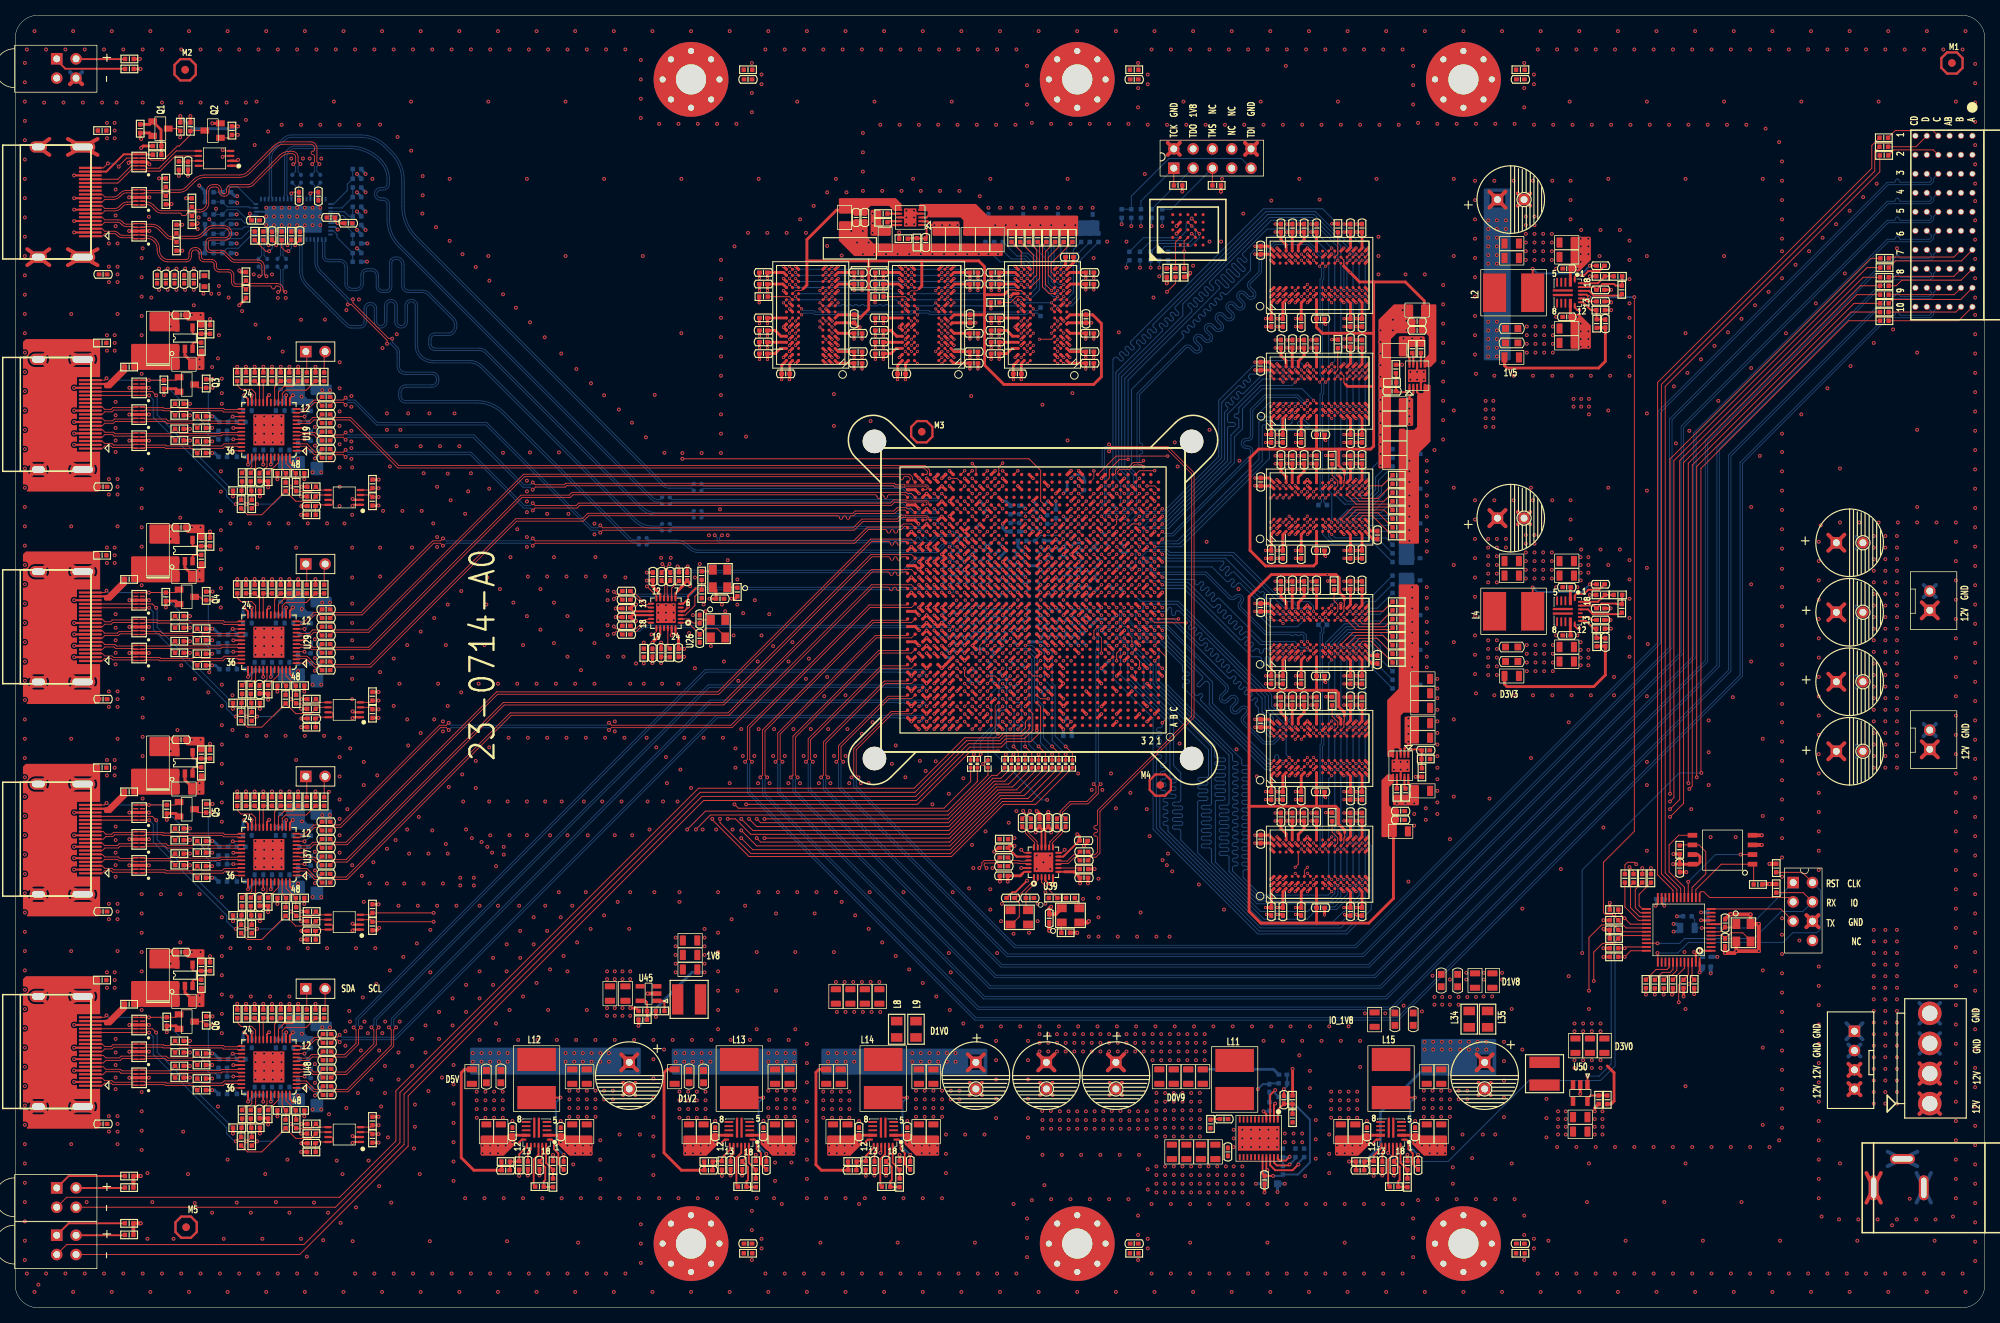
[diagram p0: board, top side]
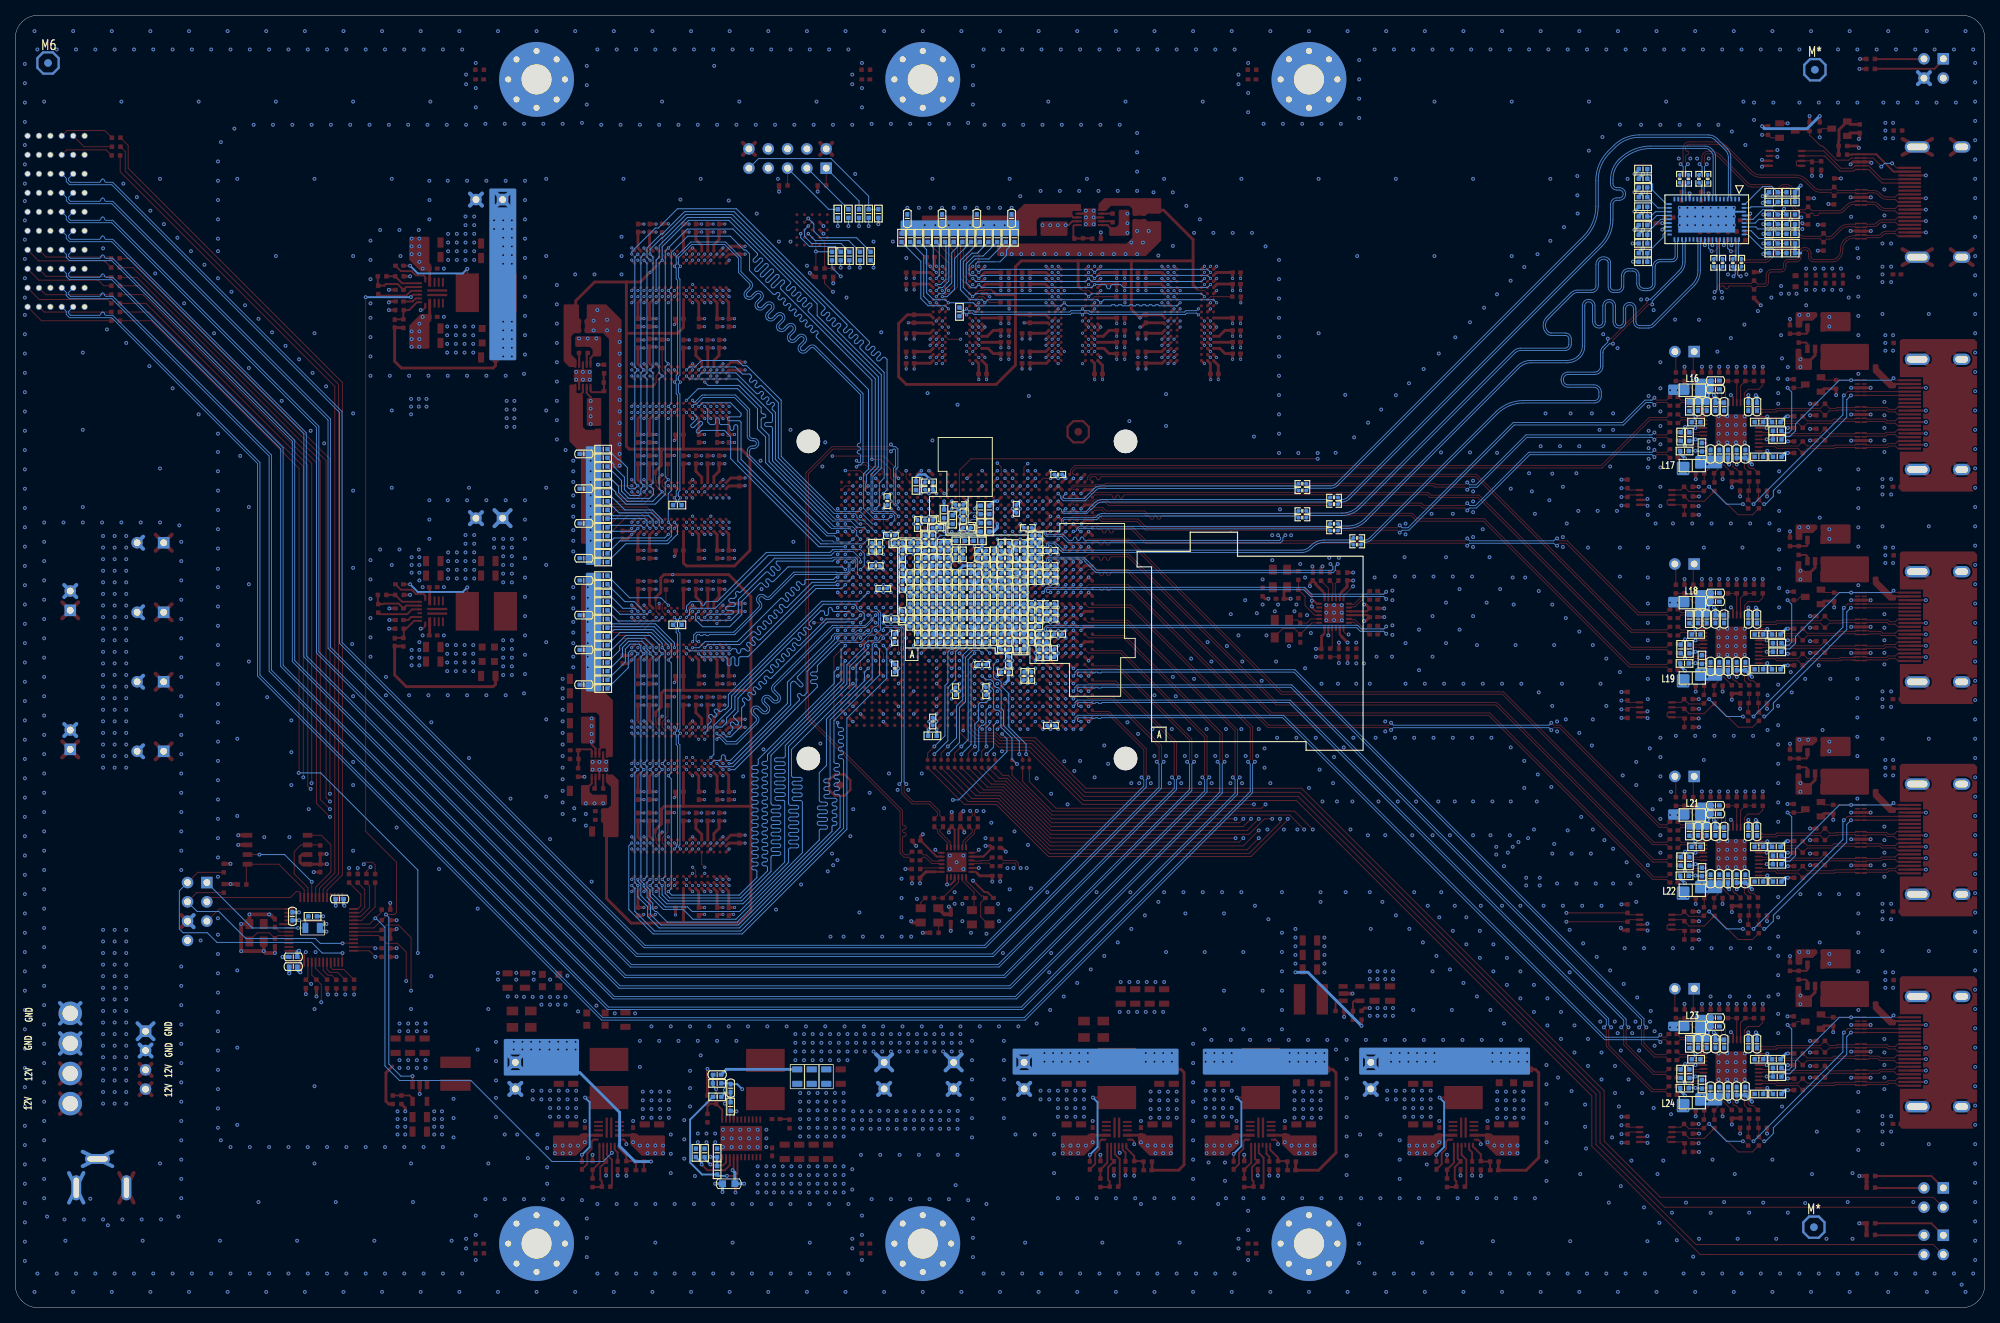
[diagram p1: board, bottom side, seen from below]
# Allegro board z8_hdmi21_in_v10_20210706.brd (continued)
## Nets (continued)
HDMI_RX1N: C400.1 HDMI1.6(DAT1-) R21.2 U7.5(IO4) U7.6(NC4)
HDMI_RX1P: C401.1 HDMI1.4(DAT1+) R24.2 U7.4(IO3) U7.7(NC3)
HDMI_RX2N: C392.1 HDMI1.9(DAT0-) R18.2 U4.2(IO2) U4.9(NC2)
HDMI_RX2P: C393.1 HDMI1.7(DAT0+) R20.2 U4.1(IO1) U4.10(NC1)
HDMI_RX3N: C390.1 HDMI1.12(CLK-) R16.2 U4.5(IO4) U4.6(NC4)
HDMI_RX3P: C391.1 HDMI1.10(CLK+) R17.2 U4.4(IO3) U4.7(NC3)
HDMI_RXC0N: C398.2 U59.39(S_INA1N)
HDMI_RXC0P: C399.2 U59.40(S_INA1P)
HDMI_RXC1N: C400.2 U59.44(S_INA0N)
HDMI_RXC1P: C401.2 U59.45(S_INA0P)
HDMI_RXC2N: C392.2 U59.11(D_IN0N)
HDMI_RXC2P: C393.2 U59.10(D_IN0P)
HDMI_RXC3N: C390.2 U59.16(D_IN1N)
HDMI_RXC3P: C391.2 U59.15(D_IN1P)
HDMI_SCL_1: J6.15(SCL) R93.1 R101.1 R107.1 U15.1(IO1) U15.10(NC1)
HDMI_SCL_2: J8.15(SCL) R161.1 R169.1 R173.1 U24.1(IO1) U24.10(NC1)
HDMI_SCL_3: J10.15(SCL) R230.1 R239.1 R243.1 U35.1(IO1) U35.10(NC1)
HDMI_SCL_4: J14.15(SCL) R288.1 R297.1 R301.1 U46.1(IO1) U46.10(NC1)
HDMI_SCL_21: HDMI1.15(SCL) U2.6(SCL2) U3.1(IO1) U3.10(NC1)
HDMI_SDA_1: J6.16(SDA) R94.1 R102.1 R108.1 U15.2(IO2) U15.9(NC2)
HDMI_SDA_2: J8.16(SDA) R162.1 R170.1 R174.1 U24.2(IO2) U24.9(NC2)
HDMI_SDA_3: J10.16(SDA) R231.1 R240.1 R244.1 U35.2(IO2) U35.9(NC2)
HDMI_SDA_4: J14.16(SDA) R289.1 R298.1 R302.1 U46.2(IO2) U46.9(NC2)
HDMI_SDA_21: HDMI1.16(SDA) U2.5(SDA2) U3.2(IO2) U3.9(NC2)
HM20_RX_RCK+: C428.2 P1.AD28(REFCLK_GXBL1C_CHTP_1C_AD28)
HM20_RX_RCK-: C426.2 P1.AD27(REFCLK_GXBL1C_CHTN_1C_AD27)
HM20_TX+: C160.1 U26.10(CLK3A)
HM20_TX-: C161.1 U26.9(CLK3B)
HM20_TX_RCX+: C160.2 P1.AB28(REFCLK_GXBL1D_CHBP_1D_AB28)
HM20_TX_RCX-: C161.2 P1.AB27(REFCLK_GXBL1D_CHBN_1D_AB27)
HM21_RX0+: C664.1 U59.29(S_OUTB1P)
HM21_RX0-: C663.1 U59.28(S_OUTB1N)
HM21_RX1+: C662.1 U59.35(S_OUTA0P)
HM21_RX1-: C661.1 U59.34(S_OUTA0N)
HM21_RX2+: C666.1 U59.7(D_OUT1P)
HM21_RX2-: C665.1 U59.8(D_OUT1N)
HM21_RX3+: C668.1 U59.3(D_OUT0P)
HM21_RX3-: C667.1 U59.4(D_OUT0N)
HM21_SCL: R187.2 R344.1 R345.1 U59.50(DEM_S1)
HM21_SDA: R186.2 R347.1 R348.1 U59.49(DEM_S0)
HM21RX0+: C664.2 P1.AG30(GXBL1C_RX_CH2P,GXBL1C_REFCLK2P_)
HM21RX0-: C663.2 P1.AG29(GXBL1C_RX_CH2N,GXBL1C_REFCLK2N_)
HM21RX1+: C662.2 P1.AF32(GXBL1C_RX_CH3P,GXBL1C_REFCLK3P_)
HM21RX1-: C661.2 P1.AF31(GXBL1C_RX_CH3N,GXBL1C_REFCLK3N_)
HM21RX2+: C666.2 P1.AJ30(GXBL1C_RX_CH1P,GXBL1C_REFCLK1P_)
HM21RX2-: C665.2 P1.AJ29(GXBL1C_RX_CH1N,GXBL1C_REFCLK1N_)
HM21RX3+: C668.2 P1.AL30(GXBL1C_RX_CH0P,GXBL1C_REFCLK0P_)
HM21RX3-: C667.2 P1.AL29(GXBL1C_RX_CH0N,GXBL1C_REFCLK0N_)
HM_1_TCX+: C115.1 P1.AH32(GXBL1C_TX_CH3P_1C_AH32)
HM_1_TCX-: C113.1 P1.AH31(GXBL1C_TX_CH3N_1C_AH31)
HM_1_TX0+: C120.1 P1.AP32(GXBL1C_TX_CH0P_1C_AP32)
HM_1_TX0-: C117.1 P1.AP31(GXBL1C_TX_CH0N_1C_AP31)
HM_1_TX1+: C130.1 P1.AM32(GXBL1C_TX_CH1P_1C_AM32)
HM_1_TX1-: C122.1 P1.AM31(GXBL1C_TX_CH1N_1C_AM31)
HM_1_TX2+: C133.1 P1.AK32(GXBL1C_TX_CH2P_1C_AK32)
HM_1_TX2-: C132.1 P1.AK31(GXBL1C_TX_CH2N_1C_AK31)
HM_2_TCX+: C181.1 P1.AG34(GXBL1D_TX_CH1P_1D_AG34)
HM_2_TCX-: C178.1 P1.AG33(GXBL1D_TX_CH1N_1D_AG33)
HM_2_TX0+: C187.1 P1.AN34(GXBL1C_TX_CH4P_1C_AN34)
HM_2_TX0-: C185.1 P1.AN33(GXBL1C_TX_CH4N_1C_AN33)
HM_2_TX1+: C194.1 P1.AL34(GXBL1C_TX_CH5P_1C_AL34)
HM_2_TX1-: C191.1 P1.AL33(GXBL1C_TX_CH5N_1C_AL33)
HM_2_TX2+: C202.1 P1.AJ34(GXBL1D_TX_CH0P_1D_AJ34)
HM_2_TX2-: C199.1 P1.AJ33(GXBL1D_TX_CH0N_1D_AJ33)
HM_3_TCX+: C252.1 P1.W34(GXBL1D_TX_CH5P_1D_W34)
HM_3_TCX-: C245.1 P1.W33(GXBL1D_TX_CH5N_1D_W33)
HM_3_TX0+: C257.1 P1.AE34(GXBL1D_TX_CH2P_1D_AE34)
HM_3_TX0-: C254.1 P1.AE33(GXBL1D_TX_CH2N_1D_AE33)
HM_3_TX1+: C263.1 P1.AC34(GXBL1D_TX_CH3P_1D_AC34)
HM_3_TX1-: C260.1 P1.AC33(GXBL1D_TX_CH3N_1D_AC33)
HM_3_TX2+: C269.1 P1.AA34(GXBL1D_TX_CH4P_1D_AA34)
HM_3_TX2-: C266.1 P1.AA33(GXBL1D_TX_CH4N_1D_AA33)
HM_4_TCX+: C296.1 P1.B32(GXBL1F_TX_CH5P_1F_B32)
HM_4_TCX-: C295.1 P1.B31(GXBL1F_TX_CH5N_1F_B31)
HM_4_TX0+: C301.1 P1.H32(GXBL1F_TX_CH2P_1F_H32)
HM_4_TX0-: C300.1 P1.H31(GXBL1F_TX_CH2N_1F_H31)
HM_4_TX1+: C331.1 P1.F32(GXBL1F_TX_CH3P_1F_F32)
HM_4_TX1-: C302.1 P1.F31(GXBL1F_TX_CH3N_1F_F31)
HM_4_TX2+: C333.1 P1.D32(GXBL1F_TX_CH4P_1F_D32)
HM_4_TX2-: C332.1 P1.D31(GXBL1F_TX_CH4N_1F_D31)
HM_SCL_1: J5.2 P1.C19(IO_2L_46_C19/DQ0) R75.2
HM_SCL_2: J7.2 P1.A20(IO_2L_41_A20/DQSN1) R132.2
HM_SCL_3: J9.2 P1.D21(IO_2L_29_D21/PLL_2L_CLKOUT1N/DQ) R209.2
HM_SCL_4: J12.2 P1.J20(IO_2L_12_J20/DQ5) R271.2
HM_SDA_1: J5.1 P1.B20(IO_2L_45_B20/DQSN0) R73.2
HM_SDA_2: J7.1 P1.A19(IO_2L_40_A19/DQS1) R130.2
HM_SDA_3: J9.1 P1.E21(IO_2L_28_E21/PLL_2L_CLKOUT1P,PL) R207.2
HM_SDA_4: J12.1 P1.M20(IO_2L_11_M20/DQ6) R269.2
HM_TX_HPD1: P1.B22(IO_2L_42_B22/DQ0) R386.1 R387.1
HM_TX_HPD2: P1.C22(IO_2L_33_C22/DQSN2) R446.1 R447.1
HM_TX_HPD3: P1.H20(IO_2L_13_H20/DQ5) R467.1 R468.1
HM_TX_HPD4: P1.K19(IO_2L_8_K19/DQS6) R480.1 R481.1
HM_TX_SCL1: R105.2 R183.2 U21.3(SCL1)
HM_TX_SCL2: R172.2 R185.2 U31.3(SCL1)
HM_TX_SCL3: R180.2 R242.2 U42.3(SCL1)
HM_TX_SCL4: R189.2 R300.2 U55.3(SCL1)
HM_TX_SCL21: R190.2 U2.3(SCL1)
HM_TX_SDA1: R96.2 R182.2 U21.4(SDA1)
HM_TX_SDA2: R164.2 R184.2 U31.4(SDA1)
HM_TX_SDA3: R179.2 R233.2 U42.4(SDA1)
HM_TX_SDA4: R188.2 R292.2 U55.4(SDA1)
HM_TX_SDA21: R191.2 U2.4(SDA1)
HPD_IN1: J6.19(HPLG) Q3.1(G) R78.2 R388.2 U15.5(IO4) U15.6(NC4)
HPD_IN2: J8.19(HPLG) Q4.1(G) R138.2 R448.2 U24.5(IO4) U24.6(NC4)
HPD_IN3: J10.19(HPLG) Q5.1(G) R211.2 R469.2 U35.5(IO4) U35.6(NC4)
HPD_IN4: J14.19(HPLG) Q6.1(G) R274.2 R482.2 U46.5(IO4) U46.6(NC4)
HPD_SNK_1: R385.1 R388.1 U19.33(HPD_SNK)
HPD_SNK_2: R444.1 R448.1 U29.33(HPD_SNK)
HPD_SNK_3: R466.1 R469.1 U37.33(HPD_SNK)
HPD_SNK_4: R479.1 R482.1 U48.33(HPD_SNK)
HPD_SRC_1: R387.2 U19.4(HPD_SRC)
HPD_SRC_2: R447.2 U29.4(HPD_SRC)
HPD_SRC_3: R468.2 U37.4(HPD_SRC)
HPD_SRC_4: R481.2 U48.4(HPD_SRC)
I2C_EN/PIN_1: R381.2 R382.1 U19.10(I2C_EN/PIN)
I2C_EN/PIN_2: R436.2 R439.1 U29.10(I2C_EN/PIN)
I2C_EN/PIN_3: R462.2 R463.1 U37.10(I2C_EN/PIN)
I2C_EN/PIN_4: R475.2 R476.1 U48.10(I2C_EN/PIN)
LED1: P1.A18(IO_2L_38_A18/DQ1) U57.4(T-)
LED2: P1.B18(IO_2L_39_B18/DQ1) U57.2(B-)
LED3: P1.D17(IO_2L_37_D17/DQ1) U58.4(T-)
LED4: P1.C18(IO_2L_36_C18/DQ1) U58.2(B-)
LED_HDMI21: P1.F21(IO_2L_17_F21/DQSN5) U1.2(B-)
M_AS_DATA0: R703.1 U6.D3(DQ0)
M_AS_DATA1: R704.1 U6.D2(DQ1)
M_AS_DATA2: R705.1 U6.C4(W#/DQ2)
M_AS_DATA3: R706.1 U6.D4(HOLD#/DQ3)
MODE: R343.1 R346.1 U59.21(MODE)
MSEL0: P1.AG15(MSEL0) R410.1 R412.1
MSEL1: P1.AG13(MSEL1) R413.1
MSEL2: P1.AG12(MSEL2) R414.1
NCE: P1.AF14(NCE) R418.1
NCONFIG: P1.AF13(NCONFIG) R420.1
NCS0: R43.2 R707.2 U6.C2(S#)
NIO_PULLUP: P1.AE14(NIO_PULLUP) R421.1 R422.1
NSTATUS: P1.AM11(NSTATUS) R398.1
PRE_SEL_1: R68.1 R69.2 U19.20(PRE_SEL)
PRE_SEL_2: R125.1 R126.2 U29.20(PRE_SEL)
PRE_SEL_3: R202.1 R203.2 U37.20(PRE_SEL)
PRE_SEL_4: R264.1 R265.2 U48.20(PRE_SEL)
R0PWR5V: HDMI1.18(+5V) R12.1 U3.5(IO4) U3.6(NC4)
RC_F_N: C184.1 U26.17(CLK1B)
RC_F_P: C186.1 U26.18(CLK1A)
REFCLK_F_N: C184.2 P1.P27(REFCLK_GXBL1F_CHBN_1F_P27)
REFCLK_F_P: C186.2 P1.P28(REFCLK_GXBL1F_CHBP_1F_P28)
RX_5V_N: Q1.3(D) R7.2 R192.2
RX_HPD_N: Q2.1(G) R11.2 R181.2
SCL_CTL_1: R74.2 R75.1 U19.15(SCL_CTL)
SCL_CTL_2: R131.2 R132.1 U29.15(SCL_CTL)
SCL_CTL_3: R208.2 R209.1 U37.15(SCL_CTL)
SCL_CTL_4: R270.2 R271.1 U48.15(SCL_CTL)
SCL_SNK_1: R93.2 U19.38(SCL_SNK)
SCL_SNK_2: R161.2 U29.38(SCL_SNK)
SCL_SNK_3: R230.2 U37.38(SCL_SNK)
SCL_SNK_4: R288.2 U48.38(SCL_SNK)
SCL_SRC_1: R90.1 R98.1 U19.46(SCL_SRC)
SCL_SRC_2: R159.1 R165.1 U29.46(SCL_SRC)
SCL_SRC_3: R226.1 R234.1 U37.46(SCL_SRC)
SCL_SRC_4: R286.1 R294.1 U48.46(SCL_SRC)
SDA_CTL_1: R72.2 R73.1 U19.16(SDA_CTL)
SDA_CTL_2: R129.2 R130.1 U29.16(SDA_CTL)
SDA_CTL_3: R206.2 R207.1 U37.16(SDA_CTL)
SDA_CTL_4: R268.2 R269.1 U48.16(SDA_CTL)
SDA_SNK_1: R94.2 U19.39(SDA_SNK)
SDA_SNK_2: R162.2 U29.39(SDA_SNK)
SDA_SNK_3: R231.2 U37.39(SDA_SNK)
SDA_SNK_4: R289.2 U48.39(SDA_SNK)
SDA_SRC_1: R91.1 R99.1 U19.47(SDA_SRC)
SDA_SRC_2: R160.1 R166.1 U29.47(SDA_SRC)
SDA_SRC_3: R227.1 R235.1 U37.47(SDA_SRC)
SDA_SRC_4: R287.1 R295.1 U48.47(SDA_SRC)
SEL0: R352.1 R367.1 U59.23(SEL0)
SEL1: R370.1 R373.1 U59.26(SEL1)
SI_DDR3A_N: C247.1 U39.17(CLK1B)
SI_DDR3A_P: C246.1 U39.18(CLK1A)
SI_DDR3B_N: C262.1 U39.9(CLK3B)
SI_DDR3B_P: C259.1 U39.10(CLK3A)
SI_DDR3C_N: C251.1 U39.13(CLK2B)
SI_DDR3C_P: C250.1 U39.14(CLK2A)
SIG_EN_1: R70.1 R71.2 U19.17(SIG_EN)
SIG_EN_2: R127.1 R128.2 U29.17(SIG_EN)
SIG_EN_3: R204.1 R205.2 U37.17(SIG_EN)
SIG_EN_4: R266.1 R267.2 U48.17(SIG_EN)
SWAP/POL_1: R389.1 R391.2 U19.1(SWAP/POL)
SWAP/POL_2: R450.1 R452.2 U29.1(SWAP/POL)
SWAP/POL_3: R470.1 R471.2 U37.1(SWAP/POL)
SWAP/POL_4: R484.1 R485.2 U48.1(SWAP/POL)
SWCLK: J11.2 R221.2 U43.37(PA14)
SWDIO: J11.4 R225.2 U43.34(PA13)
TCK: P1.AH12(TCK) R699.1
TDI: P1.AH13(TDI) R702.1
TDO: P1.AJ12(TDO) R700.1
TMS: P1.AL10(TMS) R701.1
TRST: P1.AL11(TRST) R400.1
TX_TERM_1: R392.1 R393.2 U19.36(TX_TERM_CTL)
TX_TERM_2: R454.1 R455.2 U29.36(TX_TERM_CTL)
TX_TERM_3: R472.1 R473.2 U37.36(TX_TERM_CTL)
TX_TERM_4: R486.1 R487.2 U48.36(TX_TERM_CTL)
UART_RXD: J11.3 U43.13(PA3)
UART_TXD: J11.5 U43.12(PA2)
VREF_DDR3_A: C9.1 C10.1 C11.1 C64.1 C65.1 C66.1 C445.1 C579.1 P1.AC23(VREFB2JN0_2J_AC23) P1.M22(VREFB2KN0_2K_M22) U5.6(REFOUT) U10.H1(VREFDQ) U10.M8(VREFCA) U11.H1(VREFDQ) U11.M8(VREFCA) U12.H1(VREFDQ) U12.M8(VREFCA)
VREF_DDR3_B: C58.1 C67.1 C68.1 C80.1 C124.1 C149.1 C448.1 C464.1 P1.AC12(VREFB3BN0_3B_AC12) P1.AD12(VREFB3AN0_3A_AD12) U8.H1(VREFDQ) U8.M8(VREFCA) U14.6(REFOUT) U16.H1(VREFDQ) U16.M8(VREFCA) U22.H1(VREFDQ) U22.M8(VREFCA)
VREF_DDR3_C: C203.1 C231.1 C237.1 C244.1 C253.1 C273.1 C472.1 C492.1 P1.AA10(VREFB3CN0_3C_AA10) P1.V10(VREFB3DN0_3D_V10) U28.H1(VREFDQ) U28.M8(VREFCA) U32.H1(VREFDQ) U32.M8(VREFCA) U34.6(REFOUT) U40.H1(VREFDQ) U40.M8(VREFCA)
VTT_DDR3_A: C25.1 C26.1 C27.1 C394.1 C395.1 C396.1 C397.1 R30.1 R31.1 R32.1 R33.1 R34.1 R35.1 R36.1 R37.1 R353.1 R354.1 R355.1 R356.1 R357.1 R358.1 R359.1 R360.1 R361.1 R362.1 R363.1 R364.1 R365.1 R366.1 U5.3(VO) U5.5(VOSNS)
VTT_DDR3_B: C123.1 C131.1 C140.1 C410.1 C417.1 C427.1 C459.1 R92.1 R97.1 R103.1 R106.1 R109.1 R111.1 R112.1 R113.1 R390.1 R394.1 R395.1 R397.1 R399.1 R402.1 R404.1 R407.1 R411.1 R415.1 R419.1 R423.1 R424.1 R426.1 U14.3(VO) U14.5(VOSNS)
VTT_DDR3_C: C205.1 C213.1 C221.1 C487.1 C531.1 C580.1 C593.1 R139.1 R141.1 R143.1 R145.1 R148.1 R152.1 R156.1 R157.1 R428.1 R430.1 R431.1 R432.1 R433.1 R435.1 R438.1 R442.1 R445.1 R449.1 R451.1 R456.1 R458.1 R459.1 U34.3(VO) U34.5(VOSNS)
XTL25N: C281.2 U43.6(PF1/OSC_OUT) Y5.1(XTALI)
XTL25N1: C271.2 U39.2(CLKIN_N) Y4.1(XTALI)
XTL25N2: C182.2 U26.2(CLKIN_N) Y2.1(XTALI)
XTL25P: C284.2 U43.5(PF0/OSC_IN) Y5.3(XTALO)
XTL25P1: C270.2 U39.1(CLKIN_P) Y4.3(XTALO)
XTL25P2: C189.2 U26.1(CLKIN_P) Y2.3(XTALO)
N22024981: R22.1 U5.9(PGOOD)
N22025053: C111.2 R64.2 R76.1 U14.1(REFIN)
N22025271: R61.1 U14.9(PGOOD)
N22025327: C228.2 R178.1 R195.2 U34.1(REFIN)
N22025525: R198.1 U34.9(PGOOD)
N22025799: R19.1 U5.7(EN)
N22025867: R62.1 U14.7(EN)
N22025914: R197.1 U34.7(EN)
N22026405: R259.1 R272.1 U45.5(FB)
N22026409: L7.1 U45.3(SW)
N22026570: C28.2 R38.2 R40.1 U5.1(REFIN)
N22030137: C1.1 C2.1 C3.1 J1.1 J1.2 J1.3 J1.4 J1.5 J1.6 J1.7 J1.8 J1.9 J2.1 J2.2 J2.3 J2.4 J2.5 J2.6 J2.7 J2.8 J2.9 J3.1 J3.2 J3.3 J3.4 J3.5 J3.6 J3.7 J3.8 J3.9 R3.2 R4.2 R5.2
N22030618: C384.2 R306.1 R312.2 U53.13(FB)
N22030676: R323.2 U53.16(PGOOD)
N22030684: R313.2 R319.1 U53.18(MODE)
N22030720: C378.1 U53.1(BOOT)
N22030722: C378.2 L14.1 U53.6(SW1) U53.7(SW2)
N22030830: C376.1 U53.14(SS)
N22030983: R492.1 R493.1 U56.22(RF)
N22031161: C334.2 C622.2 R483.1
N22031163: C336.2 C626.2 L11.2 R483.2 U56.6(LL#6) U56.7(LL#7) U56.8(LL#8) U56.9(LL#9) U56.10(LL#10) U56.11(LL#11)
N22031238: R325.2 U57.3(T+)
N22031240: R316.2 U57.1(B+)
N22031335: R488.2 U56.3(PGOOD)
N22031337: R489.2 U56.4(VBST)
N22031349: C336.1 R293.2
N22031384: R491.1 U56.21(TRIP)
N22031400: R490.1 U56.20(MODE)
N22031488: C626.1 R489.1
N22031700: C387.1 C388.1 C389.1 J16.1 J16.2 J16.3 J16.4 J16.5 J16.6 J16.7 J16.8 J16.9 J17.1 J17.2 J17.3 J17.4 J17.5 J17.6 J17.7 J17.8 J17.9 J18.1 J18.2 J18.3 J18.4 J18.5 J18.6 J18.7 J18.8 J18.9 R328.2 R329.2 R330.2
N22047900: P1.M27(REFCLK_GXBL1F_CHTN_1F_M27) P1.M28(REFCLK_GXBL1F_CHTP_1F_M28) R443.2
N22048190: P1.AP29(RREF_BL_AP29) R396.2
N22048192: P1.A29(RREF_TL_A29) R461.2
N22048413: L20.1 P1.A14(ADCGND_A14)
N22049180: R228.2 R229.2 U39.3(CLKIN)
N22049282: R222.1 U39.8(INTR)
N22049606: R246.2 Y3.1(EN)
N22053758: R50.2 U12.L8(ZQ)
N22054851: P1.F25(IO_2K_26_F25/RZQ_2K/LVDS2K_11P/) R457.1
N22055520: R48.2 U10.L8(ZQ)
N22056050: R49.2 U11.L8(ZQ)
N22061318: R23.2 U8.L8(ZQ)
N22061537: P1.AJ7(IO_3A_26_AJ7/RZQ_3A/LVDS3A_11P/) R403.1
N22061744: R59.2 U16.L8(ZQ)
N22062524: R89.2 U22.L8(ZQ)
N22067825: P1.K7(IO_3D_26_K7/RZQ_3D/LVDS3D_11P/D) R453.1
N22068466: R212.2 U40.L8(ZQ)
N22069069: R121.2 U28.L8(ZQ)
N22069811: R168.2 U32.L8(ZQ)
N22071827: J4.9(5) R406.2 R702.2
N22071832: J4.5(3) R15.2 R701.2
N22072215: J4.1 R14.2 R699.2
N22072232: J4.3(2) R700.2
N22082350: P1.Y18(GNDSENSE_Y18) R429.2
N22082686: P1.Y17(VCCLSENSE_Y17) R425.2
N22086073: JT1.A10(D-C10) R54.2
N22086076: JT1.B9(D-D9) R47.2
N22086079: JT1.A9(D-C9) R51.2
N22086210: JT1.B10(D-D10) R53.2
N22090777: R327.2 U58.3(T+)
N22090779: R326.2 U58.1(B+)
N22318019: C130.2 U19.5(IN_D1P)
N22318021: C122.2 U19.6(IN_D1N)
N22318023: C133.2 U19.2(IN_D2P)
N22318025: C132.2 U19.3(IN_D2N)
N22318199: C143.1 J6.MTG1 J6.MTG2 J6.MTG3 J6.MTG4 R58.2
N22318292: C144.2 R110.1 U21.7(VREF2) U21.8(EN)
N22318294: C120.2 U19.8(IN_D0P)
N22318980: C117.2 U19.9(IN_D0N)
N22318988: C115.2 U19.11(IN_CLKP)
N22318990: C113.2 U19.12(IN_CLKN)
N22319096: R65.2 U19.22(VSADJ)
N22319158: R95.1 U19.45(SPDIF_IN)
N22319174: C141.1 U19.42(OE)
N22319555: J6.18(+5V) R63.1
N22319599: R60.2 U13.3(OCB)
N22319611: R56.1 R57.1 U13.4(EN)
N22336290: C194.2 U29.5(IN_D1P)
N22336292: C191.2 U29.6(IN_D1N)
N22336294: C202.2 U29.2(IN_D2P)
N22336296: C199.2 U29.3(IN_D2N)
N22336470: C214.1 J8.MTG1 J8.MTG2 J8.MTG3 J8.MTG4 R116.2
N22336560: C222.2 R175.1 U31.7(VREF2) U31.8(EN)
N22336562: C187.2 U29.8(IN_D0P)
N22337251: C185.2 U29.9(IN_D0N)
N22337253: C181.2 U29.11(IN_CLKP)
N22337255: C178.2 U29.12(IN_CLKN)
N22337367: R122.2 U29.22(VSADJ)
N22337429: R163.1 U29.45(SPDIF_IN)
N22337445: C212.1 U29.42(OE)
N22337826: J8.18(+5V) R120.1
N22337863: R117.2 U23.3(OCB)
N22337874: R114.1 R115.1 U23.4(EN)
N22341695: C263.2 U37.5(IN_D1P)
N22341697: C260.2 U37.6(IN_D1N)
N22341699: C269.2 U37.2(IN_D2P)
N22341701: C266.2 U37.3(IN_D2N)
N22341875: C274.1 J10.MTG1 J10.MTG2 J10.MTG3 J10.MTG4 R193.2
N22341965: C282.2 R248.1 U42.7(VREF2) U42.8(EN)
N22341967: C257.2 U37.8(IN_D0P)
N22342656: C254.2 U37.9(IN_D0N)
N22342658: C252.2 U37.11(IN_CLKP)
N22342660: C245.2 U37.12(IN_CLKN)
N22342772: R199.2 U37.22(VSADJ)
N22342834: R232.1 U37.45(SPDIF_IN)
N22342850: C272.1 U37.42(OE)
N22343231: J10.18(+5V) R196.1
N22343268: R194.2 U33.3(OCB)
N22343279: R176.1 R177.1 U33.4(EN)
N22346984: C331.2 U48.5(IN_D1P)
N22347001: C302.2 U48.6(IN_D1N)
N22347003: C333.2 U48.2(IN_D2P)
N22347005: C332.2 U48.3(IN_D2N)
N22347179: C338.1 J14.MTG1 J14.MTG2 J14.MTG3 J14.MTG4 R253.2
N22347257: C364.2 R303.1 U55.7(VREF2) U55.8(EN)
N22347259: C301.2 U48.8(IN_D0P)
N22347960: C300.2 U48.9(IN_D0N)
N22347962: C296.2 U48.11(IN_CLKP)
N22347964: C295.2 U48.12(IN_CLKN)
N22348076: R261.2 U48.22(VSADJ)
N22348138: R290.1 U48.45(SPDIF_IN)
N22348154: C335.1 U48.42(OE)
N22348531: J14.18(+5V) R258.1
N22348572: R257.2 U44.3(OCB)
N22348576: R251.1 R252.1 U44.4(EN)
N22353387: R118.2 R134.2 U26.3(CLKIN)
N22353420: R119.1 U26.8(INTR)
N22353722: R133.2 Y1.1(EN)
N22359824: P1.T27(REFCLK_GXBL1E_CHTN_1E_T27) P1.T28(REFCLK_GXBL1E_CHTP_1E_T28) R434.2
N22360101: P1.Y27(REFCLK_GXBL1D_CHTN_1D_Y27) P1.Y28(REFCLK_GXBL1D_CHTP_1D_Y28) R427.2
N22376675: C43.1 HDMI1.MTG1 HDMI1.MTG2 HDMI1.MTG3 HDMI1.MTG4 R10.2
N22380384: C4.2 R13.1 U2.7(VREF2) U2.8(EN)
N22381237: R349.1 U59.22(INPUT_EN)
N22381770: R27.2 U59.43(S_INB0P)
N22381784: R26.2 U59.42(S_INB0N)
N22381826: R29.2 U59.38(S_INB1P)
N22381836: R28.2 U59.37(S_INB1N)
N22382472: C20.1 U59.41(VDD#41)
N22382559: C21.1 U59.36(VDD#36)
N22383207: C5.1 U59.9(VDD#9)
N22383495: C6.1 U59.14(VDD#14)
N22383981: C12.1 U59.51(VDD#51)
N22398516: Q1.1(G) R6.2 R9.1 R12.2
N22432680: P1.A13(VREFP_ADC_A13) P1.B13(VREFN_ADC_B13) R460.1
N22449821: R315.2 R320.1 U54.18(MODE)
N22449835: C381.1 U54.1(BOOT)
N22449837: C381.2 L15.1 U54.6(SW1) U54.7(SW2)
N22449845: C385.2 R307.1 R314.2 U54.13(FB)
N22449937: C379.1 U54.14(SS)
N22450190: R324.2 U54.16(PGOOD)
N22451830: R135.2 R136.1 U25.18(MODE)
N22451844: C164.1 U25.1(BOOT)
N22451846: C164.2 L4.1 U25.6(SW1) U25.7(SW2)
N22451862: C190.2 R147.2 R151.1 U25.13(FB)
N22451950: C183.1 U25.14(SS)
N22452196: R140.2 U25.16(PGOOD)
N22462383: R260.2 U45.1(EN/PG)
N22647853: R309.2 R317.1 U51.18(MODE)
N22647875: C372.1 U51.1(BOOT)
N22647877: C372.2 L12.1 U51.6(SW1) U51.7(SW2)
N22647893: C382.2 R304.1 R308.2 U51.13(FB)
N22647973: C370.1 U51.14(SS)
N22648227: R321.2 U51.16(PGOOD)
N22660428: R254.1 U43.44(BOOT0)
N22766072: R311.2 R318.1 U52.18(MODE)
N22766094: C375.1 U52.1(BOOT)
N22766096: C375.2 L13.1 U52.6(SW1) U52.7(SW2)
N22766112: C383.2 R305.1 R310.2 U52.13(FB)
N22766192: C373.1 U52.14(SS)
N22766425: R322.2 U52.16(PGOOD)
N22768217: R44.2 R45.1 U9.18(MODE)
N22768239: C35.1 U9.1(BOOT)
N22768241: C35.2 L2.1 U9.6(SW1) U9.7(SW2)
N22768257: C74.2 R52.2 R55.1 U9.13(FB)
N22768337: C57.1 U9.14(SS)
N22768591: R46.2 U9.16(PGOOD)
N22769636: R284.1 R285.1 U50.5(FB)
N22769670: L10.1 U50.3(SW)
N22862307: JT1.D1(D-D1) R709.2
N22862309: JT1.C1(D-C1) R708.2
N22862311: JT1.C2(D-C2) R710.2
N22881224: JT1.A8(D-C8) R713.2
N22881226: JT1.B7(D-D7) R712.2
N22881228: JT1.A7(D-C7) R711.2
N22881230: JT1.B8(D-D8) R714.2
N22958186: R1.2 U1.3(T+)
N22958370: R2.2 U1.1(B+)

Pads without a net: HDMI1 13 14; J4 6 7 8; J6 13 14; J8 13 14; J10 13 14; J11 7; J14 13 14; JT1 A4 A5 A6 B4 B5 B6 D2; M1 1; M2 1; M3 1; M4 1; M5 1; M6 1; M* 1; M*#2 1; P1 A2 A3 A4 A5 A6 A8 A9 A10 A11 A15 A16 A23 AA5 AB1 AC4 AC13 AC14 AC15 AC20 AC22 AC24 AD10 AD17 AD19 AD20 AD22 AE12 AE16 AE17 AE18 AE19 AE20 AE21 AE22 AF16 AF19 AF20 AF21 AF22 AG16 AG18 AG20 AG21 AG22 AH3 AH5 AH14 AH15 AH18 AH19 AH20 AH22 AJ5 AJ14 AJ15 AJ17 AJ19 AJ20 AJ21 AJ22 AK7 AK13 AK14 AK17 AK18 AK19 AK20 AK21 AL1 AL8 AL13 AL14 AL15 AL16 AL18 AL19 AL20 AL21 AL27 AM8 AM10 AM13 AM15 AM16 AM17 AM18 AM20 AM21 AN1 AN2 AN3 AN5 AN9 AN12 AN13 AN14 AN15 AN17 AN18 AN19 AN20 AN28 AN29 AP2 AP3 AP5 AP10 AP12 AP14 AP15 AP16 AP17 AP19 B1 B3 B5 B6 B7 B8 B10 B11 B12 B15 B16 B17 C2 C3 C4 C5 C7 C8 C9 C10 C12 C13 C15 C17 D1 D2 D4 D5 D6 D7 D9 D10 D11 D12 D15 D16 D27 E1 E2 E3 E4 E6 E7 E8 E9 E11 E12 E13 E16 E22 E27 F1 F3 F4 F5 F6 F8 F9 F10 F11 F12 F13 F15 F16 G1 G2 G3 G5 G6 G7 G8 G10 G11 G12 G13 G15 G16 H2 H3 H4 H5 H7 H8 H9 H10 H11 H12 H13 H15 J2 J6 J7 J9 J10 J11 J12 J13 J19 J21 J24 J25 J26 K2 K3 K8 K9 K10 K11 K12 K13 K14 K22 K23 L9 L10 L11 L13 L14 M2 M3 M8 M9 M10 M11 M12 M13 N8 N10 N11 P10 R8 T14 T15 V5 W1 W10; U6 A2 A3 A4 A5 B1 B5 C1 C3 C5 D1 D5 E1 E2 E3 E4 E5; U8 B7 C7 D3 J1 J9 L1 L9 M7; U10 B7 C7 D3 J1 J9 L1 L9 M7; U11 J1 J9 L1 L9 M7; U12 J1 J9 L1 L9 M7; U15 4 7; U16 J1 J9 L1 L9 M7; U19 18 40 44; U22 J1 J9 L1 L9 M7; U24 4 7; U25 15; U26 5 21; U28 J1 J9 L1 L9 M7; U29 18 40 44; U32 J1 J9 L1 L9 M7; U35 4 7; U37 18 40 44; U39 5; U40 B7 C7 D3 J1 J9 L1 L9 M7; U43 2 3 4 10 11 21 22 33 38 39 43; U46 4 7; U48 18 40 44; U51 15; U52 15; U56 5; U59 1 2 5 6 12 13 17 18 27 32 33

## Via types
v1: diameter 0.508, hole 0.254, TOP to BOTTOM, 3709 vias
v2: diameter 0.457, hole 0.203, TOP to BOTTOM, 828 vias
v3: diameter 0.406, hole 0.203, TOP to BOTTOM, 891 vias

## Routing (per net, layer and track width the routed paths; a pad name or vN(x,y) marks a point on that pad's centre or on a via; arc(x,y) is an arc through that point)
D0V9_EN: length 65.2
  TOP w0.127: U43.31 211.12,49.47 R245.2 210.24,50.36 208.66,50.36 207.01,48.7 v1(207.01,41.72)
  TOP w0.254: v1(165.74,26.86) 165.58,26.7 U56.2
  06_SIG2 w0.127: v1(207.01,41.72) 202.69,37.4 177.42,37.4 166.88,26.86 v1(165.74,26.86)
D0V9_VFB: length 4.9
  TOP w0.254: R291.2 R283.1 167.98,26.84 C334.1 166.08,26.04 U56.1
D0V9_VREG: length 19.1
  TOP w0.254: U56.18 164.08,17.61 C386.1 v1(165.46,17.35)
  BOTTOM w0.254: v1(165.46,17.35) 166.57,17.35 R493.2 168.73,17.54 170.31,19.11 170.31,24.76 R488.1
D1V0_EN: length 118.4
  TOP w0.127: v1(207.65,42.99) 207.65,46.8 208.79,47.94 210.24,47.94 R247.2 211.27,48.97 U43.32
  TOP w0.254: U53.15 113.92,20.51 v1(113.79,20.38)
  06_SIG2 w0.127: v1(207.65,42.99) 207.52,42.99 202.56,38.04 134.62,38.04 130.43,33.85 130.43,29.65 124.33,23.56 116.97,23.56 v1(113.79,20.38)
D1V0_VREG: length 7.3
  TOP w0.254: U53.17 114.92,19.63 C377.1 115.32,18.5 115.32,16.83 115.12,16.63 R323.1 115.17,15.88 R319.2
D1V2: length 19.5
  TOP w0.381: R305.2 90.66,19.2 C383.1 87.63,18.1 85.34,20.38 85.34,30.92 85.79,31.37 C317.1
  vias: v1(39.12,109.92) v1(39.12,81.98) v1(39.12,54.04) v1(39.12,26.1) v1(40.26,109.92) v1(40.26,81.98) v1(40.26,54.04) v1(40.26,26.1) v1(86.87,33.52) v1(86.87,32.37) v1(88.01,33.52) v1(88.01,32.37) v1(89.15,33.52) v1(89.15,32.37) v1(90.3,33.52) v1(90.3,32.37) v1(91.44,33.52) v1(91.44,32.37) v1(99.06,33.52) v1(99.06,32.37) v1(100.2,33.52) v1(100.2,32.37) v1(101.35,33.52) v1(101.35,32.37) v1(102.49,33.52) v1(102.49,32.37)
D1V2_OUT1: length 14
  TOP w0.229: v1(36.5,110.94) 36.12,111.33 U19.48 ; v1(30.12,120.06) 30.62,119.55 U19.24 ; v1(35.65,120.06) 35.62,120.03 U19.14 ; U19.23 31.12,120.03 v1(31.1,120.06) ; U19.37 v1(30.62,110.94)
  BOTTOM w0.381: C414.2 C415.2 30.63,110.94 v1(30.62,110.94) ; v1(36.5,110.94) 36.5,111.37 C411.2 C412.2 ; v1(30.12,120.06) 29.97,119.91 C409.2 ; v1(35.65,120.06) 35.43,119.84 C406.2 C407.2 ; v1(31.1,120.06) 31.12,120.04 C408.2
  vias: v1(37.21,111.7)
D1V2_OUT2: length 14
  TOP w0.229: U29.37 v1(30.62,83) ; v1(35.65,92.12) 35.62,92.09 U29.14 ; U29.24 30.62,91.61 v1(30.12,92.12) ; v1(31.1,92.12) 31.12,92.09 U29.23 ; v1(36.5,83) 36.12,83.39 U29.48
  BOTTOM w0.381: C541.2 29.97,91.97 v1(30.12,92.12) ; C587.2 C586.2 36.5,83.43 v1(36.5,83) ; v1(30.62,83) 30.63,83 C590.2 C589.2 ; v1(35.65,92.12) 35.43,91.9 C538.2 C539.2 ; C540.2 31.12,92.1 v1(31.1,92.12)
  vias: v1(37.21,83.76)
D1V2_OUT3: length 14
  TOP w0.229: U37.48 36.12,55.45 v1(36.5,55.06) ; v1(31.1,64.18) 31.12,64.15 U37.23 ; v1(35.65,64.18) 35.62,64.15 U37.14 ; U37.37 v1(30.62,55.06) ; v1(30.12,64.18) 30.62,63.67 U37.24
  BOTTOM w0.381: v1(30.12,64.18) 29.97,64.03 C603.2 ; C601.2 C600.2 35.43,63.96 v1(35.65,64.18) ; v1(30.62,55.06) 30.63,55.06 C608.2 C607.2 ; C605.2 C604.2 36.5,55.49 v1(36.5,55.06) ; v1(31.1,64.18) 31.12,64.16 C602.2
  vias: v1(37.21,55.82)
D1V2_OUT4: length 14
  TOP w0.229: U48.37 v1(30.62,27.12) ; v1(31.1,36.24) 31.12,36.21 U48.23 ; v1(30.12,36.24) 30.62,35.73 U48.24 ; v1(35.65,36.24) 35.62,36.21 U48.14 ; v1(36.5,27.12) 36.12,27.51 U48.48
  BOTTOM w0.381: v1(30.12,36.24) 29.97,36.09 C621.2 ; v1(31.1,36.24) 31.12,36.22 C620.2 ; v1(30.62,27.12) 30.63,27.12 C631.2 C630.2 ; C619.2 C618.2 35.43,36.02 v1(35.65,36.24) ; v1(36.5,27.12) 36.5,27.55 C627.2 C628.2
  vias: v1(37.21,27.88)
D1V2_VREG: length 7.3
  TOP w0.254: U52.17 96,19.63 C374.1 96.39,18.5 96.39,16.83 96.19,16.63 R322.1 96.25,15.88 R318.2
D1V5_VREG: length 7.3
  TOP w0.254: U9.17 207.64,134.29 C56.1 208.77,134.68 210.31,134.68 210.51,134.48 R46.1 211.38,134.54 R45.2
D1V8: length 12.4
  TOP w0.381: R272.2 v1(81.99,37.09)
  BOTTOM w0.381: v1(81.99,37.09) 89.03,44.13 v1(90.68,44.13)
  vias: v1(81.66,84.77) v1(82.68,84.77) v1(90.68,49.85) v1(90.68,48.7) v1(90.68,47.56) v1(90.68,46.42) v1(90.68,45.28)
D1V8_EN: length 61.3
  TOP w0.127: R238.2 210.87,52.08 v1(211.71,51.24) 212.48,50.47 U43.29
  TOP w0.254: v1(180.59,20.38) 180.73,20.51 180.73,21.4
  BOTTOM w0.127: v1(211.71,51.24) 211.63,51.24 210.44,50.05 210.44,31.81 208.53,29.91 199.14,29.91 188.47,19.24 181.74,19.24 v1(180.59,20.38)
D1V8_VREG: length 7.3
  TOP w0.254: R320.2 181.97,15.88 R324.1 181.92,16.63 182.12,16.83 182.12,18.5 C380.1 181.73,19.63 U54.17
D3V3: length 90
  TOP w0.254: U43.48 v1(221.57,44.13) ; 138.05,57.36 U39.7 ; v1(215.77,52.9) 216.07,53.19 U43.24 ; 87.06,88.52 86.85,88.73 U26.24 ; U43.1 v1(221.74,46.97) ; U39.24 132.74,57.36 132.52,57.15 ; U26.7 86.85,94.02 87.12,94.3 ; v1(221.74,50.99) 221.76,50.97 U43.9
  TOP w0.279: C22.1 115.4,142.45 U5.10 ; U14.10 183.4,124.95 C95.1 ; C230.1 183.25,68.98 U34.10
  TOP w0.381: C265.1 R216.2 v1(218.11,59.7) ; C265.1 v1(218.08,58.37) ; C265.1 218.97,58.36 U38.8 221.35,58.36 221.62,58.63 221.62,59.36 221.35,59.63 U38.7 ; v1(87.99,86.69) C197.1 87.25,88.33 87.06,88.52 ; v1(94.23,93.28) 94.67,93.28 R133.1 ; v1(88.77,94.93) 88.77,95.3 C162.1 88.01,95.3 88.01,95.19 87.12,94.3 ; v1(91.31,93.28) C173.1 92.18,94.38 Y1.4 ; C204.1 195.9,82.04 196.22,81.72 207.64,81.72 209.17,83.25 C190.1 208.06,87.04 R151.2 ; v1(130.56,56.07) 130.56,56.82 C267.1 132.21,56.83 132.52,57.15 ; R255.2 v1(219.46,40.96) ; R249.2 v1(208.91,47.31) ; 138.05,57.36 139.28,57.36 C268.1 v1(140.06,55.83) ; R250.2 v1(208.91,46.16) ; R256.2 v1(220.85,41.26)
  TOP w0.508: 193.91,104.95 C145.1 ; C145.1 193.91,102.82 ; C145.1 196.04,102.82 ; C145.1 196.04,104.95 ; R225.1 v1(230.76,55.74) 229.85,55.74 R224.2 ; v1(136.27,52.77) 136.02,52.51 C280.1 136.86,51.77 Y3.4 ; R246.1 v1(139.7,49.34) ; U38.3 v1(229.74,60.9)
  03_SIG1 w0.508: 194.17,104.69 C145.1 ; C145.1 195.78,103.08 ; C145.1 194.17,103.08 ; C145.1 195.78,104.69
  BOTTOM w0.381: R474.1 v1(218.57,51.5) ; v1(221.74,50.99) 221.76,50.97 C610.1 ; v1(215.77,52.9) 215.88,53.01 C609.1
  BOTTOM w0.508: v1(221.74,46.97) 221.98,46.73 C612.1 ; C145.1 196.04,104.95 ; C145.1 196.04,102.82 ; C145.1 193.91,102.82 ; C145.1 193.91,104.95 ; v1(221.57,44.13) 221.98,44.54 C613.1
  vias: v1(24.77,133.41) v1(25.78,133.41) v1(26.8,134.43) v1(26.8,133.41) v1(40.39,120.71) v1(40.39,92.77) v1(40.39,64.83) v1(40.39,36.89) v1(41.4,120.71) v1(41.4,92.77) v1(41.4,64.83) v1(41.4,36.89) v1(112.78,143.95) v1(112.78,142.68) v1(112.78,141.41) v1(181.74,66.36) v1(182.63,127.52) v1(182.88,66.36) v1(183.77,127.52) v1(184.02,66.36) v1(184.91,127.52) v1(193.75,101.16) v1(193.75,100.01) v1(193.75,98.87) v1(193.75,97.73) v1(193.75,96.58) v1(193.75,95.44) v1(193.75,87.82) v1(193.75,86.68) v1(193.75,85.53) v1(193.75,84.39) v1(193.75,83.25) v1(194.89,101.16) v1(194.89,100.01) v1(194.89,98.87) v1(194.89,97.73) v1(194.89,96.58) v1(194.89,95.44) v1(194.89,87.82) v1(194.89,86.68) v1(194.89,85.53) v1(194.89,84.39) v1(194.89,83.25) v1(196.09,101.16) v1(196.09,100.01) v1(202.95,25.84) v1(202.95,24.83) v1(202.95,23.81) v1(202.95,22.8) v1(203.96,25.84) v1(203.96,24.83) v1(203.96,23.81) v1(203.96,22.8)
D3V3_HM21: length 20.6
  TOP w0.381: C13.2 42.43,142.68 v1(42.42,142.69) 42.05,143.06 C8.2 ; v1(29.46,131.89) 30.35,132.78 R39.1 ; R20.1 23.85,142.53 v1(24,142.68) ; v1(20.57,145.22) 20.52,145.17 R17.1 ; R16.1 v1(18.92,148.58) ; R24.1 v1(21.97,139.07) ; R21.1 v1(21.97,142.48) ; v1(29.46,136.46) 29.66,136.26 R25.1 ; R18.1 v1(22.48,145.96)
  BOTTOM w0.254: U59.24 42.41,142.7 v1(42.42,142.69)
  BOTTOM w0.381: v1(29.21,145.35) 29.08,145.49 R341.2 ; v1(46.28,137.63) 46.26,137.61 R373.2 ; R343.2 45.52,144.78 v1(46.08,144.22) ; R350.2 v1(29.13,141.3) ; R349.2 45.52,142.37 v1(46.08,141.8) ; R344.2 v1(29.13,143.84) ; R371.2 29.01,138.76 v1(29.13,138.63) ; R337.2 45.52,147.32 v1(46.08,146.76) ; v1(46.08,149.17) 45.52,149.73 R335.2 ; R338.2 28.89,146.24 v1(29.21,146.24) ; R368.2 v1(29.13,140.03) ; R367.2 v1(46.33,140.03) ; R347.2 v1(29.13,142.57)
  vias: v1(18.92,136.72) v1(20.07,136.72) v1(21.21,136.72) v1(22.35,136.72) v1(23.49,136.72)
D3V3_OUT1: length 18.8
  TOP w0.229: U19.13 36.12,119.65 v1(36.53,120.06) ; U19.43 v1(33.62,110.94)
  TOP w0.381: R82.1 v1(22.99,117.41) ; R71.1 v1(36.07,123.81) ; R69.1 v1(33.78,123.81) ; R86.1 v1(22.99,114.11) ; R85.1 v1(22.99,115.63) ; R83.1 v1(25.91,117.28) ; R87.1 v1(25.91,113.98) ; R72.1 v1(37.21,123.81) ; R80.1 v1(22.99,118.94) ; R88.1 v1(25.91,112.46) ; R74.1 v1(39.5,123.81) ; R57.2 v1(25.63,130.08) ; R84.1 v1(25.91,115.76) ; R66.1 v1(30.35,123.81)
  BOTTOM w0.381: v1(39.43,111.75) 40.06,112.37 R391.1 ; v1(25.91,117.28) 26.11,117.28 R384.1 ; C413.2 33.78,111.1 v1(33.62,110.94) ; v1(36.53,120.06) 36.58,120.01 C405.2 ; v1(25.91,112.46) 26.23,112.46 R393.1
  vias: v1(37.67,119.88)
D3V3_OUT2: length 19
  TOP w0.229: U29.13 36.12,91.71 v1(36.53,92.12) ; U29.43 v1(33.62,83)
  TOP w0.381: R144.1 v1(22.99,89.47) ; R128.1 v1(36.07,95.87) ; R129.1 v1(37.21,95.87) ; R146.1 v1(25.91,89.34) ; R149.1 v1(25.91,87.82) ; R158.1 v1(25.91,84.52) ; R123.1 v1(30.35,95.87) ; R150.1 v1(22.99,87.69) ; R126.1 v1(33.78,95.87) ; R155.1 v1(25.91,86.04) ; R142.1 v1(22.99,91) ; R153.1 v1(22.99,86.17) ; R131.1 v1(39.5,95.87) ; R115.2 v1(25.63,102.14)
  BOTTOM w0.381: C537.2 36.58,92.07 v1(36.53,92.12) ; R441.1 26.11,89.34 v1(25.91,89.34) ; v1(39.43,83.81) 40.06,84.43 R452.1 ; v1(25.91,84.52) 26.36,84.52 R455.1 ; v1(33.62,83) 33.78,83.16 C588.2
  vias: v1(37.72,91.94)
D3V3_OUT3: length 18.8
  TOP w0.229: v1(36.53,64.18) 36.12,63.77 U37.13 ; U37.43 v1(33.62,55.06)
  TOP w0.381: R217.1 v1(25.91,59.88) ; R218.1 v1(22.99,59.75) ; R203.1 v1(33.78,67.93) ; R206.1 v1(37.21,67.93) ; R215.1 v1(25.91,61.4) ; R177.2 v1(25.63,74.2) ; R205.1 v1(36.07,67.93) ; R200.1 v1(30.35,67.93) ; R223.1 v1(25.91,56.58) ; R208.1 v1(39.5,67.93) ; R220.1 v1(25.91,58.1) ; R219.1 v1(22.99,58.23) ; R214.1 v1(22.99,61.53) ; v1(22.99,63.06) R213.1
  BOTTOM w0.381: v1(25.91,56.58) 26.23,56.58 R473.1 ; R465.1 26.11,61.4 v1(25.91,61.4) ; v1(39.43,55.87) 40.06,56.49 R471.1 ; C599.2 36.58,64.13 v1(36.53,64.18) ; C606.2 33.78,55.22 v1(33.62,55.06)
  vias: v1(37.72,64)
D3V3_OUT4: length 18.8
  TOP w0.229: U48.43 v1(33.62,27.12) ; v1(36.53,36.24) 36.12,35.83 U48.13
  TOP w0.381: R262.1 v1(30.35,39.99) ; R280.1 v1(22.99,30.29) ; R279.1 v1(22.99,31.81) ; R276.1 v1(22.99,33.59) ; R268.1 v1(37.21,39.99) ; R270.1 v1(39.5,39.99) ; R275.1 v1(22.99,35.12) ; R278.1 v1(25.91,31.94) ; R267.1 v1(36.07,39.99) ; R265.1 v1(33.78,39.99) ; R277.1 v1(25.91,33.46) ; R282.1 v1(25.91,28.64) ; R252.2 v1(25.63,46.26) ; R281.1 v1(25.91,30.16)
  BOTTOM w0.381: R485.1 40.06,28.55 v1(39.43,27.93) ; R487.1 26.23,28.64 v1(25.91,28.64) ; R478.1 26.11,33.46 v1(25.91,33.46) ; C629.2 33.78,27.28 v1(33.62,27.12) ; C617.2 36.58,36.19 v1(36.53,36.24)
  vias: v1(37.72,36.06)
D3V3_VREG: length 7.1
  TOP w0.254: U25.17 207.64,92.38 C177.1 208.64,92.65 210.57,92.65 210.64,92.57 R140.1 211.38,92.63 R136.2
D5V: length 56.3
  TOP w0.381: C312.1 59.12,31.37 58.67,30.92 58.67,19.75 60.33,18.1 C382.1 63.99,19.2 R304.2 ; R167.2 v1(37.62,80.07) ; R175.2 v1(37.6,76.39) ; R6.1 16.81,152.84 v1(16.56,152.59) ; R104.2 v1(37.6,106.74) ; R171.2 v1(37.6,78.8) ; R8.1 v1(23.05,156.78) ; R303.2 v1(37.6,20.51) ; R101.2 v1(28.65,106.75) ; R169.2 v1(28.65,78.81) ; R299.2 v1(37.6,22.92) ; R102.2 v1(32.19,106.75) ; R170.2 v1(32.19,78.81) ; R298.2 v1(32.19,22.93) ; R239.2 v1(28.65,50.87) ; R248.2 v1(37.6,48.45) ; R100.2 v1(37.62,108.01) ; R297.2 v1(28.65,22.93) ; R296.2 v1(37.62,24.19) ; R236.2 v1(37.62,52.13) ; R241.2 v1(37.6,50.86) ; R240.2 v1(32.19,50.87) ; R13.2 v1(21.53,148.91) ; R260.1 v1(84.27,38.27) ; R110.2 v1(37.6,104.33)
  TOP w0.508: C303.1 81.84,31.23 ; C303.1 79.71,33.36 ; C303.1 79.71,31.23 ; C303.1 81.84,33.36
  05_PWR2 w0.508: 79.97,33.1 C303.1 ; C303.1 79.97,31.49 ; C303.1 81.58,31.49 ; C303.1 81.58,33.1
  BOTTOM w0.508: C303.1 81.84,33.36 ; C303.1 79.71,31.23 ; C303.1 79.71,33.36 ; C303.1 81.84,31.23
  vias: v1(20.45,130.37) v1(20.45,129.1) v1(20.45,102.43) v1(20.45,101.16) v1(20.45,74.49) v1(20.45,73.22) v1(20.45,46.55) v1(20.45,45.28) v1(60.2,33.52) v1(60.2,32.37) v1(61.34,33.52) v1(61.34,32.37) v1(62.48,33.52) v1(62.48,32.37) v1(63.63,33.52) v1(63.63,32.37) v1(64.77,33.52) v1(64.77,32.37) v1(72.39,33.52) v1(72.39,32.37) v1(73.53,33.52) v1(73.53,32.37) v1(74.68,33.52) v1(74.68,32.37) v1(75.82,33.52) v1(75.82,32.37) v1(76.96,33.52) v1(76.96,32.37) v1(77.85,44.26) v1(77.85,43.24) v1(78.11,33.52) v1(78.11,32.37) v1(78.87,44.26) v1(78.87,43.24) v1(79.88,44.26) v1(79.88,43.24) v1(80.9,44.26) v1(80.9,43.24)
D5V_VREG: length 7.3
  TOP w0.254: R317.2 69.58,15.88 R321.1 69.52,16.63 69.72,16.83 69.72,18.5 C371.1 69.33,19.63 U51.17
D12V: length 349.8
  TOP w0.254: U56.19 164.58,18.24 v1(164.72,18.1)
  TOP w0.381: C60.1 204.57,130.41 U9.11 ; U25.2 204.57,94.76 C171.1 ; C359.1 177.85,22.7 U54.11 ; C353.1 111.05,22.7 U53.11 ; C342.1 71.71,22.7 U51.2 ; U51.11 65.45,22.7 C341.1 ; U25.11 204.57,88.5 C188.1 ; C36.1 204.57,136.67 U9.2 ; C348.1 98.38,22.7 U52.2 ; U54.2 184.1,22.7 C360.1 ; C347.1 92.12,22.7 U52.11 ; C354.1 117.3,22.7 U53.2 ; R1.1 v1(16.4,164.3)
  TOP w0.508: 250.48,28.23 JA1.1 ; JA1.1 250.48,25.5 ; JA1.1 253.21,28.23 ; JA1.1 253.21,25.5 ; J13.4 242.74,29.57 ; J13.4 241.13,29.57 ; J13.4 241.13,27.96 ; J13.4 242.74,27.96 ; 238.48,101.71 C148.1 ; C148.1 240.62,101.71 ; C148.1 240.62,99.58 ; C148.1 238.48,99.58 ; JA1.2 253.21,29.46 ; JA1.2 250.48,29.46 ; JA1.2 250.48,32.19 ; JA1.2 253.21,32.19 ; FAN1.1 252.91,90.69 ; FAN1.1 252.91,92.82 ; FAN1.1 250.77,90.69 ; FAN1.1 250.77,92.82 ; 243.5,17.74 J15.1 ; J15.1 245.41,17.74 ; J15.1 243.5,13.83 ; J15.1 245.41,13.83 ; C227.1 240.62,74.28 ; C227.1 238.48,74.28 ; C227.1 240.62,72.15 ; C227.1 238.48,72.15 ; 250.77,74.54 FAN2.1 ; FAN2.1 252.91,72.4 ; FAN2.1 250.77,72.4 ; FAN2.1 252.91,74.54 ; 238.48,92.57 C179.1 ; C179.1 240.62,90.44 ; C179.1 240.62,92.57 ; C179.1 238.48,90.44 ; 238.48,83.43 C211.1 ; C211.1 238.48,81.29 ; C211.1 240.62,83.43 ; C211.1 240.62,81.29 ; J13.3 242.74,30.5 ; J13.3 241.13,32.11 ; J13.3 242.74,32.11 ; J13.3 241.13,30.5
  04_PWR1 w0.508: C148.1 240.36,101.45 ; C148.1 238.74,101.45 ; C148.1 238.74,99.84 ; C148.1 240.36,99.84 ; 238.74,92.31 C179.1 ; C179.1 240.36,90.7 ; C179.1 240.36,92.31 ; C179.1 238.74,90.7 ; JA1.2 253.21,29.46 ; JA1.2 253.21,32.19 ; JA1.2 250.48,32.19 ; JA1.2 250.48,29.46 ; FAN2.1 252.65,74.27 ; FAN2.1 251.04,74.27 ; FAN2.1 251.04,72.66 ; FAN2.1 252.65,72.66 ; J13.4 242.74,29.57 ; J13.4 241.13,29.57 ; J13.4 242.74,27.96 ; J13.4 241.13,27.96 ; J15.1 245.41,17.74 ; J15.1 243.5,17.74 ; J15.1 245.41,13.83 ; J15.1 243.5,13.83 ; 238.74,72.41 C227.1 ; C227.1 240.36,74.02 ; C227.1 240.36,72.41 ; C227.1 238.74,74.02 ; 250.48,28.23 JA1.1 ; JA1.1 253.21,28.23 ; JA1.1 250.48,25.5 ; JA1.1 253.21,25.5 ; 251.04,90.95 FAN1.1 ; FAN1.1 251.04,92.56 ; FAN1.1 252.65,92.56 ; FAN1.1 252.65,90.95 ; 241.13,30.5 J13.3 ; J13.3 242.74,32.11 ; J13.3 242.74,30.5 ; J13.3 241.13,32.11 ; C211.1 240.36,81.55 ; C211.1 238.74,83.16 ; C211.1 240.36,83.16 ; C211.1 238.74,81.55
  06_SIG2 w0.381: v1(16.4,164.3) 17.14,163.56 17.14,162.5 15.82,161.18 15.82,19.8 17.02,18.61 59.74,18.61 v1(61.47,20.33)
  BOTTOM w0.381: v1(164.72,18.1) 164.41,17.79 C632.1 v1(163.19,16.32)
  vias: v1(61.47,21.35) v1(62.48,21.35) v1(62.48,20.33) v1(63.5,21.35) v1(63.5,20.33) v1(64.52,21.35) v1(65.41,21.78) v1(71.75,21.78) v1(72.64,21.35) v1(73.66,21.35) v1(73.66,20.33) v1(74.68,21.35) v1(74.68,20.33) v1(75.69,21.35) v1(75.69,20.33) v1(88.14,21.35) v1(88.14,20.33) v1(89.15,21.35) v1(89.15,20.33) v1(90.17,21.35) v1(90.17,20.33) v1(91.19,21.35) v1(92.08,21.78) v1(98.42,21.78) v1(99.31,21.35) v1(100.33,21.35) v1(100.33,20.33) v1(101.35,21.35) v1(101.35,20.33) v1(102.36,21.35) v1(102.36,20.33) v1(107.06,21.35) v1(107.06,20.33) v1(108.08,21.35) v1(108.08,20.33) v1(109.09,21.35) v1(109.09,20.33) v1(110.11,21.35) v1(111,21.78) v1(117.35,21.78) v1(118.24,21.35) v1(119.25,21.35) v1(119.25,20.33) v1(120.27,21.35) v1(120.27,20.33) v1(121.28,21.35) v1(121.28,20.33) v1(150.11,18.61) v1(150.11,17.46) v1(150.11,16.32) v1(150.11,15.18) v1(151.26,18.61) v1(151.26,17.46) v1(151.26,16.32) v1(151.26,15.18) v1(152.4,18.61) v1(152.4,17.46) v1(152.4,16.32) v1(152.4,15.18) v1(153.54,18.61) v1(153.54,17.46) v1(153.54,16.32) v1(153.54,15.18) v1(154.69,18.61) v1(154.69,17.46) v1(154.69,16.32) v1(154.69,15.18) v1(155.83,18.61) v1(155.83,17.46) v1(155.83,16.32) v1(155.83,15.18) v1(156.97,18.61) v1(156.97,17.46) v1(156.97,16.32) v1(156.97,15.18) v1(158.12,18.61) v1(158.12,17.46) v1(158.12,16.32) v1(158.12,15.18) v1(159.26,18.61) v1(159.26,17.46) v1(159.26,16.32) v1(159.26,15.18) v1(160.27,18.61) v1(160.27,17.46) v1(160.27,16.32) v1(160.27,15.18) v1(161.42,18.61) v1(161.42,17.46) v1(161.42,16.32) v1(161.42,15.18) v1(173.86,21.35) v1(173.86,20.33) v1(174.88,21.35) v1(174.88,20.33) v1(175.9,21.35) v1(175.9,20.33) v1(176.91,21.35) v1(177.8,21.78) v1(184.15,21.78) v1(185.04,21.35) v1(186.06,21.35) v1(186.06,20.33) v1(187.07,21.35) v1(187.07,20.33) v1(188.09,21.35) v1(188.09,20.33) v1(205.49,136.72) v1(205.49,130.37) v1(205.49,94.81) v1(205.49,88.46) v1(205.92,140.65) v1(205.92,139.64) v1(205.92,138.62) v1(205.92,137.6) v1(205.92,129.48) v1(205.92,128.46) v1(205.92,127.44) v1(205.92,126.43) v1(205.92,98.74) v1(205.92,97.73) v1(205.92,96.71) v1(205.92,95.69) v1(205.92,87.57) v1(205.92,86.55) v1(205.92,85.53) v1(205.92,84.52) v1(206.93,140.65) v1(206.93,139.64) v1(206.93,138.62) v1(206.93,128.46) v1(206.93,127.44) v1(206.93,126.43) v1(206.93,98.74) v1(206.93,97.73) v1(206.93,96.71) v1(206.93,86.55) v1(206.93,85.53) v1(206.93,84.52) v1(244.47,101.54) v1(244.47,100.01) v1(244.47,98.49) v1(244.47,96.96) v1(244.47,95.44) v1(244.47,93.92) v1(244.47,92.39) v1(244.47,90.87) v1(244.47,89.34) v1(244.47,87.82) v1(244.47,86.3) v1(244.47,84.77) v1(244.47,83.25) v1(244.47,81.72) v1(244.47,80.2) v1(244.47,78.68) v1(244.47,77.15) v1(244.47,75.63) v1(244.47,74.1) v1(244.47,72.58) v1(244.47,71.06) v1(244.47,49.72) v1(244.47,48.2) v1(244.47,46.67) v1(244.47,45.15) v1(244.47,43.62) v1(244.47,42.1) v1(244.47,40.58) v1(244.47,39.05) v1(244.47,37.53) v1(244.47,36) v1(244.47,34.48) v1(244.47,32.96) v1(244.47,31.43) v1(244.47,29.91) v1(244.47,28.38) v1(244.47,26.86) v1(246,101.54) v1(246,100.01) v1(246,98.49) v1(246,96.96) v1(246,95.44) v1(246,93.92) v1(246,92.39) v1(246,90.87) v1(246,89.34) v1(246,87.82) v1(246,86.3) v1(246,84.77) v1(246,83.25) v1(246,81.72) v1(246,80.2) v1(246,78.68) v1(246,77.15) v1(246,75.63) v1(246,74.1) v1(246,72.58) v1(246,71.06) v1(246,49.72) v1(246,48.2) v1(246,46.67) v1(246,45.15) v1(246,43.62) v1(246,42.1) v1(246,40.58) v1(246,39.05) v1(246,37.53) v1(246,36) v1(246,32.96) v1(246,28.38) v1(246,26.86) v1(247.52,101.54) v1(247.52,100.01) v1(247.52,98.49) v1(247.52,96.96) v1(247.52,95.44) v1(247.52,93.92) v1(247.52,92.39) v1(247.52,90.87) v1(247.52,89.34) v1(247.52,87.82) v1(247.52,86.3) v1(247.52,84.77) v1(247.52,83.25) v1(247.52,81.72) v1(247.52,80.2) v1(247.52,78.68) v1(247.52,77.15) v1(247.52,75.63) v1(247.52,74.1) v1(247.52,72.58) v1(247.52,71.06) v1(247.52,49.72) v1(247.52,48.2) v1(247.52,46.67) v1(247.52,45.15) v1(247.52,43.62) v1(247.52,42.1) v1(247.52,40.58) v1(247.52,39.05) v1(247.52,37.53) v1(247.52,36) v1(247.52,34.48) v1(247.52,32.96) v1(247.52,31.43) v1(247.52,29.91) v1(247.52,28.38) v1(247.52,26.86)
GND: length 1574.2
  TOP w0.229: U19.41 v1(32.62,110.94) ; v1(33.4,36.26) 33.12,35.98 U48.19 ; U37.19 33.12,63.92 v1(33.4,64.2) ; U29.41 v1(32.62,83) ; U48.41 v1(32.62,27.12) ; U29.30 v1(28.69,87.81) ; U29.7 v1(38.06,87.81) ; U37.30 v1(28.69,59.87) ; v1(33.4,92.14) 33.12,91.86 U29.19 ; U37.7 v1(38.06,59.87) ; U37.41 v1(32.62,55.06) ; U19.19 33.12,119.8 v1(33.4,120.08) ; U19.30 v1(28.69,115.75) ; U48.30 v1(28.69,31.93) ; U48.7 v1(38.06,31.93) ; U19.7 v1(38.06,115.75)
  TOP w0.254: v1(88.52,93.03) 88.27,93.03 87.86,92.63 U26.6 ; v1(88.52,93.03) v1(88.52,92.27) 88.52,92.14 88.01,91.63 U26.4 ; v1(88.52,93.03) 88.52,93.66 89.53,94.68 ; U39.4 135.5,56.2 136.02,55.69 v1(136.5,55.69) U39.6 ; v1(205.74,131.25) 205.49,131.25 205.14,131.6 U9.12 ; v1(66.29,21.53) 66.29,21.78 66.64,22.13 U51.12 ; v1(205.74,89.34) 205.49,89.34 205.14,89.69 U25.12 ; U39.23 v1(132.33,57.86) ; v1(92.96,21.53) 92.96,21.78 93.31,22.13 U52.12 ; 216.57,53.97 216.57,53.24 v1(216.92,52.9) ; 224.27,50.47 U43.8 ; v1(178.69,21.53) 178.69,21.78 179.03,22.13 U54.12 ; U43.47 221.07,46.58 v1(220.85,46.8) ; v1(133.1,56.2) 131.57,54.67 131.17,54.67 C270.1 ; v1(111.89,21.53) 111.89,21.87 112.14,22.13 U53.12
  TOP w0.279: v1(44.36,49.63) 44.49,49.76 U42.1 ; v1(181.36,71.82) 181.75,72.21 U34.4 ; J10.8 v1(7.75,60.65) ; v1(184.4,123.13) U14.8 ; U14.4 184.9,121.72 v1(185.29,122.11) ; HDMI1.8 v1(7.75,144.47) ; HDMI1.17 v1(7.75,148.97) ; HDMI1.2 v1(7.75,141.47) ; U55.1 44.49,21.82 v1(44.36,21.69) ; J8.8 v1(7.75,88.59) ; v1(117.22,143.45) U5.8 ; J14.17 v1(7.75,37.21) ; J10.17 v1(7.75,65.15) ; J10.5 v1(7.75,59.15) ; J8.11 v1(7.75,90.09) ; J10.11 v1(7.75,62.15) ; U21.1 44.49,105.64 v1(44.36,105.51) ; J14.5 v1(7.75,31.21) ; J14.8 v1(7.75,32.71) ; J8.2 v1(7.75,85.59) ; U31.1 44.49,77.7 v1(44.36,77.57) ; J6.5 v1(7.75,115.03) ; J8.17 v1(7.75,93.09) ; v1(182.25,70.8) U34.8 ; J8.5 v1(7.75,87.09) ; HDMI1.11 v1(7.75,145.97) ; J14.11 v1(7.75,34.21) ; J14.2 v1(7.75,29.71) ; J6.17 v1(7.75,121.03) ; J6.8 v1(7.75,116.53) ; U5.4 118.63,143.95 v1(118.24,144.34) ; J6.11 v1(7.75,118.03) ; J10.2 v1(7.75,57.65) ; U26.23 v1(86.35,88.47) ; J6.2 v1(7.75,113.53) ; HDMI1.5 v1(7.75,142.97)
  TOP w0.33: U2.1 29.19,150.24 v1(29.31,150.12)
  TOP w0.356: P1.E25 v2(125.89,81.12) ; P1.D23 v2(128.89,80.12) ; P1.AC17 v2(134.89,99.12) ; P1.A28 v2(122.89,76.12) ; P1.K16 v2(135.89,85.12) P1.K15 ; P1.H14 v2(137.89,83.12) ; P1.E28 v2(122.89,80.12) ; P1.F14 v2(137.89,82.12) P1.G14 ; P1.AB19 v2(131.89,98.12) ; P1.D13 v2(137.89,79.12) P1.D14 ; P1.U19 v2(131.89,92.12) ; P1.P13 v2(138.89,89.12) ; P1.J8 v2(142.89,84.12) ; P1.J16 v2(135.89,84.12) P1.J15 ; P1.AA26 v2(124.89,97.12) ; P1.Y25 v2(125.89,96.12) ; P1.C28 v2(122.89,78.12) ; P1.B28 v2(122.89,77.12) ; P1.V25 v2(125.89,94.12) ; P1.AC16 v2(135.89,99.12) ; P1.N26 v2(124.89,88.12) ; P1.R20 v2(130.89,90.12) ; P1.AA22 v2(128.89,97.12) ; P1.C14 v2(137.89,78.12) ; P1.N21 v2(129.89,88.12) ; P1.Y26 v2(124.89,96.12) ; P1.AL12 v2(138.89,106.12) ; P1.AD23 v2(127.89,100.12) ; P1.R15 v2(136.89,90.12) ; P1.W13 v2(138.89,95.12) ; P1.T12 v2(138.89,91.12) ; P1.V21 v2(129.89,94.12) ; P1.L12 v2(139.89,86.12) ; P1.U26 v2(124.89,92.12) ; v2(121.89,92.12) P1.T29 ; P1.R25 v2(125.89,90.12) ; P1.M14 v2(137.89,87.12) ; P1.B14 v2(137.89,77.12) ; P1.E14 v2(137.89,80.12) ; P1.A27 v2(123.89,76.12) ; P1.AD18 v2(132.89,100.12) ; P1.T22 v2(128.89,91.12) ; P1.L15 v2(136.89,86.12) ; P1.V16 v2(135.89,94.12) ; P1.AA25 v2(125.89,97.12) ; P1.AC25 v2(125.89,99.12) ; P1.Y20 v2(130.89,96.12) ; P1.AE13 v2(138.89,100.12) ; P1.E15 v2(135.89,81.12) ; P1.AD13 v2(137.89,99.12) ; P1.T26 v2(124.89,91.12) ; P1.T17 v2(134.89,91.12) ; P1.L25 v2(125.89,87.12) P1.M25 ; P1.P26 v2(124.89,89.12) ; P1.U14 v2(137.89,92.12) ; P1.AC19 v2(131.89,99.12) ; P1.U24 v2(126.89,92.12) ; P1.W25 v2(125.89,95.12) ; P1.W23 v2(127.89,95.12) ; P1.F28 v2(122.89,81.12) ; P1.C26 v2(125.89,78.12) ; P1.J14 v2(137.89,84.12) ; P1.B24 v2(127.89,78.12) ; P1.A12 v2(138.89,76.12) ; P1.M19 v2(131.89,87.12) ; P1.AA12 v2(139.89,97.12) ; P1.M16 v2(135.89,87.12) ; P1.W18 v2(132.89,95.12) ; P1.AJ13 v2(138.89,105.12) ; P1.AA17 v2(134.89,97.12) ; P1.L16 v2(135.89,86.12) ; P1.F27 v2(123.89,81.12) ; P1.P23 v2(127.89,89.12) ; P1.V26 v2(124.89,94.12) ; P1.P18 v2(132.89,89.12) ; P1.M15 v2(136.89,87.12) ; P1.L17 v2(134.89,86.12)
  TOP w0.381: P1.D28 v2(122.89,79.12) ; P1.M34 P1.M33 v2(118.89,87.12) ; U40.A2 v3(165.18,55.56) ; U28.M9 v3(174.38,92.67) ; v1(19.56,120.08) R78.1 21.15,120.91 Q3.2 ; U50.2 v1(205.87,28.13) ; U32.F9 v3(169.98,77.2) U32.G9 ; v2(141.89,96.12) P1.Y10 ; U8.C8 v3(166.78,138.63) ; P1.C31 v2(119.89,78.12) P1.C32 ; P1.C29 v2(121.89,78.12) ; v2(144.89,83.12) P1.H6 ; U11.G1 123.25,129.59 C65.2 v3(126.36,129.59) ; v2(145.89,85.12) P1.K5 ; P1.Y30 v2(120.89,96.12) ; P1.H34 v2(117.89,83.12) P1.H33 ; C169.2 v3(174.78,95.58) ; v2(134.39,75.95) P1.A17 ; P1.F34 v2(117.89,81.12) P1.F33 ; v1(15.02,89.58) U27.8 U27.3 v1(17.58,89.58) ; P1.AM34 P1.AM33 v2(118.89,107.12) ; U40.A3 v3(165.18,56.36) ; U16.T7 v3(177.98,122.59) ; v3(130.89,133.02) 131.29,133.42 U12.M9 ; P1.A22 v2(129.89,76.12) ; P1.D33 v2(117.89,79.12) P1.D34 ; C159.2 v1(83.08,96.73) ; v2(144.89,77.12) P1.A7 ; U32.E2 v3(168.38,70.8) ; U6.B3 v1(152.76,141.31) ; C240.2 v3(168.78,65.1) ; P1.L30 v2(120.89,87.12) ; R201.2 v1(31.5,67.93) ; C134.2 v3(165.74,112.09) ; U40.T7 v3(177.98,60.36) ; U10.A2 v3(107.45,124.22) ; P1.AN31 v2(119.89,109.12) ; C374.2 v1(95.63,17.4) ; R70.2 v1(34.92,123.81) ; P1.M31 v2(119.89,88.12) P1.M32 ; C52.2 v3(113.14,133.82) ; U22.T3 v3(177.98,103.35) ; C105.2 v3(141.88,123.51) ; C180.2 v1(78.99,90.87) ; P1.AF2 v2(149.89,102.12) ; U10.T3 v3(106.65,137.02) ; P1.A33 v2(118.89,76.12) ; U32.E8 v3(168.38,76.4) ; U40.F9 v3(169.98,61.96) U40.G9 ; v1(15.02,30.27) U49.8 U49.3 v1(17.58,30.27) ; C77.2 v3(97.9,127.83) ; R238.1 v1(209.75,53.28) ; v3(172.38,98.87) 172.23,99.02 C149.2 ; C61.2 v3(97.9,129.48) ; v2(124.89,102.12) P1.AG27 ; v2(124.89,102.12) P1.AF26 ; v2(124.89,102.12) P1.AG26 ; C229.2 23.15,68.61 22.32,69.43 U33.2 ; P1.D29 v2(121.89,79.12) ; P1.AE29 v2(121.89,101.12) ; C206.2 v3(164.47,82.09) ; U10.E2 v3(107.45,127.42) ; C90.2 v3(165.74,127.33) ; C126.2 v3(165.99,113.84) ; C104.2 v3(126.64,123.51) ; C42.2 v3(141.88,135.45) ; U12.B3 v3(137.13,125.02) ; v2(148.89,84.12) P1.J3 ; U11.J2 v3(121.89,131.42) ; C386.2 v1(164.34,15.18) ; U32.G1 v3(169.98,70) ; U12.D8 v3(132.33,126.62) ; U16.B1 v3(165.98,116.99) ; U40.C2 v3(166.78,55.56) ; U12.G8 v3(132.33,129.02) ; P1.AA31 v2(119.89,97.12) ; P1.A32 v2(119.89,76.12) P1.A31 ; v1(15.02,37.21) U46.8 U46.3 v1(17.58,37.21) ; P1.AL32 v2(119.89,107.12) P1.AL31 ; C294.2 23.15,40.67 22.32,41.49 U44.2 ; U8.T3 v3(177.98,133.83) ; Q4.2 21.15,92.97 R138.1 v1(19.81,92.14) ; P1.H21 v2(129.89,83.12) ; C197.2 v1(87.99,85.64) ; U10.A7 v3(102.65,124.22) ; P1.J28 v2(122.89,84.12) ; U28.T1 v3(177.98,85.24) 178.46,84.76 C198.2 ; C81.2 v3(111.4,127.44) ; U10.G9 v3(101.05,129.02) U10.F9 ; P1.AA29 v2(121.89,97.12) ; P1.K17 v2(134.89,86.12) ; C207.2 v3(165.99,82.09) ; R266.2 v1(34.92,39.99) ; P1.AF30 v2(120.89,102.12) ; C14.2 v3(165.74,142.57) ; P1.AD21 v2(129.89,100.12) ; C219.2 v3(174.78,80.34) ; C99.2 v3(97.9,124.78) ; U8.C2 v3(166.78,133.03) ; U28.B1 v3(165.98,85.24) ; v3(100.82,122.11) C108.2 100.82,123.99 U10.A9 ; P1.Y29 v2(121.89,96.12) ; U10.D8 v3(101.85,126.62) ; U32.T7 v3(177.98,75.6) ; v1(17.65,141.67) 16.76,141.67 U7.3 U7.8 15.01,141.65 v1(14.99,141.67) ; P1.AF29 v2(121.89,102.12) ; U32.M1 v3(174.78,70) ; U22.E1 v3(168.38,101.75) ; v2(148.89,82.12) P1.F2 ; C92.2 v3(168.78,127.33) ; U28.A9 164.95,92.66 C175.2 v3(163.07,92.66) ; U28.J2 v3(172.38,86.04) ; C53.2 v3(126.64,133.82) ; C153.2 v3(174.78,98.6) ; P1.U29 v2(121.89,92.12) ; U11.E2 v3(122.69,127.42) ; C167.2 v3(168.78,95.58) ; C242.2 v3(174.78,65.1) ; U10.C2 v3(107.45,125.82) ; P1.H29 v2(121.89,83.12) ; R89.1 v3(172.38,112.13) ; U8.J2 v3(172.38,133.03) ; R48.1 v3(97.86,132.22) ; C212.2 33.24,80.82 R163.2 v1(33.27,80) ; U8.T1 v3(177.98,132.23) ; v2(145.89,94.12) P1.V6 ; U10.D1 v3(108.25,126.62) ; v3(131.3,122.11) C110.2 131.3,123.99 U12.A9 ; P1.AN11 v2(139.89,109.12) ; R90.2 v1(34.49,109.01) ; v3(170.43,127.33) C93.2 ; U10.J2 v3(106.65,131.42) ; P1.K29 v2(121.89,86.12) ; U10.M9 v3(101.05,133.82) ; v3(170.43,112.09) C137.2 ; R68.2 v1(32.64,123.81) ; U16.E1 v3(168.38,116.99) ; P1.AC32 v2(118.89,98.12) P1.AB32 v2(118.89,97.12) ; R91.2 v1(38.03,109.01) ; P1.E29 v2(121.89,80.12) ; C18.2 v3(174.78,142.57) ; U11.E8 v3(117.09,127.42) ; U28.T7 v3(177.98,90.84) ; P1.Y33 v2(117.89,96.12) P1.Y34 ; U8.B1 v3(165.98,132.23) ; C231.2 172.23,67.27 v3(172.38,67.12) ; P1.K20 v2(130.89,85.12) ; v1(14.99,146.09) U4.8 U4.3 v1(17.65,146.09) ; P1.AK30 v2(121.89,106.12) P1.AK29 ; U12.T1 v3(138.73,137.02) 139.21,137.5 C32.2 ; U22.M1 v3(174.78,101.75) ; P1.AD33 v2(117.89,100.12) P1.AD34 ; U11.G9 v3(116.29,129.02) U11.F9 ; U32.P1 v3(176.38,70) ; P1.N30 v2(120.89,89.12) ; U28.E1 v3(168.38,85.24) ; C71.2 v3(168.4,129.08) ; U40.M9 174.38,62.19 v3(173.98,62.59) ; C195.2 v1(83.82,84.82) ; C41.2 v3(128.38,135.42) ; v2(149.89,106.12) P1.AL2 ; P1.AM30 v2(121.89,108.12) P1.AM29 ; U22.J8 v3(172.38,108.15) ; P1.AE26 v2(124.89,101.12) ; P1.AD30 v2(120.89,100.12) P1.AE30 ; v1(14.92,150.62) 15.05,150.75 U3.8 U3.3 17.33,150.75 v1(17.65,150.43) ; v3(170.43,142.57) C17.2 ; v2(124.89,109.12) P1.AN26 ; U32.T1 v3(177.98,70) ; v2(150.89,88.12) P1.N1 ; v1(19.94,64.2) R211.1 21.15,65.03 Q5.2 ; P1.L31 v2(119.89,87.12) P1.L32 ; U40.P9 v3(176.38,61.96) ; v2(147.89,105.12) P1.AJ3 ; U10.E1 v3(108.25,127.42) ; U40.T1 v3(177.98,54.76) ; C236.2 v3(176.38,66.85) ; Q2.2 v1(25.93,155.83) ; U40.G8 v3(169.98,61.16) ; U10.B9 v3(101.05,125.02) ; U10.P9 v3(101.05,135.42) ; U32.E1 v3(168.38,70) ; P1.T32 v2(118.89,92.12) P1.U32 ; U12.E8 v3(132.33,127.42) ; P1.AP23 v2(128.89,110.12) ; C183.2 v1(209.87,90.49) ; U22.E8 v3(168.38,108.15) ; U22.G9 v3(169.98,108.95) U22.F9 ; U22.E2 v3(168.38,102.55) ; U11.B3 v3(121.89,125.82) ; U16.G1 v3(169.98,116.99) ; U16.M1 v3(174.78,116.99) ; U12.P1 v3(138.73,135.42) ; v2(145.89,100.12) P1.AE5 ; P1.E32 v2(119.89,80.12) P1.E31 ; C91.2 v3(167.26,127.33) ; P1.AF18 v2(133.89,102.12) ; U40.A7 v3(165.18,60.36) ; U12.T3 v3(137.13,137.02) ; C87.2 v3(174.78,127.46) ; v2(149.89,86.12) P1.L2 ; v3(173.98,77.83) 174.38,77.43 U32.M9 ; P1.L29 v2(121.89,87.12) ; v2(118.89,97.12) P1.AA32 ; v2(118.89,97.12) P1.AB33 P1.AB34 ; v1(33.27,24.12) R290.2 33.24,24.94 C335.2 ; U32.J2 v3(172.38,70.8) ; U16.J8 v3(172.38,123.39) ; P1.AK34 P1.AK33 v2(118.89,105.12) ; U40.A9 164.95,62.18 C255.2 v3(163.07,62.18) ; P1.V29 v2(121.89,94.12) ; C364.1 v1(37.63,21.65) ; U12.J2 v3(137.13,131.42) ; U16.J2 v3(172.38,117.79) ; C209.2 v3(174.78,82.09) ; U23.2 22.32,97.37 23.15,96.55 C163.2 ; v1(33.27,52.06) R232.2 33.24,52.88 C272.2 ; U16.E2 v3(168.38,117.79) ; U40.J2 v3(172.38,55.56) ; v3(163.07,139.65) C31.2 164.95,139.65 U8.A9 ; U40.G1 v3(169.98,54.76) ; C234.2 v3(168.4,66.85) ; P1.AM14 v2(136.89,107.12) ; P1.AM24 v2(126.89,108.12) ; P1.AJ32 v2(119.89,105.12) P1.AJ31 ; P1.A30 v2(120.89,76.12) ; U40.E1 v3(168.38,54.76) ; v2(137.89,103.12) P1.AG14 ; P1.N6 145.89,89.12 v2(145.89,89.12) ; U22.B1 v3(165.98,101.75) ; v2(144.89,78.12) P1.C6 ; U22.B9 v3(165.98,108.95) ; v2(122.89,82.12) P1.G28 ; P1.F29 v2(121.89,81.12) ; v3(163.07,77.42) C223.2 164.95,77.42 U32.A9 ; v2(131.89,77.12) P1.B19 ; U12.T9 v3(131.53,137.02) ; C16.2 v3(168.78,142.57) ; U10.T7 v3(102.65,137.02) ; U10.P1 v3(108.25,135.42) ; C98.2 v3(141.88,125.03) ; v2(147.89,87.12) P1.M4 ; P1.AB29 v2(121.89,98.12) P1.AC29 v2(121.89,99.12) P1.AD29 ; C141.2 33.24,108.76 R95.2 v1(33.27,107.94) ; U11.P9 v3(116.29,135.42) ; U10.B3 v3(106.65,125.02) ; R311.1 v1(97.41,20.13) ; C135.2 v3(167.26,112.09) ; v3(168.4,51.75) 169.02,51.75 C277.2 ; C129.2 v3(176.38,113.84) ; U28.B9 v3(165.98,92.44) ; U22.P9 v3(176.38,108.95) ; U10.A3 v3(106.65,124.22) ; v1(17.58,86.15) U30.3 U30.8 v1(15.02,86.15) ; P1.T34 P1.T33 v2(118.89,91.12) ; U32.B9 v3(165.98,77.2) ; P1.AP18 v2(133.89,109.12) ; v2(146.89,108.12) P1.AM4 ; U16.T1 v3(177.98,116.99) ; v2(140.89,81.12) P1.E10 ; v3(116.06,122.11) C109.2 116.06,123.99 U11.A9 ; U12.B1 v3(138.73,125.02) ; P1.AF34 v2(117.89,102.12) P1.AF33 ; C37.2 v3(97.9,135.42) ; v2(144.89,102.12) P1.AF7 ; U28.T3 v3(177.98,86.84) ; C232.2 v3(164.47,66.85) ; P1.AN21 v2(129.89,109.12) ; U16.T9 v3(177.98,124.19) ; P1.AP11 v2(139.89,110.12) ; v1(15.02,65.15) U35.8 U35.3 v1(17.58,65.15) ; U32.T3 v3(177.98,71.6) ; U40.D1 v3(167.58,54.76) ; P1.R30 v2(120.89,91.12) ; v2(147.89,78.12) P1.B4 ; v2(142.89,108.12) P1.AM9 ; C256.2 141.06,61.27 v1(140.56,60.77) ; P1.M30 v2(120.89,88.12) ; R122.1 v1(29.21,95.87) ; U8.E2 v3(168.38,133.03) ; P1.AP33 v2(118.89,109.12) P1.AN32 ; v1(17.58,117.52) U17.3 U17.8 v1(15.02,117.52) ; v2(122.89,83.12) P1.H28 ; U32.T9 v3(177.98,77.2) ; P1.H16 v2(135.89,83.12) ; U10.T1 v3(108.25,137.02) ; U28.G8 v3(169.98,91.64) ; U28.T9 v3(177.98,92.44) ; v3(173.98,109.58) 174.38,109.18 U22.M9 ; P1.G29 v2(121.89,82.12) ; P1.K27 v2(124.89,85.12) P1.K26 ; U16.T3 v3(177.98,118.59) ; v1(66.29,17.36) R308.1 ; U8.M1 v3(174.78,132.23) ; P1.D30 v2(120.89,79.12) ; C282.1 v1(37.63,49.59) ; U12.B9 v3(131.53,125.02) ; P1.K30 v2(120.89,86.12) ; v2(148.89,77.12) P1.B2 ; U8.T9 v3(177.98,139.43) ; v2(142.89,79.12) P1.D8 ; R237.2 v1(208.91,50.99) ; v1(80.9,39.43) 81.61,39.43 R259.2 ; U40.C8 v3(166.78,61.16) ; U16.P1 v3(176.38,116.99) ; v3(128.38,126.3) C86.2 ; R287.2 v1(38.03,25.19) ; U8.P1 v3(176.38,132.23) ; U16.B3 v3(165.98,118.59) ; U8.G8 v3(169.98,138.63) ; C203.2 172.23,82.41 v3(172.38,82.26) ; R49.1 v3(113.1,132.22) ; C83.2 v3(141.88,127.44) ; C177.2 v1(209.87,92.01) ; v2(141.89,106.12) P1.AK10 ; U12.M1 v3(138.73,133.82) ; v2(118.82,103.14) 118.39,103.57 P1.AH33 P1.AH34 ; P1.AJ16 v2(134.89,105.12) ; U13.2 22.32,125.31 23.15,124.49 C106.2 ; C94.2 v3(176.38,127.33) ; v1(179.83,17.4) C379.2 ; C125.2 v3(164.47,113.84) ; v2(145.89,104.12) P1.AH6 ; C4.1 v1(22.73,148.92) ; R59.1 v3(173.18,127.37) ; U28.B3 v3(165.98,86.84) ; P1.G30 v2(120.89,82.12) ; U12.P9 v3(131.53,135.42) ; v2(142.89,109.12) P1.AP8 ; C170.2 v3(176.38,95.58) ; P1.V34 v2(117.89,94.12) P1.V33 ; U10.M1 v3(108.25,133.82) ; R227.2 v1(38.03,53.13) ; U8.J8 v3(172.38,138.63) ; U11.B1 v3(123.49,125.02) ; R67.2 v1(31.5,123.81) ; P1.AH30 v2(121.89,104.12) P1.AH29 ; v1(217.93,41.21) 218.06,41.34 R254.2 ; P1.U30 v2(120.89,92.12) P1.T30 ; v1(15.02,93.09) U24.8 U24.3 v1(17.58,93.09) ; C152.2 v3(168.4,98.6) ; R212.1 v3(172.38,65.14) ; U11.G8 v3(117.09,129.02) ; C220.2 v3(176.38,80.34) ; P1.P31 v2(119.89,90.12) P1.P32 ; U28.D8 v3(167.58,91.64) ; v2(144.89,81.12) P1.F7 ; P1.H30 v2(120.89,83.12) ; U10.C8 v3(101.85,125.82) ; R263.2 v1(31.5,39.99) ; U10.T9 v3(101.05,137.02) ; P1.AG28 v2(122.89,103.12) ; v2(143.89,87.12) P1.L7 ; R310.1 v1(92.96,17.36) ; v2(131.89,108.12) P1.AM19 ; U40.D7 v3(167.58,60.36) ; U16.P9 v3(176.38,124.19) ; C217.2 v3(168.78,80.34) ; P1.Y32 v2(118.89,96.12) ; C278.2 175.02,51.61 v3(174.88,51.75) ; C218.2 v3(170.43,80.34) ; C165.2 v3(165.74,95.58) ; U10.D7 v3(102.65,126.62) ; U10.J8 v3(101.85,131.42) ; P1.AM28 v2(122.89,108.12) ; v2(149.89,91.12) P1.T2 ; C210.2 v3(176.38,82.09) ; P1.U31 v2(119.89,92.12) P1.T31 ; P1.R32 v2(119.89,91.12) P1.R31 v2(120.89,90.12) P1.P30 v2(121.89,90.12) P1.P29 ; U28.G1 v3(169.98,85.24) ; C268.2 v1(141.11,55.83) ; U28.P9 v3(176.38,92.44) ; v2(146.89,97.12) P1.AB4 ; v3(172.38,129.35) 172.23,129.5 C67.2 ; R284.2 207.77,26.3 v1(207.77,25.84) ; R124.2 v1(31.5,95.87) ; U22.T7 v3(177.98,107.35) ; U12.E1 v3(138.73,127.42) ; U28.D1 v3(167.58,85.24) ; C380.2 v1(181.36,17.4) ; U8.D1 v3(167.58,132.23) ; U22.G1 v3(169.98,101.75) ; R50.1 v3(128.34,131.42) ; U32.J8 v3(172.38,76.4) ; v1(15.02,33.7) U47.8 U47.3 v1(17.58,33.7) ; C150.2 v3(164.47,98.6) ; R312.1 v1(111.89,17.36) ; U40.T9 v3(177.98,61.96) ; v2(149.89,96.12) P1.AA2 ; v2(150.89,98.12) P1.AC1 ; C136.2 v3(168.78,112.09) ; P1.W30 v2(120.89,95.12) ; U11.M1 v3(123.49,133.82) ; C196.1 v1(84.96,87.52) ; U12.T7 v3(133.13,137.02) ; U40.T3 v3(177.98,56.36) ; P1.AD31 v2(119.89,100.12) P1.AE31 ; v2(122.89,110.12) P1.AP28 ; R202.2 v1(32.64,67.93) ; P1.W3 v2(148.89,95.12) ; P1.K33 v2(117.89,85.12) P1.K34 ; C176.2 v1(78.99,92.01) ; v2(145.89,90.12) P1.R5 ; U40.E8 v3(168.38,61.16) ; U8.P9 v3(176.38,139.43) ; U32.D8 v3(167.58,76.4) ; U16.E8 v3(168.38,123.39) ; R264.2 v1(32.64,39.99) ; U40.J8 v3(172.38,61.16) ; C239.2 v3(167.26,65.1) ; C139.2 v3(176.38,112.09) ; v3(113.14,126.3) C85.2 ; P1.AL28 v2(122.89,106.12) P1.AK28 ; C154.2 v3(176.38,98.6) ; v2(132.89,79.12) P1.D18 ; U40.D8 v3(167.58,61.16) ; P1.W32 v2(118.89,95.12) ; P1.B33 v2(117.89,77.12) P1.B34 ; P1.G32 v2(119.89,82.12) P1.G31 ; C238.2 v3(165.74,65.1) ; P1.AG4 v2(147.89,102.12) ; v2(147.89,92.12) P1.U4 ; v2(124.89,87.12) P1.M26 ; C73.2 v3(176.38,129.08) ; U32.B3 v3(165.98,71.6) ; P1.AH11 v2(140.89,104.12) ; U11.T7 v3(117.89,137.02) ; C279.2 176.55,51.61 v3(176.4,51.75) ; C373.2 v1(94.11,17.4) ; U28.G9 v3(169.98,92.44) U28.F9 ; P1.W29 v2(121.89,95.12) ; C124.2 172.23,114.26 v3(172.38,114.11) ; v2(146.89,106.12) P1.AK5 ; v1(15.02,114.09) U20.8 U20.3 v1(17.58,114.09) ; v2(140.89,91.12) P1.R10 ; v3(111.12,129.02) 110.93,129.02 C64.2 108.01,129.59 U10.G1 ; U8.B8 v3(165.98,138.63) ; R52.1 v1(209.93,131.25) ; P1.C21 v2(130.89,78.12) ; U10.E8 v3(101.85,127.42) ; U12.G9 v3(131.53,129.02) U12.F9 ; P1.C11 v2(140.89,78.12) ; v1(15.02,61.64) U36.8 U36.3 v1(17.58,61.64) ; P1.AB31 v2(119.89,98.12) P1.AC31 ; v3(141.6,129.59) C66.2 138.49,129.59 U12.G1 ; P1.E30 v2(120.89,80.12) ; C215.2 v3(165.74,80.34) ; U11.E1 v3(123.49,127.42) ; R159.2 v1(34.49,81.07) ; R121.1 v3(172.62,95.62) ; U28.P1 v3(176.38,85.24) ; U12.E2 v3(137.93,127.42) ; P1.AG19 v2(132.89,103.12) ; R313.1 v1(116.33,20.13) ; v1(19.94,36.26) R274.1 21.15,37.09 Q6.2 ; P1.M29 v2(121.89,88.12) ; U40.B8 v3(165.98,61.16) ; v1(88.46,97.54) 88.39,97.47 C162.2 ; C377.2 v1(114.55,17.4) ; Q1.2 17.69,154.57 R9.2 16.44,153.9 v1(16.57,153.77) ; U11.B9 v3(116.29,125.02) ; R247.1 R245.1 209.04,49.72 v1(208.91,49.85) ; C100.2 v3(113.14,124.78) ; v2(142.89,82.12) P1.G9 ; U28.E8 v3(168.38,91.64) ; R226.2 v1(34.49,53.13) ; U16.B9 v3(165.98,124.19) ; v3(170.43,65.1) C241.2 ; C39.2 v3(113.14,135.42) ; C72.2 v3(174.78,129.08) ; v2(148.89,100.12) P1.AD3 ; v2(128.89,86.12) P1.L22 ; C144.1 v1(37.63,105.47) ; P1.V30 v2(120.89,94.12) ; U32.B1 v3(165.98,70) ; P1.AJ28 v2(122.89,104.12) P1.AH28 ; C54.2 v3(128.38,133.82) ; U28.M1 v3(174.78,85.24) ; C97.2 v3(126.64,125.03) ; C216.2 v3(167.26,80.34) ; U8.F9 v3(169.98,139.43) U8.G9 ; U40.C3 v3(166.78,56.36) ; v2(124.89,99.12) P1.AD26 ; U22.B3 v3(165.98,103.35) ; U40.E2 v3(168.38,55.56) ; C79.2 v3(128.38,127.83) ; v1(128.78,60.01) 129.29,60.52 C258.2 ; v2(145.89,109.12) P1.AN6 ; U8.G1 v3(169.98,132.23) ; v3(163.07,124.41) C107.2 164.95,124.41 U16.A9 ; P1.Y31 v2(119.89,96.12) ; U11.M9 v3(116.29,133.82) ; P1.C30 v2(120.89,78.12) ; U40.B9 v3(165.98,61.96) ; P1.J32 v2(119.89,84.12) P1.J31 ; P1.AL17 v2(133.89,106.12) ; U22.P1 v3(176.38,101.75) ; U12.J8 v3(132.33,131.42) ; v1(70.74,20.13) R309.1 ; U22.T9 v3(177.98,108.95) ; C235.2 v3(174.78,66.85) ; v2(146.89,81.12) P1.E5 ; v2(150.89,104.12) P1.AH1 ; C243.2 v3(176.38,65.1) ; v3(164.59,51.75) 165.08,51.75 C275.2 ; P1.N31 v2(119.89,89.12) P1.N32 ; v2(143.89,105.12) P1.AJ8 ; v2(146.89,83.12) P1.G4 ; v1(67.44,17.4) C370.2 ; C208.2 v3(168.4,82.09) ; U11.T3 v3(121.89,137.02) ; U40.M1 v3(174.78,54.76) ; C222.1 v1(37.63,77.53) ; P1.N29 v2(121.89,89.12) ; U8.D7 v3(167.58,137.83) ; U8.A2 v3(165.18,133.03) ; C371.2 v1(68.96,17.4) ; v2(129.89,103.12) P1.AH21 ; P1.AC11 v2(139.89,99.12) ; C273.2 v3(172.23,51.69) ; P1.R29 v2(121.89,91.12) ; R135.1 v1(207.14,93.79) ; C15.2 v3(167.26,142.57) ; v2(126.89,106.12) P1.AK25 ; P1.AG32 v2(119.89,103.12) P1.AG31 ; v2(118.89,89.12) P1.P33 P1.P34 ; v3(165.99,51.75) 166.61,51.75 C276.2 ; U11.T1 v3(123.49,137.02) ; C233.2 v3(165.99,66.85) ; U11.J8 v3(117.09,131.42) ; v1(15.02,58.21) U41.8 U41.3 v1(17.58,58.21) ; U11.P1 v3(123.49,135.42) ; v2(142.89,78.12) P1.B9 ; C166.2 v3(167.26,95.58) ; U40.B1 v3(165.98,54.76) ; C62.2 v3(113.14,129.48) ; C376.2 v1(113.03,17.4) ; v3(163.07,109.17) C142.2 164.95,109.17 U22.A9 ; P1.F30 v2(120.89,81.12) ; U22.D8 v3(167.58,108.15) ; U8.A7 v3(165.18,137.83) ; U10.G8 v3(101.85,129.02) ; U12.D1 v3(138.73,126.62) ; P1.AC30 v2(120.89,98.12) P1.AB30 ; P1.W31 v2(119.89,95.12) ; U16.D8 v3(167.58,123.39) ; U8.B3 v3(165.98,133.83) ; U11.T9 v3(116.29,137.02) ; P1.AD32 v2(118.89,100.12) P1.AE32 ; v3(170.43,95.58) C168.2 ; U8.E1 v3(168.38,132.23) ; U22.D1 v3(167.58,101.75) ; C19.2 v3(176.38,142.57) ; U8.M9 v3(174.78,139.43) ; R23.1 v3(173.18,142.61) ; P1.H26 v2(125.89,84.12) ; C51.2 v3(111.4,133.82) ; C78.2 v3(113.14,127.83) ; U8.E8 v3(168.38,138.63) ; R261.1 v1(29.21,39.99) ; v1(209.93,132.27) 209.8,132.4 C57.2 ; v1(183.13,20.13) R315.1 ; C103.2 v3(111.4,123.51) ; R44.1 v1(207.14,135.7) ; P1.AL22 v2(129.89,106.12) ; P1.AP30 v2(120.89,109.12) P1.AN30 ; C127.2 v3(168.4,113.84) ; C147.2 178.59,101.14 v3(177.98,101.75) U22.T1 ; C40.2 v3(126.64,135.42) ; U32.P9 v3(176.38,77.2) ; R199.1 v1(29.21,67.93) ; U8.C3 v3(166.78,133.83) ; P1.B30 v2(120.89,77.12) ; U40.P1 v3(176.38,54.76) ; C151.2 v3(165.99,98.6) ; U10.C3 v3(106.65,125.82) ; R168.1 v3(172.38,80.38) ; P1.AA30 v2(120.89,97.12) ; U8.D8 v3(167.58,138.63) ; C265.2 v1(219.82,57.32) ; R65.1 v1(29.21,123.81) ; P1.J30 v2(121.89,84.12) P1.J29 P1.K28 ; C55.2 v3(141.88,133.92) ; U16.G8 v3(169.98,123.39) ; R204.2 v1(34.92,67.93) ; C96.2 v3(111.4,125.03) ; C138.2 v3(174.78,112.09) ; R127.2 v1(34.92,95.87) ; U28.J8 v3(172.38,91.64) ; C128.2 v3(174.78,113.84) ; U8.T7 v3(177.98,137.83) ; U11.D1 v3(123.49,126.62) ; P1.AN16 v2(135.89,108.12) ; C50.2 v3(97.9,133.82) ; v1(178.69,17.36) R314.1 ; v3(128.38,124.78) C101.2 ; U16.F9 v3(169.98,124.19) U16.G9 ; U22.G8 v3(169.98,108.15) ; U32.G8 v3(169.98,76.4) ; C56.2 v1(209.93,133.92) ; P1.V32 v2(118.89,94.12) ; U8.B9 v3(165.98,139.43) ; U16.D1 v3(167.58,116.99) ; R286.2 v1(34.49,25.19) ; C38.2 v3(111.4,135.42) ; U8.A3 v3(165.18,133.83) ; C267.2 v1(129.52,56.09) ; U11.D8 v3(117.09,126.62) ; U40.B3 v3(165.98,56.36) ; U28.E2 v3(168.38,86.04) ; U16.M9 v3(174.78,124.19) ; v2(149.89,78.12) P1.C1 ; v2(135.89,78.12) P1.C16 ; v1(15.02,121.03) U15.8 U15.3 v1(17.58,121.03) ; v2(143.89,107.12) P1.AL7 ; P1.K31 v2(119.89,86.12) ; C82.2 v3(126.64,127.44) ; P1.E20 v2(130.89,81.12) ; P1.AJ18 v2(133.89,105.12) ; U32.D1 v3(167.58,70) ; P1.B29 v2(121.89,77.12) ; R147.1 v1(209.9,89.34) ; v2(148.89,89.12) P1.P3 ; P1.V31 v2(119.89,94.12) ; v2(150.89,83.12) P1.H1 ; U10.B1 v3(108.25,125.02) ; C70.2 v3(165.99,129.08) ; U22.J2 v3(172.38,102.55) ; C69.2 v3(164.47,129.08) ; P1.AB26 v2(124.89,97.12) ; R14.1 v1(153.52,146.84) ; R125.2 v1(32.64,95.87) ; v3(128.38,129.48) C63.2 ; C84.2 v3(97.9,126.3) ; v2(148.89,79.12) P1.D3 ; P1.K32 v2(118.89,86.12) ; R160.2 v1(38.03,81.07) ; v2(136.89,101.12) P1.AE15 ; U10.B8 v3(101.85,125.02)
  TOP w0.457: v2(136.89,96.12) P1.Y15 ; v2(150.89,94.12) P1.V1 ; v2(138.89,110.12) P1.AP13 ; P1.V11 v2(140.89,94.12)
  TOP w0.508: v1(141.22,50.86) 141.05,50.69 Y3.2 ; 235.61,51.67 J11.6 ; J11.6 235.61,50.06 ; J11.6 237.22,50.06 ; J11.6 237.22,51.67 ; J4.2 153.21,153.28 ; J4.2 151.6,153.28 ; J4.2 153.21,151.66 ; J4.2 151.6,151.66 ; U38.4 v1(229.74,62.17) ; C307.2 194.1,27.99 ; C307.2 192.49,29.6 ; C307.2 194.1,29.6 ; C307.2 192.49,27.99 ; C7.2 199.28,146.6 ; C7.2 197.67,146.6 ; C7.2 197.67,144.99 ; C7.2 199.28,144.99 ; C248.2 134.75,64.96 v1(134.37,65.34) ; C145.2 199.28,103.08 ; C145.2 199.28,104.69 ; C145.2 197.67,104.69 ; C145.2 197.67,103.08 ; C304.2 127.17,27.99 ; C304.2 125.56,29.6 ; C304.2 127.17,29.6 ; C304.2 125.56,27.99 ; v1(226.39,46.93) 226.14,46.67 v1(224.92,46.67) C284.1 ; v1(226.39,46.93) v1(229.36,46.93) v1(229.36,50.5) Y5.4 v1(228.27,51.75) v1(225.68,51.75) 225.53,51.75 C281.1 ; v1(226.39,46.93) Y5.2 ; U45.2 v1(83.19,41.34) ; 7.2,160.97 U1.4 8.81,160.97 ; C305.2 136.44,27.99 ; C305.2 136.44,29.6 ; C305.2 134.83,27.99 ; C305.2 134.83,29.6 ; J4.10 163.37,153.28 ; J4.10 161.76,153.28 ; J4.10 161.76,151.66 ; J4.10 163.37,151.66 ; C303.2 81.58,29.6 ; C303.2 81.58,27.99 ; C303.2 79.97,29.6 ; C303.2 79.97,27.99 ; C280.2 v1(136.02,49.59) ; C306.2 145.59,27.99 ; C306.2 145.59,29.6 ; C306.2 143.97,27.99 ; C306.2 143.97,29.6 ; C249.2 v1(135.89,65.21) ; R221.1 v1(230.76,58.41)
  02_GND1 w0.508: J13.1 242.74,37.19 ; J13.1 241.13,37.19 ; J13.1 241.13,35.58 ; J13.1 242.74,35.58 ; 242.24,74.02 C227.2 242.24,72.41 ; C304.2 127.17,27.99 ; C304.2 125.56,27.99 ; C304.2 127.17,29.6 ; C304.2 125.56,29.6 ; 197.67,103.08 C145.2 ; C145.2 199.28,103.08 ; C145.2 199.28,104.69 ; C145.2 197.67,104.69 ; J11.6 237.22,51.67 ; J11.6 235.61,51.67 ; J11.6 235.61,50.06 ; J11.6 237.22,50.06 ; 246.3,20.54 J15.2 ; J15.2 250.21,18.63 ; J15.2 250.21,20.54 ; J15.2 246.3,18.63 ; 251.04,75.2 FAN2.2 ; FAN2.2 251.04,76.81 ; FAN2.2 252.65,76.81 ; FAN2.2 252.65,75.2 ; 242.24,90.7 C179.2 242.24,92.31 ; C7.2 199.28,144.99 ; C7.2 199.28,146.6 ; C7.2 197.67,144.99 ; C7.2 197.67,146.6 ; J15.3 252.01,17.74 ; J15.3 250.1,13.83 ; J15.3 250.1,17.74 ; J15.3 252.01,13.83 ; C307.2 194.1,29.6 ; C307.2 192.49,27.99 ; C307.2 194.1,27.99 ; C307.2 192.49,29.6 ; 79.97,27.99 C303.2 ; C303.2 81.58,29.6 ; C303.2 79.97,29.6 ; C303.2 81.58,27.99 ; J4.2 153.21,151.66 ; J4.2 151.6,153.28 ; J4.2 151.6,151.66 ; J4.2 153.21,153.28 ; 7.2,162.58 U1.4 ; U1.4 8.81,162.58 ; U1.4 7.2,160.97 ; U1.4 8.81,160.97 ; 251.04,93.49 FAN1.2 ; FAN1.2 251.04,95.1 ; FAN1.2 252.65,95.1 ; FAN1.2 252.65,93.49 ; 250.48,40.11 JA1.4 ; JA1.4 250.48,37.38 ; JA1.4 253.21,40.11 ; JA1.4 253.21,37.38 ; 250.48,36.15 JA1.3 ; JA1.3 250.48,33.42 ; JA1.3 253.21,36.15 ; JA1.3 253.21,33.42 ; 134.83,29.6 C305.2 ; C305.2 136.44,29.6 ; C305.2 134.83,27.99 ; C305.2 136.44,27.99 ; 242.24,101.45 C148.2 242.24,99.84 ; 161.76,153.28 J4.10 ; J4.10 163.37,151.66 ; J4.10 161.76,151.66 ; J4.10 163.37,153.28 ; J13.2 242.74,34.65 ; J13.2 241.13,33.04 ; J13.2 242.74,33.04 ; J13.2 241.13,34.65 ; 242.24,83.16 C211.2 242.24,81.55 ; C306.2 145.59,27.99 ; C306.2 143.97,27.99 ; C306.2 143.97,29.6 ; C306.2 145.59,29.6
  03_SIG1 w0.508: 246.3,18.63 J15.2 ; J15.2 250.21,20.54 ; J15.2 250.21,18.63 ; J15.2 246.3,20.54 ; JA1.3 253.21,33.42 ; JA1.3 250.48,36.15 ; JA1.3 253.21,36.15 ; JA1.3 250.48,33.42 ; C306.2 145.59,29.6 ; C306.2 145.59,27.99 ; C306.2 143.97,29.6 ; C306.2 143.97,27.99 ; 235.61,51.67 J11.6 ; J11.6 237.22,51.67 ; J11.6 237.22,50.06 ; J11.6 235.61,50.06 ; FAN1.2 252.65,93.49 ; FAN1.2 251.04,95.1 ; FAN1.2 252.65,95.1 ; FAN1.2 251.04,93.49 ; J13.2 242.74,34.65 ; J13.2 241.13,33.04 ; J13.2 242.74,33.04 ; J13.2 241.13,34.65 ; C303.2 81.58,27.99 ; C303.2 79.97,29.6 ; C303.2 79.97,27.99 ; C303.2 81.58,29.6 ; 251.04,75.2 FAN2.2 ; FAN2.2 252.65,75.2 ; FAN2.2 252.65,76.81 ; FAN2.2 251.04,76.81 ; 242.24,72.41 C227.2 242.24,74.02 ; 134.83,27.99 C305.2 ; C305.2 136.44,27.99 ; C305.2 134.83,29.6 ; C305.2 136.44,29.6 ; 250.1,13.83 J15.3 ; J15.3 252.01,13.83 ; J15.3 252.01,17.74 ; J15.3 250.1,17.74 ; 125.56,27.99 C304.2 ; C304.2 127.17,29.6 ; C304.2 127.17,27.99 ; C304.2 125.56,29.6 ; JA1.4 253.21,40.11 ; JA1.4 250.48,37.38 ; JA1.4 250.48,40.11 ; JA1.4 253.21,37.38 ; 242.24,99.84 C148.2 242.24,101.45 ; 242.24,90.7 C179.2 242.24,92.31 ; U1.4 8.81,162.58 ; U1.4 8.81,160.97 ; U1.4 7.2,162.58 ; U1.4 7.2,160.97 ; J13.1 242.74,37.19 ; J13.1 241.13,35.58 ; J13.1 242.74,35.58 ; J13.1 241.13,37.19 ; 192.49,27.99 C307.2 ; C307.2 194.1,27.99 ; C307.2 192.49,29.6 ; C307.2 194.1,29.6 ; 242.24,81.55 C211.2 242.24,83.16
  04_PWR1 w0.127: 45.97,128.21 44.96,128.21
  04_PWR1 w0.508: 7.2,162.58 U1.4 ; U1.4 8.81,162.58 ; U1.4 7.2,160.97 ; U1.4 8.81,160.97
  05_PWR2 w0.508: 250.48,33.42 JA1.3 ; JA1.3 250.48,36.15 ; JA1.3 253.21,33.42 ; JA1.3 253.21,36.15 ; 241.13,34.65 J13.2 ; J13.2 242.74,34.65 ; J13.2 242.74,33.04 ; J13.2 241.13,33.04 ; C307.2 194.1,29.6 ; C307.2 194.1,27.99 ; C307.2 192.49,27.99 ; C307.2 192.49,29.6 ; 242.24,90.7 C179.2 242.24,92.31 ; 79.97,29.6 C303.2 ; C303.2 81.58,29.6 ; C303.2 79.97,27.99 ; C303.2 81.58,27.99 ; 125.56,29.6 C304.2 ; C304.2 127.17,27.99 ; C304.2 125.56,27.99 ; C304.2 127.17,29.6 ; 235.61,51.67 J11.6 ; J11.6 235.61,50.06 ; J11.6 237.22,51.67 ; J11.6 237.22,50.06 ; J15.3 252.01,13.83 ; J15.3 252.01,17.74 ; J15.3 250.1,13.83 ; J15.3 250.1,17.74 ; J15.2 250.21,18.63 ; J15.2 246.3,18.63 ; J15.2 246.3,20.54 ; J15.2 250.21,20.54 ; JA1.4 253.21,37.38 ; JA1.4 250.48,40.11 ; JA1.4 250.48,37.38 ; JA1.4 253.21,40.11 ; 134.83,27.99 C305.2 ; C305.2 134.83,29.6 ; C305.2 136.44,27.99 ; C305.2 136.44,29.6 ; C7.2 199.28,146.6 ; C7.2 197.67,144.99 ; C7.2 197.67,146.6 ; C7.2 199.28,144.99 ; FAN2.2 252.65,76.81 ; FAN2.2 251.04,75.2 ; FAN2.2 251.04,76.81 ; FAN2.2 252.65,75.2 ; 197.67,103.08 C145.2 ; C145.2 199.28,103.08 ; C145.2 197.67,104.69 ; C145.2 199.28,104.69 ; J13.1 242.74,37.19 ; J13.1 241.13,37.19 ; J13.1 241.13,35.58 ; J13.1 242.74,35.58 ; 251.04,93.49 FAN1.2 ; FAN1.2 252.65,95.1 ; FAN1.2 251.04,95.1 ; FAN1.2 252.65,93.49 ; 242.24,99.84 C148.2 242.24,101.45 ; J4.2 153.21,151.66 ; J4.2 153.21,153.28 ; J4.2 151.6,151.66 ; J4.2 151.6,153.28 ; 242.24,81.55 C211.2 242.24,83.16 ; 242.24,72.41 C227.2 242.24,74.02 ; 161.76,153.28 J4.10 ; J4.10 163.37,153.28 ; J4.10 163.37,151.66 ; J4.10 161.76,151.66 ; U1.4 8.81,162.58 ; U1.4 7.2,162.58 ; U1.4 7.2,160.97 ; U1.4 8.81,160.97 ; C306.2 145.59,27.99 ; C306.2 143.97,29.6 ; C306.2 143.97,27.99 ; C306.2 145.59,29.6
  06_SIG2 w0.508: JA1.3 253.21,33.42 ; JA1.3 250.48,33.42 ; JA1.3 250.48,36.15 ; JA1.3 253.21,36.15 ; 250.1,13.83 J15.3 ; J15.3 252.01,17.74 ; J15.3 252.01,13.83 ; J15.3 250.1,17.74 ; J11.6 237.22,50.06 ; J11.6 235.61,50.06 ; J11.6 235.61,51.67 ; J11.6 237.22,51.67 ; C304.2 127.17,29.6 ; C304.2 127.17,27.99 ; C304.2 125.56,27.99 ; C304.2 125.56,29.6 ; 242.24,92.31 C179.2 242.24,90.7 ; 197.67,144.99 C7.2 ; C7.2 199.28,146.6 ; C7.2 199.28,144.99 ; C7.2 197.67,146.6 ; J13.2 242.74,34.65 ; J13.2 241.13,33.04 ; J13.2 241.13,34.65 ; J13.2 242.74,33.04 ; C305.2 136.44,27.99 ; C305.2 134.83,27.99 ; C305.2 134.83,29.6 ; C305.2 136.44,29.6 ; 79.97,27.99 C303.2 ; C303.2 81.58,29.6 ; C303.2 81.58,27.99 ; C303.2 79.97,29.6 ; 143.97,27.99 C306.2 ; C306.2 145.59,27.99 ; C306.2 143.97,29.6 ; C306.2 145.59,29.6 ; FAN2.2 252.65,75.2 ; FAN2.2 251.04,75.2 ; FAN2.2 252.65,76.81 ; FAN2.2 251.04,76.81 ; 242.24,72.41 C227.2 242.24,74.02 ; 251.04,93.49 FAN1.2 ; FAN1.2 252.65,95.1 ; FAN1.2 251.04,95.1 ; FAN1.2 252.65,93.49 ; 7.2,160.97 U1.4 ; U1.4 7.2,162.58 ; U1.4 8.81,162.58 ; U1.4 8.81,160.97 ; C307.2 194.1,27.99 ; C307.2 192.49,29.6 ; C307.2 192.49,27.99 ; C307.2 194.1,29.6 ; JA1.4 253.21,37.38 ; JA1.4 253.21,40.11 ; JA1.4 250.48,37.38 ; JA1.4 250.48,40.11 ; 242.24,83.16 C211.2 242.24,81.55 ; J13.1 242.74,37.19 ; J13.1 242.74,35.58 ; J13.1 241.13,37.19 ; J13.1 241.13,35.58 ; 242.24,99.84 C148.2 242.24,101.45 ; 197.67,104.69 C145.2 ; C145.2 197.67,103.08 ; C145.2 199.28,104.69 ; C145.2 199.28,103.08 ; 246.3,18.63 J15.2 ; J15.2 250.21,20.54 ; J15.2 250.21,18.63 ; J15.2 246.3,20.54
  07_GND2 w0.508: J11.6 237.22,50.06 ; J11.6 235.61,51.67 ; J11.6 237.22,51.67 ; J11.6 235.61,50.06 ; 241.13,35.58 J13.1 ; J13.1 242.74,35.58 ; J13.1 241.13,37.19 ; J13.1 242.74,37.19 ; J13.2 242.74,33.04 ; J13.2 241.13,34.65 ; J13.2 242.74,34.65 ; J13.2 241.13,33.04 ; C145.2 199.28,104.69 ; C145.2 197.67,103.08 ; C145.2 199.28,103.08 ; C145.2 197.67,104.69 ; C304.2 127.17,27.99 ; C304.2 125.56,29.6 ; C304.2 127.17,29.6 ; C304.2 125.56,27.99 ; 192.49,29.6 C307.2 ; C307.2 194.1,29.6 ; C307.2 194.1,27.99 ; C307.2 192.49,27.99 ; 134.83,27.99 C305.2 ; C305.2 134.83,29.6 ; C305.2 136.44,29.6 ; C305.2 136.44,27.99 ; U1.4 8.81,162.58 ; U1.4 8.81,160.97 ; U1.4 7.2,162.58 ; U1.4 7.2,160.97 ; C306.2 145.59,27.99 ; C306.2 145.59,29.6 ; C306.2 143.97,27.99 ; C306.2 143.97,29.6 ; JA1.4 253.21,37.38 ; JA1.4 253.21,40.11 ; JA1.4 250.48,37.38 ; JA1.4 250.48,40.11 ; C303.2 81.58,29.6 ; C303.2 81.58,27.99 ; C303.2 79.97,27.99 ; C303.2 79.97,29.6 ; J4.2 153.21,153.28 ; J4.2 151.6,153.28 ; J4.2 151.6,151.66 ; J4.2 153.21,151.66 ; 197.67,146.6 C7.2 ; C7.2 199.28,146.6 ; C7.2 199.28,144.99 ; C7.2 197.67,144.99 ; J15.3 252.01,13.83 ; J15.3 250.1,13.83 ; J15.3 252.01,17.74 ; J15.3 250.1,17.74 ; 251.04,75.2 FAN2.2 ; FAN2.2 252.65,76.81 ; FAN2.2 251.04,76.81 ; FAN2.2 252.65,75.2 ; J4.10 163.37,153.28 ; J4.10 163.37,151.66 ; J4.10 161.76,153.28 ; J4.10 161.76,151.66 ; 242.24,81.55 C211.2 242.24,83.16 ; J15.2 250.21,18.63 ; J15.2 250.21,20.54 ; J15.2 246.3,18.63 ; J15.2 246.3,20.54 ; JA1.3 253.21,33.42 ; JA1.3 253.21,36.15 ; JA1.3 250.48,33.42 ; JA1.3 250.48,36.15 ; 242.24,72.41 C227.2 242.24,74.02 ; 242.24,99.84 C148.2 242.24,101.45 ; 251.04,93.49 FAN1.2 ; FAN1.2 252.65,95.1 ; FAN1.2 251.04,95.1 ; FAN1.2 252.65,93.49 ; 242.24,90.7 C179.2 242.24,92.31
  BOTTOM w0.102: C513.2 P1.U26
  BOTTOM w0.254: U59.52 35.58,144.2 U59.55 ; U59.25 42.06,142.2 v1(42.42,141.85)
  BOTTOM w0.305: C568.2 C569.2
  BOTTOM w0.33: C438.2 139.39,100.62 C436.2 ; C532.2 142.39,90.62 C534.2
  BOTTOM w0.381: v2(127.89,89.12) 127.39,88.63 C560.2 ; v2(127.89,89.12) 128.38,88.63 C562.2 ; v2(127.89,89.12) 127.4,89.61 C557.2 ; v1(167,16.32) C632.2 v1(166.04,15.23) ; R412.2 135.75,104.26 v2(134.89,105.12) ; v2(141.89,96.12) 142.38,96.61 C472.2 ; v2(141.89,96.12) P1.Y10 C481.2 ; v2(141.89,96.12) 142.38,95.63 C492.2 ; C480.2 134.39,96.63 v2(134.89,97.12) ; C558.2 P1.P26 v2(124.89,89.12) ; P1.R20 v2(130.89,90.12) C544.2 ; v2(125.89,87.12) P1.L25 C577.2 126.45,86.68 127.32,86.68 C578.2 ; R396.1 121.37,109.61 v2(120.89,109.12) ; C569.2 C570.2 ; P1.AG26 v2(124.89,102.12) ; R342.2 R339.2 24.96,146.89 v1(24.21,147.65) ; C552.2 138.39,89.61 v2(138.89,89.12) ; C550.2 134.39,90.63 v2(134.89,91.12) 135.38,90.63 C549.2 ; C592.2 126.37,83.64 v2(125.89,84.12) 125.4,83.64 R457.2 ; v1(44.96,146.76) 45.52,146.19 R340.2 ; C529.2 126.39,92.62 v2(126.89,92.12) P1.U24 C528.2 ; v2(133.89,106.12) 134.37,105.64 C421.2 ; C579.2 128.39,86.62 v2(128.89,86.12) 128.4,85.64 C584.2 ; v2(121.89,97.12) 122.38,97.62 C467.2 ; C506.2 129.39,93.62 v2(129.89,94.12) P1.V21 C505.2 ; R460.2 138.39,77.62 v2(137.89,77.12) ; v2(133.89,102.12) 133.39,102.62 C429.2 ; C423.2 v2(126.89,106.12) ; C532.2 142.38,90.61 v2(141.89,90.12) 141.39,89.62 C551.2 ; C466.2 126.38,97.62 v2(125.89,97.12) ; C490.2 122.38,95.62 v2(121.89,95.12) ; C479.2 135.38,96.63 v2(134.89,97.12) ; C433.2 144.39,101.63 v2(144.89,102.12) ; v2(139.89,97.12) 139.39,97.61 C464.2 ; v2(139.89,97.12) 140.38,97.61 C463.2 ; v2(139.89,97.12) 140.38,96.63 C478.2 ; R461.1 123.35,76.58 v2(122.89,76.12) ; C451.2 142.36,99.63 v2(141.89,100.11) ; R429.1 132.39,95.61 v2(132.89,95.12) 133.38,95.61 C486.2 ; C461.2 137.39,98.63 v2(137.89,99.12) 138.38,98.63 C460.2 ; C546.2 139.38,90.63 v2(138.89,91.12) ; v2(124.89,99.12) P1.AD26 C449.2 ; v2(137.89,87.12) 137.39,87.61 C566.2 ; C576.2 143.4,87.61 v2(143.89,87.12) ; C454.2 127.39,99.63 v2(127.89,100.12) ; v2(121.89,99.12) 122.38,99.62 C447.2 ; C582.2 123.31,85.53 122.47,85.53 C583.2 P1.K29 v2(121.89,86.12) ; v2(124.89,91.12) 125.39,90.62 C533.2 ; C567.2 136.39,87.61 v2(136.89,87.12) ; v1(218.14,50.51) 218.48,50.51 C611.2 218.53,49.49 v1(218.14,49.49) ; C530.2 124.4,91.64 v2(124.89,92.12) P1.U26 ; C465.2 128.39,97.62 v2(128.89,97.12) P1.AA22 C475.2 ; C477.2 124.4,96.64 v2(124.89,97.12) P1.AB26 C470.2 ; C441.2 P1.AE5 v2(145.89,100.12) 145.39,100.62 C442.2 ; C456.2 131.4,98.62 v2(131.89,99.12) 131.39,99.62 C446.2 ; C609.2 216.93,52.91 v1(216.92,52.9) ; v2(142.89,84.12) 143.39,83.62 R453.2 ; C474.2 126.38,96.62 v2(125.89,96.12) ; C542.2 129.37,90.64 v2(128.89,91.12) 128.4,90.64 C543.2 ; C468.2 146.39,97.62 v2(146.89,97.12) ; C535.2 122.38,90.61 v2(121.89,90.12) ; C485.2 P1.Y15 v2(136.89,96.12) 137.39,95.62 C484.2 ; v2(140.89,87.12) 140.39,87.61 C563.2 ; v2(141.89,100.11) 141.4,99.62 C448.2 ; v2(141.89,100.11) 142.38,100.6 C437.2 ; C457.2 129.39,98.64 C453.2 130.38,99.63 v2(129.89,100.12) 129.39,100.62 C444.2 ; v2(127.89,100.12) 128.39,100.62 C445.2 ; v2(127.89,100.12) 127.39,100.61 C439.2 ; v2(124.89,96.12) P1.AA26 C476.2 ; C585.2 131.37,84.64 v2(130.89,85.12) ; C469.2 134.39,97.62 v2(134.89,97.12) ; C595.2 131.39,80.62 v2(130.89,81.12) ; C494.2 141.39,93.62 v2(140.89,94.12) P1.V11 C495.2 ; C610.2 v1(221.76,52.02) ; C545.2 140.39,90.63 v2(140.89,91.12) ; R434.1 121.89,91.13 v2(121.89,91.12) ; C488.2 128.38,95.62 v2(127.89,95.12) ; C572.2 131.39,87.61 v2(131.89,87.12) 132.38,87.61 C571.2 ; v2(124.89,87.12) 124.39,87.61 R443.1 ; C493.2 145.39,94.61 v2(145.89,94.12) ; C561.2 124.39,88.61 v2(124.89,88.12) P1.M26 C575.2 ; P1.AG14 v2(137.89,103.12) ; C473.2 130.39,96.61 v2(130.89,96.12) P1.Y20 C491.2 ; v2(129.89,103.12) 129.89,102.59 130.36,102.12 R417.1 ; v2(129.89,106.12) 130.34,106.12 R409.1 ; C512.2 122.38,92.62 v2(121.89,92.12) ; R346.2 45.52,143.65 v1(44.96,144.22) ; 24.21,138.76 R372.2 R369.2 ; v2(121.89,96.12) 122.38,96.62 R427.1 ; C556.2 132.4,89.61 v2(132.89,89.12) 133.38,89.61 C553.2 ; v2(138.89,87.12) 138.39,87.61 C565.2 ; R403.2 144.38,106.63 v2(143.89,107.12) ; v2(138.89,76.12) 138.99,76.02 L20.2 ; v2(124.89,85.12) 124.39,85.61 C581.2 ; v2(139.89,87.12) 139.39,87.61 C564.2 ; v2(121.89,88.12) P1.N30 C559.2 ; v2(125.89,90.12) 126.39,89.62 C554.2 ; C471.2 131.39,97.63 v2(131.89,98.12) ; v2(125.89,95.12) 126.38,95.62 C489.2 ; C450.2 v2(139.89,99.12) ; R370.2 45.52,138.83 v1(44.96,139.39) ; C500.2 P1.V16 v2(135.89,94.12) 136.39,93.62 C499.2 ; C458.2 125.39,98.63 v2(125.89,99.12) 126.39,99.62 C455.2 ; C462.2 136.38,98.63 v2(135.89,99.12) ; R352.2 45.52,141.24 v1(44.96,141.8) ; C425.2 v2(133.89,105.12) ; C432.2 P1.AF26 v2(124.89,101.12) 124.89,101.12 C434.2 ; C440.2 137.37,100.64 v2(136.89,101.12) 136.39,100.63 C443.2 136.12,100.9 R421.2 ; v2(135.89,87.12) 135.39,87.61 C568.2 ; C452.2 134.39,99.62 v2(134.89,99.12) ; C482.2 139.38,95.61 v2(138.89,95.12) 138.39,95.61 C483.2 ; C509.2 P1.V25 v2(125.89,94.12) ; C574.2 129.39,87.62 v2(129.89,88.12) 130.39,87.62 C573.2 ; C547.2 137.39,90.62 v2(136.89,90.12) P1.R15 C548.2 ; R348.2 R351.2 ; C436.2 139.38,100.61 v2(138.89,100.12) ; P1.AH11 v2(140.89,104.12) ; C594.2 v2(135.89,81.12) ; R336.2 45.52,148.61 v1(44.96,149.17) ; C591.2 v2(129.89,83.12)
  BOTTOM w0.508: C307.2 194.1,27.99 ; C307.2 194.1,29.6 ; C307.2 192.49,29.6 ; C307.2 192.49,27.99 ; C303.2 81.58,27.99 ; C303.2 79.97,29.6 ; C303.2 79.97,27.99 ; C303.2 81.58,29.6 ; J15.3 252.01,13.83 ; J15.3 250.1,13.83 ; J15.3 252.01,17.74 ; J15.3 250.1,17.74 ; JA1.3 253.21,33.42 ; JA1.3 250.48,33.42 ; JA1.3 250.48,36.15 ; JA1.3 253.21,36.15 ; C304.2 127.17,29.6 ; C304.2 125.56,29.6 ; C304.2 125.56,27.99 ; C304.2 127.17,27.99 ; C305.2 136.44,27.99 ; C305.2 136.44,29.6 ; C305.2 134.83,27.99 ; C305.2 134.83,29.6 ; 242.24,99.84 C148.2 242.24,101.45 ; C7.2 199.28,144.99 ; C7.2 197.67,144.99 ; C7.2 197.67,146.6 ; C7.2 199.28,146.6 ; U1.4 8.81,162.58 ; U1.4 7.2,160.97 ; U1.4 7.2,162.58 ; U1.4 8.81,160.97 ; 251.04,93.49 FAN1.2 ; FAN1.2 251.04,95.1 ; FAN1.2 252.65,95.1 ; FAN1.2 252.65,93.49 ; JA1.4 253.21,37.38 ; JA1.4 250.48,37.38 ; JA1.4 253.21,40.11 ; JA1.4 250.48,40.11 ; FAN2.2 252.65,76.81 ; FAN2.2 251.04,75.2 ; FAN2.2 251.04,76.81 ; FAN2.2 252.65,75.2 ; 235.61,51.67 J11.6 235.61,50.06 ; C306.2 145.59,29.6 ; C306.2 145.59,27.99 ; C306.2 143.97,27.99 ; C306.2 143.97,29.6 ; J13.1 243,37.45 ; J13.1 240.87,37.45 ; J13.1 240.87,35.32 ; J13.1 243,35.32 ; 242.24,81.55 C211.2 242.24,83.16 ; C145.2 199.28,103.08 ; C145.2 199.28,104.69 ; C145.2 197.67,103.08 ; C145.2 197.67,104.69 ; 242.24,90.7 C179.2 242.24,92.31 ; 241.13,34.65 J13.2 ; J13.2 242.74,34.65 ; J13.2 241.13,33.04 ; J13.2 242.74,33.04 ; C613.2 v1(223.03,44.01) ; C612.2 v1(223.9,46.16) ; J15.2 250.21,18.63 ; J15.2 246.3,18.63 ; J15.2 250.21,20.54 ; J15.2 246.3,20.54 ; 242.24,72.41 C227.2 242.24,74.02
  vias: v1(1.27,163.77) v1(1.27,161.23) v1(1.27,158.69) v1(1.27,156.15) v1(1.27,153.61) v1(1.27,151.07) v1(1.27,148.53) v1(1.27,145.99) v1(1.27,143.45) v1(1.27,140.91) v1(1.27,138.37) v1(1.27,135.83) v1(1.27,133.29) v1(1.27,130.75) v1(1.27,128.21) v1(1.27,125.67) v1(1.27,123.13) v1(1.27,120.59) v1(1.27,118.05) v1(1.27,115.51) v1(1.27,112.97) v1(1.27,110.43) v1(1.27,107.89) v1(1.27,105.35) v1(1.27,102.81) v1(1.27,100.27) v1(1.27,97.73) v1(1.27,95.19) v1(1.27,92.65) v1(1.27,90.11) v1(1.27,87.57) v1(1.27,85.03) v1(1.27,82.49) v1(1.27,79.95) v1(1.27,77.41) v1(1.27,74.87) v1(1.27,72.33) v1(1.27,69.79) v1(1.27,67.25) v1(1.27,64.71) v1(1.27,62.17) v1(1.27,59.63) v1(1.27,57.09) v1(1.27,54.55) v1(1.27,52.01) v1(1.27,49.47) v1(1.27,46.93) v1(1.27,44.39) v1(1.27,41.85) v1(1.27,39.31) v1(1.27,36.77) v1(1.27,34.23) v1(1.27,31.69) v1(1.27,29.15) v1(1.27,26.61) v1(1.27,24.07) v1(1.27,21.53) v1(1.27,18.99) v1(1.27,16.45) v1(1.27,13.91) v1(1.27,11.37) v1(1.27,8.83) v1(1.27,6.29) v1(1.52,165.54) v1(1.52,4.51) v1(3.05,3.05) v1(3.81,158.56) v1(4.06,165.54) v1(4.06,4.51) v1(6.35,158.56) v1(6.6,165.54) v1(6.6,4.51) v1(7.37,130.75) v1(7.37,102.81) v1(7.37,74.87) v1(7.37,46.93) v1(7.37,21.53) v1(8.89,158.56) v1(9.14,165.54) v1(9.14,4.51) v1(9.4,13.91) v1(11.43,158.56) v1(11.68,165.54) v1(11.68,4.51) v1(12.06,155.89) v1(12.06,153.86) v1(12.06,127.95) v1(12.06,125.92) v1(12.06,100.01) v1(12.06,97.98) v1(12.06,72.07) v1(12.06,70.04) v1(12.06,44.13) v1(12.06,42.1) v1(12.32,140.02) v1(12.32,136.97) v1(12.32,134.94) v1(12.32,109.03) v1(12.32,107) v1(12.32,81.09) v1(12.32,79.06) v1(12.32,53.15) v1(12.32,51.12) v1(12.32,25.21) v1(12.32,23.18) v1(13.08,155.89) v1(13.08,154.88) v1(13.08,153.86) v1(13.08,127.95) v1(13.08,126.94) v1(13.08,125.92) v1(13.08,100.01) v1(13.08,99) v1(13.08,97.98) v1(13.08,72.07) v1(13.08,71.06) v1(13.08,70.04) v1(13.08,44.13) v1(13.08,43.12) v1(13.08,42.1) v1(13.21,147.13) v1(13.21,143.7) v1(13.21,142.3) v1(13.21,119.19) v1(13.21,117.41) v1(13.21,115.76) v1(13.21,114.11) v1(13.21,112.59) v1(13.21,91.25) v1(13.21,89.47) v1(13.21,87.82) v1(13.21,86.17) v1(13.21,84.65) v1(13.21,63.31) v1(13.21,61.53) v1(13.21,59.88) v1(13.21,58.23) v1(13.21,56.71) v1(13.21,35.37) v1(13.21,33.59) v1(13.21,31.94) v1(13.21,30.29) v1(13.21,28.77) v1(13.34,158.56) v1(13.46,140.02) v1(13.46,136.97) v1(13.46,135.95) v1(13.46,134.94) v1(13.46,130.75) v1(13.46,109.03) v1(13.46,108.01) v1(13.46,107) v1(13.46,102.81) v1(13.46,81.09) v1(13.46,80.07) v1(13.46,79.06) v1(13.46,74.87) v1(13.46,53.15) v1(13.46,52.13) v1(13.46,51.12) v1(13.46,46.93) v1(13.46,25.21) v1(13.46,24.19) v1(13.46,23.18) v1(13.46,21.53) v1(14.22,165.54) v1(14.22,4.51) v1(16.64,138.11) v1(16.64,135.57) v1(16.64,133.03) v1(16.64,130.49) v1(16.64,127.95) v1(16.64,122.87) v1(16.64,110.3) v1(16.64,107.76) v1(16.64,105.22) v1(16.64,102.68) v1(16.64,100.14) v1(16.64,95.06) v1(16.64,54.42) v1(16.64,51.88) v1(16.64,49.34) v1(16.64,46.8) v1(16.64,44.26) v1(16.64,39.18) v1(16.64,28.38) v1(16.64,25.84) v1(16.64,23.3) v1(16.64,20.76) v1(16.76,165.54) v1(16.76,158.56) v1(16.76,139.38) v1(16.76,82.74) v1(16.76,80.2) v1(16.76,77.66) v1(16.76,75.12) v1(16.76,72.58) v1(16.76,66.99) v1(16.76,4.51) v1(17.4,17.72) v1(17.4,9.08) v1(17.58,143.53) v1(17.91,132.91) v1(18.03,13.91) v1(18.92,133.92) v1(19.18,54.42) v1(19.3,165.54) v1(19.3,158.56) v1(19.3,4.51) v1(20.07,133.92) v1(20.32,82.74) v1(20.83,9.08) v1(21.21,133.92) v1(21.34,76.01) v1(21.72,110.3) v1(21.72,103.95) v1(21.72,54.42) v1(21.72,48.07) v1(21.84,165.54) v1(21.84,158.56) v1(21.84,84.52) v1(21.84,4.51) v1(22.1,23.18) v1(22.35,133.92) v1(22.73,17.59) v1(23.24,130.62) v1(23.24,102.68) v1(23.24,74.74) v1(23.24,46.8) v1(23.49,133.92) v1(23.49,131.89) v1(23.62,82.74) v1(23.62,13.78) v1(24,141.92) v1(24.13,143.45) v1(24.26,124.78) v1(24.26,123.76) v1(24.26,96.96) v1(24.26,95.82) v1(24.26,69.02) v1(24.26,67.88) v1(24.26,54.42) v1(24.26,41.08) v1(24.26,39.94) v1(24.38,165.54) v1(24.38,158.56) v1(24.38,130.62) v1(24.38,102.68) v1(24.38,74.74) v1(24.38,46.8) v1(24.38,4.51) v1(25.4,80.96) v1(25.53,83.63) v1(25.91,123.76) v1(25.91,12.51) v1(26.67,124.9) v1(26.67,26.48) v1(26.8,127.95) v1(26.92,165.54) v1(26.92,4.51) v1(27.05,110.05) v1(27.05,107.38) v1(27.05,104.84) v1(27.05,102.3) v1(27.05,99.76) v1(27.05,97.22) v1(27.05,94.68) v1(27.05,92.14) v1(27.18,122.24) v1(27.18,120.33) v1(27.18,118.94) v1(27.18,81.98) v1(27.18,79.18) v1(27.18,76.64) v1(27.18,74.1) v1(27.18,71.56) v1(27.18,69.02) v1(27.18,66.48) v1(27.18,63.94) v1(27.18,54.04) v1(27.18,51.37) v1(27.18,48.83) v1(27.18,46.29) v1(27.18,43.75) v1(27.18,41.21) v1(27.18,38.67) v1(27.18,36.13) v1(27.43,9.08) v1(27.81,158.56) v1(27.94,19.49) v1(28.07,132.91) v1(28.32,103.19) v1(28.32,47.31) v1(28.45,40.96) v1(28.58,80.58) v1(28.58,76.01) v1(29.14,13.84) v1(29.46,165.54) v1(29.46,4.51) v1(29.84,131.13) v1(30.35,158.56) v1(30.35,156.27) v1(30.48,75.25) v1(30.86,103.19) v1(30.86,47.31) v1(30.99,40.96) v1(30.99,12.51) v1(31.37,135.95) v1(31.5,152.97) v1(31.6,117.28) v1(31.6,116.14) v1(31.6,114.99) v1(31.6,113.85) v1(31.6,89.34) v1(31.6,88.2) v1(31.6,87.05) v1(31.6,85.91) v1(31.6,61.4) v1(31.6,60.26) v1(31.6,59.11) v1(31.6,57.97) v1(31.6,33.46) v1(31.6,32.32) v1(31.6,31.17) v1(31.6,30.03) v1(31.62,129.35) v1(31.75,158.69) v1(31.88,100.01) v1(32,165.54) v1(32,4.51) v1(32.51,9.08) v1(32.74,117.28) v1(32.74,116.14) v1(32.74,114.99) v1(32.74,113.85) v1(32.74,89.34) v1(32.74,88.2) v1(32.74,87.05) v1(32.74,85.91) v1(32.74,61.4) v1(32.74,60.26) v1(32.74,59.11) v1(32.74,57.97) v1(32.74,33.46) v1(32.74,32.32) v1(32.74,31.17) v1(32.74,30.03) v1(32.89,17.59) v1(33.02,144.72) v1(33.02,143.57) v1(33.02,142.43) v1(33.02,75.25) v1(33.27,154.75) v1(33.4,127.57) v1(33.4,103.19) v1(33.4,47.31) v1(33.53,40.96) v1(33.78,135.95) v1(33.88,117.28) v1(33.88,116.14) v1(33.88,114.99) v1(33.88,113.85) v1(33.88,89.34) v1(33.88,88.2) v1(33.88,87.05) v1(33.88,85.91) v1(33.88,61.4) v1(33.88,60.26) v1(33.88,59.11) v1(33.88,57.97) v1(33.88,33.46) v1(33.88,32.32) v1(33.88,31.17) v1(33.88,30.03) v1(34.04,144.72) v1(34.04,143.57) v1(34.04,142.43) v1(34.29,13.91) v1(34.54,165.54) v1(34.54,132.85) v1(34.54,4.51) v1(35.05,155.64) v1(35.05,144.72) v1(35.05,143.57) v1(35.05,142.43) v1(35.02,117.28) v1(35.02,116.14) v1(35.02,114.99) v1(35.02,113.85) v1(35.02,89.34) v1(35.02,88.2) v1(35.02,87.05) v1(35.02,85.91) v1(35.02,61.4) v1(35.02,60.26) v1(35.02,59.11) v1(35.02,57.97) v1(35.02,33.46) v1(35.02,32.32) v1(35.02,31.17) v1(35.02,30.03) v1(35.18,125.79) v1(35.59,132.85) v1(35.56,75.25) v1(35.81,19.49) v1(35.94,103.19) v1(35.94,47.31) v1(36.07,144.72) v1(36.07,143.57) v1(36.07,142.43) v1(36.07,40.96) v1(36.07,12.51) v1(36.32,151.19) v1(36.96,100.01) v1(36.96,72.07) v1(37.08,165.54) v1(37.08,144.72) v1(37.08,143.57) v1(37.08,142.43) v1(37.08,4.51) v1(37.59,155.64) v1(37.59,129.98) v1(37.59,9.08) v1(37.85,151.19) v1(38.1,144.72) v1(38.1,143.57) v1(38.1,142.43) v1(38.1,75.25) v1(38.35,6.73) v1(38.48,103.19) v1(38.48,47.31) v1(38.73,151.19) v1(39.12,144.72) v1(39.12,143.57) v1(39.12,142.43) v1(39.3,13.84) v1(39.62,165.54) v1(39.62,4.51) v1(40.13,155.64) v1(40.13,144.72) v1(40.13,143.57) v1(40.13,142.43) v1(40.26,151.19) v1(40.51,8.89) v1(40.64,75.25) v1(40.74,130.01) v1(41.02,103.19) v1(41.02,47.31) v1(41.15,12.51) v1(41.27,67.88) v1(41.27,25.46) v1(41.91,158.69) v1(42.16,165.54) v1(42.29,19.37) v1(42.67,155.64) v1(42.67,124.4) v1(42.67,120.97) v1(42.67,117.92) v1(42.67,116.01) v1(42.67,113.6) v1(42.67,110.55) v1(42.67,108.01) v1(42.67,105.47) v1(42.67,74.99) v1(42.67,72.45) v1(42.67,69.91) v1(42.67,66.87) v1(42.67,64.33) v1(42.67,62.17) v1(42.67,59.88) v1(42.8,11.18) v1(43.05,17.59) v1(43.31,103.19) v1(43.43,36.39) v1(43.43,34.48) v1(43.56,131.25) v1(43.56,26.29) v1(43.69,65.6) v1(43.94,39.05) v1(44.07,73.6) v1(44.04,37.65) v1(44.22,119.96) v1(44.22,118.55) v1(44.22,115.39) v1(44.22,113.98) v1(44.22,113.1) v1(44.22,111.69) v1(44.32,110.55) v1(44.32,104.33) v1(44.32,100.01) v1(44.32,96.08) v1(44.32,92.65) v1(44.32,90.11) v1(44.32,87.82) v1(44.32,85.53) v1(44.32,82.74) v1(44.32,80.07) v1(44.32,58.23) v1(44.38,8.76) v1(44.7,165.54) v1(44.7,4.51) v1(44.83,47.31) v1(44.83,13.21) v1(45.09,28.26) v1(45.21,155.64) v1(45.21,132.65) v1(45.47,33.85) v1(45.59,56.83) v1(45.72,40.83) v1(45.85,71.82) v1(45.85,68.77) v1(45.85,53.4) v1(45.94,37.65) v1(46.39,36.13) v1(46.48,19.37) v1(46.61,55.82) v1(46.86,30.04) v1(46.99,148.53) v1(47.12,58.61) v1(47.24,165.54) v1(47.24,4.51) v1(47.37,47.31) v1(47.5,42.61) v1(47.62,70.04) v1(47.88,33.85) v1(47.88,16) v1(48.01,155.66) v1(48.01,100.01) v1(48.01,96.2) v1(48.01,83.63) v1(48.13,26.48) v1(48.29,36.13) v1(48.31,126.25) v1(48.39,104.84) v1(48.67,37.65) v1(48.64,31.81) v1(48.64,28.26) v1(48.9,117.67) v1(48.9,115.51) v1(48.9,60.39) v1(48.9,55.82) v1(49.02,22.42) v1(49.28,110.68) v1(49.28,44.39) v1(49.46,13.84) v1(49.78,165.54) v1(49.78,85.41) v1(49.78,79.18) v1(49.78,4.51) v1(50.04,61.53) v1(50.19,128.08) v1(50.16,113.35) v1(50.3,154.03) v1(50.42,52.9) v1(50.42,33.59) v1(50.42,30.04) v1(50.55,82.11) v1(50.58,37.65) v1(50.67,115.51) v1(50.93,104.84) v1(51.05,46.16) v1(51.18,55.82) v1(51.56,87.19) v1(51.56,77.41) v1(51.56,62.93) v1(51.69,117.67) v1(51.69,73.98) v1(51.82,59.75) v1(52.07,158.69) v1(52.09,152.23) v1(52.2,100.01) v1(52.2,35.37) v1(52.2,31.81) v1(52.32,165.54) v1(52.32,4.51) v1(52.45,20.95) v1(52.58,26.73) v1(52.58,23.81) v1(52.83,47.94) v1(52.96,52.9) v1(53.09,64.58) v1(53.21,17.59) v1(53.34,113.35) v1(53.34,88.96) v1(53.34,75.63) v1(53.47,104.84) v1(53.6,148.89) v1(53.6,146.35) v1(53.56,143.96) v1(53.72,109.79) v1(53.72,55.82) v1(53.98,37.15) v1(53.98,33.59) v1(54.36,59.75) v1(54.36,28.51) v1(54.48,117.67) v1(54.54,8.76) v1(54.61,49.72) v1(54.61,44.13) v1(54.86,165.54) v1(54.86,62.8) v1(54.86,4.51) v1(54.99,103.19) v1(55.12,90.74) v1(55.12,77.41) v1(55.35,142.16) v1(55.5,108.01) v1(55.5,101.4) v1(55.5,100.09) v1(55.5,52.9) v1(55.63,82.11) v1(55.75,38.93) v1(55.75,35.37) v1(55.88,113.35) v1(56.13,30.29) v1(56.26,77.14) v1(56.26,75.83) v1(56.26,55.82) v1(56.64,87.19) v1(56.64,61.02) v1(56.9,109.74) v1(56.9,92.52) v1(56.9,79.18) v1(56.9,59.75) v1(57.02,68.52) v1(57.15,148.53) v1(57.15,140.37) v1(57.28,106.24) v1(57.4,165.54) v1(57.4,4.51) v1(57.53,40.7) v1(57.53,37.15) v1(57.66,31.94) v1(57.66,29.4) v1(57.66,26.86) v1(57.66,24.32) v1(57.66,21.78) v1(57.66,19.24) v1(57.66,16.7) v1(57.79,117.67) v1(58.04,52.9) v1(58.42,113.35) v1(58.67,94.3) v1(58.67,80.96) v1(58.84,138.61) v1(58.8,70.17) v1(58.93,66.61) v1(59.18,104.46) v1(59.18,14.41) v1(59.31,42.48) v1(59.31,38.93) v1(59.59,107.4) v1(59.94,165.54) v1(59.94,109.79) v1(59.94,4.51) v1(60.45,96.08) v1(60.58,136.92) v1(60.58,71.95) v1(60.58,68.39) v1(60.71,28.44) v1(60.71,27.29) v1(60.71,26.15) v1(60.71,25.01) v1(60.96,82.11) v1(61.09,52.9) v1(61.09,44.26) v1(61.09,40.7) v1(61.09,35.24) v1(61.72,87.19) v1(61.72,14.41) v1(61.85,28.44) v1(61.85,27.29) v1(61.85,26.15) v1(61.85,25.01) v1(61.98,92.52) v1(62.1,96.08) v1(62.23,158.69) v1(62.23,138.37) v1(62.37,135.13) v1(62.36,107.76) v1(62.36,73.72) v1(62.36,66.61) v1(62.48,165.54) v1(62.48,62.17) v1(62.48,4.51) v1(62.87,46.04) v1(62.87,42.48) v1(62.99,28.44) v1(62.99,27.29) v1(62.99,26.15) v1(62.99,25.01) v1(63.25,37.4) v1(63.5,82.11) v1(63.5,52.9) v1(63.63,35.24) v1(63.75,94.55) v1(64.17,133.33) v1(64.16,112.48) v1(64.14,28.44) v1(64.14,27.29) v1(64.14,26.15) v1(64.14,25.01) v1(64.26,14.41) v1(64.64,47.82) v1(64.64,44.26) v1(64.77,66.61) v1(64.7,8.76) v1(64.9,74.99) v1(65.02,165.54) v1(65.02,62.17) v1(65.02,39.18) v1(65.02,4.51) v1(65.15,98.74) v1(65.41,24.57) v1(65.53,92.77) v1(65.86,131.57) v1(66.04,102.43) v1(66.04,82.11) v1(66.17,35.24) v1(66.29,52.9) v1(66.42,49.59) v1(66.42,46.04) v1(66.8,87.19) v1(66.8,40.96) v1(66.8,14.41) v1(67.31,148.53) v1(67.31,108.81) v1(67.31,107.4) v1(67.31,106.08) v1(67.31,104.67) v1(67.31,101.4) v1(67.31,100.09) v1(67.31,91) v1(67.31,66.61) v1(67.31,62.17) v1(67.44,96.2) v1(67.44,74.99) v1(67.56,165.54) v1(67.56,4.51) v1(67.72,129.65) v1(67.72,112.53) v1(68.2,51.37) v1(68.2,47.82) v1(68.58,82.11) v1(68.58,42.74) v1(68.71,35.24) v1(69.09,94.55) v1(69.09,89.22) v1(69.34,14.41) v1(69.65,127.67) v1(69.72,66.61) v1(69.72,52.9) v1(69.98,104.46) v1(69.98,96.2) v1(69.98,74.99) v1(69.98,49.59) v1(70.1,165.54) v1(70.1,39.18) v1(70.1,4.51) v1(70.36,62.17) v1(70.36,44.51) v1(70.87,98.74) v1(70.87,92.77) v1(70.87,87.44) v1(71.12,82.11) v1(71.25,35.24) v1(71.53,112.53) v1(71.5,54.67) v1(71.75,51.37) v1(71.75,24.57) v1(71.83,125.54) v1(71.88,66.61) v1(71.88,14.41) v1(72.14,46.29) v1(72.39,158.69) v1(72.39,138.37) v1(72.52,96.2) v1(72.52,74.99) v1(72.64,165.54) v1(72.64,91) v1(72.64,85.66) v1(72.64,62.17) v1(72.64,44.26) v1(72.64,4.51) v1(72.77,104.46) v1(72.9,28.56) v1(72.9,27.42) v1(72.9,26.28) v1(72.9,25.13) v1(73.28,52.9) v1(73.41,18.86) v1(73.66,82.11) v1(73.79,35.24) v1(73.81,123.51) v1(73.91,48.07) v1(74.04,28.56) v1(74.04,27.42) v1(74.04,26.28) v1(74.04,25.13) v1(74.04,8.57) v1(74.42,89.22) v1(74.42,83.88) v1(74.42,14.41) v1(74.8,66.61) v1(75.06,96.2) v1(75.06,74.99) v1(75.06,54.67) v1(75.18,165.54) v1(75.18,39.18) v1(75.18,28.56) v1(75.18,27.42) v1(75.18,26.28) v1(75.18,25.13) v1(75.18,4.51) v1(75.31,62.17) v1(75.69,49.85) v1(75.74,121.63) v1(76.2,103.16) v1(76.2,101.75) v1(76.2,87.44) v1(76.2,82.11) v1(76.33,98.74) v1(76.33,35.24) v1(76.33,28.56) v1(76.33,27.42) v1(76.33,26.28) v1(76.33,25.13) v1(76.96,22.03) v1(76.96,19.49) v1(76.96,16.95) v1(76.96,14.41) v1(77.22,66.61) v1(77.47,148.53) v1(77.47,120.05) v1(77.47,51.63) v1(77.47,28.56) v1(77.47,27.42) v1(77.6,96.2) v1(77.6,74.99) v1(77.72,165.54) v1(77.72,4.51) v1(77.85,39.43) v1(77.85,38.42) v1(77.93,94.35) v1(77.93,93.1) v1(77.93,89.78) v1(77.93,88.53) v1(77.98,85.66) v1(78.61,28.56) v1(78.61,27.42) v1(78.87,77.14) v1(78.87,75.83) v1(78.87,62.17) v1(78.87,39.43) v1(78.87,38.42) v1(78.87,35.24) v1(79.25,53.4) v1(79.4,118.17) v1(79.5,22.8) v1(79.5,14.41) v1(79.76,66.61) v1(79.88,39.43) v1(79.88,38.42) v1(80.01,85.66) v1(80.14,74.99) v1(80.26,165.54) v1(80.26,96.08) v1(80.26,4.51) v1(80.77,49.85) v1(80.9,82.11) v1(80.9,54.67) v1(80.9,38.42) v1(81.13,116.45) v1(81.15,62.17) v1(81.41,35.24) v1(82.04,14.41) v1(82.17,22.8) v1(82.3,164.15) v1(82.3,161.61) v1(82.3,159.07) v1(82.3,156.53) v1(82.3,10.99) v1(82.3,8.45) v1(82.3,5.91) v1(82.55,138.37) v1(82.68,82.11) v1(82.96,114.52) v1(83.06,74.99) v1(83.19,66.61) v1(83.44,62.93) v1(83.95,35.24) v1(83.95,32.7) v1(83.95,30.16) v1(83.95,27.62) v1(83.95,25.08) v1(83.95,22.54) v1(83.95,20) v1(83.95,17.46) v1(84.07,54.67) v1(84.12,120.1) v1(84.33,73.72) v1(84.58,92.44) v1(84.58,91.45) v1(84.58,90.46) v1(84.71,155.77) v1(84.71,14.41) v1(84.97,98.67) v1(85.09,82.11) v1(85.22,66.61) v1(85.39,112.48) v1(85.34,33.97) v1(85.6,92.44) v1(85.6,91.45) v1(85.6,90.46) v1(85.6,72.45) v1(85.73,69.02) v1(86.23,98.67) v1(86.49,35.24) v1(86.61,92.44) v1(86.61,91.45) v1(86.61,90.46) v1(86.87,48.7) v1(86.87,47.56) v1(86.87,46.42) v1(86.87,45.28) v1(86.87,44.13) v1(87.12,66.61) v1(87.25,155.77) v1(87.25,82.11) v1(87.25,14.41) v1(87.38,54.67) v1(87.38,53.4) v1(87.38,28.44) v1(87.38,27.29) v1(87.38,26.15) v1(87.38,25.01) v1(87.5,70.8) v1(87.63,148.53) v1(87.63,128.21) v1(87.76,112.46) v1(88.01,74.99) v1(88.52,28.44) v1(88.52,27.29) v1(88.52,26.15) v1(88.52,25.01) v1(88.65,88.77) v1(88.9,68.39) v1(89.03,35.24) v1(89.15,91.12) v1(89.41,96.08) v1(89.41,84.14) v1(89.66,28.44) v1(89.66,27.29) v1(89.66,26.15) v1(89.66,25.01) v1(89.79,155.77) v1(89.79,14.41) v1(90.04,97.85) v1(90.3,112.46) v1(90.42,62.93) v1(90.55,92.52) v1(90.55,74.99) v1(90.81,91.63) v1(90.81,28.44) v1(90.81,27.29) v1(90.81,26.15) v1(90.81,25.01) v1(91.25,101.64) v1(91.52,87.06) v1(91.57,35.24) v1(92.08,24.57) v1(92.2,62.93) v1(92.33,155.77) v1(92.33,14.41) v1(92.46,54.67) v1(92.46,49.34) v1(92.46,46.8) v1(92.46,44.26) v1(92.46,41.72) v1(92.46,39.18) v1(92.46,36.64) v1(92.71,105.04) v1(92.84,137.86) v1(92.84,135.32) v1(92.84,132.78) v1(92.84,130.24) v1(92.84,127.7) v1(92.84,125.16) v1(92.84,122.62) v1(92.84,120.08) v1(92.84,117.54) v1(92.84,115) v1(92.84,112.46) v1(92.96,92.52) v1(93.09,74.99) v1(93.22,85.03) v1(93.4,91.63) v1(93.73,101.64) v1(93.73,98.36) v1(93.98,69.02) v1(94.11,35.24) v1(94.23,51.12) v1(94.36,62.93) v1(94.49,88.46) v1(94.61,139.64) v1(94.74,73.6) v1(94.74,71.06) v1(94.87,155.77) v1(94.87,14.41) v1(95,95.82) v1(95,92.52) v1(95,41.72) v1(95.12,82.49) v1(95.5,76.14) v1(95.76,91.38) v1(95.7,72.6) v1(96.01,52.9) v1(96.14,114.62) v1(96.39,141.41) v1(96.65,35.24) v1(96.9,163.77) v1(96.9,159.83) v1(96.9,157.29) v1(96.9,12.76) v1(96.9,10.22) v1(96.9,6.29) v1(97.28,93.09) v1(97.23,72.6) v1(97.54,46.8) v1(97.54,36.64) v1(97.54,14.41) v1(97.66,85.03) v1(97.79,148.53) v1(97.79,76.14) v1(97.7,69.02) v1(97.79,54.67) v1(98.17,162.24) v1(98.17,160.97) v1(98.17,88.46) v1(98.17,9.08) v1(98.17,7.81) v1(98.42,24.57) v1(98.68,165.54) v1(98.68,4.51) v1(98.93,141.41) v1(99.06,28.56) v1(99.06,26.28) v1(99.06,25.13) v1(99.19,91.25) v1(99.19,35.24) v1(99.23,69.02) v1(99.7,87.06) v1(99.7,72.6) v1(99.82,76.14) v1(99.82,14.41) v1(99.95,19.11) v1(99.95,16.7) v1(100.08,51.88) v1(100.08,41.72) v1(100.2,28.56) v1(100.2,27.42) v1(100.2,26.28) v1(100.2,25.13) v1(100.33,54.67) v1(100.84,13.65) v1(101.22,165.54) v1(101.23,72.6) v1(101.22,4.51) v1(101.35,28.56) v1(101.35,27.42) v1(101.35,26.28) v1(101.35,25.13) v1(101.47,141.41) v1(101.73,85.03) v1(101.7,69.02) v1(101.73,35.24) v1(102.11,19.11) v1(102.23,87.57) v1(102.36,76.14) v1(102.49,28.56) v1(102.49,27.42) v1(102.49,26.28) v1(102.49,25.13) v1(102.62,46.8) v1(102.62,36.64) v1(102.87,158.69) v1(102.87,54.67) v1(103.25,143.19) v1(103.23,69.02) v1(103.76,165.54) v1(103.7,72.6) v1(103.76,4.51) v1(104.01,141.41) v1(104.01,82.74) v1(104.14,34.73) v1(104.14,32.19) v1(104.14,29.65) v1(104.14,27.11) v1(104.14,24.57) v1(104.14,22.03) v1(104.14,19.49) v1(104.14,16.95) v1(104.14,14.41) v1(104.39,85.41) v1(104.65,76.14) v1(105.03,144.97) v1(105.16,51.88) v1(105.23,72.6) v1(105.41,54.67) v1(105.7,69.02) v1(105.92,8.57) v1(106.3,165.54) v1(106.3,28.44) v1(106.3,27.29) v1(106.3,26.15) v1(106.3,25.01) v1(106.3,4.51) v1(106.43,80.45) v1(106.68,14.41) v1(106.81,146.75) v1(106.81,139.7) v1(106.81,82.99) v1(106.93,76.14) v1(107.23,69.02) v1(107.44,28.44) v1(107.44,27.29) v1(107.44,26.15) v1(107.44,25.01) v1(107.7,120.21) v1(107.7,116.01) v1(107.7,46.8) v1(107.7,72.6) v1(107.95,148.53) v1(107.95,54.67) v1(107.95,42.86) v1(108.59,28.44) v1(108.59,27.29) v1(108.59,26.15) v1(108.59,25.01) v1(108.71,138.43) v1(108.71,53.4) v1(108.84,165.54) v1(108.84,4.51) v1(109.09,42.86) v1(109.22,80.58) v1(109.23,72.6) v1(109.22,14.41) v1(109.35,146.75) v1(109.47,76.14) v1(109.7,69.02) v1(109.73,28.44) v1(109.73,27.29) v1(109.73,26.15) v1(109.73,25.01) v1(109.98,141.67) v1(110.24,42.86) v1(110.49,51.63) v1(110.74,140.14) v1(111,24.57) v1(111,13.65) v1(111.23,69.02) v1(111.38,165.54) v1(111.38,75.5) v1(111.38,42.86) v1(111.38,4.51) v1(111.51,154.56) v1(111.51,152.02) v1(111.51,149.48) v1(111.51,146.94) v1(111.51,141.67) v1(111.51,138.62) v1(111.76,14.41) v1(112.27,140.14) v1(112.27,69.02) v1(112.27,49.85) v1(112.39,54.67) v1(112.52,116.65) v1(112.52,42.86) v1(112.78,77.03) v1(113.03,158.69) v1(113.03,138.62) v1(113.67,42.86) v1(113.79,155.64) v1(113.92,165.54) v1(113.92,4.51) v1(114.05,146.94) v1(114.05,48.07) v1(114.3,14.41) v1(114.55,138.62) v1(115.32,71.56) v1(115.82,73.98) v1(115.82,46.29) v1(116.08,138.62) v1(116.08,8.57) v1(116.33,155.64) v1(116.46,165.54) v1(116.46,4.51) v1(116.59,146.94) v1(116.84,54.67) v1(116.84,14.41) v1(117.09,69.79) v1(117.22,144.34) v1(117.22,142.56) v1(117.35,24.57) v1(117.6,138.62) v1(117.6,44.51) v1(118.11,148.53) v1(118.24,143.45) v1(118.24,142.56) v1(118.49,28.56) v1(118.49,27.42) v1(118.49,26.28) v1(118.49,25.13) v1(118.87,155.64) v1(119,165.54) v1(119,71.95) v1(119,4.51) v1(119.13,146.94) v1(119.13,138.62) v1(119.38,42.74) v1(119.38,14.41) v1(119.63,28.56) v1(119.63,27.42) v1(119.63,26.28) v1(119.63,25.13) v1(119.76,70.62) v1(120.65,138.62) v1(120.65,66.23) v1(120.78,28.56) v1(120.78,27.42) v1(120.78,26.28) v1(120.78,25.13) v1(121.08,71.89) v1(121.16,40.96) v1(121.41,155.64) v1(121.54,165.54) v1(121.54,4.51) v1(121.67,146.94) v1(121.92,28.56) v1(121.92,27.42) v1(121.92,26.28) v1(121.92,25.13) v1(121.92,14.41) v1(122.17,138.62) v1(122.43,22.8) v1(122.43,20.26) v1(122.43,17.72) v1(122.81,67.63) v1(122.81,46.67) v1(122.94,39.18) v1(123.06,44.13) v1(123.06,28.56) v1(123.06,27.42) v1(123.19,158.69) v1(123.32,54.67) v1(123.7,138.62) v1(123.95,155.64) v1(124.08,165.54) v1(124.08,4.51) v1(124.21,146.94) v1(124.21,28.56) v1(124.21,27.42) v1(124.71,69.66) v1(124.71,37.4) v1(124.97,22.8) v1(125.22,138.62) v1(125.48,55.18) v1(125.76,119.95) v1(125.86,60.9) v1(126.03,57.85) v1(126.24,8.57) v1(126.49,155.64) v1(126.62,165.54) v1(126.62,4.51) v1(126.75,138.62) v1(126.87,146.24) v1(127.13,37.02) v1(127.51,22.8) v1(127.64,62.67) v1(128.02,144.72) v1(128.02,138.62) v1(128.27,148.53) v1(128.27,55.05) v1(128.27,52.39) v1(128.56,57.85) v1(129.03,155.64) v1(129.03,35.12) v1(129.03,32.58) v1(129.03,30.04) v1(129.03,27.5) v1(129.03,24.96) v1(129.16,165.54) v1(129.16,46.67) v1(129.16,4.51) v1(129.29,138.62) v1(129.54,144.72) v1(129.67,50.86) v1(129.67,37.02) v1(129.79,53.15) v1(130.68,63.82) v1(131.06,144.72) v1(131.32,49.21) v1(131.32,13.65) v1(131.57,155.64) v1(131.7,165.54) v1(131.7,65.34) v1(131.7,4.51) v1(132.21,37.02) v1(132.59,144.72) v1(133.1,163.39) v1(133.1,160.85) v1(133.1,158.31) v1(133.1,11.75) v1(133.1,9.21) v1(133.1,6.67) v1(133.22,35.12) v1(133.22,32.58) v1(133.22,30.04) v1(133.22,27.5) v1(133.22,24.96) v1(133.22,22.42) v1(133.35,49.34) v1(133.73,155.89) v1(133.73,14.16) v1(134.11,144.72) v1(134.37,59.5) v1(134.37,57.72) v1(134.49,53.15) v1(134.49,50.86) v1(134.75,37.02) v1(135.1,25.89) v1(135.13,118.81) v1(135.13,24.7) v1(135.13,23.56) v1(135.13,20.13) v1(135.26,58.61) v1(135.38,16.13) v1(135.51,54.67) v1(135.51,53.15) v1(135.64,144.72) v1(136.14,59.5) v1(136.14,57.72) v1(136.27,155.77) v1(136.24,25.89) v1(136.27,24.7) v1(136.27,23.56) v1(136.27,14.29) v1(137.16,144.72) v1(137.29,37.02) v1(137.41,25.84) v1(137.41,24.7) v1(137.41,23.56) v1(137.67,20.13) v1(138.43,148.53) v1(138.43,114.11) v1(138.56,25.84) v1(138.56,24.7) v1(138.56,23.56) v1(138.68,144.72) v1(138.81,155.77) v1(138.81,14.29) v1(139.06,120.33) v1(139.7,25.84) v1(139.7,24.7) v1(139.7,23.56) v1(139.83,70.29) v1(139.83,37.02) v1(140.21,144.72) v1(140.21,20.13) v1(140.46,53.78) v1(140.84,25.84) v1(140.84,24.7) v1(140.84,23.56) v1(141.22,48.83) v1(141.35,155.77) v1(141.35,14.29) v1(141.6,68.14) v1(141.73,144.72) v1(141.86,138.11) v1(141.99,25.84) v1(141.99,24.7) v1(141.99,23.56) v1(142.37,37.02) v1(142.49,56.45) v1(142.49,53.91) v1(142.49,51.37) v1(142.49,48.83) v1(142.75,20.13) v1(143,68.14) v1(143.13,25.84) v1(143.13,24.7) v1(143.13,23.56) v1(143.64,140.27) v1(143.89,155.77) v1(143.89,14.29) v1(144.15,70.29) v1(144.24,25.89) v1(144.27,24.7) v1(144.27,23.56) v1(144.78,65.72) v1(144.91,37.02) v1(145.03,48.83) v1(145.16,128.33) v1(145.29,20.13) v1(145.38,25.89) v1(145.41,24.7) v1(145.41,23.56) v1(146.18,140.27) v1(146.43,155.77) v1(146.43,14.29) v1(146.56,25.84) v1(146.56,24.7) v1(146.56,23.56) v1(146.69,67.75) v1(147.45,37.02) v1(147.57,48.83) v1(147.7,163.77) v1(147.7,160.46) v1(147.7,157.92) v1(147.7,25.84) v1(147.7,24.7) v1(147.7,23.56) v1(147.7,12.13) v1(147.7,9.59) v1(147.7,6.29) v1(147.83,20.13) v1(148.03,52.01) v1(148.59,149.16) v1(148.84,65.6) v1(148.84,25.84) v1(148.84,24.7) v1(148.84,23.56) v1(148.97,162.24) v1(148.97,160.97) v1(148.97,155.64) v1(148.97,18.22) v1(148.97,15.56) v1(148.97,9.08) v1(148.97,7.81) v1(149.22,62.04) v1(149.48,165.54) v1(149.48,13.65) v1(149.48,4.51) v1(149.73,132.91) v1(149.99,37.02) v1(150.11,48.83) v1(150.11,28.26) v1(150.11,27.11) v1(150.11,25.97) v1(150.11,24.83) v1(150.11,23.69) v1(150.11,22.54) v1(151.26,28.26) v1(151.26,27.11) v1(151.26,25.97) v1(151.26,24.83) v1(151.26,23.69) v1(151.26,22.54) v1(151.51,155.64) v1(151.64,59.75) v1(151.84,48.83) v1(152.02,165.54) v1(152.02,13.65) v1(152.02,4.51) v1(152.4,28.26) v1(152.4,27.11) v1(152.4,25.97) v1(152.4,24.83) v1(152.4,23.69) v1(152.4,22.54) v1(152.53,113.86) v1(152.53,37.02) v1(152.91,110.68) v1(153.16,74.23) v1(153.54,28.26) v1(153.54,27.11) v1(153.54,25.97) v1(153.54,24.83) v1(153.54,23.69) v1(153.54,22.54) v1(153.67,158.69) v1(154.05,155.64) v1(154.56,165.54) v1(154.56,13.65) v1(154.56,8.57) v1(154.56,4.51) v1(154.69,28.26) v1(154.69,27.11) v1(154.69,25.97) v1(154.69,24.83) v1(154.69,23.69) v1(154.69,22.54) v1(154.94,137.1) v1(155.07,37.02) v1(155.7,55.69) v1(155.83,28.26) v1(155.83,27.11) v1(155.83,25.97) v1(155.83,24.83) v1(155.83,23.69) v1(155.83,22.54) v1(156.59,155.64) v1(156.72,100.77) v1(157.1,165.54) v1(157.1,140.27) v1(157.1,115.51) v1(157.1,13.65) v1(157.1,4.51) v1(157.61,37.02) v1(158.62,140.27) v1(158.75,148.53) v1(159,52.39) v1(159.13,155.64) v1(159.64,165.54) v1(159.64,13.65) v1(159.64,4.51) v1(160.15,37.02) v1(160.27,23.43) v1(160.27,22.29) v1(160.27,21.15) v1(160.66,73.47) v1(160.91,94.55) v1(161.04,111.44) v1(161.42,23.43) v1(161.42,22.29) v1(161.42,21.15) v1(161.54,143.95) v1(161.67,155.64) v1(162.18,165.54) v1(162.18,13.65) v1(162.18,4.51) v1(162.56,23.43) v1(162.56,22.29) v1(162.56,21.15) v1(162.69,37.02) v1(163.32,69.91) v1(163.7,23.43) v1(163.7,22.29) v1(163.7,21.15) v1(163.83,158.69) v1(164.21,155.64) v1(164.21,35.12) v1(164.72,165.54) v1(164.72,13.65) v1(164.72,8.57) v1(164.72,4.51) v1(164.85,23.43) v1(164.85,22.29) v1(164.85,21.15) v1(165.23,145.67) v1(165.23,37.02) v1(165.99,23.43) v1(165.99,22.29) v1(165.99,21.15) v1(166.75,155.64) v1(166.75,35.12) v1(167,22.92) v1(167,21.78) v1(167.13,163.39) v1(167.26,165.54) v1(167.26,13.65) v1(167.26,4.51) v1(167.77,37.02) v1(168.15,22.92) v1(168.15,21.78) v1(168.91,148.53) v1(168.91,33.21) v1(169.29,155.64) v1(169.29,35.12) v1(169.29,22.92) v1(169.29,21.78) v1(169.67,17.34) v1(169.8,165.54) v1(169.8,13.65) v1(169.8,4.51) v1(170.31,37.02) v1(170.31,31.18) v1(170.31,28.89) v1(170.31,26.48) v1(171.07,24.7) v1(171.07,22.16) v1(171.07,19.62) v1(171.58,145.8) v1(171.83,155.64) v1(171.83,35.12) v1(172.34,165.54) v1(172.34,13.65) v1(172.34,4.51) v1(172.85,37.02) v1(172.85,22.8) v1(172.85,20.26) v1(172.85,17.72) v1(173.1,28.44) v1(173.1,27.29) v1(173.1,26.15) v1(173.1,25.01) v1(173.99,158.69) v1(174.24,28.44) v1(174.24,27.29) v1(174.24,26.15) v1(174.24,25.01) v1(174.37,155.64) v1(174.37,35.12) v1(174.88,165.54) v1(174.88,13.65) v1(174.88,8.57) v1(174.88,4.51) v1(175.39,37.02) v1(175.39,28.44) v1(175.39,27.29) v1(175.39,26.15) v1(175.39,25.01) v1(176.53,28.44) v1(176.53,27.29) v1(176.53,26.15) v1(176.53,25.01) v1(176.91,155.64) v1(176.91,35.12) v1(176.91,31.69) v1(177.42,165.54) v1(177.42,13.65) v1(177.42,4.51) v1(177.55,38.73) v1(177.8,24.57) v1(179.07,148.53) v1(179.32,140.91) v1(179.32,138.37) v1(179.32,135.95) v1(179.45,155.64) v1(179.58,128.59) v1(179.58,127.06) v1(179.58,125.54) v1(179.58,124.02) v1(179.58,122.49) v1(179.58,120.97) v1(179.58,119.44) v1(179.58,117.92) v1(179.58,116.4) v1(179.58,114.87) v1(179.58,113.6) v1(179.58,112.33) v1(179.58,110.81) v1(179.96,165.54) v1(179.96,13.65) v1(179.96,4.51) v1(180.21,38.73) v1(181.23,129.98) v1(181.23,128.59) v1(181.36,70.8) v1(181.99,155.64) v1(182.25,71.82) v1(182.5,165.54) v1(182.5,131.25) v1(182.5,13.65) v1(182.5,4.51) v1(182.63,39.75) v1(182.88,135.95) v1(183.01,129.86) v1(183.01,128.59) v1(183.13,71.82) v1(183.13,70.8) v1(183.26,56.07) v1(183.52,123.13) v1(183.52,122.11) v1(183.9,163.39) v1(183.9,160.85) v1(183.9,158.31) v1(183.9,11.75) v1(183.9,9.21) v1(183.9,6.67) v1(184.02,64.96) v1(184.02,63.44) v1(184.15,24.57) v1(184.4,122.11) v1(184.53,155.89) v1(184.53,14.16) v1(185.04,38.99) v1(185.29,123.13) v1(185.29,28.56) v1(185.29,27.42) v1(185.29,26.28) v1(185.29,25.13) v1(185.42,135.95) v1(185.55,65.72) v1(185.55,64.2) v1(185.67,111.44) v1(185.67,110.05) v1(185.67,108.65) v1(185.67,106.87) v1(185.67,105.47) v1(185.67,104.08) v1(185.67,102.3) v1(185.67,100.9) v1(185.67,99.5) v1(185.67,94.81) v1(185.67,93.41) v1(185.67,92.01) v1(185.67,90.23) v1(185.67,88.84) v1(185.67,87.44) v1(185.67,85.66) v1(185.67,84.26) v1(186.44,43.69) v1(186.44,28.56) v1(186.44,27.42) v1(186.44,26.28) v1(186.44,25.13) v1(186.69,112.84) v1(187.07,155.77) v1(187.07,82.74) v1(187.07,81.47) v1(187.07,80.2) v1(187.07,78.68) v1(187.07,77.15) v1(187.07,75.63) v1(187.07,74.1) v1(187.07,72.58) v1(187.07,71.06) v1(187.07,69.53) v1(187.07,68.01) v1(187.07,66.48) v1(187.07,64.96) v1(187.07,14.29) v1(187.58,28.56) v1(187.58,27.42) v1(187.58,26.28) v1(187.58,25.13) v1(187.83,134.56) v1(187.83,132.02) v1(187.83,129.48) v1(187.83,126.94) v1(187.83,124.4) v1(187.83,121.86) v1(187.83,119.32) v1(187.83,116.78) v1(187.83,114.24) v1(188.72,61.66) v1(188.72,43.18) v1(188.72,28.56) v1(188.72,27.42) v1(188.72,26.28) v1(188.72,25.13) v1(189.1,21.02) v1(189.1,18.48) v1(189.1,16.32) v1(189.23,148.53) v1(189.23,138.37) v1(189.23,118.05) v1(189.23,107.89) v1(189.23,97.73) v1(189.23,87.57) v1(189.23,77.41) v1(189.23,67.25) v1(189.61,155.77) v1(189.61,14.29) v1(189.87,28.56) v1(189.87,27.42) v1(190.37,22.8) v1(190.88,44.07) v1(190.88,43.18) v1(191.01,28.56) v1(191.01,27.42) v1(191.64,19.68) v1(192.02,148.27) v1(192.02,145.73) v1(192.02,143.19) v1(192.02,140.65) v1(192.02,138.11) v1(192.02,135.57) v1(192.02,133.03) v1(192.02,130.49) v1(192.02,127.95) v1(192.02,125.41) v1(192.02,106.24) v1(192.02,103.7) v1(192.02,101.16) v1(192.02,98.62) v1(192.02,96.08) v1(192.02,93.54) v1(192.02,91) v1(192.02,88.46) v1(192.02,85.92) v1(192.02,83.38) v1(192.15,155.77) v1(192.15,122.87) v1(192.15,80.84) v1(192.15,14.29) v1(193.04,22.8) v1(193.17,44.07) v1(193.17,43.18) v1(193.42,119.32) v1(193.42,118.17) v1(193.42,117.03) v1(193.42,115.89) v1(193.93,66.99) v1(194.44,119.32) v1(194.44,118.17) v1(194.44,117.03) v1(194.44,115.89) v1(194.56,148.27) v1(194.56,122.62) v1(194.56,106.24) v1(194.56,80.58) v1(194.69,155.77) v1(194.69,22.8) v1(194.69,14.29) v1(195.58,44.07) v1(195.58,43.18) v1(195.83,34.99) v1(195.83,32.45) v1(195.83,29.91) v1(195.83,27.62) v1(195.83,25.08) v1(196.85,39.31) v1(196.85,18.99) v1(197.1,148.27) v1(197.1,122.62) v1(197.1,106.24) v1(197.1,80.58) v1(197.23,155.77) v1(197.23,14.29) v1(198.25,52.51) v1(198.25,33.97) v1(198.5,163.77) v1(198.5,160.46) v1(198.5,157.92) v1(198.5,12.13) v1(198.5,9.59) v1(198.5,6.29) v1(198.7,143.57) v1(198.7,142.43) v1(198.7,141.29) v1(198.7,140.14) v1(198.7,139) v1(198.7,137.86) v1(198.7,101.66) v1(198.7,100.52) v1(198.7,99.38) v1(198.7,98.23) v1(198.7,97.09) v1(198.7,95.95) v1(198.83,129.1) v1(198.83,127.95) v1(198.83,126.81) v1(198.83,125.67) v1(198.83,87.19) v1(198.83,86.04) v1(198.83,84.9) v1(198.83,83.76) v1(199.39,107.89) v1(199.39,72.33) v1(199.64,148.27) v1(199.64,122.62) v1(199.64,106.24) v1(199.64,80.58) v1(199.77,162.24) v1(199.77,160.97) v1(199.77,155.64) v1(199.77,9.08) v1(199.77,7.81) v1(199.85,143.57) v1(199.85,142.43) v1(199.85,141.29) v1(199.85,140.14) v1(199.85,139) v1(199.85,137.86) v1(199.85,101.66) v1(199.85,100.52) v1(199.85,99.38) v1(199.85,98.23) v1(199.85,97.09) v1(199.85,95.95) v1(199.97,129.1) v1(199.97,127.95) v1(199.97,126.81) v1(199.97,125.67) v1(199.97,87.19) v1(199.97,86.04) v1(199.97,84.9) v1(199.97,83.76) v1(200.28,165.54) v1(200.28,4.51) v1(200.99,141.29) v1(200.99,140.14) v1(200.99,139) v1(200.99,137.86) v1(200.99,99.38) v1(200.99,98.23) v1(200.99,97.09) v1(200.99,95.95) v1(201.12,129.1) v1(201.12,127.95) v1(201.12,126.81) v1(201.12,125.67) v1(201.12,87.19) v1(201.12,86.04) v1(201.12,84.9) v1(201.12,83.76) v1(201.42,27.5) v1(201.42,24.96) v1(201.42,22.42) v1(201.68,8.83) v1(202.18,148.27) v1(202.13,141.29) v1(202.13,140.14) v1(202.13,139) v1(202.13,137.86) v1(202.18,122.62) v1(202.18,106.24) v1(202.13,99.38) v1(202.13,98.23) v1(202.13,97.09) v1(202.13,95.95) v1(202.18,80.58) v1(202.26,129.1) v1(202.26,127.95) v1(202.26,126.81) v1(202.26,125.67) v1(202.26,87.19) v1(202.26,86.04) v1(202.26,84.9) v1(202.26,83.76) v1(202.31,155.64) v1(202.69,136.72) v1(202.69,130.37) v1(202.69,94.81) v1(202.69,88.46) v1(202.82,165.54) v1(202.82,21.15) v1(202.82,4.51) v1(203.33,57.72) v1(204.34,77.03) v1(204.34,43.62) v1(204.47,158.69) v1(204.6,148.27) v1(204.6,145.73) v1(204.6,143.19) v1(204.6,106.24) v1(204.6,103.7) v1(204.6,101.16) v1(204.72,122.62) v1(204.72,80.58) v1(204.85,155.64) v1(204.98,119.57) v1(204.98,118.55) v1(205.1,37.4) v1(205.1,36.39) v1(205.36,165.54) v1(205.36,21.15) v1(205.36,4.51) v1(205.99,141.8) v1(205.99,119.57) v1(205.99,118.55) v1(205.99,99.76) v1(206.25,37.4) v1(206.25,36.39) v1(206.76,13.91) v1(207.01,119.57) v1(207.01,118.55) v1(207.01,117.54) v1(207.01,39.31) v1(207.01,18.99) v1(207.26,122.62) v1(207.26,80.58) v1(207.39,155.64) v1(207.39,37.4) v1(207.39,36.39) v1(207.77,24.83) v1(207.77,23.81) v1(207.77,22.8) v1(207.9,165.54) v1(207.9,21.15) v1(207.9,4.51) v1(208.41,138.37) v1(208.53,141.8) v1(208.53,99.76) v1(208.53,37.4) v1(208.53,36.39) v1(208.79,25.84) v1(208.79,24.83) v1(208.79,23.81) v1(208.79,22.8) v1(208.91,63.18) v1(209.55,148.53) v1(209.55,118.05) v1(209.55,107.89) v1(209.55,97.73) v1(209.8,122.62) v1(209.93,155.64) v1(210.31,82.99) v1(210.31,80.58) v1(210.44,165.54) v1(210.44,21.15) v1(210.44,4.51) v1(211.07,141.8) v1(211.07,99.76) v1(211.84,8.83) v1(212.34,140.4) v1(212.34,137.86) v1(212.34,135.32) v1(212.34,132.14) v1(212.34,130.24) v1(212.34,127.7) v1(212.34,125.16) v1(212.34,122.62) v1(212.34,98.36) v1(212.34,95.82) v1(212.34,93.28) v1(212.34,90.74) v1(212.34,88.2) v1(212.34,85.66) v1(212.47,155.64) v1(212.98,165.54) v1(212.98,21.15) v1(212.98,4.51) v1(214.63,158.69) v1(214.63,138.37) v1(214.63,117.67) v1(214.63,107.51) v1(214.63,97.35) v1(214.63,80.45) v1(214.63,71.82) v1(214.63,68.77) v1(214.63,60.13) v1(214.76,87.31) v1(215.01,155.64) v1(215.52,165.54) v1(215.52,21.15) v1(215.52,4.51) v1(216.92,13.91) v1(217.55,155.64) v1(218.06,165.54) v1(218.06,21.15) v1(218.06,4.51) v1(218.19,121.22) v1(218.44,113.73) v1(219.57,46.8) v1(219.71,148.53) v1(219.71,128.21) v1(219.71,39.31) v1(219.71,29.15) v1(219.71,18.99) v1(219.96,123) v1(220.09,155.64) v1(220.22,115.38) v1(220.47,65.6) v1(220.6,165.54) v1(220.6,21.15) v1(220.6,4.51) v1(221.74,124.78) v1(222,8.83) v1(222.63,155.64) v1(222.76,77.28) v1(222.76,73.09) v1(222.76,68.77) v1(223.01,61.91) v1(223.14,165.54) v1(223.14,21.15) v1(223.14,4.51) v1(223.52,126.56) v1(224.03,119.32) v1(224.79,158.69) v1(224.79,138.37) v1(225.17,155.64) v1(225.3,128.33) v1(225.68,165.54) v1(225.68,21.15) v1(225.68,4.51) v1(225.93,80.33) v1(226.31,61.91) v1(227.08,130.11) v1(227.08,13.91) v1(227.71,155.64) v1(228.22,165.54) v1(228.22,21.15) v1(228.22,4.51) v1(228.35,123.63) v1(228.35,105.35) v1(228.35,95.19) v1(228.35,85.03) v1(228.85,131.89) v1(229.49,112.08) v1(229.87,148.53) v1(229.87,74.87) v1(229.87,64.71) v1(229.87,44.39) v1(229.87,34.23) v1(229.87,24.07) v1(230.25,155.13) v1(230.63,133.67) v1(230.76,165.54) v1(230.76,21.15) v1(230.76,4.51) v1(232.03,153.35) v1(232.03,22.03) v1(232.16,8.83) v1(232.41,150.81) v1(232.41,148.27) v1(232.41,145.73) v1(232.41,143.19) v1(232.41,140.65) v1(232.41,139) v1(232.41,135.45) v1(232.41,115) v1(232.41,112.59) v1(232.41,110.05) v1(232.41,107.51) v1(232.41,104.97) v1(232.41,102.43) v1(232.41,99.89) v1(232.41,97.22) v1(232.41,94.81) v1(232.41,92.27) v1(232.41,89.73) v1(232.41,87.19) v1(232.41,84.65) v1(232.41,82.11) v1(232.41,79.44) v1(232.41,77.03) v1(232.41,74.49) v1(232.41,71.95) v1(232.41,69.41) v1(232.41,66.87) v1(232.41,64.33) v1(232.41,61.79) v1(232.41,59.25) v1(232.41,56.71) v1(232.41,51.24) v1(232.41,49.09) v1(232.41,46.55) v1(232.41,44.01) v1(232.41,41.47) v1(232.41,38.93) v1(232.41,36.39) v1(232.41,33.85) v1(232.41,31.31) v1(232.41,28.77) v1(232.41,26.23) v1(232.41,23.69) v1(232.92,128.21) v1(233.3,165.54) v1(233.3,4.51) v1(234.19,137.22) v1(234.7,48.32) v1(234.95,158.69) v1(234.95,117.54) v1(235.84,165.54) v1(235.84,4.51) v1(235.97,139) v1(236.85,132.14) v1(237.24,100.77) v1(237.24,98.23) v1(237.24,95.69) v1(237.24,93.15) v1(237.24,90.61) v1(237.24,88.07) v1(237.24,85.53) v1(237.24,82.99) v1(237.24,80.45) v1(237.24,77.91) v1(237.24,75.37) v1(237.24,72.83) v1(237.24,70.29) v1(237.24,67.75) v1(237.24,65.21) v1(237.24,62.67) v1(237.24,60.13) v1(237.24,57.59) v1(237.24,44.89) v1(237.24,42.35) v1(237.24,39.81) v1(237.24,37.27) v1(237.24,34.73) v1(237.24,32.19) v1(237.24,29.65) v1(237.24,27.11) v1(237.24,24.57) v1(237.24,22.03) v1(237.24,19.49) v1(237.24,16.95) v1(237.24,14.41) v1(237.49,102.93) v1(237.62,12) v1(237.74,140.78) v1(238.38,165.54) v1(238.38,120.97) v1(238.38,4.51) v1(239.52,142.56) v1(239.9,11.62) v1(240.03,148.53) v1(240.03,110.43) v1(240.03,103.31) v1(240.03,18.99) v1(240.66,136.08) v1(240.92,165.54) v1(240.92,4.51) v1(241.3,144.34) v1(241.43,123.89) v1(242.32,8.83) v1(242.44,11.62) v1(242.57,103.31) v1(243.08,146.11) v1(243.46,165.54) v1(243.46,4.51) v1(244.47,126.94) v1(244.86,147.89) v1(244.98,11.62) v1(245.11,158.69) v1(245.11,103.31) v1(246,165.54) v1(246,34.48) v1(246,31.43) v1(246,29.91) v1(246,4.51) v1(246.89,10.86) v1(247.02,128.71) v1(247.52,139.38) v1(247.52,11.62) v1(247.65,103.31) v1(248.54,165.54) v1(248.54,4.51) v1(249.2,14.35) v1(250.06,11.62) v1(250.19,125.67) v1(250.19,115.51) v1(250.19,105.35) v1(250.19,103.31) v1(251.08,165.54) v1(251.08,4.51) v1(252.48,8.83) v1(252.6,11.62) v1(252.73,103.31) v1(253.62,165.54) v1(253.62,4.51) v1(254.89,12) v1(255.27,158.69) v1(255.27,103.31) v1(255.27,100.77) v1(255.27,98.23) v1(255.27,95.69) v1(255.27,93.15) v1(255.27,90.61) v1(255.27,88.07) v1(255.27,85.53) v1(255.27,82.99) v1(255.27,80.45) v1(255.27,77.91) v1(255.27,75.37) v1(255.27,72.83) v1(255.27,70.29) v1(255.27,67.75) v1(255.27,65.21) v1(255.27,62.67) v1(255.27,60.13) v1(255.27,57.59) v1(255.27,55.05) v1(255.27,52.51) v1(255.27,49.97) v1(255.27,47.43) v1(255.27,44.89) v1(255.27,42.35) v1(255.27,39.81) v1(255.27,37.27) v1(255.27,34.73) v1(255.27,32.19) v1(255.27,29.65) v1(255.27,27.11) v1(255.27,24.57) v1(255.27,22.03) v1(255.27,19.49) v1(255.27,16.95) v1(255.27,14.41) v1(256.16,165.54) v1(256.16,4.51) v1(257.81,163.64) v1(257.81,161.1) v1(257.81,158.56) v1(257.81,156.02) v1(257.81,152.97) v1(257.81,150.43) v1(257.81,147.89) v1(257.81,145.61) v1(257.81,143.07) v1(257.81,140.53) v1(257.81,137.99) v1(257.81,135.45) v1(257.81,132.91) v1(257.81,130.62) v1(257.81,128.08) v1(257.81,125.54) v1(257.81,123) v1(257.81,120.46) v1(257.81,117.92) v1(257.81,115.38) v1(257.81,112.84) v1(257.81,110.3) v1(257.81,107.76) v1(257.81,105.22) v1(257.81,102.68) v1(257.81,100.14) v1(257.81,97.6) v1(257.81,95.06) v1(257.81,92.52) v1(257.81,89.98) v1(257.81,87.44) v1(257.81,84.9) v1(257.81,82.36) v1(257.81,79.82) v1(257.81,77.28) v1(257.81,74.74) v1(257.81,72.2) v1(257.81,69.66) v1(257.81,67.12) v1(257.81,64.58) v1(257.81,62.04) v1(257.81,59.5) v1(257.81,56.96) v1(257.81,54.42) v1(257.81,51.88) v1(257.81,49.34) v1(257.81,46.8) v1(257.81,44.26) v1(257.81,41.72) v1(257.81,39.18) v1(257.81,36.64) v1(257.81,34.1) v1(257.81,31.56) v1(257.81,29.02) v1(257.81,26.48) v1(257.81,23.94) v1(257.81,21.4) v1(257.81,18.86) v1(257.81,16.32) v1(257.81,13.78) v1(257.81,11.24) v1(257.81,8.7) v1(257.81,6.16) v2(125.89,93.12) v2(128.89,93.12) v2(131.89,93.12) v2(134.89,93.12) v2(137.89,93.12) v2(140.89,93.12)
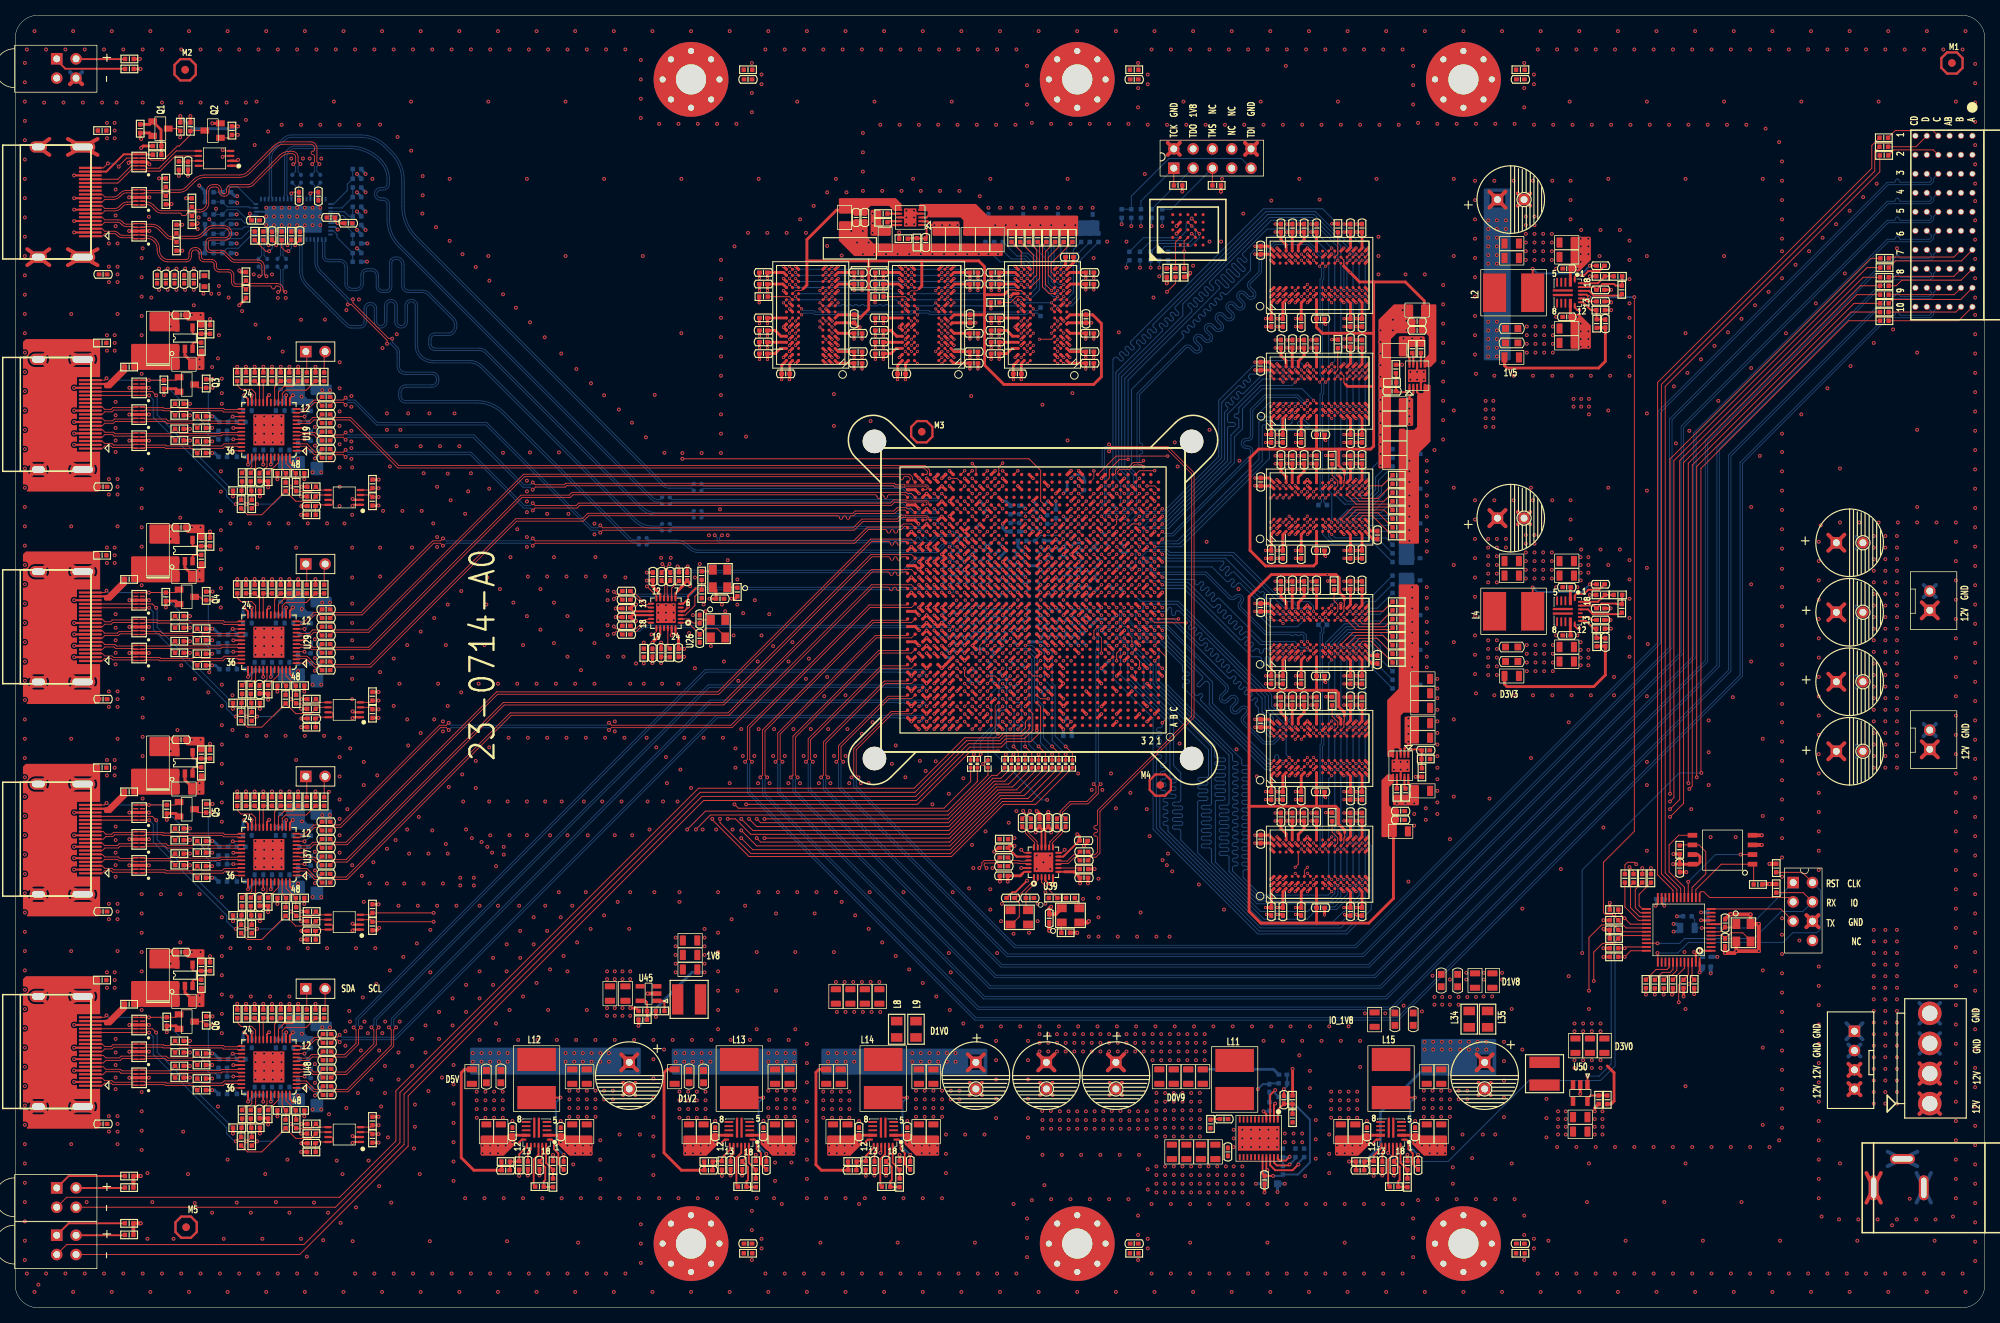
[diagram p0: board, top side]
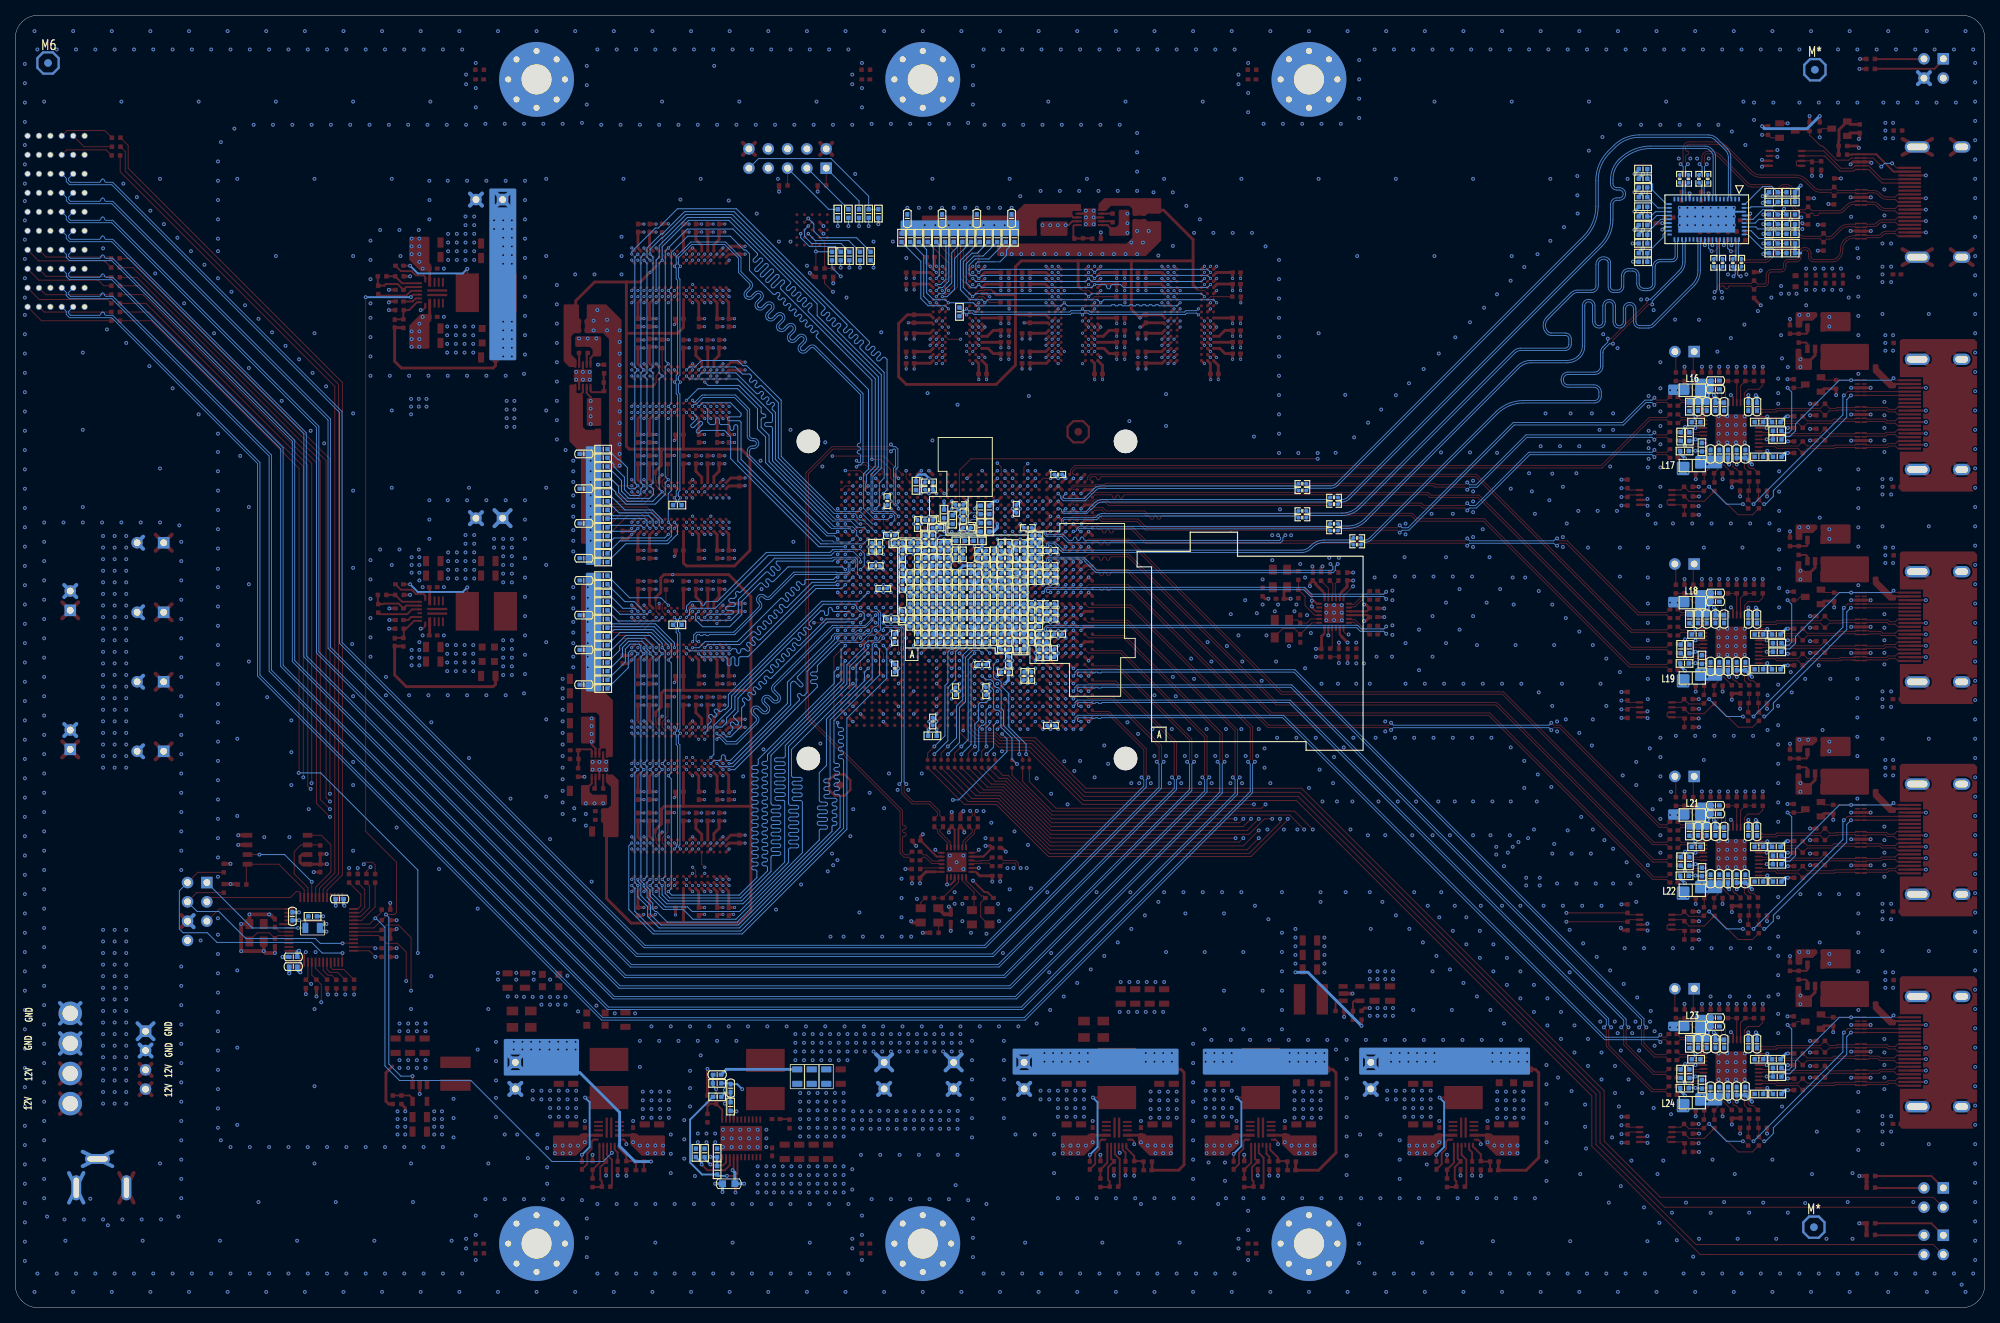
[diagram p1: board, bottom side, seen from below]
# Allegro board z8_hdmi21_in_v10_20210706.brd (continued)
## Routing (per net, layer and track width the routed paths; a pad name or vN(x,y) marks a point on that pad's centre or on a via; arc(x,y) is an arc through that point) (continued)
VCC_D0V9: length 207.9
  TOP w0.356: P1.V13 v2(138.89,94.12) ; P1.W17 v2(134.89,95.12) ; P1.N20 v2(131.89,88.12) P1.N19 ; P1.R21 v2(129.89,90.12) ; P1.AB24 v2(126.89,98.12) ; P1.V12 v2(139.89,94.12) ; P1.AA18 v2(132.89,97.12) ; P1.Y13 v2(138.89,96.12) ; P1.AB22 v2(128.89,98.12) ; P1.Y16 v2(135.89,96.12) ; P1.AB18 v2(132.89,98.12) ; P1.N24 v2(126.89,88.12) ; P1.Y14 v2(137.89,96.12) ; P1.W24 v2(126.89,95.12) ; P1.AB17 v2(134.89,98.12) ; P1.N16 v2(135.89,88.12) ; P1.U17 v2(134.89,92.12) ; P1.AB14 v2(137.89,98.12) ; P1.R23 v2(127.89,90.12) ; P1.T23 v2(127.89,91.12) ; P1.W12 v2(139.89,95.12) ; P1.Y22 v2(128.89,96.12) ; P1.U11 v2(140.89,92.12) ; P1.AB12 v2(139.89,98.12) ; P1.P12 v2(139.89,89.12) ; P1.V19 v2(131.89,94.12) ; P1.W22 v2(128.89,95.12) ; P1.AB25 v2(125.89,98.12) ; P1.AA13 v2(138.89,97.12) ; P1.P14 v2(137.89,89.12) ; P1.T25 v2(125.89,91.12) ; P1.T24 v2(126.89,91.12) ; P1.R22 v2(128.89,90.12) ; P1.AB20 v2(130.89,98.12) ; P1.V23 v2(127.89,94.12) ; P1.AB15 v2(136.89,98.12) ; P1.N15 v2(136.89,88.12) ; P1.R24 v2(126.89,90.12) ; P1.T21 v2(129.89,91.12) ; P1.AB21 v2(129.89,98.12) ; P1.N17 v2(134.89,88.12) ; P1.W15 v2(136.89,95.12) ; P1.AB13 v2(138.89,98.12) ; P1.P24 v2(126.89,89.12) ; P1.R12 v2(139.89,90.12) ; P1.U21 v2(129.89,92.12) ; P1.V15 v2(136.89,94.12) ; P1.P25 v2(125.89,89.12) ; P1.T19 v2(131.89,91.12) ; P1.R17 v2(134.89,90.12) ; P1.AA19 v2(131.89,97.12) ; P1.Y23 v2(127.89,96.12) ; P1.N22 v2(128.89,88.12) ; P1.N25 v2(125.89,88.12) ; P1.W16 v2(135.89,95.12) ; P1.AB23 v2(127.89,98.12) ; P1.P22 v2(128.89,89.12) ; P1.V18 v2(132.89,94.12) ; P1.AA23 v2(127.89,97.12) ; P1.U13 v2(138.89,92.12) ; P1.P17 v2(134.89,89.12) ; P1.N23 v2(127.89,88.12) ; P1.Y24 v2(126.89,96.12) ; P1.N12 v2(139.89,88.12) ; P1.V22 v2(128.89,94.12) ; P1.U20 v2(130.89,92.12) ; P1.U12 v2(139.89,92.12) ; P1.Y12 v2(139.89,96.12) ; P1.U18 v2(132.89,92.12) ; P1.R18 v2(132.89,90.12) ; P1.AB16 v2(135.89,98.12) ; P1.V14 v2(137.89,94.12) ; P1.N13 v2(138.89,88.12) ; P1.V17 v2(134.89,94.12) ; P1.N18 v2(132.89,88.12) ; P1.U16 v2(135.89,92.12) ; P1.U15 v2(136.89,92.12) ; P1.R16 v2(135.89,90.12) ; P1.T13 v2(137.89,91.12) ; P1.W19 v2(131.89,95.12) ; P1.V24 v2(126.89,94.12) ; P1.AA24 v2(126.89,97.12) ; P1.N14 v2(137.89,88.12) ; P1.R14 v2(137.89,90.12) ; P1.AC18 v2(132.89,99.12) ; P1.R19 v2(131.89,90.12) ; P1.U25 v2(125.89,92.12) ; P1.W14 v2(137.89,95.12) ; P1.Y21 v2(129.89,96.12) ; P1.U23 v2(127.89,92.12) ; P1.T20 v2(130.89,91.12) ; P1.W20 v2(130.89,95.12) ; P1.U22 v2(128.89,92.12) ; P1.R13 v2(138.89,90.12) ; P1.V20 v2(130.89,94.12) ; P1.AA16 v2(135.89,97.12) ; P1.W21 v2(129.89,95.12)
  TOP w0.381: P1.R11 v2(140.89,90.12) ; P1.W11 v2(140.89,95.12) ; P1.T11 v2(139.89,91.12) ; P1.AA11 v2(140.89,97.12) ; R283.2 v1(168.02,31.43) ; P1.AC21 v2(129.89,98.12) ; P1.Y11 v2(140.89,96.12) ; P1.P11 v2(140.89,89.12) ; P1.Y19 v2(131.89,96.12)
  TOP w0.508: C306.1 145.85,33.36 ; C306.1 143.71,33.36 ; C306.1 145.85,31.23 ; C306.1 143.71,31.23 ; 134.57,33.36 C305.1 ; C305.1 134.57,31.23 ; C305.1 136.7,31.23 ; C305.1 136.7,33.36
  04_PWR1 w0.508: C305.1 136.44,33.1 ; C305.1 134.83,31.49 ; C305.1 134.83,33.1 ; C305.1 136.44,31.49 ; 143.97,33.1 C306.1 ; C306.1 145.59,31.49 ; C306.1 145.59,33.1 ; C306.1 143.97,31.49
  06_SIG2 w0.508: 143.97,33.1 C306.1 ; C306.1 143.97,31.49 ; C306.1 145.59,33.1 ; C306.1 145.59,31.49 ; 134.83,33.1 C305.1 ; C305.1 136.44,33.1 ; C305.1 136.44,31.49 ; C305.1 134.83,31.49
  BOTTOM w0.254: C516.1 139.89,91.12 v2(139.89,91.12)
  BOTTOM w0.381: C504.1 P1.W20 v2(131.89,94.12) ; C478.1 P1.Y11 v2(140.89,96.12) ; C482.1 139.39,96.62 v2(139.89,96.12) ; C533.1 v2(125.89,92.12) ; C527.1 P1.T23 v2(128.89,92.12) ; C503.1 132.38,94.63 v2(131.89,95.12) ; C525.1 P1.T21 v2(130.89,92.12) ; v2(136.89,95.12) 136.39,94.63 C499.1 P1.W15 v2(136.89,94.12) ; v2(140.89,92.12) 141.39,91.62 C515.1 ; v2(137.89,88.12) 137.89,88.13 C565.1 137.89,89.12 v2(137.89,89.12) ; v2(130.89,91.12) 131.38,91.61 C524.1 ; v2(128.89,95.12) 129.38,94.63 C506.1 ; C489.1 P1.Y24 v2(126.89,95.12) ; v2(139.89,89.12) 140.38,88.63 C563.1 140.39,88.63 v2(140.89,89.12) ; v2(137.89,90.12) P1.R13 C552.1 ; v2(131.89,91.12) 132.38,91.61 C523.1 ; C520.1 136.39,91.62 v2(135.89,92.12) ; v2(128.89,94.12) 128.39,94.62 C507.1 ; C622.1 165.53,31.37 C311.1 ; v2(129.89,96.12) 129.39,95.63 C488.1 P1.Y22 v2(128.89,96.12) ; v2(137.89,98.12) P1.AB14 C461.1 ; v2(126.89,91.12) 127.38,91.61 C528.1 P1.T24 v2(127.89,92.12) ; v2(125.89,91.12) 126.38,91.61 C529.1 ; C568.1 P1.N16 v2(134.89,88.12) P1.N17 C569.1 ; v2(129.89,98.12) 130.38,98.61 C453.1 130.39,98.61 v2(130.89,98.12) ; C562.1 128.39,87.62 v2(128.89,88.12) ; C518.1 138.38,91.61 v2(137.89,91.12) ; C519.1 137.39,91.62 v2(136.89,92.12) ; v2(132.89,90.12) P1.R19 v2(131.89,90.12) ; v2(126.89,96.12) 127.4,96.63 C474.1 127.33,96.68 v2(126.89,97.12) ; C480.1 134.39,95.61 v2(134.89,95.12) ; C509.1 126.39,94.62 v2(126.89,94.12) ; C508.1 P1.W24 v2(127.89,94.12) ; v2(125.89,98.12) 126.38,98.61 C455.1 ; C491.1 P1.Y21 v2(130.89,95.12) ; v2(136.89,88.12) 136.89,88.13 C566.1 ; C501.1 P1.W17 v2(134.89,94.12) ; C502.1 133.39,94.62 v2(132.89,94.12) ; v2(138.89,97.12) 138.39,97.61 C460.1 P1.AB13 v2(138.89,98.12) ; v2(132.89,99.12) 132.39,99.62 C446.1 131.9,100.12 R422.2 ; C522.1 134.39,91.62 v2(134.89,92.12) ; C550.1 P1.P17 v2(134.89,90.12) ; v2(126.89,88.12) 126.39,87.63 C577.1 ; C471.1 131.39,96.61 v2(131.89,96.12) ; v2(126.89,89.12) P1.N25 C560.1 126.38,88.63 v2(125.89,89.12) ; v2(138.89,96.12) P1.AA13 ; P1.AA13 v2(137.89,96.12) ; P1.AA13 C483.1 ; C526.1 129.39,91.62 v2(129.89,92.12) ; C554.1 126.39,90.62 v2(126.89,90.12) ; v2(134.89,98.12) 134.39,98.61 C452.1 ; C546.1 P1.P12 v2(138.89,90.12) ; C495.1 140.38,94.63 v2(139.89,95.12) ; v2(139.89,98.12) 140.39,98.62 C463.1 ; C543.1 v2(127.89,90.12) ; P1.N12 C564.1 ; P1.N12 v2(139.89,88.12) ; P1.N12 v2(138.89,88.12) ; C517.1 139.39,91.62 v2(138.89,92.12) ; C497.1 138.39,94.62 v2(138.89,94.12) ; v2(128.89,99.12) 129.38,99.61 C444.1 ; v2(131.89,88.12) P1.N19 C571.1 ; C578.1 v2(127.89,88.12) ; C516.1 P1.T11 v2(139.89,92.12) ; v2(127.89,98.12) 128.38,98.62 C457.1 ; C570.1 P1.N18 v2(132.89,88.12) ; v2(127.89,96.12) 128.38,96.62 C475.1 128.38,96.63 v2(127.89,97.12) ; C500.1 135.39,94.63 v2(135.89,95.12) ; v2(136.89,98.12) P1.AB15 C462.1 136.38,97.61 v2(135.89,97.12) ; v2(125.89,88.12) 125.39,88.62 C575.1 ; C486.1 133.38,96.63 v2(132.89,97.12) ; v2(129.89,95.12) 130.38,94.63 C505.1 P1.W21 v2(130.89,94.12) ; C567.1 135.89,88.13 v2(135.89,88.12) ; C479.1 P1.Y16 v2(135.89,96.12) ; v2(132.89,98.12) 132.39,98.62 C456.1 ; C469.1 132.38,97.62 v2(131.89,97.12) ; v2(129.89,90.12) 129.89,90.14 C544.1 130.37,90.64 v2(129.89,91.12) ; C545.1 P1.P11 v2(139.89,90.12) ; v2(140.89,97.12) 141.38,96.63 C481.1 ; C454.1 127.38,98.61 v2(126.89,98.12) P1.AB24 C466.1 ; P1.P22 v2(128.89,90.12) ; v2(137.89,94.12) P1.W14 C498.1 137.39,94.63 v2(137.89,95.12) ; v2(128.89,89.12) 129.38,88.63 C574.1 ; v2(140.89,90.12) 141.39,90.62 C551.1 ; C496.1 P1.W12 v2(139.89,94.12) ; C494.1 141.38,94.63 v2(140.89,95.12) ; C514.1 v2(132.89,92.12) ; R425.1 135.39,98.61 v2(135.89,98.12) ; v2(135.89,90.12) 135.39,89.62 C549.1 134.89,89.12 v2(134.89,89.12) ; v2(127.89,91.12) P1.R24
  BOTTOM w0.508: C306.1 145.85,31.23 ; C306.1 143.71,31.23 ; C306.1 145.85,33.36 ; C306.1 143.71,33.36 ; 134.57,31.23 C305.1 ; C305.1 136.7,31.23 ; C305.1 136.7,33.36 ; C305.1 134.57,33.36
  vias: v1(134.75,36) v1(134.75,34.86) v1(134.75,33.72) v1(135.89,36) v1(135.89,34.86) v1(135.89,33.72) v1(137.03,36) v1(137.03,34.86) v1(137.03,33.72) v1(138.18,36) v1(138.18,34.86) v1(138.18,33.72) v1(139.32,36) v1(139.32,34.86) v1(139.32,33.72) v1(140.46,36) v1(140.46,34.86) v1(140.46,33.72) v1(141.6,36) v1(141.6,34.86) v1(141.6,33.72) v1(142.75,36) v1(142.75,34.86) v1(142.75,33.72) v1(143.89,36) v1(143.89,34.86) v1(143.89,33.72) v1(145.03,36) v1(145.03,34.86) v1(145.03,33.72) v1(146.18,36) v1(146.18,34.86) v1(146.18,33.72) v1(147.32,36) v1(147.32,34.86) v1(147.32,33.72) v1(148.46,36) v1(148.46,34.86) v1(148.46,33.72) v1(149.61,36) v1(149.61,34.86) v1(149.61,33.72) v1(149.61,32.58) v1(150.75,36) v1(150.75,34.86) v1(150.75,33.72) v1(150.75,32.58) v1(151.89,36) v1(151.89,34.86) v1(151.89,33.72) v1(151.89,32.58) v1(153.03,36) v1(153.03,34.86) v1(153.03,33.72) v1(153.03,32.58) v1(154.18,36) v1(154.18,34.86) v1(154.18,33.72) v1(154.18,32.58) v1(155.32,36) v1(155.32,34.86) v1(155.32,33.72) v1(155.32,32.58) v1(156.46,36) v1(156.46,34.86) v1(156.46,33.72) v1(156.46,32.58)
VCC_D1V8: length 8.5
  TOP w0.356: P1.T18 v2(132.89,91.12) ; P1.L26 v2(124.89,86.12) ; P1.W26 v2(124.89,95.12) ; P1.AC26 v2(124.89,98.12) ; P1.T16 v2(135.89,91.12) ; P1.R26 v2(124.89,90.12)
  BOTTOM w0.381: v2(124.89,98.12) 124.39,98.62 C458.1 ; C553.1 133.38,90.63 v2(132.89,91.12) ; C476.1 v2(124.89,95.12) ; C558.1 v2(124.89,90.12) ; C581.1 124.39,86.62 v2(124.89,86.12) ; v2(135.89,91.12) 135.39,91.61 C521.1
  vias: v1(186.69,40.89) v1(186.69,39.88) v1(187.71,40.89) v1(187.71,39.88) v1(188.72,40.89) v1(188.72,39.88) v1(189.87,40.89) v1(189.87,39.88) v1(191.01,40.89) v1(192.15,40.89) v1(193.14,40.96) v1(194.28,40.96) v2(123.83,93.09) v2(124.97,93.09)
VCC_DDR3: length 468.7
  TOP w0.279: U34.2 182.74,73.59 183.26,74.1 v1(183.26,74.49) ; v1(120.9,142.43) 120.52,142.43 120.01,142.95 U5.2 ; U14.2 183.9,120.34 183.39,119.82 v1(183.39,119.32)
  TOP w0.356: P1.AF12 v2(138.89,101.12) ; P1.AE10 v2(140.89,101.12)
  TOP w0.381: v3(170.43,126.28) C93.1 171.18,126.27 U16.H9 ; v3(176.38,141.52) C19.1 177.16,139.41 U8.R9 ; U11.D2 v3(122.69,126.62) ; U10.H9 98.97,130.22 C61.1 v3(98.95,129.48) ; U16.K8 v3(173.18,123.39) ; v3(168.78,126.28) C92.1 169.55,125.29 168.78,124.52 U16.E9 ; v2(143.89,95.12) P1.W8 ; U22.C1 166.75,101.72 C151.1 v3(165.99,99.65) ; U22.H9 171.18,111.03 C137.1 v3(170.43,111.04) ; R195.1 v1(184.2,69.86) ; v3(174.78,126.41) C87.1 175.64,124.25 U16.N9 ; U11.N9 116.22,134.68 C52.1 v3(114.19,133.82) ; v3(176.38,99.65) C154.1 177.16,101.76 U22.R1 ; v3(169.98,106.55) U22.G7 ; U28.R9 177.16,92.42 C170.1 v3(176.38,94.53) ; U40.D9 167.98,64.01 C239.1 v3(167.26,64.05) ; v3(168.4,67.9) C234.1 169.16,69.98 U32.F1 ; v3(129.43,129.48) C63.1 129.45,130.22 U12.H9 ; v3(176.38,130.13) C73.1 177.16,132.24 U8.R1 ; v3(101.82,122.11) 101.85,122.11 101.87,122.13 C108.1 101.87,124.24 U10.A8 ; U11.R1 123.48,136.21 C40.1 v3(125.59,135.42) ; U11.G7 v3(117.89,129.02) ; U40.N9 175.64,62.02 C242.1 v3(174.78,64.05) ; v3(176.38,52.66) C279.1 177.16,54.77 U40.R1 ; v3(174.78,94.53) C169.1 175.64,92.5 U28.N9 ; U10.R1 108.24,136.21 C38.1 v3(110.35,135.42) ; U40.D2 v3(167.58,55.56) ; U12.R9 131.54,136.21 C41.1 v3(129.43,135.42) ; U10.H2 v3(107.45,129.82) ; R38.1 v1(116.28,141.49) ; v2(143.89,100.12) P1.AD8 ; v3(176.38,126.28) C94.1 177.16,124.17 U16.R9 ; U28.D9 167.98,94.49 C166.1 v3(167.26,94.53) ; v3(140.83,123.51) C105.1 138.68,124.27 U12.A1 ; v2(142.89,92.12) P1.U9 ; U32.K8 v3(173.18,76.4) ; v3(98.95,127.83) C77.1 99.95,128.59 100.72,127.82 U10.E9 ; v3(110.35,133.82) C51.1 108.31,134.68 U10.N1 ; v3(167.26,126.28) C91.1 167.98,126.24 U16.D9 ; U22.R9 177.16,108.93 C139.1 v3(176.38,111.04) ; v3(174.78,141.52) C18.1 175.64,139.49 U8.N9 ; v3(174.78,52.66) C278.1 175.64,54.69 U40.N1 ; U11.K2 v3(122.69,132.22) ; v3(165.99,52.66) C276.1 166.75,54.73 U40.C1 ; v3(165.99,83.14) C207.1 166.75,85.21 U28.C1 ; v3(174.78,83.14) C209.1 175.64,85.17 U28.N1 ; v3(174.78,130.13) C72.1 175.64,132.16 U8.N1 ; v3(168.78,141.52) C16.1 169.55,140.53 168.78,139.76 U8.E9 ; v3(140.83,135.45) C42.1 138.72,136.21 U12.R1 ; U28.E9 168.78,92.77 169.55,93.54 C167.1 v3(168.78,94.53) ; v3(165.74,64.05) C238.1 166.5,63.06 167.18,62.38 U40.C9 ; v3(176.38,64.05) C243.1 177.16,61.94 U40.R9 ; v3(176.38,67.9) C236.1 177.16,70.01 U32.R1 ; U11.C9 115.87,126.22 115.19,125.54 C100.1 v3(114.19,124.78) ; U32.K2 v3(173.18,70.8) ; U10.R9 101.06,136.21 C37.1 v3(98.95,135.42) ; U8.A1 165.23,132.28 C69.1 v3(164.47,130.13) ; U12.C9 131.11,126.22 130.43,125.54 C101.1 v3(129.43,124.78) ; v3(125.59,133.82) C53.1 123.55,134.68 U11.N1 ; v2(144.89,97.12) P1.AA7 ; U32.N1 175.64,69.93 C235.1 v3(174.78,67.9) ; U12.K2 v3(137.93,132.22) ; v3(176.38,114.89) C129.1 177.16,117 U16.R1 ; U22.D9 167.98,111 C135.1 v3(167.26,111.04) ; v3(165.99,114.89) C126.1 166.75,116.96 U16.C1 ; U12.C1 138.75,125.79 C98.1 v3(140.83,125.03) ; v3(132.33,122.11) 132.35,122.13 C110.1 132.35,124.24 U12.A8 ; v3(169.98,60.36) 169.98,60.36 U40.G7 ; v3(168.4,130.13) C71.1 169.16,132.21 U8.F1 ; U10.C1 108.27,125.79 C96.1 v3(110.35,125.03) ; U16.K2 v3(173.18,117.79) ; U28.R1 177.16,85.25 C210.1 v3(176.38,83.14) ; U40.A1 165.23,54.81 C275.1 v3(164.47,52.66) ; v3(165.74,126.28) C90.1 166.5,125.29 167.18,124.61 U16.C9 ; U12.N9 131.46,134.68 C54.1 v3(129.43,133.82) ; v3(110.35,127.44) C81.1 108.26,128.21 U10.F1 ; U40.E9 168.78,62.29 169.55,63.06 C240.1 v3(168.78,64.05) ; v3(98.95,126.3) C84.1 98.99,127.02 U10.D9 ; v3(125.59,123.51) C104.1 123.44,124.27 U11.A1 ; U16.A8 165.2,123.36 C107.1 163.09,123.36 v3(163.07,123.39) ; U22.N1 175.64,101.68 C153.1 v3(174.78,99.65) ; v2(128.89,82.12) P1.F22 ; v3(168.78,111.04) C136.1 169.55,110.05 168.78,109.28 U22.E9 ; U22.D2 v3(167.58,102.55) ; v3(174.78,79.29) C219.1 175.64,77.26 U32.N9 ; U8.G7 v3(169.98,137.83) ; v3(168.4,114.89) C127.1 169.16,116.97 U16.F1 ; U28.D2 v3(167.58,86.04) ; v3(170.43,94.53) C168.1 171.18,94.52 U28.H9 ; U11.C1 123.51,125.79 C97.1 v3(125.59,125.03) ; v2(142.89,89.12) P1.P8 ; v3(114.19,126.3) C85.1 114.23,127.02 U11.D9 ; U10.B2 v3(107.45,125.02) ; U22.A8 165.2,108.12 C142.1 163.12,108.12 163.08,108.16 v3(163.07,108.16) ; U28.B2 v3(165.98,86.04) ; v3(125.59,127.44) C82.1 123.5,128.21 U11.F1 ; v2(145.89,99.12) P1.AC6 ; U32.G7 v3(169.98,75.6) ; v3(165.74,141.52) C14.1 166.5,140.53 167.18,139.85 U8.C9 ; v3(174.78,111.04) C138.1 175.64,109.01 U22.N9 ; U16.D2 v3(167.58,117.79) ; U12.F1 138.74,128.21 C83.1 v3(140.83,127.44) ; U10.A1 108.2,124.27 C103.1 v3(110.35,123.51) ; U10.G7 v3(102.65,129.02) ; v3(165.99,130.13) C70.1 166.75,132.2 U8.C1 ; v3(163.07,76.37) C223.1 165.2,76.37 U32.A8 ; U22.H2 v3(170.78,102.55) ; v3(167.26,141.52) C15.1 167.98,141.48 U8.D9 ; v3(129.43,126.3) C86.1 129.47,127.02 U12.D9 ; U8.K2 v3(173.18,133.03) ; U12.N1 138.79,134.68 C55.1 v3(140.83,133.92) ; C102.1 195.9,123.95 196.22,123.63 208.28,123.63 209.17,124.52 C74.1 208.06,128.95 R55.2 ; U12.K8 v3(132.33,132.22) ; v3(163.07,138.63) 163.09,138.6 C31.1 165.2,138.6 U8.A8 ; U8.B2 v3(165.98,133.03) ; v3(163.07,91.61) C175.1 165.2,91.61 U28.A8 ; U22.A1 165.23,101.8 C150.1 v3(164.47,99.65) ; U11.E9 115.96,127.82 115.19,128.59 C78.1 v3(114.19,127.83) ; U22.K2 v3(173.18,102.55) ; U28.A1 165.23,85.29 C206.1 v3(164.47,83.14) ; U16.G7 v3(169.98,122.59) ; U10.K8 v3(101.85,132.22) ; U11.H2 v3(122.69,129.82) ; U32.B2 v3(165.98,70.8) ; U11.B2 v3(122.69,125.02) ; U16.N1 175.64,116.92 C128.1 v3(174.78,114.89) ; U32.R9 177.16,77.18 C220.1 v3(176.38,79.29) ; U32.D2 v3(167.58,70.8) ; U12.H2 v3(137.93,129.82) ; v3(164.47,67.9) C232.1 165.23,70.05 U32.A1 ; v3(114.19,135.42) C39.1 116.3,136.21 U11.R9 ; U28.F1 169.16,85.22 C208.1 v3(168.4,83.14) ; U32.H2 v3(170.78,70.8) ; U40.H2 v3(170.78,55.56) ; v3(170.43,79.29) C218.1 171.18,79.28 U32.H9 ; U16.A1 165.23,117.04 C125.1 v3(164.47,114.89) ; v3(165.74,94.53) C165.1 166.5,93.54 167.18,92.86 U28.C9 ; v2(144.89,91.12) P1.T7 ; U40.K2 v3(173.18,55.56) ; P1.AG9 v2(142.89,102.12) ; U40.K8 v3(173.18,61.16) ; v3(165.99,67.9) C233.1 166.75,69.97 U32.C1 ; U32.E9 168.78,77.53 169.55,78.3 C217.1 v3(168.78,79.29) ; v3(98.95,124.78) C99.1 99.95,125.54 100.63,126.22 U10.C9 ; U28.H2 v3(170.78,86.04) ; U32.C9 167.18,77.62 166.5,78.3 C215.1 v3(165.74,79.29) ; U22.K8 v3(173.18,108.15) ; U32.D9 167.98,79.25 C216.1 v3(167.26,79.29) ; U11.K8 v3(117.09,132.22) ; U11.A8 117.11,124.24 C109.1 117.11,122.13 v3(117.09,122.11) ; P1.J23 v2(127.89,84.12) ; U40.H9 171.18,64.04 C241.1 v3(170.43,64.05) ; U16.H2 v3(170.78,117.79) ; U28.K2 v3(173.18,86.04) ; U28.G7 v3(169.98,90.84) ; v3(163.07,61.13) C255.1 165.2,61.13 U40.A8 ; v3(170.43,141.52) C17.1 171.18,141.51 U8.H9 ; v3(168.4,52.66) C277.1 169.16,54.74 U40.F1 ; U8.H2 v3(170.78,133.03) ; U10.K2 v3(107.45,132.22) ; v3(129.43,127.83) C79.1 130.43,128.59 131.2,127.82 U12.E9 ; U22.B2 v3(165.98,102.55) ; U16.B2 v3(165.98,117.79) ; v2(127.89,105.12) P1.AJ23 ; U10.D2 v3(107.45,126.62) ; v2(126.89,103.12) P1.AG24 ; v3(165.74,111.04) C134.1 166.5,110.05 167.18,109.37 U22.C9 ; P1.G24 v2(126.89,82.12) ; U10.N9 100.98,134.68 C50.1 v3(98.95,133.82) ; v3(114.19,129.48) C62.1 114.21,130.22 U11.H9 ; v2(142.89,98.12) P1.AB9 ; U40.B2 v3(165.98,55.56) ; U12.G7 v3(133.13,129.02) ; U22.F1 169.16,101.73 C152.1 v3(168.4,99.65) ; v2(125.89,101.12) P1.AE25 ; U28.K8 v3(173.18,91.64) ; R64.1 v1(182.43,124.07) ; U12.B2 v3(137.93,125.02) ; v2(146.89,96.12) P1.Y5 ; U12.D2 v3(137.93,126.62) ; U8.D2 v3(167.58,133.03) ; U8.K8 v3(173.18,138.63)
  TOP w0.508: 193.91,146.86 C7.1 ; C7.1 193.91,144.73 ; C7.1 196.04,146.86 ; C7.1 196.04,144.73
  05_PWR2 w0.508: 194.17,146.6 C7.1 ; C7.1 194.17,144.99 ; C7.1 195.78,146.6 ; C7.1 195.78,144.99
  BOTTOM w0.381: C439.1 126.38,100.63 v2(125.89,101.12) ; v2(127.89,105.12) 127.39,104.62 C423.1 ; v2(143.89,95.12) 144.38,94.63 C493.1 ; C437.1 143.39,100.62 v2(143.89,100.12) ; v2(144.89,97.12) 145.38,97.62 C468.1 ; C534.1 144.39,90.63 v2(144.89,91.12) ; C442.1 145.39,99.61 v2(145.89,99.12) 146.38,99.61 C441.1 ; v2(142.89,92.12) 142.39,91.63 C532.1 ; C451.1 142.39,98.61 v2(142.89,98.12) ; v2(128.89,82.12) 128.45,82.56 128.45,83.55 C591.1 ; C433.1 143.38,101.63 v2(142.89,102.12) ; C438.1 P1.AE10 v2(140.89,101.12) ; C592.1 v2(126.89,82.12) ; v2(126.89,103.12) 126.4,102.64 C430.1 ; C436.1 P1.AF12 v2(138.89,101.12) ; v2(127.89,84.12) P1.J23 v2(127.89,85.12) ; C576.1 v2(142.89,89.12)
  BOTTOM w0.508: C7.1 196.04,144.73 ; C7.1 196.04,146.86 ; C7.1 193.91,144.73 ; C7.1 193.91,146.86
  vias: v1(121.92,142.43) v1(122.94,142.43) v1(123.95,142.43) v1(183.26,77.53) v1(183.26,76.52) v1(183.26,75.5) v1(183.39,118.3) v1(183.39,117.28) v1(183.39,116.27) v1(193.75,143.07) v1(193.75,141.92) v1(193.75,140.78) v1(193.75,139.64) v1(193.75,138.49) v1(193.75,137.35) v1(193.75,129.73) v1(193.75,128.59) v1(193.75,127.44) v1(193.75,126.3) v1(193.75,125.16) v1(194.89,143.07) v1(194.89,141.92) v1(194.89,140.78) v1(194.89,139.64) v1(194.89,138.49) v1(194.89,137.35) v1(194.89,129.73) v1(194.89,128.59) v1(194.89,127.44) v1(194.89,126.3) v1(194.89,125.16) v1(196.09,143.07) v1(196.09,141.92) v2(136.89,85.12) v2(137.89,85.12) v2(138.89,85.12)
VCC_IO3V0: length 25.4
  TOP w0.279: U42.2 44.5,50.41 v1(44.37,50.53) ; U31.2 44.5,78.35 v1(44.37,78.47) ; U55.2 44.5,22.47 v1(44.37,22.59) ; U21.2 44.5,106.29 v1(44.37,106.41)
  TOP w0.33: v1(29.31,151.02) 29.19,150.89 U2.2
  TOP w0.381: R210.1 v1(25.96,66.28) ; R292.1 v1(47.8,25.14) ; R233.1 v1(47.8,53.08) ; R242.1 47.57,49.67 v1(47.88,49.97) ; R164.1 v1(47.8,81.02) ; R105.1 v1(47.8,105.55) ; R172.1 v1(47.8,77.61) ; R96.1 v1(47.8,108.96) ; R77.1 v1(25.96,122.16) ; R137.1 v1(25.96,94.22) ; R7.1 v1(21.72,156.78) ; R300.1 v1(47.8,21.73) ; R273.1 v1(25.96,38.34) ; R11.1 v1(29.29,155.44)
  BOTTOM w0.381: v1(21.72,156.78) 23.37,155.13 28.99,155.13 v1(29.29,155.44)
VCCIO_D1V8: length 75.2
  TOP w0.254: C385.1 176.39,19.2 R307.2 v1(175.45,19.24)
  TOP w0.356: P1.AD14 v2(137.89,100.12) ; P1.P20 v2(130.89,89.12) ; P1.P16 v2(135.89,89.12) ; P1.P15 v2(136.89,89.12) ; P1.AA14 v2(137.89,97.12) ; P1.AK15 v2(135.89,106.12) ; P1.P21 v2(129.89,89.12) ; P1.P19 v2(131.89,89.12) ; P1.AD15 v2(136.89,100.12) ; P1.AA15 v2(136.89,97.12) ; P1.AA21 v2(129.89,97.12) ; P1.AH16 v2(134.89,104.12) ; P1.AD16 v2(135.89,100.12) ; P1.AA20 v2(130.89,97.12)
  TOP w0.381: P1.AF17 v2(134.89,102.12) ; U6.B4 v1(152.76,142.31)
  TOP w0.508: C307.1 194.36,31.23 ; C307.1 194.36,33.36 ; C307.1 192.23,33.36 ; C307.1 192.23,31.23 ; R15.1 v1(158.6,146.84) ; R43.1 154.03,135.61 v1(154.56,136.14) ; R41.2 v1(151.48,134.78)
  04_PWR1 w0.508: J4.4 155.75,151.66 ; J4.4 154.14,151.66 ; J4.4 155.75,153.28 ; J4.4 154.14,153.28 ; C307.1 194.1,31.49 ; C307.1 194.1,33.1 ; C307.1 192.49,31.49 ; C307.1 192.49,33.1
  BOTTOM w0.254: R406.1 v1(145.54,142.56)
  BOTTOM w0.33: R400.2 140.59,109.28 140.25,109.62 139.39,109.62 v2(138.89,109.12) ; R398.2 R401.2 138.37,107.61 v2(137.89,107.12)
  BOTTOM w0.381: R416.1 132.88,102.12 v2(132.89,102.12) ; C443.1 P1.AD15 v2(135.89,100.12) ; R420.2 138.38,100.61 v2(137.89,100.12) 138.38,99.63 C450.1 ; R413.2 138.37,103.64 v2(137.89,104.12) ; P1.AD14 v2(136.89,100.12) ; C548.1 136.38,89.61 v2(135.89,89.12) ; v2(137.89,97.12) 137.39,96.63 C484.1 ; 185.93,30.92 184.78,30.92 179.58,25.72 179.58,21.27 177.55,19.24 v1(175.45,19.24) ; C485.1 136.39,96.63 v2(136.89,97.12) ; C473.1 130.39,97.62 v2(130.89,97.12) ; v2(129.89,89.12) 130.38,88.63 C573.1 ; v2(136.89,106.12) 136.91,106.1 R410.2 ; C547.1 137.38,89.61 v2(136.89,89.12) ; v2(130.89,89.12) 131.38,88.63 C572.1 ; C555.1 131.4,89.61 v2(131.89,89.12) ; v2(134.89,104.12) 134.39,103.62 C425.1 ; v2(135.89,106.12) C421.1 ; R408.1 132.48,105.53 v2(132.89,105.12) ; C429.1 v2(134.89,102.12) ; C465.1 v2(129.89,97.12)
  BOTTOM w0.508: C307.1 194.36,31.23 ; C307.1 194.36,33.36 ; C307.1 192.23,31.23 ; C307.1 192.23,33.36
  vias: v1(185.37,34.99) v1(185.37,33.98) v1(186.52,34.99) v1(186.52,33.98) v1(187.66,34.99) v1(187.66,33.98) v1(188.8,34.99) v1(188.8,33.98) v1(190.07,34.99) v1(190.07,33.98) v1(191.22,34.99) v1(191.22,33.98) v1(192.36,34.99) v1(192.36,33.98) v1(193.5,34.99) v1(193.5,33.98) v2(129.89,101.12) v2(132.89,104.12) v2(134.89,103.12) v2(135.89,105.12) v2(135.89,102.12)
VCCIO_D3V0: length 367.6
  TOP w0.381: P1.G19 v2(131.89,82.12) ; 209.42,31.81 210.31,30.92 210.31,27.19 209.93,26.81 R285.2 ; P1.F17 v2(134.89,81.12) ; R2.1 v1(16.49,162.98) ; P1.J18 v2(132.89,84.12)
  TOP w0.508: v1(16.51,17.34) R316.1 R325.1 ; v1(16.51,11.11) R326.1 R327.1
  06_SIG2 w0.381: v1(16.49,162.98) 14.3,160.79 14.3,19.55 v1(16.51,17.34) v1(16.51,11.11) 17.91,11.11 21.97,15.18 147.45,15.18 148.21,14.41 183.64,14.41 200.79,31.56 v1(205.1,31.56)
  BOTTOM w0.381: C594.1 135.39,80.62 v2(134.89,81.12) ; C595.1 v2(131.89,82.12) ; C585.1 v2(132.89,84.12)
  vias: v1(205.1,32.58) v1(206.25,32.58) v1(206.25,31.56) v1(207.39,32.58) v1(207.39,31.56) v1(208.53,32.58) v1(208.53,31.56)
VCCIO_EN: length 121.2
  TOP w0.127: U43.30 211.89,49.97 R237.1 210.31,51.55 v1(210.31,51.75) 209.17,51.75 208.91,52.01 208.91,58.61 212.98,62.67 v1(212.98,132.96)
  TOP w0.254: U9.15 206.71,133.29 v1(207.03,132.96) ; U50.1 v1(206.82,30.48)
  BOTTOM w0.127: v1(210.31,51.75) 209.93,51.37 209.93,32.07 208.34,30.48 v1(206.82,30.48)
  BOTTOM w0.254: v1(207.03,132.96) 207.04,132.96 v1(212.98,132.96)
VCCR_D1V0: length 48
  TOP w0.381: C322.1 105.72,31.37 105.33,30.97 105.33,18.81 106.05,18.1 C384.1 109.55,18.13 R306.2 ; P1.N28 v2(122.89,88.12) ; P1.AE27 v2(124.89,100.12) ; P1.U27 v2(123.89,92.12) ; P1.U28 v2(122.89,92.12) ; P1.AA27 v2(123.89,97.12) ; P1.AA28 v2(122.89,97.12) ; P1.N27 v2(123.89,88.12) ; P1.AE28 v2(123.89,101.12)
  TOP w0.508: C304.1 127.43,33.36 ; C304.1 125.3,31.23 ; C304.1 127.43,31.23 ; C304.1 125.3,33.36
  04_PWR1 w0.508: C304.1 127.17,31.49 ; C304.1 127.17,33.1 ; C304.1 125.56,33.1 ; C304.1 125.56,31.49
  BOTTOM w0.381: C470.1 124.38,97.62 v2(123.89,97.12) ; v2(122.89,92.12) P1.U28 C512.1 ; C513.1 124.38,92.62 v2(123.89,92.12) ; v2(124.89,100.12) P1.AE27 C434.1 124.38,100.63 v2(123.89,101.12) 124.38,101.62 C432.1 ; C561.1 P1.N28 v2(123.89,88.12) ; C559.1 122.39,88.61 v2(122.89,88.12) ; C467.1 123.39,97.62 v2(122.89,97.12)
  BOTTOM w0.508: C304.1 127.43,31.23 ; C304.1 127.43,33.36 ; C304.1 125.3,31.23 ; C304.1 125.3,33.36
  vias: v1(106.93,33.52) v1(106.93,32.37) v1(108.08,33.52) v1(108.08,32.37) v1(109.22,33.52) v1(109.22,32.37) v1(110.36,33.52) v1(110.36,32.37) v1(117.98,33.52) v1(117.98,32.37) v1(119.13,33.52) v1(119.13,32.37) v1(120.27,33.52) v1(120.27,32.37) v1(121.41,33.52) v1(121.41,32.37) v1(122.56,33.52) v1(122.56,32.37) v1(123.7,33.52) v1(123.7,32.37)
VCCT_D1V0: length 11.4
  TOP w0.381: P1.L28 v2(122.89,86.12) ; P1.L27 v2(123.89,86.12) ; P1.AC27 v2(123.89,99.12) ; P1.AC28 v2(122.89,99.12) ; P1.W27 v2(123.89,95.12) ; P1.W28 v2(122.89,95.12) ; v2(123.89,90.12) P1.R27 ; v2(122.89,90.12) P1.R28
  BOTTOM w0.102: P1.L28 C582.1
  BOTTOM w0.381: C449.1 124.38,99.62 v2(123.89,99.12) ; C447.1 122.89,99.12 v2(122.89,99.12) ; C583.1 122.39,86.62 v2(122.89,86.12) ; v2(122.89,95.12) 123.39,95.62 C490.1 ; P1.R27 v2(123.89,90.12) ; v2(122.89,90.12) P1.R28 C535.1 ; C477.1 v2(123.89,95.12) ; v2(123.89,86.12) P1.L28
  vias: v1(108.08,38.93) v1(109.22,38.93) v1(110.36,38.93) v1(111.51,38.93) v1(112.65,38.93) v1(113.79,38.93)
VDD_PLL1: length 17.3
  TOP w0.254: U39.11 137.87,59.36 139.96,61.46 C256.1 ; U39.16 135.01,63.03 C248.1 ; U39.15 135.5,62.91 C249.1
  TOP w0.279: C258.1 131.73,59.36 U39.20
  TOP w0.381: C256.1 140.01,61.98 v1(139.7,62.29) ; v1(136.27,62.55) 136.27,62.91 C249.1 ; C248.1 134.24,62.78 v1(134.24,62.55) ; C258.1 130.83,60.77 v1(131.44,60.77) ; R222.2 v1(141.99,57.72)
  vias: v1(131.44,61.79)
VDD_PLL2: length 14.4
  TOP w0.254: U26.11 84.85,93.9 84.58,94.17
  TOP w0.279: C180.1 81.17,91.13 U26.16 ; 84.58,88.33 84.85,88.59 U26.20 ; C176.1 81.3,91.63 U26.15
  TOP w0.381: 84.58,88.33 84.58,88.28 v1(83.82,87.52) ; v1(83.08,95.68) C159.1 83.88,94.87 84.58,94.17 ; v1(81.66,90.36) 81.42,90.36 C180.1 ; v1(81.66,92.52) 81.42,92.52 C176.1 ; R119.2 87.31,97.35 v1(87.12,97.54)
  vias: v1(82.68,87.52)
25MHZ-1: length 1.6
  TOP w0.127: R229.1 139.97,53.32 Y3.3
25MHZ-2: length 1.6
  TOP w0.127: Y1.3 91.56,96.89 R118.1
5338_SCL1: length 85.7
  TOP w0.127: v1(138.05,60.26) 137.65,59.86 U39.12 ; U43.35 211.87,47.47 v1(211.71,47.31) R249.1
  06_SIG2 w0.127: v1(138.05,60.26) 141.94,60.26 156.41,45.78 206.63,45.78 208.91,48.07 210.95,48.07 v1(211.71,47.31)
5338_SCL2: length 174.6
  TOP w0.127: U26.12 84.35,93.66 v1(83.1,94.91) ; U43.45 220.07,43.79 R255.1 218.82,42.54 v1(218.82,40.2)
  06_SIG2 w0.127: v1(83.1,94.91) 83.19,94.83 83.19,80.58 119.06,44.7 209.11,44.7 213.61,40.2 v1(218.82,40.2)
5338_SDA1: length 91.5
  TOP w0.127: U43.36 212.51,46.97 v1(211.71,46.16) R250.1 ; v1(132.33,60.26) 132.74,59.86 U39.19
  06_SIG2 w0.127: v1(132.33,60.26) 137.16,60.26 137.67,59.75 141.94,59.75 156.29,45.4 206.96,45.4 208.36,46.8 211.07,46.8 v1(211.71,46.16)
5338_SDA2: length 166.4
  TOP w0.127: U43.46 220.57,43.45 R256.1 220.29,42.61 v1(220.15,42.61) ; U26.19 84.35,88.98 83.95,88.58 v1(83.69,88.58)
  06_SIG2 w0.127: v1(83.69,88.58) 84.45,87.82 84.45,79.95 119.38,45.02 209.55,45.02 214,40.58 218.12,40.58 v1(220.15,42.61)
A1_1: length 3.1
  TOP w0.127: U19.27 v1(28.61,117.25)
  BOTTOM w0.127: R384.2 27.99,116.64 v1(28.61,117.25) 29.16,116.7 R383.1
A1_2: length 3.1
  TOP w0.127: U29.27 v1(28.61,89.31)
  BOTTOM w0.127: R440.1 29.16,88.76 v1(28.61,89.31) 27.99,88.7 R441.2
A1_3: length 3.1
  TOP w0.127: U37.27 v1(28.61,61.37)
  BOTTOM w0.127: R464.1 29.16,60.82 v1(28.61,61.37) 27.99,60.76 R465.2
A1_4: length 3.1
  TOP w0.127: U48.27 v1(28.61,33.43)
  BOTTOM w0.127: R478.2 27.99,32.82 v1(28.61,33.43) 29.16,32.88 R477.1
A_SPI_CLK: length 10.6
  TOP w0.127: U43.15 220.57,55.28 222.38,57.09 222.38,60.01 221.49,60.9 U38.6 219.02,60.9 R216.1
A_SPI_CS: length 12.6
  TOP w0.127: U43.14 221.07,55.02 224.41,58.36 U38.1 228.67,58.21 R224.1
A_SPI_DI: length 11.4
  TOP w0.127: U38.5 218.82,62.17 217.55,60.9 217.55,57.34 219.57,55.32 U43.17
A_SPI_DO: length 12
  TOP w0.127: U43.16 v1(220.07,56.05) ; U38.2 v1(226.95,59.63)
  BOTTOM w0.127: v1(226.95,59.63) 223.65,59.63 v1(220.07,56.05)
AD1: length 3.9
  TOP w0.127: P1.AH17 v2(133.89,104.12)
  BOTTOM w0.102: v2(133.89,104.12) 133.42,104.58 132.26,104.58 R408.2 R409.2
AD2: length 4.1
  TOP w0.127: P1.AG17 v2(133.89,103.12)
  BOTTOM w0.102: R417.2 R416.2 132.53,103.7 133.31,103.7 v2(133.89,103.12)
ARM_GPIO0: length 4.4
  TOP w0.127: U43.40 217.57,44.79 217.3,44.51 215.85,44.51 R696.2
ARM_GPIO1: length 3.9
  TOP w0.127: R698.2 216.66,44.13 217.68,44.13 218.07,44.53 U43.41
ARM_GPIO2: length 3.3
  TOP w0.127: U43.42 218.57,44.39 217.93,43.75 217.45,43.75 R697.2
ARM_NRST: length 18.3
  TOP w0.127: U43.7 v1(221.87,49.97)
  BOTTOM w0.127: J11.1 227.9,49.97 v1(221.87,49.97) 221.87,49.97 C611.1 220.91,51.11 R474.2
ARM_PWS0: length 112.9
  TOP w0.127: R708.1 244.22,152.92 244.22,149.92 216.04,121.75 216.04,56.94 218.07,54.92 U43.20
ARM_PWS1: length 111.5
  TOP w0.127: R709.1 244.6,152.12 244.6,149.54 216.54,121.48 216.54,57.08 218.57,55.05 U43.19
ARM_PWS2: length 110.2
  TOP w0.127: U43.18 219.07,55.19 217.04,57.21 217.04,121.22 245.27,149.45 R710.1
ARM_SPI_CLK: length 5.4
  TOP w0.127: U43.26 213.78,51.97 213.11,52.64 213.11,55.03 R693.2
ARM_SPI_DI: length 6.8
  TOP w0.127: U43.28 213.51,50.97 211.73,52.74 R694.2
ARM_SPI_DO: length 6.1
  TOP w0.127: R695.2 212.47,55.53 212.47,52.64 213.64,51.47 U43.27
ARM_SPI_NSS: length 4.8
  TOP w0.127: R691.2 213.61,54.39 213.61,52.9 214.04,52.47 U43.25
AS_DATA0: length 37.4
  TOP w0.127: P1.AJ11 v2(140.89,105.12)
  06_SIG2 w0.127: v2(140.89,105.12) 141.45,105.69 141.45,115.02 143.6,117.17 143.6,129.57 150.5,136.46 v1(150.5,136.84)
  BOTTOM w0.127: v1(150.5,136.84) R703.2
AS_DATA1: length 35.7
  TOP w0.127: v2(139.89,106.12) P1.AK12
  06_SIG2 w0.127: v2(139.89,106.12) 139.89,106.42 140.31,106.85 140.31,115.46 142.49,117.64 142.49,130.31 147.96,135.78 v1(147.96,136.84)
  BOTTOM w0.127: v1(147.96,136.84) R704.2
AS_DATA2: length 35.9
  TOP w0.127: P1.AK11 v2(140.89,106.12)
  06_SIG2 w0.127: v2(140.89,106.12) 141.07,106.31 141.07,115.15 143.24,117.32 143.24,129.84 149.35,135.95 v1(149.35,136.84)
  BOTTOM w0.127: v1(149.35,136.84) R705.2
AS_DATA3: length 40.4
  TOP w0.127: v2(136.89,102.12) P1.AF15
  06_SIG2 w0.127: v1(146.18,136.84) 146.18,136.32 139.85,130 139.85,117.79 138.99,116.93 138.99,113.2 137.36,111.57 137.36,102.6 v2(136.89,102.12)
  BOTTOM w0.127: R706.2 146.18,137.42 v1(146.18,136.84)
CLK_USR: length 2.8
  TOP w0.127: R154.1 85.85,86.99 U26.22
CLKUSR: length 82.5
  TOP w0.127: P1.AK16 134.89,106.12 134.89,110.16 133.35,111.7 v1(87.76,111.7) ; v1(84.96,84.82) C196.2 86.07,85.64 R154.2
  06_SIG2 w0.127: v1(84.96,84.82) 87.76,87.62 v1(87.76,111.7)
CONF_DONE: length 1.4
  TOP w0.127: P1.AM12 v2(138.89,107.12)
  BOTTOM w0.102: P1.AM12 v2(138.89,107.12)
CONN_RCK+: length 3.5
  TOP w0.114: C174.1 81.33,93.57 81.5,93.57 82.85,92.22 83.23,92.22 83.32,92.13 U26.14
CONN_RCK-: length 3.5
  TOP w0.114: U26.13 83.32,92.63 83.23,92.54 82.98,92.54 81.63,93.88 81.33,93.88 C172.1
CONN_TX+0: length 226.1
  TOP w0.114: v1(110.01,69.78) 110.31,70.08 110.31,73.54 115.22,78.46 117.22,78.46 P1.C34
  BOTTOM w0.114: v1(110.01,69.78) 110.31,69.48 110.31,68.5 131.44,47.37 176.37,47.37 216.41,87.41 216.41,117.78 246.38,147.75 251.94,147.75 252.36,148.17 252.36,148.59 JT1.C3
CONN_TX+1: length 230.9
  TOP w0.114: v1(108.01,71.84) 108.31,72.13 108.31,73.95 114.81,80.46 117.22,80.46 P1.E34
  BOTTOM w0.114: JT1.C4 252.36,146.09 252.36,145.67 251.94,145.25 246.38,145.25 217.93,116.81 217.93,86.78 177.38,46.23 130.42,46.23 108.31,68.35 108.31,71.54 v1(108.01,71.84)
CONN_TX+2: length 236.1
  TOP w0.114: v1(106.01,69.78) 106.31,70.08 106.31,74.43 114.33,82.46 117.22,82.46 P1.G34
  BOTTOM w0.114: JT1.C5 252.36,143.59 252.36,143.17 251.94,142.75 246.38,142.75 219.46,115.83 219.46,86.15 178.14,44.83 129.66,44.83 106.31,68.19 106.31,69.48 v1(106.01,69.78)
CONN_TX+3: length 241.2
  TOP w0.114: v1(104.01,71.84) 104.31,72.13 104.31,74.85 113.91,84.46 117.22,84.46 P1.J34
  BOTTOM w0.114: v1(104.01,71.84) 104.31,71.54 104.31,68.03 128.9,43.43 178.89,43.43 221.11,85.65 221.11,114.98 246.38,140.25 251.94,140.25 252.36,140.67 252.36,141.09 JT1.C6
CONN_TX+4: length 246.2
  TOP w0.114: P1.L34 117.22,86.45 113.57,86.45 102.31,75.19 102.31,70.08 v1(102.01,69.78)
  BOTTOM w0.114: v1(102.01,69.78) 102.31,69.48 102.31,67.87 128.14,42.04 179.65,42.04 222.63,85.02 222.63,114 246.38,137.75 251.94,137.75 252.36,138.17 252.36,138.59 JT1.C7
CONN_TX+5: length 251.3
  TOP w0.114: v1(100.01,71.84) 100.31,72.13 100.31,75.61 113.16,88.45 117.22,88.45 P1.N34
  BOTTOM w0.114: JT1.C8 252.36,136.09 252.36,135.67 251.94,135.25 246.38,135.25 224.16,113.03 224.16,84.38 180.41,40.64 127.38,40.64 100.31,67.71 100.31,71.54 v1(100.01,71.84)
CONN_TX+6: length 256.4
  TOP w0.114: P1.R34 117.22,90.45 112.74,90.45 98.31,76.02 98.31,70.08 v1(98.01,69.78)
  BOTTOM w0.114: v1(98.01,69.78) 98.31,69.48 98.31,67.55 126.61,39.24 181.17,39.24 225.68,83.75 225.68,112.05 246.38,132.75 251.94,132.75 252.36,133.17 252.36,133.59 JT1.C9
CONN_TX+7: length 261.2
  TOP w0.114: P1.U34 117.22,92.46 112.33,92.46 96.31,76.43 96.31,72.13 v1(96.01,71.84)
  BOTTOM w0.114: JT1.C10 252.36,131.09 252.36,130.67 251.94,130.25 246.38,130.25 227.2,111.08 227.2,83.12 181.93,37.85 126.23,37.85 96.31,67.77 96.31,71.54 v1(96.01,71.84)
CONN_TX-0: length 226.1
  TOP w0.114: v1(110.92,69.78) 110.62,70.08 110.62,73.41 115.35,78.14 117.9,78.14 P1.C33
  BOTTOM w0.114: JT1.D3 252.04,148.59 252.04,148.3 251.81,148.07 248.02,148.07 arc(247.86,148.13) 247.8,148.29 arc(247.74,148.44) 247.59,148.5 247.56,148.5 arc(247.41,148.44) 247.34,148.29 arc(247.28,148.13) 247.13,148.07 246.25,148.07 216.09,117.91 216.09,87.54 176.23,47.69 131.57,47.69 110.62,68.64 110.62,69.48 v1(110.92,69.78)
CONN_TX-1: length 231
  TOP w0.114: P1.E33 117.9,80.14 114.94,80.14 108.62,73.82 108.62,72.13 v1(108.92,71.84)
  BOTTOM w0.114: JT1.D4 252.04,146.09 252.04,145.8 251.81,145.57 248.02,145.57 arc(247.86,145.63) 247.8,145.79 arc(247.74,145.94) 247.59,146 247.56,146 arc(247.41,145.94) 247.34,145.79 arc(247.28,145.63) 247.13,145.57 246.25,145.57 217.61,116.94 217.61,86.91 177.25,46.55 130.56,46.55 108.62,68.48 108.62,71.54 v1(108.92,71.84)
CONN_TX-2: length 236.1
  TOP w0.114: P1.G33 117.9,82.14 114.46,82.14 106.62,74.3 106.62,70.08 v1(106.92,69.78)
  BOTTOM w0.114: v1(106.92,69.78) 106.62,69.48 106.62,68.32 129.79,45.15 178,45.15 219.14,86.28 219.14,115.96 246.25,143.07 247.13,143.07 arc(247.28,143.13) 247.34,143.29 arc(247.41,143.44) 247.56,143.5 247.59,143.5 arc(247.74,143.44) 247.8,143.29 arc(247.86,143.13) 248.02,143.07 251.81,143.07 252.04,143.3 252.04,143.59 JT1.D5
CONN_TX-3: length 241.2
  TOP w0.114: P1.J33 117.9,84.14 114.05,84.14 104.62,74.72 104.62,72.13 v1(104.92,71.84)
  BOTTOM w0.114: JT1.D6 252.04,141.09 252.04,140.8 251.81,140.57 248.02,140.57 arc(247.86,140.63) 247.8,140.79 arc(247.74,140.94) 247.59,141 247.56,141 arc(247.41,140.94) 247.34,140.79 arc(247.28,140.63) 247.13,140.57 246.25,140.57 220.79,115.11 220.79,85.78 178.76,43.75 129.03,43.75 104.62,68.16 104.62,71.54 v1(104.92,71.84)
CONN_TX-4: length 246.2
  TOP w0.114: v1(102.92,69.78) 102.62,70.08 102.62,75.06 113.7,86.14 117.9,86.14 P1.L33
  BOTTOM w0.114: v1(102.92,69.78) 102.62,69.48 102.62,68 128.27,42.35 179.52,42.35 222.31,85.15 222.31,114.14 246.25,138.07 247.13,138.07 arc(247.28,138.13) 247.34,138.29 arc(247.41,138.44) 247.56,138.5 247.59,138.5 arc(247.74,138.44) 247.8,138.29 arc(247.86,138.13) 248.02,138.07 251.81,138.07 252.04,138.3 252.04,138.59 JT1.D7
CONN_TX-5: length 251.3
  TOP w0.114: P1.N33 117.9,88.14 113.29,88.14 100.62,75.47 100.62,72.13 v1(100.92,71.84)
  BOTTOM w0.114: JT1.D8 252.04,136.09 252.04,135.8 251.81,135.57 248.02,135.57 arc(247.86,135.63) 247.8,135.79 arc(247.74,135.94) 247.59,136 247.56,136 arc(247.41,135.94) 247.34,135.79 arc(247.28,135.63) 247.13,135.57 246.25,135.57 223.84,113.16 223.84,84.52 180.28,40.96 127.51,40.96 100.62,67.84 100.62,71.54 v1(100.92,71.84)
CONN_TX-6: length 256.4
  TOP w0.114: v1(98.92,69.78) 98.62,70.08 98.62,75.89 112.88,90.14 117.9,90.14 P1.R33
  BOTTOM w0.114: JT1.D9 252.04,133.59 252.04,133.3 251.81,133.07 248.02,133.07 arc(247.86,133.13) 247.8,133.29 arc(247.74,133.44) 247.59,133.5 247.56,133.5 arc(247.41,133.44) 247.34,133.29 arc(247.28,133.13) 247.13,133.07 246.25,133.07 225.36,112.18 225.36,83.88 181.04,39.56 126.75,39.56 98.62,67.68 98.62,69.48 v1(98.92,69.78)
CONN_TX-7: length 261.3
  TOP w0.114: P1.U33 117.9,92.14 112.46,92.14 96.62,76.3 96.62,72.13 v1(96.92,71.84)
  BOTTOM w0.114: v1(96.92,71.84) 96.62,71.54 96.62,67.9 126.37,38.16 181.8,38.16 226.89,83.25 226.89,111.21 246.25,130.57 247.13,130.57 arc(247.28,130.63) 247.34,130.79 arc(247.41,130.94) 247.56,131 247.59,131 arc(247.74,130.94) 247.8,130.79 arc(247.86,130.63) 248.02,130.57 251.81,130.57 252.04,130.8 252.04,131.09 JT1.D10
CONN_TX_RCK+: length 48.2
  TOP w0.114: C174.2 79.45,93.57 79.06,93.57 v1(78.74,93.25) ; v2(122.89,94.12) P1.V28
  BOTTOM w0.102: v2(122.89,94.12) 123.35,94.12 123.45,94.22 123.45,94.43 123.37,94.51 117.41,94.51 117.37,94.47 117.34,94.47
  BOTTOM w0.114: v1(78.74,93.25) 79.06,93.57 88.68,93.57 89.58,94.47 117.34,94.47
CONN_TX_RCK-: length 48.2
  TOP w0.114: C172.2 79.45,93.88 79.06,93.88 v1(78.74,94.2) ; v2(123.89,94.12) P1.V27
  BOTTOM w0.102: 117.34,94.79 117.37,94.79 117.41,94.74 123.46,94.74 123.68,94.53 123.68,94.22 123.78,94.12 v2(123.89,94.12)
  BOTTOM w0.114: v1(78.74,94.2) 79.06,93.88 88.55,93.88 89.45,94.79 117.34,94.79
DCLK: length 35.6
  TOP w0.127: R42.1 152.62,134.78 v1(151.51,133.67) ; v2(141.89,105.12) P1.AJ10
  06_SIG2 w0.127: v2(141.89,105.12) 142.37,105.6 142.37,109.28 142.69,109.61 142.69,114.74 144.68,116.73 144.68,126.83 v1(151.51,133.67)
DCLK1: length 5.5
  TOP w0.127: U6.B2 152.62,140.18 R42.2 R41.1
DDR3_A_A0: length 158.2
  TOP w0.127: R35.2 135.51,138.95 135.51,134.64 v3(136.33,133.82) U12.N3 ; P1.H27 v2(123.89,84.12) ; U10.N3 v3(105.85,133.82) ; U11.N3 v3(121.09,133.82)
  06_SIG2 w0.127: v2(123.89,84.12) 122.37,85.64 118.77,85.64 117.69,86.72 117.69,89.66 116.09,91.26 arc(116.02,91.44) 116.09,91.62 116.66,92.19 arc(116.66,92.55) 116.3,92.55 115.73,91.98 arc(115.55,91.91) 115.37,91.98 114.99,92.37 arc(114.93,92.5) 114.99,92.63 arc(115.04,92.66) 115.09,92.67 115.63,92.67 arc(115.68,92.68) 115.72,92.69 115.76,92.7 arc(115.9,92.8) 115.95,92.97 arc(115.89,93.12) 115.75,93.19 115.72,93.2 arc(115.71,93.2) 115.7,93.2 114.25,93.2 arc(113.99,93.45) 114.25,93.71 115.52,93.71 arc(115.77,93.96) 115.52,94.21 113.23,94.21 arc(112.98,94.47) 113.23,94.72 115.48,94.72 arc(115.73,94.98) 115.48,95.23 113.23,95.23 arc(112.98,95.48) 113.23,95.74 115.47,95.74 arc(115.72,95.99) 115.47,96.25 114.6,96.25 arc(114.35,96.5) 114.6,96.75 115.47,96.75 arc(115.72,97.01) 115.47,97.26 114.6,97.26 arc(114.35,97.52) 114.6,97.77 115.47,97.77 arc(115.72,98.02) 115.47,98.28 114.6,98.28 arc(114.35,98.53) 114.6,98.79 115.47,98.79 arc(115.72,99.04) 115.47,99.29 114.6,99.29 arc(114.35,99.55) 114.6,99.8 115.47,99.8 arc(115.72,100.06) 115.47,100.31 114.6,100.31 arc(114.35,100.56) 114.6,100.82 115.47,100.82 arc(115.72,101.07) 115.47,101.33 114.6,101.33 arc(114.35,101.58) 114.6,101.83 115.47,101.83 arc(115.72,102.09) 115.47,102.34 113.16,102.34 arc(112.98,102.42) 112.9,102.6 arc(112.98,102.78) 113.16,102.86 115.47,102.86 arc(115.68,102.97) 115.71,103.2 arc(115.61,103.32) 115.47,103.37 113.16,103.37 arc(112.9,103.62) 113.16,103.87 114.6,103.87 arc(114.86,104.13) 114.6,104.38 113.16,104.38 arc(112.9,104.64) 113.16,104.89 113.84,104.89 arc(114.1,105.14) 113.84,105.4 113.16,105.4 arc(112.9,105.65) 113.16,105.91 113.84,105.91 arc(114.1,106.16) 113.84,106.41 113.16,106.41 arc(112.9,106.67) 113.16,106.92 113.84,106.92 arc(114.1,107.18) 113.84,107.43 113.16,107.43 arc(112.9,107.68) 113.16,107.94 113.84,107.94 arc(114.1,108.19) 113.84,108.45 113.16,108.45 arc(112.9,108.7) 113.16,108.95 113.84,108.95 arc(114.1,109.21) 113.84,109.46 113.16,109.46 arc(112.9,109.72) 113.16,109.97 113.84,109.97 arc(114.1,110.22) 113.84,110.48 113.2,110.48 arc(113.02,110.55) 112.95,110.72 112.95,111.21 112.8,111.37 111.51,111.37 110.46,112.41 110.46,115.46 112.65,117.64 112.65,129.3 112.12,129.83 110.06,129.83 108.13,131.76 107.35,131.76 105.85,133.26 v3(105.85,133.82) 106.07,133.82 106.46,133.43 117.87,133.43 118.26,133.82 118.66,133.82 arc(118.84,133.75) 118.92,133.57 118.92,133.49 arc(119.17,133.24) 119.42,133.49 119.42,133.57 arc(119.68,133.82) 119.93,133.57 119.93,133.49 arc(120.19,133.24) 120.44,133.49 120.44,133.57 arc(120.51,133.75) 120.69,133.82 v3(121.09,133.82) 121.49,133.42 135.93,133.42 v3(136.33,133.82)
DDR3_A_A1: length 156.8
  TOP w0.127: v3(133.13,135.42) U12.P7 134.37,135.86 134.37,139.2 R32.2 ; U11.P7 v3(117.89,135.42) ; U10.P7 v3(102.65,135.42) ; P1.G27 v2(123.89,83.12)
  03_SIG1 w0.102: v2(123.89,83.12) 123.51,82.74 117.7,82.74 117.63,82.81 117.5,82.81
  03_SIG1 w0.127: 117.5,82.81 116.72,82.81 113.16,86.37 113.16,94.88 arc(113.09,95.04) 112.94,95.1 arc(112.83,95.08) 112.74,95.02 112.42,94.7 arc(112.22,94.62) 112.02,94.7 arc(111.94,94.88) 112.02,95.06 112.95,95.99 arc(112.95,96.35) 112.59,96.35 111.66,95.42 arc(111.3,95.42) 111.3,95.78 112.23,96.71 arc(112.23,97.06) 111.87,97.06 110.94,96.14 arc(110.58,96.14) 110.58,96.5 111.51,97.42 arc(111.51,97.78) 111.15,97.78 110.22,96.85 arc(109.86,96.85) 109.86,97.21 110.79,98.14 arc(110.79,98.5) 110.43,98.5 109.5,97.57 arc(109.14,97.57) 109.14,97.93 110.07,98.86 arc(110.07,99.22) 109.71,99.22 108.79,98.29 arc(108.43,98.29) 108.43,98.65 109.35,99.58 arc(109.35,99.94) 109,99.94 108.07,99.01 arc(107.71,99.01) 107.71,99.37 108.64,100.3 arc(108.64,100.66) 108.28,100.66 107.35,99.73 arc(106.99,99.73) 106.99,100.09 107.92,101.02 arc(107.92,101.37) 107.56,101.37 106.63,100.45 arc(106.27,100.45) 106.27,100.81 107.2,101.73 arc(107.2,102.09) 106.84,102.09 105.91,101.17 arc(105.55,101.17) 105.55,101.52 106.48,102.45 arc(106.48,102.81) 106.12,102.81 105.19,101.88 arc(104.83,101.88) 104.83,102.24 105.76,103.17 arc(105.76,103.53) 105.4,103.53 104.47,102.6 arc(104.12,102.6) 104.12,102.96 105.04,103.89 arc(105.04,104.25) 104.68,104.25 103.76,103.32 arc(103.4,103.32) 103.4,103.68 104.33,104.61 arc(104.33,104.97) 103.97,104.97 103.04,104.04 arc(102.68,104.04) 102.68,104.4 103.61,105.33 arc(103.61,105.69) 103.25,105.69 102.35,104.79 arc(102.15,104.71) 101.96,104.79 arc(101.88,104.97) 101.96,105.14 102.84,106.03 arc(102.84,106.43) 102.45,106.43 102.16,106.14 arc(102.12,106.12) 102.07,106.11 arc(101.92,106.17) 101.85,106.33 101.85,113.12 99.19,115.79 99.19,124.4 99.44,124.65 99.44,133.67 100.8,135.03 102.25,135.03 v3(102.65,135.42)
  BOTTOM w0.127: v3(102.65,135.42) U10.P7 117.49,135.02 v3(117.89,135.42) U11.P7 132.73,135.02 v3(133.13,135.42)
DDR3_A_A2: length 153.2
  TOP w0.127: v3(137.13,135.42) U12.P3 135.89,135.86 135.89,138.19 R36.2 ; U11.P3 v3(121.89,135.42) ; P1.G23 v2(127.89,82.12) ; U10.P3 v3(106.65,135.42)
  03_SIG1 w0.102: v2(127.89,82.12) 127.51,81.74 127.51,78.8 127.21,78.5 117.7,78.5 117.63,78.43 117.5,78.43
  03_SIG1 w0.127: v3(137.13,135.42) U12.P3 122.29,135.02 v3(121.89,135.42) 120.88,135.42 arc(120.7,135.35) 120.62,135.17 120.62,135.06 arc(120.37,134.81) 120.12,135.06 120.12,135.17 arc(119.86,135.42) 119.61,135.17 119.61,135.06 arc(119.35,134.81) 119.1,135.06 119.1,135.17 arc(119.03,135.35) 118.85,135.42 118.57,135.42 118.17,135.02 107.05,135.02 v3(106.65,135.42) 105.97,135.42 105.03,136.36 105.03,137.22 103.61,138.65 98.58,138.65 95.89,135.95 95.89,115.59 98.35,113.12 98.35,108.83 98.17,108.65 97.97,108.65 arc(97.71,108.4) 97.97,108.14 98.5,108.14 arc(98.76,107.89) 98.5,107.63 97.97,107.63 arc(97.71,107.38) 97.97,107.13 98.5,107.13 arc(98.76,106.87) 98.5,106.62 97.97,106.62 arc(97.71,106.36) 97.97,106.11 98.5,106.11 arc(98.76,105.86) 98.5,105.6 97.97,105.6 arc(97.71,105.35) 97.97,105.09 98.5,105.09 arc(98.76,104.84) 98.5,104.59 97.97,104.59 arc(97.71,104.33) 97.97,104.08 98.5,104.08 arc(98.76,103.82) 98.5,103.57 97.97,103.57 arc(97.71,103.32) 97.97,103.06 98.5,103.06 arc(98.76,102.81) 98.5,102.55 97.97,102.55 arc(97.71,102.3) 97.97,102.05 98.5,102.05 arc(98.76,101.79) 98.5,101.54 97.97,101.54 arc(97.71,101.28) 97.97,101.03 98.5,101.03 arc(98.76,100.78) 98.5,100.52 97.97,100.52 arc(97.71,100.27) 97.97,100.01 98.5,100.01 arc(98.76,99.76) 98.5,99.51 97.97,99.51 arc(97.71,99.25) 97.97,99 98.5,99 arc(98.76,98.74) 98.5,98.49 97.97,98.49 arc(97.71,98.24) 97.97,97.98 98.61,97.98 arc(98.73,97.93) 98.78,97.81 98.78,96.61 116.96,78.43 117.5,78.43
DDR3_A_A3: length 153.7
  TOP w0.127: U10.N2 v3(107.45,134.62) ; U12.N2 v3(137.93,134.62) ; v2(127.89,83.12) 128.89,83.12 P1.G22 ; U11.N2 v3(122.69,134.62)
  03_SIG1 w0.102: v2(127.89,83.12) 127.27,82.5 127.27,78.94 127.07,78.74 117.7,78.74 117.63,78.81 117.5,78.81
  03_SIG1 w0.127: v3(137.93,134.62) U12.N2 123.09,134.22 v3(122.69,134.62) U11.N2 122.01,134.22 arc(121.83,134.29) 121.75,134.47 121.75,134.68 arc(121.5,134.94) 121.25,134.68 121.25,134.47 arc(121.17,134.29) 120.99,134.22 116.82,134.22 116.42,134.62 115.95,134.62 arc(115.77,134.54) 115.7,134.37 115.7,134.28 arc(115.44,134.02) 115.19,134.28 115.19,134.37 arc(115.11,134.54) 114.94,134.62 v3(107.45,134.62) 106.87,134.62 106.44,135.05 105.78,135.05 104.65,136.18 104.65,136.97 103.35,138.26 98.83,138.26 96.27,135.7 96.27,115.76 98.78,113.25 98.78,112.21 arc(98.87,111.99) 99.1,111.89 99.64,111.89 arc(99.9,111.64) 99.64,111.39 99.03,111.39 arc(98.78,111.13) 99.03,110.88 99.64,110.88 arc(99.9,110.62) 99.64,110.37 99.03,110.37 arc(98.78,110.12) 99.03,109.86 99.64,109.86 arc(99.9,109.61) 99.64,109.35 99.03,109.35 arc(98.78,109.1) 99.03,108.85 99.64,108.85 arc(99.9,108.59) 99.64,108.34 99.44,108.34 arc(99.19,108.08) 99.44,107.83 99.64,107.83 arc(99.9,107.58) 99.64,107.32 99.44,107.32 arc(99.19,107.07) 99.44,106.81 99.64,106.81 arc(99.9,106.56) 99.64,106.31 99.44,106.31 arc(99.19,106.05) 99.44,105.8 99.64,105.8 arc(99.9,105.54) 99.64,105.29 99.44,105.29 arc(99.19,105.04) 99.44,104.78 99.64,104.78 arc(99.9,104.53) 99.64,104.27 99.44,104.27 arc(99.19,104.02) 99.44,103.77 99.64,103.77 arc(99.9,103.51) 99.64,103.26 99.44,103.26 arc(99.19,103) 99.44,102.75 99.64,102.75 arc(99.9,102.5) 99.64,102.24 99.44,102.24 arc(99.19,101.99) 99.44,101.73 99.64,101.73 arc(99.9,101.48) 99.64,101.23 99.44,101.23 arc(99.19,100.97) 99.44,100.72 99.64,100.72 arc(99.9,100.46) 99.64,100.21 99.44,100.21 arc(99.19,99.96) 99.44,99.7 99.64,99.7 arc(99.9,99.45) 99.64,99.19 99.44,99.19 arc(99.19,98.94) 99.44,98.69 99.64,98.69 arc(99.9,98.43) 99.64,98.18 99.44,98.18 arc(99.26,98.1) 99.19,97.92 99.19,96.84 117.21,78.81 117.5,78.81
  BOTTOM w0.127: R358.2 136.65,140.09 136.65,135.32 137.35,134.62 v3(137.93,134.62)
DDR3_A_A4: length 159.5
  TOP w0.127: P1.H25 v2(125.89,83.12) ; U10.P8 v3(101.85,135.42) ; U12.P8 v3(132.33,135.42) ; U11.P8 v3(117.09,135.42)
  03_SIG1 w0.102: v2(125.89,83.12) 125.27,82.5 117.7,82.5 117.63,82.43 117.5,82.43
  03_SIG1 w0.127: v3(101.85,135.42) 101.44,135.83 99.65,135.83 arc(99.5,135.76) 99.44,135.61 99.44,135.3 99.76,134.98 arc(99.76,134.62) 99.4,134.62 99.24,134.79 arc(99.05,134.87) 98.86,134.79 98.42,134.35 98.42,133.49 arc(98.38,133.38) 98.27,133.34 98.09,133.34 arc(97.9,133.26) 97.82,133.06 arc(97.9,132.87) 98.09,132.79 98.78,132.79 arc(99.03,132.54) 98.78,132.28 98.58,132.28 arc(98.32,132.03) 98.58,131.78 98.78,131.78 arc(99.03,131.52) 98.78,131.27 98.12,131.27 arc(97.87,131.01) 98.12,130.76 98.78,130.76 arc(99.03,130.51) 98.78,130.25 98.68,130.25 arc(98.5,130.18) 98.42,130 98.42,124.38 arc(98.35,124.2) 98.17,124.13 98.09,124.13 arc(97.84,123.88) 98.09,123.62 98.55,123.62 arc(98.81,123.37) 98.55,123.11 98.09,123.11 arc(97.84,122.86) 98.09,122.61 98.55,122.61 arc(98.81,122.35) 98.55,122.1 98.09,122.1 arc(97.84,121.84) 98.09,121.59 98.55,121.59 arc(98.81,121.34) 98.55,121.08 98.09,121.08 arc(97.84,120.83) 98.09,120.57 98.55,120.57 arc(98.81,120.32) 98.55,120.07 98.09,120.07 arc(97.84,119.81) 98.09,119.56 98.55,119.56 arc(98.81,119.3) 98.55,119.05 98.09,119.05 arc(97.84,118.8) 98.09,118.54 98.55,118.54 arc(98.81,118.29) 98.55,118.03 98.09,118.03 arc(97.84,117.78) 98.09,117.53 98.48,117.53 arc(98.74,117.27) 98.48,117.02 98.09,117.02 arc(97.84,116.76) 98.09,116.51 98.42,116.51 arc(98.61,116.43) 98.69,116.24 98.69,115.8 arc(98.7,115.71) 98.76,115.63 101.47,112.92 101.47,104.51 arc(101.5,104.39) 101.56,104.29 101.99,103.87 arc(102.04,103.75) 101.99,103.63 101.56,103.2 arc(101.49,103.03) 101.56,102.86 arc(101.74,102.78) 101.92,102.86 102.35,103.29 arc(102.71,103.29) 102.71,102.93 102.23,102.45 arc(102.23,102.09) 102.59,102.09 103.07,102.57 arc(103.43,102.57) 103.43,102.22 103.02,101.8 arc(103.02,101.44) 103.38,101.44 103.79,101.86 arc(104.15,101.86) 104.15,101.5 103.73,101.08 arc(103.73,100.72) 104.09,100.72 104.51,101.14 arc(104.87,101.14) 104.87,100.78 104.45,100.36 arc(104.45,100) 104.81,100 105.23,100.42 arc(105.59,100.42) 105.59,100.06 105.17,99.64 arc(105.17,99.29) 105.53,99.29 105.95,99.7 arc(106.31,99.7) 106.31,99.34 105.89,98.93 arc(105.89,98.57) 106.25,98.57 106.66,98.98 arc(107.02,98.98) 107.02,98.62 106.61,98.21 arc(106.61,97.85) 106.97,97.85 107.38,98.26 arc(107.74,98.26) 107.74,97.91 107.33,97.49 arc(107.33,97.13) 107.69,97.13 108.1,97.55 arc(108.46,97.55) 108.46,97.19 108.05,96.77 arc(108.05,96.41) 108.4,96.41 108.82,96.83 arc(109.18,96.83) 109.18,96.47 108.76,96.05 arc(108.76,95.69) 109.12,95.69 109.54,96.11 arc(109.9,96.11) 109.9,95.75 109.48,95.33 arc(109.48,94.98) 109.84,94.98 110.26,95.39 arc(110.62,95.39) 110.62,95.03 110.2,94.62 arc(110.2,94.26) 110.56,94.26 110.98,94.67 arc(111.33,94.67) 111.33,94.31 110.92,93.9 arc(110.92,93.54) 111.28,93.54 111.69,93.95 arc(112.05,93.95) 112.05,93.59 111.64,93.18 arc(111.64,92.82) 112,92.82 112.32,93.15 arc(112.68,93.15) 112.68,92.79 112.33,92.43 arc(112.26,92.28) 112.33,92.13 112.65,91.81 arc(112.72,91.7) 112.75,91.56 112.75,86.14 116.46,82.43 117.5,82.43
  BOTTOM w0.127: v3(101.85,135.42) 102.25,135.82 116.69,135.82 v3(117.09,135.42) 117.49,135.82 131.93,135.82 v3(132.33,135.42) 132.74,135.83 132.74,135.83 133.35,135.83 133.6,136.08 133.6,137.17 132.79,137.99 131.01,137.99 R365.2
DDR3_A_A5: length 157.4
  TOP w0.127: U12.P2 v3(137.93,135.42) ; U10.P2 v3(107.45,135.42) ; U11.P2 v3(122.69,135.42) ; P1.G25 v2(126.89,83.12)
  03_SIG1 w0.102: 115.75,78.88 116.89,77.74 128.05,77.74 128.27,77.96 128.27,83.38 128.02,83.62 127.39,83.62 v2(126.89,83.12)
  03_SIG1 w0.127: v3(137.93,135.42) 137.53,135.82 123.09,135.82 v3(122.69,135.42) 122.29,135.82 115.7,135.82 arc(115.53,135.89) 115.45,136.07 115.45,136.18 arc(115.2,136.44) 114.94,136.18 114.94,136.07 arc(114.69,135.82) 114.43,136.07 114.43,136.18 arc(114.18,136.44) 113.93,136.18 113.93,136.07 arc(113.85,135.89) 113.67,135.82 107.85,135.82 v3(107.45,135.42) 107.04,135.83 106.13,135.83 105.41,136.54 105.41,137.48 103.86,139.03 98.32,139.03 95.5,136.21 95.5,114.08 arc(95.58,113.9) 95.76,113.83 96.81,113.83 arc(97.06,113.58) 96.81,113.32 95.76,113.32 arc(95.5,113.07) 95.76,112.81 97.61,112.81 arc(97.87,112.56) 97.61,112.31 95.76,112.31 arc(95.5,112.05) 95.76,111.8 97.61,111.8 arc(97.87,111.54) 97.61,111.29 95.76,111.29 arc(95.5,111.04) 95.76,110.78 97.61,110.78 arc(97.87,110.53) 97.61,110.27 95.78,110.27 arc(95.54,110.03) 95.78,109.79 96.67,109.79 96.8,109.66 96.8,108.93 97.23,108.5 97.23,97.4 115.75,78.88
  BOTTOM w0.127: v3(137.93,135.42) 137.53,135.81 137.53,139.83 R357.2
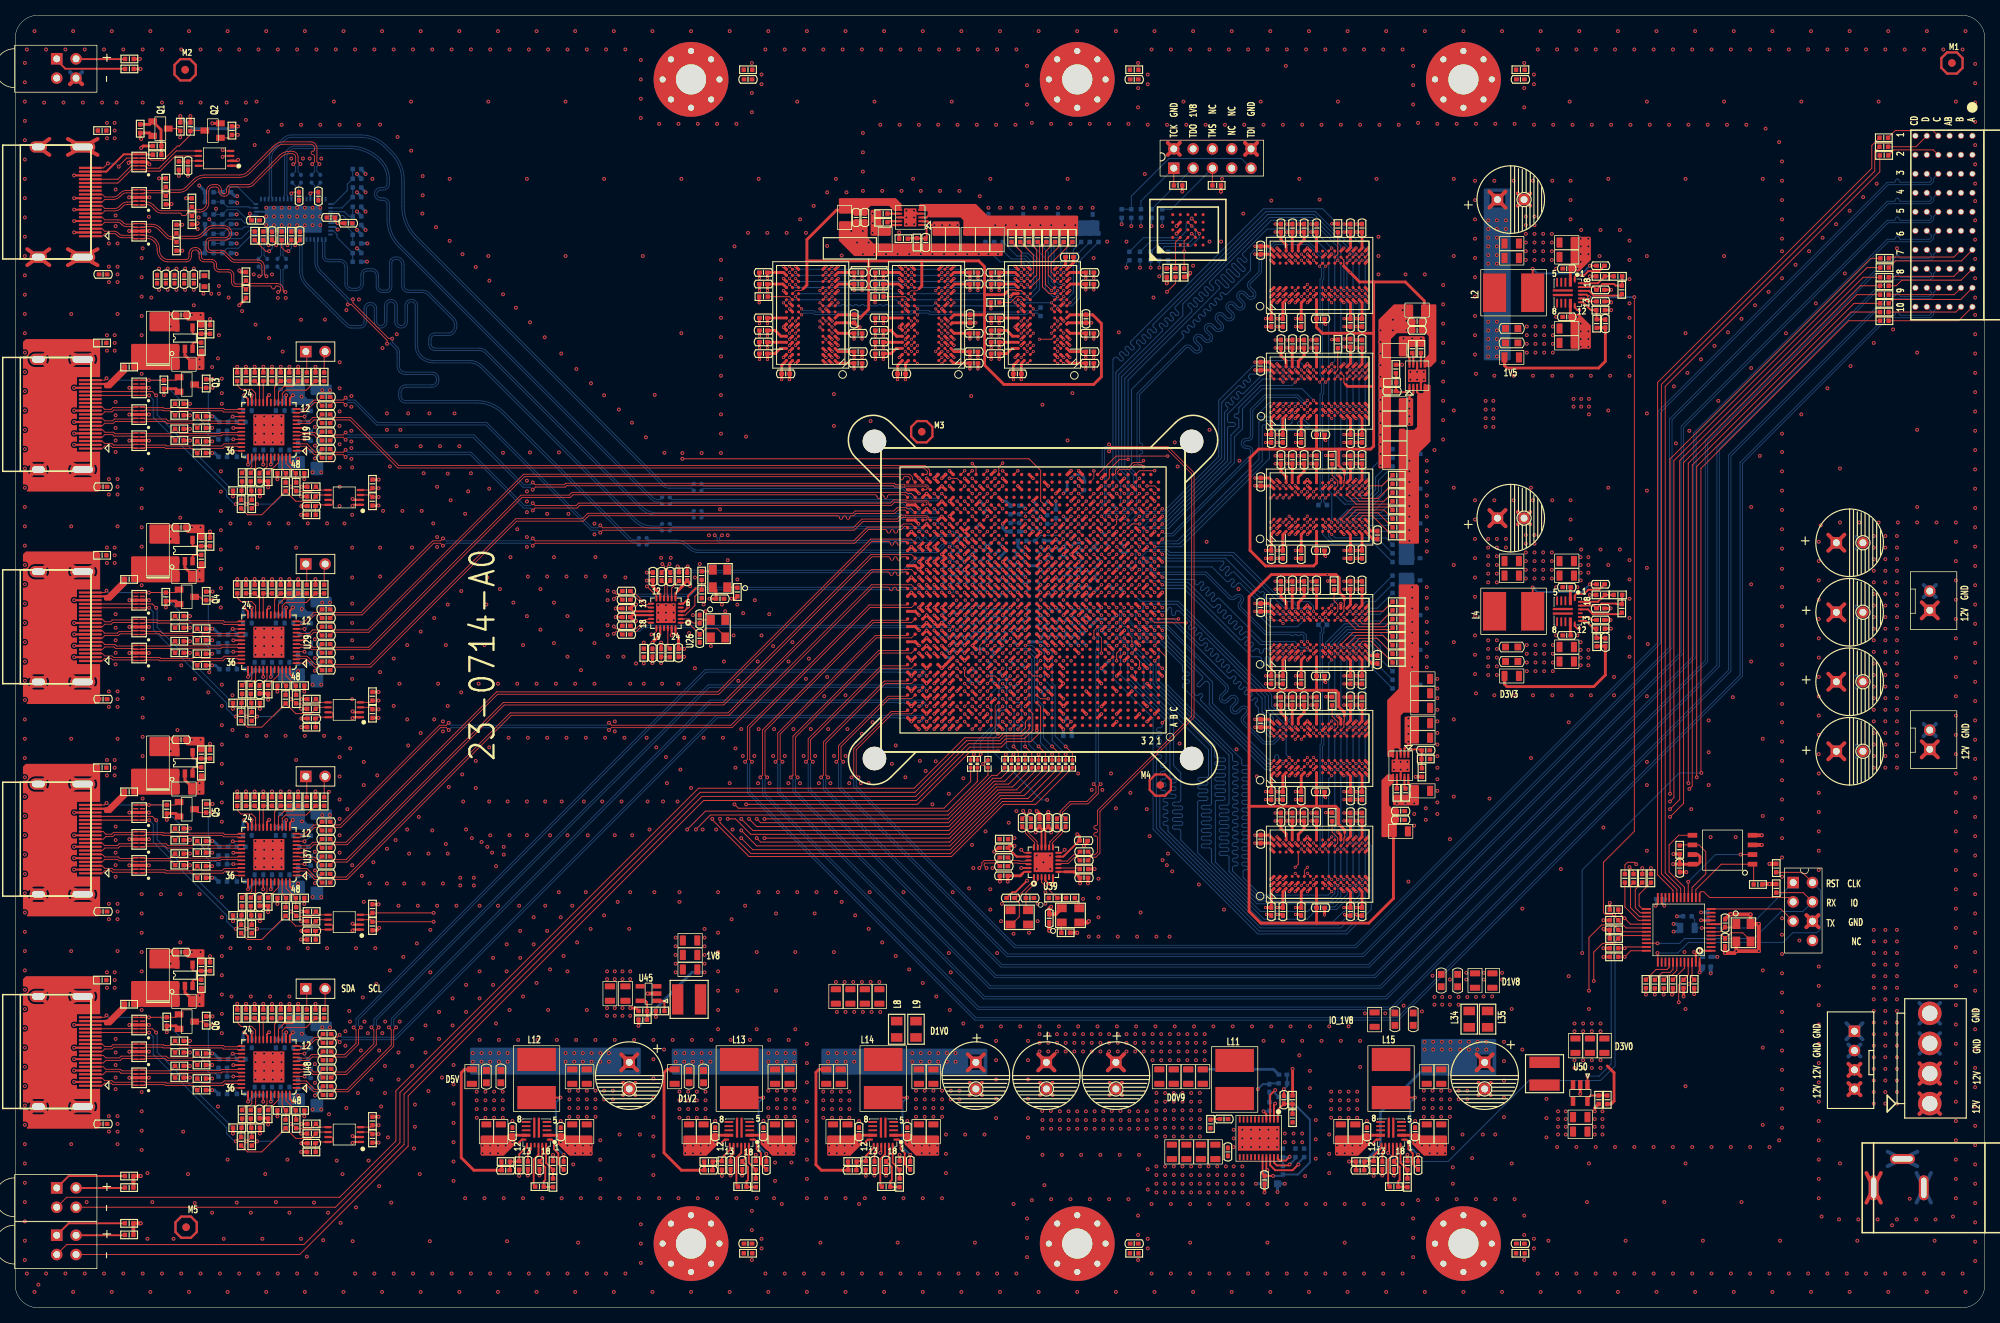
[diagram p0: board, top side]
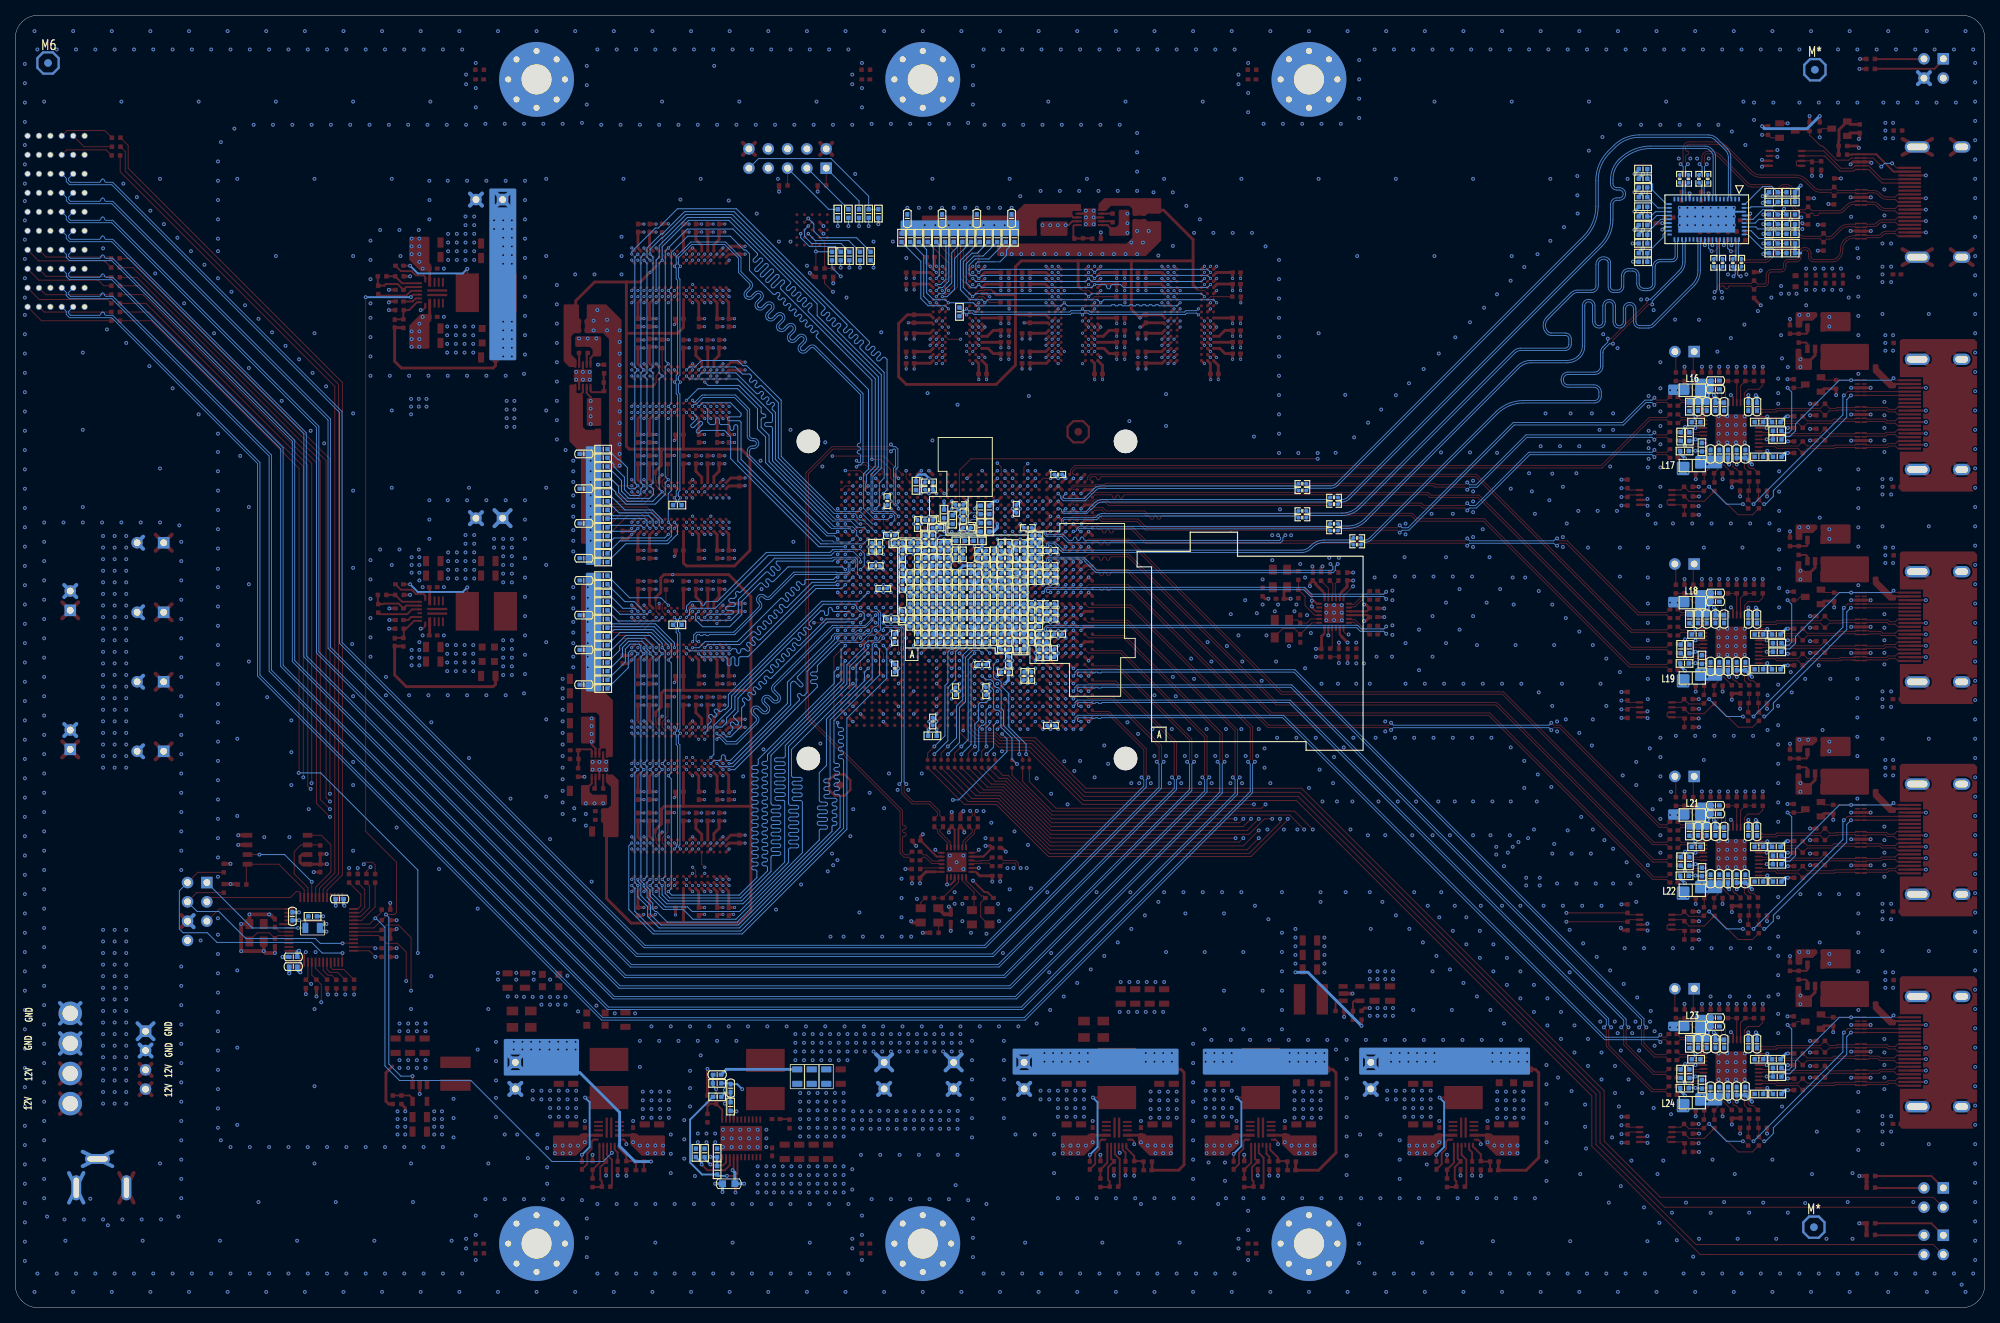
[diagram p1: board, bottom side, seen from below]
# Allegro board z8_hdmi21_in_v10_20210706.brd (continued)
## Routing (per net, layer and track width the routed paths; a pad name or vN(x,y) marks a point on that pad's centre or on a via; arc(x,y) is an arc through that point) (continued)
DDR3_A_A6: length 159.1
  TOP w0.127: P1.H24 v2(126.89,84.12) ; U12.R8 v3(132.33,136.22) ; U10.R8 v3(101.85,136.22) ; U11.R8 v3(117.09,136.22)
  03_SIG1 w0.102: v2(126.89,84.12) 126.51,83.74 117.7,83.74 117.63,83.81 117.5,83.81
  03_SIG1 w0.127: v3(101.85,136.22) 102.24,135.83 102.87,135.83 103.12,135.57 103.12,134.74 arc(103.2,134.56) 103.38,134.49 104.27,134.49 arc(104.52,134.23) 104.27,133.98 103.15,133.98 arc(102.94,133.94) 102.77,133.82 102.53,133.58 arc(102.34,133.46) 102.13,133.41 101.09,133.41 100.2,132.52 100.2,124.29 99.95,124.04 99.95,116.27 102.76,113.46 102.76,112.51 arc(102.81,112.39) 102.92,112.35 arc(103.03,112.37) 103.12,112.43 103.29,112.6 arc(103.45,112.67) 103.62,112.6 arc(103.7,112.42) 103.62,112.24 102.75,111.37 arc(102.75,111.01) 103.11,111.01 103.98,111.88 arc(104.34,111.88) 104.34,111.52 102.97,110.15 arc(102.97,109.79) 103.33,109.79 104.7,111.16 arc(105.06,111.16) 105.06,110.8 103.69,109.43 arc(103.69,109.07) 104.05,109.07 105.42,110.44 arc(105.78,110.44) 105.78,110.08 104.41,108.71 arc(104.41,108.35) 104.77,108.35 106.14,109.72 arc(106.5,109.72) 106.5,109.36 105.13,107.99 arc(105.13,107.64) 105.49,107.64 106.85,109 arc(107.21,109) 107.21,108.64 105.85,107.28 arc(105.85,106.92) 106.21,106.92 107.52,108.23 arc(107.73,108.32) 107.95,108.23 arc(108.02,108.06) 107.95,107.88 106.6,106.53 arc(106.53,106.38) 106.6,106.22 106.91,105.91 arc(107.22,105.77) 107.54,105.91 107.98,106.35 arc(108.34,106.35) 108.34,105.99 107.93,105.58 arc(107.93,105.22) 108.29,105.22 108.7,105.63 arc(109.06,105.63) 109.06,105.27 108.65,104.86 arc(108.65,104.5) 109.01,104.5 109.42,104.91 arc(109.78,104.91) 109.78,104.55 109.36,104.14 arc(109.36,103.78) 109.72,103.78 110.14,104.19 arc(110.5,104.19) 110.5,103.84 110.08,103.42 arc(110.08,103.06) 110.44,103.06 110.86,103.48 arc(111.22,103.48) 111.22,103.12 110.87,102.77 arc(110.87,102.41) 111.22,102.41 111.58,102.76 arc(111.94,102.76) 111.94,102.4 111.52,101.98 arc(111.52,101.62) 111.88,101.62 112.29,102.04 arc(112.65,102.04) 112.65,101.68 112.24,101.26 arc(112.24,100.91) 112.6,100.91 113.01,101.32 arc(113.37,101.32) 113.37,100.96 112.97,100.56 arc(112.89,100.37) 112.97,100.17 arc(113.14,100.11) 113.3,100.17 113.53,100.4 arc(113.89,100.4) 113.89,100.04 113.65,99.8 113.65,99.62 113.97,99.3 113.97,86.75 116.91,83.81 117.5,83.81
  BOTTOM w0.102: 129.54,137.6 130.25,137.6
  BOTTOM w0.127: R366.2 128.69,139.16 128.69,138.46 129.54,137.6 ; v3(101.85,136.22) 102.25,136.62 116.69,136.62 v3(117.09,136.22) 117.49,136.62 131.93,136.62 v3(132.33,136.22) 132.72,136.61 132.72,137.34 132.46,137.6 130.25,137.6
DDR3_A_A7: length 157
  TOP w0.127: U11.R2 v3(122.69,136.22) ; U12.R2 v3(137.93,136.22) ; P1.H23 v2(128.89,84.12) ; U10.R2 v3(107.45,136.22)
  03_SIG1 w0.102: 115.72,77.61 116.59,76.74 128.16,76.74 129.27,77.85 129.27,83.74 v2(128.89,84.12)
  03_SIG1 w0.127: 115.72,77.61 96.16,97.16 96.16,98.11 arc(96.08,98.32) 95.86,98.41 95.1,98.41 arc(94.89,98.5) 94.81,98.7 arc(94.88,98.89) 95.07,98.97 95.96,98.97 arc(96.22,99.22) 95.96,99.48 95.05,99.48 arc(94.79,99.73) 95.05,99.99 95.96,99.99 arc(96.22,100.24) 95.96,100.49 95.05,100.49 arc(94.79,100.75) 95.05,101 95.96,101 arc(96.22,101.26) 95.96,101.51 95.05,101.51 arc(94.79,101.76) 95.05,102.02 95.96,102.02 arc(96.22,102.27) 95.96,102.53 95.05,102.53 arc(94.79,102.78) 95.05,103.03 95.96,103.03 arc(96.22,103.29) 95.96,103.54 95,103.54 arc(94.82,103.62) 94.74,103.8 94.74,136.72 97.82,139.79 104.37,139.79 106.17,137.99 106.17,136.89 106.45,136.62 107.05,136.62 v3(107.45,136.22) 110.61,136.22 arc(110.79,136.29) 110.87,136.47 110.87,136.54 arc(111.12,136.79) 111.38,136.54 111.38,136.47 arc(111.63,136.22) 111.88,136.47 111.88,136.54 arc(112.14,136.79) 112.39,136.54 112.39,136.47 arc(112.47,136.29) 112.65,136.22 113.02,136.22 113.72,136.92 115.65,136.92 115.95,136.62 122.29,136.62 v3(122.69,136.22) 123.09,136.62 137.53,136.62 v3(137.93,136.22)
  BOTTOM w0.127: v3(137.93,136.22) 138.32,136.61 138.32,139.47 R356.2
DDR3_A_A8: length 150.8
  TOP w0.127: P1.H22 v2(129.89,84.12) ; U12.T8 v3(132.33,137.02) 132.33,138.95 R30.2 ; U11.T8 v3(117.09,137.02) ; U10.T8 v3(101.85,137.02)
  06_SIG2 w0.127: v3(132.33,137.02) 131.93,137.42 117.49,137.42 v3(117.09,137.02) 116.69,137.42 105.35,137.42 arc(105.18,137.35) 105.1,137.17 105.1,137.07 arc(104.85,136.82) 104.59,137.07 104.59,137.17 arc(104.34,137.42) 104.08,137.17 104.08,137.07 arc(103.83,136.82) 103.58,137.07 103.58,137.17 arc(103.5,137.35) 103.32,137.42 102.25,137.42 v3(101.85,137.02) 102.24,136.63 102.24,134.47 102.54,134.18 104.45,134.18 107.24,131.38 108,131.38 109.96,129.43 111.84,129.43 112.27,128.99 112.27,117.8 110.08,115.61 110.08,112.23 111.34,110.97 112.22,110.97 arc(112.47,110.72) 112.22,110.46 111.38,110.46 arc(111.12,110.21) 111.38,109.96 112.22,109.96 arc(112.47,109.7) 112.22,109.45 111.38,109.45 arc(111.12,109.19) 111.38,108.94 112.22,108.94 arc(112.47,108.69) 112.22,108.43 111.38,108.43 arc(111.12,108.18) 111.38,107.92 112.22,107.92 arc(112.47,107.67) 112.22,107.42 111.38,107.42 arc(111.12,107.16) 111.38,106.91 112.22,106.91 arc(112.47,106.65) 112.22,106.4 111.38,106.4 arc(111.12,106.15) 111.38,105.89 112.22,105.89 arc(112.47,105.64) 112.22,105.38 111.38,105.38 arc(111.12,105.13) 111.38,104.88 112.22,104.88 arc(112.47,104.62) 112.22,104.37 111.38,104.37 arc(111.12,104.11) 111.38,103.86 112.22,103.86 arc(112.47,103.61) 112.22,103.35 111.38,103.35 arc(111.12,103.1) 111.38,102.84 112.22,102.84 arc(112.47,102.59) 112.22,102.34 111.38,102.34 arc(111.13,102.09) 111.38,101.84 113.66,101.84 arc(113.92,101.58) 113.66,101.32 112.73,101.32 arc(112.47,101.07) 112.73,100.81 113.66,100.81 arc(113.91,100.56) 113.66,100.31 112.73,100.31 arc(112.47,100.05) 112.73,99.8 113.66,99.8 arc(113.91,99.54) 113.66,99.29 112.73,99.29 arc(112.47,99.04) 112.73,98.78 113.66,98.78 arc(113.91,98.53) 113.66,98.27 112.73,98.27 arc(112.47,98.02) 112.73,97.77 113.66,97.77 arc(113.91,97.51) 113.66,97.26 112.73,97.26 arc(112.47,97) 112.73,96.75 113.66,96.75 arc(113.91,96.5) 113.66,96.24 112.65,96.24 112.47,96.06 112.47,94.27 117.25,89.5 117.25,86.47 118.62,85.1 119.79,85.1 121.26,83.63 124.21,83.63 125.22,82.61 128.38,82.61 v2(129.89,84.12)
DDR3_A_A9: length 153.2
  TOP w0.127: R37.2 136.27,137.42 136.27,136.28 U12.R3 v3(137.13,136.22) ; U10.R3 v3(106.65,136.22) ; U11.R3 v3(121.89,136.22) ; P1.J22 v2(128.89,85.12)
  03_SIG1 w0.102: v2(128.89,85.12) 128.51,84.74 128.51,77.85 128.16,77.5 116.49,77.5 115.72,78.27
  03_SIG1 w0.127: 115.72,78.27 96.82,97.17 96.82,103.92 arc(96.75,104.1) 96.57,104.18 95.45,104.18 arc(95.2,104.43) 95.45,104.68 96.55,104.68 arc(96.8,104.94) 96.55,105.19 95.45,105.19 arc(95.2,105.45) 95.45,105.7 96.55,105.7 arc(96.8,105.95) 96.55,106.21 95.45,106.21 arc(95.2,106.46) 95.45,106.72 96.55,106.72 arc(96.8,106.97) 96.55,107.22 95.45,107.22 arc(95.2,107.48) 95.45,107.73 96.57,107.73 arc(96.74,107.8) 96.81,107.97 arc(96.73,108.16) 96.53,108.24 95.25,108.24 95.12,108.37 95.12,136.46 98.07,139.41 104.11,139.41 105.79,137.73 105.79,136.72 106.29,136.22 v3(106.65,136.22)
  06_SIG2 w0.127: v3(137.13,136.22) U12.R3 122.29,135.82 v3(121.89,136.22) U11.R3 107.05,135.82 v3(106.65,136.22)
DDR3_A_A10: length 160.3
  TOP w0.127: U12.L7 v3(133.13,133.02) ; U10.L7 v3(102.65,133.02) ; P1.G26 124.89,83.12 v2(124.89,84.12) ; U11.L7 v3(117.89,133.02)
  03_SIG1 w0.102: v2(124.89,84.12) 124.51,84.5 117.7,84.5
  03_SIG1 w0.127: 117.7,84.5 117.63,84.43 116.88,84.43 114.38,86.93 114.38,100.88 113.89,101.36 113.89,101.54 114.3,101.94 arc(114.37,102.12) 114.3,102.3 arc(114.12,102.37) 113.93,102.3 113.64,102 arc(113.28,102) 113.28,102.36 114.28,103.36 arc(114.28,103.72) 113.92,103.72 112.92,102.72 arc(112.56,102.72) 112.56,103.08 113.64,104.16 arc(113.64,104.51) 113.28,104.51 112.2,103.44 arc(111.84,103.44) 111.84,103.8 112.92,104.87 arc(112.92,105.23) 112.56,105.23 111.48,104.16 arc(111.12,104.16) 111.12,104.51 112.2,105.59 arc(112.2,105.95) 111.84,105.95 110.76,104.87 arc(110.4,104.87) 110.4,105.23 111.48,106.31 arc(111.48,106.67) 111.12,106.67 110.04,105.59 arc(109.69,105.59) 109.69,105.95 110.76,107.03 arc(110.76,107.39) 110.4,107.39 109.33,106.31 arc(108.97,106.31) 108.97,106.67 110.04,107.75 arc(110.04,108.11) 109.68,108.11 108.61,107.03 arc(108.25,107.03) 108.25,107.39 109.35,108.49 arc(109.35,108.83) 109.01,108.83 108.66,108.48 arc(108.3,108.48) 108.3,108.84 108.65,109.19 arc(108.65,109.55) 108.3,109.55 107.98,109.23 arc(107.62,109.23) 107.62,109.59 107.94,109.91 arc(107.94,110.27) 107.58,110.27 107.26,109.95 arc(106.9,109.95) 106.9,110.31 107.22,110.62 arc(107.22,110.98) 106.86,110.98 106.54,110.67 arc(106.18,110.67) 106.18,111.03 106.5,111.34 arc(106.5,111.7) 106.14,111.7 105.82,111.39 arc(105.47,111.39) 105.47,111.75 105.78,112.06 arc(105.78,112.42) 105.42,112.42 105.11,112.11 arc(104.75,112.11) 104.75,112.46 105.06,112.78 arc(105.06,113.14) 104.7,113.14 104.39,112.82 arc(104.03,112.82) 104.03,113.18 104.34,113.5 arc(104.34,113.86) 103.98,113.86 103.67,113.54 arc(103.31,113.54) 103.31,113.9 103.63,114.22 arc(103.63,114.58) 103.27,114.58 102.95,114.26 arc(102.59,114.26) 102.59,114.62 102.91,114.94 arc(102.91,115.29) 102.55,115.29 102.23,114.98 arc(101.87,114.98) 101.87,115.34 102.19,115.65 arc(102.19,116.01) 101.83,116.01 101.51,115.7 arc(101.15,115.7) 101.15,116.06 101.47,116.37 arc(101.47,116.73) 101.11,116.73 100.8,116.42 arc(100.62,116.34) 100.45,116.42 arc(100.36,116.63) 100.45,116.84 100.55,116.94 arc(100.59,117.06) 100.55,117.17 100.41,117.31 arc(100.35,117.39) 100.33,117.5 100.33,117.53 arc(100.4,117.71) 100.58,117.78 100.82,117.78 arc(101.07,118.04) 100.82,118.29 100.58,118.29 arc(100.33,118.55) 100.58,118.8 100.82,118.8 arc(101.07,119.05) 100.82,119.31 100.58,119.31 arc(100.33,119.56) 100.58,119.82 100.82,119.82 arc(101.07,120.07) 100.82,120.32 100.58,120.32 arc(100.33,120.58) 100.58,120.83 100.82,120.83 arc(101.07,121.09) 100.82,121.34 100.58,121.34 arc(100.4,121.41) 100.33,121.59 100.33,122.57 arc(100.4,122.73) 100.56,122.8 100.69,122.8 arc(100.88,122.88) 100.96,123.08 arc(100.9,123.24) 100.74,123.3 100.63,123.3 arc(100.44,123.39) 100.36,123.58 arc(100.36,123.59) 100.36,123.61 arc(100.36,123.62) 100.36,123.63 arc(100.46,123.79) 100.64,123.86 100.83,123.86 arc(101.01,123.93) 101.08,124.1 arc(101,124.29) 100.81,124.37 100.74,124.37 arc(100.63,124.42) 100.58,124.52 100.58,132.4 101.21,133.02 v3(102.65,133.02)
  BOTTOM w0.127: R363.2 132.53,138.75 133.22,138.75 134.37,137.6 134.37,134.26 v3(133.13,133.02) 132.73,133.42 118.29,133.42 v3(117.89,133.02) 117.49,133.42 103.05,133.42 v3(102.65,133.02)
DDR3_A_A11: length 156
  TOP w0.127: U10.R7 v3(102.65,136.22) ; R31.2 133.93,138.5 133.93,136.22 U12.R7 v3(133.13,136.22) ; U11.R7 v3(117.89,136.22) ; P1.F26 v2(124.89,82.12)
  03_SIG1 w0.127: v3(102.65,136.22) 102.25,136.61 99.47,136.61 98.42,135.57 98.42,135.06 97.41,134.05 97.41,116.37 101.09,112.69 101.09,102.1 arc(101.16,101.93) 101.32,101.86 101.78,101.86 arc(101.83,101.86) 101.87,101.83 arc(101.96,101.61) 101.87,101.4 101.22,100.75 arc(101.14,100.57) 101.22,100.39 arc(101.41,100.31) 101.61,100.39 102.34,101.12 arc(102.7,101.12) 102.7,100.76 101.86,99.92 arc(101.86,99.56) 102.22,99.56 103.06,100.4 arc(103.42,100.4) 103.42,100.04 102.64,99.26 arc(102.64,98.9) 102.99,98.9 103.78,99.68 arc(104.14,99.68) 104.14,99.33 103.35,98.54 arc(103.35,98.18) 103.71,98.18 104.5,98.97 arc(104.86,98.97) 104.86,98.61 104.07,97.82 arc(104.07,97.46) 104.43,97.46 105.22,98.25 arc(105.57,98.25) 105.57,97.89 104.79,97.1 arc(104.79,96.75) 105.15,96.75 105.93,97.53 arc(106.29,97.53) 106.29,97.17 105.51,96.39 arc(105.51,96.03) 105.87,96.03 106.65,96.81 arc(107.01,96.81) 107.01,96.45 106.23,95.67 arc(106.23,95.31) 106.59,95.31 107.37,96.09 arc(107.73,96.09) 107.73,95.73 106.95,94.95 arc(106.95,94.59) 107.31,94.59 108.09,95.37 arc(108.45,95.37) 108.45,95.01 107.66,94.23 arc(107.66,93.87) 108.02,93.87 108.81,94.66 arc(109.17,94.66) 109.17,94.3 108.38,93.51 arc(108.38,93.15) 108.74,93.15 109.53,93.94 arc(109.88,93.94) 109.88,93.58 109.1,92.79 arc(109.1,92.44) 109.46,92.44 110.24,93.22 arc(110.6,93.22) 110.6,92.86 109.82,92.08 arc(109.82,91.72) 110.18,91.72 110.96,92.5 arc(111.32,92.5) 111.32,92.14 110.54,91.36 arc(110.54,91) 110.9,91 111.68,91.78 arc(112.04,91.78) 112.04,91.42 111.26,90.64 arc(111.26,90.28) 111.62,90.28 111.92,90.58 arc(112.28,90.58) 112.28,90.22 111.97,89.92 arc(111.9,89.74) 111.97,89.56 112.32,89.22 112.32,85.99 116.71,81.6 124.36,81.6 v2(124.89,82.12)
  06_SIG2 w0.127: v3(133.13,136.22) 132.73,136.62 118.29,136.62 v3(117.89,136.22) 117.49,136.62 106.43,136.62 106.03,136.22 v3(102.65,136.22)
DDR3_A_A12: length 158
  TOP w0.127: U10.N7 v3(102.65,134.62) ; U11.N7 v3(117.89,134.62) ; v3(133.13,134.62) U12.N7 134.75,135.44 134.75,139.96 R33.2 ; P1.F24 v2(126.89,81.12)
  03_SIG1 w0.102: 117.5,83.43 117.63,83.43 117.7,83.5 126.11,83.5 126.36,83.25 126.36,81.64 v2(126.89,81.12)
  03_SIG1 w0.127: 117.5,83.43 116.73,83.43 113.61,86.55 113.61,86.57 113.56,86.62 113.56,96.33 113.12,96.78 arc(113.04,96.95) 113.12,97.13 113.49,97.5 arc(113.49,97.86) 113.13,97.86 112.76,97.49 arc(112.4,97.49) 112.4,97.85 113.34,98.79 arc(113.34,99.15) 112.98,99.15 112.04,98.21 arc(111.68,98.21) 111.68,98.57 112.62,99.51 arc(112.62,99.87) 112.26,99.87 111.32,98.93 arc(110.96,98.93) 110.96,99.29 111.9,100.23 arc(111.9,100.59) 111.54,100.59 110.6,99.65 arc(110.24,99.65) 110.24,100.01 111.18,100.95 arc(111.18,101.31) 110.82,101.31 109.88,100.37 arc(109.53,100.37) 109.53,100.73 110.47,101.67 arc(110.47,102.02) 110.11,102.02 109.17,101.09 arc(108.81,101.09) 108.81,101.44 109.75,102.38 arc(109.75,102.74) 109.39,102.74 108.45,101.8 arc(108.09,101.8) 108.09,102.16 109.03,103.1 arc(109.03,103.46) 108.67,103.46 107.73,102.52 arc(107.37,102.52) 107.37,102.88 108.31,103.82 arc(108.31,104.18) 107.95,104.18 107.01,103.24 arc(106.65,103.24) 106.65,103.6 107.35,104.3 arc(107.35,104.66) 106.99,104.66 106.29,103.96 arc(105.93,103.96) 105.93,104.32 106.63,105.01 arc(106.63,105.37) 106.27,105.37 105.57,104.68 arc(105.22,104.68) 105.22,105.04 106.03,105.85 arc(106.03,106.21) 105.67,106.21 104.86,105.4 arc(104.5,105.4) 104.5,105.76 105.31,106.57 arc(105.31,106.93) 104.95,106.93 104.14,106.11 arc(103.78,106.11) 103.78,106.47 104.59,107.29 arc(104.59,107.65) 104.23,107.65 103.42,106.83 arc(103.06,106.83) 103.06,107.19 103.87,108 arc(103.87,108.36) 103.51,108.36 102.69,107.54 arc(102.53,107.47) 102.36,107.54 arc(102.28,107.74) 102.36,107.94 103.09,108.67 103.09,108.85 102.33,109.61 arc(102.26,109.71) 102.23,109.84 102.23,113.35 99.57,116.02 99.57,124.22 99.82,124.47 99.82,133.29 100.76,134.23 102.25,134.23 v3(102.65,134.62)
  06_SIG2 w0.127: v3(133.13,134.62) 132.73,135.02 118.29,135.02 v3(117.89,134.62) 117.49,135.02 106.1,135.02 arc(105.92,135.09) 105.85,135.27 arc(105.77,135.45) 105.6,135.52 105.59,135.52 arc(105.41,135.45) 105.34,135.27 arc(105.27,135.09) 105.09,135.02 103.05,135.02 v3(102.65,134.62)
DDR3_A_BA0: length 159.9
  TOP w0.127: U11.M2 v3(122.69,133.82) ; U12.M2 v3(137.93,133.82) ; P1.D26 v2(124.89,79.12) ; U10.M2 v3(107.45,133.82)
  03_SIG1 w0.127: v3(137.93,133.82) U12.M2 123.09,133.42 v3(122.69,133.82) U11.M2 112.74,133.42 arc(112.6,133.48) 112.54,133.62 112.54,133.77 arc(112.47,133.95) 112.29,134.03 arc(112.11,133.95) 112.03,133.77 112.03,133.62 arc(111.98,133.48) 111.83,133.42 109.95,133.42 arc(109.77,133.49) 109.7,133.67 109.7,133.77 arc(109.44,134.02) 109.19,133.77 109.19,133.67 arc(109.12,133.49) 108.94,133.42 107.85,133.42 v3(107.45,133.82) 107.01,134.25 106.73,134.25 106.3,134.68 105.54,134.68 104.25,135.97 104.25,136.73 103.11,137.87 99.07,137.87 96.65,135.45 96.65,115.94 100.33,112.26 100.33,97.85 arc(100.3,97.69) 100.21,97.55 99.92,97.26 arc(99.92,96.9) 100.29,96.9 100.75,97.36 arc(100.95,97.42) 101.13,97.3 arc(101.17,97.12) 101.09,96.96 100.64,96.51 arc(100.56,96.32) 100.64,96.14 arc(100.8,96.07) 100.97,96.14 101.45,96.63 arc(101.63,96.7) 101.81,96.63 arc(101.89,96.45) 101.81,96.27 101.32,95.77 arc(101.32,95.42) 101.68,95.42 102.17,95.91 arc(102.35,95.98) 102.53,95.91 arc(102.6,95.73) 102.53,95.55 102.06,95.08 arc(102.06,94.72) 102.42,94.72 102.89,95.19 arc(103.07,95.26) 103.25,95.19 arc(103.32,95.01) 103.25,94.83 102.72,94.3 arc(102.72,93.94) 103.08,93.94 103.61,94.47 arc(103.79,94.54) 103.97,94.47 arc(104.04,94.29) 103.97,94.11 103.44,93.58 arc(103.44,93.22) 103.8,93.22 104.33,93.75 arc(104.51,93.83) 104.69,93.75 arc(104.76,93.57) 104.69,93.39 104.16,92.86 arc(104.16,92.5) 104.51,92.5 105.04,93.03 arc(105.22,93.11) 105.4,93.03 arc(105.48,92.85) 105.4,92.67 104.87,92.14 arc(104.87,91.79) 105.23,91.79 105.76,92.32 arc(105.94,92.39) 106.12,92.32 arc(106.2,92.14) 106.12,91.96 105.59,91.43 arc(105.59,91.07) 105.95,91.07 106.48,91.6 arc(106.66,91.67) 106.84,91.6 arc(106.92,91.42) 106.84,91.24 106.31,90.71 arc(106.31,90.35) 106.67,90.35 107.2,90.88 arc(107.38,90.95) 107.56,90.88 arc(107.63,90.7) 107.56,90.52 107.03,89.99 arc(107.03,89.63) 107.39,89.63 107.92,90.16 arc(108.1,90.23) 108.28,90.16 arc(108.35,89.98) 108.28,89.8 107.75,89.27 arc(107.75,88.91) 108.11,88.91 108.64,89.44 arc(108.82,89.52) 109,89.44 arc(109.07,89.26) 109,89.08 108.47,88.55 arc(108.47,88.19) 108.83,88.19 109.36,88.72 arc(109.53,88.8) 109.71,88.72 arc(109.79,88.54) 109.71,88.36 109.18,87.83 arc(109.18,87.47) 109.54,87.47 110.07,88 arc(110.25,88.08) 110.43,88 arc(110.51,87.83) 110.43,87.65 109.9,87.12 arc(109.9,86.76) 110.26,86.76 110.79,87.29 arc(110.97,87.36) 111.15,87.29 arc(111.23,87.11) 111.15,86.93 110.62,86.4 arc(110.55,86.22) 110.62,86.04 116.97,79.69 124.32,79.69 v2(124.89,79.12)
  BOTTOM w0.127: v3(137.93,133.82) 137.53,134.21 137.12,134.21 136.27,135.06 136.27,139.58 R359.2
DDR3_A_BA1: length 159.9
  TOP w0.127: U12.N8 v3(132.33,134.62) ; P1.D25 v2(125.89,80.12) ; U11.N8 v3(117.09,134.62) ; U10.N8 v3(101.85,134.62)
  06_SIG2 w0.127: v2(125.89,80.12) 125.43,80.58 118.75,80.58 118.36,80.96 118.36,81.95 115.67,84.64 arc(115.6,84.82) 115.67,85 115.84,85.17 arc(115.9,85.41) 115.72,85.59 arc(115.59,85.59) 115.48,85.53 115.31,85.36 arc(114.95,85.36) 114.95,85.72 115.88,86.65 arc(115.94,86.91) 115.72,87.08 arc(115.61,87.07) 115.52,87.01 114.59,86.08 arc(114.24,86.08) 114.24,86.44 115.21,87.41 arc(115.21,87.77) 114.85,87.77 113.88,86.8 arc(113.52,86.8) 113.52,87.16 114.49,88.13 arc(114.49,88.49) 114.13,88.49 113.16,87.52 arc(112.8,87.52) 112.8,87.88 113.77,88.85 arc(113.77,89.21) 113.41,89.21 112.44,88.24 arc(112.08,88.24) 112.08,88.6 113.05,89.57 arc(113.05,89.93) 112.7,89.93 111.72,88.96 arc(111.36,88.96) 111.36,89.31 112.34,90.29 arc(112.34,90.65) 111.98,90.65 111,89.67 arc(110.64,89.67) 110.64,90.03 111.62,91.01 arc(111.62,91.37) 111.26,91.37 110.28,90.39 arc(109.93,90.39) 109.93,90.75 110.9,91.73 arc(110.9,92.08) 110.54,92.08 109.57,91.11 arc(109.21,91.11) 109.21,91.47 110.18,92.44 arc(110.18,92.8) 109.82,92.8 108.85,91.83 arc(108.49,91.83) 108.49,92.19 109.46,93.16 arc(109.46,93.52) 109.1,93.52 108.99,93.41 108.46,93.41 108.33,93.54 108.33,93.93 arc(108.41,94.11) 108.59,94.18 109.55,94.18 arc(109.8,94.43) 109.55,94.69 108.59,94.69 arc(108.33,94.94) 108.59,95.2 109.55,95.2 arc(109.8,95.45) 109.55,95.7 108.59,95.7 arc(108.33,95.96) 108.59,96.21 109.55,96.21 arc(109.8,96.47) 109.55,96.72 108.59,96.72 arc(108.33,96.97) 108.59,97.23 109.55,97.23 arc(109.8,97.48) 109.55,97.74 108.59,97.74 arc(108.33,97.99) 108.59,98.24 109.55,98.24 arc(109.8,98.5) 109.55,98.75 108.59,98.75 arc(108.41,98.83) 108.33,99.01 108.33,122.24 109.86,123.76 109.86,128 107.62,130.24 105.79,130.24 103.5,132.52 103.5,132.72 101.85,134.38 v3(101.85,134.62)
  BOTTOM w0.127: v3(101.85,134.62) U10.N8 113.28,134.22 113.68,134.62 114.74,134.62 arc(114.92,134.54) 115,134.37 115,134.3 arc(115.25,134.05) 115.51,134.3 115.51,134.37 arc(115.58,134.54) 115.76,134.62 v3(117.09,134.62) U11.N8 131.93,134.22 v3(132.33,134.62) 132.75,134.2 133.29,134.2 133.99,134.89 133.99,137.35 132.97,138.37 131.77,138.37 R364.2
DDR3_A_BA2: length 158.8
  TOP w0.127: R34.2 135.13,139.71 135.13,134.3 136.01,133.42 U12.M3 v3(137.13,133.82) ; U10.M3 v3(106.65,133.82) ; U11.M3 v3(121.89,133.82) ; P1.C25 v2(125.89,79.12)
  03_SIG1 w0.127: v3(106.65,133.82) 106.17,134.3 105.29,134.3 103.86,135.72 103.86,136.49 102.87,137.48 99.31,137.48 97.03,135.19 97.03,116.17 100.71,112.48 100.71,100.14 arc(100.75,99.95) 100.85,99.79 101.37,99.28 arc(101.43,99.14) 101.37,99 100.81,98.44 arc(100.73,98.25) 100.81,98.06 arc(101,97.98) 101.18,98.06 101.86,98.74 arc(102.22,98.74) 102.22,98.38 101.66,97.82 arc(101.66,97.46) 102.02,97.46 102.58,98.02 arc(102.94,98.02) 102.94,97.66 102.38,97.1 arc(102.38,96.74) 102.74,96.74 103.3,97.3 arc(103.66,97.3) 103.66,96.94 103.1,96.38 arc(103.1,96.02) 103.46,96.02 104.02,96.58 arc(104.38,96.58) 104.38,96.23 103.82,95.66 arc(103.82,95.31) 104.18,95.31 104.74,95.87 arc(105.1,95.87) 105.1,95.51 104.54,94.95 arc(104.54,94.59) 104.9,94.59 105.46,95.15 arc(105.82,95.15) 105.82,94.79 105.26,94.23 arc(105.26,93.87) 105.61,93.87 106.17,94.43 arc(106.53,94.43) 106.53,94.07 105.97,93.51 arc(105.97,93.15) 106.33,93.15 106.89,93.71 arc(107.25,93.71) 107.25,93.35 106.69,92.79 arc(106.69,92.43) 107.05,92.43 107.61,92.99 arc(107.97,92.99) 107.97,92.63 107.41,92.07 arc(107.41,91.71) 107.77,91.71 108.33,92.27 arc(108.69,92.27) 108.69,91.91 108.13,91.35 arc(108.13,90.99) 108.49,90.99 109.05,91.56 arc(109.41,91.56) 109.41,91.2 108.85,90.64 arc(108.85,90.28) 109.21,90.28 109.77,90.84 arc(110.13,90.84) 110.13,90.48 109.57,89.92 arc(109.57,89.56) 109.92,89.56 110.49,90.12 arc(110.84,90.12) 110.84,89.76 110.28,89.2 arc(110.28,88.84) 110.64,88.84 111.2,89.4 arc(111.56,89.4) 111.56,89.04 110.93,88.4 arc(110.86,88.23) 110.93,88.06 arc(111.12,87.98) 111.32,88.06 111.47,88.22 arc(111.54,88.26) 111.63,88.28 arc(111.81,88.21) 111.89,88.02 111.89,87.01 arc(111.87,86.91) 111.81,86.83 111.52,86.54 arc(111.44,86.35) 111.52,86.16 116.97,80.71 124.3,80.71 v2(125.89,79.12)
  06_SIG2 w0.127: v3(106.65,133.82) 107.05,134.22 121.49,134.22 v3(121.89,133.82) 122.29,134.22 136.73,134.22 v3(137.13,133.82)
DDR3_A_CAS_N_0: length 160.6
  TOP w0.127: U11.K3 v3(121.09,132.22) ; v2(124.89,81.12) P1.E26 ; U12.K3 v3(136.33,132.22) ; U10.K3 v3(105.85,132.22)
  06_SIG2 w0.127: v2(124.89,81.12) 124.6,81.12 124.13,81.6 119.76,81.6 118.36,82.99 118.36,83.32 116.42,85.27 116.42,87.2 110.31,93.31 110.31,99.13 arc(110.24,99.31) 110.06,99.39 108.99,99.39 arc(108.74,99.64) 108.99,99.9 110.06,99.9 arc(110.31,100.15) 110.06,100.4 108.99,100.4 arc(108.74,100.66) 108.99,100.91 110.06,100.91 arc(110.31,101.17) 110.06,101.42 108.99,101.42 arc(108.74,101.67) 108.99,101.93 110.06,101.93 arc(110.31,102.18) 110.06,102.44 108.99,102.44 arc(108.74,102.69) 108.99,102.94 110.06,102.94 arc(110.31,103.2) 110.06,103.45 108.99,103.45 arc(108.74,103.71) 108.99,103.96 110.06,103.96 arc(110.31,104.21) 110.06,104.47 108.99,104.47 arc(108.74,104.72) 108.99,104.98 110.06,104.98 arc(110.31,105.23) 110.06,105.48 108.99,105.48 arc(108.74,105.74) 108.99,105.99 110.06,105.99 arc(110.31,106.25) 110.06,106.5 108.99,106.5 arc(108.74,106.75) 108.99,107.01 110.06,107.01 arc(110.31,107.26) 110.06,107.52 108.99,107.52 arc(108.74,107.77) 108.99,108.02 110.06,108.02 arc(110.31,108.28) 110.06,108.53 108.99,108.53 arc(108.74,108.79) 108.99,109.04 110.06,109.04 arc(110.31,109.29) 110.06,109.55 108.99,109.55 arc(108.74,109.8) 108.99,110.06 110.06,110.06 arc(110.31,110.31) 110.06,110.56 108.99,110.56 arc(108.74,110.82) 108.99,111.07 109.47,111.07 arc(109.65,111.14) 109.72,111.32 arc(109.65,111.5) 109.47,111.57 108.99,111.57 arc(108.79,111.65) 108.71,111.85 arc(108.79,112.03) 108.97,112.1 109.07,112.1 arc(109.32,112.36) 109.07,112.61 108.97,112.61 arc(108.71,112.86) 108.97,113.12 109.07,113.12 arc(109.32,113.37) 109.07,113.63 108.97,113.63 arc(108.71,113.88) 108.97,114.13 109.07,114.13 arc(109.32,114.39) 109.07,114.64 108.97,114.64 arc(108.71,114.9) 108.97,115.15 109.07,115.15 arc(109.32,115.4) 109.07,115.66 108.97,115.66 arc(108.71,115.91) 108.97,116.17 109.32,116.17 arc(109.58,116.42) 109.32,116.67 108.97,116.67 arc(108.71,116.93) 108.97,117.18 109.88,117.18 arc(110.13,117.44) 109.88,117.69 108.97,117.69 arc(108.71,117.94) 108.97,118.2 109.88,118.2 arc(110.13,118.45) 109.88,118.71 108.97,118.71 arc(108.71,118.96) 108.97,119.21 109.88,119.21 arc(110.13,119.47) 109.88,119.72 108.97,119.72 arc(108.71,119.98) 108.97,120.23 109.88,120.23 arc(110.13,120.48) 109.88,120.74 108.97,120.74 arc(108.71,120.99) 108.97,121.25 109.88,121.25 arc(110.13,121.5) 109.88,121.75 108.95,121.75 108.83,121.88 108.83,122.15 108.99,122.31 109.78,122.31 110.87,123.41 110.87,125.58 arc(110.93,125.72) 111.07,125.78 111.29,125.78 arc(111.54,126.03) 111.29,126.29 110.49,126.29 arc(110.24,126.54) 110.49,126.8 110.62,126.8 arc(110.8,126.87) 110.87,127.05 110.87,127.5 107.75,130.62 106.05,130.62 105.41,131.25 105.41,131.78 v3(105.85,132.22)
  BOTTOM w0.127: R355.2 139.19,139.2 139.19,133.54 138.28,132.63 136.73,132.63 v3(136.33,132.22) 133.04,132.22 132.64,131.82 U11.K3 v3(121.09,132.22) 120.69,131.82 114.95,131.82 114.8,131.97 114.47,131.97 114.33,131.82 114.05,131.82 113.9,131.97 113.57,131.97 113.42,131.82 112.58,131.82 112.43,131.97 112.15,131.97 112.01,131.82 111.73,131.82 111.58,131.97 111.3,131.97 111.16,131.82 110.88,131.82 110.73,131.97 110.45,131.97 110.31,131.82 110.03,131.82 109.88,131.97 109.6,131.97 109.45,131.82 109.17,131.82 109.03,131.97 108.75,131.97 108.6,131.82 U10.K3 v3(105.85,132.22)
DDR3_A_CK_0: length 145.6
  TOP w0.114: U10.J7 v3(103.45,130.62) ; U12.J7 v3(133.93,130.62) ; U11.J7 v3(118.69,130.62)
  TOP w0.127: v2(128.89,87.12) P1.L23
  03_SIG1 w0.102: v2(128.89,87.12) 128.6,87.12 128.5,87.02 128.5,86.74 128.27,86.5 118.64,86.5 118.6,86.46 118.57,86.46
  03_SIG1 w0.114: 118.57,86.46 118.53,86.46 118.13,86.46 117.11,87.49 117.11,105.74 108.12,114.73 108.12,115.35 arc(108.26,115.71) 108.62,115.86 111.07,115.86 arc(111.42,116.21) 111.07,116.55 108.29,116.55 arc(107.63,117.21) 108.29,117.87 111.89,117.87 arc(112.23,118.21) 111.89,118.55 108.29,118.55 arc(107.63,119.22) 108.29,119.88 111.89,119.88 arc(112.23,120.22) 111.89,120.56 108.29,120.56 arc(107.63,121.22) 108.29,121.88 111.89,121.88 arc(112.23,122.23) 111.89,122.57 108.16,122.57 arc(107.5,123.23) 108.16,123.89 109.55,123.89 arc(109.8,123.99) 109.91,124.24 arc(109.81,124.48) 109.58,124.57 109.31,124.57 arc(108.85,124.76) 108.66,125.22 arc(108.86,125.7) 109.33,125.9 111.81,125.9 arc(112.16,126.24) 111.81,126.58 109.33,126.58 arc(108.67,127.24) 109.33,127.9 109.58,127.9 arc(109.92,128.24) 109.58,128.59 108.51,128.59 arc(107.85,129.25) 108.51,129.91 109.78,129.91 arc(110.12,130.25) 109.78,130.59 104.51,130.59 104.34,130.76 103.59,130.76 v3(103.45,130.62)
  BOTTOM w0.114: v3(103.45,130.62) 103.69,130.86 104.97,130.86 105.15,130.68 117.79,130.68 117.97,130.86 118.45,130.86 v3(118.69,130.62) 118.93,130.86 120.09,130.86 120.26,130.68 132.97,130.68 133.15,130.86 133.69,130.86 v3(133.93,130.62) 134.17,130.86 134.48,130.86 R380.2
DDR3_A_CK_N_0: length 145.3
  TOP w0.114: U12.K7 v3(133.93,131.42) ; U10.K7 v3(103.45,131.42) ; U11.K7 v3(118.69,131.42)
  TOP w0.127: v2(127.89,87.12) P1.M23
  03_SIG1 w0.102: v2(127.89,87.12) 128.17,87.12 128.27,87.02 128.27,86.83 128.17,86.73 118.64,86.73 118.6,86.78 118.57,86.78
  03_SIG1 w0.114: v3(103.45,131.42) 103.45,131.24 103.61,131.08 104.47,131.08 104.64,130.91 109.78,130.91 arc(110.44,130.25) 109.78,129.59 108.51,129.59 arc(108.16,129.25) 108.51,128.91 109.58,128.91 arc(110.24,128.24) 109.58,127.58 109.33,127.58 arc(108.99,127.24) 109.33,126.9 111.81,126.9 arc(112.47,126.24) 111.81,125.58 109.33,125.58 arc(109.08,125.47) 108.98,125.22 arc(109.08,124.99) 109.31,124.89 109.58,124.89 arc(110.03,124.7) 110.22,124.24 arc(110.03,123.77) 109.55,123.57 108.16,123.57 arc(107.82,123.23) 108.16,122.89 111.89,122.89 arc(112.55,122.23) 111.89,121.56 108.29,121.56 arc(107.95,121.22) 108.29,120.88 111.89,120.88 arc(112.55,120.22) 111.89,119.56 108.29,119.56 arc(107.95,119.22) 108.29,118.87 111.89,118.87 arc(112.55,118.21) 111.89,117.55 108.29,117.55 arc(107.95,117.21) 108.29,116.87 111.07,116.87 arc(111.74,116.21) 111.07,115.54 108.62,115.54 arc(108.49,115.49) 108.43,115.35 108.43,114.86 117.42,105.87 117.42,87.62 118.26,86.78 118.4,86.78 118.57,86.78
  BOTTOM w0.114: v3(103.45,131.42) 103.69,131.18 105.11,131.18 105.28,131 117.66,131 117.84,131.18 118.45,131.18 v3(118.69,131.42) 118.93,131.18 120.22,131.18 120.4,131 132.84,131 133.02,131.18 133.69,131.18 v3(133.93,131.42) 134.17,131.18 134.46,131.18 R380.1
DDR3_A_CKE_0: length 161.5
  TOP w0.127: U11.K9 v3(116.29,132.22) ; P1.J27 v2(123.89,85.12) ; U12.K9 v3(131.53,132.22) ; U10.K9 v3(101.05,132.22)
  03_SIG1 w0.102: v2(123.89,85.12) 123.51,84.74 117.7,84.74 117.63,84.81 117.5,84.81
  03_SIG1 w0.127: 117.5,84.81 117.1,84.81 114.78,87.13 114.78,105 arc(114.77,105.06) 114.73,105.12 114.68,105.17 arc(114.52,105.24) 114.35,105.17 114.12,104.94 arc(113.95,104.87) 113.78,104.94 arc(113.71,105.11) 113.78,105.29 114.45,105.96 arc(114.52,106.14) 114.45,106.32 arc(114.27,106.39) 114.09,106.32 113.45,105.67 arc(113.09,105.67) 113.09,106.03 113.73,106.67 arc(113.8,106.85) 113.73,107.03 arc(113.55,107.11) 113.37,107.03 112.73,106.39 arc(112.37,106.39) 112.37,106.75 113.01,107.39 arc(113.09,107.57) 113.01,107.75 arc(112.83,107.83) 112.65,107.75 112.01,107.11 arc(111.65,107.11) 111.65,107.47 112.29,108.11 arc(112.37,108.29) 112.29,108.47 arc(112.11,108.54) 111.93,108.47 111.29,107.83 arc(110.93,107.83) 110.93,108.19 111.58,108.83 arc(111.65,109.01) 111.58,109.19 arc(111.4,109.26) 111.22,109.19 110.57,108.54 arc(110.21,108.54) 110.21,108.9 110.86,109.55 arc(110.93,109.73) 110.86,109.91 arc(110.68,109.98) 110.5,109.91 109.85,109.26 arc(109.49,109.26) 109.49,109.62 110.14,110.27 arc(110.21,110.45) 110.14,110.63 arc(109.96,110.7) 109.78,110.63 109.13,109.98 arc(108.78,109.98) 108.78,110.34 109.42,110.99 arc(109.49,111.16) 109.42,111.34 arc(109.24,111.42) 109.06,111.34 108.42,110.7 arc(108.06,110.7) 108.06,111.06 108.7,111.7 arc(108.78,111.88) 108.7,112.06 arc(108.52,112.14) 108.34,112.06 107.7,111.42 arc(107.34,111.42) 107.34,111.78 107.98,112.42 arc(108.06,112.6) 107.98,112.78 arc(107.8,112.86) 107.62,112.78 106.98,112.14 arc(106.62,112.14) 106.62,112.5 107.26,113.14 arc(107.34,113.32) 107.26,113.5 arc(107.08,113.57) 106.91,113.5 106.26,112.86 arc(105.9,112.86) 105.9,113.21 106.55,113.86 arc(106.62,114.04) 106.55,114.22 arc(106.37,114.29) 106.19,114.22 105.54,113.57 arc(105.18,113.57) 105.18,113.93 105.83,114.58 arc(105.9,114.76) 105.83,114.94 arc(105.65,115.01) 105.47,114.94 104.82,114.29 arc(104.47,114.29) 104.47,114.65 105.51,115.7 arc(105.59,115.88) 105.51,116.07 arc(105.34,116.14) 105.16,116.07 104.11,115.01 arc(103.75,115.01) 103.75,115.37 104.7,116.32 arc(104.78,116.51) 104.7,116.7 arc(104.53,116.77) 104.36,116.7 103.37,115.71 arc(103.21,115.64) 103.05,115.71 arc(102.96,115.93) 103.05,116.14 103.5,116.59 103.5,116.85 103.34,117.01 102.11,117.01 arc(101.92,117.08) 101.84,117.27 arc(101.92,117.46) 102.11,117.54 103.81,117.54 arc(104.08,117.81) 103.81,118.07 101.69,118.07 arc(101.5,118.15) 101.43,118.34 arc(101.5,118.52) 101.68,118.59 103.89,118.59 arc(104.14,118.85) 103.89,119.1 101.68,119.1 arc(101.43,119.35) 101.68,119.61 103.89,119.61 arc(104.14,119.86) 103.89,120.12 101.71,120.12 arc(101.54,120.19) 101.47,120.36 101.47,120.93 arc(101.54,121.09) 101.71,121.16 101.9,121.16 arc(102.16,121.41) 101.9,121.67 101.49,121.67 101.32,121.83 101.32,122.57 101.45,122.7 101.45,131.82 v3(101.05,132.22)
  BOTTOM w0.127: v3(101.05,132.22) 101.45,132.62 115.89,132.62 v3(116.29,132.22) 116.69,132.62 131.13,132.62 v3(131.53,132.22) 131.93,132.63 133.45,132.63 134.75,133.92 134.75,137.78 132.31,140.22 R362.2
DDR3_A_CS_N_0: length 154.6
  TOP w0.127: U12.L2 v3(137.93,133.02) ; U11.L2 v3(122.69,133.02) ; P1.K24 v2(126.89,85.12) ; U10.L2 v3(107.45,133.02)
  03_SIG1 w0.102: v2(126.89,85.12) 126.51,85.5 117.7,85.5 117.63,85.43 117.5,85.43
  03_SIG1 w0.127: 117.5,85.43 117.12,85.43 115.38,87.17 115.38,87.41 115.51,87.54 115.67,87.54 arc(115.93,87.79) 115.67,88.04 115.44,88.04 arc(115.19,88.3) 115.44,88.55 115.67,88.55 arc(115.93,88.81) 115.67,89.06 115.44,89.06 arc(115.19,89.31) 115.44,89.57 115.67,89.57 arc(115.93,89.82) 115.67,90.08 115.44,90.08 arc(115.19,90.33) 115.44,90.58 115.67,90.58 arc(115.93,90.84) 115.67,91.09 115.44,91.09 arc(115.19,91.35) 115.44,91.6 115.67,91.6 arc(115.93,91.85) 115.67,92.11 115.44,92.11 arc(115.19,92.36) 115.44,92.62 115.67,92.62 arc(115.93,92.87) 115.67,93.12 115.44,93.12 arc(115.19,93.38) 115.44,93.63 115.67,93.63 arc(115.93,93.89) 115.67,94.14 115.44,94.14 arc(115.19,94.39) 115.44,94.65 115.67,94.65 arc(115.93,94.9) 115.67,95.16 115.44,95.16 arc(115.19,95.41) 115.44,95.66 115.67,95.66 arc(115.93,95.92) 115.67,96.17 115.44,96.17 arc(115.19,96.43) 115.44,96.68 115.67,96.68 arc(115.93,96.93) 115.67,97.19 115.44,97.19 arc(115.19,97.44) 115.44,97.7 115.67,97.7 arc(115.93,97.95) 115.67,98.2 115.44,98.2 arc(115.19,98.46) 115.44,98.71 115.67,98.71 arc(115.93,98.97) 115.67,99.22 115.44,99.22 arc(115.19,99.47) 115.44,99.73 115.67,99.73 arc(115.93,99.98) 115.67,100.24 115.44,100.24 arc(115.19,100.49) 115.44,100.74 115.67,100.74 arc(115.93,101) 115.67,101.25 115.44,101.25 arc(115.19,101.51) 115.44,101.76 115.67,101.76 arc(115.93,102.01) 115.67,102.27 115.44,102.27 arc(115.19,102.52) 115.44,102.78 115.67,102.78 arc(115.93,103.03) 115.67,103.28 115.44,103.28 arc(115.19,103.54) 115.44,103.79 115.67,103.79 arc(115.93,104.05) 115.67,104.3 115.44,104.3 arc(115.19,104.55) 115.44,104.81 115.67,104.81 arc(115.93,105.06) 115.67,105.32 115.44,105.32 arc(115.26,105.39) 115.19,105.57 115.19,106.13 106.2,115.13 106.2,116.29 arc(106.12,116.47) 105.94,116.55 105.4,116.55 arc(105.15,116.8) 105.4,117.06 105.94,117.06 arc(106.2,117.31) 105.94,117.56 104.78,117.56 arc(104.52,117.82) 104.78,118.07 105.94,118.07 arc(106.2,118.33) 105.94,118.58 104.78,118.58 arc(104.52,118.83) 104.78,119.09 105.94,119.09 arc(106.2,119.34) 105.94,119.6 104.78,119.6 arc(104.52,119.85) 104.78,120.1 105.89,120.1 arc(106.08,120.18) 106.16,120.37 arc(106.08,120.56) 105.89,120.64 103.05,120.64 arc(102.85,120.72) 102.77,120.92 arc(102.84,121.1) 103.02,121.17 103.86,121.17 arc(104.11,121.42) 103.86,121.68 102.71,121.68 arc(102.46,121.93) 102.71,122.19 103.86,122.19 arc(104.11,122.44) 103.86,122.69 102.16,122.69 arc(101.91,122.95) 102.16,123.2 103.9,123.2 arc(104.12,123.35) 104.07,123.61 arc(104.05,123.62) 104.04,123.63 arc(103.94,123.69) 103.83,123.71 102.41,123.71 arc(102.3,123.76) 102.25,123.87 102.25,128.38 102.25,131.91 103.69,133.34 arc(103.79,133.41) 103.92,133.44 104.33,133.44 arc(104.45,133.39) 104.5,133.27 104.5,132.55 arc(104.75,132.3) 105,132.55 105,133.29 arc(105.04,133.38) 105.13,133.41 107.05,133.41 v3(107.45,133.02) 108.64,133.02 arc(108.82,132.95) 108.9,132.77 108.9,132.65 arc(109.15,132.4) 109.4,132.65 109.4,132.77 arc(109.66,133.02) 109.91,132.77 109.91,132.65 arc(110.17,132.4) 110.42,132.65 110.42,132.77 arc(110.5,132.95) 110.67,133.02 112.81,133.02 113.21,132.62 U11.L2 v3(122.69,133.02) 123.09,132.62 U12.L2 v3(137.93,133.02)
  BOTTOM w0.127: v3(137.93,133.02) 137.53,133.41 136.96,133.41 136.73,133.64 136.73,133.97 136.72,133.98 136.72,133.98 135.89,134.81 135.89,138.82 R360.2
DDR3_A_DM0: length 38.8
  TOP w0.127: v2(125.89,100.12) P1.AD25 ; U11.E7 v3(117.89,127.42)
  06_SIG2 w0.102: v2(125.89,100.12) 125.27,100.74 121.57,100.74 121.41,100.9
  06_SIG2 w0.127: v3(117.89,127.42) 117.49,127.03 117.49,125.52 117.58,125.44 117.58,123.32 arc(117.5,123.14) 117.32,123.06 116.4,123.06 arc(116.15,122.81) 116.4,122.55 117.32,122.55 arc(117.5,122.48) 117.58,122.3 117.58,121.83 116.08,120.33 116.08,105.55 118.08,103.54 119.1,103.54 119.41,103.24 119.41,102.91 119.71,102.61 119.96,102.61 120.4,102.17 120.4,101.92 121.41,100.9
DDR3_A_DM1: length 31.6
  TOP w0.127: v2(124.89,108.12) P1.AM27 ; U11.D3 v3(121.89,126.62)
  03_SIG1 w0.127: v3(121.89,126.62) 121.48,126.21 121.48,118.56 121.64,118.4 arc(121.78,118.34) 121.91,118.4 122.49,118.97 arc(122.67,119.05) 122.85,118.97 arc(122.92,118.79) 122.85,118.61 122.26,118.03 arc(122.26,117.67) 122.62,117.67 123.46,118.51 arc(123.63,118.58) 123.8,118.51 arc(123.88,118.32) 123.8,118.12 123.15,117.48 arc(123.15,117.12) 123.51,117.12 124.18,117.79 arc(124.35,117.86) 124.51,117.79 arc(124.59,117.6) 124.51,117.4 123.87,116.76 arc(123.87,116.4) 124.23,116.4 124.9,117.07 arc(125.07,117.14) 125.23,117.07 arc(125.31,116.88) 125.23,116.69 124.59,116.04 arc(124.51,115.86) 124.59,115.68 125.48,114.8 125.48,110.43 125.37,110.32 125.37,108.61 v2(124.89,108.12)
DDR3_A_DM2: length 30.4
  TOP w0.127: P1.AP24 v2(127.89,110.12) ; U12.E7 v3(133.93,128.22)
  06_SIG2 w0.127: v3(133.93,128.22) 134.33,127.81 134.33,123.45 131.58,120.7 arc(131.4,120.62) 131.22,120.7 130.78,121.14 arc(130.42,121.14) 130.42,120.78 130.86,120.34 arc(130.86,119.98) 130.5,119.98 130.06,120.42 arc(129.7,120.42) 129.7,120.06 130.15,119.62 arc(130.15,119.26) 129.79,119.26 129.26,119.79 arc(128.9,119.79) 128.9,119.43 129.43,118.9 arc(129.43,118.54) 129.07,118.54 128.59,119.02 arc(128.23,119.02) 128.23,118.66 128.67,118.22 arc(128.75,118.03) 128.67,117.83 arc(128.5,117.76) 128.33,117.83 arc(127.95,117.83) 127.95,117.44 arc(128.03,117.24) 127.95,117.04 arc(127.9,116.97) 127.89,116.89 v2(127.89,110.12)
DDR3_A_DM3: length 32.4
  TOP w0.127: U12.D3 v3(137.13,127.42) ; P1.AE23 v2(128.89,101.12)
  03_SIG1 w0.127: v3(137.13,127.42) 137.53,127.01 138.1,127.01 138.32,126.79 138.32,116.24 137.9,115.81 137.9,112.94 134.43,109.47 134.43,108.97 133.45,107.99 133.45,106.34 130.81,103.7 130.81,102.81 129.13,101.12 v2(128.89,101.12)
DDR3_A_DM4: length 78.6
  TOP w0.127: U10.E7 v3(102.65,127.42) ; P1.C23 v2(127.89,79.12)
  06_SIG2 w0.127: v2(127.89,79.12) 127.36,78.59 127.36,75.7 125.2,73.55 117.48,73.55 101.85,89.17 101.85,114.24 arc(101.78,114.41) 101.6,114.49 arc(101.35,114.74) 101.6,115 arc(101.85,115.25) 101.6,115.5 arc(101.35,115.76) 101.6,116.01 arc(101.85,116.27) 101.6,116.52 arc(101.35,116.77) 101.6,117.03 arc(101.85,117.28) 101.6,117.54 arc(101.42,117.61) 101.35,117.79 101.35,123.63 102.24,124.53 102.24,127.01 v3(102.65,127.42)
DDR3_A_DQ0: length 44.4
  TOP w0.127: U11.E3 v3(121.89,127.42) ; v2(123.89,105.12) P1.AJ27
  06_SIG2 w0.127: v3(121.89,127.42) 121.48,127.01 121.48,115.2 arc(121.59,114.94) 121.84,114.83 123.14,114.83 arc(123.39,114.58) 123.14,114.33 121.08,114.33 arc(120.83,114.07) 121.08,113.82 123.14,113.82 arc(123.39,113.56) 123.14,113.31 121.08,113.31 arc(120.83,113.06) 121.08,112.8 123.14,112.8 arc(123.39,112.55) 123.14,112.29 121.08,112.29 arc(120.83,112.04) 121.08,111.79 123.14,111.79 arc(123.39,111.53) 123.14,111.28 121.08,111.28 arc(120.83,111.02) 121.08,110.77 123.14,110.77 arc(123.32,110.7) 123.39,110.52 123.39,105.62 v2(123.89,105.12)
DDR3_A_DQ1: length 44.8
  TOP w0.127: P1.AH27 v2(123.89,103.12) ; U11.F7 v3(118.69,128.22)
  06_SIG2 w0.127: v2(123.89,103.12) 123.39,102.63 122.73,102.63 122.43,102.93 122.43,103.19 121.97,103.65 121.08,103.65 120.42,104.31 118.49,104.31 116.84,105.96 116.84,114.67 arc(116.91,114.85) 117.09,114.92 117.53,114.92 arc(117.78,115.18) 117.53,115.43 117.09,115.43 arc(116.84,115.68) 117.09,115.94 118.46,115.94 arc(118.72,116.19) 118.46,116.45 117.09,116.45 arc(116.84,116.7) 117.09,116.95 117.5,116.95 arc(117.75,117.21) 117.5,117.46 117.09,117.46 arc(116.84,117.72) 117.09,117.97 117.5,117.97 arc(117.75,118.22) 117.5,118.48 117.09,118.48 arc(116.84,118.73) 117.09,118.99 117.5,118.99 arc(117.75,119.24) 117.5,119.49 117.12,119.49 arc(116.94,119.57) 116.87,119.75 arc(116.95,119.95) 117.14,120.03 117.65,120.03 117.78,120.15 117.78,120.76 118.54,121.53 118.86,121.53 arc(119.05,121.6) 119.13,121.79 arc(119.05,121.97) 118.87,122.05 118.69,122.05 arc(118.44,122.3) 118.69,122.56 118.87,122.56 arc(119.13,122.81) 118.87,123.06 118.69,123.06 arc(118.44,123.32) 118.69,123.57 118.87,123.57 arc(119.05,123.65) 119.13,123.83 119.13,127.78 v3(118.69,128.22)
DDR3_A_DQ2: length 43.6
  TOP w0.127: U11.F2 v3(122.69,128.22) ; v2(124.89,105.12) P1.AJ26
  06_SIG2 w0.127: v3(122.69,128.22) 122.29,127.83 122.29,123.99 122,123.69 122,120.84 arc(122.08,120.64) 122.28,120.56 123.69,120.56 arc(123.87,120.48) 123.95,120.3 arc(123.88,120.12) 123.7,120.04 122.3,120.04 arc(122.05,119.79) 122.3,119.53 123.7,119.53 arc(123.95,119.28) 123.7,119.03 122.3,119.03 arc(122.05,118.77) 122.3,118.52 123.7,118.52 arc(123.95,118.26) 123.7,118.01 122.3,118.01 arc(122.05,117.76) 122.3,117.5 123.7,117.5 arc(123.95,117.25) 123.7,116.99 122.3,116.99 arc(122.05,116.74) 122.3,116.49 123.7,116.49 arc(123.95,116.23) 123.7,115.98 122.3,115.98 arc(122.05,115.72) 122.3,115.47 123.7,115.47 arc(123.88,115.4) 123.95,115.22 123.95,107.25 124.38,106.82 124.38,105.63 v2(124.89,105.12)
DDR3_A_DQ3: length 42.1
  TOP w0.127: U11.F8 v3(117.09,128.22) ; v2(126.89,100.12) P1.AD24
  06_SIG2 w0.102: v2(126.89,100.12) 126.39,99.63 125.7,99.63 125.37,99.96 125.37,100.24 125.11,100.5 121.3,100.5 121.16,100.65
  06_SIG2 w0.127: 121.16,100.65 121.03,100.77 119.51,100.77 118.36,101.92 118.36,102.68 115.7,105.35 115.7,121.15 115.57,121.27 115.57,123.33 arc(115.64,123.51) 115.82,123.58 116.73,123.58 arc(116.99,123.84) 116.73,124.09 115.82,124.09 arc(115.57,124.35) 115.82,124.6 116.55,124.6 116.68,124.73 116.68,127.81 v3(117.09,128.22)
DDR3_A_DQ4: length 39.9
  TOP w0.127: U11.H3 v3(121.89,129.82) ; v2(125.89,105.12) P1.AJ25
  06_SIG2 w0.127: v2(125.89,105.12) 126.39,105.63 126.39,106.24 126.01,106.62 125.73,106.62 125.35,107 125.35,110.38 125.12,110.6 125.12,124.4 arc(125.05,124.58) 124.87,124.65 124.18,124.65 arc(123.93,124.9) 124.18,125.16 124.87,125.16 arc(125.12,125.41) 124.87,125.67 124.18,125.67 arc(123.93,125.92) 124.18,126.17 124.87,126.17 arc(125.12,126.43) 124.87,126.68 124.18,126.68 arc(123.93,126.94) 124.18,127.19 124.87,127.19 arc(125.12,127.44) 124.87,127.7 124.18,127.7 arc(123.93,127.95) 124.18,128.21 124.87,128.21 arc(125.12,128.46) 124.87,128.71 124.23,128.71 arc(123.98,128.97) 124.23,129.22 124.87,129.22 arc(125.12,129.48) 124.87,129.73 123.37,129.73 123.05,129.41 122.29,129.41 v3(121.89,129.82)
DDR3_A_DQ5: length 39
  TOP w0.127: v2(126.89,101.12) P1.AE24 ; U11.H8 v3(117.89,129.82)
  06_SIG2 w0.127: v3(117.89,129.82) 118.28,129.43 118.28,125.44 118.01,125.16 118.01,121.63 116.46,120.08 116.46,105.75 118.29,103.92 119.81,103.92 120.4,103.34 120.4,102.96 120.73,102.62 121.09,102.62 121.42,102.29 121.42,101.93 121.74,101.61 126.4,101.61 v2(126.89,101.12)
DDR3_A_DQ6: length 39.6
  TOP w0.127: U11.G2 v3(122.69,129.02) ; v2(125.89,104.12) P1.AH25
  06_SIG2 w0.127: v2(125.89,104.12) 125.4,104.61 125.4,106.31 124.46,107.25 124.46,120.87 arc(124.39,121.05) 124.21,121.12 122.76,121.12 arc(122.5,121.37) 122.76,121.63 124.38,121.63 arc(124.64,121.88) 124.38,122.14 122.76,122.14 arc(122.5,122.39) 122.76,122.64 124.38,122.64 arc(124.64,122.9) 124.38,123.15 122.74,123.15 arc(122.5,123.34) 122.63,123.61 122.67,123.63 arc(122.73,123.65) 122.78,123.66 124.38,123.66 arc(124.64,123.91) 124.38,124.17 123.34,124.17 arc(123.16,124.24) 123.08,124.42 123.08,128.63 v3(122.69,129.02)
DDR3_A_DQ7: length 43.5
  TOP w0.127: U11.H7 v3(118.69,129.82) ; P1.AH26 v2(124.89,103.12)
  06_SIG2 w0.127: v3(118.69,129.82) 119.51,129 119.51,120.99 arc(119.43,120.81) 119.25,120.73 118.52,120.73 arc(118.26,120.48) 118.52,120.23 119.25,120.23 arc(119.51,119.97) 119.25,119.72 118.52,119.72 arc(118.26,119.46) 118.52,119.21 119.25,119.21 arc(119.51,118.96) 119.25,118.7 118.52,118.7 arc(118.26,118.45) 118.52,118.19 119.25,118.19 arc(119.51,117.94) 119.25,117.69 118.52,117.69 arc(118.26,117.43) 118.52,117.18 119.25,117.18 arc(119.43,117.1) 119.51,116.92 119.51,116.22 117.22,113.93 117.22,106.16 118.69,104.69 121.95,104.69 122.38,104.25 122.38,104 122.76,103.62 124.39,103.62 v2(124.89,103.12)
DDR3_A_DQ8: length 31.9
  TOP w0.127: P1.AN27 123.89,109.12 v2(122.89,109.12) ; U11.D7 v3(117.89,126.62)
  03_SIG1 w0.127: v2(122.89,109.12) 122.61,109.12 117.22,114.52 117.22,115.46 117.37,115.61 117.65,115.61 arc(117.9,115.86) 117.65,116.1 117.35,116.1 arc(117.09,116.36) 117.35,116.61 117.63,116.61 arc(117.88,116.87) 117.63,117.12 117.35,117.12 arc(117.09,117.37) 117.35,117.63 117.63,117.63 arc(117.88,117.88) 117.63,118.14 117.35,118.14 arc(117.09,118.39) 117.35,118.64 117.63,118.64 arc(117.88,118.9) 117.63,119.15 117.35,119.15 arc(117.09,119.41) 117.35,119.66 117.63,119.66 arc(117.88,119.91) 117.63,120.17 117.35,120.17 arc(117.09,120.42) 117.35,120.68 117.63,120.68 arc(117.88,120.93) 117.63,121.18 117.37,121.18 arc(117.12,121.44) 117.37,121.69 117.63,121.69 arc(117.81,121.77) 117.88,121.95 117.88,122.51 arc(117.81,122.69) 117.63,122.76 117.42,122.76 arc(117.17,123.02) 117.42,123.27 117.63,123.27 arc(117.88,123.52) 117.63,123.78 117.42,123.78 arc(117.17,124.03) 117.42,124.29 117.63,124.29 arc(117.81,124.36) 117.88,124.54 117.88,125.08 117.48,125.48 117.48,126.21 v3(117.89,126.62)
DDR3_A_DQ9: length 31.7
  TOP w0.127: U11.C3 v3(121.09,125.82) ; P1.AP27 v2(124.89,110.12)
  03_SIG1 w0.127: v3(121.09,125.82) 121.09,125.04 arc(121.01,124.86) 120.83,124.79 120.58,124.79 arc(120.33,124.53) 120.58,124.28 120.83,124.28 arc(121.09,124.02) 120.83,123.77 120.61,123.77 arc(120.47,123.73) 120.38,123.63 arc(120.39,123.38) 120.61,123.26 120.83,123.26 arc(121.09,123.01) 120.83,122.75 120.58,122.75 arc(120.33,122.5) 120.58,122.25 120.83,122.25 arc(121.09,121.99) 120.83,121.74 120.58,121.74 arc(120.33,121.48) 120.58,121.23 120.83,121.23 arc(121.09,120.98) 120.83,120.72 120.58,120.72 arc(120.33,120.47) 120.58,120.21 120.83,120.21 arc(121.09,119.96) 120.83,119.71 120.58,119.71 arc(120.33,119.45) 120.58,119.2 120.83,119.2 arc(121.09,118.94) 120.83,118.69 120.58,118.69 arc(120.33,118.44) 120.58,118.18 120.83,118.18 arc(121.09,117.93) 120.83,117.67 120.58,117.67 arc(120.33,117.42) 120.58,117.17 122.45,117.17 125.09,114.52 125.09,113.68 arc(125.02,113.5) 124.84,113.42 124.28,113.42 arc(124.03,113.17) 124.28,112.91 124.84,112.91 arc(125.09,112.66) 124.84,112.41 124.28,112.41 arc(124.03,112.15) 124.28,111.9 124.84,111.9 arc(125.02,111.82) 125.09,111.64 125.09,110.55 124.89,110.34 v2(124.89,110.12)
DDR3_A_DQ10: length 24.2
  TOP w0.127: U11.C8 v3(117.89,125.82) ; P1.AK26 v2(124.89,106.12)
  03_SIG1 w0.127: v3(117.89,125.82) 118.29,125.41 118.29,114.1 122.78,109.61 123.01,109.61 123.29,109.33 123.29,107.35 124.52,106.12 v2(124.89,106.12)
DDR3_A_DQ11: length 31.6
  TOP w0.127: v2(125.89,109.12) P1.AN25 ; U11.C2 v3(122.69,125.82)
  03_SIG1 w0.127: v3(122.69,125.82) 123.9,125.82 124,125.92 124,126.63 arc(124.09,126.85) 124.31,126.94 125.89,126.94 arc(126.01,126.91) 126.12,126.84 arc(126.18,126.53) 125.92,126.35 124.94,126.35 arc(124.69,126.25) 124.58,125.99 124.58,124.23 arc(124.84,123.98) 125.09,124.23 125.09,125.36 arc(125.13,125.45) 125.22,125.49 125.98,125.49 126.11,125.36 126.11,124.79 arc(126.19,124.59) 126.39,124.51 127.11,124.51 arc(127.29,124.44) 127.37,124.26 arc(127.29,124.08) 127.11,124.01 126.4,124.01 arc(126.19,123.92) 126.11,123.72 126.11,123.28 126.7,122.69 126.7,110.12 125.89,109.31 v2(125.89,109.12)
DDR3_A_DQ12: length 25.1
  TOP w0.127: U11.A7 v3(118.69,124.22) ; P1.AL26 v2(125.89,106.12)
  03_SIG1 w0.127: v3(118.69,124.22) 118.69,115.06 119.05,114.7 arc(119.12,114.52) 119.05,114.34 arc(118.97,114.16) 119.05,113.99 119.05,113.98 arc(119.23,113.91) 119.4,113.98 arc(119.58,114.06) 119.76,113.98 119.76,113.98 arc(119.84,113.8) 119.76,113.62 arc(119.69,113.45) 119.76,113.27 119.77,113.26 arc(119.95,113.19) 120.12,113.26 arc(120.3,113.34) 120.48,113.26 120.48,113.26 arc(120.56,113.08) 120.48,112.91 arc(120.41,112.73) 120.48,112.55 120.49,112.55 arc(120.66,112.47) 120.84,112.55 arc(121.02,112.62) 121.2,112.55 121.2,112.54 arc(121.27,112.37) 121.2,112.19 arc(121.13,112.01) 121.2,111.83 121.2,111.83 arc(121.38,111.75) 121.56,111.83 arc(121.74,111.9) 121.92,111.83 123.6,110.15 123.6,107.61 124.66,106.54 125.47,106.54 v2(125.89,106.12)
DDR3_A_DQ13: length 31.6
  TOP w0.127: v2(125.9,111.06) 126.39,110.57 P1.AP25 ; U11.A2 v3(121.89,124.22)
  03_SIG1 w0.127: v2(125.9,111.06) 125.86,111.1 125.86,118.33 125.72,118.46 125.54,118.46 125.17,118.1 arc(124.99,118.02) 124.8,118.1 arc(124.73,118.27) 124.8,118.44 125.54,119.18 arc(125.54,119.54) 125.18,119.54 124.55,118.9 arc(124.19,118.9) 124.19,119.26 124.82,119.89 arc(124.82,120.25) 124.46,120.25 123.49,119.28 arc(123.13,119.28) 123.13,119.64 124.1,120.61 arc(124.1,120.97) 123.74,120.97 122.32,119.55 arc(121.96,119.55) 121.96,119.91 123.38,121.33 arc(123.46,121.51) 123.38,121.69 arc(123.19,121.77) 123,121.69 122.3,120.99 arc(122.14,120.92) 121.97,120.99 arc(121.89,121.18) 121.97,121.37 122.63,122.03 arc(122.68,122.16) 122.63,122.29 121.89,123.03 v3(121.89,124.22)
DDR3_A_DQ14: length 24.3
  TOP w0.127: U11.B8 v3(117.09,125.82) ; P1.AK27 v2(123.89,106.12)
  03_SIG1 w0.127: v2(123.89,106.12) 122.43,107.58 122.43,108.22 122.05,108.6 121.79,108.6 121.39,109 121.39,109.31 116.67,114.03 116.67,124.68 117.09,125.1 v3(117.09,125.82)
DDR3_A_DQ15: length 31.8
  TOP w0.127: U11.A3 v3(121.89,125.02) ; P1.AP26 v2(125.89,110.12)
  03_SIG1 w0.127: v2(125.89,110.12) 126.34,110.58 126.34,111.21 126.24,111.32 126.24,120.59 arc(126.22,120.66) 126.19,120.71 arc(126.05,120.77) 125.91,120.71 125.63,120.43 arc(125.42,120.35) 125.21,120.43 arc(125.14,120.61) 125.21,120.78 126.19,121.75 arc(126.27,121.95) 126.19,122.14 arc(126.01,122.21) 125.83,122.14 124.89,121.2 arc(124.53,121.2) 124.53,121.56 125.39,122.43 arc(125.39,122.78) 125.03,122.78 124.17,121.92 arc(123.81,121.92) 123.81,122.28 124.67,123.14 arc(124.67,123.5) 124.32,123.5 123.45,122.64 arc(123.09,122.64) 123.09,123 123.96,123.86 arc(123.96,124.22) 123.6,124.22 122.73,123.36 arc(122.37,123.36) 122.37,123.72 122.6,123.95 arc(122.68,124.13) 122.6,124.3 v3(121.89,125.02)
DDR3_A_DQ16: length 29.7
  TOP w0.127: U12.E3 136.33,127.42 v3(134.73,127.42) ; P1.AN23 v2(128.89,109.12)
  06_SIG2 w0.127: v2(128.89,109.12) 128.4,109.61 128.4,116.95 128.79,117.35 arc(128.97,117.42) 129.15,117.35 129.24,117.26 arc(129.59,117.26) 129.59,117.62 129.51,117.71 arc(129.51,118.07) 129.87,118.07 129.95,117.98 arc(130.31,117.98) 130.31,118.34 130.23,118.43 arc(130.23,118.79) 130.59,118.79 130.67,118.7 arc(131.03,118.7) 131.03,119.06 130.95,119.14 arc(130.95,119.5) 131.31,119.5 131.39,119.42 arc(131.75,119.42) 131.75,119.78 131.66,119.86 arc(131.66,120.22) 132.02,120.22 132.11,120.14 arc(132.47,120.14) 132.47,120.5 132.38,120.58 arc(132.38,120.94) 132.74,120.94 132.83,120.86 arc(133.19,120.86) 133.19,121.21 133.1,121.3 arc(133.1,121.66) 133.46,121.66 133.55,121.57 arc(133.91,121.57) 133.91,121.93 133.82,122.02 arc(133.75,122.2) 133.82,122.38 134.73,123.29 v3(134.73,127.42)
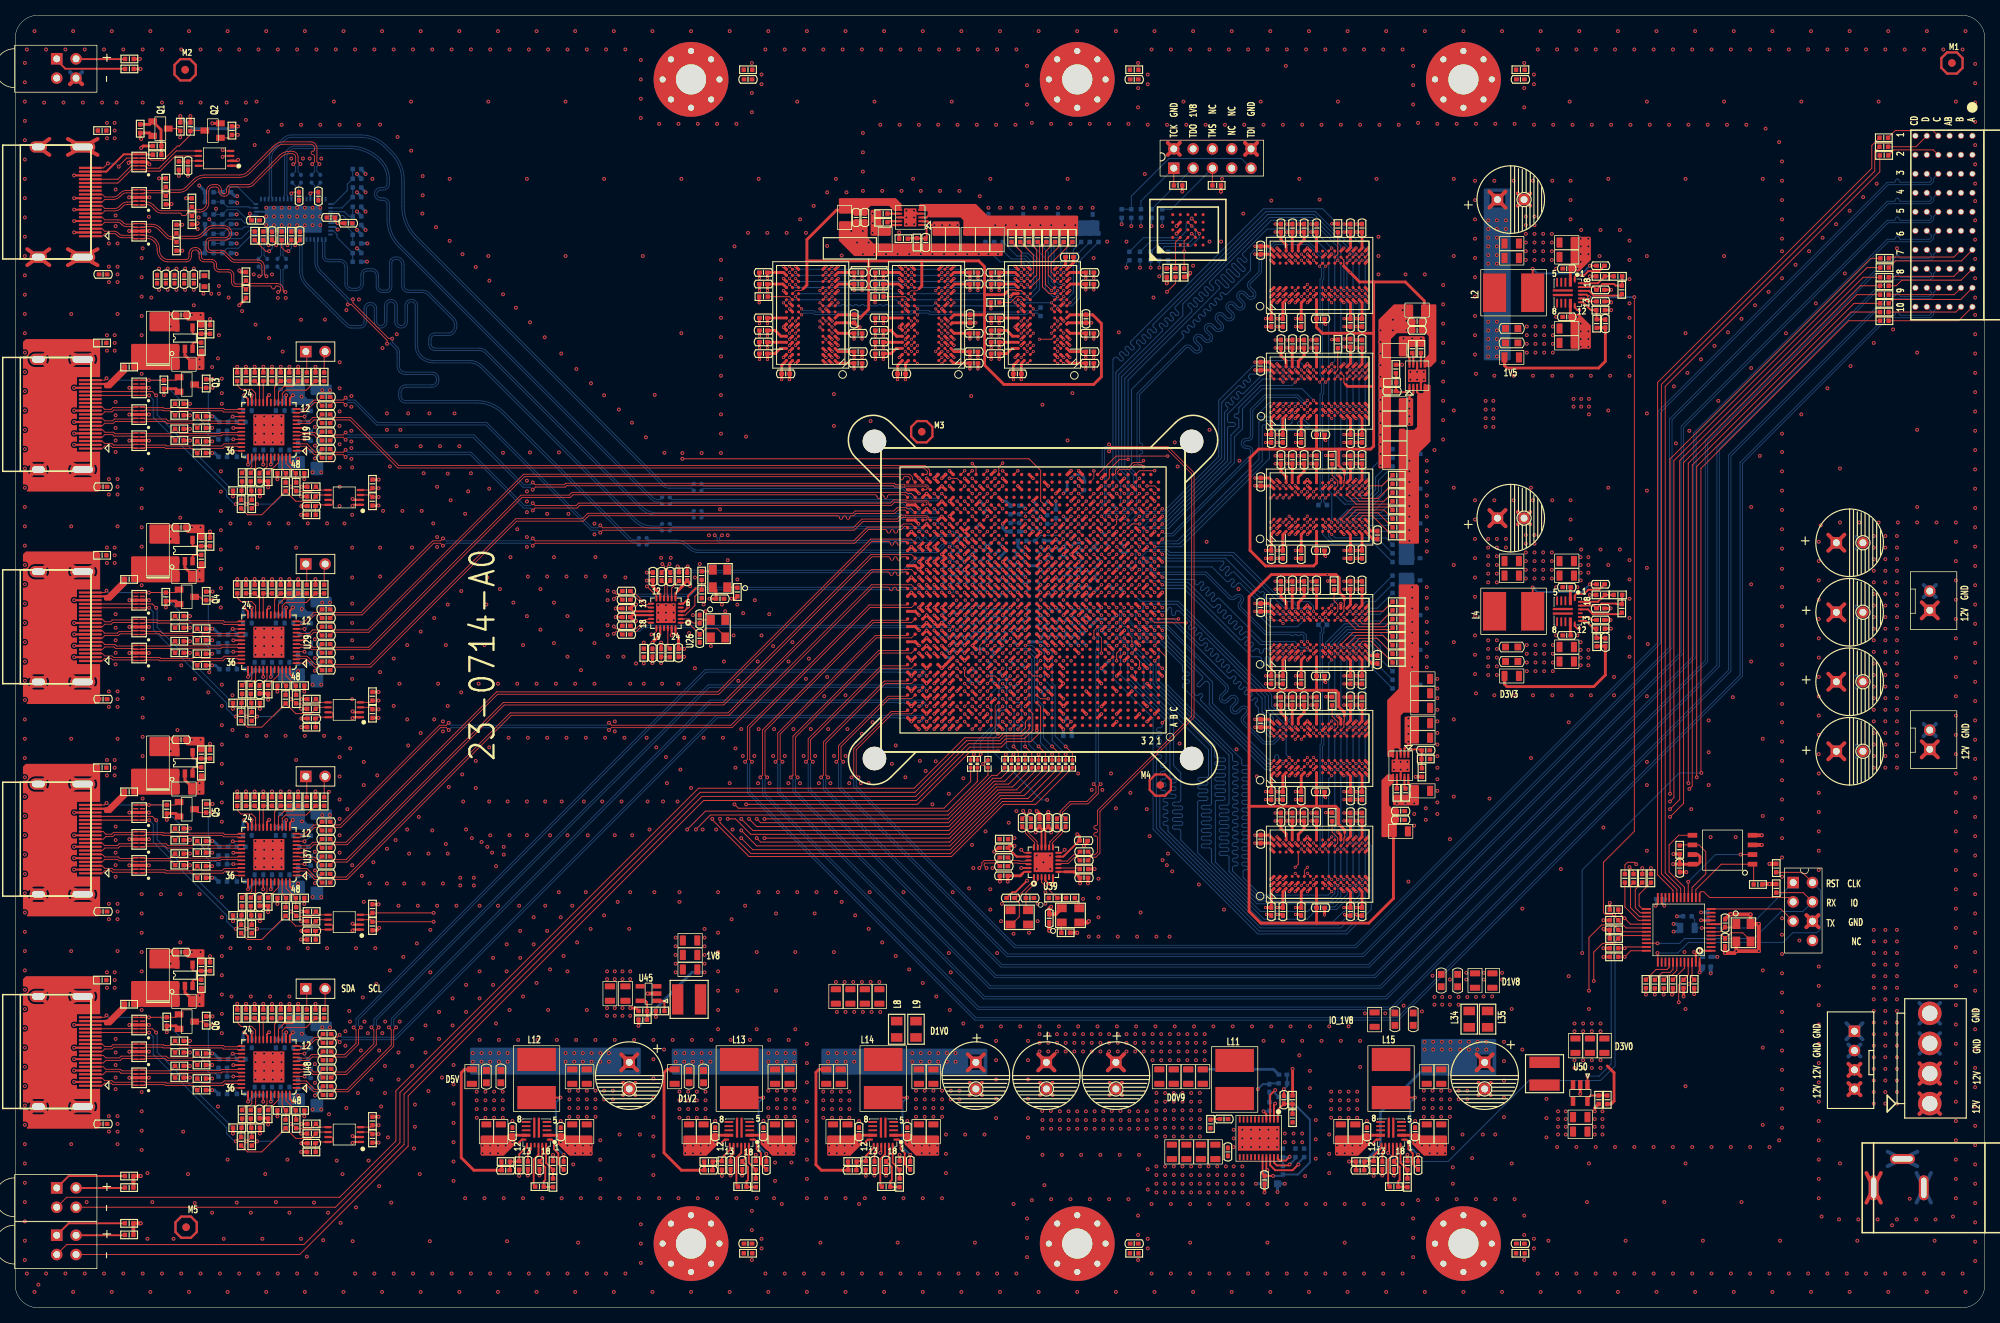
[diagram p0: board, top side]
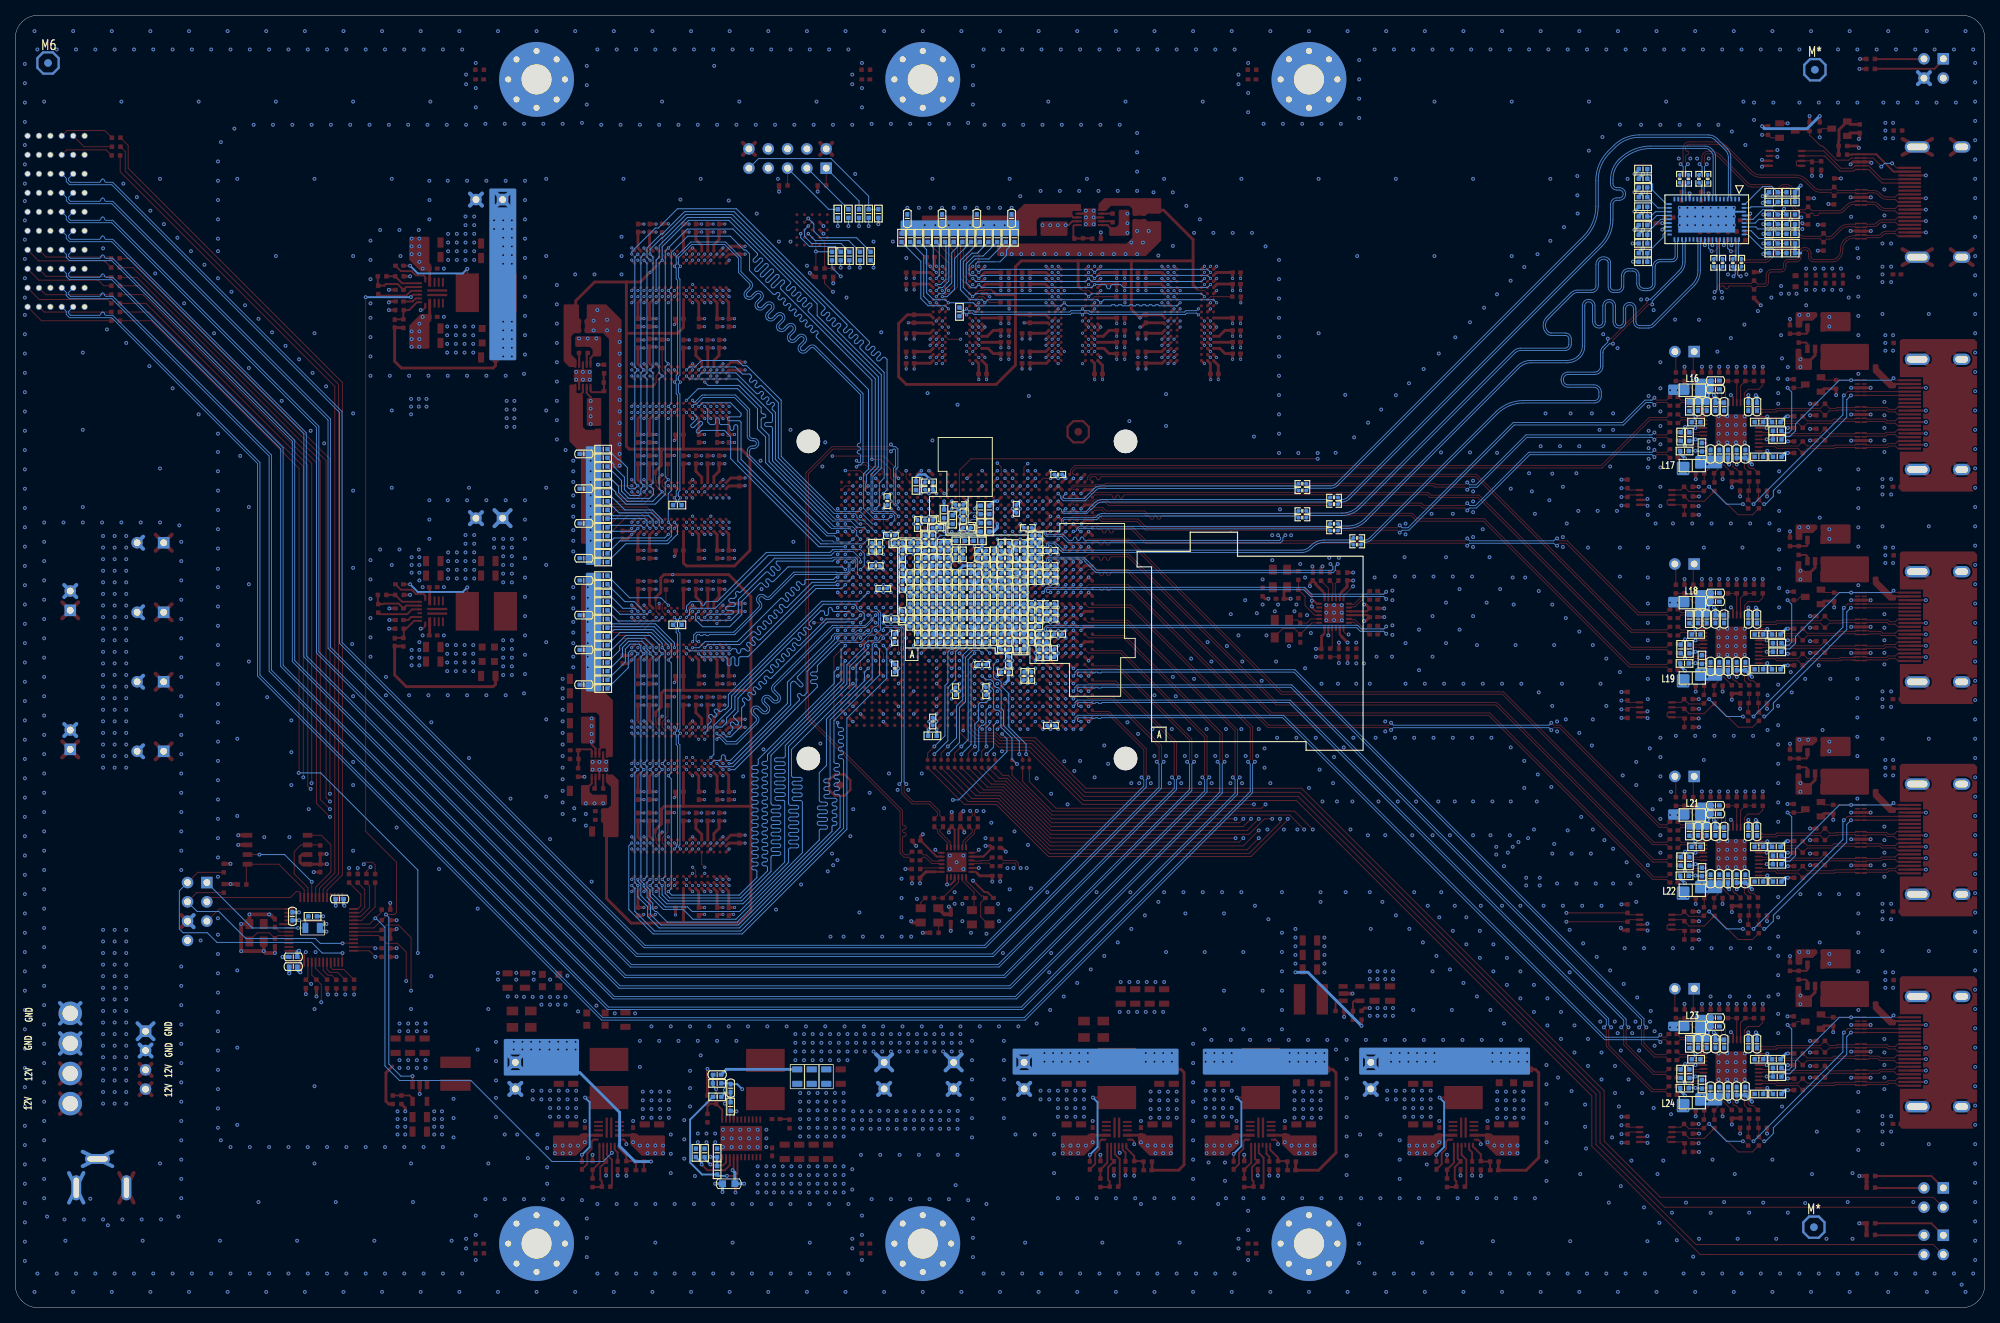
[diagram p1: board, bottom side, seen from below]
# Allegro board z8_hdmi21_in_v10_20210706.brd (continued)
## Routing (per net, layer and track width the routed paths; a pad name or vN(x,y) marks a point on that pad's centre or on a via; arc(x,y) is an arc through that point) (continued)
DDR3_A_DQ17: length 29.6
  TOP w0.127: U12.F7 v3(133.13,128.22) ; P1.AM23 v2(127.89,108.12)
  06_SIG2 w0.127: v3(133.13,128.22) 132.72,127.81 132.72,124.76 131.36,123.4 arc(131.18,123.32) 131,123.4 130.67,123.72 arc(130.31,123.72) 130.31,123.36 130.6,123.08 arc(130.6,122.72) 130.24,122.72 129.95,123 arc(129.6,123) 129.6,122.65 129.88,122.36 arc(129.88,122) 129.52,122 129.24,122.29 arc(128.88,122.29) 128.88,121.93 129.17,121.64 arc(129.17,121.28) 128.81,121.28 128.52,121.57 arc(128.34,121.64) 128.16,121.57 127.08,120.48 127.08,109.21 127.89,108.4 v2(127.89,108.12)
DDR3_A_DQ18: length 30.1
  TOP w0.127: U12.F2 v3(137.93,128.22) ; P1.AP20 v2(131.89,110.12)
  06_SIG2 w0.127: v2(131.89,110.12) 131.89,111.76 132.08,111.95 arc(132.26,112.03) 132.44,111.95 132.68,111.72 arc(133.04,111.72) 133.04,112.08 132.8,112.31 arc(132.8,112.67) 133.16,112.67 133.4,112.44 arc(133.76,112.44) 133.76,112.79 133.52,113.03 arc(133.52,113.39) 133.88,113.39 134.12,113.15 arc(134.48,113.15) 134.48,113.51 134.24,113.75 arc(134.24,114.11) 134.6,114.11 134.84,113.87 arc(135.2,113.87) 135.2,114.23 134.96,114.47 arc(134.96,114.83) 135.32,114.83 135.45,114.69 arc(135.81,114.69) 135.81,115.05 135.68,115.19 arc(135.68,115.55) 136.04,115.55 136.17,115.41 arc(136.53,115.41) 136.53,115.77 136.39,115.91 arc(136.39,116.26) 136.75,116.26 136.89,116.13 arc(137.25,116.13) 137.25,116.49 137.11,116.62 arc(137.04,116.8) 137.11,116.98 138.32,118.19 138.32,127.83 v3(137.93,128.22)
DDR3_A_DQ19: length 26.6
  TOP w0.127: P1.AL24 v2(127.89,107.12) ; U12.F8 v3(132.33,128.22)
  06_SIG2 w0.127: v2(127.89,107.12) 127.33,107.68 127.33,108.45 126.7,109.08 126.7,120.8 130.31,124.41 arc(130.49,124.49) 130.67,124.41 130.95,124.13 arc(131.31,124.13) 131.31,124.49 131.03,124.77 arc(130.95,124.95) 131.03,125.13 131.93,126.03 131.93,127.82 v3(132.33,128.22)
DDR3_A_DQ20: length 30.7
  TOP w0.127: P1.AP21 v2(129.89,110.12) ; U12.H3 v3(137.13,129.82)
  06_SIG2 w0.127: v3(137.13,129.82) 137.53,129.41 137.53,118.12 135.04,115.62 arc(134.86,115.55) 134.68,115.62 134.43,115.87 arc(134.07,115.87) 134.07,115.51 134.32,115.26 arc(134.32,114.9) 133.96,114.9 133.71,115.15 arc(133.35,115.15) 133.35,114.79 133.6,114.54 arc(133.6,114.18) 133.24,114.18 132.99,114.43 arc(132.63,114.43) 132.63,114.08 132.88,113.82 arc(132.88,113.47) 132.52,113.47 132.27,113.72 arc(131.92,113.72) 131.92,113.36 132.17,113.11 arc(132.17,112.75) 131.81,112.75 131.56,113 arc(131.2,113) 131.2,112.64 131.45,112.39 arc(131.52,112.21) 131.45,112.03 129.89,110.47 v2(129.89,110.12)
DDR3_A_DQ21: length 26.7
  TOP w0.127: U12.H8 v3(132.33,129.82) ; v2(126.89,107.12) P1.AL25
  06_SIG2 w0.127: v2(126.89,107.12) 126.31,107.7 126.31,121.05 131.44,126.18 131.44,128.21 131.93,128.7 131.93,129.43 v3(132.33,129.82)
DDR3_A_DQ22: length 30.7
  TOP w0.127: U12.G2 v3(137.13,129.02) ; v2(129.89,111.12) 129.39,110.62 P1.AP22
  06_SIG2 w0.127: v2(129.89,111.12) 130.43,111.67 130.43,113.02 134.18,116.76 arc(134.31,116.82) 134.43,116.76 134.75,116.45 arc(135.11,116.45) 135.11,116.81 134.79,117.12 arc(134.72,117.3) 134.79,117.48 arc(134.97,117.56) 135.15,117.48 135.47,117.17 arc(135.83,117.17) 135.83,117.53 135.51,117.84 arc(135.44,118.02) 135.51,118.2 arc(135.69,118.28) 135.87,118.2 136.19,117.89 arc(136.54,117.89) 136.54,118.25 135.28,119.51 arc(135.2,119.69) 135.28,119.87 arc(135.46,119.95) 135.65,119.87 136.26,119.26 arc(136.45,119.18) 136.65,119.26 arc(136.72,119.43) 136.65,119.59 135.98,120.26 arc(135.91,120.42) 135.98,120.58 136.73,121.33 136.73,128.63 v3(137.13,129.02)
DDR3_A_DQ23: length 30.6
  TOP w0.127: U12.H7 v3(133.13,129.82) ; P1.AN24 v2(127.89,109.12)
  06_SIG2 w0.127: v2(127.89,109.12) 127.46,109.55 127.46,118.85 127.71,119.11 arc(127.79,119.29) 127.71,119.47 127.6,119.58 arc(127.6,119.94) 127.96,119.94 128.02,119.88 arc(128.38,119.88) 128.38,120.24 128.1,120.52 arc(128.1,120.88) 128.46,120.88 128.79,120.55 arc(128.97,120.47) 129.15,120.55 130.51,121.91 130.76,121.91 131.11,121.56 arc(131.27,121.49) 131.42,121.56 131.72,121.86 131.72,122.11 131.89,122.28 arc(131.97,122.46) 131.89,122.64 131.76,122.77 arc(131.76,123.13) 132.12,123.13 132.38,122.87 arc(132.55,122.8) 132.72,122.87 arc(132.79,123.06) 132.72,123.25 132.47,123.49 arc(132.47,123.85) 132.83,123.85 133.05,123.63 arc(133.24,123.56) 133.43,123.63 133.52,123.73 133.52,129.43 v3(133.13,129.82)
DDR3_A_DQ24: length 31.4
  TOP w0.127: P1.AL23 v2(128.89,107.12) ; U12.D7 v3(133.13,126.62)
  03_SIG1 w0.127: v2(128.89,107.12) 129.39,107.62 129.39,111.32 129.41,111.34 129.41,115.96 130.44,116.99 arc(130.51,117.16) 130.44,117.33 129.87,117.9 arc(129.87,118.26) 130.23,118.26 130.78,117.71 arc(130.97,117.63) 131.16,117.71 arc(131.23,117.88) 131.16,118.05 130.64,118.56 arc(130.64,118.92) 131,118.92 131.51,118.42 arc(131.87,118.42) 131.87,118.78 131.36,119.28 arc(131.36,119.64) 131.72,119.64 132.23,119.14 arc(132.59,119.14) 132.59,119.5 132.08,120 arc(132.08,120.36) 132.44,120.36 132.93,119.87 arc(133.12,119.79) 133.32,119.87 133.99,120.54 133.99,124.83 133.53,125.29 133.53,126.21 v3(133.13,126.62)
DDR3_A_DQ25: length 32.8
  TOP w0.127: v2(128.89,103.12) P1.AG23 ; U12.C3 v3(137.13,125.82)
  03_SIG1 w0.127: v2(128.89,103.12) 129.09,103.12 132.69,106.72 132.69,110.25 135.43,112.99 arc(135.53,113.22) 135.43,113.45 134.59,114.29 arc(134.52,114.48) 134.59,114.67 arc(134.8,114.76) 135.01,114.67 135.3,114.38 arc(135.66,114.38) 135.66,114.74 135.38,115.02 arc(135.38,115.38) 135.74,115.38 136.21,114.91 arc(136.57,114.91) 136.57,115.27 136.1,115.74 arc(136.1,116.1) 136.46,116.1 136.56,116 arc(136.92,116) 136.92,116.36 136.86,116.42 arc(136.78,116.6) 136.86,116.78 137.53,117.46 137.53,125.41 v3(137.13,125.82)
DDR3_A_DQ26: length 32
  TOP w0.127: P1.AK24 v2(127.89,106.12) ; U12.C8 v3(133.13,125.82)
  03_SIG1 w0.127: v3(133.13,125.82) 133.13,125.02 133.6,124.54 133.6,121.86 133.47,121.72 133.29,121.72 133.17,121.84 arc(132.97,121.92) 132.77,121.84 arc(132.7,121.67) 132.77,121.49 133.14,121.12 arc(133.14,120.76) 132.79,120.76 132.41,121.14 arc(132.33,121.19) 132.23,121.21 arc(132.12,121.19) 132.03,121.13 131.24,120.34 arc(131.06,120.27) 130.88,120.34 130.22,121.01 arc(129.86,121.01) 129.86,120.65 130.53,119.98 arc(130.53,119.62) 130.17,119.62 129.52,120.26 arc(129.17,120.26) 129.17,119.9 129.82,119.25 arc(129.88,119.11) 129.82,118.96 arc(129.73,118.9) 129.63,118.88 129.28,118.88 arc(129.11,118.81) 129.03,118.63 129.03,117.64 arc(129.09,117.49) 129.24,117.42 129.55,117.42 arc(129.71,117.36) 129.78,117.2 arc(129.7,117) 129.5,116.92 129.24,116.92 arc(129.09,116.85) 129.03,116.7 129.03,111.19 128.39,110.54 128.39,106.62 v2(127.89,106.12)
DDR3_A_DQ27: length 31.4
  TOP w0.127: P1.AK23 v2(128.89,105.12) ; U12.C2 v3(137.13,126.62)
  03_SIG1 w0.127: v2(128.89,105.12) 129.39,105.62 130.07,105.62 131.32,106.87 131.32,112.71 136.65,118.05 136.65,120.09 arc(136.58,120.27) 136.4,120.35 136.37,120.35 arc(136.12,120.6) 136.37,120.85 136.4,120.85 arc(136.65,121.11) 136.4,121.36 136.27,121.36 arc(136.02,121.62) 136.27,121.87 136.4,121.87 arc(136.65,122.12) 136.4,122.38 136.27,122.38 arc(136.02,122.63) 136.27,122.89 136.4,122.89 arc(136.65,123.14) 136.4,123.39 136.27,123.39 arc(136.02,123.65) 136.27,123.9 136.4,123.9 arc(136.65,124.16) 136.4,124.41 136.27,124.41 arc(136.02,124.66) 136.27,124.92 136.4,124.92 arc(136.65,125.17) 136.4,125.43 136.27,125.43 arc(136.02,125.68) 136.27,125.93 136.44,125.93 v3(137.13,126.62)
DDR3_A_DQ28: length 32.3
  TOP w0.127: v2(127.89,102.12) P1.AF24 ; U12.A7 v3(133.13,124.22)
  03_SIG1 w0.127: v3(133.13,124.22) 132.72,123.81 132.72,123.64 133.06,123.3 arc(133.06,122.93) 132.68,122.93 132,123.62 arc(131.82,123.69) 131.64,123.63 arc(131.54,123.44) 131.62,123.24 132.04,122.81 arc(132.04,122.45) 131.68,122.45 131.29,122.84 arc(131.1,122.92) 130.91,122.84 130.58,122.51 arc(130.5,122.34) 130.58,122.16 131.27,121.47 arc(131.34,121.3) 131.27,121.12 arc(131.08,121.04) 130.9,121.12 130.26,121.76 arc(130.07,121.84) 129.88,121.76 128.65,120.54 128.65,111.55 127.48,110.39 127.48,102.53 v2(127.89,102.12)
DDR3_A_DQ29: length 32.5
  TOP w0.127: v2(128.89,102.12) P1.AF23 ; U12.A2 v3(137.93,124.22)
  03_SIG1 w0.127: v3(137.93,124.22) 137.93,116.38 137.19,115.64 137.19,114.87 136.75,114.44 136.75,113.63 136.43,113.3 arc(136.35,113.12) 136.43,112.94 136.66,112.7 arc(136.66,112.34) 136.31,112.34 136.07,112.58 arc(135.71,112.58) 135.71,112.22 135.95,111.98 arc(135.95,111.63) 135.59,111.63 135.35,111.86 arc(134.99,111.86) 134.99,111.5 135.23,111.27 arc(135.23,110.91) 134.87,110.91 134.63,111.14 arc(134.27,111.14) 134.27,110.79 134.51,110.55 arc(134.51,110.19) 134.15,110.19 133.91,110.43 arc(133.73,110.5) 133.55,110.43 133.07,109.94 133.07,106.46 130.43,103.82 130.43,103.01 129.54,102.12 v2(128.89,102.12)
DDR3_A_DQ30: length 32.1
  TOP w0.127: v2(126.89,105.12) P1.AJ24 ; U12.B8 v3(132.33,125.02)
  03_SIG1 w0.127: v3(132.33,125.02) 131.42,124.12 arc(131.24,124.04) 131.06,124.12 130.54,124.64 arc(130.19,124.64) 130.19,124.28 130.71,123.76 arc(130.71,123.4) 130.35,123.4 129.83,123.92 arc(129.5,123.95) 129.41,123.63 arc(129.44,123.59) 129.47,123.56 129.99,123.04 arc(129.99,122.68) 129.63,122.68 129.11,123.2 arc(128.75,123.2) 128.75,122.84 129.27,122.32 arc(129.27,121.96) 128.91,121.96 128.39,122.48 arc(128.03,122.48) 128.03,122.12 128.55,121.6 arc(128.62,121.42) 128.55,121.24 128.27,120.96 128.27,111.75 127.08,110.55 127.08,109.36 126.36,108.65 126.36,105.64 v2(126.89,105.12)
DDR3_A_DQ31: length 33
  TOP w0.127: U12.A3 v3(137.13,124.22) ; P1.AK22 v2(129.89,105.12)
  03_SIG1 w0.127: v3(137.13,124.22) 137.13,117.91 133.94,114.73 arc(133.84,114.48) 133.94,114.24 134.78,113.41 arc(134.78,113.05) 134.42,113.05 133.52,113.95 arc(133.16,113.95) 133.16,113.59 134.06,112.69 arc(134.06,112.33) 133.7,112.33 132.78,113.25 arc(132.63,113.31) 132.47,113.25 arc(132.39,113.05) 132.47,112.85 133.29,112.02 arc(133.29,111.66) 132.93,111.66 132.22,112.37 arc(131.87,112.37) 131.87,112.01 132.19,111.68 arc(132.28,111.56) 132.31,111.41 132.31,106.97 130.46,105.12 v2(129.89,105.12)
DDR3_A_DQ32: length 84.2
  TOP w0.127: U10.E3 v3(106.65,127.42) ; v2(123.89,77.12) P1.B27
  06_SIG2 w0.127: v2(123.89,77.12) 123.41,76.64 118.69,76.64 118.36,76.97 118.36,77.28 116.88,78.77 116.88,79.65 113.65,82.88 arc(113.47,82.96) 113.29,82.88 113,82.59 arc(112.64,82.59) 112.64,82.95 112.93,83.24 arc(112.93,83.6) 112.57,83.6 112.28,83.31 arc(111.92,83.31) 111.92,83.67 112.21,83.96 arc(112.21,84.32) 111.85,84.32 111.57,84.03 arc(111.21,84.03) 111.21,84.39 111.49,84.68 arc(111.49,85.04) 111.14,85.04 110.85,84.75 arc(110.49,84.75) 110.49,85.11 110.78,85.4 arc(110.78,85.76) 110.42,85.76 110.13,85.47 arc(109.77,85.47) 109.77,85.83 110.06,86.12 arc(110.06,86.47) 109.7,86.47 109.41,86.19 arc(109.05,86.19) 109.05,86.55 109.34,86.83 arc(109.34,87.19) 108.98,87.19 108.69,86.9 arc(108.33,86.9) 108.33,87.26 108.62,87.55 arc(108.62,87.91) 108.26,87.91 107.97,87.62 arc(107.61,87.62) 107.61,87.98 107.9,88.27 arc(107.9,88.63) 107.54,88.63 107.25,88.34 arc(106.9,88.34) 106.9,88.7 107.18,88.99 arc(107.18,89.35) 106.82,89.35 106.54,89.06 arc(106.18,89.06) 106.18,89.42 106.47,89.71 arc(106.47,90.07) 106.11,90.07 105.82,89.78 arc(105.46,89.78) 105.46,90.14 105.75,90.43 arc(105.82,90.61) 105.75,90.79 arc(105.57,90.86) 105.39,90.79 105.19,90.59 arc(104.83,90.59) 104.83,90.94 105.03,91.14 arc(105.1,91.32) 105.03,91.5 104.8,91.73 104.8,91.94 arc(104.87,92.11) 105.05,92.19 105.7,92.19 arc(105.96,92.44) 105.7,92.7 105.05,92.7 arc(104.8,92.95) 105.05,93.21 105.67,93.21 arc(105.83,93.26) 105.92,93.41 arc(105.86,93.62) 105.67,93.71 105.01,93.71 arc(104.86,93.77) 104.8,93.92 104.8,121.7 106.2,123.1 106.2,126.97 v3(106.65,127.42)
DDR3_A_DQ33: length 74.8
  TOP w0.127: v2(126.89,76.12) P1.A24 ; U10.F7 v3(102.65,128.22)
  06_SIG2 w0.127: v3(102.65,128.22) 103.12,127.74 103.12,124.09 102.34,123.3 102.34,121.28 arc(102.26,121.1) 102.08,121.03 102.03,121.03 arc(101.78,120.77) 102.03,120.52 102.08,120.52 arc(102.34,120.26) 102.08,120.01 102.03,120.01 arc(101.78,119.76) 102.03,119.5 102.08,119.5 arc(102.34,119.25) 102.08,118.99 102.03,118.99 arc(101.78,118.74) 102.03,118.49 102.08,118.49 arc(102.26,118.41) 102.34,118.23 102.34,89.23 117.64,73.93 124.94,73.93 126.89,75.87 v2(126.89,76.12)
DDR3_A_DQ34: length 83.8
  TOP w0.127: v2(124.89,77.12) P1.A26 ; U10.F2 v3(107.45,128.22)
  06_SIG2 w0.127: v2(124.89,77.12) 124.4,77.61 118.72,77.61 117.35,78.98 117.35,79.74 106.38,90.72 106.38,94.21 arc(106.33,94.32) 106.22,94.36 105.46,94.36 arc(105.21,94.62) 105.46,94.87 106.1,94.87 arc(106.35,95.13) 106.1,95.38 105.46,95.38 arc(105.21,95.63) 105.46,95.89 106.1,95.89 arc(106.35,96.14) 106.1,96.4 105.46,96.4 arc(105.21,96.65) 105.46,96.9 106.1,96.9 arc(106.35,97.16) 106.1,97.41 105.46,97.41 arc(105.21,97.67) 105.46,97.92 106.1,97.92 arc(106.35,98.17) 106.1,98.43 105.46,98.43 arc(105.21,98.68) 105.46,98.94 106.1,98.94 arc(106.35,99.19) 106.1,99.44 105.46,99.44 arc(105.21,99.7) 105.46,99.95 106.1,99.95 arc(106.35,100.21) 106.1,100.46 105.46,100.46 arc(105.21,100.71) 105.46,100.97 106.1,100.97 arc(106.35,101.22) 106.1,101.48 105.46,101.48 arc(105.21,101.73) 105.46,101.98 106.1,101.98 arc(106.35,102.24) 106.1,102.49 105.46,102.49 arc(105.21,102.75) 105.46,103 106.1,103 arc(106.35,103.25) 106.1,103.51 105.46,103.51 arc(105.21,103.76) 105.46,104.02 106.07,104.02 arc(106.32,104.27) 106.07,104.52 105.34,104.52 105.21,104.66 105.21,121.48 107.05,123.32 107.05,127.83 v3(107.45,128.22)
DDR3_A_DQ35: length 78.5
  TOP w0.127: P1.B23 v2(127.89,77.12) ; U10.F8 v3(101.85,128.22)
  06_SIG2 w0.127: v3(101.85,128.22) 101.44,127.81 101.44,124.52 100.36,123.44 100.36,121.28 arc(100.43,121.1) 100.61,121.03 100.66,121.03 arc(100.91,120.77) 100.66,120.52 100.61,120.52 arc(100.36,120.26) 100.61,120.01 100.66,120.01 arc(100.91,119.76) 100.66,119.5 100.61,119.5 arc(100.36,119.25) 100.61,118.99 100.66,118.99 arc(100.86,118.9) 100.91,118.69 100.91,89.58 117.32,73.16 125.43,73.16 127.89,75.63 v2(127.89,77.12)
DDR3_A_DQ36: length 84.1
  TOP w0.127: P1.C27 v2(123.89,79.12) ; U10.H3 v3(106.65,129.82)
  06_SIG2 w0.127: v2(123.89,79.12) 123.44,79.57 118.64,79.57 117.33,80.87 arc(117.26,81.05) 117.33,81.23 117.42,81.32 arc(117.42,81.68) 117.06,81.68 116.98,81.59 arc(116.62,81.59) 116.62,81.95 116.7,82.04 arc(116.7,82.4) 116.34,82.4 116.26,82.31 arc(115.9,82.31) 115.9,82.67 115.98,82.76 arc(116.02,83.07) 115.72,83.18 arc(115.67,83.15) 115.62,83.11 115.54,83.03 arc(115.18,83.03) 115.18,83.39 115.26,83.47 arc(115.26,83.83) 114.91,83.83 114.82,83.75 arc(114.46,83.75) 114.46,84.11 114.55,84.19 arc(114.55,84.55) 114.19,84.55 114.1,84.47 arc(113.74,84.47) 113.74,84.83 113.83,84.91 arc(113.83,85.27) 113.47,85.27 113.38,85.18 arc(113.02,85.18) 113.02,85.54 113.11,85.63 arc(113.11,85.99) 112.75,85.99 112.67,85.9 arc(112.31,85.9) 112.31,86.26 112.39,86.35 arc(112.39,86.71) 112.03,86.71 111.95,86.62 arc(111.59,86.62) 111.59,86.98 111.67,87.07 arc(111.67,87.43) 111.31,87.43 111.23,87.34 arc(110.87,87.34) 110.87,87.7 110.95,87.78 arc(110.95,88.14) 110.6,88.14 110.51,88.06 arc(110.15,88.06) 110.15,88.42 110.24,88.5 arc(110.24,88.86) 109.88,88.86 109.79,88.78 arc(109.43,88.78) 109.43,89.14 109.52,89.22 arc(109.52,89.58) 109.16,89.58 109.07,89.5 arc(108.71,89.5) 108.71,89.85 108.8,89.94 arc(108.8,90.3) 108.44,90.3 108.35,90.21 arc(108.17,90.14) 108,90.21 arc(107.92,90.39) 108,90.57 108.08,90.66 arc(108.08,91.02) 107.72,91.02 107.64,90.93 arc(107.46,90.86) 107.28,90.93 107.19,91.02 107.19,105.55 arc(107.11,105.73) 106.93,105.81 106.45,105.81 arc(106.2,106.06) 106.45,106.32 106.93,106.32 arc(107.11,106.39) 107.19,106.57 107.19,116.75 arc(107.11,116.93) 106.93,117.01 106.4,117.01 arc(106.15,117.26) 106.4,117.51 106.93,117.51 arc(107.19,117.77) 106.93,118.02 106.4,118.02 arc(106.15,118.28) 106.4,118.53 106.93,118.53 arc(107.19,118.78) 106.93,119.04 106.4,119.04 arc(106.15,119.29) 106.4,119.55 106.93,119.55 arc(107.19,119.8) 106.93,120.05 106.4,120.05 arc(106.15,120.31) 106.4,120.56 106.93,120.56 arc(107.19,120.82) 106.93,121.07 106.75,121.07 arc(106.49,121.32) 106.75,121.58 106.93,121.58 arc(107.11,121.65) 107.19,121.83 107.19,122.24 108.71,123.76 108.71,128.33 107.62,129.43 107.04,129.43 v3(106.65,129.82)
DDR3_A_DQ37: length 74.3
  TOP w0.127: U10.H8 v3(101.85,129.82) ; v2(125.89,76.12) P1.A25
  06_SIG2 w0.127: v2(125.89,76.12) 124.45,74.69 117.95,74.69 103.1,89.54 103.1,122.77 103.89,123.56 103.89,127.95 arc(103.96,128.13) 104.14,128.21 104.27,128.21 arc(104.52,128.46) 104.27,128.71 104.14,128.71 arc(103.96,128.79) 103.89,128.97 103.89,129.25 102.87,130.26 102.29,130.26 v3(101.85,129.82)
DDR3_A_DQ38: length 84.1
  TOP w0.127: P1.B26 v2(124.89,78.12) ; U10.G2 v3(107.45,129.02)
  06_SIG2 w0.127: v2(124.89,78.12) 124.46,78.55 118.75,78.55 118.41,78.88 118.41,79.24 106.78,90.87 106.78,105.17 106.65,105.3 105.72,105.3 105.59,105.42 105.59,106.69 105.72,106.82 106.5,106.82 arc(106.76,107.07) 106.5,107.33 105.84,107.33 arc(105.59,107.58) 105.84,107.84 106.5,107.84 arc(106.76,108.09) 106.5,108.34 105.84,108.34 arc(105.59,108.6) 105.84,108.85 106.5,108.85 arc(106.76,109.11) 106.5,109.36 105.84,109.36 arc(105.59,109.61) 105.84,109.87 106.5,109.87 arc(106.76,110.12) 106.5,110.38 105.84,110.38 arc(105.59,110.63) 105.84,110.88 106.5,110.88 arc(106.76,111.14) 106.5,111.39 105.84,111.39 arc(105.59,111.65) 105.84,111.9 106.5,111.9 arc(106.76,112.15) 106.5,112.41 105.84,112.41 arc(105.59,112.66) 105.84,112.92 106.5,112.92 arc(106.76,113.17) 106.5,113.42 105.84,113.42 arc(105.59,113.68) 105.84,113.93 106.5,113.93 arc(106.76,114.19) 106.5,114.44 105.84,114.44 arc(105.59,114.69) 105.84,114.95 106.5,114.95 arc(106.76,115.2) 106.5,115.46 105.84,115.46 arc(105.59,115.71) 105.84,115.96 106.43,115.96 arc(106.69,116.22) 106.43,116.47 105.72,116.47 105.59,116.6 105.59,121.27 107.85,123.53 107.85,128.62 v3(107.45,129.02)
DDR3_A_DQ39: length 74.3
  TOP w0.127: U10.H7 v3(102.65,129.82) ; P1.B25 v2(126.89,77.12)
  06_SIG2 w0.127: v3(102.65,129.82) 103.5,128.96 103.5,123.81 102.72,123.02 102.72,89.39 117.8,74.31 124.71,74.31 126.39,75.98 126.39,76.63 v2(126.89,77.12)
DDR3_A_DQS0N: length 37.7
  TOP w0.114: P1.AF25 v2(125.89,102.12) ; U11.G3 v3(121.89,129.02)
  06_SIG2 w0.102: v2(125.89,102.12) 126.07,102.12 126.17,102.22 126.17,102.63 124.59,104.2 123.44,104.2 122.14,105.51 121.76,105.51 121.72,105.46 121.69,105.46
  06_SIG2 w0.114: v3(121.89,129.02) 121.65,128.78 120.63,128.78 120.33,128.48 120.33,115.71 118.05,113.43 118.05,112.18 arc(118.24,111.71) 118.71,111.52 118.86,111.52 arc(119.1,111.42) 119.2,111.18 arc(119.09,110.94) 118.85,110.83 118.71,110.83 arc(118.24,110.64) 118.05,110.17 118.05,106.87 118.93,105.98 120.65,105.98 121.17,105.46 121.69,105.46
DDR3_A_DQS0P: length 37.7
  TOP w0.114: U11.F3 v3(121.89,128.22) ; P1.AG25 v2(126.89,102.12)
  06_SIG2 w0.102: v2(126.89,102.12) 126.53,102.12 126.4,102.25 126.4,102.72 124.69,104.43 123.54,104.43 122.23,105.74 121.76,105.74 121.72,105.78 121.69,105.78
  06_SIG2 w0.114: 121.69,105.78 121.3,105.78 120.78,106.3 119.06,106.3 118.36,107 118.36,110.17 arc(118.46,110.42) 118.71,110.52 118.85,110.52 arc(119.32,110.71) 119.51,111.18 arc(119.32,111.64) 118.86,111.84 118.71,111.84 arc(118.46,111.94) 118.36,112.18 118.36,113.3 120.65,115.58 120.65,127.23 arc(120.72,127.39) 120.88,127.46 arc(121.11,127.68) 120.88,127.91 arc(120.72,127.98) 120.65,128.14 120.65,128.35 120.76,128.46 121.65,128.46 v3(121.89,128.22)
DDR3_A_DQS1N: length 31.9
  TOP w0.114: U11.B7 v3(118.69,125.82)
  TOP w0.127: v2(125.89,107.12) P1.AM26
  03_SIG1 w0.114: v2(125.89,107.12) 125.89,107.22 125.72,107.39 124.58,107.39 124.14,107.82 124.14,110.59 122.54,112.2 arc(122.34,112.67) 122.54,113.13 123.48,114.08 arc(123.58,114.32) 123.48,114.56 arc(123.24,114.66) 123,114.56 122.05,113.62 arc(121.12,113.62) 121.12,114.55 122.06,115.5 arc(122.16,115.74) 122.06,115.98 arc(121.82,116.08) 121.58,115.98 120.63,115.04 arc(120.16,114.84) 119.7,115.04 119.38,115.35 119.38,125.95 119.27,126.06 118.93,126.06 v3(118.69,125.82)
DDR3_A_DQS1P: length 31.9
  TOP w0.114: U11.C7 v3(118.69,126.62)
  TOP w0.127: v2(125.89,108.12) P1.AM25
  03_SIG1 w0.114: v2(125.89,108.12) 125.47,107.71 124.71,107.71 124.46,107.95 124.46,110.72 122.76,112.42 arc(122.66,112.67) 122.76,112.91 123.71,113.85 arc(123.9,114.32) 123.71,114.79 arc(123.24,114.98) 122.77,114.79 121.83,113.84 arc(121.34,113.84) 121.34,114.33 122.29,115.27 arc(122.48,115.74) 122.29,116.21 arc(121.82,116.4) 121.35,116.21 120.41,115.26 arc(120.16,115.16) 119.92,115.26 119.7,115.49 119.7,126.08 119.4,126.38 118.93,126.38 v3(118.69,126.62)
DDR3_A_DQS2N: length 31.8
  TOP w0.114: U12.G3 v3(136.33,129.02)
  TOP w0.127: P1.AN22 v2(128.89,108.12)
  06_SIG2 w0.102: v2(128.89,108.12) 129.27,108.51 129.27,111.35 129.23,111.39 129.23,111.42
  06_SIG2 w0.114: v3(136.33,129.02) 136.23,128.92 135.81,128.92 135.51,128.61 135.51,128.4 135.51,121.91 133.8,120.2 arc(133.61,119.73) 133.8,119.27 134.14,118.93 arc(134.24,118.69) 134.14,118.45 arc(133.9,118.34) 133.65,118.45 133.32,118.78 arc(132.38,118.78) 132.38,117.85 132.72,117.51 arc(132.82,117.27) 132.72,117.03 arc(132.48,116.93) 132.23,117.03 131.9,117.36 arc(130.96,117.36) 130.96,116.43 131.3,116.09 arc(131.4,115.85) 131.3,115.61 arc(131.06,115.51) 130.82,115.61 130.48,115.94 arc(130.01,116.14) 129.55,115.94 129.23,115.63 129.23,111.42
DDR3_A_DQS2P: length 31.9
  TOP w0.114: U12.F3 v3(136.33,128.22)
  TOP w0.127: P1.AM22 v2(129.89,108.12)
  06_SIG2 w0.102: v2(129.89,108.12) 129.78,108.02 129.6,108.02 129.5,108.12 129.5,111.35 129.55,111.39 129.55,111.42
  06_SIG2 w0.114: v3(136.33,128.22) 136.33,128.51 136.24,128.6 135.95,128.6 135.83,128.48 135.83,128.4 135.83,121.78 134.03,119.98 arc(133.93,119.73) 134.03,119.49 134.36,119.15 arc(134.56,118.69) 134.36,118.22 arc(133.9,118.03) 133.43,118.22 133.09,118.56 arc(132.61,118.56) 132.61,118.07 132.94,117.74 arc(133.14,117.27) 132.94,116.8 arc(132.48,116.61) 132.01,116.8 131.67,117.14 arc(131.19,117.14) 131.19,116.65 131.52,116.32 arc(131.72,115.85) 131.52,115.38 arc(131.06,115.19) 130.59,115.38 130.25,115.72 arc(130.01,115.82) 129.77,115.72 129.55,115.49 129.55,111.42
DDR3_A_DQS3N: length 32.5
  TOP w0.114: U12.B7 v3(133.93,125.82) ; v2(127.89,104.12) P1.AH24
  03_SIG1 w0.102: v2(127.89,104.12) 127.91,104.1 128.17,104.1 128.27,104.2 128.27,105.65 128.61,105.99 128.61,106.06 128.63,106.07
  03_SIG1 w0.114: 128.63,106.07 130.37,107.81 130.37,111.49 130.25,111.61 130.25,111.93 130.37,112.04 130.37,112.31 130.25,112.42 130.25,112.74 130.37,112.85 130.37,113.12 130.25,113.23 130.25,113.55 130.37,113.67 130.37,113.93 130.25,114.05 130.25,114.36 130.37,114.48 130.37,115.8 130.95,116.38 arc(131.42,116.58) 131.89,116.38 132.36,115.91 arc(132.6,115.81) 132.85,115.91 arc(132.95,116.15) 132.85,116.39 132.37,116.87 arc(132.37,117.8) 133.3,117.8 133.78,117.33 arc(134.02,117.23) 134.27,117.33 arc(134.37,117.57) 134.27,117.81 133.79,118.29 arc(133.6,118.76) 133.79,119.22 134.82,120.26 134.82,125.9 134.71,126.01 134.12,126.01 v3(133.93,125.82)
DDR3_A_DQS3P: length 32.6
  TOP w0.114: v2(128.89,104.12) P1.AH23 ; U12.C7 v3(133.93,126.62)
  03_SIG1 w0.102: v2(128.89,104.12) 128.5,104.51 128.5,105.56 128.77,105.83 128.84,105.83 128.85,105.85
  03_SIG1 w0.114: 128.85,105.85 130.68,107.68 130.68,115.67 131.18,116.16 arc(131.42,116.26) 131.66,116.16 132.14,115.68 arc(132.6,115.49) 133.07,115.68 arc(133.26,116.15) 133.07,116.62 132.6,117.09 arc(132.6,117.58) 133.08,117.58 133.56,117.1 arc(134.02,116.91) 134.49,117.1 arc(134.68,117.57) 134.49,118.04 134.01,118.51 arc(133.91,118.76) 134.01,119 135.14,120.12 135.14,126.03 134.84,126.33 134.22,126.33 v3(133.93,126.62)
DDR3_A_DQS4N: length 76.5
  TOP w0.114: U10.G3 v3(105.85,129.82)
  TOP w0.127: P1.D24 v2(126.89,79.12)
  06_SIG2 w0.102: 125.92,77.53 125.94,77.55 126,77.55 126.27,77.82 126.27,78.43 126.5,78.66 126.78,78.66 126.89,78.76 v2(126.89,79.12)
  06_SIG2 w0.114: 125.92,77.53 124.05,75.67 118.61,75.67 116.07,78.2 arc(116,78.36) 116.07,78.53 116.11,78.57 arc(116.27,78.95) 116.11,79.34 116.02,79.43 arc(115.72,79.55) 115.43,79.43 115.3,79.3 arc(114.97,79.3) 114.97,79.62 115.01,79.66 arc(115.17,80.05) 115.01,80.43 114.92,80.53 arc(114.63,80.65) 114.33,80.53 114.2,80.39 arc(113.88,80.39) 113.88,80.72 113.92,80.76 arc(114.1,81.19) 113.92,81.62 arc(113.58,81.76) 113.24,81.62 113.11,81.49 arc(112.94,81.42) 112.78,81.49 104.1,90.17 104.1,122.16 105.02,123.07 105.02,126.86 106.62,128.46 106.62,129.28 106.32,129.58 105.96,129.58 105.85,129.69 v3(105.85,129.82)
DDR3_A_DQS4P: length 76.4
  TOP w0.114: U10.F3 v3(105.85,129.02)
  TOP w0.127: P1.C24 v2(126.89,78.12)
  06_SIG2 w0.102: v2(126.89,78.12) 126.89,78.29 126.74,78.43 126.6,78.43 126.5,78.33 126.5,77.73 126.14,77.37 126.14,77.31
  06_SIG2 w0.114: 126.14,77.31 124.19,75.35 118.47,75.35 115.84,77.98 arc(115.68,78.36) 115.84,78.75 115.88,78.79 arc(115.95,78.95) 115.88,79.11 115.79,79.21 arc(115.72,79.23) 115.65,79.21 115.52,79.07 arc(114.75,79.07) 114.75,79.85 114.79,79.89 arc(114.85,80.05) 114.79,80.21 114.7,80.3 arc(114.63,80.33) 114.56,80.3 114.43,80.17 arc(113.65,80.17) 113.65,80.94 113.69,80.98 arc(113.78,81.19) 113.69,81.4 arc(113.58,81.44) 113.46,81.4 113.33,81.27 arc(112.94,81.11) 112.56,81.27 103.78,90.04 103.78,122.29 104.7,123.2 104.7,126.99 106.3,128.59 106.3,129.15 106.18,129.26 105.96,129.26 105.85,129.15 v3(105.85,129.02)
DDR3_A_ODT_0: length 158
  TOP w0.127: U10.K1 v3(108.25,132.22) ; U11.K1 v3(123.49,132.22) ; U12.K1 v3(138.73,132.22) ; P1.K25 v2(125.89,86.12)
  06_SIG2 w0.127: v2(125.89,86.12) 125.36,86.65 118.69,86.65 118.08,87.26 118.08,89.88 117.14,90.82 117.14,93.41 arc(117.07,93.59) 116.89,93.66 116.43,93.66 arc(116.18,93.92) 116.43,94.17 116.89,94.17 arc(117.14,94.43) 116.89,94.68 116.43,94.68 arc(116.18,94.93) 116.43,95.19 116.89,95.19 arc(117.14,95.44) 116.89,95.7 116.43,95.7 arc(116.18,95.95) 116.43,96.2 116.89,96.2 arc(117.14,96.46) 116.89,96.71 116.43,96.71 arc(116.18,96.97) 116.43,97.22 116.89,97.22 arc(117.14,97.47) 116.89,97.73 116.43,97.73 arc(116.18,97.98) 116.43,98.24 116.89,98.24 arc(117.14,98.49) 116.89,98.74 116.43,98.74 arc(116.18,99) 116.43,99.25 116.89,99.25 arc(117.14,99.51) 116.89,99.76 116.43,99.76 arc(116.18,100.01) 116.43,100.27 116.89,100.27 arc(117.14,100.52) 116.89,100.78 116.43,100.78 arc(116.18,101.03) 116.43,101.28 116.89,101.28 arc(117.07,101.36) 117.14,101.54 117.14,102.58 114.5,105.22 114.5,111.42 114.17,111.75 111.71,111.75 110.85,112.61 110.85,115.3 111.64,116.09 arc(111.69,116.13) 111.76,116.14 114.17,116.14 arc(114.43,116.4) 114.17,116.65 113.31,116.65 arc(113.06,116.9) 113.31,117.16 114.17,117.16 arc(114.43,117.41) 114.17,117.67 113.31,117.67 arc(113.06,117.92) 113.31,118.17 114.17,118.17 arc(114.43,118.43) 114.17,118.68 113.31,118.68 arc(113.06,118.94) 113.31,119.19 114.17,119.19 arc(114.43,119.44) 114.17,119.7 113.31,119.7 arc(113.06,119.95) 113.31,120.21 114.17,120.21 arc(114.43,120.46) 114.17,120.71 113.31,120.71 arc(113.06,120.97) 113.31,121.22 114.17,121.22 arc(114.43,121.48) 114.17,121.73 113.31,121.73 arc(113.06,121.98) 113.31,122.24 114.17,122.24 arc(114.43,122.49) 114.17,122.75 113.31,122.75 arc(113.06,123) 113.31,123.25 114.17,123.25 arc(114.43,123.51) 114.17,123.76 113.31,123.76 arc(113.11,123.84) 113.03,124.04 arc(113.11,124.24) 113.31,124.32 114.5,124.32 114.63,124.45 114.63,125.21 114.5,125.34 113.59,125.34 113.46,125.46 113.46,125.74 113.59,125.87 115.59,125.87 arc(115.84,126.12) 115.59,126.38 114.86,126.38 arc(114.6,126.63) 114.86,126.89 115.59,126.89 arc(115.84,127.14) 115.59,127.39 114.86,127.39 arc(114.6,127.65) 114.86,127.9 115.59,127.9 arc(115.84,128.16) 115.59,128.41 113.41,128.41 arc(113.16,128.66) 113.41,128.92 115.59,128.92 arc(115.84,129.17) 115.59,129.43 114.86,129.43 arc(114.6,129.68) 114.86,129.93 116.48,129.93 arc(116.84,130.29) 116.48,130.64 109.73,130.64 108.25,132.13 v3(108.25,132.22) 111.94,132.22 112.33,131.83 119.68,131.83 arc(119.86,131.75) 119.93,131.57 119.93,131.23 arc(120.19,130.98) 120.44,131.23 120.44,131.57 arc(120.51,131.75) 120.69,131.83 123.09,131.83 v3(123.49,132.22) 123.88,131.83 138.33,131.83 v3(138.73,132.22)
  BOTTOM w0.127: v3(138.73,132.22) 139.57,133.06 139.57,138.44 R354.2
DDR3_A_RAS_N_0: length 158.6
  TOP w0.102: U10.J3 v3(105.85,131.42)
  TOP w0.127: U11.J3 v3(121.09,131.42) ; P1.F23 v2(127.89,81.12) ; U12.J3 v3(136.33,131.42)
  03_SIG1 w0.127: v3(105.85,131.42) 106.24,131.81 110.64,131.81 arc(110.82,131.89) 110.9,132.07 110.9,132.32 arc(111.15,132.58) 111.41,132.32 111.41,132.07 arc(111.66,131.81) 111.91,132.07 111.91,132.32 arc(112.17,132.58) 112.42,132.32 112.42,132.07 arc(112.5,131.89) 112.68,131.81 120.69,131.81 v3(121.09,131.42) 121.48,131.81 135.93,131.81 v3(136.33,131.42)
  06_SIG2 w0.127: v2(127.89,81.12) 127.41,81.6 124.74,81.6 123.71,82.62 120.77,82.62 120.39,83 120.39,83.39 120.15,83.62 118.73,83.62 116.84,85.51 116.84,87.39 116.57,87.66 arc(116.5,87.84) 116.57,88.02 116.75,88.19 arc(116.75,88.55) 116.39,88.55 116.21,88.37 arc(115.85,88.37) 115.85,88.73 116.46,89.34 arc(116.46,89.7) 116.1,89.7 115.49,89.09 arc(115.14,89.09) 115.14,89.45 115.74,90.06 arc(115.74,90.42) 115.38,90.42 114.78,89.81 arc(114.42,89.81) 114.42,90.17 115.02,90.78 arc(115.02,91.14) 114.66,91.14 114.06,90.53 arc(113.7,90.53) 113.7,90.89 114.3,91.5 arc(114.3,91.85) 113.95,91.85 113.34,91.25 arc(112.98,91.25) 112.98,91.61 113.59,92.21 arc(113.59,92.57) 113.23,92.57 112.62,91.97 arc(112.26,91.97) 112.26,92.33 112.87,92.93 arc(112.87,93.29) 112.51,93.29 111.9,92.69 arc(111.54,92.69) 111.54,93.04 112.15,93.65 arc(112.15,94.01) 111.79,94.01 111.18,93.4 arc(110.93,93.35) 110.79,93.57 110.79,94.53 arc(110.84,94.66) 110.98,94.72 111.76,94.72 arc(112.01,94.97) 111.76,95.22 110.97,95.22 arc(110.72,95.48) 110.97,95.73 111.76,95.73 arc(112.01,95.99) 111.76,96.24 110.97,96.24 arc(110.72,96.49) 110.97,96.75 111.76,96.75 arc(112.01,97) 111.76,97.26 110.97,97.26 arc(110.72,97.51) 110.97,97.76 111.76,97.76 arc(112.01,98.02) 111.76,98.27 110.97,98.27 arc(110.72,98.53) 110.97,98.78 111.76,98.78 arc(112.01,99.03) 111.76,99.29 110.97,99.29 arc(110.72,99.54) 110.97,99.8 111.76,99.8 arc(112.01,100.05) 111.76,100.3 110.97,100.3 arc(110.72,100.56) 110.97,100.81 111.76,100.81 arc(112.01,101.07) 111.76,101.32 110.97,101.32 arc(110.79,101.4) 110.72,101.57 110.72,111.04 109.7,112.05 109.7,115.84 110.54,116.67 110.54,117.76 110.67,117.89 111.63,117.89 arc(111.89,118.14) 111.63,118.4 110.79,118.4 arc(110.54,118.65) 110.79,118.9 111.63,118.9 arc(111.89,119.16) 111.63,119.41 110.79,119.41 arc(110.54,119.67) 110.79,119.92 111.63,119.92 arc(111.89,120.17) 111.63,120.43 110.79,120.43 arc(110.54,120.68) 110.79,120.94 111.63,120.94 arc(111.89,121.19) 111.63,121.44 110.79,121.44 arc(110.54,121.7) 110.79,121.95 111.63,121.95 arc(111.89,122.21) 111.63,122.46 111.12,122.46 arc(110.87,122.71) 111.12,122.97 111.63,122.97 arc(111.81,123.04) 111.89,123.22 111.89,128.03 111.66,128.26 110.62,128.26 107.87,131 106.27,131 v3(105.85,131.42)
  BOTTOM w0.127: R353.2 139.95,137.68 139.95,132.78 139,131.83 136.73,131.83 v3(136.33,131.42)
DDR3_A_RST_N_0: length 145
  TOP w0.127: U11.T2 v3(122.69,137.02) ; U12.T2 v3(137.93,137.02) ; P1.L24 v2(127.89,86.12) ; U10.T2 v3(107.45,137.02)
  TOP w0.381: C32.1 138.16,137.25 v3(137.93,137.02)
  03_SIG1 w0.102: 116.22,76.5 128.26,76.5 129.51,77.75 129.51,85.06 128.94,85.62 128.39,85.62 v2(127.89,86.12)
  03_SIG1 w0.127: 116.22,76.5 94.36,98.36 94.36,136.97 97.56,140.17 104.62,140.17 106.55,138.24 106.55,137.91 v3(107.45,137.02) 107.85,137.42 108.49,137.42 arc(108.67,137.35) 108.74,137.17 108.74,137.07 arc(109,136.82) 109.25,137.07 109.25,137.17 arc(109.51,137.42) 109.76,137.17 109.76,137.07 arc(110.01,136.82) 110.27,137.07 110.27,137.17 arc(110.34,137.35) 110.52,137.42 122.29,137.42 v3(122.69,137.02) 123.09,137.42 137.53,137.42 v3(137.93,137.02)
DDR3_A_WE_N_0: length 151.5
  TOP w0.127: P1.M24 126.89,87.12 v2(126.89,86.12) ; U10.L3 v3(106.65,133.02) ; U11.L3 v3(121.89,133.02) ; U12.L3 v3(137.13,133.02)
  03_SIG1 w0.102: 117.5,85.81 117.63,85.81 117.7,85.74 126.51,85.74 v2(126.89,86.12)
  03_SIG1 w0.127: 117.5,85.81 117.3,85.81 116.33,86.78 116.33,105.58 106.63,115.28 106.63,121.35 106.47,121.5 104.81,121.5 arc(104.55,121.76) 104.81,122.01 106.33,122.01 arc(106.58,122.26) 106.33,122.52 104.81,122.52 arc(104.55,122.77) 104.81,123.03 106.33,123.03 arc(106.58,123.28) 106.33,123.53 104.81,123.53 arc(104.69,123.56) 104.61,123.63 arc(104.58,123.9) 104.81,124.04 105.98,124.04 arc(106.23,124.3) 105.98,124.55 103.31,124.55 arc(103.05,124.8) 103.31,125.06 105.98,125.06 arc(106.23,125.31) 105.98,125.57 103.31,125.57 arc(103.05,125.82) 103.31,126.07 105.98,126.07 arc(106.23,126.33) 105.98,126.58 103.31,126.58 arc(103.05,126.84) 103.31,127.09 105.98,127.09 arc(106.23,127.34) 105.98,127.6 103.31,127.6 arc(103.05,127.85) 103.31,128.11 105.98,128.11 arc(106.23,128.36) 105.98,128.61 103.31,128.61 arc(103.05,128.87) 103.31,129.12 105.23,129.12 arc(105.48,129.38) 105.23,129.63 103.31,129.63 arc(103.13,129.71) 103.05,129.88 103.05,131.67 103.49,132.11 arc(103.52,132.15) 103.53,132.2 103.53,132.58 arc(103.78,132.83) 104.04,132.58 104.04,132.07 arc(104.09,131.94) 104.23,131.89 105.31,131.89 arc(105.4,131.92) 105.44,132.01 105.44,132.87 arc(105.48,132.97) 105.59,133.02 v3(106.65,133.02)
  06_SIG2 w0.127: v3(137.13,133.02) U12.L3 122.29,132.62 v3(121.89,133.02) 121.49,132.63 107.04,132.63 v3(106.65,133.02)
  BOTTOM w0.127: R361.2 135.51,138.06 135.51,134.02 136.51,133.02 v3(137.13,133.02)
DDR3_B_A0: length 103.5
  TOP w0.127: U16.N3 v3(175.58,118.59) ; R111.2 180.03,104.97 176.4,104.97 U22.N3 v3(175.58,103.35) ; P1.AP4 147.89,110.12 149.87,110.12 v2(149.89,110.14) ; U8.N3 v3(175.58,133.83)
  03_SIG1 w0.127: v3(175.58,133.83) 175.18,133.43 U16.N3 v3(175.58,118.59) 175.18,118.19 U22.N3 v3(175.58,103.35)
  06_SIG2 w0.127: v3(175.58,133.83) 175.58,134.32 174.45,135.45 165.05,135.45 163.88,134.28 163.88,131.33 155.29,122.74 arc(155.11,122.66) 154.93,122.74 154.52,123.14 arc(154.17,123.14) 154.17,122.78 154.57,122.38 arc(154.57,122.02) 154.21,122.02 153.81,122.42 arc(153.45,122.42) 153.45,122.06 153.85,121.66 arc(153.85,121.3) 153.49,121.3 153.09,121.7 arc(152.73,121.7) 152.73,121.34 153.13,120.94 arc(153.13,120.58) 152.77,120.58 152.37,120.98 arc(152.01,120.98) 152.01,120.63 152.41,120.22 arc(152.41,119.86) 152.05,119.86 151.65,120.27 arc(151.29,120.27) 151.29,119.91 151.69,119.5 arc(151.69,119.14) 151.34,119.14 150.93,119.55 arc(150.57,119.55) 150.57,119.19 151.51,118.25 arc(151.51,117.89) 151.15,117.89 150.21,118.83 arc(149.86,118.83) 149.86,118.47 150.79,117.53 arc(150.79,117.17) 150.43,117.17 149.69,117.92 arc(149.33,117.92) 149.33,117.56 150.07,116.82 arc(150.07,116.46) 149.71,116.46 149.57,116.6 149.39,116.6 149.22,116.44 149.22,110.81 v2(149.89,110.14)
DDR3_B_A1: length 102.1
  TOP w0.127: v3(176.38,107.35) U22.P7 176.81,106.11 180.03,106.11 R103.2 ; P1.AN4 v2(147.89,109.12) ; U8.P7 v3(176.38,137.83) ; U16.P7 v3(176.38,122.59)
  06_SIG2 w0.127: v2(147.89,109.12) 146.79,110.22 146.79,112.31 147.29,112.81 147.29,120.59 158.12,131.41 arc(158.3,131.49) 158.48,131.41 158.83,131.06 arc(159.19,131.06) 159.19,131.42 158.84,131.77 arc(158.76,131.95) 158.84,132.13 arc(159.02,132.2) 159.2,132.13 159.56,131.76 arc(159.73,131.7) 159.89,131.76 arc(159.98,131.96) 159.9,132.15 159.56,132.49 arc(159.48,132.67) 159.56,132.85 arc(159.74,132.92) 159.92,132.85 160.25,132.52 arc(160.61,132.52) 160.61,132.87 160.27,133.21 arc(160.2,133.39) 160.27,133.57 arc(160.45,133.64) 160.63,133.57 160.99,133.21 arc(161.35,133.21) 161.35,133.58 160.28,134.64 arc(160.28,135) 160.64,135 161.43,134.22 arc(161.79,134.22) 161.79,134.58 161,135.36 arc(161,135.72) 161.36,135.72 161.69,135.39 arc(161.87,135.32) 162.05,135.39 arc(162.12,135.57) 162.05,135.75 161.72,136.08 arc(161.72,136.44) 162.08,136.44 162.41,136.11 arc(162.59,136.04) 162.77,136.11 arc(162.84,136.29) 162.77,136.47 162.44,136.8 arc(162.44,137.16) 162.8,137.16 163.15,136.8 arc(163.33,136.73) 163.51,136.8 164.94,138.23 175.97,138.23 v3(176.38,137.83)
  BOTTOM w0.127: v3(176.38,137.83) U8.P7 175.98,122.99 v3(176.38,122.59) U16.P7 175.98,107.75 v3(176.38,107.35)
DDR3_B_A2: length 106.8
  TOP w0.102: P1.AM6 v2(145.89,107.12)
  TOP w0.127: U8.P3 v3(176.38,133.83) ; R112.2 179.27,104.58 176.81,104.58 U22.P3 v3(176.38,103.35) ; U16.P3 v3(176.38,118.59)
  03_SIG1 w0.127: v3(176.38,103.35) 176.78,103.75 176.78,118.19 v3(176.38,118.59) 176.78,118.99 176.78,133.43 v3(176.38,133.83)
  06_SIG2 w0.102: v2(145.89,107.12) 145.51,106.74 145.51,105.97 145.73,105.74 149.11,105.74 149.35,105.98 149.35,106.24 149.73,106.62 149.99,106.62 150.27,106.9 150.27,108.37
  06_SIG2 w0.127: v3(176.38,133.83) 176.38,134.18 174.73,135.83 164.82,135.83 163.47,134.48 163.47,131.49 159.69,127.7 arc(159.51,127.63) 159.33,127.7 158.94,128.09 arc(158.76,128.17) 158.58,128.09 arc(158.51,127.91) 158.58,127.73 158.97,127.34 arc(158.97,126.98) 158.61,126.98 158.22,127.37 arc(158.04,127.45) 157.86,127.37 arc(157.79,127.19) 157.86,127.01 158.25,126.62 arc(158.25,126.27) 157.89,126.27 157.5,126.66 arc(157.32,126.73) 157.14,126.66 arc(157.07,126.48) 157.14,126.3 157.53,125.91 arc(157.53,125.55) 157.17,125.55 156.78,125.94 arc(156.6,126.01) 156.42,125.94 arc(156.35,125.76) 156.42,125.58 156.81,125.19 arc(156.81,124.83) 156.46,124.83 156.07,125.22 arc(155.89,125.29) 155.71,125.22 arc(155.63,125.04) 155.71,124.86 156.1,124.47 arc(156.1,124.11) 155.74,124.11 155.35,124.5 arc(155.17,124.57) 154.99,124.5 arc(154.91,124.32) 154.99,124.14 155.38,123.75 arc(155.38,123.39) 155.02,123.39 154.6,123.81 arc(154.45,123.87) 154.29,123.81 148.84,118.36 148.84,110.4 150.27,108.98 150.27,108.37
DDR3_B_A3: length 106.7
  TOP w0.102: P1.AM5 v2(145.89,108.12)
  TOP w0.127: U22.N2 v3(175.58,102.55) ; U8.N2 v3(175.58,133.03) ; U16.N2 v3(175.58,117.79)
  06_SIG2 w0.102: 150.17,105.78 149.89,105.5 145.54,105.5 145.27,105.78 145.27,107.5 v2(145.89,108.12)
  06_SIG2 w0.127: v3(175.58,102.55) U22.N2 175.18,117.39 v3(175.58,117.79) U16.N2 175.18,132.63 v3(175.58,133.03) 175.17,133.43 175.17,133.99 174.1,135.06 165.25,135.06 164.26,134.07 164.26,131.16 159.26,126.16 arc(159.18,125.96) 159.26,125.77 159.44,125.59 arc(159.44,125.23) 159.08,125.23 158.9,125.41 arc(158.54,125.41) 158.54,125.05 158.72,124.87 arc(158.72,124.51) 158.36,124.51 158.18,124.69 arc(157.82,124.69) 157.82,124.33 158.01,124.15 arc(158.01,123.79) 157.65,123.79 157.46,123.97 arc(157.11,123.97) 157.11,123.61 157.29,123.43 arc(157.29,123.07) 156.93,123.07 156.75,123.25 arc(156.39,123.25) 156.39,122.89 156.57,122.71 arc(156.57,122.35) 156.21,122.35 156.03,122.53 arc(155.67,122.53) 155.67,122.18 155.85,121.99 arc(155.85,121.63) 155.49,121.63 155.31,121.82 arc(154.95,121.82) 154.95,121.46 155.13,121.28 arc(155.13,120.92) 154.77,120.92 154.59,121.1 arc(154.23,121.1) 154.23,120.74 154.41,120.56 arc(154.41,120.2) 154.05,120.2 153.87,120.38 arc(153.51,120.38) 153.51,120.02 153.7,119.84 arc(153.7,119.48) 153.34,119.48 153.15,119.66 arc(152.8,119.66) 152.8,119.3 152.98,119.12 arc(152.98,118.76) 152.62,118.76 152.44,118.94 arc(152.08,118.94) 152.08,118.58 152.26,118.4 arc(152.33,118.22) 152.26,118.04 149.63,115.42 149.63,111.04 150.57,110.1 150.57,106.18 150.17,105.78
  BOTTOM w0.127: v3(175.58,102.55) 175.97,102.94 175.97,103.52 176.28,103.82 R411.2
DDR3_B_A4: length 102.5
  TOP w0.127: U16.P8 v3(176.38,123.39) ; U8.P8 v3(176.38,138.63) ; U22.P8 v3(176.38,108.15) ; P1.AM1 149.89,108.12 v2(148.89,108.12)
  06_SIG2 w0.127: v2(148.89,108.12) 148.41,108.6 147.78,108.6 145.95,110.43 145.95,112.1 146.91,113.07 146.91,120.79 157.15,131.03 arc(157.22,131.21) 157.15,131.39 156.8,131.74 arc(156.8,132.1) 157.16,132.1 157.48,131.77 arc(157.84,131.77) 157.84,132.13 157.52,132.46 arc(157.52,132.81) 157.88,132.81 158.2,132.49 arc(158.56,132.49) 158.56,132.85 158.23,133.17 arc(158.23,133.53) 158.59,133.53 158.92,133.21 arc(159.28,133.21) 159.28,133.57 158.95,133.89 arc(158.95,134.25) 159.31,134.25 159.64,133.92 arc(160,133.92) 160,134.28 159.66,134.62 arc(159.59,134.78) 159.63,134.95 162.36,137.68 163.8,137.68 165.14,139.02 175.98,139.02 v3(176.38,138.63)
  BOTTOM w0.127: R394.2 180.34,110.99 180.34,110.68 178.94,109.28 178.94,107.63 178.18,106.87 177.04,106.87 176.78,107.13 176.78,107.74 v3(176.38,108.15) 176.78,108.55 176.78,122.99 v3(176.38,123.39) 176.78,123.79 176.78,138.23 v3(176.38,138.63)
DDR3_B_A5: length 99.2
  TOP w0.127: v2(149.89,107.12) P1.AM2 ; U22.P2 v3(176.38,102.55) ; U8.P2 v3(176.38,133.03) ; U16.P2 v3(176.38,117.79)
  06_SIG2 w0.127: v2(149.89,107.12) 149.94,107.17 149.94,108.55 147.96,110.53 147.96,111.65 148.44,112.13 148.44,118.54 158.73,128.83 arc(158.91,128.91) 159.09,128.84 159.5,128.43 arc(159.68,128.35) 159.86,128.43 arc(159.93,128.61) 159.86,128.79 159.45,129.2 arc(159.45,129.55) 159.81,129.55 160.22,129.15 arc(160.4,129.07) 160.58,129.15 arc(160.65,129.33) 160.58,129.51 160.17,129.91 arc(160.17,130.27) 160.53,130.27 160.94,129.86 arc(161.12,129.79) 161.3,129.86 arc(161.37,130.04) 161.3,130.22 160.89,130.63 arc(160.89,130.99) 161.25,130.99 161.66,130.58 arc(161.84,130.51) 162.02,130.58 arc(162.09,130.76) 162.02,130.94 161.61,131.35 arc(161.61,131.71) 161.97,131.71 162.37,131.3 arc(162.55,131.23) 162.73,131.3 arc(162.81,131.48) 162.73,131.66 162.33,132.07 arc(162.33,132.43) 162.69,132.43 162.84,132.27 162.97,132.27 163.07,132.37 163.07,134.66 164.62,136.21 174.98,136.21 176.78,134.4 176.78,133.67 176.38,133.26 v3(176.38,133.03) 175.98,132.63 U16.P2 v3(176.38,117.79) 175.98,117.39 U22.P2 v3(176.38,102.55)
  BOTTOM w0.127: R415.2 180.91,102.94 176.77,102.94 v3(176.38,102.55)
DDR3_B_A6: length 103.8
  TOP w0.127: U16.R8 v3(177.18,123.39) ; U8.R8 v3(177.18,138.63) ; U22.R8 v3(177.18,108.15) ; v2(147.89,108.12) P1.AM3
  06_SIG2 w0.127: v2(147.89,108.12) 147.67,108.12 145.59,110.2 145.59,112.33 146.53,113.27 146.53,121.02 152.8,127.29 arc(152.88,127.47) 152.8,127.65 152.45,128 arc(152.45,128.36) 152.81,128.36 153.14,128.03 arc(153.5,128.03) 153.5,128.39 153.17,128.72 arc(153.17,129.08) 153.53,129.08 153.86,128.75 arc(154.22,128.75) 154.22,129.11 153.89,129.44 arc(153.89,129.8) 154.25,129.8 154.57,129.47 arc(154.93,129.47) 154.93,129.83 154.61,130.16 arc(154.61,130.52) 154.97,130.52 155.29,130.19 arc(155.65,130.19) 155.65,130.55 155.33,130.87 arc(155.33,131.23) 155.68,131.23 156.01,130.91 arc(156.37,130.91) 156.37,131.27 156.03,131.61 arc(155.95,131.8) 156.03,131.99 162.16,138.11 163.63,138.11 165.4,139.89 176.47,139.89 177.18,139.18 v3(177.18,138.63)
  BOTTOM w0.127: v3(177.18,138.63) 177.58,138.23 177.58,123.79 v3(177.18,123.39) 177.58,122.99 177.58,108.55 v3(177.18,108.15) 177.57,107.75 178.3,107.75 178.56,108.01 178.56,110.55 179.58,111.57 179.78,111.57 R390.2
DDR3_B_A7: length 100.9
  TOP w0.127: U22.R2 v3(177.18,102.55) ; U16.R2 v3(177.18,117.79) ; v2(148.89,107.12) P1.AL3 ; U8.R2 v3(177.18,133.03)
  06_SIG2 w0.127: v2(148.89,107.12) 148.89,107.4 149.3,107.81 149.3,108.29 147.19,110.4 147.19,112.08 147.68,112.56 147.68,120.33 154.39,127.05 arc(154.57,127.13) 154.76,127.05 154.85,126.95 arc(155.21,126.95) 155.21,127.31 155.11,127.41 arc(155.11,127.77) 155.47,127.77 155.79,127.46 arc(156.15,127.46) 156.15,127.81 155.83,128.13 arc(155.83,128.49) 156.19,128.49 156.51,128.17 arc(156.87,128.17) 156.87,128.53 156.55,128.85 arc(156.55,129.21) 156.91,129.21 157.23,128.89 arc(157.59,128.89) 157.59,129.25 157.27,129.57 arc(157.27,129.93) 157.63,129.93 157.94,129.61 arc(158.3,129.61) 158.3,129.97 157.99,130.29 arc(157.99,130.64) 158.35,130.64 158.71,130.28 arc(158.89,130.2) 159.07,130.28 162.26,133.46 162.26,134.99 164.69,137.42 175.65,137.42 177.57,135.5 177.57,133.42 v3(177.18,133.03) 177.58,132.63 177.58,118.19 v3(177.18,117.79) 177.58,117.39 177.58,102.95 v3(177.18,102.55)
  BOTTOM w0.127: v3(177.18,102.55) 177.57,102.15 180.56,102.15 R419.2
DDR3_B_A8: length 104.5
  TOP w0.127: R92.2 179.78,108.15 v3(177.98,108.15) U22.T8 ; P1.AL6 v2(144.89,107.12) ; U16.T8 v3(177.98,123.39) ; U8.T8 v3(177.98,138.63)
  03_SIG1 w0.127: v3(177.98,108.15) 178.38,108.55 178.38,122.99 v3(177.98,123.39) 178.38,123.79 178.38,138.23 v3(177.98,138.63)
  BOTTOM w0.127: v2(144.89,107.12) 144.4,107.61 144.4,124.78 144.61,124.99 arc(144.79,125.07) 144.97,124.99 145.34,124.63 arc(145.7,124.63) 145.7,124.99 145.33,125.35 arc(145.33,125.71) 145.69,125.71 146.06,125.35 arc(146.42,125.35) 146.42,125.71 146.05,126.07 arc(146.05,126.43) 146.41,126.43 146.78,126.07 arc(147.13,126.07) 147.13,126.42 146.77,126.79 arc(146.7,126.97) 146.77,127.15 164.21,144.59 171.96,144.59 174.5,142.05 174.88,142.05 177.58,139.35 177.58,139.26 177.81,139.03 177.9,139.03 177.98,138.95 v3(177.98,138.63)
DDR3_B_A9: length 107.4
  TOP w0.127: U8.R3 v3(177.18,133.83) ; R113.2 178.51,104.2 177.23,104.2 U22.R3 v3(177.18,103.35) ; v2(145.89,106.12) P1.AK6 ; U16.R3 v3(177.18,118.59)
  06_SIG2 w0.127: v2(145.89,106.12) 146.35,106.59 148.97,106.59 149.39,107.01 149.39,107.29 149.61,107.51 149.61,108.45 147.57,110.48 147.57,111.87 148.06,112.36 148.06,118.7 148.89,119.53 arc(148.96,119.71) 148.89,119.89 148.62,120.16 arc(148.62,120.51) 148.98,120.51 149.25,120.25 arc(149.43,120.17) 149.61,120.25 arc(149.68,120.43) 149.61,120.61 149.34,120.87 arc(149.34,121.23) 149.7,121.23 149.96,120.97 arc(150.14,120.89) 150.32,120.97 arc(150.4,121.14) 150.32,121.32 150.06,121.59 arc(150.06,121.95) 150.42,121.95 150.68,121.68 arc(150.86,121.61) 151.04,121.68 arc(151.12,121.86) 151.04,122.04 150.77,122.31 arc(150.77,122.67) 151.13,122.67 151.4,122.4 arc(151.58,122.33) 151.76,122.4 arc(151.84,122.58) 151.76,122.76 151.49,123.03 arc(151.49,123.39) 151.85,123.39 152.12,123.12 arc(152.3,123.05) 152.48,123.12 arc(152.55,123.3) 152.48,123.48 152.21,123.75 arc(152.21,124.11) 152.57,124.11 152.84,123.84 arc(153.02,123.76) 153.2,123.84 arc(153.27,124.02) 153.2,124.2 152.93,124.47 arc(152.93,124.83) 153.29,124.83 153.56,124.56 arc(153.74,124.48) 153.92,124.56 arc(153.99,124.74) 153.92,124.92 153.65,125.18 arc(153.65,125.54) 154.01,125.54 154.28,125.28 arc(154.46,125.2) 154.63,125.28 arc(154.71,125.46) 154.63,125.64 154.37,125.9 arc(154.37,126.26) 154.73,126.26 154.99,125.99 arc(155.17,125.92) 155.35,125.99 162.67,133.32 162.67,134.82 164.49,136.64 171.41,136.64 171.41,136.63 175.8,136.63 177.18,135.26 v3(177.18,133.83) 177.18,133.58 176.78,133.19 176.78,133.16 176.78,118.98 v3(177.18,118.59) 176.78,118.19 176.78,103.74 v3(177.18,103.35)
DDR3_B_A10: length 107
  TOP w0.127: U8.L7 v3(173.98,137.83) ; U22.L7 v3(173.98,107.35) ; P1.AL5 v2(146.89,107.12) ; U16.L7 v3(173.98,122.59)
  BOTTOM w0.102: 147.12,108.62 147.12,108.47 147.27,108.32 147.27,107.5 v2(146.89,107.12)
  BOTTOM w0.127: 147.12,108.62 147.12,109.56 145.95,110.73 145.95,122.24 154.72,131.01 arc(154.8,131.19) 154.72,131.37 154.33,131.76 arc(154.33,132.12) 154.69,132.12 155.08,131.73 arc(155.44,131.73) 155.44,132.09 155.05,132.48 arc(155.05,132.84) 155.41,132.84 155.8,132.45 arc(156.16,132.45) 156.16,132.81 155.77,133.2 arc(155.77,133.56) 156.13,133.56 156.52,133.17 arc(156.88,133.17) 156.88,133.53 156.49,133.92 arc(156.49,134.28) 156.85,134.28 157.24,133.89 arc(157.6,133.89) 157.6,134.25 157.08,134.76 157.08,134.94 165.2,143.07 170.5,143.07 173.98,139.59 v3(173.98,137.83) 174.38,137.43 174.38,122.99 v3(173.98,122.59) 174.38,122.19 174.38,107.75 v3(173.98,107.35) 175.21,106.11 178.56,106.11 179.71,107.25 179.71,108.07 R397.2
DDR3_B_A11: length 103.2
  TOP w0.127: v2(147.89,107.12) P1.AL4 ; R97.2 179.27,106.49 177.23,106.49 U22.R7 v3(177.18,107.35) ; U16.R7 v3(177.18,122.59) ; U8.R7 v3(177.18,137.83)
  03_SIG1 w0.127: v3(177.18,137.83) 177.58,137.43 177.58,122.99 v3(177.18,122.59) 177.58,122.19 177.58,107.75 v3(177.18,107.35)
  06_SIG2 w0.127: v2(147.89,107.12) 147.4,107.61 146.76,107.61 146.38,107.99 146.38,108.27 146.02,108.62 145.77,108.62 145.21,109.18 145.21,112.48 146.15,113.42 146.15,121.25 149.18,124.27 arc(149.25,124.45) 149.18,124.63 148.85,124.96 arc(148.85,125.32) 149.21,125.32 149.48,125.04 arc(149.68,124.96) 149.87,125.04 arc(149.94,125.21) 149.87,125.37 149.57,125.68 arc(149.57,126.04) 149.93,126.04 150.2,125.76 arc(150.4,125.68) 150.59,125.76 arc(150.66,125.93) 150.59,126.09 150.29,126.39 arc(150.29,126.75) 150.65,126.75 150.92,126.48 arc(151.11,126.4) 151.31,126.48 arc(151.38,126.64) 151.31,126.81 151,127.11 arc(151,127.47) 151.36,127.47 151.64,127.2 arc(151.83,127.12) 152.02,127.2 arc(152.09,127.36) 152.02,127.53 151.72,127.83 arc(151.63,128.06) 151.72,128.29 162.59,139.15 164.03,139.15 165.15,140.27 176.66,140.27 177.57,139.36 177.57,138.22 v3(177.18,137.83)
DDR3_B_A12: length 108.2
  TOP w0.127: U16.N7 v3(175.58,122.59) ; R106.2 180.79,105.73 176.4,105.73 U22.N7 v3(175.58,107.35) ; v2(145.89,105.12) P1.AJ6 ; U8.N7 v3(175.58,137.83)
  03_SIG1 w0.127: v3(175.58,107.35) 175.98,107.75 175.98,122.19 v3(175.58,122.59) 175.98,122.99 175.98,137.43 v3(175.58,137.83)
  BOTTOM w0.127: v2(145.89,105.12) 145.41,105.59 145.41,108.52 144.78,109.16 144.78,123.05 147.91,126.18 arc(147.99,126.36) 147.91,126.54 147.56,126.9 arc(147.56,127.25) 147.92,127.25 148.27,126.9 arc(148.63,126.9) 148.63,127.26 148.28,127.61 arc(148.28,127.97) 148.64,127.97 148.99,127.62 arc(149.35,127.62) 149.35,127.98 149,128.33 arc(149,128.69) 149.36,128.69 149.71,128.34 arc(150.07,128.34) 150.07,128.7 149.72,129.05 arc(149.64,129.21) 149.69,129.37 164.52,144.21 171.02,144.21 173.97,141.26 174.14,141.26 175.97,139.43 175.97,138.22 v3(175.58,137.83)
DDR3_B_BA0: length 111.4
  TOP w0.127: P1.AG7 144.89,103.12 v2(144.89,104.12) ; U22.M2 v3(174.78,102.55) ; U8.M2 v3(174.78,133.03) ; U16.M2 v3(174.78,117.79)
  06_SIG2 w0.102: v2(144.89,104.12) 145.27,103.74 151.05,103.74 151.38,104.08
  06_SIG2 w0.127: v3(174.78,102.55) 174.38,102.95 174.38,117.39 v3(174.78,117.79) 174.38,118.19 174.38,132.63 v3(174.78,133.03) 174.37,133.43 172.23,133.43 171.86,133.06 171.86,132.85 169.57,130.57 168.05,130.57 164.29,126.81 164.29,126.31 164.95,125.64 arc(164.95,125.28) 164.59,125.28 arc(164.57,125.3) 164.55,125.32 164.04,125.83 arc(163.68,125.83) 163.68,125.47 164.29,124.86 arc(164.29,124.5) 163.93,124.5 163.33,125.11 arc(163.15,125.18) 162.97,125.11 162.59,124.73 162.59,124.4 161.85,123.66 161.67,123.66 161.52,123.81 arc(161.16,123.81) 161.16,123.45 161.18,123.43 arc(161.26,123.25) 161.18,123.07 arc(161,122.99) 160.82,123.07 160.43,123.46 arc(160.07,123.46) 160.07,123.1 160.46,122.71 arc(160.54,122.53) 160.46,122.35 arc(160.28,122.28) 160.1,122.35 159.71,122.74 arc(159.35,122.74) 159.35,122.38 159.74,121.99 arc(159.82,121.81) 159.74,121.63 arc(159.57,121.56) 159.39,121.63 159,122.02 arc(158.64,122.02) 158.64,121.66 159.03,121.27 arc(159.1,121.09) 159.03,120.91 arc(158.85,120.84) 158.67,120.91 158.28,121.3 arc(157.92,121.3) 157.92,120.94 158.31,120.55 arc(158.38,120.37) 158.31,120.2 arc(158.13,120.12) 157.95,120.2 157.56,120.59 arc(157.2,120.59) 157.2,120.23 157.59,119.84 arc(157.66,119.66) 157.59,119.48 arc(157.41,119.4) 157.23,119.48 156.84,119.87 arc(156.48,119.87) 156.48,119.51 156.87,119.12 arc(156.95,118.94) 156.87,118.76 arc(156.69,118.68) 156.51,118.76 156.12,119.15 arc(155.76,119.15) 155.76,118.79 156.15,118.4 arc(156.23,118.22) 156.15,118.04 arc(155.97,117.97) 155.79,118.04 155.4,118.43 arc(155.04,118.43) 155.04,118.07 155.43,117.68 arc(155.51,117.5) 155.43,117.32 arc(155.25,117.25) 155.08,117.32 154.68,117.71 arc(154.51,117.79) 154.33,117.71 150.8,114.19 150.8,111.65 151.7,110.74 151.7,104.39 151.38,104.08
  BOTTOM w0.127: v3(174.78,102.55) 175.17,102.94 175.17,103.61 175.77,104.2 180.41,104.2 R407.2
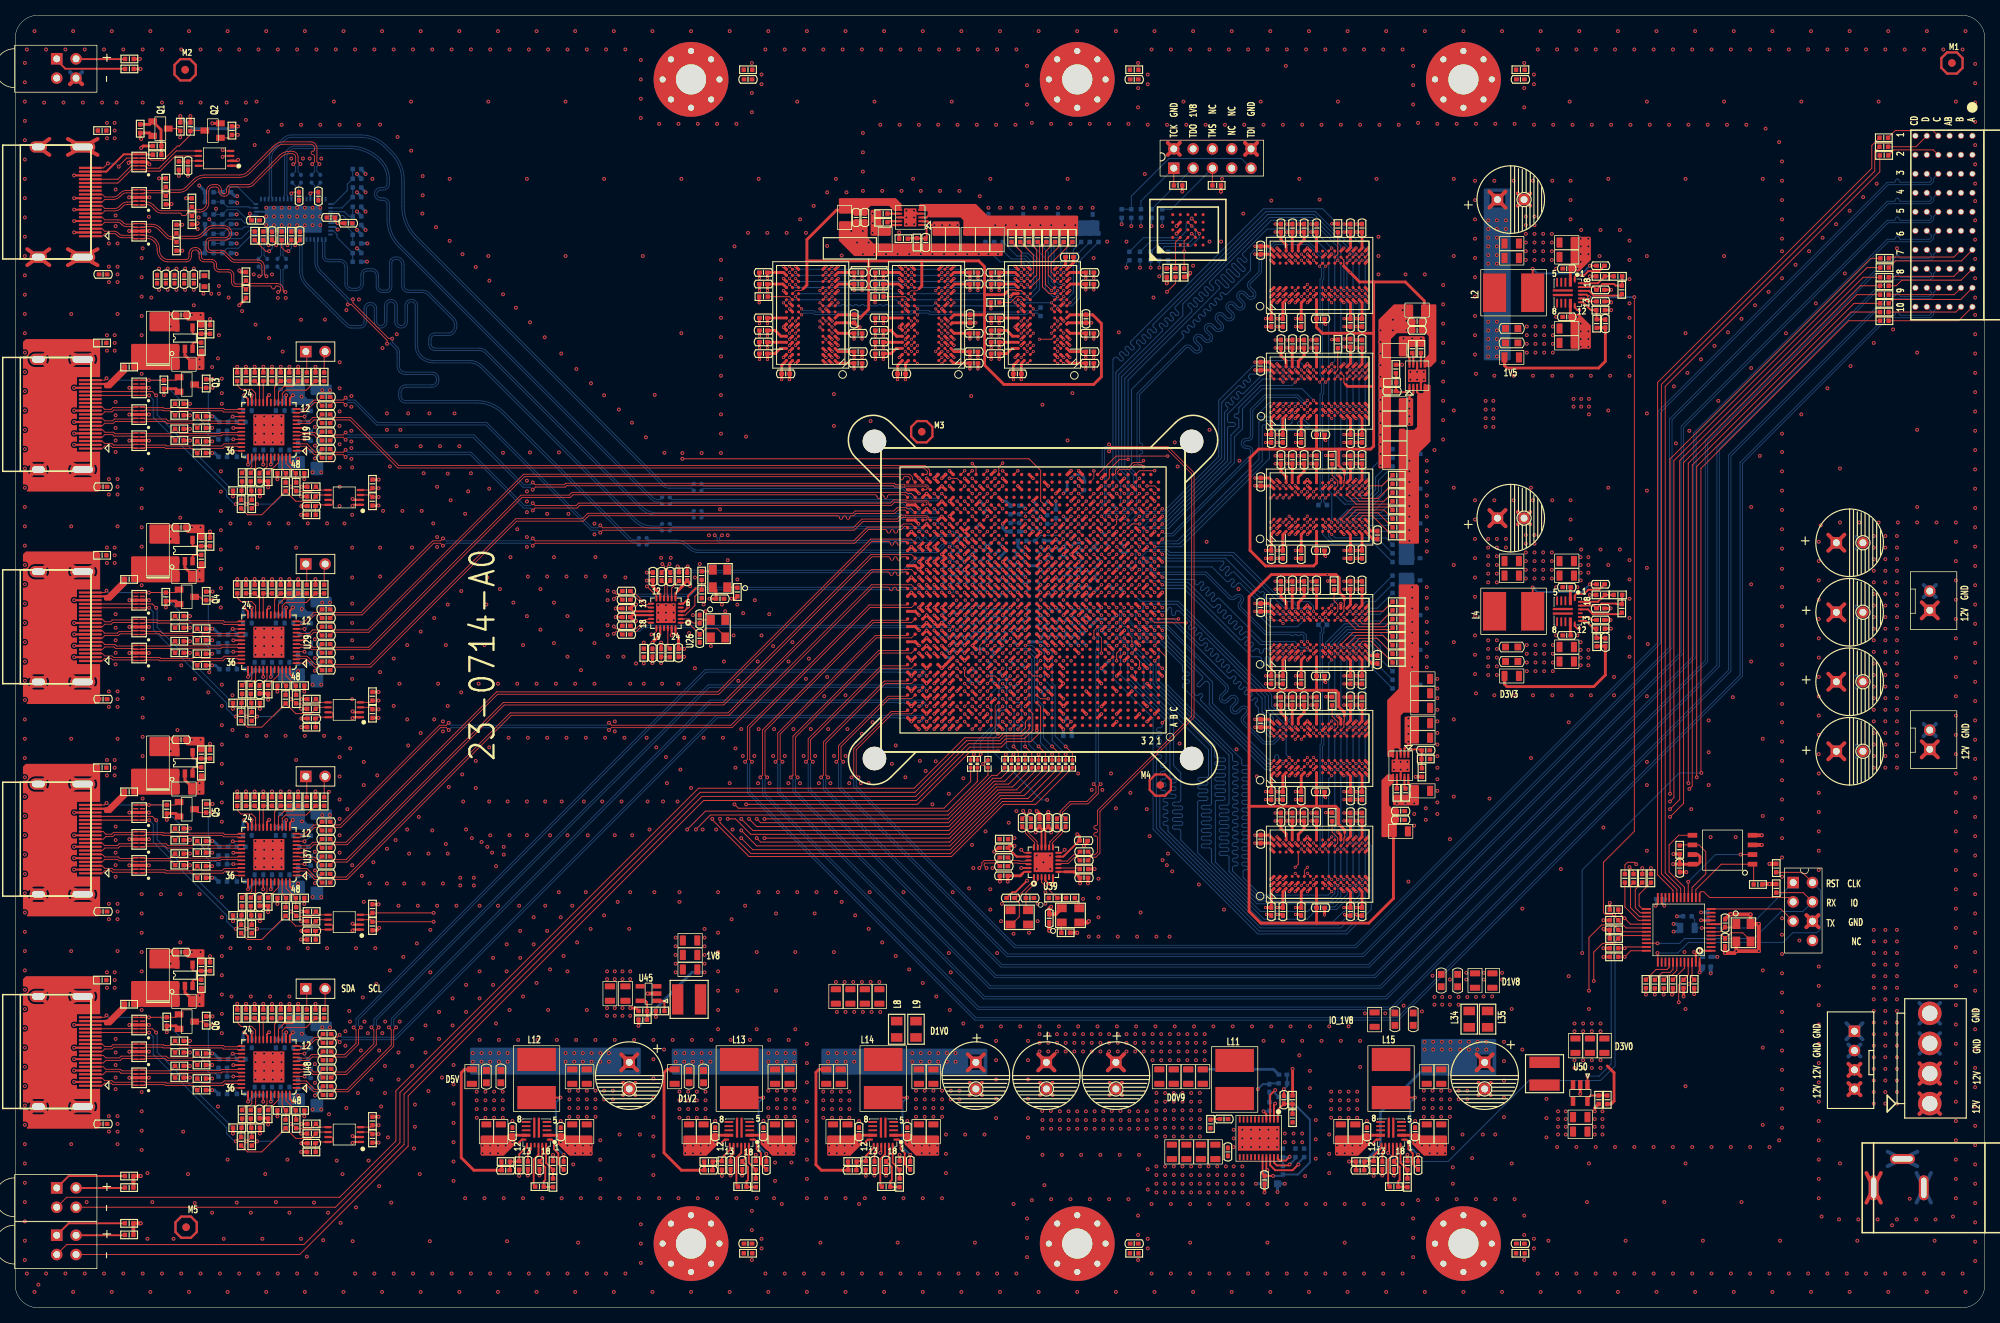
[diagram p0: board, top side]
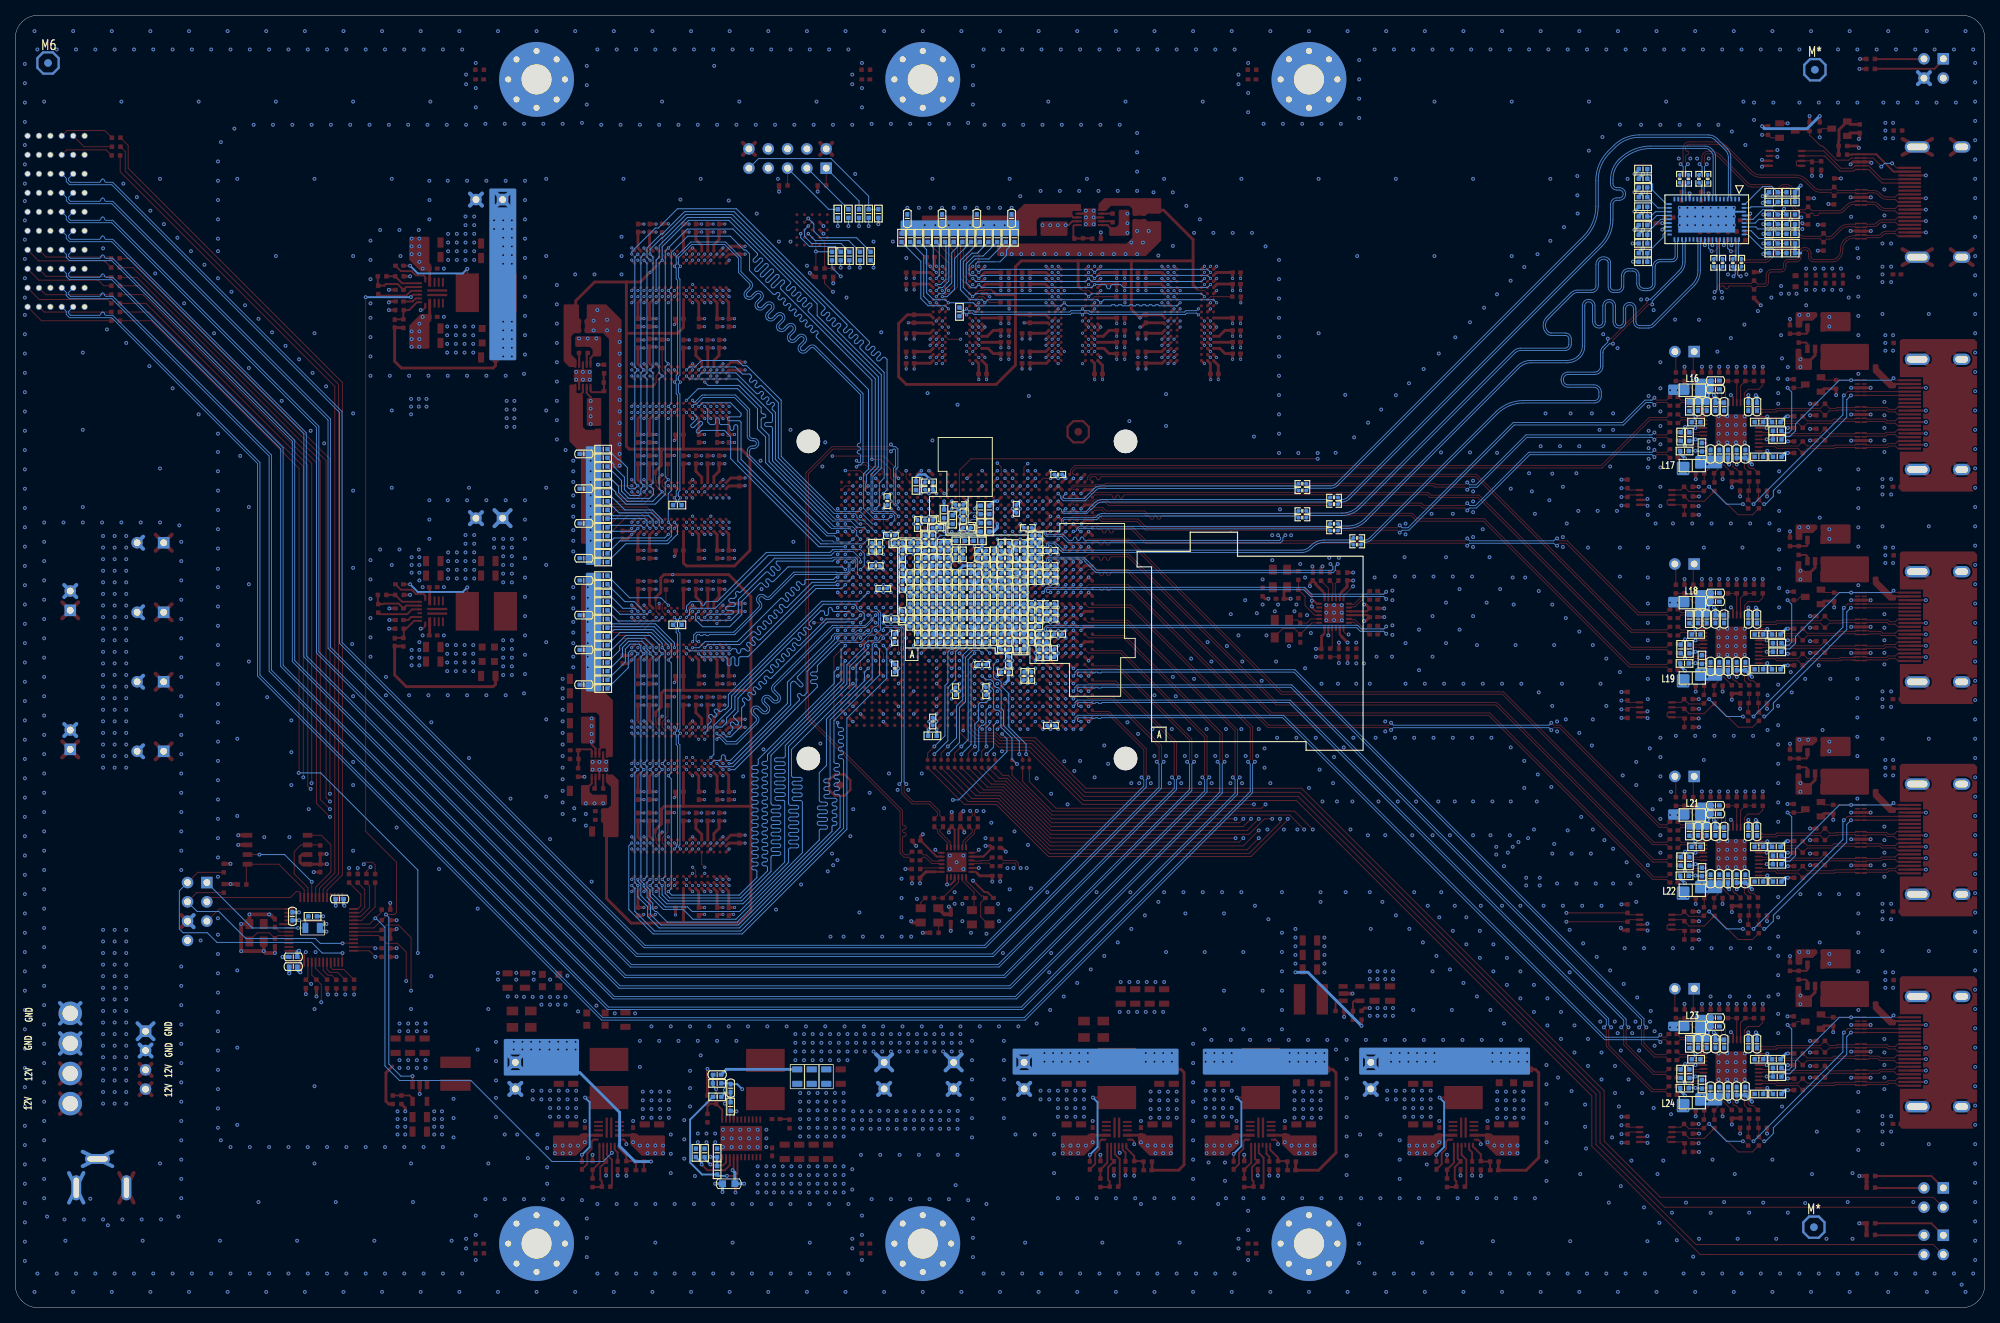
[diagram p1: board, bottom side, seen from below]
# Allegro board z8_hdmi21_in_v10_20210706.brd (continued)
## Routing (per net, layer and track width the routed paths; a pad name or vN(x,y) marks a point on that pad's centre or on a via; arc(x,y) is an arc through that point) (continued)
DDR3_B_BA1: length 112.8
  TOP w0.127: U16.N8 v3(175.58,123.39) ; v2(142.89,104.12) P1.AH8 ; U8.N8 v3(175.58,138.63) ; U22.N8 v3(175.58,108.15)
  BOTTOM w0.102: 146.02,109.59 146.27,109.35 146.27,104.93 146.08,104.74 143.51,104.74 v2(142.89,104.12)
  BOTTOM w0.127: 146.02,109.59 145.16,110.45 145.16,122.77 150.85,128.46 arc(150.92,128.64) 150.85,128.82 150.55,129.12 arc(150.48,129.29) 150.55,129.45 arc(150.74,129.53) 150.93,129.45 151.21,129.18 arc(151.57,129.18) 151.57,129.54 151.27,129.84 arc(151.2,130) 151.27,130.17 arc(151.46,130.25) 151.65,130.17 151.93,129.89 arc(152.29,129.89) 152.29,130.25 152.01,130.53 arc(151.93,130.72) 152.01,130.91 arc(152.18,130.98) 152.34,130.91 152.64,130.61 arc(153,130.61) 153,130.97 152.62,131.36 arc(152.55,131.53) 152.62,131.7 164.74,143.83 170.86,143.83 173.95,140.74 174.07,140.74 175.58,139.23 v3(175.58,138.63) U8.N8 175.18,123.79 v3(175.58,123.39) U16.N8 175.18,108.55 v3(175.58,108.15) 175.13,107.7 175.13,107 175.64,106.49 178.38,106.49 179.32,107.43 179.32,108.83 R395.2
DDR3_B_BA2: length 109.9
  TOP w0.127: U8.M3 v3(174.78,133.83) ; U16.M3 v3(174.78,118.59) ; v3(174.78,103.35) U22.M3 175.98,105.35 180.79,105.35 R109.2 ; v2(143.89,103.12) P1.AG8
  03_SIG1 w0.127: v3(174.78,103.35) 174.78,110.1 174.38,110.5 174.38,118.19 v3(174.78,118.59) 174.38,118.99 174.38,133.43 v3(174.78,133.83)
  BOTTOM w0.102: 146.38,109.77 146.51,109.64 146.51,104.79 146.22,104.5 143.68,104.5 143.38,104.2 143.38,103.63 v2(143.89,103.12)
  BOTTOM w0.127: 146.38,109.77 145.54,110.6 145.54,122.49 153.59,130.54 153.59,132.07 164.97,143.45 170.66,143.45 174.37,139.74 174.37,138.24 174.78,137.83 v3(174.78,133.83)
DDR3_B_CAS_N_0: length 114.3
  TOP w0.127: U16.K3 v3(173.18,118.59) ; v2(143.89,104.12) P1.AH7 ; U22.K3 v3(173.18,103.35) ; U8.K3 v3(173.18,133.83)
  BOTTOM w0.102: 147.51,109.31 147.51,105.2 146,103.7 144.31,103.7 v2(143.89,104.12)
  BOTTOM w0.127: R424.2 179.52,100.9 173.35,100.9 172.77,101.49 172.77,102.94 v3(173.18,103.35) 173.18,107.11 172.78,107.51 172.78,118.19 v3(173.18,118.59) U16.K3 172.78,133.43 v3(173.18,133.83) 172.78,134.22 172.78,138.81 170.61,140.98 165.02,140.98 163.19,139.15 162.97,139.15 162.48,138.67 162.48,136.46 159.4,133.38 arc(159.22,133.31) 159.04,133.38 158.92,133.5 arc(158.56,133.5) 158.56,133.15 158.69,133.02 arc(158.69,132.66) 158.33,132.66 158.2,132.79 arc(157.84,132.79) 157.84,132.43 157.97,132.3 arc(157.97,131.94) 157.61,131.94 157.48,132.07 arc(157.12,132.07) 157.12,131.71 157.25,131.59 arc(157.25,131.23) 156.89,131.23 156.77,131.35 arc(156.41,131.35) 156.41,130.99 156.53,130.87 arc(156.53,130.51) 156.17,130.51 156.05,130.63 arc(155.69,130.63) 155.69,130.27 155.81,130.15 arc(155.81,129.79) 155.45,129.79 155.33,129.91 arc(154.97,129.91) 154.97,129.55 155.09,129.43 arc(155.09,129.07) 154.73,129.07 154.61,129.19 arc(154.25,129.19) 154.25,128.83 154.37,128.71 arc(154.37,128.35) 154.02,128.35 153.89,128.48 arc(153.53,128.48) 153.53,128.12 153.66,127.99 arc(153.73,127.81) 153.66,127.63 146.84,120.82 146.84,110.35 147.51,109.68 147.51,109.31
DDR3_B_CK_0: length 100
  TOP w0.114: P1.AP7 144.61,109.62 144.73,109.74 144.73,110.19 145.16,110.62 146.48,110.62 147.07,111.21 148.17,111.21 v2(148.41,111.45) ; U16.J7 v3(171.58,121.79) ; U22.J7 v3(171.58,106.55) ; U8.J7 v3(171.58,137.03)
  BOTTOM w0.114: R405.2 171.82,106 171.82,106.31 v3(171.58,106.55) 171.82,106.79 171.82,107.32 171.64,107.5 171.64,120.21 171.82,120.39 171.82,121.55 v3(171.58,121.79) 171.82,122.03 171.82,122.5 171.64,122.68 171.64,135.32 171.82,135.5 171.82,136.79 v3(171.58,137.03) 171.82,137.27 171.82,138.15 170.08,139.89 165.76,139.89 163.93,138.06 163.93,136.19 162.51,134.77 arc(162.41,134.52) 162.51,134.28 163.02,133.77 arc(163.21,133.31) 163.02,132.86 arc(162.54,132.66) 162.06,132.86 161.57,133.35 arc(161.09,133.35) 161.09,132.86 161.58,132.37 arc(161.77,131.91) 161.58,131.44 arc(161.11,131.25) 160.64,131.44 160.16,131.93 arc(159.67,131.93) 159.67,131.44 160.18,130.93 arc(160.37,130.48) 160.18,130.02 arc(159.7,129.82) 159.22,130.02 158.74,130.51 arc(158.25,130.51) 158.25,130.03 158.77,129.51 arc(158.95,129.07) 158.77,128.63 arc(158.27,128.42) 157.78,128.63 157.32,129.09 arc(156.83,129.09) 156.83,128.61 157.32,128.12 arc(157.51,127.65) 157.32,127.18 arc(156.85,126.99) 156.39,127.18 155.9,127.67 arc(155.41,127.67) 155.41,127.19 155.93,126.67 arc(156.11,126.23) 155.93,125.79 arc(155.44,125.59) 154.94,125.79 154.48,126.25 arc(154.24,126.35) 153.99,126.25 153.2,125.45 147.88,120.14 147.88,113.93 arc(147.94,113.78) 148.09,113.71 arc(148.32,113.49) 148.09,113.26 arc(147.94,113.19) 147.88,113.04 147.88,113.02 arc(147.94,112.86) 148.09,112.8 arc(148.26,112.73) 148.32,112.57 arc(148.26,112.41) 148.09,112.34 arc(147.94,112.28) 147.88,112.13 147.88,111.32 147.99,111.21 148.17,111.21 v2(148.41,111.45)
DDR3_B_CK_N_0: length 100.1
  TOP w0.114: P1.AP6 145.16,109.62 145.05,109.74 145.05,110.06 145.29,110.3 146.61,110.3 147.2,110.89 148.17,110.89 v2(148.41,110.64) ; U16.K7 v3(172.38,121.79) ; U8.K7 v3(172.38,137.03) ; U22.K7 v3(172.38,106.55)
  BOTTOM w0.114: v2(148.41,110.64) 148.17,110.89 147.86,110.89 147.56,111.19 147.56,120.27 153.77,126.48 arc(154.24,126.67) 154.7,126.48 155.17,126.01 arc(155.44,125.9) 155.7,126.01 arc(155.79,126.23) 155.7,126.45 155.19,126.96 arc(155.19,127.9) 156.12,127.9 156.61,127.41 arc(156.85,127.31) 157.1,127.41 arc(157.2,127.65) 157.1,127.89 156.61,128.38 arc(156.61,129.32) 157.54,129.32 158.01,128.85 arc(158.27,128.74) 158.54,128.85 arc(158.63,129.07) 158.54,129.29 158.03,129.8 arc(158.03,130.73) 158.96,130.73 159.45,130.25 arc(159.7,130.14) 159.96,130.25 arc(160.05,130.48) 159.96,130.71 159.45,131.22 arc(159.45,132.15) 160.38,132.15 160.87,131.67 arc(161.11,131.56) 161.35,131.67 arc(161.45,131.91) 161.35,132.15 160.86,132.64 arc(160.86,133.57) 161.8,133.57 162.29,133.08 arc(162.54,132.98) 162.8,133.08 arc(162.89,133.31) 162.8,133.54 162.28,134.06 arc(162.09,134.52) 162.28,134.99 163.61,136.32 163.61,138.19 165.63,140.21 170.21,140.21 172.14,138.28 172.14,137.27 v3(172.38,137.03) 172.14,136.79 172.14,135.37 171.96,135.19 171.96,122.81 172.14,122.64 172.14,122.03 v3(172.38,121.79) 172.14,121.55 172.14,120.26 171.96,120.08 171.96,107.63 172.14,107.45 172.14,106.79 v3(172.38,106.55) 172.14,106.31 172.14,106.01 R405.1
DDR3_B_CKE_0: length 111.6
  TOP w0.127: U8.K9 v3(173.18,139.43) ; U16.K9 v3(173.18,124.19) ; v2(146.39,111.62) 145.27,111.62 143.92,110.28 143.92,109.15 P1.AN8 ; U22.K9 v3(173.18,108.95)
  BOTTOM w0.127: v2(146.39,111.62) 146.39,122.04 158.36,134.02 arc(158.44,134.2) 158.36,134.38 157.94,134.81 arc(157.94,135.17) 158.3,135.17 159.22,134.24 arc(159.58,134.24) 159.58,134.6 158.65,135.52 arc(158.65,135.88) 159.01,135.88 159.94,134.96 arc(160.3,134.96) 160.3,135.32 159.37,136.24 arc(159.37,136.6) 159.73,136.6 160.66,135.68 arc(161.01,135.68) 161.01,136.04 160.09,136.96 arc(160.09,137.32) 160.45,137.32 161.37,136.4 arc(161.73,136.4) 161.73,136.76 160.81,137.68 arc(160.81,138.04) 161.17,138.04 161.6,137.61 arc(161.96,137.61) 161.96,137.97 161.44,138.48 161.44,138.7 164.67,141.92 170.68,141.92 v3(173.18,139.43) 173.57,139.03 173.57,124.58 v3(173.18,124.19) 173.58,123.79 173.58,109.35 v3(173.18,108.95) 173.58,108.55 173.58,107.03 174.88,105.73 178.74,105.73 180.09,107.07 180.09,107.31 R399.2
DDR3_B_CS_N_0: length 112.9
  TOP w0.127: U16.L2 v3(173.98,117.79) ; U8.L2 v3(173.98,133.03) ; P1.AL9 v2(142.89,107.12) ; U22.L2 v3(173.98,102.55)
  06_SIG2 w0.102: v2(142.89,107.12) 143.27,106.74 143.27,104.06 143.83,103.5 151.32,103.5 151.49,103.67
  06_SIG2 w0.127: 151.49,103.67 152.08,104.27 152.08,110.95 151.18,111.85 151.18,113.98 153.97,116.78 155.5,116.78 156.23,117.51 156.41,117.51 156.96,116.95 arc(157.32,116.95) 157.32,117.31 156.86,117.77 arc(156.86,118.13) 157.22,118.13 157.68,117.67 arc(158.04,117.67) 158.04,118.03 157.58,118.49 arc(157.58,118.85) 157.94,118.85 158.4,118.39 arc(158.76,118.39) 158.76,118.75 158.3,119.21 arc(158.3,119.57) 158.65,119.57 159.12,119.1 arc(159.48,119.1) 159.48,119.46 159.01,119.93 arc(159.01,120.29) 159.37,120.29 159.84,119.82 arc(160.2,119.82) 160.2,120.18 159.73,120.65 arc(159.73,121) 160.09,121 160.56,120.54 arc(160.91,120.54) 160.91,120.9 160.45,121.36 arc(160.45,121.72) 160.81,121.72 161.27,121.26 arc(161.63,121.26) 161.63,121.62 161.17,122.08 arc(161.17,122.44) 161.53,122.44 161.99,121.98 arc(162.35,121.98) 162.35,122.34 161.89,122.8 arc(161.89,123.16) 162.25,123.16 162.72,122.68 arc(162.9,122.61) 163.08,122.68 166.17,125.77 166.17,127.98 167.79,129.6 169.32,129.6 172.35,132.63 173.34,132.63 173.73,133.03 v3(173.98,133.03) 173.98,131.37 173.58,130.97 U16.L2 v3(173.98,117.79) 173.58,117.39 173.58,102.94 v3(173.98,102.55)
  BOTTOM w0.127: R404.2 179.65,104.58 175.39,104.58 174.37,103.57 174.37,102.94 v3(173.98,102.55)
DDR3_B_DM0: length 33.5
  TOP w0.127: P1.AB11 v2(140.89,98.12) ; U22.E7 v3(168.38,107.35)
  03_SIG1 w0.102: 145.55,100.41 145.39,100.24 145.39,100.06 145.06,99.74 142.85,99.74 142.39,99.27 142.39,99.02 141.99,98.62 141.39,98.62 v2(140.89,98.12)
  03_SIG1 w0.127: v3(168.38,107.35) 167.97,107.75 164.33,107.75 164.01,107.43 158.62,107.43 153.82,102.62 147.77,102.62 147.39,102.24 147.39,101.96 147.05,101.62 146.72,101.62 146.39,101.29 146.39,100.98 146.03,100.62 145.77,100.62 145.55,100.41
DDR3_B_DM1: length 35
  TOP w0.127: v2(144.89,99.12) P1.AC7 ; U22.D3 v3(167.58,104.15)
  06_SIG2 w0.102: v2(144.89,99.12) 145.27,98.74 151.13,98.74 151.21,98.81 151.41,98.81
  06_SIG2 w0.127: 151.41,98.81 157.19,98.81 arc(157.31,98.86) 157.36,98.98 157.36,99.19 arc(157.61,99.44) 157.87,99.19 157.87,99.07 arc(157.94,98.89) 158.12,98.82 arc(158.3,98.89) 158.37,99.07 158.37,99.18 arc(158.45,99.36) 158.63,99.44 arc(158.81,99.36) 158.88,99.18 158.88,98.98 arc(158.93,98.86) 159.05,98.81 159.38,98.81 159.72,99.15 arc(159.89,99.22) 160.07,99.15 160.35,98.87 arc(160.71,98.87) 160.71,99.23 160.43,99.51 arc(160.43,99.87) 160.79,99.87 161.19,99.47 arc(161.55,99.47) 161.55,99.83 161.15,100.23 arc(161.15,100.59) 161.51,100.59 161.58,100.51 arc(161.94,100.51) 161.94,100.87 161.87,100.94 arc(161.87,101.3) 162.23,101.3 162.6,100.94 arc(162.96,100.94) 162.96,101.3 162.59,101.66 arc(162.51,101.84) 162.59,102.02 164.16,103.6 arc(164.24,103.77) 164.16,103.95 163.88,104.23 arc(163.88,104.59) 164.24,104.59 164.68,104.15 v3(167.58,104.15)
DDR3_B_DM2: length 35
  TOP w0.127: U16.E7 v3(168.38,121.79) ; v2(147.89,101.12) P1.AE3
  BOTTOM w0.102: 152.03,103.43 151.34,102.74 148.91,102.74 148.39,102.22 148.39,101.62 v2(147.89,101.12)
  BOTTOM w0.127: 152.03,103.43 159.92,111.32 159.92,114.8 160.96,115.84 160.96,116.84 arc(160.89,117.02) 160.71,117.09 160.59,117.09 arc(160.34,117.35) 160.59,117.6 160.71,117.6 arc(160.89,117.67) 160.96,117.85 160.96,118.43 163.88,121.35 167.94,121.35 v3(168.38,121.79)
DDR3_B_DM3: length 35.2
  TOP w0.127: U16.D3 v3(167.58,118.59) ; v2(149.89,103.12) P1.AG2
  03_SIG1 w0.127: v2(149.89,103.12) 149.39,103.62 149.39,105.3 149.7,105.62 150.06,105.62 151.16,106.72 151.16,106.98 150.68,107.46 arc(150.68,107.82) 151.04,107.82 151.58,107.27 arc(151.94,107.27) 151.94,107.63 151.41,108.16 arc(151.41,108.52) 151.77,108.52 152.3,107.99 arc(152.66,107.99) 152.66,108.35 152.13,108.88 arc(152.07,109.15) 152.3,109.32 arc(152.4,109.3) 152.49,109.24 153.02,108.71 arc(153.38,108.71) 153.38,109.07 153.34,109.1 arc(153.27,109.28) 153.34,109.46 157.3,113.42 157.3,114.29 162.51,119.49 166.67,119.49 v3(167.58,118.59)
DDR3_B_DM4: length 57.8
  TOP w0.127: U8.E7 v3(168.38,137.83) ; v2(141.89,101.12) P1.AE9
  03_SIG1 w0.102: v2(141.89,101.12) 140.5,102.51 140.5,110.3 140.58,110.38 140.58,110.55
  03_SIG1 w0.127: 140.58,110.55 140.58,111.57 141.6,112.6 141.6,115.05 147.07,120.52 arc(147.15,120.7) 147.07,120.88 146.62,121.33 arc(146.62,121.69) 146.98,121.69 147.46,121.21 arc(147.82,121.21) 147.82,121.57 147.34,122.05 arc(147.34,122.41) 147.7,122.41 148.18,121.93 arc(148.35,121.85) 148.53,121.93 arc(148.61,122.11) 148.53,122.29 147.97,122.86 arc(147.91,123) 147.97,123.14 162.18,137.35 167.9,137.35 v3(168.38,137.83)
DDR3_B_DQ0: length 29.1
  TOP w0.102: P1.AD2 v2(149.89,99.12)
  TOP w0.127: U22.E3 v3(168.38,103.35)
  03_SIG1 w0.127: v2(149.89,99.12) 150.39,98.62 151,98.62 151.35,98.27 159.73,98.27 160.11,98.65 arc(160.27,98.72) 160.43,98.65 160.71,98.37 arc(161.07,98.37) 161.07,98.73 160.8,99 arc(160.73,99.17) 160.8,99.35 161.78,100.32 arc(161.85,100.5) 161.78,100.68 161.42,101.03 arc(161.42,101.39) 161.78,101.39 162.14,101.04 arc(162.49,101.04) 162.49,101.4 162.14,101.75 arc(162.14,102.11) 162.5,102.11 162.85,101.76 arc(163.21,101.76) 163.21,102.12 162.86,102.47 arc(162.86,102.83) 163.22,102.83 163.55,102.5 arc(163.74,102.42) 163.93,102.5 arc(164,102.67) 163.93,102.83 163.83,102.93 163.83,103.11 164.01,103.29 164.21,103.29 164.55,102.95 167.98,102.95 v3(168.38,103.35)
DDR3_B_DQ1: length 29.5
  TOP w0.127: v2(147.89,100.12) P1.AE4 ; U22.F7 v3(169.98,107.35)
  03_SIG1 w0.102: 152.3,101.51 148.69,101.51 148.39,101.21 148.39,101.03 147.89,100.53 v2(147.89,100.12)
  03_SIG1 w0.127: v3(169.98,107.35) 169.25,106.62 168.06,106.62 167.73,106.95 164.83,106.95 164.5,106.62 159.89,106.62 159.44,106.16 arc(159.26,106.09) 159.08,106.16 159.06,106.18 arc(158.7,106.18) 158.7,105.82 158.72,105.8 arc(158.72,105.44) 158.36,105.44 158.34,105.47 arc(157.98,105.47) 157.98,105.11 158,105.08 arc(158,104.72) 157.64,104.72 157.62,104.75 arc(157.26,104.75) 157.26,104.39 157.28,104.37 arc(157.28,104.01) 156.92,104.01 156.9,104.03 arc(156.54,104.03) 156.54,103.67 156.56,103.65 arc(156.64,103.47) 156.56,103.29 154.79,101.51 152.3,101.51
DDR3_B_DQ2: length 32.9
  TOP w0.127: U22.F2 v3(169.18,102.55) ; P1.AB5 v2(146.89,98.12)
  03_SIG1 w0.102: 151.22,97.81 151.14,97.74 147.27,97.74 v2(146.89,98.12)
  03_SIG1 w0.127: 151.22,97.81 151.29,97.89 161.33,97.89 161.78,98.35 arc(161.86,98.53) 161.78,98.71 161.48,99.01 arc(161.48,99.37) 161.84,99.37 162.14,99.06 arc(162.5,99.06) 162.5,99.42 162.2,99.73 arc(162.2,100.08) 162.56,100.08 162.86,99.78 arc(163.22,99.78) 163.22,100.14 162.92,100.44 arc(162.92,100.8) 163.28,100.8 163.58,100.5 arc(163.94,100.5) 163.94,100.86 163.64,101.16 arc(163.64,101.52) 164,101.52 164.3,101.22 arc(164.44,101.15) 164.59,101.17 arc(164.73,101.36) 164.66,101.58 164.36,101.88 arc(164.31,102.18) 164.59,102.31 arc(164.66,102.28) 164.71,102.24 165.02,101.94 arc(165.2,101.86) 165.37,101.94 165.58,102.14 168.77,102.14 v3(169.18,102.55)
DDR3_B_DQ3: length 33.8
  TOP w0.127: U22.F8 v3(169.18,107.35) ; P1.AB10 v2(141.89,98.12)
  03_SIG1 w0.102: v2(141.89,98.12) 142.39,98.62 143.01,98.62 143.39,99 143.39,99.25 143.64,99.51 145.95,99.51 146.39,99.94 146.39,100.22 146.79,100.62 147.04,100.62 147.39,100.97 147.39,101.22 147.9,101.74 151.23,101.74 151.46,101.97 152.37,101.97
  03_SIG1 w0.127: v3(169.18,107.35) 168.78,106.95 168.21,106.95 167.79,107.38 164.6,107.38 164.22,107 158.8,107 155.57,103.77 arc(155.5,103.59) 155.57,103.41 arc(155.57,103.05) 155.21,103.05 arc(155.03,103.12) 154.85,103.05 153.77,101.97 152.37,101.97
DDR3_B_DQ4: length 28.8
  TOP w0.102: P1.AD1 v2(150.89,99.12)
  TOP w0.127: U22.H3 v3(170.78,103.35)
  03_SIG1 w0.127: v2(150.89,99.12) 151.13,99.12 151.6,98.65 157.92,98.65 158.44,99.17 arc(158.62,99.25) 158.8,99.17 159.13,98.84 arc(159.49,98.84) 159.49,99.2 159.16,99.53 arc(159.16,99.89) 159.52,99.89 159.9,99.51 arc(160.26,99.51) 160.26,99.87 159.88,100.25 arc(159.88,100.61) 160.24,100.61 160.62,100.23 arc(160.97,100.23) 160.97,100.59 160.6,100.97 arc(160.52,101.15) 160.6,101.33 163.01,103.74 168.54,103.74 169.35,102.93 169.81,102.93 169.81,102.94 170.14,102.94 170.15,102.93 170.36,102.93 v3(170.78,103.35)
DDR3_B_DQ5: length 29.4
  TOP w0.127: v2(147.89,99.12) P1.AD4 ; U22.H8 v3(170.78,107.35)
  03_SIG1 w0.102: 151.26,100.43 151.13,100.43 151.05,100.51 148.71,100.51 148.51,100.31 148.51,99.74 v2(147.89,99.12)
  03_SIG1 w0.127: v3(170.78,107.35) 171.18,106.94 171.18,105.87 170.99,105.68 162.26,105.68 160.82,104.24 158.86,104.24 155.06,100.43 151.26,100.43
DDR3_B_DQ6: length 32.9
  TOP w0.127: P1.AB6 v2(145.89,98.12) ; U22.G2 v3(169.98,102.55)
  03_SIG1 w0.102: v2(145.89,98.12) 146.5,97.51 151.4,97.51
  03_SIG1 w0.127: 151.4,97.51 161.55,97.51 165.38,101.33 165.72,101.33 arc(165.9,101.26) 165.97,101.08 165.97,100.5 arc(166.22,100.24) 166.48,100.5 166.48,101.08 arc(166.73,101.33) 166.99,101.08 166.99,100.5 arc(167.24,100.24) 167.49,100.5 167.49,101.08 arc(167.75,101.33) 168,101.08 168,100.5 arc(168.26,100.24) 168.51,100.5 168.51,101.08 arc(168.58,101.26) 168.76,101.33 v3(169.98,102.55)
DDR3_B_DQ7: length 31.7
  TOP w0.127: U22.H7 v3(170.78,106.55) ; P1.AC5 v2(146.89,99.12)
  03_SIG1 w0.102: v2(146.89,99.12) 147.4,99.63 147.96,99.63 148.27,99.94 148.27,100.45 148.55,100.74 151.05,100.74 151.13,100.81 151.26,100.81
  03_SIG1 w0.127: 151.26,100.81 154.73,100.81 158.62,104.71 159.16,104.71 arc(159.28,104.76) 159.33,104.89 159.33,105.3 arc(159.59,105.55) 159.84,105.3 159.84,104.97 arc(160.1,104.71) 160.35,104.97 160.35,105.85 arc(160.62,106.12) 160.88,105.85 160.88,105.52 arc(161.14,105.27) 161.39,105.52 161.39,105.85 arc(161.46,106.02) 161.62,106.08 170.31,106.08 v3(170.78,106.55)
DDR3_B_DQ8: length 33.6
  TOP w0.127: U22.D7 v3(167.58,106.55) ; P1.AD6 v2(144.89,100.12)
  06_SIG2 w0.102: 151.38,100.9 151.26,100.9 151.09,100.74 147.03,100.74 146.8,100.51 145.27,100.51 v2(144.89,100.12)
  06_SIG2 w0.127: 151.38,100.9 153.95,100.9 154.08,101.03 arc(154.13,101.16) 154.08,101.28 154.03,101.33 arc(154.03,101.69) 154.39,101.69 154.49,101.59 arc(154.84,101.59) 154.84,101.95 154.75,102.05 arc(154.75,102.41) 155.11,102.41 155.2,102.31 arc(155.56,102.31) 155.56,102.67 155.47,102.77 arc(155.47,103.13) 155.82,103.13 155.92,103.03 arc(156.28,103.03) 156.28,103.39 156.18,103.49 arc(156.18,103.85) 156.54,103.85 156.64,103.75 arc(157,103.75) 157,104.11 156.9,104.21 arc(156.9,104.57) 157.26,104.57 157.36,104.47 arc(157.72,104.47) 157.72,104.83 157.62,104.92 arc(157.62,105.28) 157.98,105.28 158.08,105.19 arc(158.44,105.19) 158.44,105.54 158.34,105.64 arc(158.34,106) 158.7,106 158.8,105.9 arc(159.16,105.9) 159.16,106.26 159.06,106.36 arc(159.06,106.72) 159.42,106.72 159.51,106.62 arc(159.69,106.55) 159.87,106.62 160.19,106.94 167.18,106.94 v3(167.58,106.55)
DDR3_B_DQ9: length 35
  TOP w0.127: v3(166.78,103.35) 166.78,103.35 U22.C3 ; P1.AD7 v2(143.89,99.12)
  06_SIG2 w0.102: 151.51,98.34 151.3,98.34 151.13,98.51 144.5,98.51 v2(143.89,99.12)
  06_SIG2 w0.127: v3(166.78,103.35) 166.38,103.75 164.95,103.75 163.42,102.22 163.42,100.62 arc(163.35,100.44) 163.17,100.37 162.58,100.37 arc(162.33,100.11) 162.58,99.86 163.45,99.86 arc(163.7,99.61) 163.45,99.35 162.2,99.35 arc(161.95,99.1) 162.2,98.84 163.7,98.84 arc(163.96,98.59) 163.7,98.34 151.51,98.34
DDR3_B_DQ10: length 33.5
  TOP w0.127: U22.C8 v3(166.78,108.15) ; v2(145.89,101.12) P1.AE6
  06_SIG2 w0.102: 151.51,101.89 151.36,101.89 151.2,101.74 146.5,101.74 v2(145.89,101.12)
  06_SIG2 w0.127: v3(166.78,108.15) 166.37,107.74 165.34,107.74 arc(165.16,107.81) 165.09,107.99 165.09,108.85 arc(164.87,109.1) 164.59,108.93 arc(164.58,108.89) 164.58,108.85 164.58,107.99 arc(164.33,107.74) 164.07,107.99 164.07,108.85 arc(163.82,109.11) 163.56,108.85 163.56,107.99 arc(163.49,107.81) 163.31,107.74 162.83,107.74 arc(162.66,107.81) 162.59,107.99 162.59,108.85 arc(162.33,109.1) 162.08,108.85 162.08,107.99 arc(161.82,107.73) 161.57,107.99 161.57,108.47 arc(161.32,108.72) 161.06,108.47 161.06,107.99 arc(160.99,107.81) 160.81,107.74 158.63,107.74 152.78,101.89 151.51,101.89
DDR3_B_DQ11: length 36
  TOP w0.127: U22.C2 v3(167.58,103.35) ; P1.AC10 v2(140.89,99.12)
  06_SIG2 w0.102: v2(140.89,99.12) 141.37,99.61 142.01,99.61 142.39,99.99 142.39,100.24 142.89,100.74 146.11,100.74 146.41,101.03 146.41,101.21 146.71,101.51 151.48,101.51
  06_SIG2 w0.127: v3(167.58,103.35) 168.15,103.92 168.15,106.57 167.38,107.33 158.93,107.33 153.11,101.51 151.48,101.51
DDR3_B_DQ12: length 33.6
  TOP w0.127: U22.A7 v3(165.18,106.55) ; v2(146.89,100.12) P1.AD5
  06_SIG2 w0.102: 151.41,100.51 147.27,100.51 v2(146.89,100.12)
  06_SIG2 w0.127: 151.41,100.51 154.45,100.51 155.03,101.09 arc(155.21,101.17) 155.39,101.09 155.74,100.74 arc(156.1,100.74) 156.1,101.1 155.75,101.45 arc(155.75,101.81) 156.11,101.81 156.46,101.46 arc(156.82,101.46) 156.82,101.82 156.47,102.17 arc(156.47,102.53) 156.83,102.53 157.18,102.18 arc(157.54,102.18) 157.54,102.54 157.19,102.89 arc(157.19,103.25) 157.55,103.25 157.9,102.9 arc(158.26,102.9) 158.26,103.26 157.9,103.61 arc(157.9,103.97) 158.26,103.97 158.62,103.62 arc(158.98,103.62) 158.98,103.98 158.62,104.33 arc(158.62,104.69) 158.98,104.69 159.33,104.33 arc(159.69,104.33) 159.69,104.69 159.34,105.05 arc(159.34,105.4) 159.7,105.4 160.05,105.05 arc(160.41,105.05) 160.41,105.41 160.06,105.76 arc(160.06,106.12) 160.42,106.12 160.77,105.77 arc(160.95,105.7) 161.13,105.77 161.91,106.55 v3(165.18,106.55)
DDR3_B_DQ13: length 35.1
  TOP w0.127: P1.AD11 v2(140.89,100.12) ; U22.A2 v3(165.18,102.55)
  06_SIG2 w0.102: v2(140.89,100.12) 140.46,99.7 140.46,97.85 140.81,97.51 151.13,97.51 151.21,97.43 151.38,97.43
  06_SIG2 w0.127: 151.38,97.43 165.11,97.43 165.53,97.85 165.53,100.08 arc(165.61,100.26) 165.79,100.34 166.07,100.34 arc(166.32,100.59) 166.07,100.85 165.79,100.85 arc(165.61,100.92) 165.53,101.1 165.53,102.19 v3(165.18,102.55)
DDR3_B_DQ14: length 33.5
  TOP w0.102: v2(144.89,101.12) P1.AE7
  TOP w0.127: U22.B8 v3(165.98,108.15)
  06_SIG2 w0.127: v3(165.98,108.15) 165.58,108.54 165.58,109.44 165.4,109.61 161.77,109.61 arc(161.64,109.56) 161.58,109.43 arc(161.33,109.17) 161.07,109.43 161.07,110.01 arc(160.99,110.21) 160.78,110.3 arc(160.61,110.23) 160.53,110.05 160.53,108.44 arc(160.28,108.19) 160.03,108.44 160.03,109.98 arc(159.77,110.23) 159.52,109.98 159.52,108.48 arc(159.44,108.3) 159.25,108.22 158.42,108.22 152.83,102.63 145.75,102.63 145.39,102.27 145.39,101.63 v2(144.89,101.12)
DDR3_B_DQ15: length 35.8
  TOP w0.127: P1.AC9 v2(141.89,99.12) ; U22.A3 v3(165.18,103.35)
  06_SIG2 w0.102: 151.45,97.88 151.27,97.88 151.13,97.74 142.69,97.74 142.37,98.06 142.37,98.64 v2(141.89,99.12)
  06_SIG2 w0.127: v3(165.18,103.35) 164.29,102.46 164.29,102.31 arc(164.34,102.18) 164.47,102.13 164.87,102.13 arc(165.13,101.87) 164.87,101.62 164.13,101.62 arc(163.88,101.37) 164.13,101.11 164.87,101.11 arc(165.13,100.86) 164.87,100.6 164.16,100.6 arc(163.91,100.35) 164.16,100.1 164.95,100.1 165.07,99.97 165.07,98.13 164.82,97.88 151.45,97.88
DDR3_B_DQ16: length 36.7
  TOP w0.127: U16.E3 v3(168.38,118.59) ; v2(146.89,101.12) P1.AF4
  BOTTOM w0.102: v2(146.89,101.12) 147.51,100.5 152.3,100.5
  BOTTOM w0.127: 152.3,100.5 153.12,100.5 164.03,111.42 164.03,115.93 arc(164.11,116.11) 164.28,116.18 arc(164.47,116.1) 164.55,115.91 164.55,115.68 arc(164.8,115.42) 165.06,115.68 165.06,115.91 arc(165.14,116.11) 165.34,116.19 166.22,116.19 arc(166.39,116.26) 166.46,116.43 166.46,116.86 arc(166.71,117.11) 166.97,116.86 166.97,116.43 arc(167.04,116.26) 167.21,116.19 167.67,116.19 167.98,116.51 167.98,118.19 v3(168.38,118.59)
DDR3_B_DQ17: length 38.8
  TOP w0.127: U16.F7 v3(169.18,122.59) ; v2(147.89,103.12) 146.89,103.12 P1.AG5
  BOTTOM w0.102: 152.32,104.86 151.2,103.74 148.76,103.74 148.14,103.12 v2(147.89,103.12)
  BOTTOM w0.127: v3(169.18,122.59) 168.77,122.99 164.28,122.99 161.61,120.32 arc(161.43,120.24) 161.25,120.32 161.07,120.49 arc(160.71,120.49) 160.71,120.13 160.89,119.96 arc(160.89,119.6) 160.53,119.6 160.35,119.77 arc(159.99,119.77) 159.99,119.41 160.17,119.24 arc(160.17,118.88) 159.81,118.88 159.63,119.05 arc(159.28,119.05) 159.28,118.7 159.45,118.52 arc(159.52,118.34) 159.45,118.16 159.08,117.79 159.08,111.62 152.32,104.86
DDR3_B_DQ18: length 36.3
  TOP w0.127: v3(169.18,118.59) 169.18,118.59 U16.F2 ; v2(148.89,101.12) P1.AF3
  BOTTOM w0.102: v2(148.89,101.12) 149.27,100.74 151.41,100.74 151.55,100.89 152.87,100.89
  BOTTOM w0.127: v3(169.18,118.59) 169.13,118.59 168.66,119.06 164.97,119.06 163.6,117.69 163.6,117.44 arc(163.67,117.28) 163.83,117.21 165.15,117.21 arc(165.41,116.95) 165.15,116.7 163.83,116.7 arc(163.67,116.63) 163.6,116.47 163.6,111.62 152.87,100.89
DDR3_B_DQ19: length 40
  TOP w0.127: v2(145.89,102.12) P1.AF6 ; U16.F8 v3(169.18,123.39)
  BOTTOM w0.102: v2(145.89,102.12) 146,102.12 147.51,103.63 147.99,103.63 148.36,104 148.36,104.23 148.64,104.5 151.37,104.5 152.12,105.24
  BOTTOM w0.127: 152.12,105.24 158.7,111.83 158.7,119.09 160.86,121.25 arc(161.04,121.32) 161.22,121.25 161.35,121.11 arc(161.71,121.11) 161.71,121.47 161.58,121.6 arc(161.58,121.96) 161.93,121.96 162.07,121.83 arc(162.43,121.83) 162.43,122.19 162.29,122.32 arc(162.22,122.5) 162.29,122.68 162.46,122.85 163.42,122.85 164.36,123.78 168.78,123.78 v3(169.18,123.39)
DDR3_B_DQ20: length 35.1
  TOP w0.127: U16.H3 v3(170.78,119.39) ; v2(148.89,102.12) P1.AG3
  BOTTOM w0.102: 151.87,102.68 151.69,102.5 149.27,102.5 v2(148.89,102.12)
  BOTTOM w0.127: v3(170.78,119.39) 169.25,120.92 164.06,120.92 161.44,118.3 161.44,115.63 160.38,114.57 160.38,111.19 151.87,102.68
DDR3_B_DQ21: length 39.9
  TOP w0.127: U16.H8 v3(170.78,123.39) ; v2(145.89,103.12) P1.AG6
  BOTTOM w0.102: v2(145.89,103.12) 146.32,103.12 147.93,104.74 151.06,104.74 152.65,106.34
  BOTTOM w0.127: v3(170.78,123.39) 170.38,123.78 169.65,123.78 168.81,124.63 164.03,124.63 163.35,123.94 162.86,123.94 158.32,119.39 158.32,112 152.65,106.34
DDR3_B_DQ22: length 35.1
  TOP w0.127: U16.G2 v3(169.98,117.79) ; P1.AE2 v2(149.89,100.12)
  BOTTOM w0.127: v2(149.89,100.12) 153.37,100.12 164.97,111.72 164.97,114.62 165.79,115.43 168.65,115.43 arc(168.77,115.41) 168.87,115.34 169.07,115.14 arc(169.43,115.14) 169.43,115.5 168.74,116.19 arc(168.74,116.55) 169.1,116.55 169.79,115.86 arc(170.15,115.86) 170.15,116.21 169.46,116.91 arc(169.38,117.09) 169.46,117.27 v3(169.98,117.79)
DDR3_B_DQ23: length 38.9
  TOP w0.127: v2(146.89,102.12) P1.AF5 ; U16.H7 v3(170.78,122.59)
  BOTTOM w0.102: v2(146.89,102.12) 147.44,102.68 148.34,102.68 149.16,103.5 151.54,103.5 152.52,104.48
  BOTTOM w0.127: v3(170.78,122.59) 170.38,122.19 164.09,122.19 159.46,117.56 159.46,116.72 arc(159.54,116.54) 159.72,116.46 160.25,116.46 arc(160.5,116.21) 160.25,115.95 159.72,115.95 arc(159.54,115.88) 159.46,115.7 159.46,111.43 152.52,104.48
DDR3_B_DQ24: length 35.2
  TOP w0.114: U16.D7 v3(167.58,122.59)
  TOP w0.127: v2(148.89,104.12) P1.AJ2
  03_SIG1 w0.102: 147.27,109.54 147.27,105.72 147.51,105.49 147.51,104.91 147.79,104.62 148.39,104.62 v2(148.89,104.12)
  03_SIG1 w0.127: 147.27,109.54 147.27,109.87 147.6,110.2 147.6,112.36 157.66,122.42 164.39,122.42 164.97,122.99 167.17,122.99 v3(167.58,122.59)
DDR3_B_DQ25: length 33.8
  TOP w0.127: U16.C3 v3(166.78,118.59) ; P1.AK1 v2(149.89,105.12)
  03_SIG1 w0.127: v2(149.89,105.12) 150.25,105.12 150.9,105.78 151.15,105.78 154.06,108.69 arc(154.14,108.87) 154.06,109.05 154,109.11 arc(154,109.47) 154.36,109.47 154.42,109.41 arc(154.78,109.41) 154.78,109.77 154.72,109.83 arc(154.72,110.18) 155.08,110.18 155.14,110.13 arc(155.5,110.13) 155.5,110.49 155.44,110.54 arc(155.44,110.9) 155.8,110.9 155.86,110.84 arc(156.22,110.84) 156.22,111.2 156.16,111.26 arc(156.16,111.62) 156.52,111.62 156.58,111.56 arc(156.94,111.56) 156.94,111.92 156.88,111.98 arc(156.88,112.34) 157.24,112.34 157.3,112.28 arc(157.66,112.28) 157.66,112.64 157.6,112.7 arc(157.6,113.06) 157.96,113.06 157.99,113.03 arc(158.2,112.94) 158.4,113.03 arc(158.48,113.21) 158.4,113.38 157.95,113.84 arc(157.95,114.2) 158.31,114.2 158.76,113.74 arc(159.12,113.74) 159.12,114.1 158.67,114.56 arc(158.67,114.92) 159.03,114.92 159.48,114.46 arc(159.84,114.46) 159.84,114.82 159.35,115.31 arc(159.27,115.49) 159.35,115.67 162.76,119.09 166.28,119.09 v3(166.78,118.59)
DDR3_B_DQ26: length 35
  TOP w0.127: v2(146.89,105.12) P1.AJ4 ; U16.C8 v3(166.78,123.39)
  03_SIG1 w0.102: v2(146.89,105.12) 146.27,105.74 146.27,109.89
  03_SIG1 w0.127: v3(166.78,123.39) 166.38,123.78 164.36,123.78 164.18,123.96 162.65,123.96 arc(162.47,123.89) 162.39,123.71 162.39,123.58 arc(162.14,123.32) 161.89,123.58 161.89,123.71 arc(161.81,123.89) 161.63,123.96 158.09,123.96 146.79,112.66 146.79,110.66 146.27,110.14 146.27,109.89
DDR3_B_DQ27: length 34.7
  TOP w0.127: U16.C2 v3(166.78,117.79) ; v2(149.89,104.12) P1.AH2
  03_SIG1 w0.127: v2(149.89,104.12) 150.39,104.62 151.35,104.62 151.64,104.33 152.5,104.33 154.55,106.38 arc(154.62,106.56) 154.55,106.74 154.24,107.05 arc(154.24,107.41) 154.59,107.41 154.93,107.08 arc(155.29,107.08) 155.29,107.44 154.95,107.77 arc(154.95,108.13) 155.31,108.13 155.64,107.8 arc(156,107.8) 156,108.16 155.67,108.49 arc(155.67,108.85) 156.03,108.85 156.36,108.52 arc(156.72,108.52) 156.72,108.88 156.39,109.21 arc(156.39,109.57) 156.75,109.57 157.08,109.23 arc(157.44,109.23) 157.44,109.59 157.11,109.93 arc(157.11,110.28) 157.47,110.28 157.8,109.96 arc(158.16,109.96) 158.16,110.32 157.83,110.64 arc(157.83,111) 158.19,111 158.53,110.66 arc(158.88,110.66) 158.88,111.02 158.47,111.44 arc(158.42,111.55) 158.47,111.67 164.98,118.18 166.38,118.18 v3(166.78,117.79)
DDR3_B_DQ28: length 34.9
  TOP w0.127: P1.AK2 v2(148.89,105.12) ; U16.A7 v3(165.18,122.59)
  03_SIG1 w0.102: v2(148.89,105.12) 148.41,105.6 147.83,105.6 147.5,105.93 147.5,109.46 147.7,109.66
  03_SIG1 w0.127: v3(165.18,122.59) 164.57,121.98 163.88,121.98 arc(163.7,121.91) 163.62,121.73 163.62,121.63 arc(163.37,121.37) 163.12,121.63 163.12,121.73 arc(162.86,121.98) 162.61,121.73 162.61,121.63 arc(162.35,121.37) 162.1,121.63 162.1,121.73 arc(161.85,121.98) 161.59,121.73 161.59,121.63 arc(161.34,121.37) 161.08,121.63 161.08,121.73 arc(160.83,121.98) 160.58,121.73 160.58,121.63 arc(160.32,121.37) 160.07,121.63 160.07,121.73 arc(159.81,121.98) 159.56,121.73 159.56,121.63 arc(159.31,121.37) 159.05,121.63 159.05,121.73 arc(158.98,121.91) 158.8,121.98 157.78,121.98 148.01,112.2 148.01,109.97 147.7,109.66
DDR3_B_DQ29: length 35.5
  TOP w0.127: v2(150.89,103.12) P1.AG1 ; U16.A2 v3(165.18,117.79)
  03_SIG1 w0.127: v2(150.89,103.12) 151.59,103.82 152.73,103.82 159.59,110.68 arc(159.66,110.86) 159.59,111.04 159.24,111.39 arc(159.24,111.75) 159.6,111.75 159.95,111.4 arc(160.31,111.4) 160.31,111.76 159.96,112.11 arc(159.96,112.47) 160.32,112.47 160.67,112.12 arc(161.02,112.12) 161.02,112.48 160.67,112.83 arc(160.67,113.19) 161.03,113.19 161.38,112.84 arc(161.74,112.84) 161.74,113.2 161.39,113.55 arc(161.39,113.91) 161.75,113.91 162.1,113.56 arc(162.46,113.56) 162.46,113.92 162.11,114.27 arc(162.11,114.63) 162.47,114.63 162.82,114.28 arc(163.18,114.28) 163.18,114.64 162.83,114.99 arc(162.83,115.35) 163.19,115.35 163.54,115 arc(163.9,115) 163.9,115.36 163.55,115.71 arc(163.55,116.07) 163.91,116.07 164.26,115.72 arc(164.61,115.72) 164.61,116.08 164.26,116.43 arc(164.26,116.78) 164.62,116.78 164.94,116.47 arc(165.14,116.39) 165.33,116.47 arc(165.41,116.65) 165.33,116.82 164.89,117.27 164.89,117.5 v3(165.18,117.79)
DDR3_B_DQ30: length 35.1
  TOP w0.127: P1.AH4 v2(147.89,104.12) ; U16.B8 v3(165.98,123.39)
  03_SIG1 w0.102: 146.63,109.87 146.5,109.73 146.5,105.85 146.75,105.6 146.95,105.6 147.27,105.28 147.27,104.74 v2(147.89,104.12)
  03_SIG1 w0.127: v3(165.98,123.39) 164.72,123.39 164.19,122.85 161.55,122.85 arc(161.37,122.92) 161.29,123.1 arc(161.04,123.36) 160.78,123.1 arc(160.53,122.85) 160.28,123.1 arc(160.02,123.36) 159.77,123.1 arc(159.69,122.92) 159.51,122.85 157.53,122.85 147.19,112.51 147.19,110.43 146.63,109.87
DDR3_B_DQ31: length 34.7
  TOP w0.127: U16.A3 v3(165.18,118.59) ; v2(150.89,105.12) P1.AJ1
  03_SIG1 w0.127: v2(150.89,105.12) 151.14,105.37 arc(151.33,105.45) 151.53,105.37 152.01,104.89 arc(152.15,104.82) 152.3,104.84 arc(152.44,105.02) 152.37,105.25 152.01,105.61 arc(151.98,105.94) 152.3,106.02 arc(152.33,106) 152.37,105.97 152.73,105.6 arc(153.09,105.6) 153.09,105.96 152.73,106.33 arc(152.73,106.69) 153.08,106.69 153.45,106.32 arc(153.81,106.32) 153.81,106.68 153.44,107.05 arc(153.37,107.23) 153.44,107.41 160.57,114.53 arc(160.64,114.71) 160.57,114.89 160.17,115.29 arc(160.17,115.65) 160.52,115.65 160.93,115.25 arc(161.29,115.25) 161.29,115.61 160.88,116.01 arc(160.88,116.37) 161.24,116.37 161.65,115.97 arc(162,115.97) 162,116.33 161.6,116.73 arc(161.6,117.09) 161.96,117.09 162.36,116.69 arc(162.72,116.69) 162.72,117.05 162.32,117.45 arc(162.32,117.81) 162.68,117.81 163.08,117.4 arc(163.44,117.4) 163.44,117.76 163.04,118.17 arc(163.04,118.53) 163.4,118.53 163.8,118.12 arc(163.98,118.05) 164.16,118.12 164.62,118.59 v3(165.18,118.59)
DDR3_B_DQ32: length 57.6
  TOP w0.127: U8.E3 v3(168.38,133.83) ; v2(142.89,101.12) P1.AF9
  03_SIG1 w0.102: 143.58,109.52 143.5,109.43 143.5,101.74 v2(142.89,101.12)
  03_SIG1 w0.127: v3(168.38,133.83) 167.97,133.42 167.97,132.03 arc(167.89,131.83) 167.69,131.75 166.42,131.75 arc(166.16,131.5) 166.42,131.24 167.44,131.24 arc(167.62,131.17) 167.69,130.99 arc(167.61,130.79) 167.41,130.71 166.59,130.71 arc(166.33,130.45) 166.59,130.2 167.67,130.2 arc(167.85,130.13) 167.92,129.95 167.92,129.66 167.77,129.5 165.71,129.5 arc(165.53,129.58) 165.46,129.76 165.46,130.35 arc(165.2,130.6) 164.95,130.35 164.95,129.76 arc(164.87,129.58) 164.69,129.5 162.74,129.5 arc(162.56,129.58) 162.49,129.76 162.49,130.36 arc(162.23,130.62) 161.98,130.36 161.98,129.76 arc(161.9,129.58) 161.72,129.5 160.68,129.5 144.78,113.6 144.78,110.71 143.58,109.52
DDR3_B_DQ33: length 57.7
  TOP w0.127: P1.AG11 v2(140.89,103.12) ; U8.F7 v3(169.18,137.83)
  03_SIG1 w0.102: 141.2,110.55 141.2,110.38 141.27,110.3 141.27,103.51 v2(140.89,103.12)
  03_SIG1 w0.127: 141.2,110.55 141.2,111.54 141.99,112.33 141.99,114.77 149.25,122.03 arc(149.32,122.21) 149.25,122.39 148.76,122.88 arc(148.76,123.24) 149.12,123.24 149.61,122.75 arc(149.97,122.75) 149.97,123.11 149.48,123.6 arc(149.48,123.96) 149.84,123.96 150.33,123.47 arc(150.69,123.47) 150.69,123.83 150.19,124.32 arc(150.19,124.68) 150.55,124.68 151.05,124.19 arc(151.23,124.11) 151.41,124.19 arc(151.48,124.37) 151.41,124.55 150.87,125.09 arc(150.79,125.27) 150.87,125.45 162.38,136.97 168.32,136.97 v3(169.18,137.83)
DDR3_B_DQ34: length 58
  TOP w0.127: v2(143.89,102.12) P1.AF8 ; U8.F2 v3(169.18,133.03)
  03_SIG1 w0.102: 144.37,109.51 144.27,109.41 144.27,102.51 v2(143.89,102.12)
  03_SIG1 w0.127: 144.37,109.51 145.16,110.3 145.16,113.42 159.94,128.21 160.51,128.21 arc(160.67,128.27) 160.74,128.43 160.74,128.79 arc(160.81,128.97) 160.99,129.04 arc(161.17,128.97) 161.25,128.79 161.25,128.43 arc(161.31,128.27) 161.47,128.21 161.53,128.21 arc(161.69,128.27) 161.75,128.43 161.75,128.79 arc(162.01,129.04) 162.26,128.79 162.26,128.43 arc(162.33,128.27) 162.49,128.21 162.54,128.21 arc(162.7,128.27) 162.77,128.43 162.77,128.79 arc(162.84,128.97) 163.02,129.04 arc(163.2,128.97) 163.28,128.79 163.28,128.43 arc(163.34,128.27) 163.5,128.21 163.56,128.21 arc(163.72,128.27) 163.79,128.43 163.79,128.52 arc(164.04,128.77) 164.29,128.52 164.29,128.43 arc(164.36,128.27) 164.52,128.21 164.75,128.21 arc(164.91,128.27) 164.98,128.43 164.98,128.92 arc(165.05,129.08) 165.21,129.14 arc(165.41,129.06) 165.49,128.86 165.49,128.43 arc(165.55,128.27) 165.71,128.21 166.18,128.21 arc(166.34,128.27) 166.4,128.43 166.4,128.81 arc(166.48,128.99) 166.66,129.07 arc(166.84,128.99) 166.91,128.81 166.91,128.43 arc(166.98,128.27) 167.14,128.21 167.19,128.21 arc(167.35,128.27) 167.42,128.43 167.42,128.81 arc(167.67,129.07) 167.93,128.81 167.93,128.43 arc(167.99,128.27) 168.15,128.21 168.99,128.21 169.18,128.4 169.18,130.55 arc(169.1,130.73) 168.92,130.81 168.5,130.81 arc(168.24,131.06) 168.5,131.32 168.92,131.32 arc(169.1,131.39) 169.18,131.57 v3(169.18,133.03)
DDR3_B_DQ35: length 57.8
  TOP w0.127: U8.F8 v3(169.18,138.63) ; v2(139.89,102.12) P1.AF11
  03_SIG1 w0.102: v2(139.89,102.12) 140.27,102.51 140.27,110.3 140.2,110.38 140.2,110.55
  03_SIG1 w0.127: 140.2,110.55 140.2,111.82 141.22,112.85 141.22,115.33 144.84,118.94 arc(144.91,119.12) 144.84,119.3 144.4,119.74 arc(144.4,120.1) 144.76,120.1 145.2,119.66 arc(145.56,119.66) 145.56,120.02 145.12,120.46 arc(145.12,120.82) 145.48,120.82 145.92,120.38 arc(146.1,120.31) 146.28,120.38 146.28,120.38 arc(146.36,120.58) 146.28,120.77 145.84,121.21 arc(145.76,121.39) 145.84,121.57 162.03,137.76 163.98,137.76 164.46,138.23 168.78,138.23 v3(169.18,138.63)
DDR3_B_DQ36: length 58
  TOP w0.127: v2(142.89,103.12) P1.AH9 ; U8.H3 v3(170.78,133.83)
  03_SIG1 w0.102: 143.4,109.92 143.27,109.79 143.27,103.51 v2(142.89,103.12)
  03_SIG1 w0.127: 143.4,109.92 144.4,110.92 144.4,113.78 161.98,131.36 arc(162.16,131.43) 162.34,131.36 163.3,130.4 arc(163.66,130.4) 163.66,130.76 162.7,131.72 arc(162.7,132.08) 163.06,132.08 164.02,131.12 arc(164.38,131.12) 164.38,131.47 163.41,132.44 arc(163.41,132.8) 163.77,132.8 164.77,131.8 arc(165.13,131.8) 165.13,132.15 164.13,133.15 arc(164.06,133.33) 164.13,133.51 164.92,134.3 168.46,134.3 169.33,133.43 170.38,133.43 v3(170.78,133.83)
DDR3_B_DQ37: length 57.2
  TOP w0.127: P1.AE11 v2(139.89,101.12) ; U8.H8 v3(170.78,138.63)
  03_SIG1 w0.127: v3(170.78,138.63) 170.38,139.02 164.1,139.02 163.25,138.16 161.87,138.16 143.79,120.08 143.79,118.55 140.84,115.61 140.84,113.09 139.4,111.65 139.4,101.61 v2(139.89,101.12)
DDR3_B_DQ38: length 58
  TOP w0.127: U8.G2 v3(169.98,133.03) ; v2(143.89,101.12) P1.AE8
  03_SIG1 w0.102: 144.55,109.21 144.5,109.16 144.5,101.74 v2(143.89,101.12)
  03_SIG1 w0.127: 144.55,109.21 145.54,110.2 145.54,113.25 160.07,127.77 160.39,127.77 arc(160.57,127.7) 160.64,127.52 160.64,126.94 arc(160.9,126.68) 161.15,126.94 161.15,127.52 arc(161.4,127.77) 161.66,127.52 161.66,126.94 arc(161.91,126.68) 162.17,126.94 162.17,127.52 arc(162.42,127.77) 162.67,127.52 162.67,126.94 arc(162.93,126.68) 163.18,126.94 163.18,127.52 arc(163.44,127.77) 163.69,127.52 163.69,126.94 arc(163.94,126.68) 164.2,126.94 164.2,127.52 arc(164.33,127.74) 164.59,127.73 arc(164.68,127.64) 164.71,127.52 164.71,126.94 arc(164.96,126.68) 165.21,126.94 165.21,127.52 arc(165.29,127.7) 165.47,127.77 169.14,127.77 169.57,128.21 169.57,132.62 v3(169.98,133.03)
DDR3_B_DQ39: length 58.1
  TOP w0.127: v2(141.89,104.12) P1.AH10 ; U8.H7 v3(170.78,137.83)
  03_SIG1 w0.102: 141.58,110.55 141.58,110.38 141.5,110.3 141.5,104.51 v2(141.89,104.12)
  03_SIG1 w0.127: 141.58,110.55 141.58,111.29 142.37,112.08 142.37,114.49 152.19,124.31 arc(152.26,124.49) 152.19,124.67 151.8,125.06 arc(151.8,125.42) 152.16,125.42 152.55,125.03 arc(152.91,125.03) 152.91,125.39 152.52,125.78 arc(152.52,126.14) 152.88,126.14 153.27,125.75 arc(153.63,125.75) 153.63,126.11 153.24,126.5 arc(153.24,126.86) 153.59,126.86 153.98,126.47 arc(154.34,126.47) 154.34,126.83 153.95,127.22 arc(153.95,127.58) 154.31,127.58 154.7,127.19 arc(154.88,127.11) 155.06,127.19 155.3,127.42 155.3,129.32 162.56,136.59 169.54,136.59 v3(170.78,137.83)
DDR3_B_DQS0N: length 34.9
  TOP w0.114: U22.G3 v3(169.98,103.35)
  TOP w0.127: P1.AB7 v2(144.89,98.12)
  03_SIG1 w0.102: v2(144.89,98.12) 144.82,98.06 144.5,98.06 144.37,98.18 144.37,98.44 144.45,98.51 148.61,98.51 149.61,99.51 151.16,99.51 151.21,99.46 151.23,99.46
  03_SIG1 w0.114: 151.23,99.46 157.56,99.46 157.96,99.87 arc(158.15,100.33) 157.96,100.8 157.63,101.13 arc(157.54,101.35) 157.63,101.57 157.65,101.59 arc(157.9,101.69) 158.14,101.59 158.45,101.28 arc(159.38,101.28) 159.38,102.22 159.07,102.53 arc(158.97,102.77) 159.07,103.01 arc(159.32,103.11) 159.56,103.01 159.86,102.7 arc(160.33,102.51) 160.8,102.7 162.68,104.58 168.46,104.58 169.46,103.59 169.86,103.59 169.98,103.47 v3(169.98,103.35)
DDR3_B_DQS0P: length 34.9
  TOP w0.114: U22.F3 v3(169.98,104.15)
  TOP w0.127: v2(143.89,98.12) P1.AB8
  03_SIG1 w0.102: v2(143.89,98.12) 143.99,98.12 144.15,98.28 144.15,98.53 144.35,98.74 148.52,98.74 149.52,99.74 151.16,99.74 151.21,99.78 151.23,99.78
  03_SIG1 w0.114: 151.23,99.78 157.43,99.78 157.74,100.09 arc(157.84,100.33) 157.74,100.58 157.4,100.91 arc(157.22,101.35) 157.4,101.79 157.43,101.82 arc(157.9,102.01) 158.36,101.82 158.67,101.51 arc(159.15,101.51) 159.15,101.99 158.85,102.3 arc(158.65,102.77) 158.85,103.23 arc(159.32,103.43) 159.78,103.23 160.09,102.93 arc(160.33,102.83) 160.57,102.93 162.55,104.9 168.59,104.9 169.59,103.91 169.86,103.91 169.98,104.02 v3(169.98,104.15)
DDR3_B_DQS1N: length 35.6
  TOP w0.114: U22.B7 v3(165.98,106.55)
  TOP w0.127: v2(142.89,100.12) P1.AD9
  06_SIG2 w0.102: v2(142.89,100.12) 142.89,99.84 142.99,99.74 150.02,99.74 150.06,99.78 150.09,99.78
  06_SIG2 w0.114: v3(165.98,106.55) 166.15,106.55 166.27,106.43 166.27,105.89 166.15,105.78 162.39,105.78 161.9,105.29 arc(161.71,104.82) 161.9,104.35 162.36,103.89 arc(162.45,103.66) 162.36,103.44 arc(162.1,103.33) 161.84,103.44 161.41,103.87 arc(160.48,103.87) 160.48,102.93 160.94,102.47 arc(161.04,102.25) 160.94,102.02 arc(160.68,101.91) 160.43,102.02 159.99,102.45 arc(159.06,102.45) 159.06,101.51 159.52,101.05 arc(159.62,100.83) 159.52,100.6 arc(159.26,100.49) 159.01,100.6 158.58,101.03 arc(158.11,101.22) 157.64,101.03 156.47,99.86 150.34,99.86 150.26,99.78 150.09,99.78
DDR3_B_DQS1P: length 35.8
  TOP w0.114: U22.C7 v3(166.78,106.55)
  TOP w0.127: P1.AC8 v2(142.89,99.12)
  06_SIG2 w0.102: 150.09,99.46 150.06,99.46 150.02,99.51 143.27,99.51 v2(142.89,99.12)
  06_SIG2 w0.114: v3(166.78,106.55) 166.59,106.36 166.59,105.76 166.29,105.46 162.52,105.46 162.12,105.06 arc(162.02,104.82) 162.12,104.58 162.59,104.11 arc(162.77,103.66) 162.59,103.21 arc(162.1,103.01) 161.62,103.21 161.19,103.64 arc(160.7,103.64) 160.7,103.16 161.17,102.7 arc(161.35,102.25) 161.17,101.79 arc(160.68,101.59) 160.2,101.79 159.77,102.22 arc(159.29,102.22) 159.29,101.74 159.75,101.28 arc(159.93,100.83) 159.75,100.38 arc(159.26,100.18) 158.78,100.38 158.35,100.81 arc(158.11,100.91) 157.87,100.81 156.6,99.54 150.47,99.54 150.4,99.46 150.09,99.46
DDR3_B_DQS2N: length 33.7
  TOP w0.114: U16.G3 v3(169.98,118.59) ; P1.AE1 v2(150.89,101.12)
  BOTTOM w0.114: v2(150.89,101.12) 151.31,101.55 152.31,101.55 162.79,112.03 162.79,112.72 arc(162.6,113.18) 162.13,113.38 161.93,113.38 arc(161.59,113.72) 161.93,114.06 162.13,114.06 arc(162.6,114.26) 162.79,114.72 162.79,118.07 164.48,119.76 168.6,119.76 169.53,118.83 169.86,118.83 169.98,118.71 v3(169.98,118.59)
DDR3_B_DQS2P: length 33.7
  TOP w0.114: U16.F3 v3(169.98,119.39) ; P1.AF1 v2(150.89,102.12)
  BOTTOM w0.114: v2(150.89,102.12) 151.14,101.87 152.18,101.87 162.47,112.16 162.47,112.72 arc(162.37,112.96) 162.13,113.06 161.93,113.06 arc(161.27,113.72) 161.93,114.38 162.13,114.38 arc(162.37,114.48) 162.47,114.72 162.47,118.2 164.35,120.08 168.34,120.08 168.73,120.08 169.67,119.15 169.86,119.15 169.98,119.26 v3(169.98,119.39)
DDR3_B_DQS3N: length 33.8
  TOP w0.114: U16.B7 v3(166.78,121.79)
  TOP w0.127: v2(148.89,106.12) P1.AK3
  03_SIG1 w0.102: v2(148.89,106.12) 148.6,106.12 148.5,106.22 148.5,108.49 148.62,108.6 148.68,108.6 148.7,108.62
  03_SIG1 w0.114: v3(166.78,121.79) 166.54,122.03 166.1,122.03 164.42,120.35 157.62,120.35 157.5,120.22 arc(157.4,119.98) 157.5,119.74 157.83,119.41 arc(158.02,118.94) 157.83,118.47 arc(157.36,118.28) 156.89,118.47 156.56,118.8 arc(156.08,118.8) 156.08,118.32 156.41,117.99 arc(156.6,117.52) 156.41,117.05 arc(155.94,116.86) 155.48,117.05 155.14,117.38 arc(154.9,117.48) 154.66,117.38 149.24,111.96 149.24,109.16 148.7,108.62
DDR3_B_DQS3P: length 34
  TOP w0.114: U16.C7 v3(166.78,122.59)
  TOP w0.127: v2(147.89,106.12) P1.AK4
  03_SIG1 w0.102: 148.47,108.85 148.45,108.83 148.45,108.77 148.27,108.58 148.27,106.51 v2(147.89,106.12)
  03_SIG1 w0.114: v3(166.78,122.59) 166.54,122.35 165.97,122.35 164.29,120.66 157.49,120.66 157.27,120.45 arc(157.08,119.98) 157.27,119.51 157.6,119.18 arc(157.7,118.94) 157.6,118.7 arc(157.36,118.6) 157.12,118.7 156.79,119.03 arc(155.85,119.03) 155.85,118.09 156.19,117.76 arc(156.29,117.52) 156.19,117.28 arc(155.94,117.18) 155.7,117.28 155.37,117.61 arc(154.9,117.8) 154.43,117.61 148.92,112.09 148.92,109.3 148.47,108.85
DDR3_B_DQS4N: length 57.9
  TOP w0.114: U8.G3 v3(169.98,133.83)
  TOP w0.127: v2(141.89,102.12) P1.AF10
  03_SIG1 w0.102: v2(141.89,102.12) 141.89,102.46 141.99,102.56 142.27,102.56 142.5,102.8 142.5,110.46 142.55,110.5 142.55,110.53
  03_SIG1 w0.114: v3(169.98,133.83) 169.98,133.95 169.86,134.07 169.51,134.07 168.58,135 162.67,135 162.4,134.73 arc(162.3,134.48) 162.4,134.24 162.59,134.05 arc(162.78,133.58) 162.59,133.11 arc(162.12,132.92) 161.66,133.11 161.47,133.31 arc(160.98,133.31) 160.98,132.82 161.17,132.63 arc(161.37,132.16) 161.17,131.7 arc(160.71,131.5) 160.24,131.7 160.05,131.89 arc(159.56,131.89) 159.56,131.4 159.75,131.21 arc(159.95,130.74) 159.75,130.28 arc(159.29,130.08) 158.82,130.28 158.63,130.47 arc(158.14,130.47) 158.14,129.98 158.33,129.79 arc(158.53,129.32) 158.33,128.86 arc(157.87,128.66) 157.4,128.86 157.21,129.05 arc(156.72,129.05) 156.72,128.57 156.92,128.37 arc(157.11,127.91) 156.92,127.44 143.38,113.91 143.38,111.65 142.55,110.81 142.55,110.53
DDR3_B_DQS4P: length 57.9
  TOP w0.114: U8.F3 v3(169.98,134.63)
  TOP w0.127: v2(141.89,103.12) P1.AG10
  03_SIG1 w0.102: v2(141.89,103.12) 141.89,102.89 141.99,102.79 142.17,102.79 142.27,102.89 142.27,110.46 142.23,110.5 142.23,110.53
  03_SIG1 w0.114: v3(169.98,134.63) 169.98,134.5 169.86,134.39 169.64,134.39 168.71,135.32 162.54,135.32 162.17,134.95 arc(161.98,134.48) 162.17,134.02 162.37,133.82 arc(162.47,133.58) 162.37,133.34 arc(162.12,133.24) 161.88,133.34 161.69,133.53 arc(160.76,133.53) 160.76,132.6 160.95,132.41 arc(161.05,132.16) 160.95,131.92 arc(160.71,131.82) 160.46,131.92 160.27,132.11 arc(159.34,132.11) 159.34,131.18 159.53,130.99 arc(159.63,130.74) 159.53,130.5 arc(159.29,130.4) 159.04,130.5 158.85,130.69 arc(157.92,130.69) 157.92,129.76 158.11,129.57 arc(158.21,129.32) 158.11,129.08 arc(157.87,128.98) 157.63,129.08 157.43,129.27 arc(156.5,129.27) 156.5,128.34 156.69,128.15 arc(156.79,127.91) 156.69,127.66 143.07,114.04 143.07,111.78 142.23,110.94 142.23,110.53
DDR3_B_ODT_0: length 108.9
  TOP w0.127: v2(151.6,112.05) 144.82,112.05 P1.AP9 ; U8.K1 v3(173.18,132.23) ; U22.K1 v3(173.18,101.75) ; U16.K1 v3(173.18,116.99)
  06_SIG2 w0.127: v3(173.18,101.75) 172.78,102.14 172.78,116.59 v3(173.18,116.99) 172.78,117.38 172.78,130.81 173.18,131.2 v3(173.18,132.23) 172.63,132.23 168.99,128.59 167.84,128.59 166.65,127.39 166.65,125.64 164.16,123.15 arc(164.07,122.92) 164.16,122.69 164.93,121.92 arc(164.93,121.56) 164.57,121.56 163.75,122.38 arc(163.39,122.38) 163.39,122.02 164.17,121.24 arc(164.17,120.88) 163.81,120.88 163.03,121.66 arc(162.67,121.66) 162.67,121.3 163.45,120.52 arc(163.45,120.16) 163.1,120.16 162.31,120.94 arc(161.95,120.94) 161.95,120.58 162.74,119.8 arc(162.74,119.44) 162.38,119.44 161.59,120.23 arc(161.23,120.23) 161.23,119.87 162.02,119.08 arc(162.02,118.72) 161.66,118.72 160.87,119.51 arc(160.52,119.51) 160.52,119.15 161.3,118.36 arc(161.3,118) 160.94,118 160.16,118.79 arc(159.8,118.79) 159.8,118.43 160.58,117.65 arc(160.58,117.29) 160.22,117.29 159.44,118.07 arc(159.08,118.07) 159.08,117.71 159.86,116.93 arc(159.86,116.57) 159.5,116.57 158.72,117.35 arc(158.36,117.35) 158.36,116.99 159.14,116.21 arc(159.14,115.85) 158.78,115.85 158,116.63 arc(157.82,116.71) 157.64,116.63 157.35,116.34 154.11,116.34 151.6,113.83 v2(151.6,112.05)
  BOTTOM w0.127: v3(173.18,101.75) 173.64,101.28 180.29,101.28 R423.2
DDR3_B_RAS_N_0: length 113.7
  TOP w0.127: U22.J3 v3(172.38,103.35) ; v2(143.89,106.12) P1.AK8 ; U16.J3 v3(172.38,118.59) ; U8.J3 v3(172.38,133.83)
  03_SIG1 w0.127: v3(172.38,133.83) 172.77,133.43 172.77,118.98 v3(172.38,118.59) 172.77,118.19 172.77,103.74 v3(172.38,103.35)
  06_SIG2 w0.102: 151.32,104.9 150.92,104.5 143.97,104.5 143.51,104.97 143.51,105.74 v2(143.89,106.12)
  06_SIG2 w0.127: 151.32,104.9 151.32,110.52 150.42,111.42 150.42,114.34 150.99,114.91 arc(151.06,115.09) 150.99,115.27 150.98,115.28 arc(150.98,115.64) 151.34,115.64 151.35,115.63 arc(151.71,115.63) 151.71,115.99 151.7,116 arc(151.7,116.36) 152.06,116.36 152.07,116.35 arc(152.43,116.35) 152.43,116.71 152.42,116.72 arc(152.42,117.08) 152.78,117.08 152.79,117.07 arc(153.15,117.07) 153.15,117.43 153.14,117.44 arc(153.14,117.79) 153.5,117.79 153.5,117.79 arc(153.86,117.79) 153.86,118.15 153.86,118.15 arc(153.86,118.51) 154.22,118.51 154.22,118.51 arc(154.58,118.51) 154.58,118.87 154.58,118.87 arc(154.58,119.23) 154.93,119.23 154.94,119.23 arc(155.3,119.23) 155.3,119.58 155.29,119.59 arc(155.29,119.95) 155.65,119.95 155.66,119.94 arc(156.02,119.94) 156.02,120.3 156.01,120.31 arc(156.01,120.67) 156.37,120.67 156.38,120.66 arc(156.74,120.66) 156.74,121.02 156.73,121.03 arc(156.73,121.39) 157.09,121.39 157.1,121.38 arc(157.46,121.38) 157.46,121.74 157.45,121.75 arc(157.45,122.11) 157.81,122.11 157.81,122.1 arc(158.17,122.1) 158.17,122.46 158.17,122.46 arc(158.17,122.82) 158.53,122.82 158.53,122.82 arc(158.89,122.82) 158.89,123.18 158.89,123.18 arc(158.89,123.54) 159.25,123.54 159.25,123.54 arc(159.61,123.54) 159.61,123.89 159.6,123.9 arc(159.6,124.26) 159.96,124.26 159.97,124.25 arc(160.33,124.25) 160.33,124.61 160.32,124.62 arc(160.32,124.98) 160.68,124.98 161.26,124.4 arc(161.62,124.4) 161.62,124.76 161.34,125.04 arc(161.34,125.4) 161.7,125.4 161.99,125.11 arc(162.35,125.11) 162.35,125.47 162.06,125.75 arc(162.06,126.11) 162.42,126.11 162.71,125.82 arc(163.07,125.82) 163.07,126.18 162.79,126.46 arc(162.79,126.82) 163.15,126.82 163.44,126.53 arc(163.8,126.53) 163.8,126.89 163.51,127.18 arc(163.51,127.53) 163.87,127.53 163.96,127.45 arc(164.32,127.45) 164.32,127.81 163.95,128.18 arc(163.95,128.54) 164.31,128.54 164.73,128.12 164.91,128.12 165.2,128.41 165.2,129.96 165.86,130.62 167.28,130.62 167.78,131.11 167.78,131.66 arc(168.03,131.91) 168.28,131.66 168.28,131.2 arc(168.36,131.02) 168.54,130.95 169.29,130.95 171.4,133.06 171.4,133.22 172.01,133.83 v3(172.38,133.83)
  BOTTOM w0.127: v3(172.38,103.35) 171.96,102.93 171.96,101.79 173.23,100.52 178.76,100.52 R426.2
DDR3_B_RST_N_0: length 103
  TOP w0.127: U16.T2 v3(177.98,117.79) ; P1.AM7 v2(144.89,108.12) ; U22.T2 v3(177.98,102.55) ; U8.T2 v3(177.98,133.03)
  TOP w0.381: C147.1 178.33,102.19 v3(177.98,102.55)
  06_SIG2 w0.127: v3(177.98,102.55) 178.38,102.95 178.38,117.39 v3(177.98,117.79) 178.38,118.19 178.38,132.63 v3(177.98,133.03) 178.37,133.42 178.37,139.64 177.35,140.65 163.42,140.65 148.02,125.25 arc(147.95,125.07) 148.02,124.89 148.43,124.48 arc(148.43,124.12) 148.07,124.12 147.66,124.53 arc(147.3,124.53) 147.3,124.17 147.71,123.76 arc(147.71,123.4) 147.35,123.4 146.94,123.81 arc(146.58,123.81) 146.58,123.45 147,123.04 arc(147,122.68) 146.64,122.68 146.22,123.09 arc(145.86,123.09) 145.86,122.73 146.3,122.3 arc(146.35,122.19) 146.3,122.08 145.77,121.55 145.77,113.6 144.83,112.66 144.83,108.18 v2(144.89,108.12)
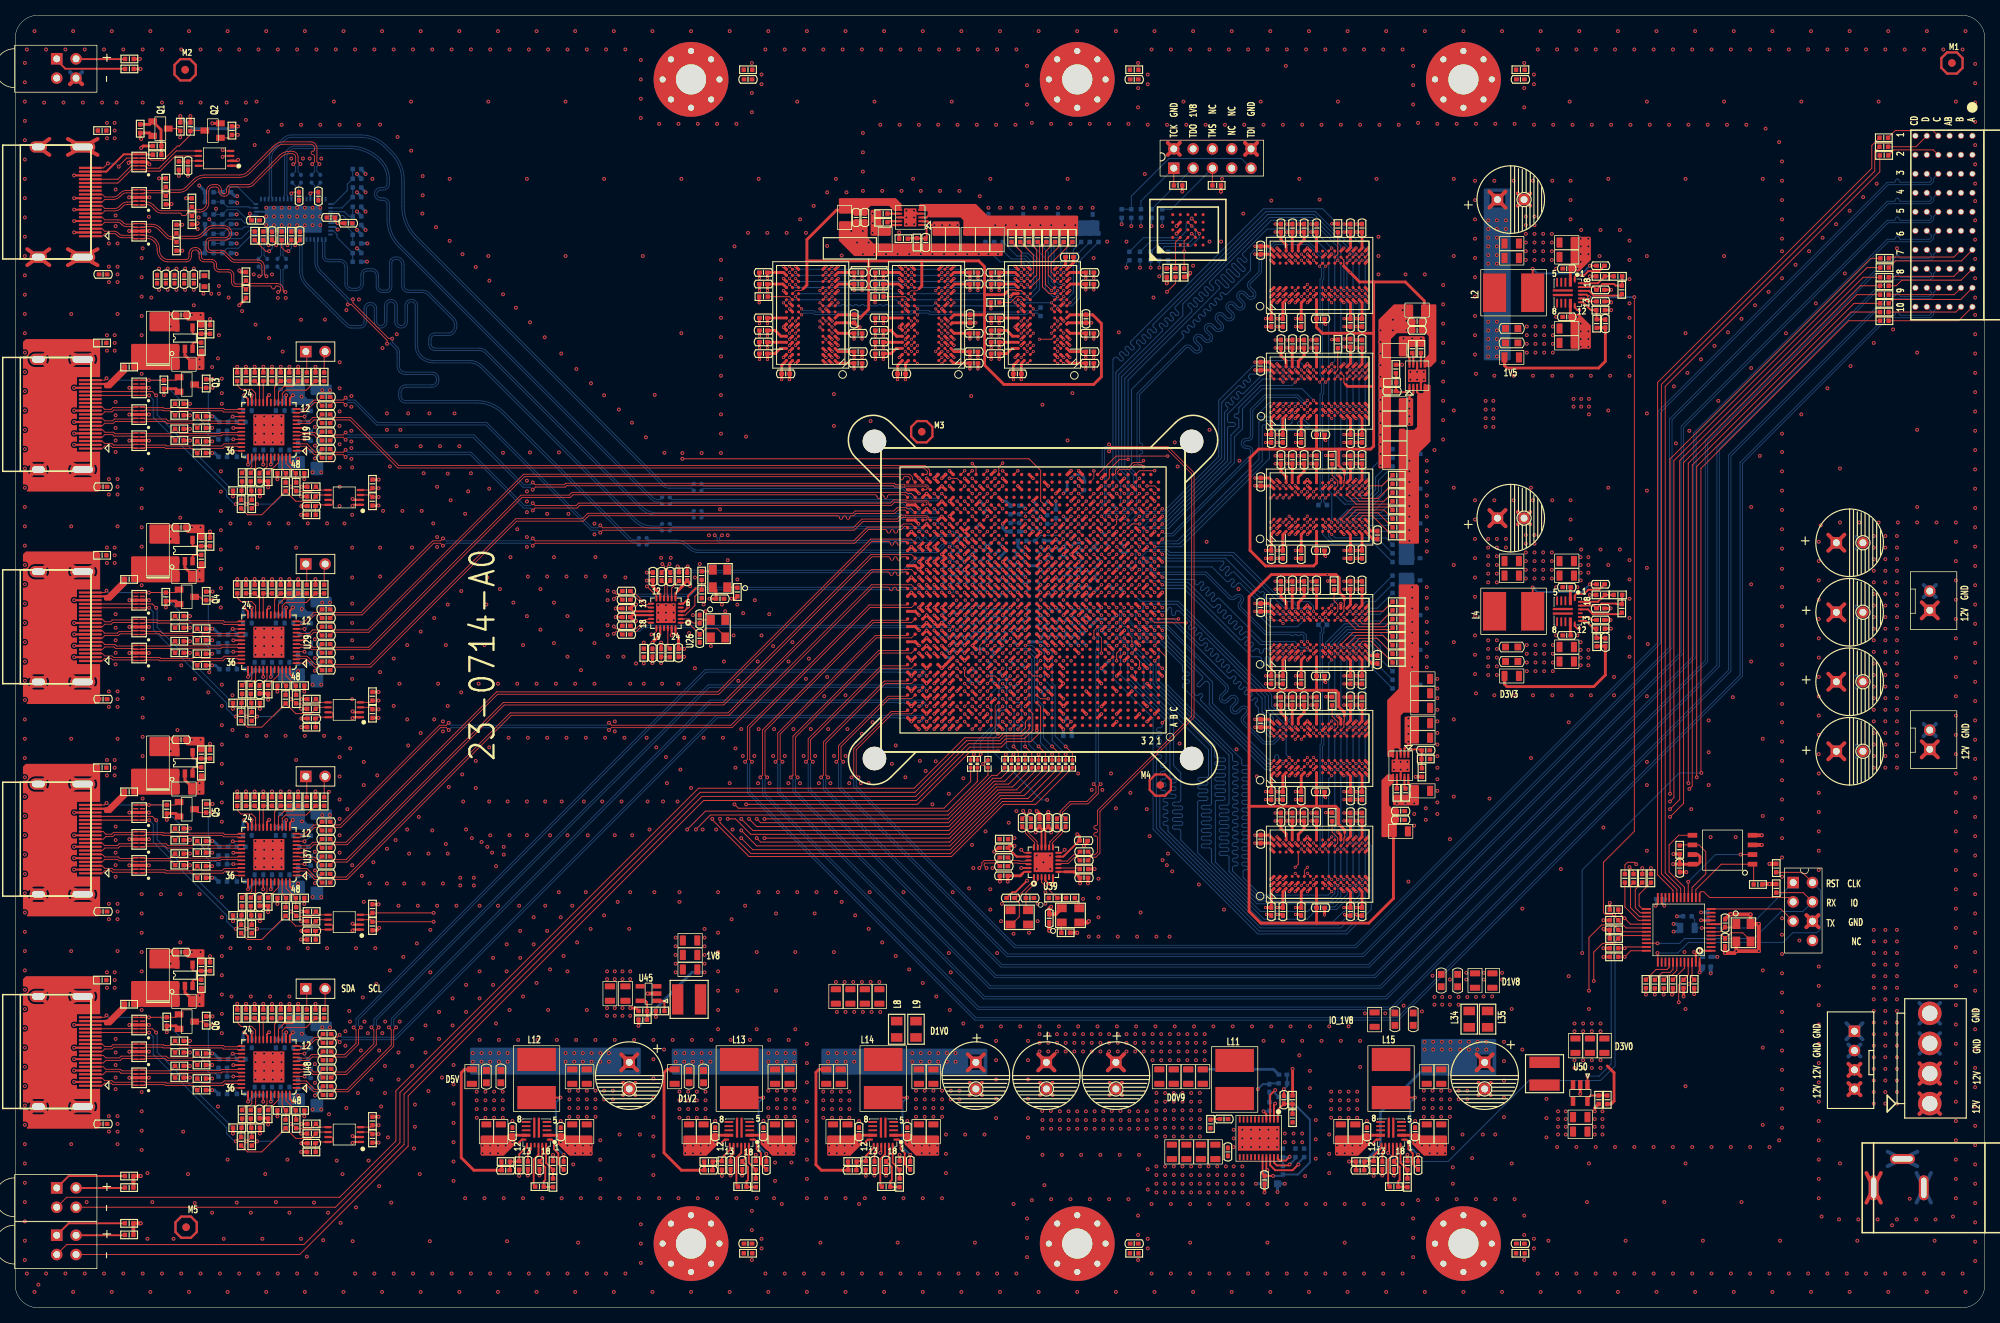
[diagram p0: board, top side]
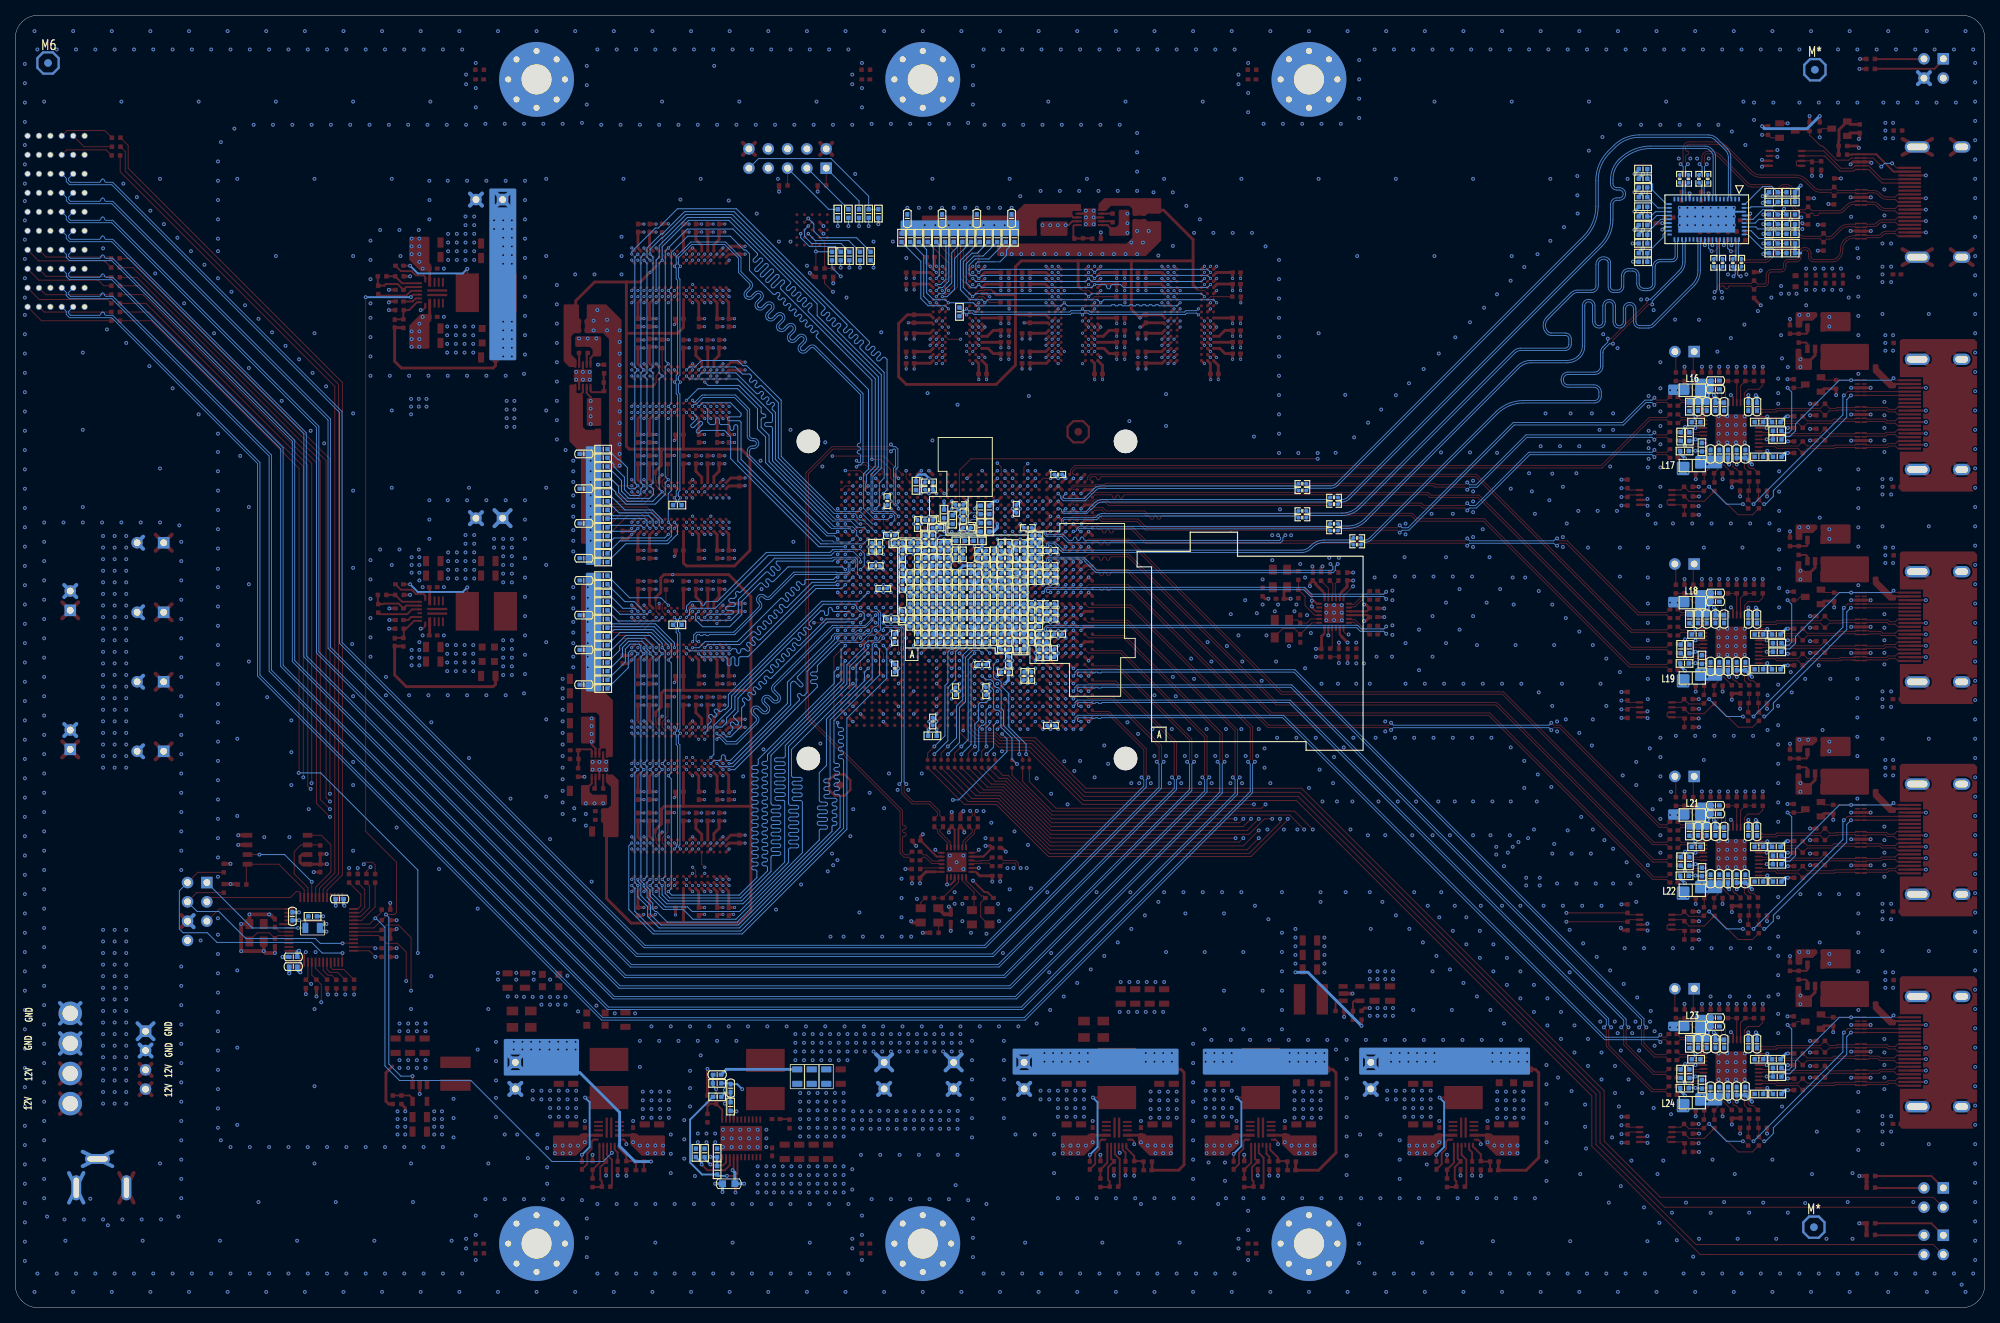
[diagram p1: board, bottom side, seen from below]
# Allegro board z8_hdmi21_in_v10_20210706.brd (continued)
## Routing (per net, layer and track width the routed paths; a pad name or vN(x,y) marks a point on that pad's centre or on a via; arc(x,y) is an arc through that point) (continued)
DDR3_B_WE_N_0: length 110.4
  TOP w0.127: U16.L3 v3(173.98,118.59) ; U22.L3 v3(173.98,103.35) ; U8.L3 v3(173.98,133.83) ; P1.AN7 v2(143.89,108.12)
  03_SIG1 w0.127: v3(173.98,103.35) U22.L3 173.58,118.19 173.98,118.59 v3(173.98,118.59) U16.L3 173.58,133.43 v3(173.98,133.83)
  06_SIG2 w0.102: 150.11,104.74 144.62,104.74 144.4,104.97 144.4,107.61 v2(143.89,108.12)
  06_SIG2 w0.127: 150.11,104.74 150.39,105.02 150.39,105.24 150.94,105.79 150.94,110.34 150.04,111.24 150.04,115.26 160.1,125.32 arc(160.17,125.5) 160.1,125.68 159.91,125.86 arc(159.91,126.22) 160.27,126.22 160.75,125.74 arc(161.11,125.74) 161.11,126.1 160.63,126.58 arc(160.63,126.94) 160.99,126.94 161.47,126.46 arc(161.83,126.46) 161.83,126.82 161.35,127.3 arc(161.35,127.66) 161.71,127.66 162.19,127.18 arc(162.54,127.18) 162.54,127.54 162.07,128.02 arc(162.07,128.38) 162.43,128.38 162.87,127.94 arc(163.08,127.85) 163.3,127.94 arc(163.36,128.08) 163.3,128.22 162.79,128.73 arc(162.79,129.09) 163.15,129.09 163.3,128.94 163.48,128.94 163.63,129.08 163.63,129.96 164.94,131.27 166.91,131.27 arc(167.16,131.52) 166.91,131.78 164.93,131.78 arc(164.75,131.85) 164.68,132.03 164.68,133.93 164.97,134.22 173.58,134.22 v3(173.98,133.83)
  BOTTOM w0.127: R402.2 178.89,104.97 175.26,104.97 173.98,103.68 v3(173.98,103.35)
DDR3_C_A0: length 106.4
  TOP w0.127: U40.N3 v3(175.58,56.36) ; v3(175.58,86.84) U28.N3 176.4,88.46 179.9,88.46 R152.2 ; P1.L4 v2(146.89,86.12) ; U32.N3 v3(175.58,71.6)
  03_SIG1 w0.127: v3(175.58,86.84) 175.97,86.44 175.97,71.99 v3(175.58,71.6) 175.97,71.2 175.97,56.75 v3(175.58,56.36)
  BOTTOM w0.127: v2(146.89,86.12) 148.46,84.55 148.46,81.95 156.97,73.44 156.97,70.03 arc(156.9,69.85) 156.72,69.78 155.8,69.78 arc(155.55,69.53) 155.8,69.27 156.64,69.27 arc(156.9,69.02) 156.64,68.76 155.8,68.76 arc(155.55,68.51) 155.8,68.26 156.64,68.26 arc(156.9,68) 156.64,67.75 155.8,67.75 arc(155.55,67.49) 155.8,67.24 156.64,67.24 arc(156.9,66.99) 156.64,66.73 155.78,66.73 arc(155.61,66.66) 155.54,66.49 155.54,59.86 164.28,51.12 169.93,51.12 171.22,52.41 173.81,52.41 175.59,54.19 175.59,55 175.98,55.4 175.98,55.95 v3(175.58,56.36)
DDR3_C_A1: length 106
  TOP w0.127: R143.2 180.16,89.6 176.81,89.6 U28.P7 v3(176.38,90.84) ; P1.K4 147.89,85.12 v2(147.89,84.12) ; U32.P7 v3(176.38,75.6) ; U40.P7 v3(176.38,60.36)
  06_SIG2 w0.127: v3(176.38,90.84) 175.98,90.44 175.98,75.99 v3(176.38,75.6) 175.98,75.2 175.98,60.75 v3(176.38,60.36) 174.38,58.36 163.93,58.36 159.47,62.81 159.47,64.49 158.83,65.13 arc(158.76,65.31) 158.83,65.49 159.36,66.03 arc(159.36,66.39) 159,66.39 158.47,65.85 arc(158.11,65.85) 158.11,66.21 159.16,67.26 arc(159.16,67.62) 158.8,67.62 157.75,66.57 arc(157.39,66.57) 157.39,66.93 158.44,67.98 arc(158.44,68.33) 158.08,68.33 157.03,67.29 arc(156.68,67.29) 156.68,67.65 157.72,68.69 arc(157.72,69.05) 157.36,69.05 156.32,68.01 arc(155.96,68.01) 155.96,68.37 157,69.41 arc(157,69.77) 156.64,69.77 155.6,68.73 arc(155.24,68.73) 155.24,69.09 156.28,70.13 arc(156.28,70.49) 155.92,70.49 154.88,69.44 arc(154.7,69.37) 154.52,69.44 148.46,75.5 148.46,78.37 147.89,78.95 v2(147.89,84.12)
DDR3_C_A2: length 109.9
  TOP w0.127: U32.P3 v3(176.38,71.6) ; v3(176.38,86.84) U28.P3 176.81,88.07 179.14,88.07 R156.2 ; v2(147.89,88.12) P1.N4 ; U40.P3 v3(176.38,56.36)
  06_SIG2 w0.127: v2(147.89,88.12) 147.4,88.61 147.4,89.24 146.02,90.61 142.7,90.61 142.39,90.31 142.39,89.5 140.41,87.52 140.41,75.27 162.15,53.53 175.16,53.53 175.98,54.36 175.98,55.96 v3(176.38,56.36)
  BOTTOM w0.127: v3(176.38,56.36) U40.P3 175.98,71.2 v3(176.38,71.6) U32.P3 175.98,86.19 176.38,86.59 v3(176.38,86.84)
DDR3_C_A3: length 112.6
  TOP w0.127: U28.N2 v3(175.58,86.04) ; P1.N5 146.89,88.12 v2(146.89,87.12) ; U40.N2 v3(175.58,55.56) ; U32.N2 v3(175.58,70.8)
  BOTTOM w0.127: R456.2 179.2,85.73 179.2,86.86 178.36,87.69 176.66,87.69 175.98,87.02 175.98,86.69 175.58,86.28 v3(175.58,86.04) 175.18,85.64 U32.N2 v3(175.58,70.8) 175.18,70.4 U40.N2 v3(175.58,55.56) 175.21,55.19 175.21,54.39 173.56,52.74 170.64,52.74 170.03,52.13 163.8,52.13 157.35,58.58 157.35,60.25 arc(157.28,60.43) 157.1,60.51 156.26,60.51 arc(156.01,60.76) 156.26,61.02 157.1,61.02 arc(157.35,61.27) 157.1,61.52 156.26,61.52 arc(156.01,61.78) 156.26,62.03 157.1,62.03 arc(157.35,62.29) 157.1,62.54 156.26,62.54 arc(156.01,62.79) 156.26,63.05 157.1,63.05 arc(157.35,63.3) 157.1,63.56 156.26,63.56 arc(156.01,63.81) 156.26,64.06 157.1,64.06 arc(157.35,64.32) 157.1,64.57 156.26,64.57 arc(156.01,64.83) 156.26,65.08 157.1,65.08 arc(157.35,65.33) 157.1,65.59 156.26,65.59 arc(156.01,65.84) 156.26,66.1 157.1,66.1 arc(157.28,66.17) 157.35,66.35 157.35,73.85 149.3,81.9 149.3,84.37 146.89,86.78 v2(146.89,87.12)
DDR3_C_A4: length 105.1
  TOP w0.127: U28.P8 v3(176.38,91.64) ; U40.P8 v3(176.38,61.16) ; U32.P8 v3(176.38,76.4) ; v2(146.89,85.12) P1.J4
  06_SIG2 w0.127: v3(176.38,91.64) 176.77,91.24 176.77,76.79 v3(176.38,76.4) 176.77,76 176.77,61.55 v3(176.38,61.16) 176.77,60.76 176.77,60.12 174.62,57.98 171.5,57.98 171.09,57.56 164.09,57.56 158.33,63.32 arc(158.26,63.5) 158.33,63.68 158.76,64.11 arc(158.76,64.47) 158.4,64.47 158.01,64.08 arc(157.65,64.08) 157.65,64.44 158.05,64.84 arc(158.05,65.2) 157.69,65.2 157.29,64.8 arc(156.93,64.8) 156.93,65.16 157.33,65.56 arc(157.33,65.92) 156.98,65.92 156.57,65.52 arc(156.21,65.52) 156.21,65.87 156.6,66.26 arc(156.6,66.62) 156.24,66.62 155.85,66.23 arc(155.5,66.23) 155.5,66.59 155.89,66.98 arc(155.89,67.34) 155.53,67.34 155.14,66.95 arc(154.78,66.95) 154.78,67.31 155.17,67.7 arc(155.17,68.06) 154.81,68.06 154.42,67.67 arc(154.06,67.67) 154.06,68.03 154.45,68.42 arc(154.45,68.78) 154.09,68.78 153.7,68.39 arc(153.34,68.39) 153.34,68.75 153.73,69.14 arc(153.73,69.5) 153.37,69.5 152.98,69.11 arc(152.62,69.11) 152.62,69.47 153.01,69.86 arc(153.01,70.22) 152.65,70.22 152.26,69.83 arc(151.9,69.83) 151.9,70.19 152.29,70.58 arc(152.36,70.8) 152.22,70.98 147.4,75.81 147.4,84.61 v2(146.89,85.12)
  BOTTOM w0.127: R430.2 178.89,92.9 177.64,92.9 v3(176.38,91.64)
DDR3_C_A5: length 106.7
  TOP w0.127: U32.P2 v3(176.38,70.8) ; P1.J5 v2(146.89,84.12) ; U40.P2 v3(176.38,55.56) ; U28.P2 v3(176.38,86.04)
  BOTTOM w0.127: v2(146.89,84.12) 147.37,83.64 147.37,82.46 152.37,77.46 152.37,71.34 153.31,70.4 153.31,66.8 arc(153.24,66.6) 153.04,66.53 152.48,66.53 arc(152.22,66.27) 152.48,66.02 153.31,66.02 arc(153.57,65.76) 153.31,65.51 152.48,65.51 arc(152.22,65.26) 152.48,65 153.31,65 arc(153.57,64.75) 153.31,64.49 152.48,64.49 arc(152.22,64.24) 152.48,63.99 153.34,63.99 arc(153.59,63.73) 153.34,63.48 152.48,63.48 arc(152.22,63.22) 152.48,62.97 153.11,62.97 arc(153.25,62.91) 153.31,62.77 153.31,61.54 164.12,50.74 173.3,50.74 174.7,52.13 174.88,52.13 175.21,52.46 175.21,53.23 175.97,53.99 175.97,54.91 176.38,55.31 v3(176.38,55.56) 176.38,55.8 176.78,56.2 176.78,70.4 v3(176.38,70.8) 176.78,71.2 176.78,85.64 v3(176.38,86.04) 176.78,86.44 176.78,87.06 177.04,87.31 178.18,87.31 178.82,86.68 178.82,84.97 R458.2
DDR3_C_A6: length 106.9
  TOP w0.127: U32.R8 v3(177.18,76.4) ; v2(145.89,88.12) P1.M5 ; U28.R8 v3(177.18,91.64) ; U40.R8 v3(177.18,61.16)
  06_SIG2 w0.127: v2(145.89,88.12) 145.48,87.71 143.89,87.71 142.44,86.27 142.44,77.94 159.78,60.6 arc(159.85,60.42) 159.78,60.24 159.49,59.96 arc(159.49,59.6) 159.85,59.6 160.14,59.89 arc(160.5,59.89) 160.5,59.53 160.21,59.24 arc(160.21,58.88) 160.57,58.88 160.86,59.17 arc(161.22,59.17) 161.22,58.81 160.93,58.52 arc(160.93,58.16) 161.29,58.16 161.58,58.45 arc(161.93,58.45) 161.93,58.09 161.65,57.8 arc(161.65,57.44) 162.01,57.44 162.29,57.73 arc(162.65,57.73) 162.65,57.37 162.36,57.08 arc(162.36,56.72) 162.72,56.72 163.01,57.01 arc(163.37,57.01) 163.37,56.65 163.12,56.4 arc(163.12,56.04) 163.48,56.04 163.73,56.29 arc(163.91,56.37) 164.09,56.29 164.42,55.96 170.99,55.96 171.22,56.2 171.22,56.45 171.96,57.19 175.03,57.19 177.57,59.73 177.57,60.76 v3(177.18,61.16) 177.57,61.55 177.57,76 v3(177.18,76.4) 177.57,76.79 177.57,91.24 v3(177.18,91.64)
  BOTTOM w0.127: v3(177.18,91.64) 177.57,92.03 179.16,92.03 R431.2
DDR3_C_A7: length 108.2
  TOP w0.127: U28.R2 v3(177.18,86.04) ; v2(145.89,87.12) P1.L5 ; U40.R2 v3(177.18,55.56) ; U32.R2 v3(177.18,70.8)
  BOTTOM w0.127: R459.2 178.44,84.21 178.44,86.17 178.17,86.43 177.57,86.43 v3(177.18,86.04) 177.58,85.64 177.58,71.2 v3(177.18,70.8) 177.58,70.4 177.58,55.96 v3(177.18,55.56) 177.18,54.05 175.9,52.77 175.9,51.5 174.37,49.97 163.8,49.97 150.57,63.21 150.57,67.25 arc(150.66,67.46) 150.86,67.54 151.13,67.54 arc(151.38,67.8) 151.13,68.05 150.9,68.05 arc(150.65,68.3) 150.9,68.56 151.13,68.56 arc(151.38,68.81) 151.13,69.07 150.9,69.07 arc(150.65,69.32) 150.9,69.57 151.13,69.57 arc(151.38,69.83) 151.13,70.08 150.9,70.08 arc(150.65,70.34) 150.9,70.59 151.13,70.59 arc(151.38,70.84) 151.13,71.1 150.9,71.1 arc(150.65,71.35) 150.9,71.61 151.13,71.61 arc(151.31,71.68) 151.38,71.86 151.38,77.25 145.39,83.25 145.39,86.63 v2(145.89,87.12)
DDR3_C_A8: length 108.4
  TOP w0.102: P1.M6 v2(144.89,87.12)
  TOP w0.127: U28.T8 v3(177.98,91.64) 179.91,91.64 R139.2 ; U32.T8 v3(177.98,76.4) ; U40.T8 v3(177.98,61.16)
  06_SIG2 w0.127: v3(177.98,91.64) 178.37,91.24 178.37,76.79 v3(177.98,76.4) 178.37,76 178.37,61.55 v3(177.98,61.16)
  BOTTOM w0.127: v3(177.98,61.16) 178.37,60.76 178.37,52.4 175.16,49.19 163.45,49.19 149.68,62.95 149.68,77.56 144.42,82.82 144.42,86.66 v2(144.89,87.12)
DDR3_C_A9: length 110.4
  TOP w0.102: P1.M7 v2(144.89,88.12)
  TOP w0.127: R157.2 178.38,87.69 177.23,87.69 U28.R3 v3(177.18,86.84) ; U40.R3 v3(177.18,56.36) ; U32.R3 v3(177.18,71.6)
  03_SIG1 w0.127: v3(177.18,56.36) 176.78,56.75 176.78,71.2 v3(177.18,71.6) 176.78,71.99 176.78,86.44 v3(177.18,86.84)
  BOTTOM w0.102: v2(144.89,88.12) 145.51,87.5 146.11,87.5 146.27,87.35
  BOTTOM w0.127: v3(177.18,56.36) 177.18,56.11 176.78,55.72 176.78,54.24 175.51,52.97 175.51,51.75 174.12,50.36 163.96,50.36 151.64,62.68 151.64,63.3 arc(151.59,63.43) 151.46,63.48 151.23,63.48 arc(150.98,63.73) 151.23,63.99 151.38,63.99 arc(151.64,64.24) 151.38,64.49 151.23,64.49 arc(150.98,64.75) 151.23,65 151.38,65 arc(151.64,65.26) 151.38,65.51 151.23,65.51 arc(150.98,65.76) 151.23,66.02 151.38,66.02 arc(151.64,66.27) 151.38,66.53 151.23,66.53 arc(150.98,66.78) 151.23,67.03 152.45,67.03 arc(152.7,67.29) 152.45,67.54 152.17,67.54 arc(151.92,67.8) 152.17,68.05 152.45,68.05 arc(152.7,68.3) 152.45,68.56 152.17,68.56 arc(151.92,68.81) 152.17,69.07 152.48,69.07 arc(152.73,69.32) 152.48,69.57 152.02,69.57 151.89,69.7 151.89,77.36 146.35,82.89 146.35,87.26 146.27,87.35
DDR3_C_A10: length 108.4
  TOP w0.127: U40.L7 v3(173.98,60.36) ; U32.L7 v3(173.98,75.6) ; v2(145.89,86.12) P1.K6 ; U28.L7 v3(173.98,90.84)
  06_SIG2 w0.127: v2(145.89,86.12) 146.37,86.6 147.78,86.6 149.73,84.65 149.73,83.63 150.56,82.8 arc(150.63,82.62) 150.56,82.44 149.91,81.8 arc(149.85,81.63) 149.91,81.47 arc(150.11,81.39) 150.3,81.47 150.92,82.09 arc(151.28,82.09) 151.28,81.73 150.63,81.08 arc(150.56,80.92) 150.63,80.75 arc(150.83,80.67) 151.02,80.75 151.65,81.38 arc(152.01,81.38) 152.01,81.02 151.35,80.36 arc(151.28,80.2) 151.35,80.03 arc(151.54,79.95) 151.74,80.03 152.37,80.66 arc(152.73,80.66) 152.73,80.3 152.07,79.65 arc(152,79.48) 152.07,79.31 arc(152.18,79.25) 152.3,79.23 arc(152.38,79.26) 152.45,79.31 153.09,79.94 arc(153.44,79.94) 153.44,79.58 152.79,78.93 arc(152.72,78.76) 152.79,78.59 arc(152.98,78.51) 153.17,78.59 153.8,79.22 arc(154.16,79.22) 154.16,78.87 153.51,78.21 arc(153.44,78.04) 153.51,77.87 arc(153.7,77.8) 153.89,77.87 154.51,78.49 arc(154.87,78.49) 154.87,78.13 154.22,77.49 arc(154.16,77.32) 154.22,77.16 arc(154.42,77.08) 154.61,77.16 155.23,77.78 arc(155.59,77.78) 155.59,77.42 154.94,76.77 arc(154.87,76.6) 154.94,76.44 arc(155.14,76.36) 155.33,76.44 155.95,77.06 arc(156.31,77.06) 156.31,76.7 155.66,76.05 arc(155.59,75.89) 155.66,75.72 arc(155.85,75.64) 156.05,75.72 156.67,76.34 arc(156.84,76.41) 157.02,76.34 160.81,72.56 160.81,65.7 163.96,62.55 163.96,60.9 165.35,59.5 173.12,59.5 v3(173.98,60.36) 173.58,60.75 173.58,75.2 v3(173.98,75.6) 173.58,75.99 173.58,90.44 v3(173.98,90.84)
  BOTTOM w0.127: R433.2 179.78,90.36 174.45,90.36 v3(173.98,90.84)
DDR3_C_A11: length 105.7
  TOP w0.127: P1.L6 144.89,86.12 v2(144.89,85.12) ; R141.2 179.4,89.98 177.23,89.98 U28.R7 v3(177.18,90.84) ; U32.R7 v3(177.18,75.6) ; U40.R7 v3(177.18,60.36)
  03_SIG1 w0.127: v3(177.18,60.36) 177.57,60.75 177.57,75.2 v3(177.18,75.6) 177.58,76 177.58,90.44 v3(177.18,90.84)
  06_SIG2 w0.102: v2(144.89,85.12) 145.07,84.94
  06_SIG2 w0.127: 145.07,84.94 145.72,84.29 145.72,76.39 145.35,76.03 arc(145.28,75.85) 145.35,75.67 arc(145.53,75.59) 145.71,75.67 146.33,76.29 arc(146.69,76.29) 146.69,75.93 146.07,75.31 arc(146,75.13) 146.07,74.95 arc(146.25,74.87) 146.43,74.95 146.83,75.35 arc(147.14,75.39) 147.25,75.1 arc(147.23,75.04) 147.19,74.99 146.79,74.59 arc(146.71,74.41) 146.79,74.23 arc(146.97,74.16) 147.15,74.23 147.55,74.63 arc(147.91,74.63) 147.91,74.27 147.51,73.87 arc(147.43,73.69) 147.51,73.51 arc(147.69,73.44) 147.87,73.51 148.27,73.91 arc(148.63,73.91) 148.63,73.56 148.22,73.15 arc(148.15,72.97) 148.22,72.79 arc(148.4,72.72) 148.58,72.79 148.99,73.2 arc(149.35,73.2) 149.35,72.84 148.94,72.43 arc(148.87,72.25) 148.94,72.07 arc(149.12,72) 149.3,72.07 149.72,72.49 arc(150.08,72.49) 150.08,72.13 149.66,71.72 arc(149.59,71.54) 149.66,71.36 arc(149.84,71.28) 150.02,71.36 150.44,71.77 arc(150.8,71.77) 150.8,71.41 150.38,71 arc(150.31,70.82) 150.38,70.64 arc(150.56,70.56) 150.74,70.64 151.15,71.05 arc(151.51,71.05) 151.51,70.69 151.1,70.28 arc(151.02,70.1) 151.1,69.92 164.26,56.76 170.9,56.76 171.73,57.59 174.85,57.59 177.18,59.92 v3(177.18,60.36)
DDR3_C_A12: length 110.8
  TOP w0.127: R145.2 180.92,89.22 176.4,89.22 U28.N7 v3(174.78,90.84) ; U32.N7 v3(174.78,75.6) ; v2(143.89,86.12) P1.L8 ; U40.N7 v3(174.78,60.36)
  06_SIG2 w0.102: v2(143.89,86.12) 144.27,85.74 147.9,85.74
  06_SIG2 w0.127: v3(174.78,90.84) 174.38,90.44 174.38,75.99 v3(174.78,75.6) 174.38,75.2 174.38,60.75 v3(174.78,60.36) 173.54,59.12 164.92,59.12 163.53,60.52 163.53,62.4 163.23,62.69 arc(163.05,62.76) 162.87,62.69 162.03,61.84 arc(161.67,61.84) 161.67,62.2 162.51,63.05 arc(162.51,63.41) 162.16,63.41 161.31,62.56 arc(160.95,62.56) 160.95,62.92 161.8,63.76 arc(161.8,64.12) 161.44,64.12 160.79,63.48 arc(160.43,63.48) 160.43,63.84 161.08,64.48 arc(161.15,64.66) 161.08,64.84 160.38,65.54 160.38,70.29 160,70.67 arc(159.93,70.85) 160,71.03 160.3,71.32 arc(160.3,71.68) 159.94,71.68 159.64,71.39 arc(159.28,71.39) 159.28,71.75 159.93,72.39 arc(159.93,72.75) 159.57,72.75 158.92,72.1 arc(158.57,72.1) 158.57,72.46 159.21,73.11 arc(159.21,73.47) 158.85,73.47 158.21,72.82 arc(157.85,72.82) 157.85,73.18 158.49,73.83 arc(158.49,74.19) 158.13,74.19 157.49,73.54 arc(157.13,73.54) 157.13,73.9 157.77,74.54 arc(157.77,74.9) 157.41,74.9 156.77,74.26 arc(156.41,74.26) 156.41,74.62 157.05,75.26 arc(157.05,75.62) 156.7,75.62 156.05,74.98 arc(155.88,74.91) 155.72,74.98 149.3,81.39 149.3,82.04 arc(149.38,82.22) 149.56,82.3 arc(149.81,82.55) 149.56,82.81 arc(149.38,82.88) 149.3,83.06 149.3,84.52 148.08,85.74 147.9,85.74
DDR3_C_BA0: length 115.1
  TOP w0.127: v2(143.89,89.12) P1.P7 ; U28.M2 v3(174.78,86.04) ; U40.M2 v3(174.78,55.56) ; U32.M2 v3(174.78,70.8)
  03_SIG1 w0.127: v3(174.78,55.56) 175.17,55.95 175.17,70.4 v3(174.78,70.8) 175.17,71.19 175.17,85.64 v3(174.78,86.04)
  BOTTOM w0.102: 146.51,87.74 145.7,87.74 145.41,88.03 145.41,88.2 145.11,88.5 144.51,88.5 v2(143.89,89.12)
  BOTTOM w0.127: R451.2 179.58,86.5 179.58,87.03 178.54,88.07 176.26,88.07 175.18,87 175.18,86.44 v3(174.78,86.04) ; v3(174.78,55.56) 174.37,55.15 174.37,54.14 173.38,53.15 163.35,53.15 157.86,58.64 157.86,66.58 arc(157.91,66.71) 158.04,66.76 158.9,66.76 arc(159.16,67.01) 158.9,67.27 158.04,67.27 arc(157.78,67.52) 158.04,67.77 158.95,67.77 arc(159.21,68.03) 158.95,68.28 158.04,68.28 arc(157.78,68.54) 158.04,68.79 158.95,68.79 arc(159.21,69.04) 158.95,69.3 158.04,69.3 arc(157.78,69.55) 158.04,69.81 158.95,69.81 arc(159.21,70.06) 158.95,70.31 158.04,70.31 arc(157.78,70.57) 158.04,70.82 158.95,70.82 arc(159.21,71.08) 158.95,71.33 158.04,71.33 arc(157.78,71.58) 158.04,71.84 158.95,71.84 arc(159.21,72.09) 158.95,72.35 158.04,72.35 arc(157.86,72.42) 157.78,72.6 157.78,73.98 149.68,82.08 149.68,84.59 147.4,86.88 147.4,87.24 146.89,87.74 146.51,87.74
DDR3_C_BA1: length 113.1
  TOP w0.102: P1.N9 142.88,88.13 v2(142.88,86.12)
  TOP w0.127: U28.N8 v3(175.58,91.64) ; U40.N8 v3(175.58,61.16) ; U32.N8 v3(175.58,76.4)
  06_SIG2 w0.102: 147.78,85.41 147.68,85.5 143.49,85.5 v2(142.88,86.12)
  06_SIG2 w0.127: v3(175.58,91.64) 175.18,91.24 175.18,76.79 v3(175.58,76.4) 175.18,76 175.18,61.55 v3(175.58,61.16) 175.58,60.58 173.74,58.74 164.19,58.74 159.92,63 159.92,70.12 159.68,70.35 arc(159.51,70.42) 159.33,70.35 158.64,69.67 arc(158.28,69.67) 158.28,70.03 158.97,70.71 arc(158.97,71.07) 158.61,71.07 157.93,70.39 arc(157.57,70.39) 157.57,70.75 158.25,71.43 arc(158.25,71.79) 157.89,71.79 157.21,71.1 arc(156.85,71.1) 156.85,71.46 157.53,72.15 arc(157.6,72.33) 157.53,72.51 155.23,74.81 arc(155.05,74.88) 154.87,74.81 154.61,74.54 arc(154.25,74.54) 154.25,74.9 154.51,75.17 arc(154.58,75.35) 154.51,75.52 arc(154.33,75.6) 154.15,75.52 153.89,75.26 arc(153.53,75.26) 153.53,75.62 153.79,75.88 arc(153.87,76.06) 153.79,76.24 arc(153.61,76.32) 153.43,76.24 153.17,75.98 arc(152.81,75.98) 152.81,76.34 153.07,76.6 arc(153.15,76.78) 153.07,76.96 arc(152.89,77.04) 152.71,76.96 152.45,76.7 arc(152.38,76.65) 152.3,76.63 arc(152.04,76.77) 152.09,77.06 152.36,77.32 arc(152.43,77.5) 152.36,77.68 arc(152.18,77.75) 152,77.68 151.73,77.42 arc(151.37,77.42) 151.37,77.78 151.64,78.04 arc(151.71,78.22) 151.64,78.4 arc(151.46,78.47) 151.28,78.4 151.01,78.14 arc(150.66,78.14) 150.66,78.49 150.92,78.76 arc(150.99,78.94) 150.92,79.12 arc(150.74,79.19) 150.56,79.12 150.24,78.8 arc(149.88,78.8) 149.88,79.15 150.2,79.48 arc(150.27,79.66) 150.2,79.84 arc(150.02,79.91) 149.84,79.84 149.58,79.57 arc(149.22,79.57) 149.22,79.93 149.48,80.19 arc(149.56,80.37) 149.48,80.55 arc(149.3,80.63) 149.12,80.55 148.83,80.27 arc(148.47,80.27) 148.47,80.62 148.76,80.91 arc(148.84,81.09) 148.76,81.27 148.45,81.58 148.45,84.73 147.78,85.41
  BOTTOM w0.127: v3(175.58,91.64) 175.98,91.23 176,91.24 179.52,91.24 R432.2
DDR3_C_BA2: length 114.3
  TOP w0.127: P1.P9 141.89,89.12 v2(141.89,88.12) ; U40.M3 v3(174.78,56.36) ; R148.2 180.67,88.84 175.98,88.84 U28.M3 v3(174.78,86.84) ; U32.M3 v3(174.78,71.6)
  03_SIG1 w0.127: v3(174.78,86.84) 174.38,86.44 174.38,71.99 v3(174.78,71.6) 174.38,71.2 174.38,56.75 v3(174.78,56.36)
  06_SIG2 w0.127: v3(174.78,56.36) 174.37,55.95 174.37,55.31 173.04,53.98 162.34,53.98 162.03,54.29 arc(161.96,54.47) 162.03,54.65 162.13,54.74 arc(162.13,55.1) 161.77,55.1 161.67,55.01 arc(161.31,55.01) 161.31,55.36 161.41,55.46 arc(161.41,55.82) 161.05,55.82 160.95,55.72 arc(160.6,55.72) 160.6,56.08 160.69,56.18 arc(160.69,56.54) 160.33,56.54 160.24,56.44 arc(159.88,56.44) 159.88,56.8 159.97,56.9 arc(159.97,57.26) 159.62,57.26 159.52,57.16 arc(159.16,57.16) 159.16,57.52 159.26,57.62 arc(159.26,57.98) 158.9,57.98 158.8,57.88 arc(158.44,57.88) 158.44,58.24 158.54,58.34 arc(158.54,58.7) 158.18,58.7 158.08,58.6 arc(157.72,58.6) 157.72,58.96 157.82,59.05 arc(157.82,59.41) 157.46,59.41 157.36,59.32 arc(157,59.32) 157,59.68 157.1,59.77 arc(157.1,60.13) 156.74,60.13 156.64,60.03 arc(156.28,60.03) 156.28,60.39 156.38,60.49 arc(156.38,60.85) 156.02,60.85 155.93,60.75 arc(155.57,60.75) 155.57,61.11 155.66,61.21 arc(155.66,61.57) 155.3,61.57 155.21,61.47 arc(154.85,61.47) 154.85,61.83 154.95,61.93 arc(154.95,62.29) 154.59,62.29 154.49,62.19 arc(154.13,62.19) 154.13,62.55 154.23,62.65 arc(154.23,63.01) 153.87,63.01 153.77,62.91 arc(153.41,62.91) 153.41,63.27 153.51,63.37 arc(153.51,63.72) 153.15,63.72 153.05,63.63 arc(152.69,63.63) 152.69,63.99 152.79,64.08 arc(152.79,64.44) 152.43,64.44 152.33,64.34 arc(151.97,64.34) 151.97,64.7 152.07,64.8 arc(152.07,65.16) 151.71,65.16 151.61,65.06 arc(151.26,65.06) 151.26,65.42 151.35,65.52 arc(151.35,65.88) 150.99,65.88 150.9,65.78 arc(150.54,65.78) 150.54,66.14 150.64,66.24 arc(150.64,66.6) 150.28,66.6 150.18,66.5 arc(149.82,66.5) 149.82,66.86 149.92,66.96 arc(149.92,67.32) 149.56,67.32 149.5,67.26 149.32,67.26 148.82,67.75 148.82,68.19 141.3,75.7 141.3,87.54 v2(141.89,88.12)
DDR3_C_CAS_N_0: length 116.2
  TOP w0.127: U28.K3 v3(173.18,86.84) ; U32.K3 v3(173.18,71.6) ; U40.K3 v3(173.18,56.36) ; v2(143.89,88.12) P1.N7
  03_SIG1 w0.127: v3(173.18,86.84) 173.57,86.44 173.57,71.99 v3(173.18,71.6) 173.57,71.2 173.57,56.75 v3(173.18,56.36)
  06_SIG2 w0.127: v2(143.89,88.12) 143.63,88.12 142.06,86.55 142.06,77.74 149.7,70.1 arc(149.72,70.08) 149.74,70.04 arc(149.77,69.89) 149.7,69.74 149.38,69.43 arc(149.38,69.07) 149.74,69.07 150.06,69.38 arc(150.42,69.38) 150.42,69.02 150.1,68.71 arc(150.1,68.35) 150.46,68.35 150.78,68.66 arc(151.14,68.66) 151.14,68.3 150.82,67.99 arc(150.82,67.63) 151.18,67.63 151.49,67.94 arc(151.85,67.94) 151.85,67.59 151.53,67.26 arc(151.53,66.9) 151.89,66.9 152.21,67.23 arc(152.57,67.23) 152.57,66.87 152.26,66.55 arc(152.26,66.19) 152.62,66.19 152.93,66.51 arc(153.29,66.51) 153.29,66.15 152.98,65.83 arc(152.98,65.48) 153.34,65.48 153.65,65.79 arc(154.01,65.79) 154.01,65.43 153.7,65.12 arc(153.7,64.76) 154.05,64.76 154.37,65.07 arc(154.73,65.07) 154.73,64.71 154.41,64.4 arc(154.41,64.04) 154.77,64.04 155.09,64.35 arc(155.45,64.35) 155.45,63.99 155.13,63.68 arc(155.13,63.32) 155.49,63.32 155.81,63.63 arc(156.16,63.63) 156.16,63.28 155.85,62.96 arc(155.85,62.6) 156.21,62.6 156.52,62.92 arc(156.88,62.92) 156.88,62.56 156.57,62.24 arc(156.57,61.88) 156.93,61.88 157.24,62.2 arc(157.6,62.2) 157.6,61.84 157.29,61.52 arc(157.29,61.17) 157.65,61.17 157.96,61.48 arc(158.32,61.48) 158.32,61.12 158.01,60.81 arc(158.01,60.45) 158.37,60.45 158.68,60.76 arc(159.04,60.76) 159.04,60.4 158.7,60.06 arc(158.63,59.9) 158.7,59.73 163.26,55.16 170.97,55.16 171.6,55.79 171.6,56.22 172.16,56.78 172.75,56.78 v3(173.18,56.36)
  BOTTOM w0.127: R442.2 180.29,89.22 175.21,89.22 173.18,87.19 v3(173.18,86.84)
DDR3_C_CK_0: length 102.5
  TOP w0.102: v2(149.89,88.12) P1.N2
  TOP w0.114: v3(171.58,60.36) 171.58,60.36 U40.J7 ; v3(171.58,75.6) 171.58,75.6 U32.J7 ; v3(171.58,90.84) 171.58,90.84 U28.J7
  06_SIG2 w0.102: v2(149.89,88.12) 149.45,88.12 149.35,88.22 149.35,88.41 149.45,88.51 151.06,88.51 151.1,88.47 151.13,88.47
  06_SIG2 w0.114: v3(171.58,60.36) 171.79,60.57 171.79,60.73 169.85,62.67 169.52,62.67 arc(169.36,62.61) 169.29,62.45 169.29,62.44 arc(169.06,62.22) 168.83,62.44 168.83,62.45 arc(168.76,62.61) 168.6,62.67 165.92,62.67 162.23,66.37 162.23,74.74 161.09,75.88 161.09,76.71 161.93,77.56 arc(161.93,78.04) 161.45,78.04 160.59,77.19 arc(160.12,76.99) 159.66,77.19 arc(159.46,77.65) 159.66,78.12 160.5,78.96 arc(160.5,79.44) 160.01,79.44 159.17,78.6 arc(158.71,78.41) 158.24,78.6 arc(158.04,79.07) 158.24,79.54 159.09,80.39 arc(159.09,80.88) 158.61,80.88 157.75,80.02 arc(157.29,79.83) 156.82,80.02 arc(156.63,80.49) 156.82,80.96 157.71,81.84 arc(157.71,82.33) 157.22,82.33 156.33,81.44 arc(155.87,81.25) 155.4,81.44 arc(155.21,81.91) 155.4,82.38 156.3,83.28 arc(156.3,83.76) 155.82,83.76 154.92,82.86 arc(154.45,82.67) 153.98,82.86 arc(153.79,83.33) 153.98,83.79 154.88,84.7 arc(154.88,85.18) 154.4,85.18 153.5,84.28 arc(153.03,84.09) 152.56,84.28 arc(152.37,84.75) 152.56,85.21 153.48,86.13 arc(153.48,86.61) 152.99,86.61 152.08,85.7 arc(151.61,85.51) 151.14,85.7 arc(150.95,86.17) 151.14,86.63 151.98,87.47 arc(152.08,87.71) 151.98,87.96 151.47,88.47 151.13,88.47
  BOTTOM w0.114: v3(171.58,60.36) 171.79,60.57 171.79,60.73 171.64,60.88 171.64,74.05 171.82,74.23 171.82,75.36 v3(171.58,75.6) 171.82,75.84 171.82,75.95 171.64,76.13 171.64,88.77 171.82,88.96 171.82,89.45 R437.2 171.82,90.25 171.82,90.6 v3(171.58,90.84)
DDR3_C_CK_N_0: length 102.6
  TOP w0.102: v2(148.89,88.12) P1.N3
  TOP w0.114: v3(172.38,60.36) 172.38,60.36 U40.K7 ; v3(172.38,90.84) 172.38,90.84 U28.K7 ; U32.K7 172.38,75.6 v3(172.38,75.6)
  06_SIG2 w0.102: 151.13,88.79 151.1,88.79 151.06,88.74 149.36,88.74 149.12,88.51 149.12,88.22 149.02,88.12 v2(148.89,88.12)
  06_SIG2 w0.114: 151.13,88.79 151.6,88.79 152.21,88.18 arc(152.4,87.71) 152.21,87.25 151.37,86.41 arc(151.27,86.17) 151.37,85.92 arc(151.61,85.82) 151.85,85.92 152.77,86.84 arc(153.7,86.84) 153.7,85.91 152.79,84.99 arc(152.69,84.75) 152.79,84.5 arc(153.03,84.4) 153.27,84.5 154.18,85.41 arc(155.11,85.41) 155.11,84.47 154.21,83.57 arc(154.11,83.33) 154.21,83.09 arc(154.45,82.98) 154.69,83.09 155.59,83.99 arc(156.53,83.99) 156.53,83.05 155.62,82.15 arc(155.52,81.91) 155.62,81.67 arc(155.87,81.57) 156.11,81.67 157,82.55 arc(157.93,82.55) 157.93,81.62 157.04,80.73 arc(156.94,80.49) 157.04,80.25 arc(157.29,80.15) 157.53,80.25 158.38,81.1 arc(159.32,81.1) 159.32,80.17 158.46,79.31 arc(158.36,79.07) 158.46,78.83 arc(158.71,78.73) 158.95,78.83 159.79,79.67 arc(160.72,79.67) 160.72,78.73 159.88,77.89 arc(159.78,77.65) 159.88,77.41 arc(160.12,77.31) 160.37,77.41 161.22,78.27 arc(162.16,78.27) 162.16,77.33 161.4,76.58 161.4,76.01 162.55,74.87 162.55,66.5 166.05,62.99 169.98,62.99 172.11,60.86 172.11,60.62 v3(172.38,60.36)
  BOTTOM w0.114: v3(172.38,90.84) 172.14,90.6 172.14,90.26 R437.1 172.14,89.45 172.14,88.83 171.96,88.64 171.96,76.26 172.14,76.09 172.14,75.84 v3(172.38,75.6) 172.14,75.36 172.14,74.1 171.96,73.92 171.96,61.02 172.11,60.86 172.11,60.62 v3(172.38,60.36)
DDR3_C_CKE_0: length 109.5
  TOP w0.127: v2(148.89,86.12) P1.L3 ; U28.K9 v3(173.18,92.44) ; U40.K9 v3(173.18,61.96) ; U32.K9 v3(173.18,77.2)
  06_SIG2 w0.127: v3(173.18,92.44) 172.78,92.04 172.78,77.59 v3(173.18,77.2) 172.78,76.8 172.78,62.35 v3(173.18,61.96) 172.78,61.56 172.78,60.2 172.47,59.88 166.37,59.88 164.39,61.86 164.39,62.73 161.29,65.82 161.29,74.33 161.18,74.44 arc(161,74.51) 160.83,74.44 160.38,73.99 arc(160.02,73.99) 160.02,74.35 160.47,74.8 arc(160.47,75.16) 160.11,75.16 159.66,74.71 arc(159.3,74.71) 159.3,75.07 159.75,75.52 arc(159.75,75.88) 159.39,75.88 158.94,75.43 arc(158.58,75.43) 158.58,75.79 159.03,76.23 arc(159.03,76.59) 158.67,76.59 158.22,76.15 arc(157.86,76.15) 157.86,76.51 158.31,76.95 arc(158.31,77.31) 157.95,77.31 157.5,76.87 arc(157.15,76.87) 157.15,77.22 157.59,77.67 arc(157.59,78.03) 157.23,78.03 156.79,77.58 arc(156.43,77.58) 156.43,77.94 156.87,78.39 arc(156.87,78.75) 156.51,78.75 156.07,78.3 arc(155.71,78.3) 155.71,78.66 156.16,79.11 arc(156.16,79.47) 155.8,79.47 155.35,79.02 arc(154.99,79.02) 154.99,79.38 155.44,79.83 arc(155.44,80.19) 155.08,80.19 154.63,79.74 arc(154.27,79.74) 154.27,80.1 154.72,80.55 arc(154.72,80.9) 154.36,80.9 153.91,80.46 arc(153.55,80.46) 153.55,80.82 154,81.26 arc(154,81.62) 153.64,81.62 153.19,81.18 arc(152.83,81.18) 152.83,81.54 153.28,81.98 arc(153.28,82.34) 152.92,82.34 152.48,81.89 arc(152.39,81.84) 152.3,81.82 arc(152.06,81.98) 152.12,82.25 152.56,82.7 arc(152.6,83.02) 152.3,83.12 arc(152.25,83.09) 152.2,83.06 151.74,82.6 arc(151.39,82.6) 151.39,82.96 151.84,83.42 arc(151.92,83.6) 151.84,83.78 150.04,85.59 149.42,85.59 v2(148.89,86.12)
  BOTTOM w0.127: v3(173.18,92.44) 174.15,93.41 178.25,93.41 R428.2
DDR3_C_CS_N_0: length 107.6
  TOP w0.127: U32.L2 v3(173.98,70.8) ; U40.L2 v3(173.98,55.56) ; v2(149.89,85.12) P1.K1 ; U28.L2 v3(173.98,86.04)
  BOTTOM w0.127: v2(149.89,85.12) 150.06,84.95 150.06,82.28 159.66,72.68 159.66,66.38 arc(159.59,66.2) 159.41,66.12 158.62,66.12 arc(158.37,65.87) 158.62,65.62 159.41,65.62 arc(159.66,65.36) 159.41,65.11 158.62,65.11 arc(158.37,64.85) 158.62,64.6 159.41,64.6 arc(159.66,64.35) 159.41,64.09 158.62,64.09 arc(158.37,63.84) 158.62,63.58 159.41,63.58 arc(159.66,63.33) 159.41,63.08 158.62,63.08 arc(158.37,62.82) 158.62,62.57 159.41,62.57 arc(159.66,62.31) 159.41,62.06 158.62,62.06 arc(158.37,61.81) 158.62,61.55 159.41,61.55 arc(159.66,61.3) 159.41,61.04 158.62,61.04 arc(158.37,60.79) 158.62,60.54 159.41,60.54 arc(159.66,60.28) 159.41,60.03 158.62,60.03 arc(158.37,59.77) 158.62,59.52 159.41,59.52 arc(159.59,59.45) 159.66,59.27 159.66,57.39 163.52,53.53 173.18,53.53 173.99,54.34 173.99,55.54 v3(173.98,55.56) 174.38,55.96 174.38,70.4 v3(173.98,70.8) 174.38,71.2 174.38,85.63 v3(173.98,86.04) 174.37,86.43 174.37,87.23 175.6,88.46 178.76,88.46 R449.2
DDR3_C_DM0: length 34.1
  TOP w0.127: P1.R2 149.89,90.12 v2(154.01,90.12) ; U32.E7 v3(168.38,74.8)
  03_SIG1 w0.127: v2(154.01,90.12) 154.01,90.12 154.7,89.43 154.7,87.73 154.99,87.44 arc(155.07,87.26) 154.99,87.08 154.84,86.93 arc(154.84,86.57) 155.2,86.57 155.35,86.72 arc(155.71,86.72) 155.71,86.36 155.56,86.21 arc(155.56,85.85) 155.92,85.85 156.07,86 arc(156.43,86) 156.43,85.64 156.28,85.49 arc(156.28,85.14) 156.64,85.14 156.79,85.28 arc(157.15,85.28) 157.15,84.93 157,84.78 arc(157,84.42) 157.36,84.42 157.51,84.57 arc(157.86,84.57) 157.86,84.21 157.72,84.06 arc(157.72,83.7) 158.07,83.7 158.22,83.85 arc(158.58,83.85) 158.58,83.49 158.43,83.34 arc(158.43,82.98) 158.79,82.98 158.94,83.13 arc(159.3,83.13) 159.3,82.77 159.15,82.62 arc(159.15,82.26) 159.51,82.26 159.66,82.41 arc(159.84,82.49) 160.02,82.41 166.43,76 167.17,76 v3(168.38,74.8)
DDR3_C_DM1: length 35
  TOP w0.127: v3(167.58,72.4) U32.D3 ; P1.R4 v2(147.89,90.12)
  BOTTOM w0.127: v3(167.58,72.4) 167.18,72.79 167.18,76.59 164.85,78.93 164.85,80.51 152.79,92.57 148.69,92.57 148.39,92.27 148.39,92.01 148.01,91.63 147.73,91.63 147.4,91.3 147.4,90.61 v2(147.89,90.12)
DDR3_C_DM2: length 31.9
  TOP w0.127: P1.Y4 v2(147.89,96.12) ; U28.E7 v3(168.38,90.84)
  BOTTOM w0.102: v2(147.89,96.12) 148.27,96.5 148.27,98.42 148.59,98.74 151.51,98.74 151.64,98.62 151.77,98.62
  BOTTOM w0.127: v3(168.38,90.84) 167.97,91.24 164.85,91.24 arc(164.68,91.32) 164.6,91.49 arc(164.68,91.67) 164.86,91.75 165.37,91.75 arc(165.56,91.83) 165.64,92.02 arc(165.56,92.2) 165.38,92.28 164.62,92.28 arc(164.6,92.28) 164.59,92.28 arc(164.43,92.36) 164.36,92.54 arc(164.43,92.71) 164.59,92.8 arc(164.6,92.8) 164.62,92.8 164.97,92.8 arc(165.15,92.87) 165.23,93.05 arc(165.15,93.25) 164.95,93.33 164.49,93.33 164.27,93.55 arc(164.22,93.67) 164.27,93.8 arc(164.27,94.16) 163.92,94.16 arc(163.79,94.11) 163.66,94.16 159.21,98.62 151.77,98.62
DDR3_C_DM3: length 29.6
  TOP w0.127: P1.Y7 v2(144.89,96.12) ; v3(167.58,86.84) U28.D3
  06_SIG2 w0.102: 144.65,93.79 144.5,93.94 144.5,95.74 v2(144.89,96.12)
  06_SIG2 w0.127: v3(167.58,86.84) 166.72,87.69 162.26,87.69 156.26,93.69 144.75,93.69 144.65,93.79
DDR3_C_DM4: length 58.5
  TOP w0.127: v2(142.89,90.12) P1.R9 ; U40.E7 168.78,58.36 v3(168.38,57.96)
  03_SIG1 w0.102: 142.48,85.92 142.48,86.78 142.5,86.8 142.5,89.74 v2(142.89,90.12)
  03_SIG1 w0.127: v3(168.38,57.96) 167.6,58.74 160.27,58.74 160.04,58.97 arc(159.97,59.15) 160.04,59.33 160.2,59.49 arc(160.2,59.85) 159.84,59.85 159.68,59.69 arc(159.32,59.69) 159.32,60.05 159.48,60.21 arc(159.48,60.57) 159.12,60.57 158.96,60.41 arc(158.6,60.41) 158.6,60.77 158.77,60.93 arc(158.77,61.29) 158.41,61.29 158.24,61.13 arc(157.89,61.13) 157.89,61.49 158.05,61.65 arc(158.05,62.01) 157.69,62.01 157.53,61.84 arc(157.17,61.84) 157.17,62.2 157.33,62.37 arc(157.33,62.72) 156.97,62.72 156.81,62.56 arc(156.45,62.56) 156.45,62.92 156.61,63.08 arc(156.61,63.44) 156.25,63.44 156.09,63.28 arc(155.73,63.28) 155.73,63.64 155.89,63.8 arc(155.89,64.16) 155.53,64.16 155.37,64 arc(155.01,64) 155.01,64.36 155.17,64.52 arc(155.17,64.88) 154.81,64.88 154.65,64.72 arc(154.47,64.64) 154.29,64.72 142.48,76.54 142.48,85.92
DDR3_C_DQ0: length 36.2
  TOP w0.127: P1.P1 v2(150.89,89.12) ; U32.E3 v3(168.38,71.6)
  03_SIG1 w0.127: v3(168.38,71.6) 167.98,72 163.4,72 157.09,78.3 arc(157.02,78.48) 157.09,78.66 157.27,78.83 arc(157.27,79.19) 156.91,79.19 156.73,79.02 arc(156.37,79.02) 156.37,79.38 156.55,79.55 arc(156.55,79.91) 156.19,79.91 156.02,79.74 arc(155.66,79.74) 155.66,80.1 155.83,80.27 arc(155.83,80.63) 155.47,80.63 155.3,80.46 arc(154.94,80.46) 154.94,80.82 155.11,80.99 arc(155.11,81.35) 154.75,81.35 154.58,81.18 arc(154.22,81.18) 154.22,81.53 154.39,81.71 arc(154.39,82.07) 154.03,82.07 153.86,81.89 arc(153.5,81.89) 153.5,82.25 153.68,82.43 arc(153.68,82.79) 153.32,82.79 153.14,82.61 arc(152.78,82.61) 152.78,82.97 152.96,83.15 arc(152.96,83.5) 152.6,83.5 152.42,83.33 arc(152.24,83.26) 152.06,83.33 151.87,83.53 151.87,88.14 v2(150.89,89.12)
DDR3_C_DQ1: length 36.5
  TOP w0.127: U32.F7 v3(169.18,74.8) ; P1.R1 v2(153.01,90.62)
  03_SIG1 w0.127: v3(169.18,74.8) 168.71,74.33 166.57,74.33 165.57,75.34 165.57,76.17 165.31,76.43 arc(165.14,76.5) 164.96,76.43 164.84,76.32 arc(164.77,76.26) 164.69,76.23 arc(164.64,76.22) 164.59,76.22 arc(164.54,76.25) 164.49,76.28 arc(164.41,76.48) 164.49,76.68 164.6,76.79 arc(164.6,77.15) 164.24,77.15 164.12,77.04 arc(163.77,77.04) 163.77,77.4 163.93,77.56 arc(164,77.72) 163.93,77.89 163.77,78.05 arc(163.59,78.14) 163.4,78.06 163.29,77.95 arc(162.93,77.95) 162.93,78.31 163.04,78.42 arc(163.04,78.78) 162.68,78.78 162.47,78.58 arc(162.11,78.58) 162.11,78.94 162.32,79.14 arc(162.32,79.5) 161.96,79.5 161.75,79.29 arc(161.39,79.29) 161.39,79.65 161.6,79.86 arc(161.6,80.22) 161.24,80.22 161.02,79.99 arc(160.66,79.99) 160.66,80.35 160.88,80.58 arc(160.88,80.94) 160.52,80.94 160.25,80.66 arc(159.89,80.66) 159.89,81.02 160.16,81.3 arc(160.16,81.66) 159.8,81.66 159.58,81.43 arc(159.4,81.36) 159.22,81.43 154.1,86.55 154.1,89.4 153.01,90.48 v2(153.01,90.62)
DDR3_C_DQ2: length 33.9
  TOP w0.127: P1.P2 v2(149.89,89.12) ; U32.F2 v3(169.18,70.8)
  03_SIG1 w0.127: v3(169.18,70.8) 168.78,71.19 163.59,71.19 159.97,74.82 arc(159.79,74.89) 159.61,74.82 159.52,74.73 arc(159.16,74.73) 159.16,75.09 159.25,75.18 arc(159.25,75.54) 158.89,75.54 158.8,75.45 arc(158.44,75.45) 158.44,75.81 158.53,75.9 arc(158.53,76.26) 158.17,76.26 158.08,76.17 arc(157.73,76.17) 157.73,76.53 157.81,76.61 arc(157.81,76.97) 157.45,76.97 157.37,76.89 arc(157.01,76.89) 157.01,77.25 157.09,77.33 arc(157.17,77.51) 157.09,77.69 151.46,83.32 151.46,86.73 150.38,87.81 150.38,88.63 v2(149.89,89.12)
DDR3_C_DQ3: length 37
  TOP w0.127: P1.U3 v2(148.89,92.12) ; U32.F8 v3(169.18,76.4)
  03_SIG1 w0.127: v3(169.18,76.4) 167.94,77.64 167.66,77.64 arc(167.48,77.56) 167.4,77.38 167.4,76.99 arc(167.15,76.73) 166.9,76.99 166.9,77.38 arc(166.82,77.56) 166.64,77.64 165.46,77.64 157.21,85.88 arc(157.13,86.09) 157.21,86.29 157.69,86.77 arc(157.69,87.13) 157.33,87.13 156.85,86.65 arc(156.67,86.58) 156.49,86.65 arc(156.42,86.83) 156.49,87.01 156.97,87.49 arc(156.97,87.85) 156.61,87.85 156.13,87.37 arc(155.95,87.29) 155.77,87.37 arc(155.7,87.55) 155.77,87.73 156.25,88.21 arc(156.25,88.57) 155.89,88.57 155.57,88.24 arc(155.39,88.16) 155.21,88.24 arc(155.13,88.42) 155.21,88.6 155.56,88.95 arc(155.62,89.09) 155.56,89.23 151.89,92.9 149.66,92.9 v2(148.89,92.12)
DDR3_C_DQ4: length 38.4
  TOP w0.127: P1.U2 v2(149.89,92.12) ; U32.H3 v3(170.78,72.4)
  03_SIG1 w0.127: v3(170.78,72.4) 169.27,73.9 166.19,73.9 163.22,76.87 162.99,76.87 159.24,80.62 arc(159.06,80.7) 158.88,80.62 158.82,80.56 arc(158.46,80.56) 158.46,80.92 158.52,80.98 arc(158.52,81.34) 158.16,81.34 158.1,81.28 arc(157.75,81.28) 157.75,81.64 157.81,81.7 arc(157.81,82.06) 157.45,82.06 157.39,82 arc(157.03,82) 157.03,82.36 157.09,82.42 arc(157.09,82.78) 156.73,82.78 156.67,82.72 arc(156.31,82.72) 156.31,83.08 156.37,83.14 arc(156.37,83.5) 156.01,83.5 155.95,83.44 arc(155.59,83.44) 155.59,83.8 155.65,83.86 arc(155.65,84.22) 155.29,84.22 155.23,84.16 arc(154.87,84.16) 154.87,84.51 154.93,84.57 arc(154.93,84.93) 154.57,84.93 154.51,84.87 arc(154.15,84.87) 154.15,85.23 154.21,85.29 arc(154.29,85.47) 154.21,85.65 153.62,86.25 153.62,89.22 152.55,90.28 152.55,91.61 151.64,92.52 150.28,92.52 v2(149.89,92.12)
DDR3_C_DQ5: length 37
  TOP w0.127: P1.V3 v2(147.89,94.12) ; U32.H8 v3(170.78,76.4)
  03_SIG1 w0.127: v3(170.78,76.4) 170.38,76.79 169.55,76.79 168.3,78.04 165.68,78.04 160.01,83.72 arc(159.93,83.9) 160.01,84.08 160.41,84.48 arc(160.41,84.84) 160.05,84.84 159.71,84.5 arc(159.35,84.5) 159.35,84.86 159.69,85.2 arc(159.69,85.56) 159.33,85.56 158.99,85.22 arc(158.63,85.22) 158.63,85.58 158.97,85.92 arc(158.97,86.28) 158.61,86.28 158.5,86.16 arc(158.14,86.16) 158.14,86.52 158.36,86.74 arc(158.42,86.89) 158.36,87.05 152.12,93.28 148.73,93.28 v2(147.89,94.12)
DDR3_C_DQ6: length 36.8
  TOP w0.127: v3(170.78,71.6) U32.G2 ; P1.W2 v2(149.89,94.12)
  03_SIG1 w0.127: v2(149.89,94.12) 150.31,94.55 152.07,94.55 163.88,82.74 163.88,81.55 165.51,79.92 165.81,79.92 166.88,78.85 169.62,78.85 171.58,76.9 171.58,76.15 171.18,75.76 171.18,72 v3(170.78,71.6)
DDR3_C_DQ7: length 38.8
  TOP w0.127: U32.H7 v3(170.78,75.6) ; P1.V2 v2(148.89,94.12)
  03_SIG1 w0.127: v2(148.89,94.12) 149.35,93.66 152.35,93.66 161.24,84.77 arc(161.31,84.59) 161.24,84.41 160.81,83.99 arc(160.81,83.63) 161.17,83.63 161.6,84.06 arc(161.96,84.06) 161.96,83.7 161.53,83.27 arc(161.53,82.91) 161.89,82.91 162.32,83.34 arc(162.67,83.34) 162.67,82.98 162.25,82.55 arc(162.25,82.19) 162.61,82.19 163.03,82.62 arc(163.22,82.69) 163.4,82.62 arc(163.47,82.44) 163.4,82.26 162.92,81.78 162.92,81.47 165.94,78.45 169.39,78.45 171.2,76.64 171.2,76.26 170.78,75.84 v3(170.78,75.6)
DDR3_C_DQ8: length 34
  TOP w0.127: U32.D7 v3(168.38,75.6) ; P1.V4 v2(146.89,94.12)
  BOTTOM w0.127: v3(168.38,75.6) 167.98,75.99 167.98,76.68 167.59,77.08 arc(167.51,77.26) 167.59,77.44 167.79,77.64 arc(167.79,78) 167.43,78 167.23,77.8 arc(166.87,77.8) 166.87,78.16 167.07,78.36 arc(167.07,78.72) 166.71,78.72 166.51,78.52 arc(166.33,78.44) 166.15,78.52 165.94,78.73 165.68,78.73 165.28,79.13 165.28,80.66 152.98,92.95 148.06,92.95 v2(146.89,94.12)
DDR3_C_DQ9: length 36.5
  TOP w0.127: v3(166.78,71.6) U32.C3 ; P1.U5 v2(146.89,92.12)
  BOTTOM w0.102: 151.16,87.49 150.91,87.74 148.67,87.74 148.34,88.07 148.34,88.21 148.04,88.5 147.4,88.5 147.16,88.74 146.65,88.74 146.38,89.01 146.38,89.27 146.02,89.62 145.77,89.62 145.5,89.89 145.5,91.34 145.8,91.63 146.39,91.63 v2(146.89,92.12)
  BOTTOM w0.127: 151.16,87.49 154.91,83.73 154.91,80.94 155.27,80.59 arc(155.45,80.52) 155.63,80.59 155.78,80.74 arc(156.14,80.74) 156.14,80.38 155.99,80.23 arc(155.91,80.05) 155.99,79.87 164.67,71.19 166.37,71.19 v3(166.78,71.6)
DDR3_C_DQ10: length 32
  TOP w0.127: U32.C8 v3(166.78,76.4) ; P1.T3 v2(148.89,91.12)
  BOTTOM w0.102: 149.37,91.61 v2(148.89,91.12)
  BOTTOM w0.127: v3(166.78,76.4) 166.11,76.4 165.51,77 165.51,77.61 164.41,78.7 164.41,80.38 156.75,88.04 arc(156.58,88.11) 156.4,88.04 156.2,87.84 arc(155.84,87.84) 155.84,88.2 156.04,88.4 arc(156.11,88.58) 156.04,88.76 arc(155.86,88.83) 155.68,88.76 155.48,88.56 arc(155.12,88.56) 155.12,88.92 155.32,89.12 arc(155.39,89.3) 155.32,89.47 arc(155.14,89.55) 154.96,89.47 154.76,89.28 arc(154.4,89.28) 154.4,89.64 154.6,89.83 arc(154.67,90.01) 154.6,90.19 153.11,91.68 152.8,91.68 arc(152.68,91.63) 152.63,91.51 152.63,91.32 arc(152.52,91.12) 152.3,91.08 arc(152.17,91.17) 152.12,91.32 152.12,91.88 arc(151.87,92.14) 151.61,91.88 151.61,91.86 arc(151.54,91.68) 151.36,91.61 149.37,91.61
DDR3_C_DQ11: length 31
  TOP w0.127: P1.P4 v2(147.89,89.12) ; U32.C2 167.58,71.6 v3(167.58,71.6)
  BOTTOM w0.102: 151.5,88.52 151.28,88.74 148.69,88.74 148.3,89.12 v2(147.89,89.12)
  BOTTOM w0.127: 151.5,88.52 151.71,88.3 151.71,88.1 157.51,82.31 157.51,79.5 164.99,72.02 165.43,72.02 arc(165.61,72.09) 165.68,72.27 165.68,72.5 arc(165.94,72.76) 166.19,72.5 166.19,72.27 arc(166.27,72.09) 166.45,72.02 167.16,72.02 v3(167.58,71.6)
DDR3_C_DQ12: length 34.9
  TOP w0.127: U32.A7 v3(165.18,75.6) ; P1.T4 v2(147.89,91.12)
  BOTTOM w0.127: v2(147.89,91.12) 148.39,90.61 152.4,90.61 155.8,87.22 arc(156.01,87.13) 156.22,87.22 156.43,87.42 arc(156.78,87.42) 156.78,87.06 156.57,86.85 arc(156.57,86.49) 156.93,86.49 157.14,86.71 arc(157.5,86.71) 157.5,86.35 157.29,86.13 arc(157.29,85.77) 157.65,85.77 157.86,85.99 arc(158.22,85.99) 158.22,85.63 158.01,85.42 arc(158.01,85.06) 158.37,85.06 158.58,85.27 arc(158.94,85.27) 158.94,84.91 158.73,84.7 arc(158.73,84.34) 159.09,84.34 159.3,84.55 arc(159.66,84.55) 159.66,84.19 159.45,83.98 arc(159.45,83.62) 159.81,83.62 160.02,83.83 arc(160.2,83.91) 160.38,83.83 164.01,80.2 164.01,78.45 164.59,77.86 164.59,77.68 164.01,77.1 arc(163.93,76.92) 164.01,76.75 arc(164.18,76.68) 164.35,76.75 164.61,77.01 arc(164.78,77.08) 164.95,77.01 arc(165.03,76.82) 164.95,76.63 164.75,76.43 arc(164.66,76.23) 164.75,76.02 v3(165.18,75.6)
DDR3_C_DQ13: length 36.4
  TOP w0.127: U32.A2 v3(165.18,70.8) ; P1.U6 v2(145.89,92.12)
  BOTTOM w0.102: v2(145.89,92.12) 145.27,91.51 145.27,89.18 145.95,88.5 146.89,88.5 147.89,87.51 150.55,87.51 150.72,87.34
  BOTTOM w0.127: 150.72,87.34 153.57,84.49 153.57,83.78 arc(153.61,83.69) 153.7,83.65 154.2,83.65 arc(154.46,83.4) 154.2,83.14 153.8,83.14 arc(153.54,82.89) 153.8,82.63 154.2,82.63 arc(154.46,82.38) 154.2,82.13 153.81,82.13 arc(153.64,82.05) 153.57,81.88 153.57,81.67 164.44,70.8 v3(165.18,70.8)
DDR3_C_DQ14: length 31.8
  TOP w0.127: P1.R3 v2(148.89,90.12) ; U32.B8 165.98,75.6 v3(165.98,75.6)
  BOTTOM w0.127: v2(148.89,90.12) 149,90.23 152.22,90.23 159.59,82.87 arc(159.77,82.79) 159.95,82.87 160.14,83.05 arc(160.5,83.05) 160.5,82.69 160.31,82.51 arc(160.31,82.15) 160.67,82.15 160.85,82.33 arc(161.21,82.33) 161.21,81.97 161.03,81.79 arc(161.03,81.43) 161.39,81.43 161.57,81.62 arc(161.93,81.62) 161.93,81.26 161.75,81.07 arc(161.75,80.71) 162.1,80.71 162.29,80.9 arc(162.65,80.9) 162.65,80.54 162.46,80.35 arc(162.46,79.99) 162.82,79.99 163.01,80.18 arc(163.37,80.18) 163.37,79.82 163.18,79.63 arc(163.11,79.45) 163.18,79.27 163.53,78.93 163.53,76.57 164.97,75.12 165.48,75.12 165.96,75.6 v3(165.98,75.6)
DDR3_C_DQ15: length 31
  TOP w0.127: U32.A3 v3(165.18,71.6) ; P1.P5 v2(146.89,89.12)
  BOTTOM w0.102: v2(146.89,89.12) 147.16,89.12 147.54,88.74 148.23,88.74 148.46,88.51 151.08,88.51 151.32,88.27 151.32,88.11
  BOTTOM w0.127: v3(165.18,71.6) 164.8,71.6 157.07,79.32 157.07,82.16 156.86,82.37 arc(156.68,82.45) 156.5,82.37 155.88,81.75 arc(155.52,81.75) 155.52,82.11 156.14,82.73 arc(156.21,82.91) 156.14,83.09 151.32,87.91 151.32,88.11
DDR3_C_DQ16: length 31.7
  TOP w0.127: P1.Y3 v2(148.89,96.12) ; U28.E3 v3(168.38,86.84)
  BOTTOM w0.127: v2(148.89,96.12) 149.39,95.62 151.05,95.62 151.23,95.44 154.25,95.44 157.5,92.2 arc(157.68,92.12) 157.86,92.2 158.12,92.46 arc(158.31,92.54) 158.51,92.46 arc(158.58,92.29) 158.51,92.12 158.22,91.84 arc(158.22,91.48) 158.58,91.48 158.84,91.74 arc(159.03,91.82) 159.22,91.74 arc(159.29,91.57) 159.22,91.41 158.94,91.12 arc(158.94,90.76) 159.3,90.76 159.56,91.02 arc(159.75,91.1) 159.94,91.02 arc(160.01,90.85) 159.94,90.69 159.65,90.4 arc(159.65,90.04) 160.01,90.04 160.28,90.3 arc(160.47,90.38) 160.66,90.3 arc(160.73,90.14) 160.66,89.97 160.37,89.68 arc(160.37,89.32) 160.73,89.32 161,89.59 arc(161.19,89.66) 161.38,89.59 arc(161.45,89.42) 161.38,89.25 161.09,88.96 arc(161.09,88.6) 161.45,88.6 161.69,88.84 arc(161.94,88.95) 162.2,88.84 163.79,87.26 167.96,87.26 v3(168.38,86.84)
DDR3_C_DQ17: length 31.4
  TOP w0.127: P1.AA3 v2(148.89,97.12) ; U28.F7 v3(169.18,90.84)
  BOTTOM w0.102: v2(148.89,97.12) 148.51,97.5 148.51,98.28 148.73,98.5 151.26,98.5 151.4,98.36
  BOTTOM w0.127: 151.4,98.36 151.53,98.23 158.88,98.23 158.93,98.19 arc(159,98.01) 158.93,97.83 158.52,97.42 arc(158.52,97.06) 158.88,97.06 159.28,97.47 arc(159.46,97.54) 159.64,97.47 arc(159.72,97.29) 159.64,97.11 159.24,96.71 arc(159.24,96.35) 159.6,96.35 160,96.75 arc(160.18,96.82) 160.36,96.75 163.96,93.15 163.96,91.43 164.94,90.44 168.87,90.44 169.18,90.75 v3(169.18,90.84)
DDR3_C_DQ18: length 28.6
  TOP w0.127: U28.F2 v3(169.18,86.04) ; P1.Y2 v2(149.89,95.12)
  BOTTOM w0.127: v2(149.89,95.12) 150.38,94.63 153.72,94.63 162.69,85.66 163.65,85.66 arc(163.83,85.58) 163.91,85.4 163.91,84.7 arc(164.16,84.44) 164.42,84.7 164.42,85.4 arc(164.67,85.66) 164.92,85.4 164.92,84.7 arc(165.18,84.44) 165.43,84.7 165.43,85.4 arc(165.5,85.56) 165.66,85.63 168.77,85.63 v3(169.18,86.04)
DDR3_C_DQ19: length 28.8
  TOP w0.127: U28.F8 v3(169.18,91.64) ; P1.AB2 v2(149.89,97.12)
  BOTTOM w0.127: v2(149.89,97.12) 150.24,97.47 157.43,97.47 159.31,95.59 arc(159.49,95.51) 159.67,95.59 159.92,95.83 arc(160.28,95.83) 160.28,95.48 160.04,95.23 arc(160.04,94.87) 160.4,94.87 160.82,95.3 arc(160.99,95.37) 161.15,95.3 163.5,92.95 163.5,91.2 165.1,89.6 168.66,89.6 169.57,90.51 169.57,91.24 v3(169.18,91.64)
DDR3_C_DQ20: length 28.7
  TOP w0.127: P1.Y1 v2(150.89,95.12) ; U28.H3 v3(170.78,86.84)
  BOTTOM w0.127: v3(170.78,86.84) 170.37,86.43 165.02,86.43 164.74,86.7 164.37,86.7 arc(164.22,86.64) 164.16,86.49 164.16,86.34 arc(164.09,86.17) 163.92,86.1 arc(163.73,86.18) 163.65,86.37 163.65,86.5 arc(163.59,86.64) 163.45,86.7 163.2,86.7 arc(163.15,86.69) 163.11,86.67 162.92,86.47 arc(162.71,86.39) 162.51,86.47 arc(162.44,86.65) 162.51,86.83 162.8,87.12 arc(162.8,87.48) 162.44,87.48 162.16,87.2 arc(161.98,87.13) 161.81,87.2 arc(161.73,87.38) 161.81,87.56 162.08,87.84 arc(162.16,88.02) 162.08,88.21 arc(161.91,88.28) 161.74,88.21 161.45,87.92 arc(161.27,87.85) 161.09,87.92 153.95,95.06 150.95,95.06 v2(150.89,95.12)
DDR3_C_DQ21: length 31.5
  TOP w0.127: U28.H8 v3(170.78,91.64) ; P1.AA4 v2(147.89,97.12)
  BOTTOM w0.102: v2(147.89,97.12) 147.4,97.61 147.4,99.25 147.89,99.74 151.38,99.74
  BOTTOM w0.127: 151.38,99.74 151.53,99.74 151.89,99.38 160.27,99.38 166.75,92.9 168.11,92.9 arc(168.28,92.83) 168.35,92.66 arc(168.6,92.41) 168.86,92.66 arc(168.93,92.83) 169.1,92.9 170.18,92.9 170.78,92.3 v3(170.78,91.64)
DDR3_C_DQ22: length 29.1
  TOP w0.127: U28.G2 169.98,86.84 v3(169.98,86.84) ; P1.AA1 v2(150.89,96.12)
  BOTTOM w0.127: v3(169.98,86.84) 169.13,86.84 168.33,87.64 164.08,87.64 158.43,93.3 arc(158.25,93.38) 158.07,93.3 157.76,93 arc(157.41,93) 157.41,93.36 157.71,93.66 arc(157.71,94.02) 157.35,94.02 157.05,93.72 arc(156.69,93.72) 156.69,94.08 156.99,94.38 arc(156.99,94.74) 156.63,94.74 156.33,94.44 arc(155.97,94.44) 155.97,94.8 156.27,95.1 arc(156.34,95.28) 156.27,95.46 arc(156.08,95.53) 155.9,95.46 155.6,95.16 arc(155.45,95.1) 155.29,95.16 155.19,95.26 155.19,95.69 155.07,95.82 151.46,95.82 151.16,96.12 v2(150.89,96.12)
DDR3_C_DQ23: length 28.9
  TOP w0.127: U28.H7 v3(170.78,90.84) ; P1.AB3 v2(147.89,98.12)
  BOTTOM w0.102: 151.51,99.25 151.26,99.5 148.84,99.5 147.89,98.55 v2(147.89,98.12)
  BOTTOM w0.127: v3(170.78,90.84) 170.38,91.23 170.38,91.8 170.15,92.03 166.99,92.03 160.02,99 151.77,99 151.51,99.25
DDR3_C_DQ24: length 33.1
  TOP w0.127: U28.D7 v3(167.58,90.84) ; P1.AA6 v2(145.89,97.12)
  06_SIG2 w0.102: v2(145.89,97.12) 146.27,96.74 151.61,96.74
  06_SIG2 w0.127: 151.61,96.74 167.84,96.74 167.98,96.6 167.98,93.73 arc(168.06,93.54) 168.25,93.46 168.81,93.46 arc(168.99,93.38) 169.07,93.2 arc(168.99,93.02) 168.81,92.95 167.21,92.95 arc(166.95,92.69) 167.21,92.44 167.73,92.44 arc(167.91,92.36) 167.98,92.18 167.98,91.24 v3(167.58,90.84)
DDR3_C_DQ25: length 34.7
  TOP w0.127: v3(166.78,86.84) U28.C3 ; P1.AA8 v2(143.89,97.12)
  06_SIG2 w0.102: 144.5,93.44 144.27,93.66 144.27,96.74 v2(143.89,97.12)
  06_SIG2 w0.127: v3(166.78,86.84) 166.36,87.26 162.01,87.26 161.78,87.48 arc(161.6,87.56) 161.42,87.48 161.31,87.37 arc(160.95,87.37) 160.95,87.73 161.06,87.84 arc(161.06,88.2) 160.7,88.2 160.59,88.09 arc(160.23,88.09) 160.23,88.45 160.34,88.56 arc(160.34,88.92) 159.98,88.92 159.87,88.81 arc(159.51,88.81) 159.51,89.17 159.62,89.28 arc(159.62,89.64) 159.26,89.64 159.15,89.53 arc(158.79,89.53) 158.79,89.89 158.9,90 arc(158.9,90.36) 158.55,90.36 158.44,90.25 arc(158.08,90.25) 158.08,90.61 158.19,90.72 arc(158.26,90.9) 158.19,91.08 155.96,93.31 144.63,93.31 144.5,93.44
DDR3_C_DQ26: length 33.1
  TOP w0.127: P1.W4 v2(147.89,95.12) ; U28.C8 v3(166.78,91.64)
  06_SIG2 w0.102: 151.45,95.51 148.27,95.51 v2(147.89,95.12)
  06_SIG2 w0.127: v3(166.78,91.64) 166.53,91.64 165.31,90.41 164.69,90.41 163.54,91.57 163.54,95.25 arc(163.29,95.51) 163.03,95.25 163.03,93.31 arc(162.78,93.06) 162.52,93.31 162.52,95.25 arc(162.27,95.51) 162.02,95.25 162.02,94.17 arc(161.76,93.92) 161.51,94.17 161.51,95.25 arc(161.43,95.43) 161.25,95.51 158.61,95.51 arc(158.45,95.44) 158.38,95.28 158.38,95.16 arc(158.13,94.91) 157.87,95.16 157.87,95.28 arc(157.81,95.44) 157.65,95.51 151.45,95.51
DDR3_C_DQ27: length 36.6
  TOP w0.127: P1.Y9 v2(142.89,96.12) ; U28.C2 v3(166.78,86.04)
  06_SIG2 w0.102: v2(142.89,96.12) 143.27,95.74 143.27,93.65 143.48,93.44
  06_SIG2 w0.127: 143.48,93.44 144.37,92.54 153.06,92.54 156.14,89.46 arc(156.32,89.39) 156.5,89.46 156.8,89.76 arc(157.16,89.76) 157.16,89.4 156.86,89.1 arc(156.86,88.74) 157.22,88.74 157.52,89.04 arc(157.88,89.04) 157.88,88.68 157.58,88.38 arc(157.58,88.02) 157.94,88.02 158.24,88.33 arc(158.6,88.33) 158.6,87.97 158.3,87.67 arc(158.3,87.31) 158.66,87.31 158.96,87.61 arc(159.32,87.61) 159.32,87.25 159.02,86.95 arc(159.02,86.59) 159.38,86.59 159.68,86.89 arc(159.85,86.96) 160.02,86.9 160.49,86.43 166.38,86.43 v3(166.78,86.04)
DDR3_C_DQ28: length 33.1
  TOP w0.127: P1.W5 v2(146.89,95.12) ; U28.A7 v3(165.18,90.84)
  06_SIG2 w0.102: 151.46,95.9 151.33,95.9 151.17,95.74 147.5,95.74 v2(146.89,95.12)
  06_SIG2 w0.127: v3(165.18,90.84) 165.18,91.67 arc(165.13,91.77) 165.02,91.82 164.3,91.82 arc(164.13,91.89) 164.06,92.06 arc(164.13,92.24) 164.31,92.32 165.3,92.32 arc(165.56,92.57) 165.3,92.82 164.3,92.82 arc(164.05,93.08) 164.3,93.33 164.9,93.33 arc(165.08,93.41) 165.15,93.59 arc(165.12,93.7) 165.05,93.79 arc(164.98,93.83) 164.9,93.84 164.3,93.84 arc(164.05,94.09) 164.3,94.35 164.92,94.35 arc(165.14,94.46) 165.16,94.7 arc(165.06,94.81) 164.92,94.86 164.31,94.86 arc(164.05,95.11) 164.31,95.36 165.02,95.36 arc(165.21,95.44) 165.29,95.63 arc(165.21,95.82) 165.02,95.9 151.46,95.9
DDR3_C_DQ29: length 35
  TOP w0.127: P1.AA9 v2(142.89,97.12) ; U28.A2 v3(165.18,86.04)
  06_SIG2 w0.127: v3(165.18,86.04) 164.59,86.04 arc(164.41,85.96) 164.33,85.78 164.33,85.61 arc(164.08,85.36) 163.83,85.61 163.83,85.78 arc(163.57,86.04) 163.32,85.78 163.32,85.61 arc(163.06,85.36) 162.81,85.61 162.81,85.78 arc(162.56,86.04) 162.3,85.78 162.3,85.61 arc(162.05,85.36) 161.79,85.61 161.79,85.78 arc(161.54,86.04) 161.29,85.78 161.29,85.61 arc(161.03,85.36) 160.78,85.61 160.78,85.78 arc(160.7,85.96) 160.52,86.04 158.86,86.04 153.26,91.63 143.76,91.63 143.38,92.01 143.38,92.95 142.37,93.97 142.37,96.6 v2(142.89,97.12)
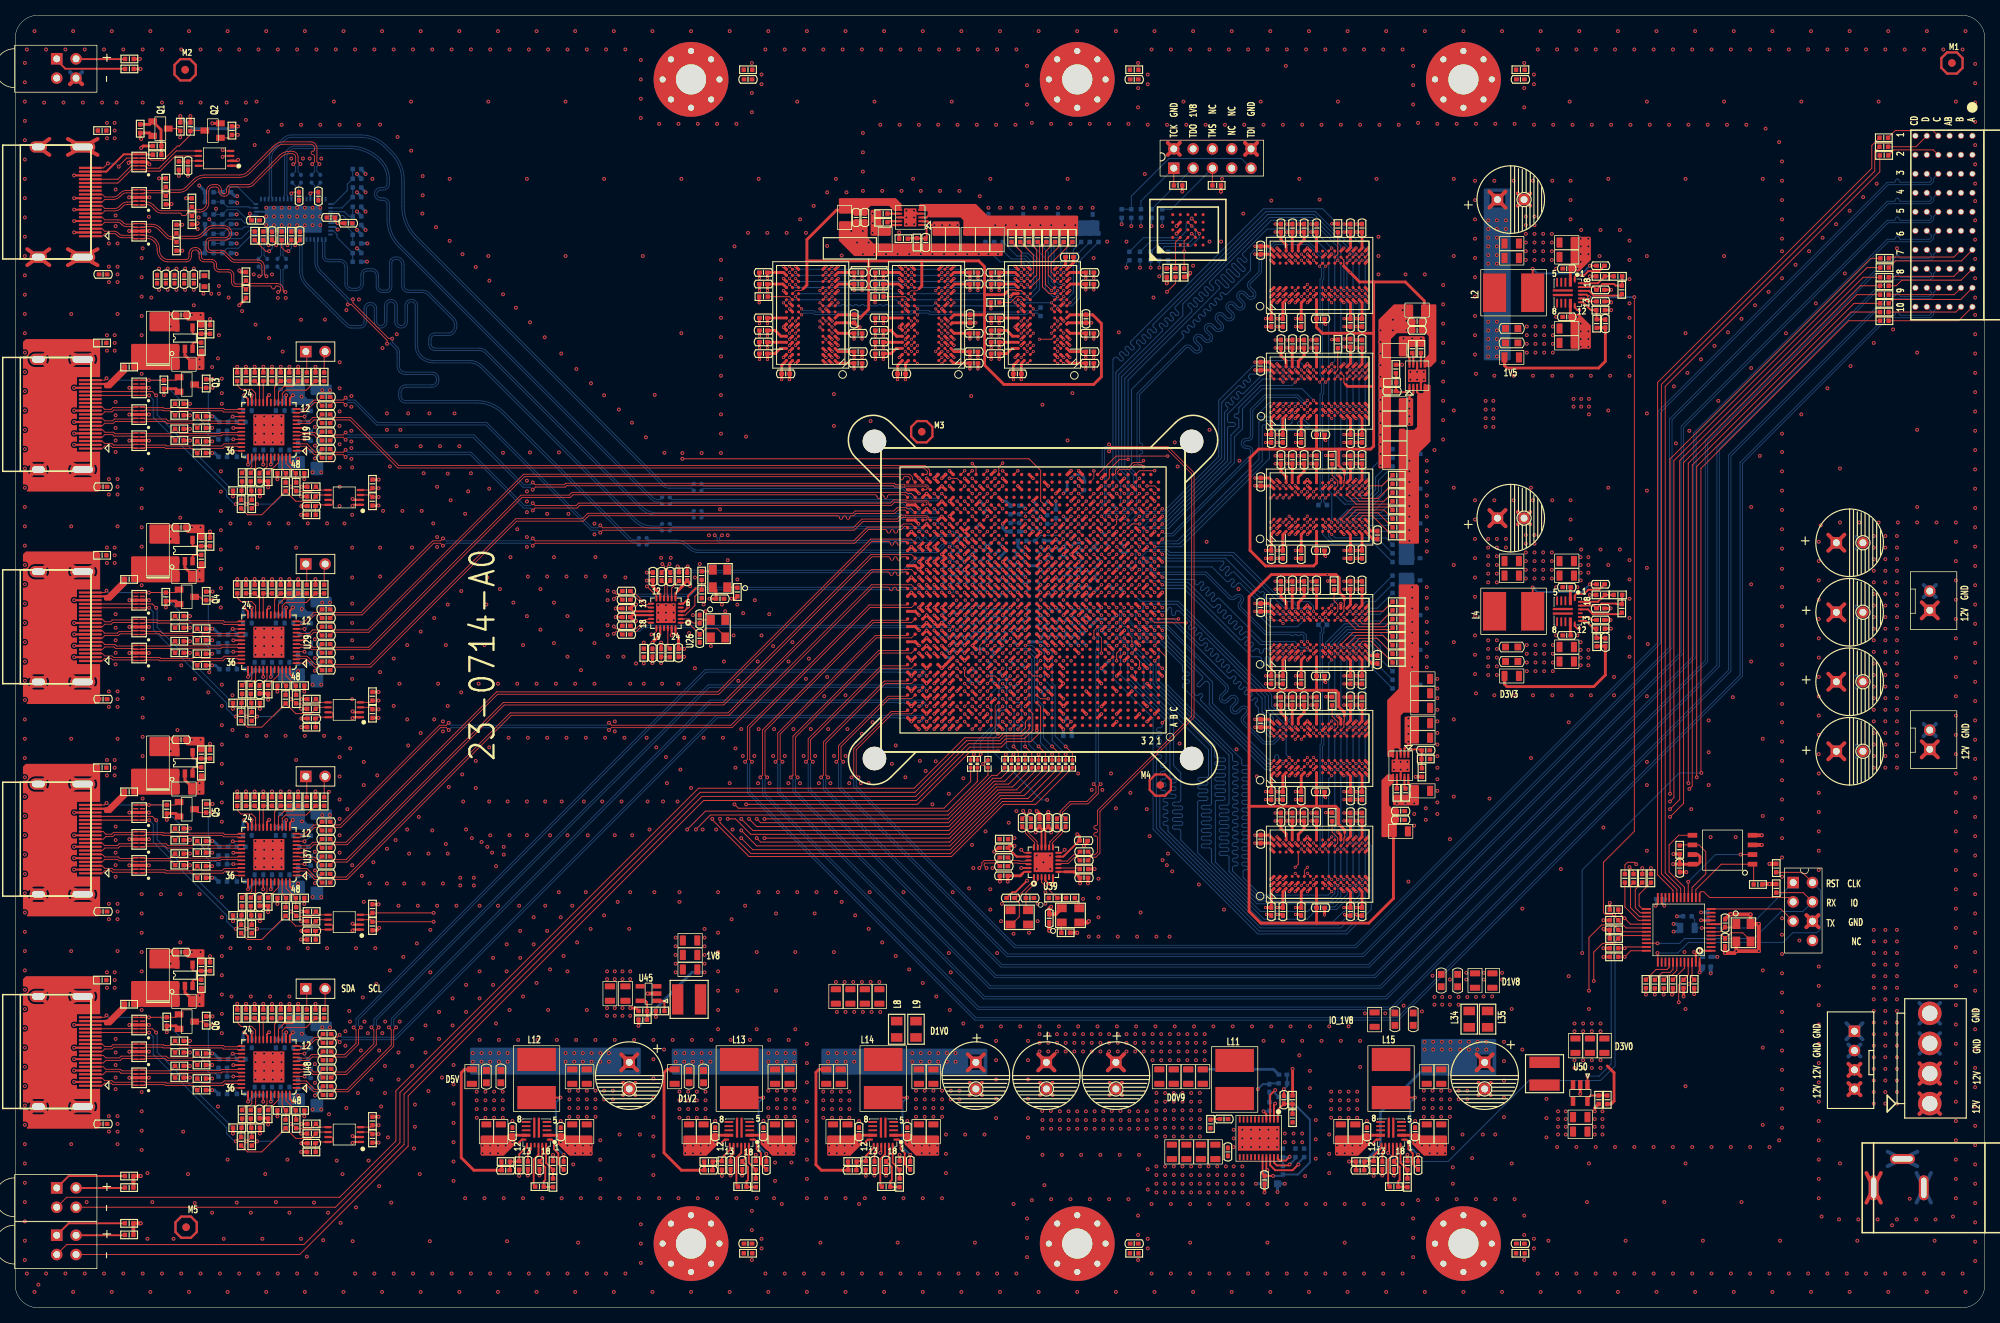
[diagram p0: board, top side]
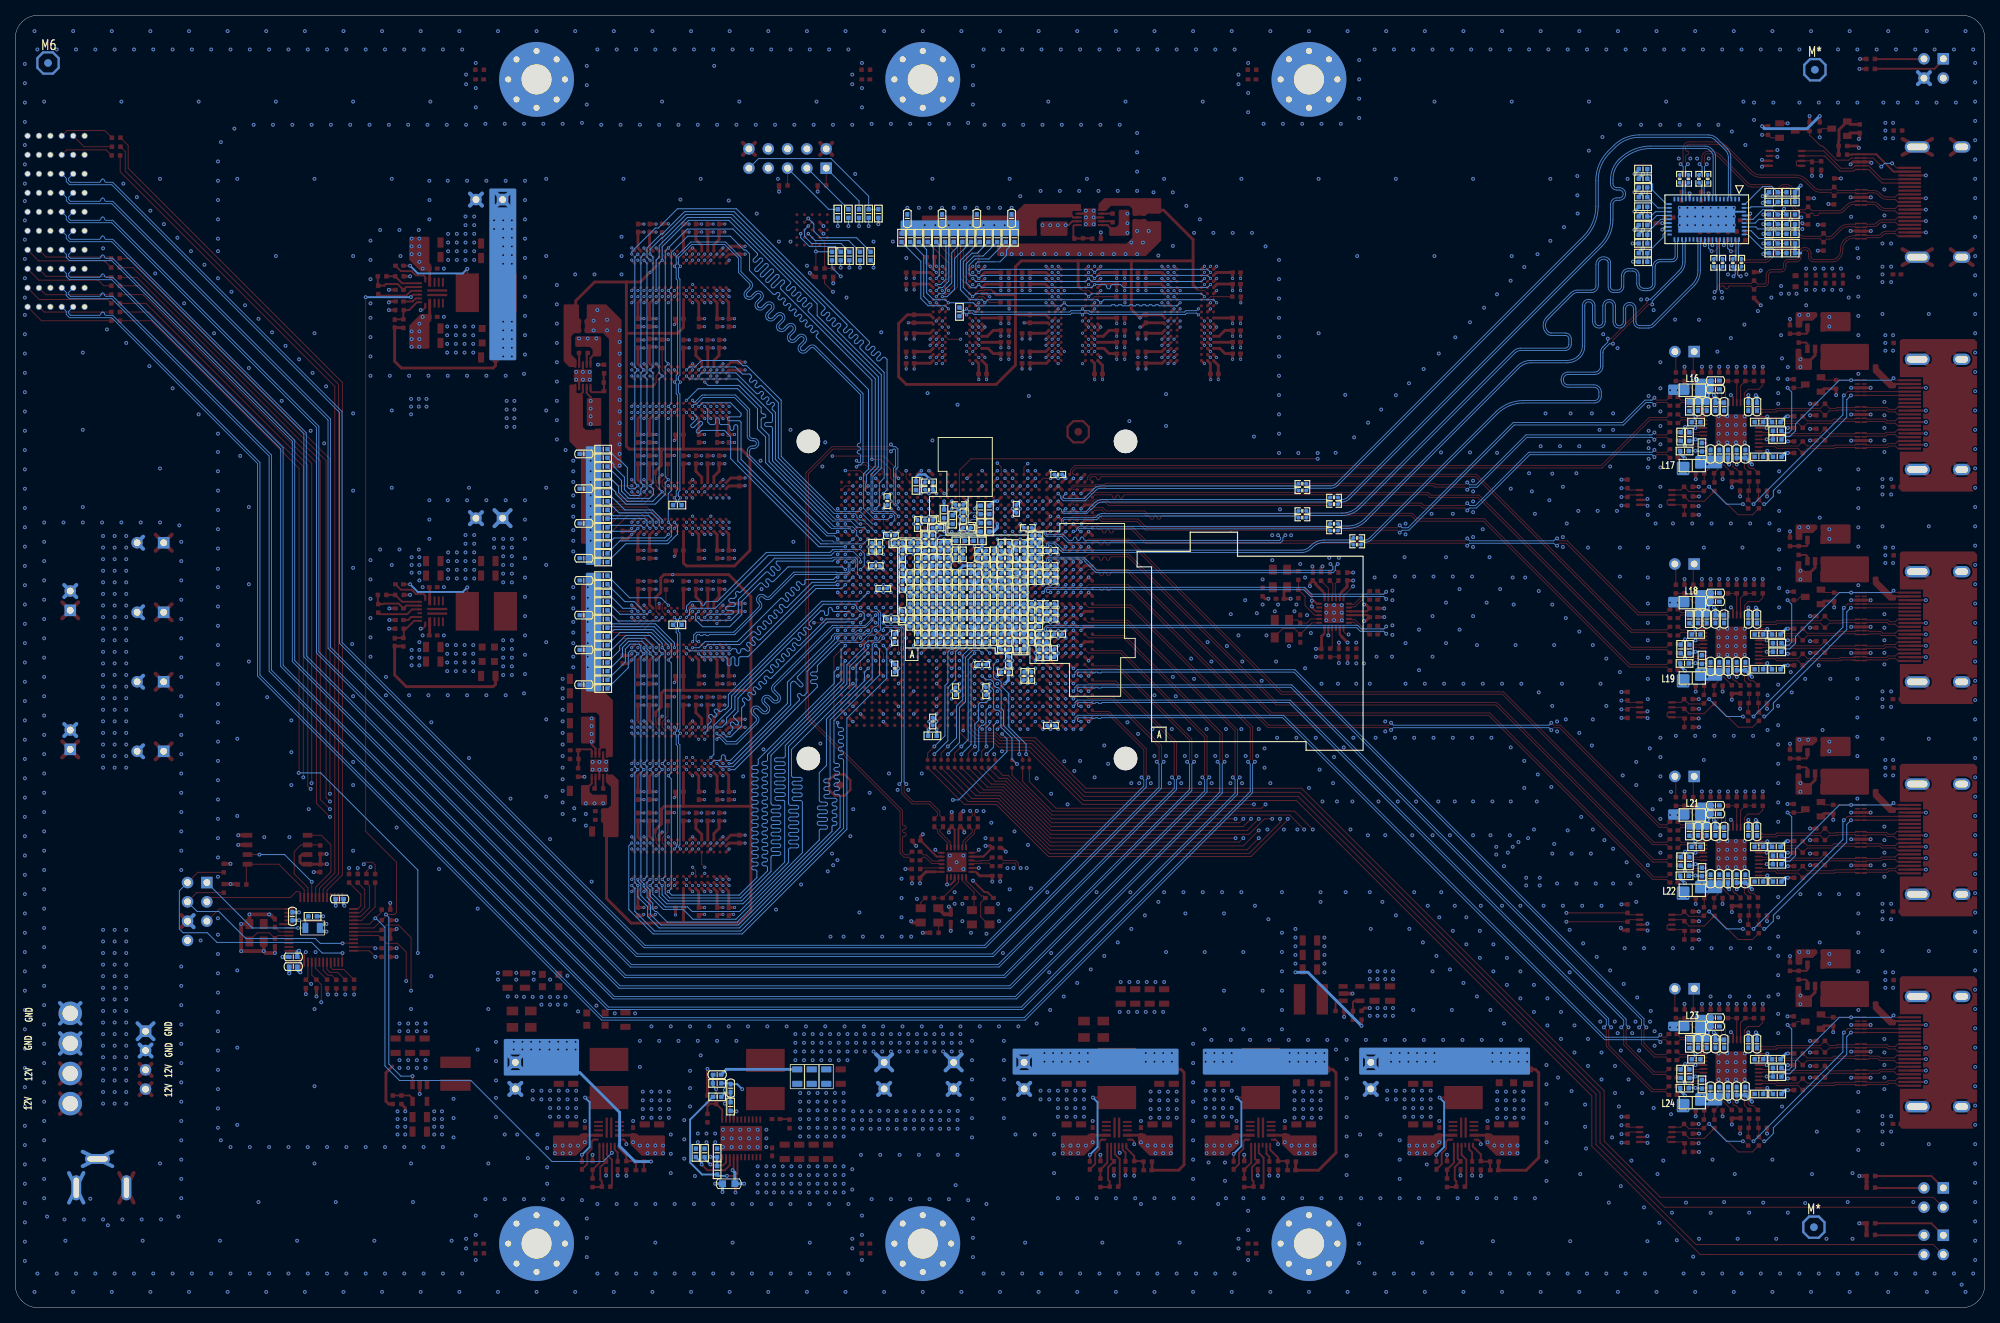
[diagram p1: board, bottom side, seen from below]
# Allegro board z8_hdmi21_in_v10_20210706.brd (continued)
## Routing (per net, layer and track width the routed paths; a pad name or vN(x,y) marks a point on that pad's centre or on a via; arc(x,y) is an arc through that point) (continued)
DDR3_C_DQ30: length 29.6
  TOP w0.127: U28.B8 v3(165.98,91.64) ; P1.Y6 v2(145.89,96.12)
  06_SIG2 w0.102: v2(145.89,96.12) 146.27,96.51 151.08,96.51 151.26,96.33 151.51,96.33
  06_SIG2 w0.127: v3(165.98,91.64) 166.42,92.08 166.42,92.82 arc(166.35,92.99) 166.19,93.05 165.94,93.05 arc(165.77,93.12) 165.7,93.29 arc(165.78,93.48) 165.96,93.56 167.11,93.56 arc(167.28,93.63) 167.36,93.79 arc(167.29,93.98) 167.11,94.06 166.55,94.06 arc(166.46,94.1) 166.42,94.19 166.42,96.15 166.24,96.33 151.51,96.33
DDR3_C_DQ31: length 36.8
  TOP w0.127: P1.Y8 v2(143.89,96.12) ; U28.A3 v3(165.18,86.84)
  06_SIG2 w0.102: 143.76,93.66 143.5,93.93 143.5,95.74 v2(143.89,96.12)
  06_SIG2 w0.127: 143.76,93.66 144.5,92.93 153.52,92.93 154.05,92.39 154.23,92.39 154.61,92.77 arc(154.8,92.85) 154.99,92.77 arc(155.06,92.61) 154.99,92.44 154.59,92.04 arc(154.59,91.68) 154.95,91.68 155.72,92.45 arc(155.86,92.52) 156.03,92.48 arc(156.15,92.3) 156.07,92.09 155.31,91.32 arc(155.31,90.96) 155.67,90.96 156.44,91.73 arc(156.8,91.73) 156.8,91.37 156.03,90.6 arc(156.03,90.24) 156.38,90.24 157.16,91.01 arc(157.33,91.08) 157.51,91.01 arc(157.58,90.83) 157.51,90.64 157.34,90.48 157.34,90.3 160.8,86.84 v3(165.18,86.84)
DDR3_C_DQ32: length 58.3
  TOP w0.127: U40.E3 v3(168.38,57.16) ; P1.T9 v2(142.89,91.12)
  03_SIG1 w0.102: 142.11,86.55 142.11,86.8 142.27,86.96 142.27,90.51 v2(142.89,91.12)
  03_SIG1 w0.127: 142.11,86.55 142.11,76.35 160.18,58.28 162.79,58.28 arc(162.97,58.21) 163.04,58.03 163.04,57.21 arc(163.3,56.96) 163.55,57.21 163.55,58.03 arc(163.8,58.28) 164.06,58.03 164.06,57.21 arc(164.31,56.96) 164.57,57.21 164.57,58.03 arc(164.82,58.28) 165.07,58.03 165.07,57.49 arc(165.33,57.24) 165.58,57.49 165.58,58.03 arc(165.84,58.28) 166.09,58.03 166.09,57.49 arc(166.34,57.24) 166.6,57.49 166.6,58.03 arc(166.67,58.21) 166.85,58.28 167.25,58.28 v3(168.38,57.16)
DDR3_C_DQ33: length 57
  TOP w0.127: P1.V8 v2(143.89,94.12) ; U40.F7 v3(169.18,60.36)
  03_SIG1 w0.102: 144.77,84.58 144.5,84.85 144.5,93.51 v2(143.89,94.12)
  03_SIG1 w0.127: 144.77,84.58 145.69,83.65 145.69,76.72 154.66,67.75 156.03,67.75 156.63,67.16 arc(156.8,67.09) 156.98,67.17 157.24,67.43 arc(157.42,67.5) 157.6,67.43 arc(157.68,67.25) 157.6,67.07 157.34,66.81 arc(157.34,66.45) 157.7,66.45 158.82,67.57 arc(159.18,67.57) 159.18,67.22 158.06,66.09 arc(158.06,65.73) 158.42,65.73 159.54,66.86 arc(159.72,66.93) 159.9,66.86 164.36,62.4 168.63,62.4 169.57,61.45 169.57,60.75 v3(169.18,60.36)
DDR3_C_DQ34: length 63.6
  TOP w0.127: P1.W9 v2(142.89,95.12) ; U40.F2 v3(169.18,55.56)
  03_SIG1 w0.127: v2(142.89,95.12) P1.W9 142.39,94.04 140.97,92.62 140.74,92.62 140.46,92.34 140.46,76.21 161.51,55.16 162.42,55.16 arc(162.59,55.09) 162.67,54.91 162.67,54.42 arc(162.92,54.17) 163.18,54.42 163.18,54.91 arc(163.43,55.16) 163.69,54.91 163.69,54.42 arc(163.94,54.17) 164.19,54.42 164.19,54.91 arc(164.45,55.16) 164.7,54.91 164.7,54.42 arc(164.96,54.17) 165.21,54.42 165.21,54.91 arc(165.28,55.09) 165.46,55.16 168.78,55.16 v3(169.18,55.56)
DDR3_C_DQ35: length 60.3
  TOP w0.127: P1.T8 v2(143.89,91.12) ; U40.F8 v3(169.18,61.16)
  03_SIG1 w0.102: v2(143.89,91.12) 144.27,90.74 144.27,84.54 144.53,84.29
  03_SIG1 w0.127: v3(169.18,61.16) 168.78,61.56 164.75,61.56 164.21,61.01 arc(163.85,61.01) 163.85,61.37 164.06,61.58 arc(164.13,61.76) 164.06,61.94 162.15,63.85 arc(161.97,63.92) 161.79,63.85 160.68,62.73 arc(160.32,62.73) 160.32,63.09 161.43,64.21 arc(161.43,64.57) 161.07,64.57 159.96,63.45 arc(159.6,63.45) 159.6,63.81 160.71,64.93 arc(160.71,65.28) 160.35,65.28 159.24,64.17 arc(158.88,64.17) 158.88,64.53 159.99,65.64 arc(159.99,66) 159.63,66 158.52,64.89 arc(158.31,64.82) 158.13,64.93 155.79,67.27 154.51,67.27 145.36,76.42 145.36,83.45 144.53,84.29
DDR3_C_DQ36: length 60
  TOP w0.127: P1.U8 v2(143.89,92.12) ; U40.H3 v3(170.78,56.36)
  03_SIG1 w0.102: v2(143.89,92.12) 143.36,92.65 141.86,92.65 141.5,92.29 141.5,86.86 141.73,86.63 141.73,86.42
  03_SIG1 w0.127: v3(170.78,56.36) 170.38,56.75 164.94,56.75 164.64,56.45 162.66,56.45 arc(162.48,56.53) 162.41,56.71 162.41,57.55 arc(162.15,57.8) 161.9,57.55 161.9,56.71 arc(161.83,56.53) 161.65,56.45 161.44,56.45 141.73,76.16 141.73,86.42
DDR3_C_DQ37: length 61.1
  TOP w0.127: U40.H8 v3(170.78,61.16) ; v2(144.89,94.12) P1.V7
  03_SIG1 w0.102: v2(144.89,94.12) 145.5,93.51 145.5,84.92 145.66,84.76
  03_SIG1 w0.127: 145.66,84.76 146.46,83.96 146.46,77.18 154.91,68.72 155.45,68.72 157.73,71.01 158.19,71.01 161.84,67.36 arc(161.91,67.18) 161.84,67 161.71,66.88 arc(161.71,66.52) 162.07,66.52 162.55,67 arc(162.91,67) 162.91,66.64 162.43,66.16 arc(162.43,65.8) 162.79,65.8 163.27,66.28 arc(163.63,66.28) 163.63,65.92 163.15,65.44 arc(163.15,65.08) 163.51,65.08 163.99,65.56 arc(164.35,65.56) 164.35,65.2 163.87,64.72 arc(163.87,64.36) 164.23,64.36 164.71,64.84 arc(165.06,64.84) 165.06,64.48 164.59,64.01 arc(164.59,63.65) 164.95,63.65 165.07,63.77 arc(165.25,63.84) 165.43,63.77 165.89,63.31 169.8,63.31 170.78,62.33 v3(170.78,61.16)
DDR3_C_DQ38: length 57.2
  TOP w0.127: P1.V9 v2(142.89,94.12) ; U40.G2 v3(169.98,55.56)
  03_SIG1 w0.102: v2(142.89,94.12) 141.27,92.51 141.27,86.55 141.35,86.47 141.35,86.17
  03_SIG1 w0.127: v3(169.98,55.56) 169.58,55.95 161.36,55.95 141.35,75.96 141.35,86.17
DDR3_C_DQ39: length 61.4
  TOP w0.127: P1.U7 v2(144.89,92.12) ; U40.H7 v3(170.78,60.36)
  03_SIG1 w0.102: v2(144.89,92.12) 145.27,91.74 145.27,84.64 145.43,84.48
  03_SIG1 w0.127: v3(170.78,60.36) 170.38,60.75 170.38,62.12 169.65,62.85 164.62,62.85 160.88,66.59 arc(160.81,66.76) 160.88,66.94 161.02,67.08 arc(161.02,67.44) 160.66,67.44 160.53,67.3 arc(160.17,67.3) 160.17,67.66 160.3,67.8 arc(160.3,68.16) 159.95,68.16 159.81,68.02 arc(159.45,68.02) 159.45,68.38 159.56,68.49 arc(159.63,68.65) 159.56,68.8 arc(159.36,68.88) 159.15,68.8 158.2,67.85 arc(157.84,67.85) 157.84,68.21 158.79,69.16 arc(158.79,69.52) 158.43,69.52 157.06,68.14 arc(156.7,68.14) 156.7,68.5 158.03,69.84 arc(158.12,70.06) 158.03,70.27 arc(157.87,70.34) 157.71,70.27 155.68,68.24 154.79,68.24 146.08,76.95 146.08,83.83 145.43,84.48
DDR3_C_DQS0N: length 37
  TOP w0.114: U32.G3 v3(169.98,71.6) ; P1.T1 v2(150.89,91.12)
  03_SIG1 w0.114: v3(169.98,71.6) 169.74,71.84 169.2,71.84 168.21,72.83 165.43,72.83 164.56,73.71 arc(164.33,73.8) 164.11,73.71 163.9,73.5 arc(162.96,73.5) 162.96,74.43 163.11,74.57 arc(163.21,74.81) 163.11,75.06 163.09,75.07 arc(162.86,75.17) 162.64,75.07 162.48,74.92 arc(161.55,74.92) 161.55,75.85 161.69,75.99 arc(161.79,76.23) 161.69,76.48 161.67,76.49 arc(161.44,76.59) 161.22,76.49 161.06,76.33 arc(160.13,76.33) 160.13,77.27 160.27,77.41 arc(160.37,77.65) 160.27,77.9 160.25,77.91 arc(160.03,78.01) 159.8,77.91 159.74,77.85 arc(159.33,77.68) 158.92,77.85 158.41,78.37 158.41,79.15 152.67,84.89 152.67,88.39 151.46,89.6 151.46,91.22 151.35,91.33 151,91.33 150.89,91.22 v2(150.89,91.12)
DDR3_C_DQS0P: length 37.3
  TOP w0.114: P1.U1 v2(150.89,92.12) ; U32.F3 v3(169.98,72.4)
  03_SIG1 w0.114: v2(150.89,92.12) 150.89,91.76 151,91.65 151.48,91.65 151.78,91.35 151.78,89.73 152.98,88.52 152.98,85.02 158.72,79.28 158.72,78.5 159.15,78.08 arc(159.33,78) 159.51,78.08 159.57,78.14 arc(160.03,78.32) 160.48,78.14 160.49,78.12 arc(160.69,77.65) 160.49,77.19 160.35,77.04 arc(160.35,76.56) 160.84,76.56 160.99,76.72 arc(161.44,76.9) 161.9,76.72 161.91,76.7 arc(162.1,76.23) 161.91,75.77 161.77,75.63 arc(161.77,75.14) 162.25,75.14 162.41,75.3 arc(162.86,75.48) 163.31,75.3 163.33,75.28 arc(163.52,74.81) 163.33,74.35 163.19,74.21 arc(163.19,73.72) 163.67,73.72 163.88,73.93 arc(164.33,74.12) 164.78,73.93 165.56,73.15 168.34,73.15 169.34,72.16 169.74,72.16 v3(169.98,72.4)
DDR3_C_DQS1N: length 36.8
  TOP w0.114: U32.B7 v3(166.78,74.8)
  TOP w0.127: P1.T6 v2(145.89,91.12)
  BOTTOM w0.102: 151.1,89.46 151.08,89.46 151.03,89.51 147.21,89.51 146.27,90.45 146.27,90.74 v2(145.89,91.12)
  BOTTOM w0.114: 151.1,89.46 151.44,89.46 159.17,81.73 arc(159.27,81.49) 159.17,81.25 158.6,80.68 arc(158.41,80.21) 158.6,79.74 arc(159.07,79.55) 159.53,79.74 159.97,80.17 arc(160.45,80.17) 160.45,79.69 160.02,79.26 arc(159.82,78.79) 160.02,78.32 160.02,78.32 arc(160.49,78.13) 160.95,78.32 161.39,78.76 arc(161.87,78.76) 161.87,78.27 161.44,77.84 arc(161.24,77.37) 161.44,76.9 164.17,74.17 165.57,74.17 166.44,75.04 166.66,75.04 166.78,74.92 v3(166.78,74.8)
DDR3_C_DQS1P: length 36.7
  TOP w0.114: U32.C7 v3(166.78,75.6)
  TOP w0.127: P1.T5 v2(146.89,91.12)
  BOTTOM w0.102: 151.1,89.78 151.08,89.78 151.03,89.74 147.31,89.74 146.5,90.54 146.5,91.09 146.61,91.2 146.81,91.2 v2(146.89,91.12)
  BOTTOM w0.114: v3(166.78,75.6) 166.78,75.47 166.66,75.36 166.31,75.36 165.44,74.49 164.3,74.49 161.66,77.13 arc(161.56,77.37) 161.66,77.61 162.1,78.05 arc(162.1,78.98) 161.16,78.98 160.73,78.55 arc(160.49,78.45) 160.24,78.55 arc(160.14,78.79) 160.24,79.03 160.68,79.47 arc(160.68,80.4) 159.74,80.4 159.31,79.97 arc(159.07,79.87) 158.82,79.97 arc(158.72,80.21) 158.82,80.45 159.4,81.02 arc(159.59,81.49) 159.4,81.96 151.57,89.78 151.1,89.78
DDR3_C_DQS2N: length 29
  TOP w0.114: U28.G3 v3(169.98,87.64)
  TOP w0.127: P1.AC2 v2(149.89,98.12)
  BOTTOM w0.102: v2(149.89,98.12) 149.6,98.12 149.5,98.02 149.5,96.88 149.65,96.74 151.03,96.74 151.08,96.78 151.1,96.78
  BOTTOM w0.114: 151.1,96.78 156.66,96.78 159.87,93.58 arc(160.11,93.48) 160.35,93.58 160.45,93.68 arc(161.38,93.68) 161.38,92.74 161.28,92.65 arc(161.18,92.4) 161.28,92.16 164.57,88.87 169.46,88.87 169.84,88.5 169.84,87.78 v3(169.98,87.64)
DDR3_C_DQS2P: length 29.3
  TOP w0.114: U28.F3 v3(169.18,87.64)
  TOP w0.127: P1.AC3 v2(148.89,98.12)
  BOTTOM w0.102: 151.1,96.46 151.08,96.46 151.03,96.51 149.55,96.51 149.27,96.79 149.27,98.02 149.17,98.12 v2(148.89,98.12)
  BOTTOM w0.114: 151.1,96.46 156.53,96.46 159.64,93.36 arc(160.11,93.16) 160.58,93.36 160.67,93.45 arc(161.16,93.45) 161.16,92.97 161.06,92.87 arc(160.87,92.4) 161.06,91.94 164.44,88.56 167.75,88.56 167.88,88.43 168.15,88.43 168.28,88.56 168.54,88.56 168.67,88.43 168.94,88.43 169.06,88.56 169.33,88.56 169.52,88.37 169.52,87.75 169.41,87.64 v3(169.18,87.64)
DDR3_C_DQS3N: length 35.6
  TOP w0.114: U28.B7 v3(166.78,90.04)
  TOP w0.127: v2(144.89,95.12) P1.W7
  06_SIG2 w0.102: 151.17,94.46 151.15,94.46 151.1,94.51 145.4,94.51 145.2,94.71 145.2,95.02 145.09,95.12 v2(144.89,95.12)
  06_SIG2 w0.114: 151.17,94.46 156.75,94.46 157.66,93.56 arc(158.12,93.37) 158.59,93.56 159.3,94.27 arc(159.54,94.37) 159.77,94.27 arc(159.88,94.02) 159.77,93.78 159.07,93.08 arc(159.07,92.14) 160.01,92.14 160.72,92.85 arc(160.95,92.95) 161.19,92.85 arc(161.29,92.61) 161.19,92.36 160.49,91.66 arc(160.49,90.73) 161.43,90.73 161.92,91.21 arc(162.15,91.31) 162.38,91.21 arc(162.48,90.96) 162.38,90.7 161.91,90.24 arc(161.91,89.31) 162.85,89.31 163.38,89.84 163.66,89.84 164.13,89.37 165.58,89.37 166.49,90.28 166.66,90.28 166.78,90.16 v3(166.78,90.04)
DDR3_C_DQS3P: length 35.4
  TOP w0.114: U28.C7 v3(166.78,90.84)
  TOP w0.127: P1.W6 v2(145.89,95.12)
  06_SIG2 w0.102: 151.17,94.78 151.15,94.78 151.1,94.74 145.49,94.74 145.42,94.81 145.42,95.02 145.53,95.12 v2(145.89,95.12)
  06_SIG2 w0.114: 151.17,94.78 156.89,94.78 157.88,93.79 arc(158.12,93.69) 158.37,93.79 159.07,94.5 arc(159.54,94.69) 160,94.5 arc(160.19,94.02) 160,93.55 159.3,92.85 arc(159.3,92.37) 159.78,92.37 160.49,93.08 arc(160.95,93.27) 161.42,93.08 arc(161.61,92.61) 161.42,92.13 160.72,91.43 arc(160.72,90.95) 161.2,90.95 161.69,91.44 arc(162.15,91.63) 162.6,91.44 arc(162.8,90.96) 162.6,90.48 162.14,90.02 arc(162.14,89.53) 162.62,89.53 163.25,90.16 163.8,90.16 164.27,89.69 165.45,89.69 166.36,90.6 166.66,90.6 166.78,90.71 v3(166.78,90.84)
DDR3_C_DQS4N: length 56.2
  TOP w0.114: U40.G3 v3(169.98,57.16)
  TOP w0.127: v2(141.89,91.12) P1.T10
  03_SIG1 w0.102: v2(141.89,91.12) 141.89,91.41 141.99,91.51 143.13,91.51 143.27,91.37 143.27,84.99 143.23,84.95 143.23,84.92
  03_SIG1 w0.114: v3(169.98,57.16) 169.98,57.28 169.86,57.4 169.49,57.4 168.95,57.94 168.95,59.05 168.43,59.58 161.73,59.58 161.36,59.95 arc(161.19,60.35) 161.36,60.75 161.91,61.3 arc(161.91,61.79) 161.42,61.79 160.88,61.24 arc(160.47,61.07) 160.07,61.24 155.51,65.8 154.39,65.8 143.59,76.6 143.59,79.78 143.46,79.91 143.46,80.18 143.59,80.3 143.59,80.57 143.46,80.7 143.46,80.96 143.59,81.09 143.59,81.36 143.46,81.48 143.46,81.75 143.59,81.88 143.59,82.14 143.48,82.25 143.48,82.56 143.59,82.66 143.59,82.93 143.48,83.03 143.48,83.35 143.59,83.45 143.59,84.06 143.23,84.42 143.23,84.92
DDR3_C_DQS4P: length 56.2
  TOP w0.114: U40.F3 169.58,57.56 v3(169.98,57.96)
  TOP w0.127: v2(141.89,92.12) P1.U10
  03_SIG1 w0.102: 143.55,84.92 143.55,84.95 143.5,84.99 143.5,91.46 143.22,91.74 142.27,91.74 v2(141.89,92.12)
  03_SIG1 w0.114: 143.55,84.92 143.55,84.55 143.9,84.19 143.9,76.73 154.52,66.12 155.64,66.12 160.29,61.46 arc(160.47,61.39) 160.65,61.46 161.2,62.01 arc(162.13,62.01) 162.13,61.08 161.59,60.53 arc(161.51,60.35) 161.59,60.17 161.86,59.89 168.56,59.89 169.27,59.19 169.27,58.07 169.62,57.72 169.86,57.72 169.98,57.83 v3(169.98,57.96)
DDR3_C_ODT_0: length 107.8
  TOP w0.127: U28.K1 v3(173.18,85.24) ; P1.J1 v2(150.89,84.12) ; U32.K1 v3(173.18,70) ; U40.K1 v3(173.18,54.76)
  BOTTOM w0.127: v2(150.89,84.12) 151.36,83.65 151.36,82.13 161.34,72.15 161.34,71.58 arc(161.42,71.4) 161.59,71.33 161.95,71.33 arc(162.2,71.08) 161.95,70.82 161.59,70.82 arc(161.34,70.57) 161.59,70.31 161.95,70.31 arc(162.2,70.06) 161.95,69.81 161.59,69.81 arc(161.34,69.55) 161.59,69.3 161.95,69.3 arc(162.2,69.04) 161.95,68.79 161.59,68.79 arc(161.34,68.54) 161.59,68.28 161.95,68.28 arc(162.2,68.03) 161.95,67.77 161.59,67.77 arc(161.34,67.52) 161.59,67.27 161.95,67.27 arc(162.2,67.01) 161.95,66.76 161.59,66.76 arc(161.34,66.5) 161.59,66.25 161.95,66.25 arc(162.2,66) 161.95,65.74 161.59,65.74 arc(161.34,65.49) 161.59,65.23 161.95,65.23 arc(162.2,64.98) 161.95,64.73 161.59,64.73 arc(161.34,64.47) 161.59,64.22 161.95,64.22 arc(162.2,63.96) 161.95,63.71 161.59,63.71 arc(161.34,63.46) 161.59,63.2 161.95,63.2 arc(162.2,62.95) 161.95,62.69 161.59,62.69 arc(161.34,62.44) 161.59,62.19 161.95,62.19 arc(162.2,61.93) 161.95,61.68 161.59,61.68 arc(161.34,61.42) 161.59,61.17 161.95,61.17 arc(162.2,60.92) 161.95,60.66 161.59,60.66 arc(161.34,60.41) 161.59,60.15 161.95,60.15 arc(162.2,59.9) 161.95,59.65 161.59,59.65 arc(161.34,59.39) 161.59,59.14 161.95,59.14 arc(162.2,58.88) 161.95,58.63 161.59,58.63 arc(161.34,58.38) 161.59,58.12 161.95,58.12 arc(162.2,57.87) 161.95,57.61 161.72,57.61 arc(161.58,57.55) 161.52,57.41 161.52,56.61 163.84,54.29 172.71,54.29 v3(173.18,54.76) U40.K1 172.78,69.6 v3(173.18,70) 172.78,70.39 172.78,84.84 v3(173.18,85.24) 172.77,85.64 172.77,87.34 175.03,89.6 181.05,89.6 R438.2
DDR3_C_RAS_N_0: length 117
  TOP w0.127: v2(143.89,90.12) 143.89,90.12 P1.R7 ; U40.J3 v3(172.38,56.36) ; U28.J3 v3(172.38,86.84) ; U32.J3 v3(172.38,71.6)
  03_SIG1 w0.127: v3(172.38,56.36) 172.77,56.75 172.77,71.2 v3(172.38,71.6) 172.77,71.99 172.77,86.44 v3(172.38,86.84)
  06_SIG2 w0.127: v3(172.38,56.36) 171.96,55.94 171.96,55.46 170.86,54.36 163.45,54.36 148.69,69.12 arc(148.62,69.3) 148.69,69.48 149.03,69.82 arc(149.03,70.18) 148.67,70.18 148.26,69.77 arc(147.9,69.77) 147.9,70.12 148.32,70.54 arc(148.32,70.9) 147.96,70.9 147.54,70.48 arc(147.18,70.48) 147.18,70.84 147.6,71.26 arc(147.6,71.62) 147.24,71.62 146.82,71.2 arc(146.46,71.2) 146.46,71.56 146.88,71.98 arc(146.88,72.34) 146.52,72.34 146.1,71.92 arc(145.74,71.92) 145.74,72.28 146.16,72.7 arc(146.16,73.05) 145.8,73.05 145.39,72.64 arc(145.03,72.64) 145.03,73 145.44,73.41 arc(145.44,73.77) 145.08,73.77 144.65,73.34 arc(144.3,73.34) 144.3,73.7 144.72,74.13 arc(144.72,74.49) 144.36,74.49 143.94,74.06 arc(143.58,74.06) 143.58,74.42 144,74.85 arc(144.07,74.96) 144.07,75.1 arc(143.89,75.28) 143.65,75.21 143.23,74.79 arc(142.9,74.77) 142.83,75.1 arc(142.85,75.13) 142.87,75.15 143.29,75.57 arc(143.29,75.93) 142.93,75.93 142.5,75.5 arc(142.14,75.5) 142.14,75.86 142.57,76.29 arc(142.63,76.4) 142.63,76.53 arc(142.45,76.71) 142.21,76.65 142.03,76.47 141.81,76.47 141.68,76.6 141.68,86.83 143.39,88.54 143.39,89.62 v2(143.89,90.12)
  BOTTOM w0.127: R435.2 180.54,89.98 174.85,89.98 172.38,87.5 v3(172.38,86.84)
DDR3_C_RST_N_0: length 100.4
  TOP w0.127: U40.T2 v3(177.98,55.56) ; U32.T2 v3(177.98,70.8) ; v2(150.89,76.96) 151.38,77.46 151.38,85.63 P1.L1 ; U28.T2 v3(177.98,86.04)
  TOP w0.381: v3(177.98,86.04) 178.21,85.81 C198.1
  03_SIG1 w0.127: v3(177.98,55.56) 178.37,55.95 178.37,70.4 v3(177.98,70.8) 178.37,71.19 178.37,85.64 v3(177.98,86.04)
  BOTTOM w0.127: v2(150.89,76.96) 150.89,76.57 arc(150.81,76.39) 150.63,76.32 150.37,76.32 arc(150.11,76.06) 150.37,75.81 150.56,75.81 arc(150.81,75.55) 150.56,75.3 150.37,75.3 arc(150.11,75.05) 150.37,74.79 150.56,74.79 arc(150.81,74.54) 150.56,74.28 150.37,74.28 arc(150.11,74.03) 150.37,73.78 150.56,73.78 arc(150.81,73.52) 150.56,73.27 150.37,73.27 arc(150.11,73.01) 150.37,72.76 150.56,72.76 arc(150.81,72.51) 150.56,72.25 150.37,72.25 arc(150.18,72.16) 150.12,71.96 150.12,63.08 163.63,49.57 174.98,49.57 177.57,52.16 177.57,55.15 v3(177.98,55.56)
DDR3_C_WE_N_0: length 108.4
  TOP w0.127: U40.L3 v3(173.98,56.36) ; U28.L3 v3(173.98,86.84) ; U32.L3 v3(173.98,71.6) ; v2(149.89,87.12) P1.M1
  BOTTOM w0.127: v2(149.89,87.12) 150.44,86.57 150.44,82.46 160.12,72.78 160.12,72.12 arc(160.2,71.94) 160.38,71.86 160.6,71.86 arc(160.86,71.61) 160.6,71.36 160.38,71.36 arc(160.12,71.1) 160.38,70.85 160.6,70.85 arc(160.86,70.59) 160.6,70.34 160.38,70.34 arc(160.12,70.09) 160.38,69.83 160.6,69.83 arc(160.86,69.58) 160.6,69.32 160.38,69.32 arc(160.12,69.07) 160.38,68.82 160.6,68.82 arc(160.86,68.56) 160.6,68.31 160.38,68.31 arc(160.12,68.05) 160.38,67.8 160.6,67.8 arc(160.86,67.55) 160.6,67.29 160.38,67.29 arc(160.12,67.04) 160.38,66.78 160.6,66.78 arc(160.86,66.53) 160.6,66.28 160.38,66.28 arc(160.12,66.02) 160.38,65.77 160.6,65.77 arc(160.86,65.51) 160.6,65.26 160.38,65.26 arc(160.12,65.01) 160.38,64.75 160.6,64.75 arc(160.86,64.5) 160.6,64.24 160.38,64.24 arc(160.12,63.99) 160.38,63.74 160.6,63.74 arc(160.86,63.48) 160.6,63.23 160.38,63.23 arc(160.12,62.97) 160.38,62.72 160.6,62.72 arc(160.86,62.47) 160.6,62.21 160.38,62.21 arc(160.12,61.96) 160.38,61.7 160.6,61.7 arc(160.86,61.45) 160.6,61.2 160.32,61.2 arc(160.07,60.94) 160.32,60.69 160.6,60.69 arc(160.86,60.43) 160.6,60.18 160.32,60.18 arc(160.07,59.93) 160.32,59.67 160.6,59.67 arc(160.86,59.42) 160.6,59.16 160.38,59.16 arc(160.12,58.91) 160.38,58.66 160.6,58.66 arc(160.86,58.4) 160.6,58.15 160.38,58.15 arc(160.2,58.07) 160.12,57.89 160.12,57.47 163.68,53.91 172.97,53.91 173.58,54.52 173.58,55.96 v3(173.98,56.36) 173.58,56.75 173.58,71.2 v3(173.98,71.6) U32.L3 173.58,86.44 v3(173.98,86.84) 173.98,87.43 175.39,88.84 179.52,88.84 R445.2
DDR3A_N: length 22.9
  TOP w0.114: v1(133.47,65.37) 133.19,65.09 133.19,64.76 C247.2
  TOP w0.127: P1.E24 v2(126.89,80.12)
  06_SIG2 w0.102: v2(126.89,80.12) 127.09,80.12 127.2,80.02 127.2,79.72 127.42,79.5 128.05,79.5 128.3,79.26 128.3,75.26 128.25,75.22 128.25,75.2
  06_SIG2 w0.114: 128.25,75.2 128.25,67.58 131.42,64.41 132.99,64.41 133.29,64.71 133.29,65.19 v1(133.47,65.37)
DDR3A_P: length 23.1
  TOP w0.114: v1(132.59,65.37) 132.87,65.09 132.87,64.76 C246.2
  TOP w0.127: P1.E23 v2(127.89,80.12)
  06_SIG2 w0.102: v2(127.89,80.12) 127.53,80.12 127.42,80.02 127.42,79.82 127.51,79.73 128.14,79.73 128.52,79.35 128.52,75.25 128.57,75.2
  06_SIG2 w0.114: v1(132.59,65.37) 132.76,65.37 132.98,65.16 132.98,64.84 132.86,64.73 131.55,64.73 130.91,65.37 arc(130.84,65.53) 130.91,65.69 131.05,65.83 arc(131.05,66.15) 130.72,66.15 130.59,66.01 arc(130.43,65.95) 130.26,66.01 128.57,67.71 128.57,75.2
DDR3B_N: length 79.8
  TOP w0.114: C262.2 141.53,59.28 142.14,59.28 142.68,59.82 142.68,65.3 155.07,77.69 155.07,109.86 151.64,113.28 144.19,113.28 v1(143.89,113.58)
  TOP w0.127: P1.AK9 v2(142.89,106.12)
  BOTTOM w0.102: 143.23,109.39 143.23,109.36 143.28,109.32 143.28,105.84 143.18,105.74 142.99,105.74 142.89,105.84 v2(142.89,106.12)
  BOTTOM w0.114: v1(143.89,113.58) 143.59,113.28 143.27,113.28 142.97,112.98 142.97,110.58 143.23,110.32 143.23,109.39
DDR3B_P: length 79.8
  TOP w0.114: C259.2 141.53,59.59 142.01,59.59 142.37,59.95 142.37,61.82 arc(142.3,61.98) 142.14,62.05 142.1,62.05 arc(141.87,62.28) 142.1,62.5 142.14,62.5 arc(142.37,62.73) 142.14,62.96 142.1,62.96 arc(141.87,63.19) 142.1,63.42 142.14,63.42 arc(142.3,63.49) 142.37,63.65 142.37,65.43 154.75,77.82 154.75,109.73 151.51,112.97 144.19,112.97 v1(143.89,112.67)
  TOP w0.127: P1.AJ9 v2(142.89,105.12)
  BOTTOM w0.102: v2(142.89,105.12) 142.89,105.41 142.99,105.51 143.27,105.51 143.51,105.74 143.51,109.32 143.55,109.36 143.55,109.39
  BOTTOM w0.114: v1(143.89,112.67) 143.59,112.97 143.4,112.97 143.29,112.85 143.29,110.71 143.55,110.45 143.55,109.39
DDR3C_N: length 32.2
  TOP w0.102: v2(144.89,89.12) P1.P6
  TOP w0.114: v1(142.77,68.9) 142.47,68.6 142.47,67.67 141.1,66.29 138.87,66.29 137.76,65.18 137.76,64.76 C251.2
  BOTTOM w0.102: v2(144.89,89.12) 144.91,89.14 144.91,89.41 144.81,89.51 142.7,89.51 142.5,89.31 142.5,86.99 142.55,86.95 142.55,86.92
  BOTTOM w0.114: 142.55,86.92 142.55,86.53 142.47,86.46 142.47,69.2 v1(142.77,68.9)
DDR3C_P: length 32.4
  TOP w0.102: v2(144.89,90.12) P1.R6
  TOP w0.114: v1(141.86,68.9) 142.16,68.6 142.16,67.8 140.97,66.61 138.74,66.61 137.45,65.31 137.45,64.76 C250.2
  BOTTOM w0.102: v2(144.89,90.12) 144.5,89.74 142.61,89.74 142.27,89.4 142.27,86.99 142.23,86.95 142.23,86.92
  BOTTOM w0.114: v1(141.86,68.9) 142.16,69.2 142.16,86.59 142.23,86.67 142.23,86.92
DEM_D0: length 5.9
  BOTTOM w0.127: U59.53 30.88,144.7 30.74,144.84 27.89,144.84 R341.1 R342.1
DEM_D1: length 6.9
  BOTTOM w0.127: U59.54 31.52,145.2 29.21,147.51 28,147.51 R338.1 R339.1
ENSMB: length 6
  BOTTOM w0.127: U59.48 30.11,142.2 29.84,141.93 27.89,141.93 R350.1 R351.1
EQ_D0: length 4.8
  BOTTOM w0.127: R337.1 R340.1 42.97,144.7 U59.20
EQ_D1: length 6
  BOTTOM w0.127: U59.19 41.88,145.2 43.69,147.01 43.69,147.83 R336.1 R335.1
EQ_S0: length 6.6
  BOTTOM w0.127: U59.46 31.15,141.2 29.34,139.39 27.89,139.39 R371.1 R372.1
EQ_S1: length 6.3
  BOTTOM w0.127: U59.47 30.76,141.7 29.72,140.66 27.89,140.66 R368.1 R369.1
EQ_SEL/A0_1: length 4.2
  TOP w0.127: R66.2 R67.1 32.12,121.3 U19.21
EQ_SEL/A0_2: length 4.2
  TOP w0.127: R123.2 R124.1 32.12,93.36 U29.21
EQ_SEL/A0_3: length 4.2
  TOP w0.127: R200.2 R201.1 32.12,65.42 U37.21
EQ_SEL/A0_4: length 4.2
  TOP w0.127: U48.21 32.12,37.48 R263.1 R262.2
F_ARM_GPIO0: length 110.4
  TOP w0.127: v2(131.89,80.12) P1.E19 ; R696.1 v1(214.5,41.21)
  06_SIG2 w0.102: v2(131.89,80.12) 131.27,79.5 131.27,75.83 130.81,75.37 130.81,75.1
  06_SIG2 w0.127: 130.81,75.1 130.81,72.45 132.33,70.93 132.72,70.93 157.1,46.55 205.24,46.55 207.27,48.58 211.32,48.58 212.85,47.05 212.85,42.86 v1(214.5,41.21)
F_ARM_GPIO1: length 109.2
  TOP w0.127: R698.1 v1(215.67,41.21) ; v2(131.89,79.12) P1.D19
  06_SIG2 w0.102: v2(131.89,79.12) 131.51,78.74 131.51,75.82 131.85,75.48 131.85,75.1
  06_SIG2 w0.127: v1(215.67,41.21) 214,42.89 214,46.55 211.58,48.96 207.01,48.96 204.98,46.93 157.23,46.93 131.85,72.3 131.85,75.1
F_ARM_GPIO2: length 111.4
  TOP w0.127: R697.1 v1(216.84,41.21) ; v2(131.89,81.12) P1.F19
  06_SIG2 w0.102: 132.33,77.53 132.27,77.6 132.27,80.74 v2(131.89,81.12)
  06_SIG2 w0.127: v1(216.84,41.21) 215.14,42.91 215.14,46.04 211.86,49.32 206.73,49.32 204.72,47.31 157.35,47.31 132.33,72.33 132.33,77.53
F_ARM_SPI_CLK: length 105.9
  TOP w0.127: R693.1 v1(214.02,57.85) ; v2(132.89,81.12) P1.F18
  06_SIG2 w0.127: v1(214.02,57.85) 214.02,58.46 213.49,58.99 211.71,58.99 201.17,48.45 157.73,48.45 134.11,72.07 134.11,75.37 133.86,75.63 133.86,80.15 v2(132.89,81.12)
F_ARM_SPI_DI: length 110
  TOP w0.127: R694.1 211.73,58.25 212.09,58.61 212.98,58.61 v1(213.23,58.36) ; v2(132.89,83.12) P1.H19
  06_SIG2 w0.102: 132.72,77.66 132.51,77.87 132.51,82.74 v2(132.89,83.12)
  06_SIG2 w0.127: v1(213.23,58.36) 213.23,57.98 202.95,47.69 157.48,47.69 133.35,71.82 133.35,74.62 132.84,75.13 132.84,77.53 132.72,77.66
F_ARM_SPI_DO: length 103
  TOP w0.127: v1(212.34,57.98) 212.88,57.44 R695.1 ; v2(132.89,80.12) P1.E18
  06_SIG2 w0.127: v1(212.34,57.98) 202.44,48.07 157.61,48.07 133.73,71.95 133.73,74.99 133.35,75.37 133.35,79.66 v2(132.89,80.12)
F_ARM_SPI_NSS: length 107.7
  TOP w0.127: v2(132.89,82.11) 132.89,82.13 P1.G18 ; R691.1 v1(215.16,57.85)
  06_SIG2 w0.127: v2(132.89,82.11) 132.89,81.8 134.49,80.2 134.49,77.15 135.13,76.52 135.13,71.52 157.82,48.83 200.91,48.83 211.58,59.5 213.77,59.5 215.16,58.1 v1(215.16,57.85)
F_HM21_SCL: length 15.8
  TOP w0.102: P1.L18 v2(132.89,86.12)
  TOP w0.127: R187.1 135.5,72.97 v1(134.62,73.85)
  BOTTOM w0.127: v2(132.89,86.12) 133.73,85.28 133.73,74.74 v1(134.62,73.85)
F_HM21_SDA: length 14.5
  TOP w0.102: P1.K18 v2(132.89,85.12)
  TOP w0.127: R186.1 v1(134.61,72.83)
  BOTTOM w0.127: v1(134.61,72.83) 133.35,74.09 133.35,84.66 v2(132.89,85.12)
F_HM_TX_SCL1: length 6.2
  TOP w0.102: P1.B21 v2(130.89,77.12)
  TOP w0.127: v1(131.32,73.85) 131.95,73.22 R183.1
  BOTTOM w0.127: v1(131.32,73.85) 131.39,73.92 131.39,76.32 130.89,76.82 v2(130.89,77.12)
F_HM_TX_SCL2: length 10.4
  TOP w0.102: P1.D20 v2(130.89,80.12)
  TOP w0.127: v1(132.84,73.85) 133.73,72.97 R185.1
  BOTTOM w0.127: v1(132.84,73.85) 132.84,76.77 132.39,77.23 132.39,79.39 132.15,79.62 P1.D20 v2(130.89,80.12)
F_HM_TX_SCL3: length 13.9
  TOP w0.102: P1.F20 v2(130.89,82.12)
  TOP w0.127: v1(127.3,71.54) 127.42,71.54 R180.1
  BOTTOM w0.127: v2(130.89,82.12) 130.89,81.79 130.39,81.29 130.39,78.89 130.12,78.62 129.74,78.62 129.41,78.3 129.41,76.39 127.97,74.94 127.97,72.2 v1(127.3,71.54)
F_HM_TX_SCL4: length 19.8
  TOP w0.102: P1.L20 v2(130.89,86.12)
  TOP w0.127: v1(136.4,73.85) 137.28,72.97 R189.1
  BOTTOM w0.102: v2(130.89,86.12) 131.51,86.74 133.54,86.74 133.73,86.55
  BOTTOM w0.127: 133.73,86.55 134.44,85.84 134.44,80 135.25,79.18 135.25,74.99 v1(136.4,73.85)
F_HM_TX_SCL21: length 18.9
  TOP w0.102: P1.M18 v2(132.89,87.12)
  TOP w0.127: v1(138.18,72.83) 138.17,72.83 R190.1
  BOTTOM w0.127: v1(138.18,72.83) 136.4,74.61 136.4,81.6 135.38,82.61 135.38,86.3 135,86.68 134.24,86.68 133.79,87.12 v2(132.89,87.12)
F_HM_TX_SDA1: length 6.5
  TOP w0.102: P1.A21 v2(129.89,77.12)
  TOP w0.127: R182.1 131.06,72.58 v1(131.32,72.83)
  BOTTOM w0.127: v2(129.89,77.12) P1.A21 130.39,73.77 v1(131.32,72.83)
F_HM_TX_SDA2: length 8.7
  TOP w0.102: P1.C20 v2(130.89,79.12)
  TOP w0.127: R184.1 v1(132.84,72.83)
  BOTTOM w0.127: v2(130.89,79.12) P1.C20 131.39,76.96 131.7,76.64 131.95,76.64 132.33,76.26 132.33,73.33 v1(132.84,72.83)
F_HM_TX_SDA3: length 14.5
  TOP w0.102: P1.G20 v2(131.89,83.12)
  TOP w0.127: R179.1 126.56,72.4 v1(127,72.83)
  BOTTOM w0.127: v1(127,72.83) 127,74.54 129.08,76.62 129.08,78.6 129.39,78.9 129.39,81.19 129.79,81.6 130.02,81.6 130.39,81.96 130.39,82.29 130.72,82.62 P1.G20 v2(131.89,83.12)
F_HM_TX_SDA4: length 17.9
  TOP w0.102: P1.L19 v2(131.89,86.12)
  TOP w0.127: R188.1 v1(136.39,72.83)
  BOTTOM w0.102: 133.35,86.3 133.14,86.5 132.27,86.5 v2(131.89,86.12)
  BOTTOM w0.127: 133.35,86.3 134.09,85.56 134.09,79.72 134.87,78.93 134.87,74.35 v1(136.39,72.83)
F_HM_TX_SDA21: length 17.9
  TOP w0.102: P1.M17 v2(134.89,87.12)
  TOP w0.127: R191.1 139.06,72.97 v1(138.18,73.85)
  BOTTOM w0.127: v1(138.18,73.85) 136.78,75.25 136.78,81.85 136.4,82.23 136.4,86.25 136.02,86.62 135.69,86.62 135.19,87.12 v2(134.89,87.12)
F_NCS0: length 33.4
  TOP w0.102: P1.AN10 141.89,109.12 v2(141.89,110.12)
  06_SIG2 w0.127: v2(141.89,110.12) 141.89,114.95 143.96,117.02 143.96,129.17 v1(150.49,135.7)
  BOTTOM w0.127: v1(150.49,135.7) 150.5,135.7 151.64,136.84 R707.1
F_RX_5V_N: length 16.1
  TOP w0.102: P1.K21 v2(129.89,85.12)
  TOP w0.127: R192.1 125.68,72.4 v1(126.11,72.83)
  BOTTOM w0.127: v1(126.11,72.83) 126.11,74.16 128.39,76.43 128.39,80.82 129.39,81.82 129.39,82.28 129.73,82.62 130.05,82.62 130.39,82.96 130.39,84.62 v2(129.89,85.12)
F_RX_HPD_N: length 15.1
  TOP w0.102: P1.L21 v2(129.89,86.12)
  TOP w0.127: v1(130.3,72.83) 130.17,72.7 R181.1
  06_SIG2 w0.127: v2(129.89,86.12) 130.43,85.58 130.43,75.63 130.3,75.5 v1(130.3,72.83)
FCLT_GPIO0: length 190.2
  TOP w0.127: v2(135.89,80.12) 134.89,80.12 P1.E17 ; R711.1 243.59,136.85 218.19,111.44 218.19,67.12 v1(217.68,66.61)
  06_SIG2 w0.127: v1(217.68,66.61) 216.79,66.61 200.15,49.97 158.25,49.97 137.03,71.18 137.03,78.98 v2(135.89,80.12)
FCLT_GPIO1: length 193.3
  TOP w0.127: P1.H18 133.89,83.12 v2(134.89,83.12) ; R712.1 244.07,138.07 217.68,111.67 v1(217.68,67.63)
  06_SIG2 w0.127: v2(134.89,83.12) 137.41,80.6 137.41,71.31 158.37,50.36 200.03,50.36 217.3,67.63 v1(217.68,67.63)
FCLT_GPIO2: length 196.7
  TOP w0.102: P1.G21 v2(130.89,83.12)
  TOP w0.127: v1(217.68,64.58) 219.46,66.36 219.46,111.19 242.73,134.46 R713.1
  06_SIG2 w0.127: v2(130.89,83.12) 131.39,83.63 133.1,83.63 133.48,83.25 133.48,81.88 134.87,80.48 134.87,77.53 135.51,76.9 135.51,71.69 157.99,49.21 200.66,49.21 216.03,64.58 v1(217.68,64.58)
FCLT_GPIO3: length 191.8
  TOP w0.127: v1(217.68,65.6) 218.95,66.87 218.95,111.44 243.08,135.58 R714.1 ; P1.G17 v2(134.89,82.12)
  06_SIG2 w0.127: v2(134.89,82.12) 135.38,81.63 135.38,77.79 135.89,77.28 135.89,71.82 158.12,49.59 200.4,49.59 216.41,65.6 v1(217.68,65.6)
FCLT_GPIO4: length 191.3
  TOP w0.102: v2(134.87,84.14) 134.39,83.65 P1.H17
  TOP w0.127: v1(220.22,68.26) 220.6,68.64 220.6,110.86 241.88,132.14 R51.1
  03_SIG1 w0.102: 136.68,75.1 136.53,75.25 136.53,83.38 136.27,83.63 135.38,83.63 v2(134.87,84.14)
  03_SIG1 w0.127: v1(152.2,57.42) 149.02,57.42 137.41,69.02 137.41,74.36 136.68,75.1
  06_SIG2 w0.102: 178.56,50.74 158.88,50.74
  06_SIG2 w0.127: 178.56,50.74 199.77,50.74 217.3,68.26 v1(220.22,68.26) ; 158.88,50.74 v1(152.2,57.42)
FCLT_GPIO5: length 193.5
  TOP w0.102: P1.J17 134.39,84.67 v2(134.87,85.15)
  TOP w0.127: R47.1 242.26,133.29 220.08,111.1 220.08,69.04 v1(220.09,69.02)
  03_SIG1 w0.102: 137.44,75.1 137.03,75.5 137.03,84.26 136.78,84.52 135.51,84.52 v2(134.87,85.15)
  03_SIG1 w0.127: v1(151.49,58.23) 148.97,58.23 138.43,68.77 138.43,72.07 139.06,72.71 139.06,74.1 138.3,74.87 137.67,74.87 137.44,75.1
  06_SIG2 w0.102: 163.45,51.12 163.58,50.99 178.18,50.99 178.31,51.12 178.56,51.12
  06_SIG2 w0.127: v1(220.09,69.02) 217.42,69.02 199.52,51.12 178.56,51.12 ; 163.45,51.12 159,51.12 153.69,56.43 153.69,56.81 152.27,58.23 v1(151.49,58.23)
FCLT_GPIO6: length 199.6
  TOP w0.102: P1.D22 129.34,79.62 128.91,79.18 128.91,75.88 v2(129.29,75.5)
  TOP w0.127: v1(221.79,70.37) 221.74,70.42 221.74,110.43 241.17,129.86 R54.1
  06_SIG2 w0.127: v1(135.74,66.81) 136.19,66.81 156.84,46.16 205.61,46.16 v1(206.12,46.67)
  BOTTOM w0.102: 128.88,75.1 v2(129.29,75.5)
  BOTTOM w0.127: v1(135.74,66.81) 134.98,66.81 128.63,73.16 128.63,74.84 128.88,75.1 ; v1(206.12,46.67) 206.12,57.59 218.9,70.37 v1(221.79,70.37)
FCLT_GPIO7: length 198.6
  TOP w0.102: P1.M21 130.49,87.62 v2(130.94,88.07)
  TOP w0.127: R53.1 241.5,131 221.18,110.68 v1(221.18,69.79)
  03_SIG1 w0.102: v2(130.94,88.07) 131.19,88.07 131.57,87.69 137.03,87.69 137.41,87.31 137.41,75.63 137.67,75.37 138.56,75.37 138.84,75.1
  03_SIG1 w0.127: v1(150.93,58.89) 150.77,58.74 149.35,58.74 139.06,69.03 139.06,71.81 139.57,72.33 139.57,74.36 138.84,75.1
  06_SIG2 w0.102: 163.45,51.5 163.7,51.24 177.67,51.24 177.93,51.5 178.56,51.5
  06_SIG2 w0.127: 178.56,51.5 199.14,51.5 217.42,69.79 v1(221.18,69.79) ; v1(150.93,58.89) 151.13,59.09 151.92,59.09 154.05,56.96 154.05,56.58 159.13,51.5 163.45,51.5
HD_SCL1: length 14
  TOP w0.127: R107.2 30.55,104.33 32.44,104.33 R98.2 36.9,106.11 38.89,106.11 R104.1 39.72,106.94 U21.6
HD_SCL2: length 14
  TOP w0.127: R173.2 30.55,76.39 32.44,76.39 R165.2 36.9,78.17 38.89,78.17 R171.1 39.72,79 U31.6
HD_SCL3: length 14
  TOP w0.127: U42.6 39.72,51.06 R241.1 38.89,50.23 36.9,50.23 R234.2 32.44,48.45 30.55,48.45 R243.2
HD_SCL4: length 14
  TOP w0.127: U55.6 39.72,23.12 R299.1 38.89,22.29 36.9,22.29 R294.2 32.44,20.51 30.55,20.51 R301.2
HD_SDA1: length 11.9
  TOP w0.127: v1(36.26,108.01) 36.39,108.01 R99.2 37.03,107.38 38.92,107.38 R100.1 39.98,107.59 U21.5 ; v1(31.81,105.73) 31.68,105.73 R108.2
  BOTTOM w0.127: v1(31.81,105.73) 33.97,105.73 v1(36.26,108.01)
HD_SDA2: length 11.9
  TOP w0.127: v1(36.26,80.07) 36.39,80.07 R166.2 37.03,79.44 38.92,79.44 R167.1 39.98,79.65 U31.5 ; v1(31.81,77.79) 31.68,77.79 R174.2
  BOTTOM w0.127: v1(36.26,80.07) 33.97,77.79 v1(31.81,77.79)
HD_SDA3: length 11.9
  TOP w0.127: R244.2 31.68,49.85 v1(31.81,49.85) ; v1(36.26,52.13) 36.39,52.13 R235.2 37.03,51.5 38.92,51.5 R236.1 39.98,51.71 U42.5
  BOTTOM w0.127: v1(36.26,52.13) 33.97,49.85 v1(31.81,49.85)
HD_SDA4: length 11.9
  TOP w0.127: v1(36.26,24.19) 36.39,24.19 R295.2 37.03,23.56 38.92,23.56 R296.1 39.98,23.77 U55.5 ; R302.2 31.68,21.91 v1(31.81,21.91)
  BOTTOM w0.127: v1(36.26,24.19) 33.97,21.91 v1(31.81,21.91)
HDMI20_RX_RCK+: length 73.9
  TOP w0.114: v1(48.92,126.83) 48.92,127.28 48.67,127.52 44.2,132 v1(43.75,132)
  BOTTOM w0.114: v1(48.92,126.83) 49.36,126.83 50.05,126.14 arc(50.19,125.94) 50.23,125.71 50.23,123.88 arc(50.55,123.1) 51.32,122.78 54.82,122.78 arc(55.24,122.61) 55.41,122.19 55.41,122.02 arc(55.24,121.6) 54.81,121.42 51.42,121.42 arc(50.73,121.14) 50.44,120.45 50.44,119.94 arc(50.71,119.3) 51.34,119.04 60.68,119.04 arc(62.53,118.67) 64.1,117.62 80.66,101.06 arc(81.08,100.78) 81.57,100.69 81.75,100.69 C428.1 ; v1(43.75,132) 43.75,132.45 39.98,136.21 arc(39.56,136.84) 39.42,137.58 39.42,140.26 39.33,140.35 U59.31
HDMI20_RX_RCK-: length 73.4
  TOP w0.114: v1(49.59,127.5) 49.14,127.5 44.42,132.22 v1(44.42,132.67)
  BOTTOM w0.114: v1(49.59,127.5) 49.59,127.05 50.28,126.37 arc(50.48,126.07) 50.55,125.71 50.55,123.88 arc(50.78,123.33) 51.32,123.1 54.82,123.1 arc(55.46,122.83) 55.73,122.19 55.73,122.02 arc(55.46,121.38) 54.81,121.11 51.42,121.11 arc(50.95,120.92) 50.76,120.45 50.76,119.94 arc(50.93,119.52) 51.34,119.35 60.68,119.35 arc(62.66,118.96) 64.33,117.84 80.89,101.29 arc(81.2,101.08) 81.57,101 81.76,101 C426.1 ; U59.30 39.83,140.35 39.73,140.26 39.73,137.58 arc(39.86,136.96) 40.21,136.44 43.97,132.67 v1(44.42,132.67)
HDMI21_RX+: length 3
  TOP w0.114: U39.22 132.96,58.36 132.87,58.45 132.04,58.45 131.98,58.52 130.99,58.52 C264.1
HDMI21_RX-: length 3
  TOP w0.114: U39.21 132.96,58.86 132.87,58.77 132.18,58.77 132.11,58.83 130.99,58.83 C261.1
HDMI21_RX_RCK+: length 95.9
  TOP w0.114: v1(127.77,57.85) 127.46,58.17 127.46,58.4 127.57,58.52 129.11,58.52 C264.2 ; v2(122.89,102.12) P1.AF28
  06_SIG2 w0.114: v1(92.96,101.64) 92.65,101.32 92.65,96.39 127.46,61.58 127.46,58.17 v1(127.77,57.85)
  BOTTOM w0.102: 121.63,101.78 121.66,101.78 121.7,101.73 123.37,101.73 123.48,101.84 123.48,102.02 123.37,102.12 v2(122.89,102.12)
  BOTTOM w0.114: v1(92.96,101.64) 92.65,101.32 92.65,101.08 92.76,100.97 118.32,100.97 arc(118.47,101.03) 118.53,101.17 arc(118.59,101.34) 118.76,101.4 arc(118.92,101.34) 118.98,101.17 arc(119.05,101.03) 119.19,100.97 119.23,100.97 arc(119.38,101.03) 119.44,101.17 arc(119.67,101.4) 119.9,101.17 arc(119.96,101.03) 120.11,100.97 120.46,100.97 121.27,101.78 121.63,101.78
HDMI21_RX_RCK-: length 95.9
  TOP w0.114: v1(126.82,57.85) 127.14,58.17 127.14,58.53 127.44,58.83 129.11,58.83 C261.2 ; v2(123.89,102.12) P1.AF27
  06_SIG2 w0.114: v1(92.01,101.64) 92.33,101.32 92.33,96.26 127.14,61.45 127.14,58.17 v1(126.82,57.85)
  BOTTOM w0.102: 121.63,101.46 121.66,101.46 121.7,101.5 123.46,101.5 123.7,101.75 123.7,102.02 123.81,102.12 v2(123.89,102.12)
  BOTTOM w0.114: 121.63,101.46 121.4,101.46 120.59,100.65 92.63,100.65 92.33,100.95 92.33,101.32 v1(92.01,101.64)
HDMI_1_TCX+: length 20.9
  TOP w0.114: U19.26 29.31,117.75 29.22,117.84 27.44,117.84 27.27,118.01 21.63,118.01 R82.2 20.42,118.01 19.46,118.01 19.37,118.11 17.05,118.11 16.96,118.02 U17.4 U17.7 15.62,118.02 15.53,118.11 12.96,118.11 12.72,117.87 11.79,117.87 11.45,117.53 J6.10
HDMI_1_TCX-: length 20.9
  TOP w0.114: J6.12 11.43,118.53 11.77,118.19 12.59,118.19 12.83,118.43 15.54,118.43 15.63,118.52 U17.6 U17.5 16.98,118.52 17.07,118.43 19.5,118.43 19.59,118.33 20.42,118.33 R80.2 21.63,118.33 27.4,118.33 27.57,118.16 29.23,118.16 29.33,118.25 U19.25
HDMI_1_TX0+: length 20.8
  TOP w0.114: J6.7 11.45,116.03 11.79,116.37 12.93,116.37 13.17,116.61 15.53,116.61 15.63,116.52 U17.10 U17.1 16.99,116.52 17.08,116.61 19.73,116.61 19.97,116.36 23.35,116.36 R84.2 24.53,116.34 29.25,116.34 29.34,116.25 U19.29
HDMI_1_TX0-: length 20.9
  TOP w0.114: U19.28 29.35,116.75 29.26,116.66 24.57,116.66 R83.2 23.35,116.68 20.1,116.68 19.86,116.93 17.07,116.93 16.98,117.02 U17.2 U17.9 15.61,117.02 15.52,116.93 13.04,116.93 12.8,116.69 11.77,116.69 11.43,117.03 J6.9
HDMI_1_TX1+: length 20.8
  TOP w0.114: J6.4 11.45,114.53 11.79,114.87 12.82,114.87 13.02,114.68 15.53,114.68 15.62,114.59 U20.7 U20.4 16.99,114.59 17.08,114.68 20.46,114.68 R86.2 21.63,114.71 27.09,114.71 27.22,114.84 29.23,114.84 29.32,114.75 U19.32
HDMI_1_TX1-: length 20.8
  TOP w0.114: U19.31 29.32,115.25 29.23,115.16 27.09,115.16 26.96,115.03 21.63,115.03 R85.2 20.39,115 17.07,115 16.98,115.09 U20.5 U20.6 15.63,115.09 15.54,115 13.15,115 12.96,115.19 11.79,115.19 11.45,115.53 J6.6
HDMI_1_TX2+: length 20.9
  TOP w0.114: U19.35 29.32,113.25 29.23,113.34 27.62,113.34 27.34,113.06 24.55,113.06 R88.2 23.35,113.06 19.78,113.06 19.66,113.18 17.05,113.18 16.96,113.09 U20.1 U20.10 15.63,113.09 15.53,113.18 12.8,113.18 12.6,113.37 11.76,113.37 11.42,113.03 J6.1
HDMI_1_TX2-: length 20.9
  TOP w0.114: J6.3 11.43,114.03 11.77,113.69 12.74,113.69 12.93,113.5 15.52,113.5 15.61,113.59 U20.9 U20.2 16.98,113.59 17.07,113.5 19.79,113.5 19.91,113.38 23.35,113.38 R87.2 24.55,113.38 27.21,113.38 27.49,113.66 29.23,113.66 29.32,113.75 U19.34
HDMI_2_TCX+: length 20.9
  TOP w0.114: U29.26 29.31,89.81 29.22,89.9 27.41,89.9 27.24,90.07 21.63,90.07 R144.2 20.42,90.07 18.7,90.07 18.61,90.17 17.05,90.17 16.96,90.08 U27.4 U27.7 15.62,90.08 15.53,90.17 12.89,90.17 12.66,89.93 11.79,89.93 11.45,89.59 J8.10
HDMI_2_TCX-: length 20.9
  TOP w0.114: U29.25 29.33,90.31 29.23,90.22 27.55,90.22 27.37,90.39 21.63,90.39 R142.2 20.42,90.39 18.83,90.39 18.74,90.49 17.07,90.49 16.98,90.58 U27.5 U27.6 15.63,90.58 15.54,90.49 12.76,90.49 12.52,90.25 11.79,90.25 11.45,90.59 J8.12
HDMI_2_TX0+: length 20.8
  TOP w0.114: J8.7 11.45,88.09 11.79,88.43 13.57,88.43 13.8,88.67 15.21,88.67 15.3,88.58 U27.10 U27.1 16.99,88.58 17.08,88.67 18.96,88.67 19.21,88.42 23.35,88.42 R149.2 24.53,88.4 29.22,88.4 29.32,88.31 U29.29
HDMI_2_TX0-: length 20.9
  TOP w0.114: U29.28 29.32,88.81 29.23,88.72 24.57,88.72 R146.2 23.35,88.74 19.34,88.74 19.1,88.99 17.07,88.99 16.98,89.08 U27.2 U27.9 15.3,89.08 15.21,88.99 13.67,88.99 13.44,88.75 11.77,88.75 11.43,89.09 J8.9
HDMI_2_TX1+: length 20.8
  TOP w0.114: U29.32 29.32,86.81 29.23,86.9 27.22,86.9 27.09,86.77 21.63,86.77 R153.2 20.46,86.74 17.08,86.74 16.99,86.65 U30.4 U30.7 15.62,86.65 15.53,86.74 13.2,86.74 13.01,86.93 11.79,86.93 11.45,86.59 J8.4
HDMI_2_TX1-: length 20.8
  TOP w0.114: U29.31 29.32,87.31 29.23,87.22 27.09,87.22 26.96,87.09 21.63,87.09 R150.2 20.39,87.06 17.07,87.06 16.98,87.15 U30.5 U30.6 15.63,87.15 15.54,87.06 13.34,87.06 13.14,87.25 11.79,87.25 11.45,87.59 J8.6
HDMI_2_TX2+: length 21.4
  TOP w0.114: 16.96,85.15 U30.1 U30.10 15.63,85.15 15.53,85.24 12.8,85.24 12.6,85.43 11.76,85.43 11.42,85.09 J8.1 ; 16.96,85.15 17.3,85.15 17.39,85.24 ; 16.96,85.15 17.05,85.24 17.39,85.24 ; 17.39,85.24 18.9,85.24 19.01,85.12 23.35,85.12 R158.2 24.55,85.12 27.34,85.12 27.62,85.4 29.23,85.4 29.32,85.31 U29.35
HDMI_2_TX2-: length 21.3
  TOP w0.114: 16.98,85.65 U30.2 U30.9 15.61,85.65 15.52,85.56 12.93,85.56 12.74,85.75 11.77,85.75 11.43,86.09 J8.3 ; 16.98,85.65 17.07,85.56 17.39,85.56 ; 16.98,85.65 17.3,85.65 17.39,85.56 ; 17.39,85.56 19.03,85.56 19.15,85.44 23.35,85.44 R155.2 24.55,85.44 27.21,85.44 27.49,85.72 29.23,85.72 29.32,85.81 U29.34
HDMI_3_TCX+: length 20.9
  TOP w0.114: J10.10 11.58,61.65 11.92,61.99 12.83,61.99 13.07,62.23 15.53,62.23 15.62,62.14 U36.7 U36.4 16.96,62.14 17.05,62.23 19.37,62.23 19.46,62.13 20.42,62.13 R214.2 21.63,62.13 27.24,62.13 27.41,61.96 29.22,61.96 29.31,61.87 U37.26
HDMI_3_TCX-: length 20.9
  TOP w0.114: J10.12 11.58,62.65 11.92,62.31 12.7,62.31 12.93,62.55 15.54,62.55 15.63,62.64 U36.6 U36.5 16.98,62.64 17.07,62.55 19.5,62.55 19.59,62.45 20.42,62.45 R213.2 21.63,62.45 27.37,62.45 27.55,62.28 29.23,62.28 29.33,62.37 U37.25
HDMI_3_TX0+: length 20.8
  TOP w0.114: U37.29 29.32,60.37 29.22,60.46 24.53,60.46 R217.2 23.35,60.48 19.97,60.48 19.73,60.73 17.08,60.73 16.99,60.64 U36.1 U36.10 15.63,60.64 15.53,60.73 13.8,60.73 13.57,60.49 11.79,60.49 11.45,60.15 J10.7
HDMI_3_TX0-: length 20.9
  TOP w0.114: J10.9 11.43,61.15 11.77,60.81 13.44,60.81 13.67,61.05 15.52,61.05 15.61,61.14 U36.9 U36.2 16.98,61.14 17.07,61.05 19.86,61.05 20.1,60.8 23.35,60.8 R215.2 24.57,60.78 29.23,60.78 29.32,60.87 U37.28
HDMI_3_TX1+: length 20.8
  TOP w0.114: U37.32 29.32,58.87 29.23,58.96 27.09,58.96 26.96,58.83 21.63,58.83 R219.2 20.46,58.8 17.08,58.8 16.99,58.71 U41.4 U41.7 15.62,58.71 15.53,58.8 13.65,58.8 13.46,58.99 11.79,58.99 11.45,58.65 J10.4
HDMI_3_TX1-: length 20.8
  TOP w0.114: U37.31 29.32,59.37 29.23,59.28 26.96,59.28 26.83,59.15 21.63,59.15 R218.2 20.39,59.12 17.07,59.12 16.98,59.21 U41.5 U41.6 15.63,59.21 15.54,59.12 13.79,59.12 13.59,59.31 11.79,59.31 11.45,59.65 J10.6
HDMI_3_TX2+: length 20.9
  TOP w0.114: J10.1 11.42,57.15 11.76,57.49 12.6,57.49 12.8,57.3 15.53,57.3 15.63,57.21 U41.10 U41.1 16.96,57.21 17.05,57.3 19.66,57.3 19.78,57.18 23.35,57.18 R223.2 24.55,57.18 27.34,57.18 27.62,57.46 29.23,57.46 29.32,57.37 U37.35
HDMI_3_TX2-: length 20.9
  TOP w0.114: U37.34 29.32,57.87 29.23,57.78 27.49,57.78 27.21,57.5 24.55,57.5 R220.2 23.35,57.5 19.91,57.5 19.79,57.62 17.07,57.62 16.98,57.71 U41.2 U41.9 15.61,57.71 15.52,57.62 12.93,57.62 12.74,57.81 11.77,57.81 11.43,58.15 J10.3
HDMI_4_TCX+: length 20.9
  TOP w0.114: J14.10 11.45,33.71 11.79,34.05 12.72,34.05 12.96,34.29 15.53,34.29 15.62,34.2 U47.7 U47.4 16.96,34.2 17.05,34.29 19.37,34.29 19.46,34.19 20.42,34.19 R276.2 21.63,34.19 27.24,34.19 27.41,34.02 29.22,34.02 29.31,33.93 U48.26
HDMI_4_TCX-: length 20.9
  TOP w0.114: U48.25 29.3,34.43 29.21,34.34 27.55,34.34 27.37,34.51 21.63,34.51 R275.2 20.42,34.51 19.59,34.51 19.5,34.61 17.07,34.61 16.98,34.7 U47.5 U47.6 15.63,34.7 15.54,34.61 12.83,34.61 12.59,34.37 11.77,34.37 11.43,34.71 J14.12
HDMI_4_TX0+: length 20.8
  TOP w0.114: J14.7 11.58,32.21 11.92,32.55 13.82,32.55 14.06,32.79 15.21,32.79 15.3,32.7 U47.10 U47.1 16.99,32.7 17.08,32.79 19.73,32.79 19.97,32.54 23.35,32.54 R278.2 24.53,32.52 29.22,32.52 29.32,32.43 U48.29
HDMI_4_TX0-: length 20.9
  TOP w0.114: J14.9 11.58,33.21 11.92,32.87 13.69,32.87 13.92,33.11 15.21,33.11 15.3,33.2 U47.9 U47.2 16.98,33.2 17.07,33.11 19.86,33.11 20.1,32.86 23.35,32.86 R277.2 24.57,32.84 29.23,32.84 29.32,32.93 U48.28
HDMI_4_TX1+: length 20.8
  TOP w0.114: J14.4 11.58,30.71 11.92,31.05 13.71,31.05 13.91,30.86 15.21,30.86 15.3,30.77 U49.7 U49.4 16.99,30.77 17.08,30.86 20.46,30.86 R280.2 21.63,30.89 27.09,30.89 27.22,31.02 29.23,31.02 29.32,30.93 U48.32
HDMI_4_TX1-: length 20.8
  TOP w0.114: U48.31 29.32,31.43 29.23,31.34 27.09,31.34 26.96,31.21 21.63,31.21 R279.2 20.39,31.18 17.07,31.18 16.98,31.27 U49.5 U49.6 15.3,31.27 15.21,31.18 14.04,31.18 13.84,31.37 11.92,31.37 11.58,31.71 J14.6
HDMI_4_TX2+: length 20.9
  TOP w0.114: J14.1 11.42,29.21 11.76,29.55 12.6,29.55 12.8,29.36 15.53,29.36 15.63,29.27 U49.10 U49.1 16.96,29.27 17.05,29.36 19.66,29.36 19.78,29.24 23.35,29.24 R282.2 24.55,29.24 27.34,29.24 27.62,29.52 29.23,29.52 29.32,29.43 U48.35
HDMI_4_TX2-: length 20.9
  TOP w0.114: J14.3 11.43,30.21 11.77,29.87 12.74,29.87 12.93,29.68 15.52,29.68 15.61,29.77 U49.9 U49.2 16.98,29.77 17.07,29.68 19.79,29.68 19.91,29.56 23.35,29.56 R281.2 24.55,29.56 27.21,29.56 27.49,29.84 29.23,29.84 29.32,29.93 U48.34
HDMI_HPD_21: length 18
  TOP w0.127: v1(12.19,150.56) 11.61,149.97 HDMI1.19 ; Q2.3 23.1,154.87 R8.2 23.05,154.3 21.59,152.84 21.34,152.84 19.47,150.98 17.87,150.98 17.59,151.25 U3.4 U3.7 14.66,151.25 13.61,150.2 v1(13.61,150.13)
  BOTTOM w0.127: v1(12.19,150.56) 13.18,150.56 v1(13.61,150.13)
HDMI_HPD_IN1: length 30.7
  TOP w0.127: Q3.3 24.04,121.04 R77.2 v1(25.94,121.04)
  06_SIG2 w0.127: v1(39.43,113.42) 38.73,114.12 38.73,119.82 37.52,121.04 v1(25.94,121.04)
  BOTTOM w0.127: R386.2 39.43,113.48 v1(39.43,113.42) ; R385.2 26.49,115.13 25.78,115.13 25.4,115.51 25.4,120.49 v1(25.94,121.04)
HDMI_HPD_IN2: length 30.7
  TOP w0.127: v1(25.94,93.1) R137.2 24.7,93.1 24.26,93.53 Q4.3
  06_SIG2 w0.127: v1(39.43,85.48) 38.86,86.06 38.86,91.63 37.4,93.1 v1(25.94,93.1)
  BOTTOM w0.127: R446.2 39.43,85.54 v1(39.43,85.48) ; v1(25.94,93.1) 25.4,92.55 25.4,87.57 25.78,87.19 26.49,87.19 R444.2
HDMI_HPD_IN3: length 30.6
  TOP w0.127: v1(25.94,65.16) R210.2 24.04,65.16 Q5.3
  06_SIG2 w0.127: v1(25.94,65.16) 37.27,65.16 38.73,63.69 38.73,58.24 v1(39.43,57.54)
  BOTTOM w0.127: R466.2 26.49,59.25 25.78,59.25 25.4,59.63 25.4,64.61 v1(25.94,65.16) ; v1(39.43,57.54) 39.43,57.6 R467.2
HDMI_HPD_IN4: length 30.7
  TOP w0.127: Q6.3 24.68,37.65 R273.2 v1(25.94,37.22)
  06_SIG2 w0.127: v1(39.43,29.6) 38.73,30.3 38.73,36 37.52,37.22 v1(25.94,37.22)
  BOTTOM w0.127: R480.2 39.43,29.66 v1(39.43,29.6) ; R479.2 26.49,31.31 25.78,31.31 25.4,31.69 25.4,36.67 v1(25.94,37.22)
HDMI_RX0N: length 37.1
  TOP w0.114: HDMI1.3 11.43,141.97 11.77,141.63 13,141.63 arc(13.29,141.57) 13.54,141.41 13.68,141.26 arc(13.87,141.14) 14.08,141.1 15.5,141.1 15.55,141.15 U7.9 U7.2 16.9,141.15 17.02,141.03 17.27,141.03 arc(17.92,140.9) 18.47,140.54 18.49,140.52 arc(18.86,139.97) 18.99,139.32 18.99,139.13 arc(19.08,138.66) 19.34,138.27 19.44,138.17 arc(19.72,137.99) 20.04,137.92 22.47,137.92 arc(22.75,138.04) 22.86,138.31 22.86,138.69 arc(22.92,139) 23.09,139.26 arc(23.69,139.5) 24.28,139.26 arc(24.45,139) 24.51,138.69 24.51,138.24 arc(24.6,138.01) 24.83,137.92 25.83,137.92 arc(26.29,137.73) 26.48,137.27 26.48,136.97 arc(26.59,136.7) 26.86,136.59 28.02,136.59 arc(28.55,136.37) 28.77,135.85 28.77,134.94 arc(28.84,134.76) 29.02,134.68 29.9,134.68 R25.2 30.74,134.75 34.49,134.75 arc(35.02,134.53) 35.24,134 35.24,133.84 arc(35.26,133.74) 35.32,133.66 35.33,133.64 v1(35.54,133.64)
  BOTTOM w0.114: v1(35.54,133.64) 35.22,133.96 35.22,136.55 35.64,136.96 C398.1
HDMI_RX0P: length 37.1
  TOP w0.114: HDMI1.1 11.45,140.97 11.79,141.31 13,141.31 arc(13.17,141.28) 13.31,141.18 13.46,141.04 arc(13.74,140.85) 14.08,140.78 15.49,140.78 15.63,140.65 U7.10 U7.1 16.89,140.65 16.95,140.72 17.27,140.72 arc(17.8,140.61) 18.25,140.31 18.26,140.3 arc(18.56,139.85) 18.67,139.32 18.67,139.13 arc(18.79,138.54) 19.12,138.04 19.21,137.95 arc(19.6,137.69) 20.04,137.6 22.47,137.6 arc(22.97,137.81) 23.18,138.31 23.18,138.69 arc(23.21,138.88) 23.32,139.03 arc(23.69,139.18) 24.05,139.03 arc(24.16,138.88) 24.19,138.69 24.19,138.24 arc(24.38,137.79) 24.83,137.6 25.83,137.6 arc(26.06,137.51) 26.16,137.27 26.16,136.97 arc(26.37,136.48) 26.86,136.27 28.02,136.27 arc(28.32,136.15) 28.45,135.85 28.45,134.94 arc(28.62,134.53) 29.02,134.37 29.96,134.37 R39.2 30.81,134.43 33.55,134.43 arc(33.68,134.37) 33.74,134.24 arc(33.8,134.1) 33.93,134.05 34.01,134.05 arc(34.14,134.1) 34.2,134.24 arc(34.25,134.37) 34.39,134.43 34.49,134.43 arc(34.8,134.3) 34.92,134 34.92,133.84 arc(34.92,133.8) 34.89,133.76 34.77,133.64 v1(34.59,133.64)
  BOTTOM w0.114: C399.1 34.49,136.96 34.91,136.55 34.91,133.96 v1(34.59,133.64)
HDMI_RX1N: length 36.9
  TOP w0.114: v1(33.05,135.71) 32.77,135.99 32.77,137.01 arc(32.52,137.61) 31.92,137.86 28.88,137.86 arc(28.72,137.89) 28.58,137.98 27.66,138.9 arc(27.41,139.07) 27.1,139.13 25.72,139.13 arc(25.49,139.22) 25.4,139.45 25.4,140.21 arc(25.47,140.39) 25.65,140.46 27.66,140.46 arc(27.95,140.52) 28.19,140.68 arc(28.48,141.37) 28.19,142.05 arc(27.84,142.29) 27.43,142.37 25.99,142.37 arc(25.56,142.28) 25.19,142.04 24.45,141.29 arc(24.09,141.05) 23.67,140.97 21.6,140.97 R21.2 20.76,140.91 20.45,140.91 arc(20.28,140.94) 20.13,141.04 19.06,142.1 arc(18.56,142.44) 17.97,142.56 17.02,142.56 16.93,142.65 U7.5 U7.6 15.58,142.65 15.49,142.56 14.64,142.56 arc(14.44,142.6) 14.27,142.71 14.08,142.9 arc(13.82,143.07) 13.51,143.13 11.77,143.13 11.43,143.47 HDMI1.6
  BOTTOM w0.114: v1(33.05,135.71) 32.83,135.93 32.83,136.64 33.15,136.96 C400.1
HDMI_RX1P: length 36.9
  TOP w0.114: HDMI1.4 11.42,142.47 11.76,142.81 13.51,142.81 arc(13.7,142.78) 13.86,142.67 14.04,142.49 arc(14.31,142.3) 14.64,142.24 15.53,142.24 15.62,142.15 U7.7 U7.4 16.99,142.15 17.08,142.24 17.97,142.24 arc(18.44,142.15) 18.84,141.88 19.9,140.81 arc(20.15,140.65) 20.45,140.59 20.82,140.59 R24.2 21.66,140.65 23.67,140.65 arc(24.21,140.76) 24.67,141.07 25.42,141.81 arc(25.68,141.99) 25.99,142.05 27.43,142.05 arc(27.72,141.99) 27.97,141.83 arc(28.16,141.37) 27.97,140.91 arc(27.83,140.81) 27.66,140.78 25.65,140.78 arc(25.25,140.61) 25.08,140.21 25.08,139.45 arc(25.27,139) 25.72,138.81 27.1,138.81 arc(27.29,138.77) 27.44,138.67 28.35,137.76 arc(28.59,137.6) 28.88,137.54 31.92,137.54 arc(32.29,137.39) 32.45,137.01 32.45,135.82 32.33,135.71 v1(32.1,135.71)
  BOTTOM w0.114: v1(32.1,135.71) 32.32,135.71 32.51,135.9 32.51,136.45 32,136.96 C401.1
HDMI_RX2N: length 37.6
  TOP w0.114: v1(37.52,150.46) 37.21,150.77 37.21,151.38 arc(36.99,151.92) 36.45,152.15 36.03,152.15 arc(35.36,152.01) 34.78,151.63 31.12,147.97 arc(30.9,147.82) 30.64,147.76 28.46,147.76 arc(27.99,147.57) 27.8,147.1 27.8,146.84 arc(27.71,146.64) 27.51,146.56 27.46,146.56 arc(27.21,146.66) 27.11,146.9 27.11,147.1 arc(26.92,147.57) 26.45,147.76 26.03,147.76 arc(25.41,147.5) 25.15,146.88 25.15,145.35 arc(24.89,144.72) 24.26,144.46 23.62,144.46 R18.2 22.74,144.34 19.28,144.34 arc(18.95,144.4) 18.67,144.59 18.15,145.11 arc(17.74,145.38) 17.25,145.48 17.14,145.48 17.03,145.59 U4.2 U4.9 15.55,145.59 15.42,145.47 14.73,145.47 14.72,145.47 arc(14.31,145.39) 13.96,145.16 13.66,144.86 arc(13.41,144.69) 13.12,144.63 11.77,144.63 11.43,144.97 HDMI1.9
  BOTTOM w0.114: v1(37.52,150.46) 37.2,150.13 37.2,149.45 37.59,149.06 C392.1
HDMI_RX2P: length 37.5
  TOP w0.114: v1(36.57,150.46) 36.73,150.46 36.89,150.62 36.89,151.38 arc(36.76,151.7) 36.45,151.83 36.03,151.83 arc(35.48,151.72) 35.01,151.4 31.35,147.74 arc(31.02,147.52) 30.64,147.45 28.46,147.45 arc(28.22,147.35) 28.12,147.1 28.12,146.84 arc(27.94,146.42) 27.51,146.24 27.46,146.24 arc(26.99,146.43) 26.79,146.9 26.79,147.1 arc(26.69,147.35) 26.45,147.45 26.03,147.45 arc(25.63,147.28) 25.46,146.88 25.46,145.35 arc(25.11,144.5) 24.26,144.15 23.73,144.15 R20.2 22.88,144.02 22.69,144.02 arc(22.58,143.97) 22.53,143.86 arc(22.49,143.75) 22.37,143.7 22.01,143.7 arc(21.89,143.75) 21.85,143.86 arc(21.8,143.97) 21.69,144.02 19.24,144.02 arc(18.83,144.1) 18.48,144.33 17.93,144.88 arc(17.62,145.09) 17.25,145.16 17.08,145.16 17.01,145.09 U4.1 U4.10 15.63,145.09 15.56,145.16 14.72,145.16 arc(14.43,145.1) 14.19,144.93 13.89,144.63 arc(13.53,144.4) 13.12,144.31 11.79,144.31 11.45,143.97 HDMI1.7
  BOTTOM w0.114: v1(36.57,150.46) 36.88,150.15 36.88,149.49 36.45,149.06 C393.1
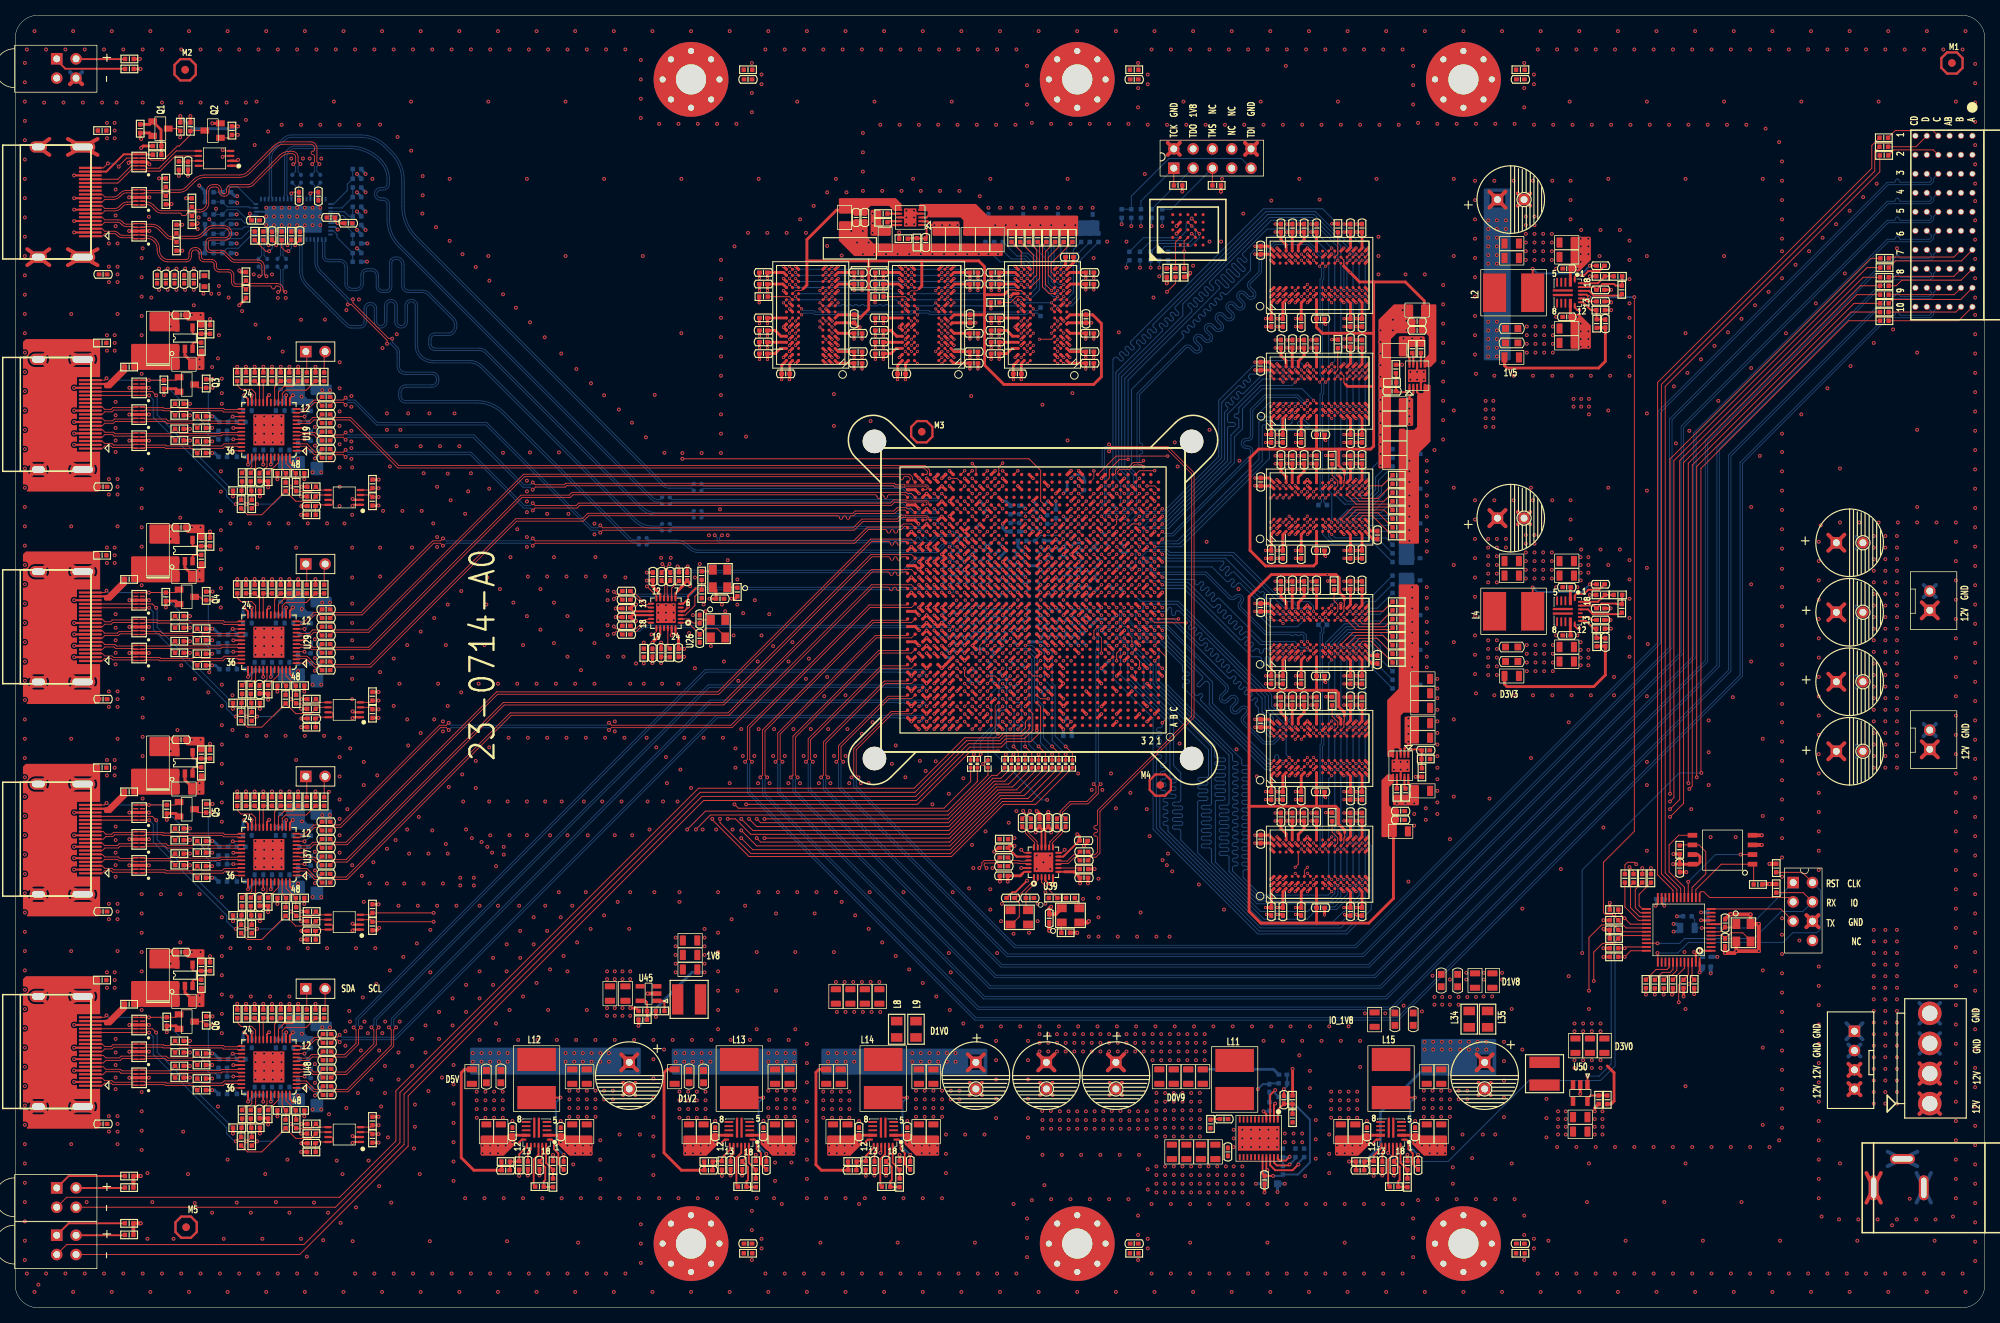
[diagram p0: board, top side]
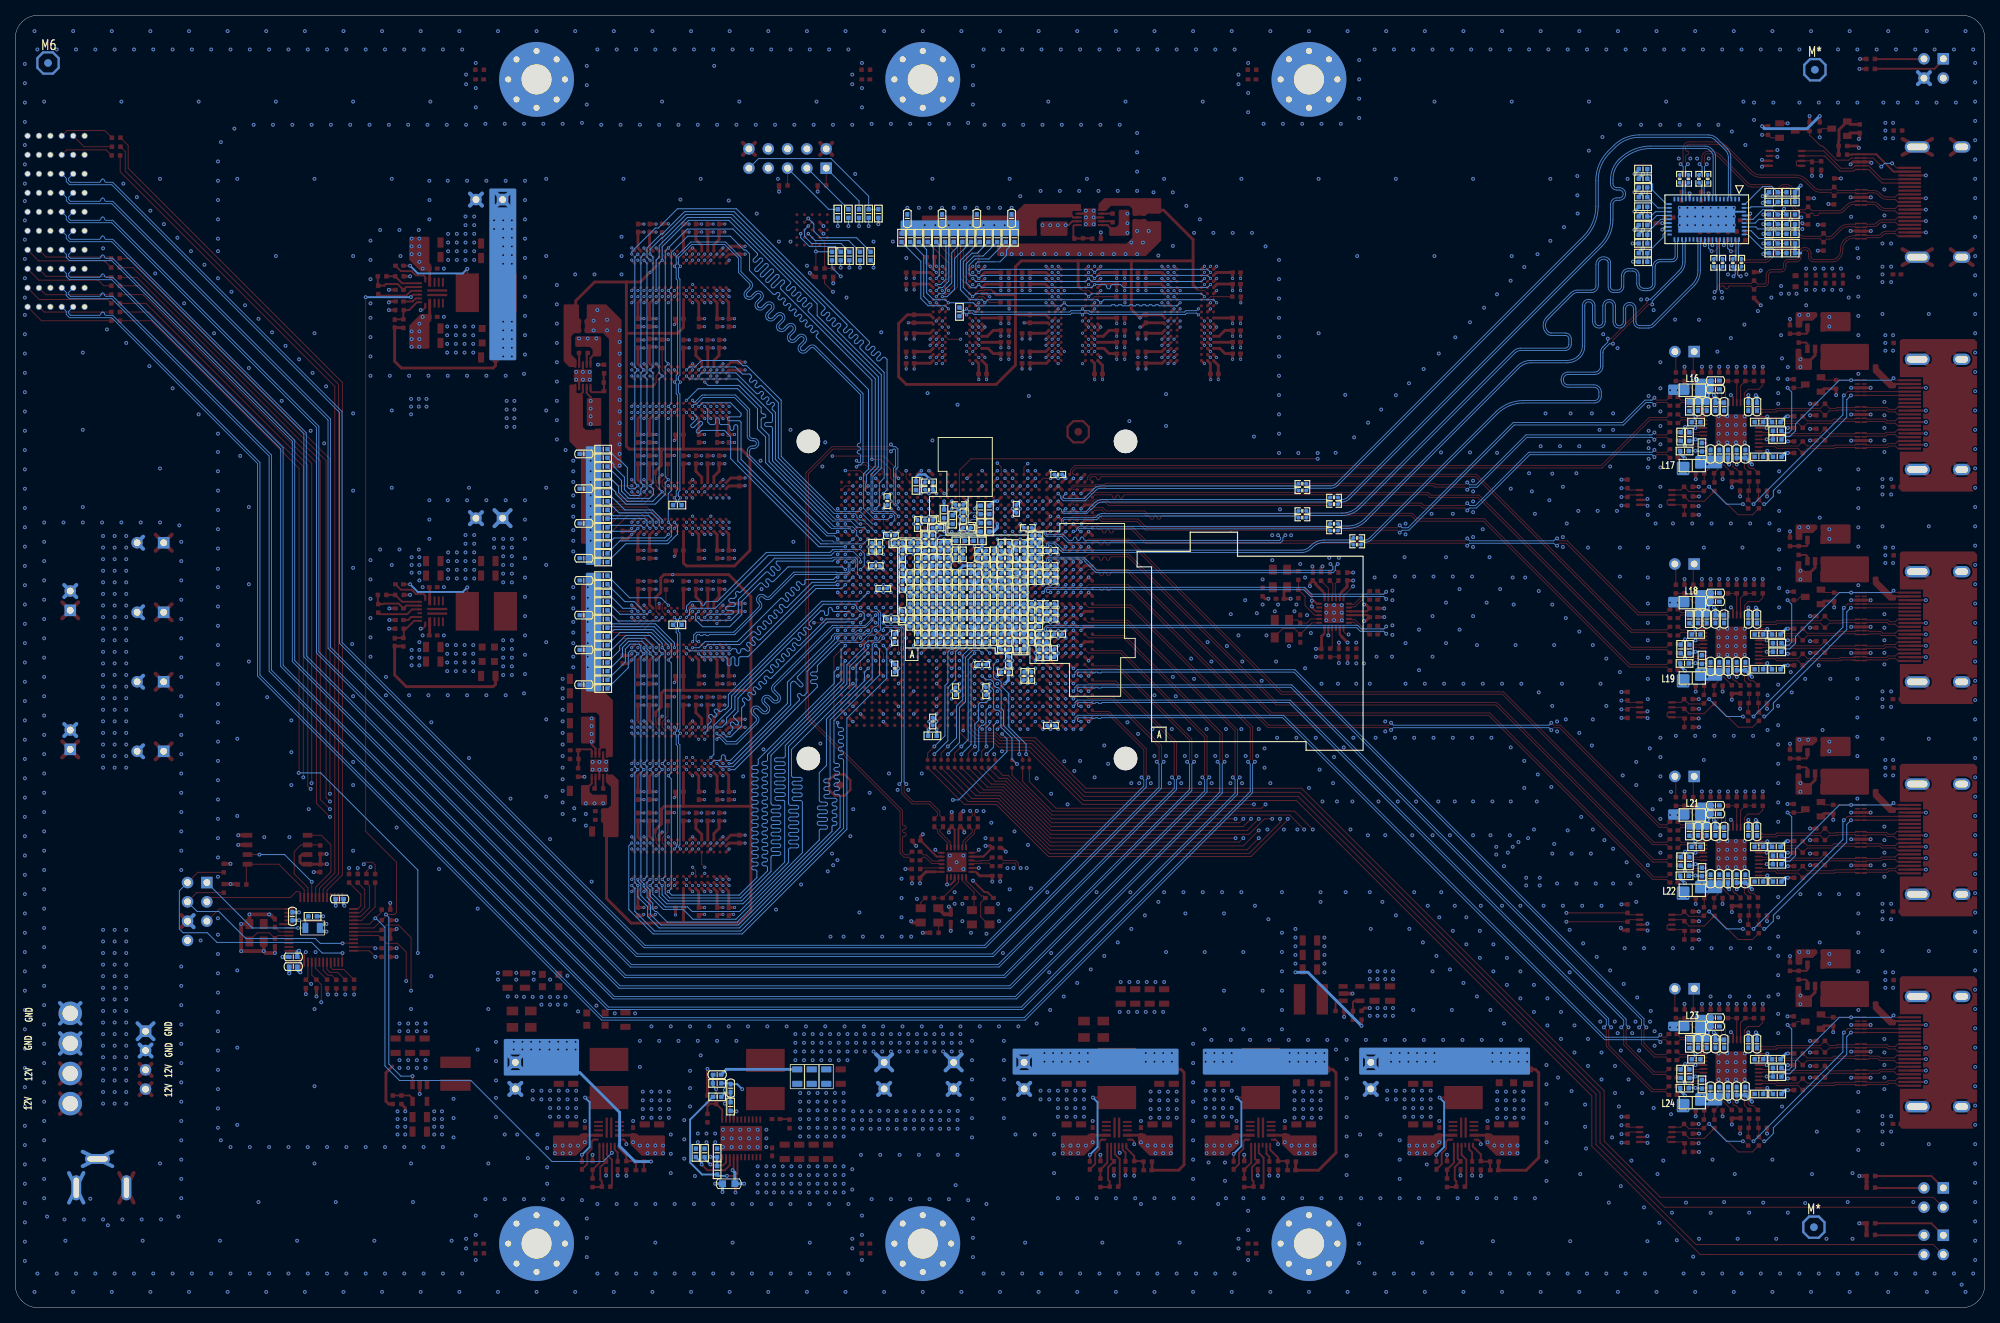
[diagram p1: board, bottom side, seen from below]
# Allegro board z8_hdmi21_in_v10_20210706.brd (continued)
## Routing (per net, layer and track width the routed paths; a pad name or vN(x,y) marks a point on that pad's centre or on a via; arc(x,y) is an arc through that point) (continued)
HDMI_RX3N: length 37.4
  TOP w0.114: HDMI1.12 11.45,146.47 11.79,146.13 12.88,146.13 arc(13.25,146.21) 13.58,146.42 13.8,146.64 arc(14.19,146.91) 14.67,147 15.37,147 15.46,147.09 U4.6 U4.5 16.93,147.09 17.02,147 19.36,147 R16.2 20.2,147.07 21.6,147.07 arc(22.06,147.16) 22.45,147.42 23.44,148.42 arc(24.13,148.87) 24.94,149.03 29.52,149.03 arc(30.11,149.15) 30.61,149.49 33.95,152.83 arc(34.57,153.24) 35.31,153.39 38.88,153.39 arc(39.45,153.15) 39.69,152.58 39.69,150.78 v1(40.01,150.46)
  BOTTOM w0.114: v1(40.01,150.46) 39.67,150.12 39.67,149.52 40.13,149.06 C390.1
HDMI_RX3P: length 37.4
  TOP w0.114: HDMI1.10 11.45,145.47 11.79,145.81 12.88,145.81 arc(13.38,145.91) 13.8,146.2 14.02,146.42 arc(14.32,146.62) 14.67,146.69 15.37,146.69 15.46,146.59 U4.7 U4.4 16.86,146.59 16.95,146.69 19.42,146.69 R17.2 20.27,146.75 21.6,146.75 arc(22.18,146.86) 22.67,147.19 23.67,148.19 arc(24.25,148.58) 24.94,148.72 29.52,148.72 arc(30.23,148.86) 30.83,149.26 34.18,152.6 arc(34.7,152.95) 35.31,153.07 38.88,153.07 arc(39.23,152.93) 39.37,152.58 39.37,152.38 arc(39.31,152.23) 39.16,152.17 39.14,152.17 arc(38.91,151.94) 39.14,151.71 arc(39.3,151.64) 39.37,151.48 39.37,150.77 v1(39.06,150.46)
  BOTTOM w0.114: v1(39.06,150.46) 39.36,150.16 39.36,149.43 38.99,149.06 C391.1
HDMI_RXC0N: length 2.8
  BOTTOM w0.114: C398.2 35.64,138.01 35.23,138.41 35.23,140.28 35.33,140.37 U59.39
HDMI_RXC0P: length 2.8
  BOTTOM w0.114: U59.40 34.83,140.35 34.92,140.25 34.92,138.43 34.49,138.01 C399.2
HDMI_RXC1N: length 2.8
  BOTTOM w0.114: C400.2 33.15,138.01 32.73,138.42 32.73,140.27 32.83,140.36 U59.44
HDMI_RXC1P: length 2.8
  BOTTOM w0.114: U59.45 32.33,140.36 32.42,140.26 32.42,138.42 32,138.01 C401.2
HDMI_RXC2N: length 2.4
  BOTTOM w0.114: U59.11 37.33,146.39 37.23,146.48 37.23,147.65 37.59,148.01 C392.2
HDMI_RXC2P: length 2.4
  BOTTOM w0.114: C393.2 36.45,148.01 36.92,147.54 36.92,146.48 36.83,146.39 U59.10
HDMI_RXC3N: length 2.4
  BOTTOM w0.114: C390.2 40.13,148.01 39.73,147.61 39.73,146.48 39.83,146.39 U59.16
HDMI_RXC3P: length 2.4
  BOTTOM w0.114: U59.15 39.33,146.39 39.42,146.48 39.42,147.58 38.99,148.01 C391.2
HDMI_SCL_1: length 30.3
  TOP w0.127: J6.15 U15.10 U15.1 v1(17.61,120.03) ; R93.1 29.84,107.58 R101.1 29.77,106.34 R107.1 29.16,105.73 v1(29.02,105.73)
  BOTTOM w0.127: v1(29.02,105.73) 28.83,105.73 27.81,106.74 27.81,107.51 18.16,117.16 18.16,119.48 v1(17.61,120.03)
HDMI_SCL_2: length 30.3
  TOP w0.127: R161.1 29.84,79.64 R169.1 29.77,78.4 R173.1 29.16,77.79 v1(29.02,77.79) ; v1(17.61,92.09) U24.1 U24.10 J8.15
  BOTTOM w0.127: v1(17.61,92.09) 18.16,91.54 18.16,89.22 27.81,79.57 27.81,78.8 28.83,77.79 v1(29.02,77.79)
HDMI_SCL_3: length 30.3
  TOP w0.127: J10.15 U35.10 U35.1 v1(17.61,64.15) ; R230.1 29.84,51.7 R239.1 29.72,51.57 R243.1 29.16,49.85 v1(29.02,49.85)
  BOTTOM w0.127: v1(17.61,64.15) 18.16,63.6 18.16,61.28 27.81,51.63 27.81,50.86 28.83,49.85 v1(29.02,49.85)
HDMI_SCL_4: length 30.3
  TOP w0.127: v1(29.02,21.91) 29.16,21.91 R301.1 29.72,23.63 R297.1 29.84,23.76 R288.1 ; v1(17.61,36.21) U46.1 U46.10 J14.15
  BOTTOM w0.127: v1(29.02,21.91) 28.83,21.91 27.81,22.92 27.81,23.69 18.16,33.34 18.16,35.66 v1(17.61,36.21)
HDMI_SCL_21: length 15.9
  TOP w0.127: U2.6 21.05,151.54 19.05,149.54 17.27,149.54 17.06,149.75 U3.1 U3.10 15.28,149.75 13.51,147.97 HDMI1.15
HDMI_SDA_1: length 31.5
  TOP w0.127: v1(18.54,120.03) 18.04,120.53 U15.2 U15.9 J6.16 ; R94.1 30.99,107.58 R102.1 31.12,107.45 R108.1 30.55,105.73 v1(30.42,105.73)
  BOTTOM w0.127: v1(30.42,105.73) 18.67,117.48 18.67,119.91 v1(18.54,120.03)
HDMI_SDA_2: length 31.5
  TOP w0.127: v1(30.42,77.79) 30.55,77.79 R174.1 31.12,79.51 R170.1 30.99,79.64 R162.1 ; J8.16 U24.9 U24.2 18.04,92.59 v1(18.54,92.09)
  BOTTOM w0.127: v1(18.54,92.09) 18.67,91.97 18.67,89.54 v1(30.42,77.79)
HDMI_SDA_3: length 31.5
  TOP w0.127: J10.16 U35.9 U35.2 18.04,64.65 v1(18.54,64.15) ; v1(30.42,49.85) 30.55,49.85 R244.1 31.12,51.57 R240.1 30.99,51.7 R231.1
  BOTTOM w0.127: v1(18.54,64.15) 18.67,64.03 18.67,61.59 v1(30.42,49.85)
HDMI_SDA_4: length 31.5
  TOP w0.127: R289.1 30.99,23.76 R298.1 31.12,23.63 R302.1 30.55,21.91 v1(30.42,21.91) ; v1(18.54,36.21) 18.04,36.71 U46.2 U46.9 J14.16
  BOTTOM w0.127: v1(30.42,21.91) 18.67,33.66 18.67,36.09 v1(18.54,36.21)
HDMI_SDA_21: length 16
  TOP w0.127: HDMI1.16 13.51,148.47 15.28,150.25 U3.9 U3.2 17.07,150.25 17.4,149.92 18.92,149.92 21.19,152.19 U2.5
HM20_RX_RCK+: length 42.4
  TOP w0.114: v2(122.89,100.12) P1.AD28
  BOTTOM w0.102: v2(122.89,100.12) 123.07,100.12 123.17,100.22 123.17,100.43 123.09,100.51 122.42,100.51 122.19,100.28 122.19,100.22 122.17,100.2
  BOTTOM w0.114: C428.2 83.36,100.7 86.85,100.7 arc(87.71,100.53) 88.44,100.04 88.57,99.91 arc(89.18,99.5) 89.9,99.36 121.33,99.36 122.17,100.2
HM20_RX_RCK-: length 42.9
  TOP w0.114: v2(123.89,100.12) P1.AD27
  BOTTOM w0.102: 121.95,100.42 121.96,100.44 122.03,100.44 122.33,100.74 123.18,100.74 123.4,100.53 123.4,100.22 123.5,100.12 v2(123.89,100.12)
  BOTTOM w0.114: C426.2 83.32,101.02 86.85,101.02 arc(87.83,100.82) 88.67,100.26 88.79,100.14 arc(89.3,99.8) 89.9,99.68 121.2,99.68 121.95,100.42
HM20_TX+: length 2.6
  TOP w0.114: C160.1 85.44,95.26 85.44,93.76 85.35,93.67 U26.10
HM20_TX-: length 2.6
  TOP w0.114: U26.9 85.85,93.67 85.76,93.76 85.76,95.26 C161.1
HM20_TX_RCX+: length 42.3
  TOP w0.114: v1(85.12,97.85) 85.44,97.54 85.44,97.14 C160.2 ; v2(122.89,98.12) P1.AB28
  BOTTOM w0.102: v2(122.89,98.12) 123.04,98.12 123.17,98.25 123.17,98.41 123.07,98.51 118.64,98.51 118.36,98.23 118.36,98.17
  BOTTOM w0.114: 118.36,98.17 116.9,96.71 85.74,96.71 85.44,97.01 85.44,97.54 v1(85.12,97.85)
HM20_TX_RCX-: length 42.3
  TOP w0.114: C161.2 85.76,97.14 85.76,97.54 v1(86.07,97.85) ; v2(123.89,98.12) P1.AB27
  BOTTOM w0.102: 118.14,98.39 118.15,98.4 118.21,98.4 118.55,98.74 123.16,98.74 123.4,98.51 123.4,98.25 123.53,98.12 v2(123.89,98.12)
  BOTTOM w0.114: 118.14,98.39 116.77,97.03 85.87,97.03 85.76,97.14 85.76,97.54 v1(86.07,97.85)
HM21_RX0+: length 86.3
  BOTTOM w0.114: U59.29 40.33,140.36 40.42,140.27 40.42,138.35 arc(40.63,137.83) 41.15,137.62 42.68,137.62 arc(43.17,137.41) 43.37,136.93 43.37,134.7 arc(43.43,134.38) 43.62,134.1 arc(43.94,133.88) 44.33,133.81 44.86,133.81 arc(45.51,134.08) 45.78,134.73 45.78,135.86 arc(45.94,136.24) 46.32,136.4 46.88,136.4 arc(47.1,136.36) 47.27,136.24 arc(47.43,136) 47.49,135.73 47.49,134.38 arc(47.72,133.8) 48.3,133.57 48.83,133.57 arc(49.33,133.78) 49.54,134.28 49.54,137.5 arc(49.57,137.63) 49.65,137.75 arc(50.41,137.9) 50.84,137.25 50.84,134.47 arc(51.1,133.83) 51.75,133.57 53.57,133.57 arc(53.93,133.49) 54.23,133.29 57.43,130.09 arc(57.78,129.25) 57.43,128.41 arc(57.26,128.29) 57.04,128.24 55.17,128.24 arc(54.62,128.02) 54.39,127.47 54.39,126.77 arc(54.64,126.18) 55.23,125.93 61.07,125.93 arc(61.45,125.86) 61.77,125.64 82.22,105.19 arc(83.28,104.48) 84.53,104.24 88.97,104.24 C664.1
HM21_RX0-: length 85.8
  BOTTOM w0.114: U59.28 40.83,140.36 40.73,140.27 40.73,138.35 arc(40.86,138.06) 41.15,137.93 42.68,137.93 arc(43.39,137.64) 43.69,136.93 43.69,134.7 arc(43.73,134.5) 43.84,134.33 arc(44.07,134.18) 44.33,134.12 44.86,134.12 arc(45.29,134.3) 45.47,134.73 45.47,135.86 arc(45.72,136.46) 46.32,136.72 46.88,136.72 arc(47.22,136.65) 47.5,136.46 arc(47.72,136.12) 47.8,135.73 47.8,134.38 arc(47.95,134.03) 48.3,133.88 48.83,133.88 arc(49.11,134) 49.23,134.28 49.23,137.5 arc(49.28,137.75) 49.42,137.97 arc(50.53,138.19) 51.16,137.25 51.16,134.47 arc(51.33,134.06) 51.75,133.88 53.57,133.88 arc(54.05,133.79) 54.46,133.52 57.66,130.31 arc(58.1,129.25) 57.66,128.18 arc(57.38,127.99) 57.04,127.93 55.17,127.93 arc(54.85,127.79) 54.71,127.47 54.71,126.77 arc(54.86,126.4) 55.23,126.25 61.07,126.25 arc(61.57,126.15) 62,125.87 82.45,105.42 arc(83.4,104.78) 84.53,104.55 88.97,104.55 C663.1
HM21_RX1+: length 84.8
  BOTTOM w0.114: U59.35 37.33,140.37 37.42,140.28 37.42,136.45 arc(37.63,135.36) 38.25,134.44 43.48,129.21 arc(43.83,128.98) 44.25,128.89 45.38,128.89 arc(45.96,129.14) 46.21,129.72 46.21,131.44 arc(46.72,131.95) 47.24,131.44 47.24,129.72 arc(48.07,128.89) 48.9,129.72 48.9,131.82 arc(49.41,132.33) 49.93,131.82 49.93,129.72 arc(50.76,128.89) 51.59,129.72 51.59,131.83 arc(52.11,132.35) 52.62,131.83 52.62,126.52 arc(52.78,125.72) 53.24,125.03 arc(54.03,124.51) 54.96,124.32 59.71,124.32 arc(60.54,124.16) 61.24,123.69 81.39,103.53 arc(82.5,102.79) 83.8,102.53 84.8,102.53 C662.1
HM21_RX1-: length 84.3
  BOTTOM w0.114: U59.34 37.83,140.36 37.73,140.27 37.73,136.45 arc(37.93,135.48) 38.47,134.67 43.7,129.44 arc(43.95,129.27) 44.25,129.21 45.38,129.21 arc(45.74,129.36) 45.89,129.72 45.89,131.44 arc(46.72,132.27) 47.55,131.44 47.55,129.72 arc(48.07,129.21) 48.58,129.72 48.58,131.82 arc(49.41,132.65) 50.25,131.82 50.25,129.72 arc(50.76,129.21) 51.27,129.72 51.27,131.83 arc(52.11,132.67) 52.94,131.83 52.94,126.52 arc(53.07,125.84) 53.46,125.26 arc(54.15,124.8) 54.96,124.64 59.71,124.64 arc(60.66,124.45) 61.46,123.91 81.62,103.76 arc(82.62,103.09) 83.8,102.85 84.8,102.85 C661.1
HM21_RX2+: length 82.1
  BOTTOM w0.114: C666.1 84.8,106.33 84.55,106.33 arc(84.16,106.41) 83.84,106.62 50.61,139.85 arc(49.59,141.39) 49.23,143.2 49.23,145.19 arc(48.98,145.78) 48.39,146.02 48.08,146.02 arc(47.56,146.53) 48.08,147.05 48.39,147.05 arc(48.98,147.29) 49.23,147.88 49.23,148.46 arc(48.95,149.86) 48.15,151.05 48.07,151.12 arc(46.18,152.39) 43.95,152.83 36.77,152.83 arc(36.33,152.74) 35.95,152.49 35.77,152.31 arc(35.51,151.92) 35.42,151.46 35.42,146.36 35.33,146.27 U59.7
HM21_RX2-: length 81.6
  BOTTOM w0.114: C665.1 84.8,106.01 84.55,106.01 arc(84.04,106.11) 83.61,106.4 50.39,139.63 arc(49.29,141.26) 48.91,143.2 48.91,145.19 arc(48.76,145.55) 48.39,145.7 48.08,145.7 arc(47.24,146.53) 48.08,147.37 48.39,147.37 arc(48.76,147.52) 48.91,147.88 48.91,148.46 arc(48.65,149.74) 47.93,150.82 47.85,150.9 arc(46.06,152.09) 43.95,152.51 36.77,152.51 arc(36.45,152.45) 36.18,152.27 35.99,152.08 arc(35.8,151.8) 35.73,151.46 35.73,146.33 35.83,146.24 U59.8
HM21_RX3+: length 86
  BOTTOM w0.114: U59.3 33.33,146.04 33.42,146.13 33.42,151.36 arc(33.54,151.99) 33.9,152.52 35.2,153.82 arc(35.73,154.18) 36.37,154.31 45.45,154.31 arc(47.26,153.95) 48.79,152.92 49.59,152.12 arc(50.76,150.38) 51.17,148.32 51.17,144.92 arc(51.6,142.77) 52.82,140.94 85.32,108.43 arc(85.65,108.21) 86.05,108.13 88.97,108.13 C668.1
HM21_RX3-: length 85.5
  BOTTOM w0.114: C667.1 88.97,107.82 86.05,107.82 arc(85.53,107.92) 85.1,108.21 52.59,140.71 arc(51.3,142.64) 50.85,144.92 50.85,148.32 arc(50.47,150.26) 49.37,151.9 48.57,152.7 arc(47.14,153.65) 45.45,153.99 36.37,153.99 arc(35.86,153.89) 35.42,153.6 34.12,152.29 arc(33.83,151.87) 33.73,151.36 33.73,146.14 33.83,146.04 U59.4
HM21_SCL: length 188.1
  TOP w0.127: v1(97.54,61.79) 98.04,61.28 122.92,61.28 129.4,67.75 132.2,67.75 R187.2
  06_SIG2 w0.127: v1(26.42,144.59) 26.03,144.59 25.02,143.57 25.02,137.27 35.36,126.94 41.4,126.94 45.72,122.62 45.72,77.03 59.31,63.44 95.89,63.44 v1(97.54,61.79)
  BOTTOM w0.127: v1(26.42,144.59) 26.42,144.16 R345.1 R344.1 27.89,144.47 29.21,144.47 30.48,143.2 U59.50
HM21_SDA: length 183.7
  TOP w0.127: v1(98.55,61.79) 122.89,61.79 129.24,68.14 131.69,68.14 R186.2
  06_SIG2 w0.127: v1(25.53,143.2) 25.53,137.35 35.54,127.33 41.64,127.33 46.17,122.8 46.17,77.21 59.56,63.82 96.52,63.82 v1(98.55,61.79)
  BOTTOM w0.127: v1(25.53,143.2) 25.53,143.13 R348.1 R347.1 27.89,143.2 29.72,143.2 30.22,142.7 U59.49
HM21RX0+: length 32.8
  TOP w0.114: P1.AG30 v2(120.89,103.12)
  BOTTOM w0.102: 117.21,103.69 117.23,103.69 117.28,103.73 121.07,103.73 121.23,103.57 121.23,103.19 121.17,103.12 v2(120.89,103.12)
  BOTTOM w0.114: 117.21,103.69 116.8,103.69 116.45,104.05 arc(116.32,104.13) 116.16,104.16 90.48,104.16 C664.2
HM21RX0-: length 33.2
  TOP w0.114: P1.AG29 v2(121.89,103.12)
  BOTTOM w0.102: v2(121.89,103.12) 121.6,103.12 121.46,103.26 121.46,103.66 121.16,103.96 117.28,103.96 117.23,104.01 117.21,104.01
  BOTTOM w0.114: 117.21,104.01 116.94,104.01 116.67,104.27 arc(116.44,104.43) 116.16,104.48 90.63,104.48 C663.2
HM21RX1+: length 34.5
  TOP w0.114: P1.AF32 v2(118.89,102.12)
  BOTTOM w0.102: v2(118.89,102.12) 119.04,102.12 119.2,102.28 119.2,102.39 119.06,102.53 117.5,102.53 117.46,102.48 117.43,102.48
  BOTTOM w0.114: C662.2 86.34,102.48 117.43,102.48
HM21RX1-: length 35
  TOP w0.114: P1.AF31 v2(119.89,102.12)
  BOTTOM w0.102: 117.43,102.8 117.45,102.8 117.49,102.76 119.16,102.76 119.43,102.48 119.43,102.33 119.63,102.12 v2(119.89,102.12)
  BOTTOM w0.114: 117.43,102.8 86.44,102.8 C661.2
HM21RX2+: length 37.1
  TOP w0.114: P1.AJ30 v2(120.89,105.12)
  BOTTOM w0.102: v2(120.89,105.12) 121.04,105.12 121.14,105.02 121.14,104.82 121.04,104.71 118.23,104.71 117.8,105.14 117.8,105.2 117.79,105.22
  BOTTOM w0.114: 117.79,105.22 117.11,105.89 arc(116.63,106.22) 116.05,106.33 86.39,106.33 C666.2
HM21RX2-: length 37.6
  TOP w0.114: P1.AJ29 v2(121.89,105.12)
  BOTTOM w0.102: 117.56,104.99 117.58,104.98 117.64,104.98 118.14,104.48 121.13,104.48 121.46,104.81 121.46,105.02 121.56,105.12 v2(121.89,105.12)
  BOTTOM w0.114: 117.56,104.99 116.89,105.67 arc(116.5,105.92) 116.05,106.01 86.39,106.01 C665.2
HM21RX3+: length 33.1
  TOP w0.114: P1.AL30 v2(120.89,107.12)
  BOTTOM w0.114: v2(120.89,107.12) 121.23,106.78 121.23,106.62 121.1,106.49 118.45,106.49 117.14,107.8 arc(116.79,108.03) 116.38,108.12 90.58,108.12 C668.2
HM21RX3-: length 33.6
  TOP w0.114: P1.AL29 v2(121.89,107.12)
  BOTTOM w0.114: v2(121.89,107.12) 121.55,106.78 121.55,106.49 121.23,106.17 118.32,106.17 116.92,107.58 arc(116.67,107.74) 116.38,107.8 90.54,107.8 C667.2
HM_1_TCX+: length 87.7
  TOP w0.102: P1.AH32 119.84,103.62 119.94,103.72 119.94,103.89 119.82,104.01 117.16,104.01 117.12,103.97 117.09,103.97
  TOP w0.114: v1(43.46,118.78) 43.14,119.09 41.83,119.09 C115.1 ; 117.09,103.97 116.66,103.97 116.14,103.45 111.52,103.45 110.36,102.3 77.28,102.3 v1(76.96,101.98)
  BOTTOM w0.114: v1(43.46,118.78) 43.78,119.09 44.58,119.09 47.53,116.14 61.91,116.14 75.75,102.3 76.64,102.3 v1(76.96,101.98)
HM_1_TCX-: length 87.7
  TOP w0.102: P1.AH31 120.27,103.62 120.17,103.72 120.17,103.99 119.91,104.24 117.16,104.24 117.12,104.29 117.09,104.29
  TOP w0.114: C113.1 41.83,119.41 43.14,119.41 v1(43.46,119.73) ; v1(76.96,102.93) 77.28,102.62 110.23,102.62 111.39,103.77 116.01,103.77 116.52,104.29 117.09,104.29
  BOTTOM w0.114: v1(76.96,102.93) 76.64,102.62 75.88,102.62 62.04,116.46 47.66,116.46 44.71,119.41 43.78,119.41 v1(43.46,119.73)
HM_1_TX0+: length 82.5
  TOP w0.114: C120.1 41.83,116.81 44.01,116.81 50.33,110.49 119.55,110.49 119.97,110.07 119.97,109.72 119.87,109.62 P1.AP32
HM_1_TX0-: length 82.5
  TOP w0.114: P1.AP31 120.29,109.72 120.29,110.2 119.68,110.81 50.46,110.81 44.14,117.13 41.83,117.13 C117.1
HM_1_TX1+: length 83
  TOP w0.102: P1.AM32 119.85,107.62 119.95,107.72 119.95,107.93 119.87,108.01 117.01,108.01 116.96,107.97
  TOP w0.114: C130.1 41.83,114.52 43.14,114.52 v1(43.46,114.2) ; 116.96,107.97 115.69,107.97 115.51,108.15 72.53,108.15 72.35,107.97 68.41,107.97 v1(68.07,107.63)
  BOTTOM w0.114: v1(68.07,107.63) 67.75,107.95 66.8,107.95 60.23,114.52 43.78,114.52 v1(43.46,114.2)
HM_1_TX1-: length 83
  TOP w0.102: P1.AM31 120.28,107.62 120.18,107.72 120.18,108.03 119.96,108.24 119.72,108.24 117.01,108.24 116.99,108.26 116.99,108.27 116.97,108.29 116.96,108.29
  TOP w0.114: v1(43.46,115.16) 43.14,114.84 41.83,114.84 C122.1 ; v1(68.07,108.58) 68.37,108.29 72.21,108.29 72.4,108.47 115.64,108.47 115.82,108.29 116.96,108.29
  BOTTOM w0.114: v1(68.07,108.58) 67.75,108.27 66.93,108.27 60.36,114.84 43.78,114.84 v1(43.46,115.16)
HM_1_TX2+: length 83.2
  TOP w0.102: 117.14,105.97 117.17,105.97 117.21,106.01 119.79,106.01 119.94,105.87 119.94,105.72 119.84,105.62 P1.AK32
  TOP w0.114: C133.1 41.83,112.24 43.14,112.24 v1(43.46,111.92) ; v1(68.07,104.9) 68.39,105.22 73.91,105.22 74.24,105.55 115.24,105.55 115.66,105.97 117.14,105.97
  BOTTOM w0.114: v1(43.46,111.92) 43.78,112.24 43.94,112.24 59.84,112.24 66.86,105.22 67.75,105.22 v1(68.07,104.9)
HM_1_TX2-: length 83.3
  TOP w0.102: 117.14,106.29 117.17,106.29 117.21,106.24 119.89,106.24 120.17,105.96 120.17,105.72 120.27,105.62 P1.AK31
  TOP w0.114: 117.14,106.29 115.53,106.29 115.11,105.87 74.11,105.87 73.78,105.54 68.39,105.54 v1(68.07,105.85) ; v1(43.46,112.87) 43.14,112.55 41.83,112.55 C132.1
  BOTTOM w0.114: v1(43.46,112.87) 43.78,112.55 44.07,112.55 59.98,112.55 66.99,105.54 67.75,105.54 v1(68.07,105.85)
HM_2_TCX+: length 82.7
  TOP w0.114: P1.AG34 117.2,102.81 116.97,102.81 116.55,102.39 116.28,102.39 arc(116.12,102.32) 116.05,102.16 116.05,102.15 arc(115.82,101.92) 115.6,102.15 115.6,102.16 arc(115.37,102.39) 115.14,102.16 115.14,102.15 arc(114.91,101.92) 114.68,102.15 114.68,102.16 arc(114.61,102.32) 114.45,102.39 112.23,102.39 110.43,100.58 68.39,100.58 v1(68.07,100.27) ; C181.1 41.83,91.15 45.62,91.15 55.05,100.58 55.94,100.58 v1(56.26,100.27)
  BOTTOM w0.114: v1(56.26,100.27) 56.39,100.27 56.71,100.58 67.75,100.58 v1(68.07,100.27)
HM_2_TCX-: length 82.7
  TOP w0.114: P1.AG33 117.89,103.12 116.84,103.12 116.42,102.7 112.1,102.7 110.29,100.9 68.39,100.9 v1(68.07,101.22) ; v1(56.26,101.22) 55.94,100.9 54.92,100.9 45.49,91.47 41.83,91.47 C178.1
  BOTTOM w0.114: v1(68.07,101.22) 67.75,100.9 56.71,100.9 56.39,101.22 v1(56.26,101.22)
HM_2_TX0+: length 86.2
  TOP w0.114: P1.AN34 117.73,108.96 117.73,109.13 117.51,109.35 117.03,109.35 arc(116.89,109.29) 116.83,109.15 arc(116.77,108.99) 116.6,108.92 arc(116.44,108.99) 116.38,109.15 arc(116.32,109.29) 116.18,109.35 66.99,109.35 46.51,88.87 41.83,88.87 C187.1
HM_2_TX0-: length 86.2
  TOP w0.114: P1.AN33 118.05,108.96 118.05,109.26 117.64,109.66 66.86,109.66 46.38,89.19 41.83,89.19 C185.1
HM_2_TX1+: length 85.8
  TOP w0.114: P1.AL34 117.05,106.96 114.96,106.96 arc(114.8,106.89) 114.73,106.74 114.73,106.71 arc(114.51,106.48) 114.28,106.71 114.28,106.74 arc(114.21,106.89) 114.05,106.96 114.04,106.96 arc(113.88,106.89) 113.82,106.74 113.82,106.71 arc(113.75,106.55) 113.59,106.48 arc(113.43,106.55) 113.36,106.71 113.36,106.74 arc(113.3,106.89) 113.14,106.96 73.37,106.96 73,106.59 66.65,106.59 46.64,86.58 41.83,86.58 C194.1
HM_2_TX1-: length 85.8
  TOP w0.114: C191.1 41.83,86.9 46.51,86.9 66.52,106.91 72.87,106.91 73.24,107.28 117.18,107.28 117.33,107.12 117.88,107.12 P1.AL33
HM_2_TX2+: length 86
  TOP w0.114: C202.1 41.83,84.3 46.77,84.3 65.96,103.49 74.73,103.49 75.44,104.2 108.18,104.2 arc(108.34,104.14) 108.41,103.97 108.41,103.95 arc(108.64,103.72) 108.87,103.95 108.87,103.97 arc(109.1,104.2) 109.33,103.97 109.33,103.95 arc(109.55,103.72) 109.78,103.95 109.78,103.97 arc(109.85,104.14) 110.01,104.2 110.3,104.2 110.61,104.51 115.7,104.51 116.14,104.95 117.06,104.95 P1.AJ34
HM_2_TX2-: length 86
  TOP w0.114: P1.AJ33 117.89,105.12 117.34,105.12 117.19,105.27 116.01,105.27 115.57,104.83 110.48,104.83 110.17,104.52 75.31,104.52 74.6,103.81 65.83,103.81 46.64,84.61 41.83,84.61 C199.1
HM_3_TCX+: length 90.9
  TOP w0.114: P1.W34 117.2,94.81 116.6,94.81 arc(116.44,94.74) 116.37,94.58 arc(116.14,94.35) 115.91,94.58 arc(115.69,94.81) 115.46,94.58 115.46,94.56 arc(115.23,94.33) 115,94.56 115,94.58 arc(114.93,94.74) 114.77,94.81 112.78,94.81 94.3,76.33 78.42,76.33 v1(78.11,76.01) ; C252.1 41.83,63.21 42.83,63.21 55.94,76.33 56.71,76.33 v1(57.02,76.01)
  BOTTOM w0.114: v1(78.11,76.01) 77.79,76.32 57.33,76.32 v1(57.02,76.01)
HM_3_TCX-: length 91
  TOP w0.114: C245.1 41.83,63.53 42.7,63.53 55.81,76.64 56.71,76.64 v1(57.02,76.96) ; P1.W33 117.88,95.12 112.65,95.12 94.17,76.64 78.42,76.64 v1(78.11,76.96)
  BOTTOM w0.114: v1(78.11,76.96) 77.79,76.65 57.33,76.65 v1(57.02,76.96)
HM_3_TX0+: length 93.9
  TOP w0.114: C257.1 41.83,60.93 43.66,60.93 63.44,80.71 92.56,80.71 112.66,100.81 114.87,100.81 arc(115.03,100.74) 115.1,100.58 115.1,100.55 arc(115.33,100.32) 115.56,100.55 115.56,100.58 arc(115.79,100.81) 116.01,100.58 116.01,100.55 arc(116.24,100.32) 116.47,100.55 116.47,100.58 arc(116.54,100.74) 116.7,100.81 117.2,100.81 P1.AE34
HM_3_TX0-: length 93.9
  TOP w0.114: C254.1 41.83,61.25 43.53,61.25 63.31,81.03 92.43,81.03 112.52,101.12 117.88,101.12 P1.AE33
HM_3_TX1+: length 94
  TOP w0.114: C263.1 41.83,58.64 43.66,58.64 64.33,79.31 93.22,79.31 112.71,98.81 114.87,98.81 arc(115.03,98.74) 115.1,98.58 115.1,98.56 arc(115.32,98.34) 115.55,98.56 115.55,98.58 arc(115.78,98.81) 116.01,98.58 116.01,98.56 arc(116.24,98.33) 116.47,98.56 116.47,98.58 arc(116.53,98.74) 116.7,98.81 117.2,98.81 P1.AC34
HM_3_TX1-: length 94
  TOP w0.114: P1.AC33 117.88,99.12 112.58,99.12 93.09,79.63 64.2,79.63 43.53,58.96 41.83,58.96 C260.1
HM_3_TX2+: length 94.1
  TOP w0.114: P1.AA34 117.2,96.81 116.64,96.81 arc(116.48,96.74) 116.42,96.58 116.42,96.55 arc(116.19,96.32) 115.96,96.55 115.96,96.58 arc(115.73,96.81) 115.5,96.58 115.5,96.57 arc(115.27,96.34) 115.04,96.57 115.04,96.58 arc(114.98,96.74) 114.82,96.81 112.75,96.81 93.88,77.95 65.25,77.95 43.66,56.36 41.83,56.36 C269.1
HM_3_TX2-: length 94.1
  TOP w0.114: C266.1 41.83,56.67 43.53,56.67 65.12,78.26 93.75,78.26 112.61,97.12 117.88,97.12 P1.AA33
HM_4_TCX+: length 97.5
  TOP w0.114: v2(118.89,77.12) P1.B32 ; C296.1 41.96,35.27 42.36,35.27 v1(42.67,34.96)
  BOTTOM w0.114: v2(118.89,77.12) 119.24,77.12 119.35,77.24 119.35,77.49 119.22,77.63 117.49,77.63 117.39,77.53 117.08,77.53 116.98,77.63 116.71,77.63 116.61,77.53 116.29,77.53 116.2,77.63 92.37,77.63 50.01,35.27 42.99,35.27 v1(42.67,34.96)
HM_4_TCX-: length 97.5
  TOP w0.114: v1(42.67,35.91) 42.36,35.59 41.96,35.59 C295.1 ; v2(119.89,77.12) P1.B31
  BOTTOM w0.114: v2(119.89,77.12) 119.67,77.34 119.67,77.62 119.35,77.95 92.24,77.95 49.88,35.59 42.99,35.59 v1(42.67,35.91)
HM_4_TX0+: length 102.8
  TOP w0.114: v2(118.89,83.12) P1.H32 ; v1(45.47,36.88) 45.15,36.57 45.15,34.67 43.47,32.99 41.96,32.99 C301.1
  BOTTOM w0.114: v1(45.47,36.88) 45.15,37.2 45.15,37.9 90.88,83.63 116.19,83.63 116.29,83.53 116.61,83.53 116.71,83.63 116.98,83.63 117.08,83.53 117.4,83.53 117.51,83.63 119.23,83.63 119.36,83.5 119.36,83.24 119.25,83.12 v2(118.89,83.12)
HM_4_TX0-: length 102.9
  TOP w0.114: v1(44.51,36.88) 44.83,36.57 44.83,34.8 43.33,33.31 41.96,33.31 C300.1 ; v2(119.89,83.12) P1.H31
  BOTTOM w0.114: v1(44.51,36.88) 44.83,37.2 44.83,38.04 90.74,83.95 119.36,83.95 119.68,83.64 119.68,83.33 v2(119.89,83.12)
HM_4_TX1+: length 103
  TOP w0.114: C331.1 41.96,30.7 43.59,30.7 47.5,34.61 47.5,36.58 v1(47.82,36.89) ; v2(118.89,81.12) P1.F32
  BOTTOM w0.114: v2(118.89,81.12) 119.27,81.12 119.38,81.24 119.38,81.48 119.23,81.63 117.51,81.63 117.42,81.55 117.05,81.55 116.97,81.63 116.7,81.63 116.62,81.55 116.25,81.55 116.16,81.63 91.29,81.63 47.5,37.84 47.5,37.21 v1(47.82,36.89)
HM_4_TX1-: length 103
  TOP w0.114: v2(119.89,81.12) P1.F31 ; v1(46.86,36.89) 47.18,36.58 47.18,34.74 43.46,31.02 41.96,31.02 C302.1
  BOTTOM w0.114: v2(119.89,81.12) 119.7,81.31 119.7,81.61 119.36,81.95 91.16,81.95 47.18,37.97 47.18,37.21 v1(46.86,36.89)
HM_4_TX2+: length 103.2
  TOP w0.114: C333.1 41.96,28.42 43.79,28.42 49.78,34.41 49.78,36.58 v1(50.1,36.89) ; v2(118.89,79.12) P1.D32
  BOTTOM w0.114: v2(118.89,79.12) 119.23,79.12 119.35,79.24 119.35,79.52 119.23,79.63 117.48,79.63 117.36,79.51 117.04,79.51 116.93,79.63 116.66,79.63 116.54,79.51 116.22,79.51 116.11,79.63 91.51,79.63 49.78,37.91 49.78,37.21 v1(50.1,36.89)
HM_4_TX2-: length 103.3
  TOP w0.114: v1(49.15,36.89) 49.47,36.58 49.47,34.54 43.66,28.73 41.96,28.73 C332.1 ; v2(119.89,79.12) P1.D31
  BOTTOM w0.114: v1(49.15,36.89) 49.47,37.21 49.47,38.04 91.38,79.95 119.36,79.95 119.66,79.65 119.66,79.35 v2(119.89,79.12)
HM_SCL_1: length 164
  TOP w0.102: P1.C19 v2(132.89,78.12)
  TOP w0.127: R75.2 40.64,125.67 J5.2
  03_SIG1 w0.127: v2(132.89,78.12) 133.02,77.99 133.02,74.94 133.73,74.23 133.73,72.07 119.25,57.59 62.99,57.59 59.31,61.28 v1(59.31,62.93)
  06_SIG2 w0.127: J5.2 40.77,125.41 45.34,120.84 45.34,76.9 v1(59.31,62.93)
HM_SCL_2: length 129.2
  TOP w0.102: P1.A20 v2(130.89,76.12)
  TOP w0.127: R132.2 40.64,97.73 J7.2
  03_SIG1 w0.127: v2(130.89,76.12) 130.89,75.45 129.79,74.36 129.79,70.68 119.25,60.13 63.63,60.13 63.12,60.64 v1(62.1,60.64)
  06_SIG2 w0.127: v1(62.1,60.64) 59.56,60.64 43.31,76.9 43.31,95.31 J7.2
HM_SCL_3: length 113.4
  TOP w0.102: P1.D21 v2(129.89,80.12)
  TOP w0.127: J9.2 40.64,69.79 R209.2
  03_SIG1 w0.127: v2(129.89,80.12) P1.D21 131.05,79.62 131.39,79.29 131.39,75.06 130.81,74.49 130.81,71.18 119.25,59.63 v1(64.26,59.63)
  06_SIG2 w0.127: v1(64.26,59.63) 63.5,58.86 51.82,58.86 J9.2
HM_SCL_4: length 123.5
  TOP w0.102: P1.J20 v2(130.89,84.12)
  TOP w0.127: J12.2 40.77,39.36 R271.2
  03_SIG1 w0.127: v2(130.89,84.12) 131.39,83.62 131.39,82.93 131.69,82.62 132.96,82.62 133.35,82.23 133.35,75.25 134.11,74.49 134.11,71.95 119.25,57.09 59.05,57.09 v1(58.55,56.58)
  06_SIG2 w0.127: J12.2 55.37,56.58 v1(58.55,56.58)
HM_SDA_1: length 163
  TOP w0.102: P1.B20 v2(131.89,78.12)
  TOP w0.127: 38.23,125.79 38.35,125.67 R73.2
  03_SIG1 w0.127: v2(131.89,78.12) 131.89,77.73 132.33,77.28 132.33,71.69 119.25,58.61 63.25,58.61 v1(60.07,61.79)
  06_SIG2 w0.127: v1(60.07,61.79) 59.69,61.79 44.88,76.59 44.88,120.15 39.24,125.79 38.23,125.79
HM_SDA_2: length 132.5
  TOP w0.102: P1.A19 v2(131.89,76.12)
  TOP w0.127: 38.23,97.85 38.35,97.73 R130.2
  03_SIG1 w0.127: v1(62.74,59.88) 63.5,59.12 119.25,59.12 131.89,71.75 v2(131.89,76.12)
  06_SIG2 w0.127: v1(62.74,59.88) 59.69,59.88 42.8,76.77 42.8,93.3 42.78,93.3 38.23,97.85
HM_SDA_3: length 120.7
  TOP w0.102: P1.E21 v2(129.89,81.12)
  TOP w0.127: R207.2 38.35,69.79 38.23,69.91
  03_SIG1 w0.127: v2(129.89,81.12) P1.E21 132.04,80.62 132.39,80.28 132.39,77.74 132.66,77.46 132.66,74.74 133.35,74.05 133.35,72.2 119.25,58.1 v1(63.25,58.1)
  06_SIG2 w0.127: v1(63.25,58.1) 50.04,58.1 38.23,69.91
HM_SDA_4: length 132.8
  TOP w0.102: P1.M20 v2(130.89,87.12)
  TOP w0.127: 38.23,41.97 38.35,41.85 R269.2
  03_SIG1 w0.127: v2(130.89,87.12) 131.39,86.62 131.39,85.95 131.71,85.62 133.13,85.62 134.47,84.29 134.47,77.18 135.89,75.76 135.89,72.2 119.25,55.56 v1(60.33,55.56)
  06_SIG2 w0.127: v1(60.33,55.56) 58.8,57.09 53.34,57.09 38.23,41.97
HM_TX_HPD1: length 147.3
  TOP w0.102: P1.B22 v2(129.89,78.12)
  03_SIG1 w0.102: 129.92,76.62 130.03,76.62 130.27,76.86 130.27,77.74 v2(129.89,78.12)
  03_SIG1 w0.127: 129.92,76.62 129.26,76.62 128.4,75.76 128.4,70.42 119.25,61.28 v1(61.34,61.28)
  06_SIG2 w0.127: v1(39.42,115.89) 39.42,114.57 43.82,110.17 43.82,77.03 59.56,61.28 v1(61.34,61.28)
  BOTTOM w0.127: R387.1 38.86,115.33 v1(39.42,115.89) 40.01,115.3 R386.1
HM_TX_HPD2: length 123.1
  TOP w0.102: P1.C22 v2(129.89,79.12)
  03_SIG1 w0.102: v2(129.89,79.12) 130.51,78.5 130.51,76.64
  03_SIG1 w0.127: 130.51,76.64 130.51,76.47 130.39,76.35 130.39,75.84 128.78,74.23 128.78,70.29 119.13,60.64 v1(64.26,60.64)
  06_SIG2 w0.127: v1(39.42,87.95) 42.29,85.08 42.29,76.64 59.56,59.37 62.99,59.37 v1(64.26,60.64)
  BOTTOM w0.127: R447.1 38.86,87.39 v1(39.42,87.95) 40.01,87.36 R446.1
HM_TX_HPD3: length 119.7
  TOP w0.127: P1.H20 v2(131.89,84.12)
  03_SIG1 w0.127: v2(131.89,84.12) 132.39,83.62 133.1,83.62 133.73,82.99 133.73,75.5 135.13,74.1 135.13,72.45 119.25,56.58 v1(60.33,56.58)
  06_SIG2 w0.127: v1(60.33,56.58) 59.44,57.47 41.96,57.47 v1(39.42,60.01)
  BOTTOM w0.127: R467.1 40.01,59.42 v1(39.42,60.01) 38.86,59.45 R468.1
HM_TX_HPD4: length 133.6
  TOP w0.102: P1.K19 v2(131.89,85.12)
  03_SIG1 w0.127: v2(131.89,85.12) 132.39,84.62 133.12,84.62 134.09,83.65 134.09,76.92 135.51,75.5 135.51,72.33 119.25,56.07 59.05,56.07 v1(58.55,55.56)
  06_SIG2 w0.127: v1(39.42,32.07) 39.42,38.09 56.9,55.56 v1(58.55,55.56)
  BOTTOM w0.127: R481.1 38.86,31.51 v1(39.42,32.07) 40.01,31.48 R480.1
HM_TX_SCL1: length 107.8
  TOP w0.127: R183.2 130.16,69.28 128.76,69.28 122.8,63.31 97.54,63.31 v1(96.52,64.33) ; U21.3 46.72,106.94 R105.2 v1(47.8,106.67)
  06_SIG2 w0.127: v1(96.52,64.33) 96.01,64.83 94.61,64.83 52.78,106.67 v1(47.8,106.67)
HM_TX_SCL2: length 98.9
  TOP w0.127: U31.3 46.72,79 R172.2 v1(47.8,78.73) ; R185.2 131.18,68.52 129.08,68.52 122.86,62.29 96.77,62.29 94.74,64.33 v1(93.73,64.33)
  06_SIG2 w0.127: v1(93.73,64.33) 92.78,65.27 61.26,65.27 v1(47.8,78.73)
HM_TX_SCL3: length 91.6
  TOP w0.127: v1(55.04,50.79) R242.2 46.72,51.06 U42.3 ; R180.2 127.96,70.09 122.7,64.83 91.44,64.83 v1(89.53,62.93)
  06_SIG2 w0.127: v1(89.53,62.93) 89.03,62.42 85.47,62.42 73.84,50.79 v1(55.04,50.79)
HM_TX_SCL4: length 113.2
  TOP w0.127: R189.2 133.21,66.99 129.71,66.99 122.98,60.26 97.03,60.26 v1(95.5,61.79) ; U55.3 46.72,23.12 R300.2 v1(47.8,22.85)
  06_SIG2 w0.127: v1(95.5,61.79) 95.38,61.66 86.61,61.66 v1(47.8,22.85)
HM_TX_SCL21: length 190.1
  TOP w0.127: R190.2 133.72,66.61 129.87,66.61 123.01,59.75 96.77,59.75 92.71,63.82 v1(92.71,64.33) ; v1(27.29,151.42) 27.41,151.54 U2.3
  06_SIG2 w0.127: v1(27.29,151.42) 27.56,151.14 27.56,136.79 36.19,128.16 42.09,128.16 46.99,123.25 46.99,77.53 59.69,64.83 92.2,64.83 v1(92.71,64.33)
HM_TX_SDA1: length 107
  TOP w0.127: v1(97.54,64.33) 98.04,63.82 122.76,63.82 128.61,69.66 129.66,69.66 R182.2 ; v1(47.8,107.83) R96.2 46.74,107.59 U21.4
  06_SIG2 w0.127: v1(97.54,64.33) 96.52,65.34 94.74,65.34 52.25,107.83 v1(47.8,107.83)
HM_TX_SDA2: length 98
  TOP w0.127: v1(95.5,64.33) 97.03,62.8 122.83,62.8 128.92,68.9 130.67,68.9 R184.2 ; v1(47.8,79.89) R164.2 46.74,79.65 U31.4
  06_SIG2 w0.127: v1(47.8,79.89) 61.97,65.72 93.09,65.72 94.49,64.33 v1(95.5,64.33)
HM_TX_SDA3: length 90.2
  TOP w0.127: v1(55.04,51.95) R233.2 46.74,51.71 U42.4 ; v1(88.39,62.93) 90.81,65.34 122.67,65.34 126.56,69.23 R179.2
  06_SIG2 w0.127: v1(55.04,51.95) 74.37,51.95 85.34,62.93 v1(88.39,62.93)
HM_TX_SDA4: length 112.3
  TOP w0.127: R188.2 132.7,67.37 129.55,67.37 122.95,60.77 97.54,60.77 v1(95.5,62.8) ; v1(47.8,24.01) R292.2 46.74,23.77 U55.4
  06_SIG2 w0.127: v1(47.8,24.01) 85.83,62.04 94.74,62.04 v1(95.5,62.8)
HM_TX_SDA21: length 193.1
  TOP w0.127: v1(91.69,64.33) 91.69,64.2 96.52,59.37 123.17,59.37 130.03,66.23 134.23,66.23 R191.2 ; U2.4 27.41,152.19 v1(27.29,152.32)
  06_SIG2 w0.127: v1(27.29,152.32) 26.67,151.7 26.67,150.56 27.05,150.18 27.05,136.33 35.64,127.75 41.86,127.75 46.58,123.02 46.58,77.37 59.62,64.33 v1(91.69,64.33)
HPD_IN1: length 26.7
  TOP w0.127: Q3.1 21.16,122.04 R78.2 19.55,122.03 v1(17.58,122.03) U15.5 U15.6 ; J6.19 11.76,122.03 v1(12.01,122.29)
  BOTTOM w0.127: R388.2 26.36,114.62 25.65,114.62 24.89,115.38 24.89,116.27 19.13,122.03 v1(17.58,122.03) 12.26,122.03 v1(12.01,122.29)
HPD_IN2: length 27
  TOP w0.127: U24.6 U24.5 17.27,94.09 ; 17.27,94.09 v1(17.58,94.09) ; 17.27,94.09 17.28,94.1 R138.2 21.16,94.1 Q4.1 ; J8.19 11.76,94.09 v1(12.01,94.35)
  BOTTOM w0.127: R448.2 26.36,86.68 25.65,86.68 24.89,87.44 24.89,88.33 19.13,94.09 v1(17.58,94.09) 12.26,94.09 v1(12.01,94.35)
HPD_IN3: length 26.7
  TOP w0.127: v1(12.01,66.41) 11.76,66.15 J10.19 ; U35.6 U35.5 v1(17.58,66.15) 17.59,66.16 R211.2 21.16,66.16 Q5.1
  BOTTOM w0.127: R469.2 26.36,58.74 25.65,58.74 24.89,59.5 24.89,60.39 19.13,66.15 v1(17.58,66.15) 12.26,66.15 v1(12.01,66.41)
HPD_IN4: length 26.7
  TOP w0.127: J14.19 11.76,38.21 v1(12.01,38.47) ; Q6.1 21.16,38.22 R274.2 17.59,38.22 v1(17.58,38.21) U46.5 U46.6
  BOTTOM w0.127: v1(12.01,38.47) 12.26,38.21 v1(17.58,38.21) 19.13,38.21 24.89,32.45 24.89,31.56 25.65,30.8 26.36,30.8 R482.2
HPD_SNK_1: length 3.1
  TOP w0.127: U19.33 v1(28.69,114.25)
  BOTTOM w0.127: v1(28.69,114.25) 28.67,114.24 R388.1 R385.1
HPD_SNK_2: length 3.1
  TOP w0.127: U29.33 v1(28.69,86.31)
  BOTTOM w0.127: R444.1 R448.1 28.67,86.3 v1(28.69,86.31)
HPD_SNK_3: length 3.1
  TOP w0.127: U37.33 v1(28.69,58.37)
  BOTTOM w0.127: v1(28.69,58.37) 28.67,58.36 R469.1 R466.1
HPD_SNK_4: length 3.1
  TOP w0.127: U48.33 v1(28.69,30.43)
  BOTTOM w0.127: R479.1 R482.1 28.67,30.42 v1(28.69,30.43)
HPD_SRC_1: length 2
  TOP w0.127: U19.4 v1(38.06,114.25)
  BOTTOM w0.127: v1(38.06,114.25) 38.25,114.06 R387.2
HPD_SRC_2: length 2
  TOP w0.127: U29.4 v1(38.06,86.31)
  BOTTOM w0.127: R447.2 38.25,86.12 v1(38.06,86.31)
HPD_SRC_3: length 2
  TOP w0.127: U37.4 v1(38.06,58.37)
  BOTTOM w0.127: v1(38.06,58.37) 38.25,58.18 R468.2
HPD_SRC_4: length 2
  TOP w0.127: U48.4 v1(38.06,30.43)
  BOTTOM w0.127: R481.2 38.25,30.24 v1(38.06,30.43)
I2C_EN/PIN_1: length 3.1
  TOP w0.127: U19.10 v1(38.06,117.25)
  BOTTOM w0.127: R382.1 38.06,117 v1(38.06,117.25) 38.8,117.99 R381.2
I2C_EN/PIN_2: length 3.1
  TOP w0.127: U29.10 v1(38.06,89.31)
  BOTTOM w0.127: R439.1 38.06,89.06 v1(38.06,89.31) 38.8,90.05 R436.2
I2C_EN/PIN_3: length 3.1
  TOP w0.127: U37.10 v1(38.06,61.37)
  BOTTOM w0.127: R463.1 38.06,61.12 v1(38.06,61.37) 38.12,61.37 R462.2
I2C_EN/PIN_4: length 3.1
  TOP w0.127: U48.10 v1(38.06,33.43)
  BOTTOM w0.127: R475.2 38.12,33.43 v1(38.06,33.43) 38.06,33.18 R476.1
LED1: length 155.8
  TOP w0.102: 130.15,75.25 129.51,74.61
  TOP w0.127: 129.51,74.61 125.15,74.61 118.35,67.82 90.1,67.82 50.61,28.32 50.61,21.72 42.12,13.23 U57.4 ; P1.A18 133.39,76.17 132.46,75.25 130.15,75.25
LED2: length 158.9
  TOP w0.127: P1.B18 132.89,77.12 132.89,76.31 132.21,75.63 130.05,75.63 129.41,74.99 124.89,74.99 118.25,68.35 89.88,68.35 50.07,28.55 50.07,21.94 42.67,14.54 6.77,14.54 U57.2
LED3: length 163.3
  TOP w0.127: U58.4 37.42,7.01 51.69,21.27 51.69,27.88 90.55,66.74 118.54,66.74 125.56,73.76 129.7,73.76 130.43,74.49 133.6,74.49 134.89,75.77 134.89,79.12 P1.D17
LED4: length 163.7
  TOP w0.127: P1.C18 133.86,78.15 133.86,76.01 132.72,74.87 130.3,74.87 129.65,74.21 125.38,74.21 118.45,67.28 90.33,67.28 51.15,28.1 51.15,21.5 37.97,8.32 6.77,8.32 U58.2
LED_HDMI21: length 197.9
  TOP w0.102: P1.F21 v2(129.89,82.12)
  TOP w0.127: v1(129.29,73.22) 129.16,73.34 125.78,73.34 118.67,66.23 v1(96.14,66.23)
  06_SIG2 w0.127: U1.2 7.28,159.96 9.27,159.96 14.22,164.91 20.53,164.91 30.25,155.19 30.25,137.25 30.73,136.77 30.73,135.42 36.78,129.37 42.77,129.37 48.13,124.02 48.13,114.11 96.01,66.23 v1(96.14,66.23) ; v1(129.29,73.22) 129.92,73.85 129.92,75.5 129.41,76.01 129.41,81.65 v2(129.89,82.12)
M_AS_DATA0: length 7.3
  TOP w0.127: U6.D3 v2(155.76,141.31)
  BOTTOM w0.127: R703.1 151.2,139.64 154.61,139.64 155.76,140.78 v2(155.76,141.31)
M_AS_DATA1: length 8.5
  TOP w0.127: U6.D2 v2(154.76,141.31)
  BOTTOM w0.127: v2(154.76,141.31) 153.84,140.4 149.42,140.4 R704.1
M_AS_DATA2: length 9
  TOP w0.127: U6.C4 v2(154.76,142.31)
  BOTTOM w0.127: R705.1 150.44,140.02 154.31,140.02 155.24,140.96 155.24,141.83 v2(154.76,142.31)
M_AS_DATA3: length 11.3
  TOP w0.127: v1(154.76,143.31) U6.D4
  BOTTOM w0.127: R706.1 148.41,140.78 153.16,140.78 154.02,141.64 154.02,142.58 v1(154.76,143.31)
MODE: length 4.5
  BOTTOM w0.127: U59.21 43.32,144.2 43.94,143.57 R346.1 R343.1
MSEL0: length 2.6
  TOP w0.127: v2(136.89,103.12) P1.AG15
  BOTTOM w0.127: R412.1 136.88,103.13 v2(136.89,103.12) 136.91,103.14 R410.1
MSEL1: length 1.4
  TOP w0.127: P1.AG13 v2(138.89,103.12)
  BOTTOM w0.102: R413.1 v2(138.89,103.12)
MSEL2: length 1.4
  TOP w0.127: P1.AG12 v2(139.89,103.12)
  BOTTOM w0.102: v2(139.89,103.12) 140.39,102.62 R414.1
NCE: length 1.4
  TOP w0.127: P1.AF14 137.39,101.63 v2(137.85,102.09)
  BOTTOM w0.102: v2(137.85,102.09) 137.87,102.09 R418.1
NCONFIG: length 1.4
  TOP w0.127: v2(138.89,102.12) P1.AF13
  BOTTOM w0.102: v2(138.89,102.12) 138.39,101.63 R420.1
NCS0: length 6.4
  TOP w0.127: R43.2 v1(153.76,138.97) 153.76,140.32 U6.C2
  BOTTOM w0.127: R707.2 153.72,138.93 v1(153.76,138.97)
NIO_PULLUP: length 6.1
  TOP w0.127: v2(137.89,101.12) P1.AE14
  BOTTOM w0.127: v2(137.89,101.12) 137.39,101.62 134.91,101.62 R421.1 R422.1
NSTATUS: length 1.4
  TOP w0.127: P1.AM11 v2(139.89,108.12)
  BOTTOM w0.102: R398.1 v2(139.89,108.12)
PRE_SEL_1: length 4
  TOP w0.127: R69.2 R68.1 32.62,121.91 U19.20
PRE_SEL_2: length 4
  TOP w0.127: U29.20 32.62,93.97 R125.1 R126.2
PRE_SEL_3: length 4
  TOP w0.127: R203.2 R202.1 32.62,66.03 U37.20
PRE_SEL_4: length 4
  TOP w0.127: U48.20 32.62,38.09 R264.1 R265.2
R0PWR5V: length 9.2
  TOP w0.254: HDMI1.18 12,149.47 14.27,151.75 U3.6 U3.5 17.45,151.75 17.5,151.7 R12.1
RC_F_N: length 3.4
  TOP w0.114: U26.17 83.32,90.63 83.23,90.54 82.85,90.54 81.63,89.31 81.33,89.31 C184.1
RC_F_P: length 3.4
  TOP w0.114: U26.18 83.32,90.13 83.23,90.22 82.98,90.22 81.76,89 81.33,89 C186.1
REFCLK_F_N: length 48
  TOP w0.114: v2(123.89,89.12) P1.P27 ; C184.2 79.45,89.31 79.06,89.31 v1(78.74,89.63)
  BOTTOM w0.102: 118.61,89.79 118.64,89.79 118.68,89.74 123.44,89.74 123.68,89.5 123.68,89.22 123.78,89.12 v2(123.89,89.12)
  BOTTOM w0.114: v1(78.74,89.63) 79.06,89.31 82.01,89.31 82.48,89.79 118.61,89.79
REFCLK_F_P: length 48
  TOP w0.114: v2(122.89,89.12) P1.P28 ; v1(78.74,88.68) 79.06,89 79.45,89 C186.2
  BOTTOM w0.102: 118.61,89.47 118.64,89.47 118.68,89.51 123.34,89.51 123.45,89.41 123.45,89.22 123.35,89.12 v2(122.89,89.12)
  BOTTOM w0.114: v1(78.74,88.68) 79.06,89 82.14,89 82.62,89.47 118.61,89.47
RX_5V_N: length 161.3
  TOP w0.127: Q1.3 21.41,155.13 R7.2 v1(21.72,153.99) ; 125.68,71.06 125.68,69.23 122.17,65.72 95.12,65.72 v1(94.61,66.23)
  06_SIG2 w0.127: v1(94.61,66.23) 47.37,113.47 47.37,123.51 42.32,128.56 36.37,128.56 27.94,136.99 27.94,152.46 26.42,153.99 v1(21.72,153.99)
RX_HPD_N: length 159.8
  TOP w0.127: Q2.1 28.12,153.92 R11.2 v1(29.29,154.31) ; R181.2 129.15,70.04 128.45,70.04 122.73,64.33 v1(98.55,64.33)
  06_SIG2 w0.127: v1(29.29,154.31) 29.82,153.78 29.82,136.99 30.35,136.46 30.35,135.19 36.58,128.97 42.55,128.97 47.75,123.76 47.75,113.86 95.89,65.72 97.16,65.72 v1(98.55,64.33)
SCL_CTL_1: length 7.4
  TOP w0.127: U19.15 35.12,120.28 35.56,120.71 38.28,120.71 R74.2 R75.1
SCL_CTL_2: length 7.4
  TOP w0.127: U29.15 35.12,92.34 35.56,92.77 38.28,92.77 R131.2 R132.1
SCL_CTL_3: length 7.4
  TOP w0.127: R209.1 R208.2 38.28,64.83 35.56,64.83 35.12,64.4 U37.15
SCL_CTL_4: length 7.4
  TOP w0.127: U48.15 35.12,36.46 35.56,36.89 38.28,36.89 R270.2 R271.1
SCL_SNK_1: length 2.8
  TOP w0.127: U19.38 31.12,110.69 30.86,110.43 30.43,110.43 R93.2
SCL_SNK_2: length 2.8
  TOP w0.127: R161.2 30.43,82.49 30.86,82.49 31.12,82.75 U29.38
SCL_SNK_3: length 2.8
  TOP w0.127: U37.38 31.12,54.81 30.86,54.55 30.43,54.55 R230.2
SCL_SNK_4: length 2.8
  TOP w0.127: R288.2 30.43,26.61 30.86,26.61 31.12,26.87 U48.38
SCL_SRC_1: length 3.6
  TOP w0.127: R98.1 35.61,108.63 R90.1 35.12,110.28 U19.46
SCL_SRC_2: length 3.6
  TOP w0.127: R165.1 35.61,80.69 R159.1 35.12,82.34 U29.46
SCL_SRC_3: length 3.6
  TOP w0.127: R234.1 35.61,52.75 R226.1 35.12,54.4 U37.46
SCL_SRC_4: length 3.6
  TOP w0.127: U48.46 35.12,26.46 R286.1 35.61,24.81 R294.1
SDA_CTL_1: length 5.7
  TOP w0.127: U19.16 34.62,120.48 35.35,121.21 36.5,121.21 R72.2 R73.1
SDA_CTL_2: length 5.7
  TOP w0.127: R130.1 R129.2 36.5,93.27 35.35,93.27 34.62,92.54 U29.16
SDA_CTL_3: length 5.7
  TOP w0.127: U37.16 34.62,64.6 35.35,65.33 36.5,65.33 R206.2 R207.1
SDA_CTL_4: length 5.7
  TOP w0.127: R269.1 R268.2 36.5,37.39 35.35,37.39 34.62,36.66 U48.16
SDA_SNK_1: length 2.3
  TOP w0.127: R94.2 31.62,110.48 U19.39
SDA_SNK_2: length 2.3
  TOP w0.127: R162.2 31.62,82.54 U29.39
SDA_SNK_3: length 2.3
  TOP w0.127: R231.2 31.62,54.6 U37.39
SDA_SNK_4: length 2.3
  TOP w0.127: R289.2 31.62,26.66 U48.39
SDA_SRC_1: length 3.9
  TOP w0.127: R99.1 36.9,108.63 R91.1 35.62,111.07 U19.47
SDA_SRC_2: length 3.9
  TOP w0.127: U29.47 35.62,83.13 R160.1 36.9,80.69 R166.1
SDA_SRC_3: length 3.9
  TOP w0.127: R235.1 36.9,52.75 R227.1 35.62,55.19 U37.47
SDA_SRC_4: length 3.9
  TOP w0.127: U48.47 35.62,27.25 R287.1 36.9,24.81 R295.1
SEL0: length 5.1
  BOTTOM w0.127: R367.1 R352.1 44.4,141.42 42.62,143.2 U59.23
SEL1: length 5.5
  BOTTOM w0.127: R373.1 R370.1 42.33,140.82 42.33,141.2 41.83,141.7 U59.26
SI_DDR3A_N: length 3.4
  TOP w0.114: U39.17 134.5,60.88 134.41,60.98 134.41,61.36 133.19,62.58 133.19,62.88 C247.1
SI_DDR3A_P: length 3.4
  TOP w0.114: C246.1 132.87,62.88 132.87,62.45 134.1,61.23 134.1,61.01 134.01,60.92 U39.18
SI_DDR3B_N: length 3.4
  TOP w0.114: U39.9 137.55,58.36 137.64,58.45 138.53,58.45 139.35,59.28 139.65,59.28 C262.1
SI_DDR3B_P: length 3.4
  TOP w0.114: U39.10 137.55,58.86 137.64,58.77 138.39,58.77 139.22,59.59 139.65,59.59 C259.1
SI_DDR3C_N: length 3.5
  TOP w0.114: C251.1 137.76,62.88 137.76,62.52 136.41,61.17 136.41,61.01 136.5,60.92 U39.13
SI_DDR3C_P: length 3.5
  TOP w0.114: U39.14 136.01,60.88 136.1,60.98 136.1,61.3 137.45,62.65 137.45,62.88 C250.1
SIG_EN_1: length 4.3
  TOP w0.127: R71.2 R70.1 34.12,121.13 U19.17
SIG_EN_2: length 4.3
  TOP w0.127: R128.2 R127.1 34.12,93.19 U29.17
SIG_EN_3: length 4.3
  TOP w0.127: R205.2 R204.1 34.12,65.25 U37.17
SIG_EN_4: length 4.3
  TOP w0.127: R267.2 R266.1 34.12,37.31 U48.17
SWAP/POL_1: length 2.9
  TOP w0.127: U19.1 v1(38.06,112.75)
  BOTTOM w0.127: R391.2 38.9,112.75 v1(38.06,112.75) 37.96,112.66 R389.1
SWAP/POL_2: length 2.9
  TOP w0.127: U29.1 v1(38.06,84.81)
  BOTTOM w0.127: R450.1 37.96,84.72 v1(38.06,84.81) 38.9,84.81 R452.2
SWAP/POL_3: length 2.9
  TOP w0.127: U37.1 v1(38.06,56.87)
  BOTTOM w0.127: R471.2 38.9,56.87 v1(38.06,56.87) 37.96,56.78 R470.1
SWAP/POL_4: length 2.9
  TOP w0.127: U48.1 v1(38.06,28.93)
  BOTTOM w0.127: R485.2 38.9,28.93 v1(38.06,28.93) 37.96,28.84 R484.1
SWCLK: length 35.9
  TOP w0.127: v1(216.03,46.67) 216.07,46.63 U43.37 ; J11.2 235.07,57.29 R221.2
  BOTTOM w0.127: J11.2 237.49,54.86 237.49,49.85 236.98,49.34 233.81,49.34 232.54,48.07 220.09,48.07 218.69,46.67 v1(216.03,46.67)
SWDIO: length 29.4
  TOP w0.127: v1(216.03,47.94) 216,47.97 U43.34 ; J11.4 235.19,54.62 R225.2
  BOTTOM w0.127: v1(216.03,47.94) 218.95,47.94 219.58,48.58 228.73,48.58 232.28,52.13 235.14,52.13 J11.4
TCK: length 43.8
  TOP w0.127: P1.AH12 v2(139.89,104.12)
  06_SIG2 w0.127: v2(139.89,104.12) 139.4,104.61 139.4,111.57 139.83,112 139.83,116.57 141.33,118.07 141.33,127.7 142.09,128.46 142.09,130.54 147.19,135.65 147.19,141.41 v1(148.08,142.3)
  BOTTOM w0.127: R699.1 v1(148.08,142.3)
TDI: length 43.7
  TOP w0.127: P1.AH13 v2(138.89,104.12)
  06_SIG2 w0.127: v2(138.89,104.12) 138.35,104.66 138.35,111.57 139.37,112.59 139.37,116.73 140.28,117.64 140.28,129.43 146.81,135.95 v1(146.81,142.3)
  BOTTOM w0.127: R702.1 v1(146.81,142.3)
TDO: length 42.9
  TOP w0.127: P1.AJ12 v2(139.89,105.12)
  06_SIG2 w0.127: v1(149.48,142.3) 148.59,141.41 148.59,135.8 142.88,130.09 142.88,117.47 140.69,115.28 140.69,106.64 140.34,106.29 140.34,105.57 v2(139.89,105.12)
  BOTTOM w0.127: R700.1 v1(149.48,142.3)
TMS: length 41
  TOP w0.127: P1.AL10 v2(141.89,107.12)
  06_SIG2 w0.127: v2(141.89,107.12) 141.89,109.44 142.32,109.87 142.32,114.87 144.32,116.87 144.32,128.69 151.26,135.62 151.26,141.92 v1(150.88,142.3)
  BOTTOM w0.127: R701.1 v1(150.88,142.3)
TRST: length 1.6
  TOP w0.102: P1.AL11 v2(139.89,107.12)
  BOTTOM w0.102: R400.1 140.13,107.12 v2(139.89,107.12)
TX_TERM_1: length 3.3
  TOP w0.127: U19.36 v1(28.61,112.75)
  BOTTOM w0.127: R393.2 27.87,112.01 v1(28.61,112.75) 29.16,112.2 R392.1
TX_TERM_2: length 3.2
  TOP w0.127: U29.36 v1(28.61,84.81)
  BOTTOM w0.127: R455.2 27.99,84.2 v1(28.61,84.81) 29.16,84.26 R454.1
TX_TERM_3: length 3.3
  TOP w0.127: U37.36 v1(28.61,56.87)
  BOTTOM w0.127: R472.1 29.16,56.32 v1(28.61,56.87) 27.87,56.13 R473.2
TX_TERM_4: length 3.3
  TOP w0.127: U48.36 v1(28.61,28.93)
  BOTTOM w0.127: R486.1 29.16,28.38 v1(28.61,28.93) 27.87,28.19 R487.2
UART_RXD: length 13.5
  TOP w0.127: U43.13 221.57,54.57 221.74,54.74 222.12,54.74 222.89,53.97 233.3,53.97 J11.3
UART_TXD: length 11.5
  TOP w0.127: U43.12 232.26,52.47 J11.5
VREF_DDR3_A: length 111.7
  TOP w0.102: 103.63,134.05 103.4,133.82 102.65,133.82 U10.M8 ; U11.M8 117.86,133.79 118.62,133.79 118.9,134.07
  TOP w0.152: U12.M8 132.33,133.82 131.67,133.82 131.57,133.92 130.68,133.92 130.43,133.67
  TOP w0.279: 115.44,144.72 115.71,144.45 U5.6
  TOP w0.381: 127.51,130.64 127.51,124.02 130.05,121.48 141.86,121.48 142.88,122.49 142.88,129.49 141.73,130.64 C66.1 138.74,130.64 U12.H1 ; 127.51,130.64 C65.1 123.5,130.64 U11.H1 ; 127.51,130.64 127.51,133.29 ; 127.51,133.29 127.51,136.97 126.75,137.73 119.25,137.73 ; 127.51,133.29 130.05,133.29 130.43,133.67 ; 104.14,137.73 112.27,137.73 ; 104.14,137.73 104.14,134.56 103.63,134.05 ; 104.14,137.73 104.14,140.53 108.01,144.4 C9.1 ; 112.27,137.73 119.25,137.73 ; 112.27,137.73 112.27,131.36 v3(111.12,130.22) 110.71,130.64 C64.1 108.26,130.64 U10.H1 ; 119.25,137.73 119.25,134.43 118.9,134.07 ; P1.M22 v2(129.89,87.12) ; P1.AC23 v2(127.92,99.09)
  BOTTOM w0.381: C579.1 129.39,86.63 v2(129.89,87.12) ; v2(127.92,99.09) 128.39,99.56 C445.1
VREF_DDR3_B: length 158.3
  TOP w0.152: 174.85,109.69 174.85,108.88 174.78,108.8 174.78,108.15 U22.M8 ; U16.M8 174.78,122.59 174.78,121.7 175.01,121.48 ; 174.76,137.08 174.76,137.85 U8.M8
  TOP w0.279: U14.6 185.4,124.63 185.67,124.9
  TOP w0.381: P1.AC12 v2(138.89,99.12) P1.AD12 v2(139.89,100.12) ; 178.69,128.21 171.94,128.21 171.18,128.97 C67.1 171.18,130.11 U8.H1 ; 178.69,128.21 178.69,134.96 ; 178.69,128.21 178.69,121.22 ; 171.18,112.97 174.09,112.97 ; 171.18,112.97 C124.1 171.18,114.87 U16.H1 ; 171.18,112.97 163.58,112.97 162.43,111.82 162.43,99.63 164.47,97.6 170.8,97.6 171.18,97.98 C149.1 171.18,99.63 U22.H1 ; 174.09,112.97 174.09,110.83 174.85,110.07 174.85,109.69 ; 174.09,112.97 178.31,112.97 178.69,113.35 178.69,121.22 ; 178.69,121.22 175.26,121.22 175.01,121.48 ; 178.69,134.96 176.85,134.96 v3(175.58,136.23) 174.76,137.04 174.76,137.08 ; 178.69,134.96 182.86,134.96 185.35,132.46 C58.1
  03_SIG1 w0.381: v3(175.58,136.23) 174.62,137.18 174.62,138.75 173.1,140.27 162.43,140.27 140.34,118.17
  BOTTOM w0.381: C448.1 140.38,99.63 v2(139.89,100.12) ; v2(138.89,99.12) 139.38,98.63 C464.1
VREF_DDR3_C: length 144.8
  TOP w0.127: 174.78,76.4 U32.M8
  TOP w0.152: 174.78,76.4 174.78,77.13 174.83,77.18 174.83,77.86 ; 174.88,62.52 174.88,61.89 174.78,61.79 174.78,61.16 U40.M8 ; 174.83,93.15 174.83,92.35 174.78,92.29 174.78,91.64 U28.M8
  TOP w0.279: U34.6 181.24,69.29 180.97,69.02
  TOP w0.381: 171.2,65.98 171.18,65.99 C231.1 171.18,67.88 U32.H1 ; 171.2,65.98 173.69,65.98 174.07,65.6 174.07,63.67 174.88,62.85 174.88,62.52 ; 171.2,65.98 162.31,65.98 ; 174.83,77.86 174.83,78.35 174.09,79.08 174.09,80.85 173.71,81.23 171.18,81.23 ; 171.18,81.23 C203.1 171.18,83.12 U28.H1 ; 171.18,81.23 162.31,81.23 ; 162.31,65.98 162.31,52.13 163.83,50.61 171.2,50.61 ; 162.31,65.98 162.31,81.23 ; U40.H1 171.18,52.64 C273.1 171.18,50.63 171.2,50.61 ; 162.31,81.23 162.31,93.54 165.23,96.46 v3(172.59,96.46) 173.74,96.46 174.17,96.02 174.17,94.12 174.83,93.45 174.83,93.15 ; v2(141.89,97.12) P1.AA10 ; v2(141.89,94.12) P1.V10 ; C253.1 181.3,53.85 178.05,50.61 171.2,50.61
  06_SIG2 w0.305: v2(141.89,94.12) 141.38,94.63 141.38,96.62 v2(141.89,97.12)
  BOTTOM w0.381: v2(141.89,94.12) 142.38,94.61 C492.1 ; C472.1 142.39,97.62 v2(141.89,97.12)
VTT_DDR3_A: length 2.2
  TOP w0.279: 120.4,143.95 119.89,143.45 U5.3 ; U5.5 120,144.45
  vias: v1(128.91,142.43) v1(130.3,142.43) v1(131.7,142.43) v1(133.48,142.43) v1(134.87,142.43) v1(136.27,142.43) v1(138.05,142.43) v1(139.45,142.43)
VTT_DDR3_B: length 2.2
  TOP w0.279: U14.3 184.4,120.46 184.91,119.95 ; U14.5 185.4,120.35
  vias: v1(183.39,111.44) v1(183.39,110.05) v1(183.39,108.65) v1(183.39,106.87) v1(183.39,105.47) v1(183.39,104.08) v1(183.39,102.3) v1(183.39,100.9)
VTT_DDR3_C: length 2.2
  TOP w0.279: U34.3 182.25,73.47 181.74,73.98 ; U34.5 181.24,73.58
  vias: v1(183.77,94.81) v1(183.77,93.41) v1(183.77,92.01) v1(183.77,90.23) v1(183.77,88.84) v1(183.77,87.44) v1(183.77,85.66) v1(183.77,84.26)
XTL25N: length 3.7
  TOP w0.127: U43.6 224.3,49.47 C281.2 225.98,50.08 Y5.1
XTL25N1: length 5.1
  TOP w0.127: Y4.1 132.95,52.6 C271.2 132.95,54.66 134.5,56.21 U39.2
XTL25N2: length 4.4
  TOP w0.127: Y2.1 90.45,90.5 C182.2 89.17,90.09 88.63,90.63 U26.2
XTL25P: length 6.2
  TOP w0.127: Y5.3 228.27,48.3 227.23,49.34 225.66,49.34 C284.2 224.54,48.97 U43.5
XTL25P1: length 8.2
  TOP w0.127: Y4.3 131.06,50.43 132.08,51.45 132.08,53.29 C270.2 131.72,54.17 131.95,54.17 134.01,56.22 U39.1
XTL25P2: length 7.3
  TOP w0.127: U26.1 88.52,90.13 C189.2 90.79,89.34 92.35,89.34 93.4,88.3 Y2.3
N22024981: length 1.6
  TOP w0.279: U5.9 114.87,142.95 R22.1
N22025053: length 4.8
  TOP w0.254: C111.2 181.75,120.46 183.26,120.46 183.4,120.6 U14.1
  TOP w0.279: C111.2 181.63,121.69 R76.1 181.66,122.89 R64.2
N22025271: length 1.6
  TOP w0.279: R61.1 183.9,125.48 U14.9
N22025327: length 4.8
  TOP w0.254: U34.1 183.25,73.33 183.39,73.47 184.89,73.47 C228.2
  TOP w0.279: C228.2 185.02,72.24 R178.1 184.98,71.04 R195.2
N22025525: length 1.6
  TOP w0.279: R198.1 182.74,68.45 U34.9
N22025799: length 1.5
  TOP w0.279: U5.7 114.74,143.95 R19.1
N22025867: length 1.5
  TOP w0.279: U14.7 184.9,125.6 R62.1
N22025914: length 1.5
  TOP w0.279: U34.7 181.75,68.32 R197.1
N22026405: length 3.3
  TOP w0.254: R272.1 R259.1 83.11,40.21 82.93,40.39 U45.5
N22026570: length 4.8
  TOP w0.254: C28.2 119.89,140.8 119.89,142.3 119.75,142.45 U5.1
  TOP w0.279: C28.2 118.66,140.67 R40.1 117.46,140.71 R38.2
N22030137:
  vias: v1(2.54,167.96) v1(7.62,167.96) v1(12.7,167.96) v1(17.78,167.96) v1(22.86,167.96) v1(27.94,167.96) v1(33.02,167.96) v1(38.1,167.96) v1(43.18,167.96) v1(48.26,167.96) v1(53.34,167.96) v1(58.42,167.96) v1(63.5,167.96) v1(68.58,167.96) v1(73.66,167.96) v1(78.74,167.96) v1(83.82,167.96) v1(88.9,167.96) v1(93.98,167.96) v1(99.06,167.96) v1(104.14,167.96) v1(109.22,167.96) v1(114.3,167.96) v1(119.38,167.96) v1(124.46,167.96) v1(129.54,167.96) v1(134.62,167.96) v1(139.7,167.96) v1(144.78,167.96) v1(149.86,167.96) v1(154.94,167.96) v1(160.02,167.96) v1(165.1,167.96) v1(170.18,167.96) v1(175.26,167.96) v1(180.34,167.96) v1(185.42,167.96) v1(190.5,167.96) v1(195.58,167.96) v1(200.66,167.96) v1(205.74,167.96) v1(210.82,167.96) v1(215.9,167.96) v1(220.98,167.96) v1(226.06,167.96) v1(231.14,167.96) v1(236.22,167.96) v1(241.3,167.96) v1(246.38,167.96) v1(251.46,167.96) v1(256.54,167.96)
N22030618: length 4.9
  TOP w0.254: U53.13 112.92,21.01 111.89,19.98 R312.2 110.73,19.29 R306.1 110.67,18.13 C384.2
N22030676: length 5.8
  TOP w0.254: R323.2 113.79,16.14 113.79,19.57 114.42,20.2 U53.16
N22030684: length 4.8
  TOP w0.254: R319.1 R313.2 115.42,19.08 U53.18
N22030720: length 4.9
  TOP w0.254: C378.1 117.02,18.92 117.02,20.33 116.46,20.89 116.46,21.87 116.2,22.13 U53.1
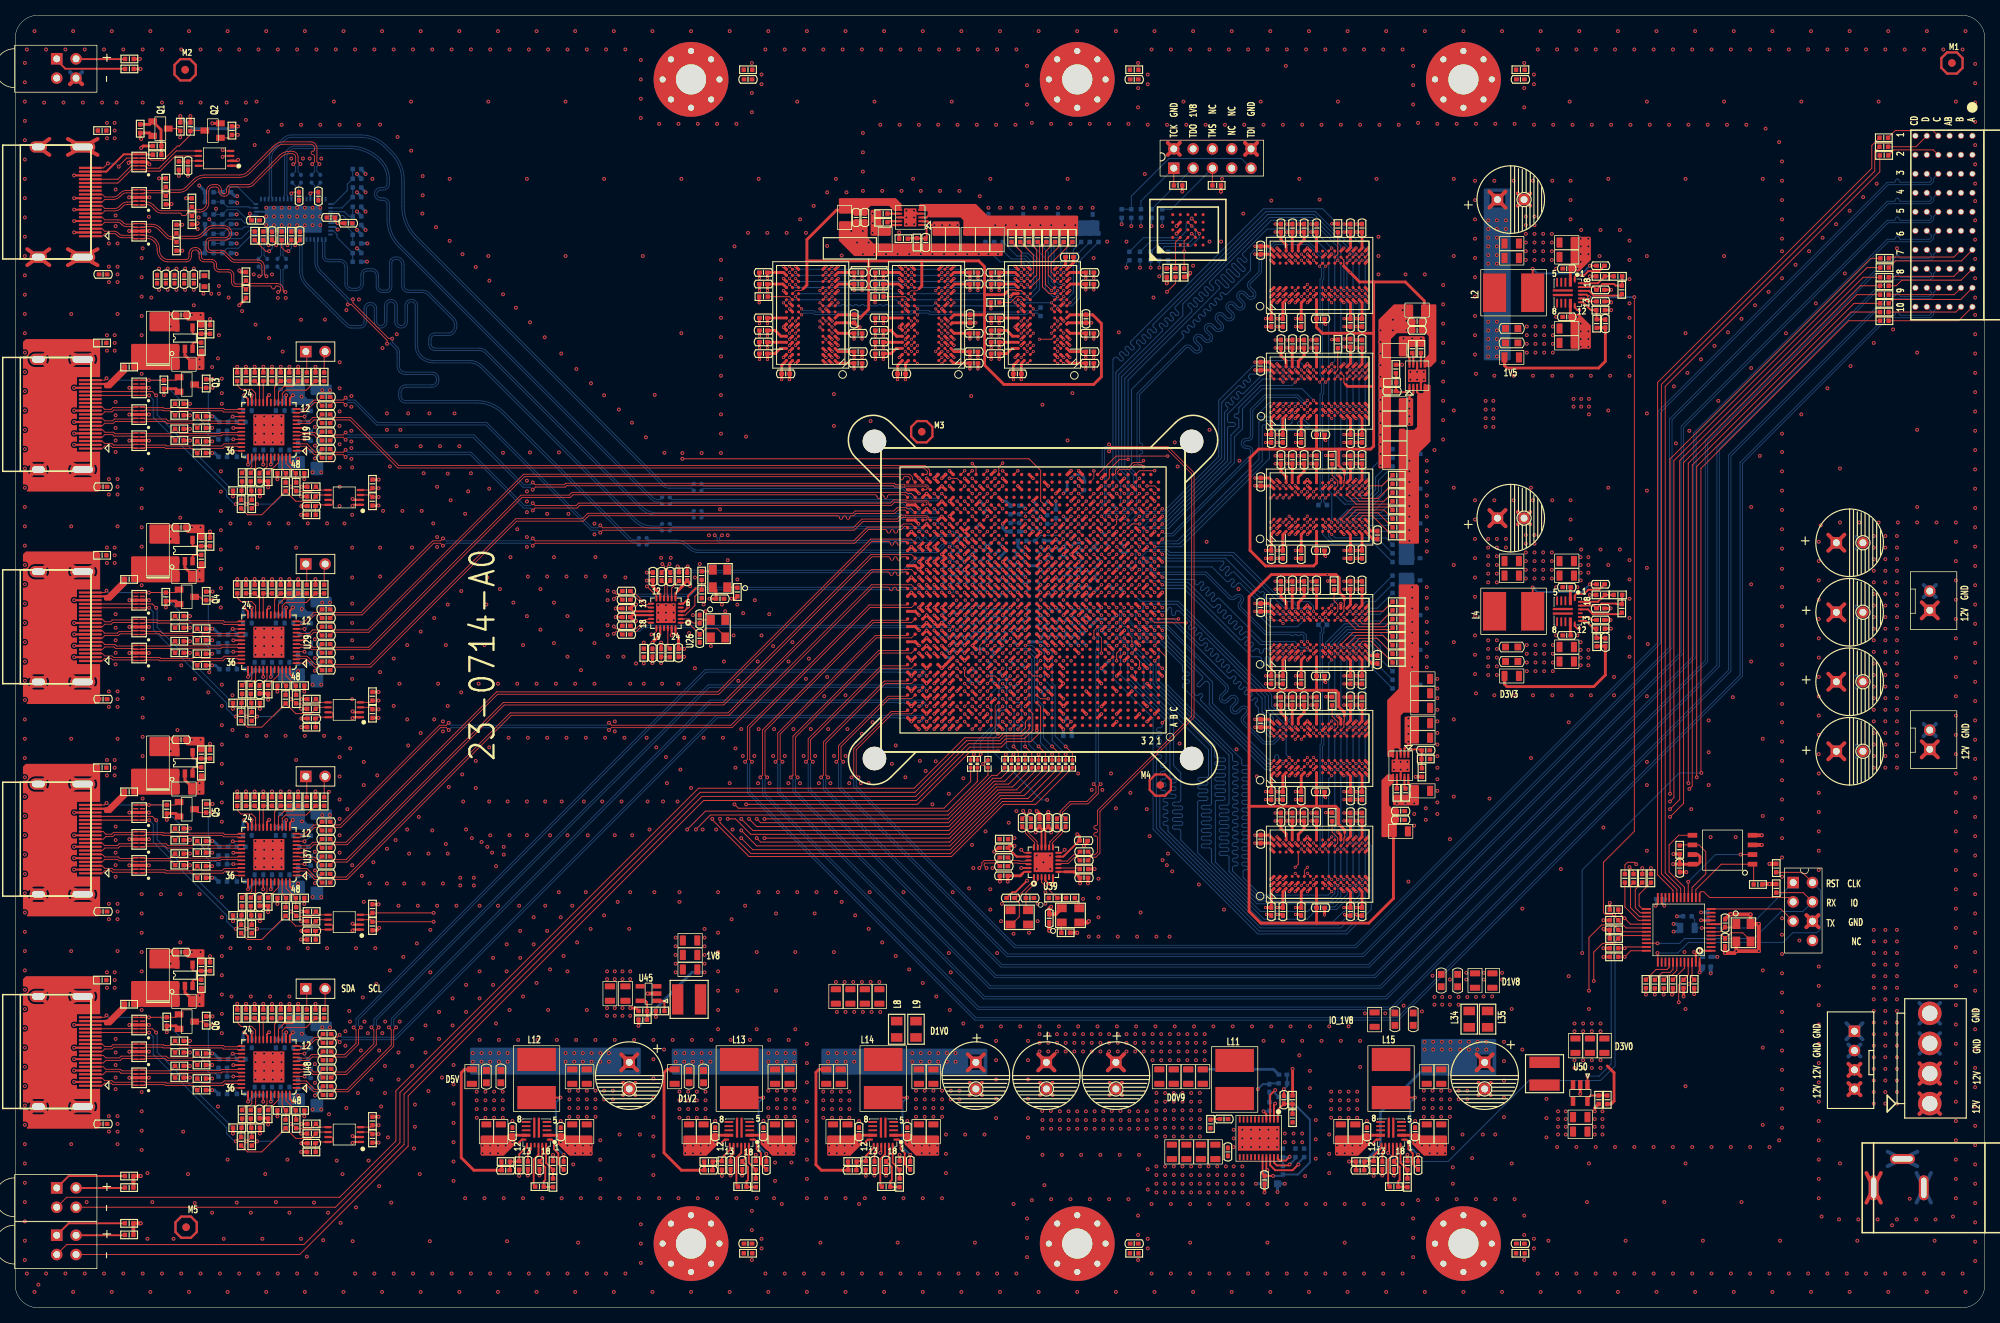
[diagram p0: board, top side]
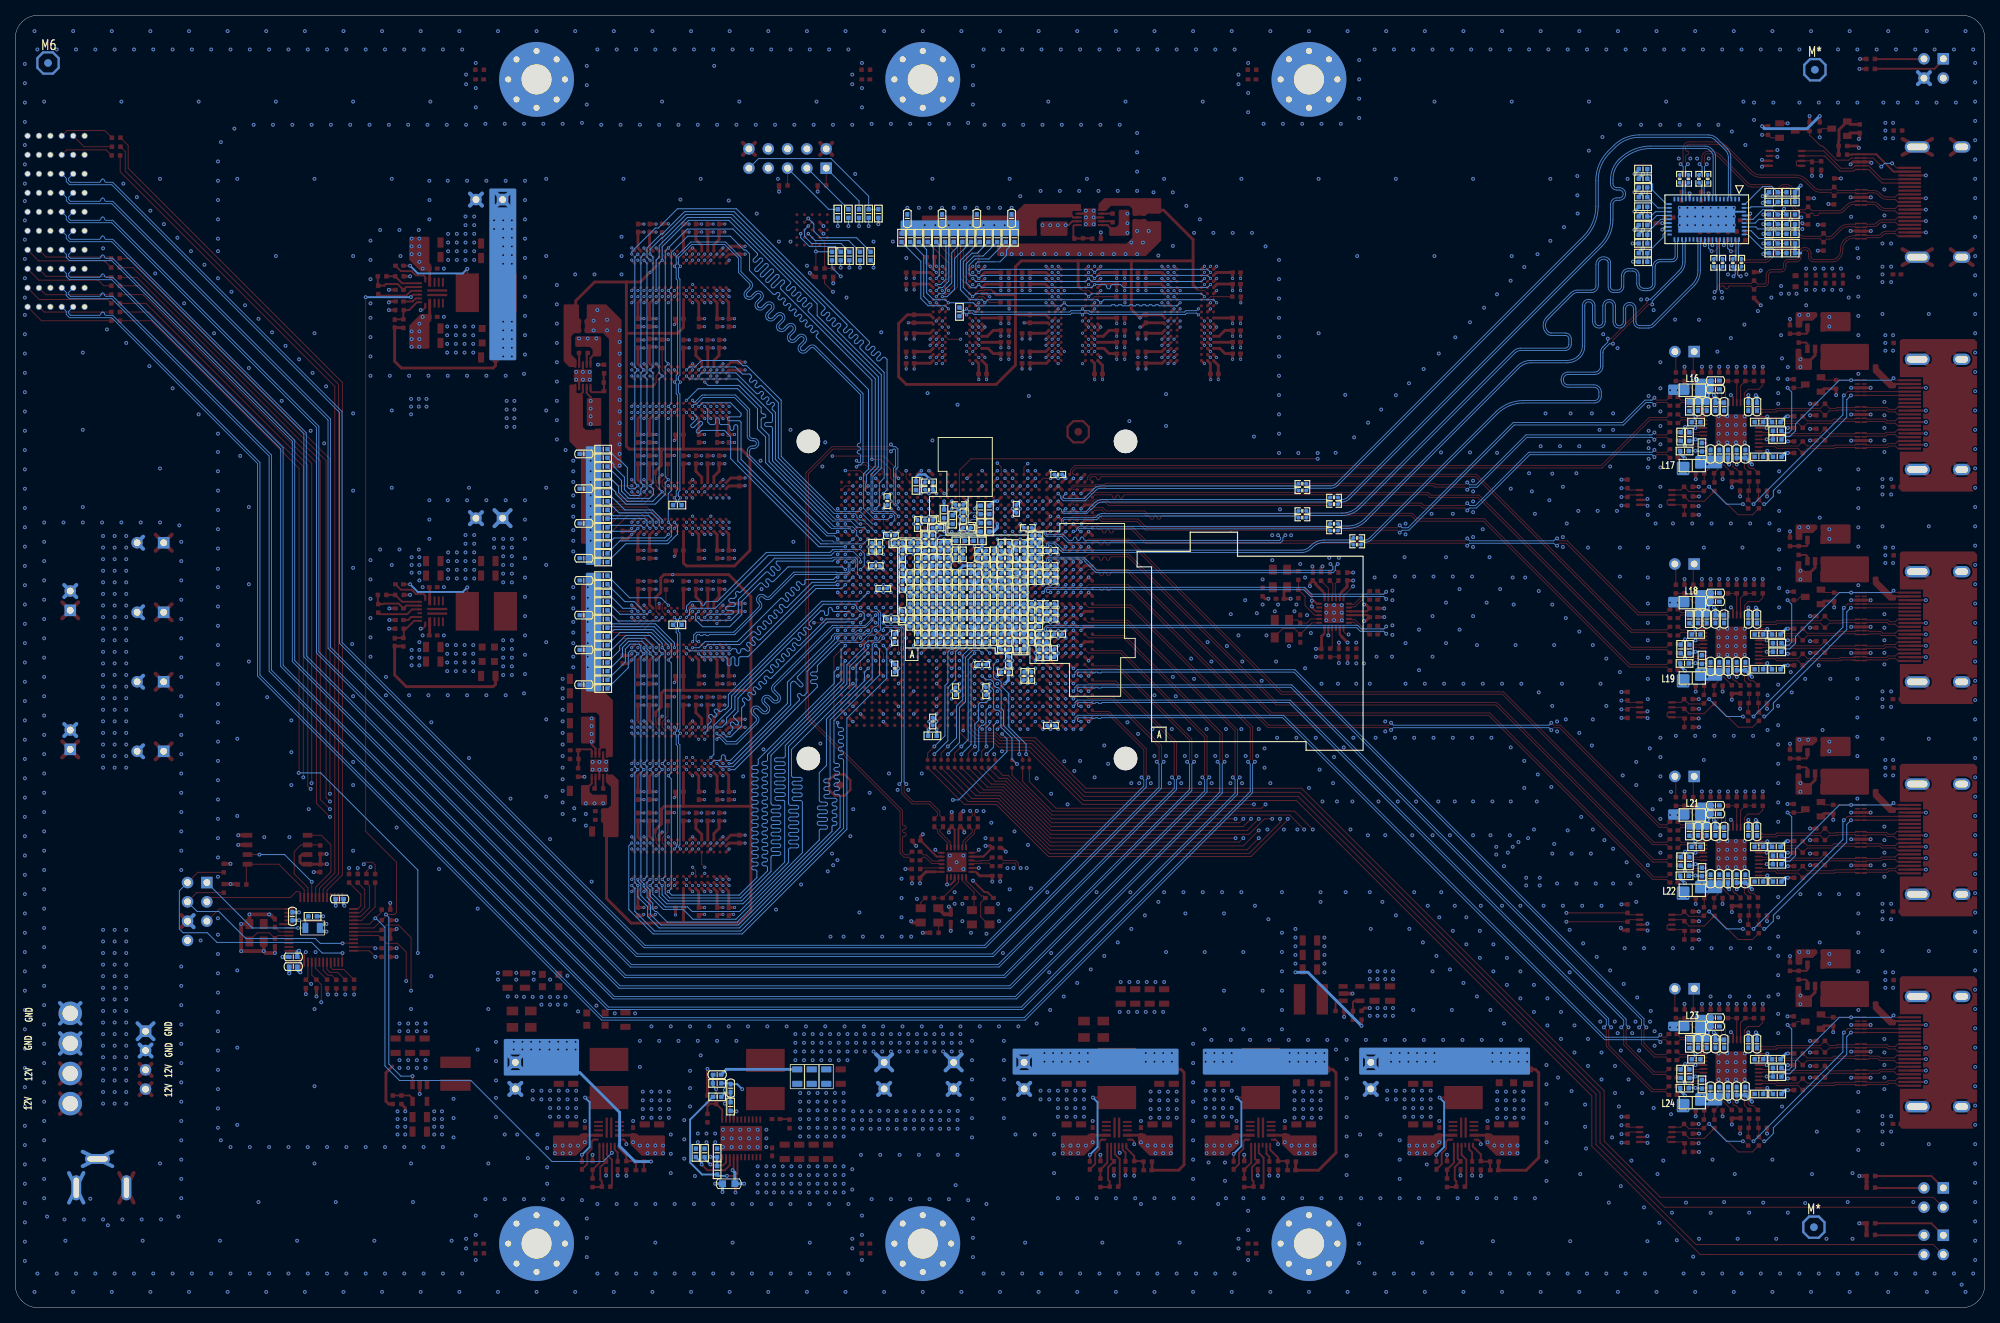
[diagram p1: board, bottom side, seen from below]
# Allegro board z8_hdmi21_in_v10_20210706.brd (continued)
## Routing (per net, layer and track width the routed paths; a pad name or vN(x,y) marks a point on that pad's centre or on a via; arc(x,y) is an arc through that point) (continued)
N22030722: length 12.2
  TOP w0.254: L14.1 v1(117.32,27.65) ; C378.2 v1(117.73,20.13)
  BOTTOM w0.254: v1(117.73,20.13) 116.71,21.15 116.71,27.05 v1(117.32,27.65)
N22030830: length 2.3
  TOP w0.254: U53.14 113.42,20.83 113.03,20.43 C376.1
N22030983: length 4.1
  TOP w0.254: U56.22 166.08,19.62 166.33,19.37 167.13,19.37 v1(167.64,19.88)
  BOTTOM w0.254: R493.1 R492.1 167.59,19.82 v1(167.64,19.88)
N22031161: length 3
  TOP w0.254: C334.2 v1(166.88,28.77)
  BOTTOM w0.254: C622.2 167.31,30.63 R483.1 167.31,29.2 v1(166.88,28.77)
N22031163: length 3.1
  BOTTOM w0.254: v1(163.45,28.77) 164.1,29.42 C626.2 165.08,29.53 R483.2
N22031238: length 6.4
  TOP w0.254: U57.3 14.38,15.77 R325.2
N22031240: length 9.6
  TOP w0.254: R316.2 7.03,17.34 U57.1
N22031335: length 5.2
  TOP w0.254: v1(165.74,28.64) 165.08,27.98 U56.3
  BOTTOM w0.254: v1(165.74,28.64) 165.74,28.2 R488.2
N22031337: length 2
  TOP w0.254: v1(164.21,25.84) 164.58,25.48 U56.4
  BOTTOM w0.254: v1(164.21,25.84) 164.9,25.84 R489.2
N22031349: length 1.3
  TOP w0.254: R293.2 157.3,24.83 C336.1
N22031384: length 4.3
  TOP w0.254: U56.21 165.58,19.11 165.96,18.73 167.51,18.73 v1(167.64,18.86)
  BOTTOM w0.254: v1(167.64,18.86) 168.4,19.62 R491.1
N22031400: length 6.6
  TOP w0.254: U56.20 165.08,18.76 165.74,18.1 168.02,18.1 v1(168.78,18.86)
  BOTTOM w0.254: v1(168.78,18.86) 168.78,19.06 R490.1
N22031488: length 1.3
  BOTTOM w0.254: C626.1 R489.1
N22031700:
  vias: v1(2.54,2.1) v1(7.62,2.1) v1(12.7,2.1) v1(17.78,2.1) v1(22.86,2.1) v1(27.94,2.1) v1(33.02,2.1) v1(38.1,2.1) v1(43.18,2.1) v1(48.26,2.1) v1(53.34,2.1) v1(58.42,2.1) v1(63.5,2.1) v1(68.58,2.1) v1(73.66,2.1) v1(78.74,2.1) v1(83.82,2.1) v1(88.9,2.1) v1(93.98,2.1) v1(99.06,2.1) v1(104.14,2.1) v1(109.22,2.1) v1(114.3,2.1) v1(119.38,2.1) v1(124.46,2.1) v1(129.54,2.1) v1(134.62,2.1) v1(139.7,2.1) v1(144.78,2.1) v1(149.86,2.1) v1(154.94,2.1) v1(160.02,2.1) v1(165.1,2.1) v1(170.18,2.1) v1(175.26,2.1) v1(180.34,2.1) v1(185.42,2.1) v1(190.5,2.1) v1(195.58,2.1) v1(200.66,2.1) v1(205.74,2.1) v1(210.82,2.1) v1(215.9,2.1) v1(220.98,2.1) v1(226.06,2.1) v1(231.14,2.1) v1(236.22,2.1) v1(241.3,2.1) v1(246.38,2.1) v1(251.46,2.1) v1(256.54,2.1)
N22047900: length 2.8
  TOP w0.381: v2(122.89,87.12) P1.M28 ; v2(123.89,87.12) P1.M27
  BOTTOM w0.381: v2(123.89,87.12) P1.M28 R443.2 123.38,87.62 v2(122.89,87.12)
N22048190: length 1.4
  TOP w0.381: P1.AP29 v2(121.89,109.12)
  BOTTOM w0.381: P1.AP29 v2(121.89,109.12)
N22048192: length 1.4
  TOP w0.381: P1.A29 v2(121.89,76.12)
  BOTTOM w0.381: v2(121.89,76.12) 122.33,76.57 R461.2
N22048413: length 1.6
  TOP w0.381: P1.A14 v2(137.89,76.12)
  BOTTOM w0.381: L20.1 137.87,76.1 v2(137.89,76.12)
N22049180: length 4.8
  TOP w0.127: U39.3 135.01,55.99 R228.2 R229.2
N22049282: length 2.9
  TOP w0.127: U39.8 139.89,57.86 R222.1
N22049606: length 1.4
  TOP w0.127: R246.2 137.61,50.64 Y3.1
N22053758: length 3.7
  TOP w0.127: U12.L8 132.33,133.02 131.71,133.02 130.96,132.27 R50.2
N22054851: length 1.4
  TOP w0.127: P1.F25 v2(125.89,82.12)
  BOTTOM w0.381: R457.1 v2(125.89,82.12)
N22055520: length 3.4
  TOP w0.127: R48.2 99,133.02 101.85,133.02 U10.L8
N22056050: length 3.4
  TOP w0.127: R49.2 114.24,133.02 117.09,133.02 U11.L8
N22061318: length 3.4
  TOP w0.127: R23.2 173.98,141.47 173.98,138.63 U8.L8
N22061537: length 1.4
  TOP w0.127: v2(144.89,105.12) P1.AJ7
  BOTTOM w0.381: R403.1 144.39,105.61 v2(144.89,105.12)
N22061744: length 3.4
  TOP w0.127: U16.L8 173.98,123.39 173.98,126.23 R59.2
N22062524: length 3.7
  TOP w0.127: R89.2 173.23,109.51 173.98,108.76 173.98,108.15 U22.L8
N22067825: length 1.4
  TOP w0.127: P1.K7 v2(143.89,85.12)
  BOTTOM w0.381: R453.1 v2(143.89,85.12)
N22068466: length 3.7
  TOP w0.127: R212.2 173.23,62.57 173.96,61.84 173.96,61.14 U40.L8
N22069069: length 3.6
  TOP w0.127: U28.L8 173.98,91.64 173.98,92.52 173.48,93.01 R121.2
N22069811: length 3.7
  TOP w0.127: U32.L8 173.98,76.4 173.98,77.06 173.23,77.81 R168.2
N22071827: length 21.3
  BOTTOM w0.127: R406.2 R702.2 146.81,146.24 151.77,151.19 161.3,151.19 J4.9
N22071832: length 11.1
  TOP w0.127: J4.5 157.48,149.93 R15.2
  BOTTOM w0.127: R701.2 152.07,144.52 J4.5
N22072215: length 9.5
  TOP w0.127: J4.1 152.4,149.93 R14.2
  BOTTOM w0.127: R699.2 148.08,145.61 J4.1
N22072232: length 7.7
  BOTTOM w0.127: R700.2 154.89,149.93 J4.3
N22082350: length 1.4
  TOP w0.102: P1.Y18 v2(132.89,96.12)
  BOTTOM w0.381: R429.2 132.39,96.62 v2(132.89,96.12)
N22082686: length 5.8
  TOP w0.102: v2(134.9,96.14) P1.Y17
  06_SIG2 w0.102: v2(134.9,100.11) 135.38,99.63 135.38,96.62 v2(134.9,96.14)
  BOTTOM w0.381: v2(134.9,100.11) 135.38,99.63 R425.2
N22086073: length 11.8
  TOP w0.127: JT1.A10 255.63,129.86 R54.2
N22086076: length 9.9
  TOP w0.127: JT1.B9 255.06,133.29 R47.2
N22086079: length 11.9
  TOP w0.127: R51.2 246.94,132.65 255.92,132.65 JT1.A9
N22086210: length 9.8
  TOP w0.127: R53.2 255.27,131 JT1.B10
N22090777: length 6.4
  TOP w0.254: U58.3 14.38,9.55 R327.2
N22090779: length 9.6
  TOP w0.254: R326.2 7.03,11.11 U58.1
N22318019: length 3.7
  TOP w0.114: C130.2 39.96,114.52 39.59,114.52 39.27,114.84 37.51,114.84 37.42,114.75 U19.5
N22318021: length 3.7
  TOP w0.114: C122.2 39.96,114.84 39.72,114.84 39.4,115.16 37.51,115.16 37.42,115.25 U19.6
N22318023: length 4.1
  TOP w0.114: U19.2 37.39,113.25 37.49,113.34 38.26,113.34 39.36,112.24 39.96,112.24 C133.2
N22318025: length 4.1
  TOP w0.114: U19.3 37.39,113.75 37.48,113.66 38.39,113.66 39.5,112.55 39.96,112.55 C132.2
N22318199: length 28.6
  TOP w0.508: 6.92,123.73 J6.MTG1 ; J6.MTG1 6.92,125.84 ; J6.MTG1 10.83,125.84 ; J6.MTG1 10.83,123.73 ; J6.MTG4 4.49,109.23 ; J6.MTG4 1.58,111.34 ; J6.MTG4 1.58,109.23 ; J6.MTG4 4.49,111.34 ; 6.92,109.23 J6.MTG2 ; J6.MTG2 10.83,111.34 ; J6.MTG2 6.92,111.34 ; J6.MTG2 10.83,109.23 ; 4.49,123.73 J6.MTG3 4.49,125.84
N22318292: length 4.7
  TOP w0.127: U21.7 41.66,106.29 41.78,106.16 41.78,105.76 41.66,105.64 U21.8 39.65,105.64 C144.2 39.49,104.36 R110.1
N22318294: length 3.8
  TOP w0.114: C120.2 39.96,116.81 39.27,116.81 38.81,116.34 37.51,116.34 37.42,116.25 U19.8
N22318980: length 3.8
  TOP w0.114: U19.9 37.44,116.75 37.53,116.66 38.68,116.66 39.14,117.13 39.96,117.13 C117.2
N22318988: length 4.1
  TOP w0.114: C115.2 39.96,119.09 39.4,119.09 38.15,117.84 37.49,117.84 37.4,117.75 U19.11
N22318990: length 4.1
  TOP w0.114: U19.12 37.41,118.25 37.5,118.16 38.02,118.16 39.27,119.41 39.96,119.41 C113.2
N22319096: length 4.6
  TOP w0.127: U19.22 31.62,120.33 31.12,120.84 29.72,120.84 29.21,121.35 R65.2
N22319158: length 2.6
  TOP w0.127: U19.45 34.62,111.2 R95.1
N22319174: length 2.6
  TOP w0.127: U19.42 33.12,110.66 32.89,110.43 32.75,110.43 C141.1
N22319555: length 2.1
  TOP w0.305: J6.18 12.01,121.53
N22319599: length 1.9
  TOP w0.254: R60.2 23.5,126.99 23.32,126.81 U13.3
N22319611: length 3
  TOP w0.254: U13.4 23.32,128.27 23.45,128.15 R56.1 R57.1
N22336290: length 3.7
  TOP w0.114: U29.5 37.42,86.81 37.51,86.9 38.7,86.9 39.02,86.58 39.96,86.58 C194.2
N22336292: length 3.7
  TOP w0.114: U29.6 37.42,87.31 37.51,87.22 38.83,87.22 39.15,86.9 39.96,86.9 C191.2
N22336294: length 4.1
  TOP w0.114: C202.2 39.96,84.3 39.36,84.3 38.26,85.4 37.49,85.4 37.39,85.31 U29.2
N22336296: length 4.1
  TOP w0.114: C199.2 39.96,84.61 39.5,84.61 38.39,85.72 37.48,85.72 37.39,85.81 U29.3
N22336470: length 28.6
  TOP w0.508: 6.92,81.29 J8.MTG2 ; J8.MTG2 10.83,83.4 ; J8.MTG2 6.92,83.4 ; J8.MTG2 10.83,81.29 ; 4.49,97.9 J8.MTG3 4.49,95.79 ; 6.92,95.79 J8.MTG1 ; J8.MTG1 10.83,95.79 ; J8.MTG1 10.83,97.9 ; J8.MTG1 6.92,97.9 ; 1.58,83.4 J8.MTG4 ; J8.MTG4 4.49,83.4 ; J8.MTG4 4.49,81.29 ; J8.MTG4 1.58,81.29
N22336560: length 4.7
  TOP w0.127: R175.1 39.49,76.42 C222.2 39.65,77.7 U31.8 41.66,77.7 41.78,77.82 41.78,78.22 41.66,78.35 U31.7
N22336562: length 3.8
  TOP w0.114: U29.8 37.42,88.31 37.51,88.4 38.81,88.4 39.27,88.87 39.96,88.87 C187.2
N22337251: length 3.8
  TOP w0.114: U29.9 37.44,88.81 37.53,88.72 38.68,88.72 39.14,89.19 39.96,89.19 C185.2
N22337253: length 4.1
  TOP w0.114: C181.2 39.96,91.15 39.4,91.15 38.15,89.9 37.49,89.9 37.4,89.81 U29.11
N22337255: length 4.1
  TOP w0.114: C178.2 39.96,91.47 39.27,91.47 38.02,90.22 37.5,90.22 37.41,90.31 U29.12
N22337367: length 4.6
  TOP w0.127: R122.2 29.21,93.41 29.72,92.9 31.12,92.9 31.62,92.39 U29.22
N22337429: length 2.6
  TOP w0.127: U29.45 34.62,83.26 R163.1
N22337445: length 2.6
  TOP w0.127: U29.42 33.12,82.72 32.89,82.49 32.75,82.49 C212.1
N22337826: length 2.1
  TOP w0.279: 12.01,93.59 J8.18
N22337863: length 1.9
  TOP w0.254: R117.2 23.5,99.05 23.32,98.87 U23.3
N22337874: length 3
  TOP w0.254: R115.1 R114.1 23.45,100.21 23.32,100.33 U23.4
N22341695: length 3.7
  TOP w0.114: U37.5 37.42,58.87 37.51,58.96 39.27,58.96 39.59,58.64 39.96,58.64 C263.2
N22341697: length 3.7
  TOP w0.114: C260.2 39.96,58.96 39.72,58.96 39.4,59.28 37.51,59.28 37.42,59.37 U37.6
N22341699: length 4.1
  TOP w0.114: U37.2 37.39,57.37 37.49,57.46 38.26,57.46 39.36,56.36 39.96,56.36 C269.2
N22341701: length 4.1
  TOP w0.114: C266.2 39.96,56.67 39.5,56.67 38.39,57.78 37.48,57.78 37.39,57.87 U37.3
N22341875: length 28.6
  TOP w0.508: J10.MTG4 4.49,55.46 ; J10.MTG4 1.58,55.46 ; J10.MTG4 1.58,53.35 ; J10.MTG4 4.49,53.35 ; J10.MTG2 10.83,53.35 ; J10.MTG2 6.92,55.46 ; J10.MTG2 10.83,55.46 ; J10.MTG2 6.92,53.35 ; J10.MTG1 10.83,67.85 ; J10.MTG1 6.92,67.85 ; J10.MTG1 10.83,69.96 ; J10.MTG1 6.92,69.96 ; 4.49,67.85 J10.MTG3 4.49,69.96
N22341965: length 4.7
  TOP w0.127: R248.1 39.49,48.48 C282.2 39.65,49.76 U42.8 41.66,49.76 41.78,49.88 41.78,50.28 41.66,50.41 U42.7
N22341967: length 3.8
  TOP w0.114: U37.8 37.42,60.37 37.51,60.46 38.81,60.46 39.27,60.93 39.96,60.93 C257.2
N22342656: length 3.8
  TOP w0.114: U37.9 37.44,60.87 37.53,60.78 38.68,60.78 39.14,61.25 39.96,61.25 C254.2
N22342658: length 4.1
  TOP w0.114: C252.2 39.96,63.21 39.4,63.21 38.15,61.96 37.49,61.96 37.4,61.87 U37.11
N22342660: length 4.1
  TOP w0.114: C245.2 39.96,63.53 39.27,63.53 38.02,62.28 37.5,62.28 37.41,62.37 U37.12
N22342772: length 4.6
  TOP w0.127: U37.22 31.62,64.45 31.12,64.96 29.72,64.96 29.21,65.47 R199.2
N22342834: length 2.6
  TOP w0.127: U37.45 34.62,55.32 R232.1
N22342850: length 2.6
  TOP w0.127: U37.42 33.12,54.78 32.89,54.55 32.75,54.55 C272.1
N22343231: length 2.1
  TOP w0.305: J10.18 12.01,65.65
N22343268: length 1.9
  TOP w0.254: U33.3 23.32,70.93 23.5,71.11 R194.2
N22343279: length 3
  TOP w0.254: U33.4 23.32,72.39 23.45,72.27 R176.1 R177.1
N22346984: length 3.9
  TOP w0.114: U48.5 37.45,30.93 37.54,31.02 38.82,31.02 39.14,30.7 40.08,30.7 C331.2
N22347001: length 3.9
  TOP w0.114: U48.6 37.44,31.43 37.53,31.34 38.95,31.34 39.27,31.02 40.08,31.02 C302.2
N22347003: length 4.2
  TOP w0.114: U48.2 37.42,29.43 37.51,29.52 38.16,29.52 39.27,28.42 40.08,28.42 C333.2
N22347005: length 4.2
  TOP w0.114: U48.3 37.42,29.93 37.51,29.84 38.3,29.84 39.4,28.73 40.08,28.73 C332.2
N22347179: length 28.6
  TOP w0.508: 1.58,27.52 J14.MTG4 ; J14.MTG4 4.49,27.52 ; J14.MTG4 1.58,25.41 ; J14.MTG4 4.49,25.41 ; 6.92,42.02 J14.MTG1 ; J14.MTG1 10.83,39.91 ; J14.MTG1 10.83,42.02 ; J14.MTG1 6.92,39.91 ; 6.92,27.52 J14.MTG2 ; J14.MTG2 10.83,27.52 ; J14.MTG2 6.92,25.41 ; J14.MTG2 10.83,25.41 ; 4.49,39.91 J14.MTG3 4.49,42.02
N22347257: length 4.7
  TOP w0.127: U55.7 41.66,22.47 41.78,22.34 41.78,21.94 41.66,21.82 U55.8 39.65,21.82 C364.2 39.49,20.54 R303.1
N22347259: length 3.9
  TOP w0.114: U48.8 37.42,32.43 37.51,32.52 38.62,32.52 39.09,32.99 40.08,32.99 C301.2
N22347960: length 3.9
  TOP w0.114: U48.9 37.41,32.93 37.5,32.84 38.49,32.84 38.96,33.31 40.08,33.31 C300.2
N22347962: length 4.2
  TOP w0.114: C296.2 40.08,35.27 39.47,35.27 38.22,34.02 37.52,34.02 37.42,33.93 U48.11
N22347964: length 4.2
  TOP w0.114: C295.2 40.08,35.59 39.34,35.59 38.09,34.34 37.48,34.34 37.39,34.43 U48.12
N22348076: length 4.6
  TOP w0.127: R261.2 29.21,37.53 29.72,37.02 31.12,37.02 31.62,36.51 U48.22
N22348138: length 2.6
  TOP w0.127: U48.45 34.62,27.38 R290.1
N22348154: length 2.6
  TOP w0.127: C335.1 32.75,26.61 32.89,26.61 33.12,26.84 U48.42
N22348531: length 2.1
  TOP w0.305: J14.18 12.01,37.71
N22348572: length 1.9
  TOP w0.254: R257.2 23.5,43.17 23.32,42.99 U44.3
N22348576: length 3
  TOP w0.254: U44.4 23.32,44.45 23.45,44.33 R251.1 R252.1
N22353387: length 6.1
  TOP w0.127: U26.3 88.14,91.13 89.41,92.39 89.41,93.59 R134.2 R118.2
N22353420: length 2.7
  TOP w0.127: R119.1 86.35,94.68 U26.8
N22353722: length 1.4
  TOP w0.127: R133.2 94.94,94.79 Y1.1
N22359824: length 2.8
  TOP w0.381: v2(122.89,91.12) P1.T28 ; v2(123.89,91.12) P1.T27
  BOTTOM w0.381: v2(123.89,91.12) 123.39,91.61 R434.2 P1.T28 v2(122.89,91.12)
N22360101: length 2.8
  TOP w0.381: P1.Y27 v2(123.89,96.12) ; P1.Y28 v2(122.89,96.12)
  BOTTOM w0.381: v2(123.89,96.12) 123.89,96.13 R427.2 122.89,96.12 v2(122.89,96.12)
N22376675: length 28.6
  TOP w0.508: 6.92,153.78 HDMI1.MTG1 ; HDMI1.MTG1 10.83,151.67 ; HDMI1.MTG1 10.83,153.78 ; HDMI1.MTG1 6.92,151.67 ; HDMI1.MTG4 4.49,137.17 ; HDMI1.MTG4 4.49,139.28 ; HDMI1.MTG4 1.58,139.28 ; HDMI1.MTG4 1.58,137.17 ; 4.49,153.78 HDMI1.MTG3 4.49,151.67 ; 6.92,137.17 HDMI1.MTG2 ; HDMI1.MTG2 6.92,139.28 ; HDMI1.MTG2 10.83,139.28 ; HDMI1.MTG2 10.83,137.17
N22380384: length 4.5
  TOP w0.127: R13.1 21.6,150.76 C4.2 22.86,150.89 U2.7 24.67,150.89 24.79,150.77 24.79,150.37 24.67,150.24 U2.8
N22381237: length 3.4
  BOTTOM w0.127: R349.1 43.13,143.7 U59.22
N22381770: length 1.7
  TOP w0.127: R27.2 32.65,140.47 v1(33.33,139.79)
  BOTTOM w0.127: U59.43 v1(33.33,139.79)
N22381784: length 4.3
  TOP w0.127: v1(33.4,139) 32.97,139 R26.2
  BOTTOM w0.127: v1(33.4,139) 33.42,139 33.83,139.4 U59.42
N22381826: length 1.6
  TOP w0.127: v1(35.83,139.79) 35.83,139.98 R29.2
  BOTTOM w0.127: U59.38 v1(35.83,139.79)
N22381836: length 3.8
  TOP w0.127: v1(35.93,139.01) 35.55,139.01 35.05,139.51 R28.2
  BOTTOM w0.127: v1(35.93,139.01) 36.33,139.4 U59.37
N22382472: length 1.7
  TOP w0.254: C20.1 34.33,139.96 v1(34.33,139.79)
  BOTTOM w0.254: U59.41 v1(34.33,139.79)
N22382559: length 1.7
  TOP w0.254: v1(36.83,139.79) 36.83,139.87 C21.1
  BOTTOM w0.254: U59.36 v1(36.83,139.79)
N22383207: length 1.8
  TOP w0.127: C5.1 36.48,146.77 v1(36.33,146.61)
  BOTTOM w0.254: U59.9 v1(36.33,146.61)
N22383495: length 1.9
  TOP w0.127: C6.1 38.98,146.77 v1(38.83,146.61)
  BOTTOM w0.254: U59.14 v1(38.83,146.61)
N22383981: length 1.9
  TOP w0.254: v1(30.86,143.95) 30.86,143.3 C12.1
  BOTTOM w0.254: U59.51 31.12,143.7 v1(30.86,143.95)
N22398516: length 6.7
  TOP w0.381: R9.1 17.69,155.69 Q1.1 19.18,154.98 19.18,153.57 19.23,153.51 R6.2 R12.2
N22432680: length 2.1
  TOP w0.102: P1.B13 v2(138.89,77.12) P1.A13
  BOTTOM w0.127: P1.A13 v2(138.89,77.12)
N22449821: length 4.8
  TOP w0.254: U54.18 182.22,19.08 R315.2 R320.1
N22449835: length 4.9
  TOP w0.254: C381.1 183.83,18.91 183.83,20.32 183.26,20.89 183.26,21.87 183.01,22.13 U54.1
N22449837: length 12.2
  TOP w0.254: L15.1 v1(184.12,27.65) ; v1(184.53,20.13) C381.2
  BOTTOM w0.254: v1(184.53,20.13) 183.52,21.15 183.52,27.05 v1(184.12,27.65)
N22449845: length 4.9
  TOP w0.254: U54.13 179.72,21.04 178.69,20 R314.2 177.53,19.29 R307.1 177.44,19.2 C385.2
N22449937: length 2.3
  TOP w0.254: U54.14 180.22,20.83 179.83,20.43 C379.1
N22450190: length 5.8
  TOP w0.254: U54.16 181.22,20.13 180.59,19.49 180.59,16.14 R324.2
N22451830: length 4.8
  TOP w0.254: R136.1 R135.2 208.19,92.88 U25.18
N22451844: length 5
  TOP w0.254: C164.1 208.35,94.48 206.93,94.48 206.38,93.92 205.36,93.92 205.14,93.7 U25.1
N22451846: length 12.2
  TOP w0.254: C164.2 v1(207.14,95.19) ; L4.1 v1(199.61,94.77)
  BOTTOM w0.254: v1(207.14,95.19) 206.12,94.17 200.21,94.17 v1(199.61,94.77)
N22451862: length 4.9
  TOP w0.254: C190.2 209.13,88.13 R151.1 207.97,88.18 R147.2 207.65,89.34 206.61,90.38 U25.13
N22451950: length 2.3
  TOP w0.254: U25.14 207,90.88 207.39,90.49 C183.1
N22452196: length 5.8
  TOP w0.254: R140.2 211.13,91.25 207.52,91.25 206.89,91.88 U25.16
N22462383: length 2.2
  TOP w0.254: R260.2 85.4,40.13 85.14,40.39 U45.1
N22647853: length 4.8
  TOP w0.254: R317.1 R309.2 69.83,19.08 U51.18
N22647875: length 4.9
  TOP w0.254: U51.1 70.61,22.13 70.87,21.87 70.87,20.89 71.44,20.32 71.44,18.91 C372.1
N22647877: length 12.2
  TOP w0.254: L12.1 v1(71.72,27.65) ; v1(72.14,20.13) C372.2
  BOTTOM w0.254: v1(72.14,20.13) 71.12,21.15 71.12,27.05 v1(71.72,27.65)
N22647893: length 4.9
  TOP w0.254: U51.13 67.33,21.22 66.29,20.19 R308.2 66.24,19.24 R304.1 65.08,18.13 C382.2
N22647973: length 2.3
  TOP w0.254: U51.14 67.83,20.83 67.44,20.43 C370.1
N22648227: length 5.8
  TOP w0.254: R321.2 68.2,16.14 68.2,19.49 68.83,20.13 U51.16
N22660428: length 2.9
  TOP w0.127: R254.1 219.57,44.68 U43.44
N22766072: length 4.8
  TOP w0.254: U52.18 96.5,19.08 R311.2 R318.1
N22766094: length 4.9
  TOP w0.254: U52.1 97.28,22.13 97.54,21.87 97.54,20.89 98.09,20.33 98.09,18.92 C375.1
N22766096: length 12.2
  TOP w0.254: v1(98.39,27.65) L13.1 ; v1(98.81,20.26) C375.2
  BOTTOM w0.254: v1(98.81,20.26) 97.79,21.27 97.79,27.05 v1(98.39,27.65)
N22766112: length 4.9
  TOP w0.254: C383.2 91.75,18.13 R305.1 91.8,19.29 R310.2 92.96,19.75 94,20.78 U52.13
N22766192: length 2.3
  TOP w0.254: U52.14 94.5,20.27 94.11,19.88 C373.1
N22766425: length 5.8
  TOP w0.254: R322.2 94.87,16.14 94.87,19.75 95.5,20.38 U52.16
N22768217: length 4.8
  TOP w0.254: R45.1 R44.2 208.19,134.79 U9.18
N22768239: length 5
  TOP w0.254: C35.1 208.35,136.39 206.93,136.39 206.38,135.83 205.36,135.83 205.14,135.61 U9.1
N22768241: length 12.2
  TOP w0.254: C35.2 v1(207.14,137.1) ; L2.1 v1(199.61,136.68)
  BOTTOM w0.254: v1(199.61,136.68) 200.21,136.08 206.12,136.08 v1(207.14,137.1)
N22768257: length 4.9
  TOP w0.254: U9.13 206.23,132.29 207.26,131.25 R52.2 208.03,131.2 R55.1 209.13,130.04 C74.2
N22768337: length 2.3
  TOP w0.254: U9.14 206.41,132.79 206.81,132.4 C57.1
N22768591: length 5.8
  TOP w0.254: U9.16 207.01,133.79 207.65,133.16 211.13,133.16 R46.2
N22769636: length 3.2
  TOP w0.254: U50.5 206.82,27.56 207.19,27.93 R284.1 R285.1
N22862307: length 5.7
  TOP w0.127: R709.2 250.02,152.75 JT1.D1
N22862309: length 7.3
  TOP w0.127: R708.2 247.3,154.88 252.26,154.88 JT1.C1
N22862311: length 7.1
  TOP w0.127: R710.2 247.13,152.34 252.3,152.34 JT1.C2
N22881224: length 11.9
  TOP w0.127: JT1.A8 255.96,135.19 248.16,135.19 247.43,134.46 R713.2
N22881226: length 9.9
  TOP w0.127: R712.2 246.64,138.24 255.02,138.24 255.95,139.18 JT1.B7
N22881228: length 12
  TOP w0.127: JT1.A7 256,137.73 247.34,137.73 R711.2
N22881230: length 10
  TOP w0.127: R714.2 246.57,135.7 255.02,135.7 255.95,136.64 JT1.B8
N22958186: length 6.5
  TOP w0.254: R1.2 14.43,164.27 8,164.27 U1.3
N22958370: length 9.7
  TOP w0.254: R2.2 14.45,162.98 14.42,163 6.6,163 5.46,164.15 U1.1

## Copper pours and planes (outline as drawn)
D1V2 on BOTTOM (solid shape): 102.87,33.97 102.87,30.8 102.74,30.67 86.49,30.67 86.36,30.8 86.36,33.97 86.49,34.1 102.74,34.1
D1V2 on BOTTOM (solid shape): 39.43,111.3 39.54,111.32 40.39,111.32 40.51,111.19 40.51,109.66 40.39,109.54 38.99,109.54 38.86,109.66 38.86,111.19 38.99,111.32 39.33,111.32
D1V2 on BOTTOM (solid shape): 39.43,83.36 39.54,83.38 40.39,83.38 40.51,83.25 40.51,81.72 40.39,81.6 38.99,81.6 38.86,81.72 38.86,83.25 38.99,83.38 39.33,83.38
D1V2 on BOTTOM (solid shape): 39.43,55.42 39.54,55.44 40.39,55.44 40.51,55.31 40.51,53.78 40.39,53.66 38.99,53.66 38.86,53.78 38.86,55.31 38.99,55.44 39.33,55.44
D1V2 on BOTTOM (solid shape): 39.43,27.48 39.54,27.5 40.39,27.5 40.51,27.37 40.51,25.84 40.39,25.72 38.99,25.72 38.86,25.84 38.86,27.37 38.99,27.5 39.33,27.5
D1V2 on TOP: 102.74,30.92 102.87,31.05 102.87,34.23 102.74,34.35 86.11,34.35 85.98,34.23 85.98,31.05 86.11,30.92
D1V2 on 04_PWR1: 39.22,24.7 38.86,25.06 38.86,26.25 40.64,28.03 40.64,46.02 38.86,47.79 38.86,54.19 40.64,55.97 40.64,74.21 38.86,75.99 38.86,82.13 40.64,83.91 40.64,102.02 38.86,103.8 38.86,110.45 39.09,110.68 48.2,110.68 49.78,109.09 49.78,39.12 51.37,37.53 92.48,37.53 92.84,37.17 92.84,31.66 92.38,31.21 59.56,31.18 59.23,31.05 46.76,31.05 45.59,29.89 45.59,25.31 44.98,24.7
D1V2_OUT1 on BOTTOM (solid shape): 38.1,111.95 38.1,110.55 37.97,110.43 34.67,110.43 34.54,110.55 34.54,111.95 34.67,112.08 37.97,112.08
D1V2_OUT1 on 06_SIG2: 30.1,120.46 37.21,120.46 37.47,120.21 37.47,110.55 37.21,110.3 30.1,110.3 29.84,110.55 29.84,120.21
D1V2_OUT2 on BOTTOM (solid shape): 38.1,84.01 38.1,82.61 37.97,82.49 34.67,82.49 34.54,82.61 34.54,84.01 34.67,84.14 37.97,84.14
D1V2_OUT2 on 06_SIG2: 30.1,92.52 37.21,92.52 37.47,92.27 37.47,82.61 37.21,82.36 30.1,82.36 29.84,82.61 29.84,92.27
D1V2_OUT3 on BOTTOM (solid shape): 38.1,56.07 38.1,54.67 37.97,54.55 34.67,54.55 34.54,54.67 34.54,56.07 34.67,56.2 37.97,56.2
D1V2_OUT3 on 06_SIG2: 30.1,64.58 37.21,64.58 37.47,64.33 37.47,54.67 37.21,54.42 30.1,54.42 29.84,54.67 29.84,64.33
D1V2_OUT4 on BOTTOM (solid shape): 38.1,28.13 38.1,26.73 37.97,26.61 34.67,26.61 34.54,26.73 34.54,28.13 34.67,28.26 37.97,28.26
D1V2_OUT4 on 06_SIG2: 30.1,36.64 37.21,36.64 37.47,36.39 37.47,26.73 37.21,26.48 30.1,26.48 29.84,26.73 29.84,36.39
D1V8 on TOP: 82.93,85.92 81.41,85.92 81.28,85.79 81.28,84.52 81.41,84.39 82.93,84.39 83.06,84.52 83.06,85.79
D1V8 on TOP: 89.28,50.86 96.39,57.98 123.57,57.98 128.02,62.42 129.67,62.42 129.79,62.29 129.79,61.28 129.67,61.15 128.78,61.15 123.95,56.32 97.54,56.32 91.44,50.23 91.44,38.54 91.31,38.42 89.41,38.42 89.28,38.54
D1V8 on 04_PWR1: 86.47,38.04 86.11,38.4 86.11,78.27 81.41,82.97 81.41,84.92 81.64,85.15 92.46,85.15 92.84,84.77 92.84,38.4 92.48,38.04
D3V3 on TOP (solid shape): 184.66,68.64 184.66,66.23 184.53,66.1 181.36,66.1 181.23,66.23 181.23,67.37 181.36,67.5 183.13,67.5 183.52,67.88 183.52,68.64 183.64,68.77 184.53,68.77
D3V3 on TOP (solid shape): 113.92,144.34 113.92,142.56 114.3,142.18 115.06,142.18 115.19,142.05 115.19,141.16 115.06,141.03 112.65,141.03 112.52,141.16 112.52,144.34 112.65,144.46 113.79,144.46
D3V3 on TOP (solid shape): 185.42,127.7 185.42,126.56 185.29,126.43 183.52,126.43 183.13,126.05 183.13,125.29 183.01,125.16 182.12,125.16 181.99,125.29 181.99,127.7 182.12,127.83 185.29,127.83
D3V3 on BOTTOM (solid shape): 41.66,121.35 41.66,120.21 41.53,120.08 38.99,120.08 38.86,120.21 38.86,121.35 38.99,121.48 41.53,121.48
D3V3 on BOTTOM (solid shape): 41.66,93.41 41.66,92.27 41.53,92.14 38.99,92.14 38.86,92.27 38.86,93.41 38.99,93.54 41.53,93.54
D3V3 on BOTTOM (solid shape): 41.66,65.47 41.66,64.33 41.53,64.2 38.99,64.2 38.86,64.33 38.86,65.47 38.99,65.6 41.53,65.6
D3V3 on BOTTOM (solid shape): 41.66,37.53 41.66,36.64 41.4,36.39 38.99,36.39 38.86,36.51 38.86,37.53 38.99,37.66 41.53,37.66
D3V3 on TOP: 24.77,135.06 26.8,135.06 27.18,134.68 27.18,133.16 27.05,133.03 24.64,133.03 24.51,133.16 24.51,134.81
D3V3 on TOP: 205.23,27.75 205.36,27.62 205.36,22.54 205.23,22.42 202.69,22.42 202.56,22.54 202.56,27.62 202.69,27.75
D3V3 on TOP: 196.34,99.5 196.6,99.76 196.6,105.22 196.47,105.35 193.04,105.35 192.91,105.22 192.91,82.49 193.04,82.36 196.22,82.36 196.34,82.49
D3V3 on BOTTOM: 193.17,82.87 193.17,105.22 193.29,105.35 196.6,105.35 196.72,105.22 196.72,82.87 196.6,82.74 193.29,82.74
D3V3 on 03_SIG1: 202.92,22.03 202.31,22.65 202.31,33.72 200.03,36 30.23,36 27.94,38.29 27.94,122.98 24.64,126.28 24.64,134.58 24.74,134.68 31.75,134.68 41.92,124.51 41.92,104.95 43.31,103.57 88.52,103.57 92.9,99.19 92.9,97.92 94.61,96.2 94.61,93.15 94.49,93.03 92.84,93.03 91.69,91.88 91.69,89.09 89.03,86.42 87.76,86.42 87.63,86.55 87.63,87.95 88.01,88.33 88.01,97.98 87.63,98.36 84.33,98.36 83.06,97.09 43.58,97.09 41.91,95.42 41.91,59.39 47.01,54.29 125.86,54.29 128.4,56.83 156.97,56.83 160.66,53.15 179.68,53.15 181.36,54.82 181.36,138.47 178.67,141.16 112.63,141.16 112.39,141.39 112.39,153.92 113.28,154.81 229.36,154.81 231.52,152.65 231.52,22.77 230.78,22.03
D3V3_HM21 on TOP: 25.15,135.45 18.54,135.45 18.29,135.7 18.29,136.72 18.54,136.97 25.27,136.97 25.4,136.84 25.4,135.7
D3V3_HM21 on 04_PWR1: 20.81,131.51 18.41,133.9 18.41,152.87 18.77,153.23 46.12,153.23 46.48,152.87 46.48,132.63 45.36,131.51
D3V3_OUT1 on BOTTOM (solid shape): 38.1,122.11 38.1,119.95 38.48,119.57 39.12,119.57 39.24,119.44 39.24,118.94 39.12,118.81 36.32,118.81 36.2,118.94 36.2,120.08 36.07,120.2 36.07,120.21 35.96,120.37 35.8,120.48 35.79,120.48 35.69,120.59 35.69,122.11 35.81,122.24 37.97,122.24
D3V3_OUT1 on 04_PWR1: 22.97,103.95 22.61,104.31 22.61,130.37 22.99,130.75 39.24,130.75 40.13,129.86 40.13,111.55 39.77,111.19 38.88,111.19 38.35,110.66 38.35,104.54 37.76,103.95
D3V3_OUT2 on BOTTOM (solid shape): 38.1,94.3 38.1,92.01 38.48,91.63 39.12,91.63 39.24,91.5 39.24,91 39.12,90.87 36.32,90.87 36.2,91 36.2,92.14 36.07,92.26 36.07,92.27 35.96,92.43 35.8,92.54 35.79,92.54 35.69,92.65 35.69,94.3 35.81,94.42 37.97,94.42
D3V3_OUT2 on 04_PWR1: 22.97,76.14 22.61,76.5 22.61,103.08 22.97,103.44 38.5,103.44 40.13,101.81 40.13,84.12 38.35,82.34 38.35,76.73 37.76,76.14
D3V3_OUT3 on BOTTOM (solid shape): 38.1,66.36 38.1,64.07 38.48,63.69 39.12,63.69 39.24,63.56 39.24,63.06 39.12,62.93 36.32,62.93 36.2,63.06 36.2,64.2 36.07,64.32 36.07,64.33 35.96,64.49 35.8,64.6 35.79,64.6 35.69,64.71 35.69,66.36 35.81,66.48 37.97,66.48
D3V3_OUT3 on 04_PWR1: 22.97,47.94 22.61,48.3 22.61,75.27 22.97,75.63 38.5,75.63 40.13,74 40.13,56.18 38.35,54.4 38.35,48.54 37.76,47.94
D3V3_OUT4 on BOTTOM (solid shape): 38.1,38.42 38.1,36.13 38.48,35.75 39.12,35.75 39.24,35.62 39.24,35.12 39.12,34.99 36.32,34.99 36.2,35.12 36.2,36.26 36.07,36.38 36.07,36.39 35.96,36.55 35.8,36.66 35.79,36.66 35.69,36.77 35.69,38.42 35.81,38.54 37.97,38.54
D3V3_OUT4 on 04_PWR1: 22.97,24.7 22.61,25.06 22.61,47.08 22.97,47.43 38.5,47.43 40.13,45.81 40.13,28.24 38.35,26.46 38.35,25.06 37.99,24.7
D5V on TOP (solid shape): 21.59,130.87 21.59,128.59 21.46,128.46 17.78,128.46 17.65,128.59 17.65,130.87 17.78,131 21.46,131
D5V on TOP (solid shape): 21.59,102.93 21.59,100.65 21.46,100.52 17.78,100.52 17.65,100.65 17.65,102.93 17.78,103.06 21.46,103.06
D5V on TOP (solid shape): 21.59,74.99 21.59,72.71 21.46,72.58 17.78,72.58 17.65,72.71 17.65,74.99 17.78,75.12 21.46,75.12
D5V on TOP (solid shape): 21.59,47.05 21.59,44.77 21.46,44.64 17.78,44.64 17.65,44.77 17.65,47.05 17.78,47.18 21.46,47.18
D5V on BOTTOM (solid shape): 82.3,34.1 82.3,30.8 82.17,30.67 59.94,30.67 59.82,30.8 59.82,31.28 81.79,31.28 81.79,33.31 79.76,33.31 79.76,31.28 59.82,31.28 59.82,34.1 59.94,34.23 82.17,34.23
D5V on TOP: 76.33,30.92 76.58,30.67 82.04,30.67 82.17,30.8 82.17,34.23 82.04,34.35 60.45,34.35 59.31,33.21 59.31,31.05 59.44,30.92
D5V on TOP: 82.8,41.97 82.68,41.85 77.6,41.85 77.47,41.97 77.47,44.51 77.6,44.64 82.68,44.64 82.8,44.51
D5V on 05_PWR2: 19.28,7.81 16.26,10.84 16.26,151.55 14.48,153.33 14.48,157.57 14.84,157.92 24.41,157.92 24.89,157.44 24.89,110.19 25.8,109.28 38.12,109.28 38.61,108.8 38.61,101.77 38.25,101.41 25.8,101.41 24.89,100.5 24.89,82.25 25.8,81.34 38.12,81.34 38.61,80.86 38.61,73.83 38.25,73.47 25.8,73.47 24.89,72.56 24.89,54.31 25.8,53.4 38.12,53.4 38.61,52.92 38.61,45.89 38.25,45.53 25.8,45.53 24.89,44.62 24.89,26.25 25.68,25.46 38.12,25.46 38.61,24.98 38.61,21.42 39.52,20.51 48.24,20.51 49.02,21.29 49.02,44.66 49.51,45.15 84.1,45.15 85.09,44.15 85.09,31.28 84.73,30.92 60.22,30.92 59.31,30.01 59.31,8.3 58.82,7.81
D5V_OUT1 on TOP (solid shape): 21.59,126.68 21.59,123.51 21.46,123.38 15.37,123.38 15.24,123.51 15.24,126.68 15.37,126.81 21.46,126.81
D5V_OUT2 on TOP (solid shape): 21.59,98.74 21.59,95.57 21.46,95.44 16.84,95.44 16.64,95.49 16.43,95.44 15.37,95.44 15.24,95.57 15.24,98.74 15.37,98.87 21.46,98.87
D5V_OUT3 on TOP (solid shape): 21.59,70.8 21.59,67.63 21.46,67.5 15.37,67.5 15.24,67.63 15.24,70.8 15.37,70.93 21.46,70.93
D5V_OUT4 on TOP (solid shape): 21.59,42.86 21.59,39.69 21.46,39.56 16.84,39.56 16.64,39.61 16.43,39.56 15.37,39.56 15.24,39.69 15.24,42.86 15.37,42.99 21.46,42.99
D12V on TOP (solid shape): 65.79,22.8 65.79,21.53 64.26,20 61.34,20 61.21,20.13 61.21,22.54 61.34,22.67 64.64,22.67 64.9,22.92 65.66,22.92
D12V on TOP (solid shape): 72.52,22.67 75.82,22.67 75.95,22.54 75.95,20.13 75.82,20 72.9,20 71.37,21.53 71.37,22.8 71.5,22.92 72.26,22.92
D12V on TOP (solid shape): 92.46,22.8 92.46,21.53 90.93,20 88.01,20 87.88,20.13 87.88,22.54 88.01,22.67 91.31,22.67 91.57,22.92 92.33,22.92
D12V on TOP (solid shape): 111.38,22.8 111.38,21.53 109.86,20 106.93,20 106.81,20.13 106.81,22.54 106.93,22.67 110.24,22.67 110.49,22.92 111.25,22.92
D12V on TOP (solid shape): 118.11,22.67 121.41,22.67 121.54,22.54 121.54,20.13 121.41,20 118.49,20 116.97,21.53 116.97,22.8 117.09,22.92 117.86,22.92
D12V on TOP (solid shape): 178.18,22.8 178.18,21.53 176.66,20 173.74,20 173.61,20.13 173.61,22.54 173.74,22.67 177.04,22.67 177.29,22.92 178.05,22.92
D12V on TOP (solid shape): 184.91,22.67 188.21,22.67 188.34,22.54 188.34,20.13 188.21,20 185.29,20 183.77,21.53 183.77,22.8 183.9,22.92 184.66,22.92
D12V on TOP (solid shape): 207.26,140.78 207.26,137.86 205.74,136.33 204.47,136.33 204.34,136.46 204.34,137.22 204.6,137.48 204.6,140.78 204.72,140.91 207.14,140.91
D12V on TOP (solid shape): 207.26,129.22 207.26,126.3 207.14,126.17 204.72,126.17 204.6,126.3 204.6,129.6 204.34,129.86 204.34,130.62 204.47,130.75 205.74,130.75
D12V on TOP (solid shape): 99.19,22.67 102.49,22.67 102.62,22.54 102.62,20.13 102.49,20 99.57,20 99.23,20.34 99.23,20.35 99.11,20.56 98.9,20.68 98.89,20.68 98.04,21.53 98.04,22.8 98.17,22.92 98.93,22.92
D12V on TOP: 254.38,12.76 254.13,12.51 238.51,12.51 238.12,12.89 238.12,102.17 238.38,102.43 254.13,102.43 254.38,102.17
D12V on TOP: 204.47,94.42 205.74,94.42 207.26,95.95 207.26,98.87 207.14,99 204.72,99 204.6,98.87 204.6,95.57 204.34,95.31 204.34,94.55
D12V on TOP: 204.47,88.84 205.74,88.84 207.26,87.31 207.26,84.39 207.14,84.26 204.72,84.26 204.6,84.39 204.6,87.69 204.34,87.95 204.34,88.71
D12V on TOP: 163.7,20.13 163.7,14.8 163.58,14.67 149.86,14.67 149.73,14.8 149.73,19.88 149.86,20 158.62,20 158.88,20.26 163.58,20.26
D12V on BOTTOM: 149.86,18.99 149.73,18.86 149.73,14.92 149.86,14.8 161.67,14.8 161.8,14.92 161.8,18.86 161.67,18.99
D12V on 04_PWR1: 60.18,2.6 60.07,2.71 60.07,29.52 60.72,30.16 202.44,30.29 203.52,30.29 205.23,32 205.23,167.34 205.34,167.45 255.63,167.45 256.54,166.54 256.54,158.03 258.06,156.51 258.06,128.9 256.54,127.38 256.54,3.38 255.76,2.6
GND on TOP (solid shape): 24.89,130.87 24.89,129.1 24.77,128.97 24.13,128.97 24,129.1 24,129.73 23.88,129.86 22.61,129.86 22.1,130.37 22.1,130.87 22.23,131 24.77,131
GND on TOP (solid shape): 24.89,126.05 24.89,123.51 24.77,123.38 22.86,123.38 22.73,123.51 22.73,124.78 22.86,124.9 23.75,124.9 24.13,125.29 24.13,126.05 24.26,126.17 24.77,126.17
GND on TOP (solid shape): 24.89,102.93 24.89,101.16 24.77,101.03 24.13,101.03 24,101.16 24,101.79 23.88,101.92 22.61,101.92 22.1,102.43 22.1,102.93 22.23,103.06 24.77,103.06
GND on TOP (solid shape): 24.89,98.11 24.89,95.57 24.77,95.44 22.86,95.44 22.73,95.57 22.73,96.84 22.86,96.96 23.75,96.96 24.13,97.35 24.13,98.11 24.26,98.23 24.77,98.23
GND on TOP (solid shape): 24.89,74.99 24.89,73.22 24.77,73.09 24.13,73.09 24,73.22 24,73.85 23.88,73.98 22.61,73.98 22.1,74.49 22.1,74.99 22.23,75.12 24.77,75.12
GND on TOP (solid shape): 24.89,70.17 24.89,67.63 24.77,67.5 22.86,67.5 22.73,67.63 22.73,68.9 22.86,69.02 23.75,69.02 24.13,69.41 24.13,70.17 24.26,70.29 24.77,70.29
GND on TOP (solid shape): 24.89,47.05 24.89,45.28 24.77,45.15 24.13,45.15 24,45.28 24,45.91 23.88,46.04 22.61,46.04 22.1,46.55 22.1,47.05 22.23,47.18 24.77,47.18
GND on TOP (solid shape): 24.89,42.23 24.89,39.69 24.77,39.56 22.86,39.56 22.73,39.69 22.73,40.96 22.86,41.08 23.75,41.08 24.13,41.47 24.13,42.23 24.26,42.35 24.77,42.35
GND on TOP (solid shape): 112.14,143.07 112.14,140.78 112.9,140.02 129.79,140.02 129.92,139.89 129.92,138.49 129.79,138.37 110.36,138.37 108.33,140.4 108.33,142.81 108.46,142.94 110.11,142.94 110.36,143.19 112.01,143.19
GND on TOP (solid shape): 183.9,131.89 183.9,130.24 184.15,129.98 184.15,128.33 184.02,128.21 181.74,128.21 180.97,127.44 180.97,110.55 180.85,110.43 179.45,110.43 179.32,110.55 179.32,129.98 181.36,132.02 183.77,132.02
GND on TOP: 67.31,25.34 65.66,25.34 65.15,25.84 65.15,29.78 65.02,29.91 59.44,29.91 59.31,29.78 59.31,23.81 59.44,23.69 64.64,23.69 64.9,23.43 66.29,23.43 66.55,23.18 67.56,23.18 67.69,23.3 67.69,24.96
GND on TOP: 69.85,25.34 71.5,25.34 72.01,25.84 72.01,29.78 72.14,29.91 76.33,29.91 76.58,30.16 82.04,30.16 82.17,30.04 82.17,23.81 82.04,23.69 72.52,23.69 72.26,23.43 70.87,23.43 70.61,23.18 69.6,23.18 69.47,23.3 69.47,24.96
GND on TOP: 95.76,92.27 89.92,92.27 89.79,92.39 89.79,93.54 89.92,93.66 90.68,93.66 90.81,93.54 90.81,92.9 91.06,92.65 92.71,92.65 92.96,92.9 92.96,93.66 93.09,93.79 93.6,93.79 93.73,93.66 93.73,92.9 93.85,92.77 95.5,92.77 95.63,92.9 95.63,95.31 95.5,95.44 94.74,95.44 94.36,95.82 92.96,95.82 92.71,96.08 92.71,97.98 92.58,98.11 91.06,98.11 90.93,97.98 90.93,97.6 90.81,97.47 89.79,97.47 89.66,97.35 89.66,94.42 89.53,94.3 89.28,94.3 89.15,94.42 89.15,98.62 89.28,98.74 95.89,98.74 96.01,98.62 96.01,92.52
GND on TOP: 201.93,90.36 201.93,88.71 201.42,88.2 197.49,88.2 197.36,88.07 197.36,82.49 197.49,82.36 203.45,82.36 203.58,82.49 203.58,87.69 203.84,87.95 203.84,89.34 204.09,89.6 204.09,90.61 203.96,90.74 202.31,90.74
GND on TOP: 201.93,134.81 201.93,136.46 201.42,136.97 197.49,136.97 197.36,137.1 197.36,141.29 197.1,141.54 197.1,147.13 197.23,147.26 203.45,147.26 203.58,147.13 203.58,137.48 203.84,137.22 203.84,135.83 204.09,135.57 204.09,134.56 203.96,134.43 202.31,134.43
GND on TOP: 11.68,156.15 11.81,156.27 13.34,156.27 13.46,156.15 13.46,153.61 13.34,153.48 11.81,153.48 11.68,153.61
GND on TOP: 141.6,48.7 141.35,48.45 135.51,48.45 135.25,48.7 135.25,54.93 135.38,55.05 136.27,54.17 136.27,53.53 135.51,52.77 135.51,51.12 135.64,50.99 136.53,50.99 136.65,50.86 136.65,48.96 136.91,48.7 139.95,48.7 140.21,48.96 140.21,49.85 140.08,49.97 139.06,49.97 138.94,50.1 138.94,51.5 139.06,51.63 140.84,51.63 140.97,51.75 140.97,53.28 140.84,53.4 140.46,53.4 139.95,53.91 139.95,54.29 139.7,54.55 137.03,54.55 136.02,55.56 136.02,55.69 136.27,55.94 136.78,55.94 137.54,55.18 141.35,55.18 141.6,54.93
GND on TOP: 41.78,96.46 26.67,96.46 26.29,96.84 26.29,103.19 25.91,103.57 15.11,103.57 14.73,103.19 14.73,97.22 14.35,96.84 12.06,96.84 11.68,97.22 11.68,99.5 11.18,100.01 1.4,100.01 1.02,100.39 1.02,106.49 1.4,106.87 11.43,106.87 11.94,107.38 11.94,110.17 12.32,110.55 27.56,110.55 27.94,110.17 27.94,103.95 28.32,103.57 46.61,103.57 53.09,110.05 60.2,110.05 60.45,109.79 60.45,107.76 44.96,92.27 42.8,92.27 42.16,92.9 42.16,96.08
GND on TOP: 201.93,92.9 201.93,94.55 201.42,95.06 197.49,95.06 197.36,95.19 197.36,99.5 197.1,99.76 197.1,105.22 197.23,105.35 203.45,105.35 203.58,105.22 203.58,95.57 203.84,95.31 203.84,93.92 204.09,93.66 204.09,92.65 203.96,92.52 202.31,92.52
GND on TOP: 94.87,87.06 94.61,86.8 88.65,86.8 88.39,87.06 88.39,89.34 88.52,89.47 88.77,89.47 89.41,88.84 89.41,88.07 89.66,87.82 90.55,87.82 90.81,88.07 90.81,88.71 91.06,88.96 92.2,88.96 92.46,88.71 92.46,87.31 92.58,87.19 94.11,87.19 94.23,87.31 94.23,89.22 94.11,89.34 93.09,89.34 92.46,89.98 92.46,91.38 92.33,91.5 90.68,91.5 90.55,91.38 90.55,91 90.42,90.87 88.9,90.87 88.77,91 88.77,91.12 89.53,91.88 94.61,91.88 94.87,91.63
GND on TOP: 96.52,25.34 98.17,25.34 98.68,25.84 98.68,29.78 98.81,29.91 102.74,29.91 102.87,29.78 102.87,23.81 102.74,23.69 99.19,23.69 98.93,23.43 97.54,23.43 97.28,23.18 96.27,23.18 96.14,23.3 96.14,24.96
GND on TOP: 182.25,25.34 183.9,25.34 184.4,25.84 184.4,29.78 184.53,29.91 188.85,29.91 189.1,30.16 194.69,30.16 194.82,30.04 194.82,23.81 194.69,23.69 184.91,23.69 184.66,23.43 183.26,23.43 183.01,23.18 181.99,23.18 181.86,23.3 181.86,24.96
GND on TOP: 112.9,25.34 111.25,25.34 110.74,25.84 110.74,29.78 110.62,29.91 106.05,29.91 105.92,29.78 105.92,23.81 106.05,23.69 110.24,23.69 110.49,23.43 111.89,23.43 112.14,23.18 113.16,23.18 113.28,23.3 113.28,24.96
GND on TOP: outline of 220 points within 1.02,4.25 258.06,165.8 ; 27 cut-outs
GND on TOP: 115.44,25.34 117.09,25.34 117.6,25.84 117.6,29.78 117.73,29.91 122.05,29.91 122.3,30.16 127.76,30.16 127.89,30.04 127.89,23.81 127.76,23.69 118.11,23.69 117.86,23.43 116.46,23.43 116.2,23.18 115.19,23.18 115.06,23.3 115.06,24.96
GND on TOP: 130.81,53.02 131.44,53.02 131.7,52.77 131.7,51.63 131.44,51.37 130.05,51.37 129.92,51.24 129.92,49.72 130.05,49.59 131.95,49.59 132.08,49.72 132.08,50.74 132.72,51.37 134.11,51.37 134.24,51.5 134.24,53.15 134.11,53.28 133.73,53.28 133.6,53.4 133.6,54.42 133.73,54.55 134.49,54.55 134.75,54.29 134.75,49.21 134.49,48.96 129.54,48.96 129.41,49.09 129.41,53.4 130.17,54.17 130.56,54.17 130.68,54.04 130.68,53.15
GND on TOP: 26.8,68.52 26.42,68.9 26.42,75.25 26.03,75.63 15.11,75.63 14.73,75.25 14.73,69.66 14.35,69.28 12.06,69.28 11.68,69.66 11.68,71.56 11.18,72.07 1.4,72.07 1.02,72.45 1.02,78.55 1.4,78.93 11.43,78.93 11.94,79.44 11.94,82.87 12.19,83.12 27.69,83.12 27.94,82.87 27.94,77.15 29.46,75.63 48.13,75.63 48.39,75.88 48.39,81.72 48.01,82.11 44.07,82.11 43.82,82.36 43.82,83.25 44.07,83.5 47.37,83.5 62.99,99.12 77.98,99.12 78.23,98.87 78.23,88.07 80.77,85.53 80.77,84.26 81.15,83.88 88.39,83.88 90.55,86.04 94.87,86.04 96.52,87.69 96.52,93.28 96.65,93.41 99.5,93.41 99.57,93.35 99.57,89.34 91.95,81.72 59.82,81.72 46.61,68.52
GND on TOP: 156.72,23.94 156.59,24.07 156.59,25.34 156.97,25.72 156.97,29.78 156.84,29.91 149.22,29.91 148.97,30.16 134.24,30.16 134.11,30.04 134.11,21.15 134.24,21.02 158.62,21.02 158.88,20.76 160.66,20.76 160.78,20.64 169.42,20.64 169.55,20.76 169.55,24.57 169.42,24.7 167.39,24.7 166.62,23.94
GND on TOP: 201.93,132.27 201.93,130.62 201.42,130.11 197.49,130.11 197.36,129.98 197.36,124.4 197.49,124.27 203.45,124.27 203.58,124.4 203.58,129.6 203.84,129.86 203.84,131.25 204.09,131.51 204.09,132.52 203.96,132.65 202.31,132.65
GND on TOP: 93.98,25.34 92.33,25.34 91.82,25.84 91.82,29.78 91.69,29.91 86.11,29.91 85.98,29.78 85.98,23.81 86.11,23.69 91.31,23.69 91.57,23.43 92.96,23.43 93.22,23.18 94.23,23.18 94.36,23.3 94.36,24.96
GND on BOTTOM: 149.48,105.47 149.22,105.73 149.22,118.17 164.59,133.54 164.59,137.73 165.99,139.13 169.8,139.13 171.32,137.6 171.32,125.67 170.94,125.29 163.07,125.29 157.48,119.7 157.48,112.2 150.75,105.47
GND on BOTTOM: 163.96,55.05 162.81,56.2 162.81,69.91 163.19,70.29 168.53,70.29 168.91,70.68 168.91,78.3 165.23,81.98 165.23,83.5 165.99,84.26 170.81,84.26 171.2,83.88 171.2,55.31 170.94,55.05
GND on BOTTOM: 141.69,93.82 141.69,92.42 141.16,91.89 124.88,91.89 124.63,92.14 124.63,94.2 124.79,94.37 141.14,94.37
GND on BOTTOM: 166.62,93.92 160.27,100.27 160.27,106.24 165.48,111.44 165.48,114.11 165.74,114.36 170.94,114.36 171.32,113.98 171.32,108.14 170.56,107.38 170.56,101.92 173.35,99.12 178.94,99.12 179.2,98.87 179.2,95.19 177.93,93.92
GND on BOTTOM: 257.68,4.19 198.75,4.25 198.25,4.76 198.25,13.4 197.61,14.03 184.78,14.03 184.15,13.4 184.15,4.76 183.64,4.25 147.96,4.25 147.45,4.76 147.45,13.4 146.81,14.03 133.99,14.03 133.35,13.4 133.35,4.76 132.84,4.25 97.16,4.25 96.65,4.76 96.65,13.4 96.01,14.03 83.19,14.03 82.55,13.4 82.55,4.76 82.04,4.25 1.4,4.25 1.02,4.64 1.02,134.18 1.02,165.42 1.4,165.8 82.04,165.8 82.55,165.29 82.55,156.65 83.19,156.02 96.01,156.02 96.65,156.65 96.65,165.29 97.16,165.8 132.84,165.8 133.35,165.29 133.35,156.65 133.99,156.02 146.81,156.02 147.45,156.65 147.45,165.29 147.96,165.8 183.64,165.8 184.15,165.29 184.15,156.65 184.78,156.02 197.61,156.02 198.25,156.65 198.25,165.29 198.75,165.8 257.68,165.8 258.06,165.42 258.06,4.57 ; 31 cut-outs
GND on 02_GND1, 07_GND2: 3.05,1.02 1.61,1.61 1.02,3.05 1.02,167 1.61,168.44 3.05,169.04 256.03,169.04 257.47,168.44 258.06,167 258.06,3.05 257.47,1.61 256.03,1.02
GND on 03_SIG1: 46.46,55.56 42.42,59.6 42.42,95.21 43.79,96.58 80.39,96.58 80.77,96.2 80.77,86.8 81.66,85.92 89.28,85.92 92.33,88.96 92.33,91 93.22,91.88 99.59,91.88 116.48,74.99 126.26,74.99 126.62,74.63 126.62,69.76 118.64,61.79 61.34,61.79 59.69,63.44 58.67,63.44 57.91,62.67 57.91,56.2 57.28,55.56
GND on 03_SIG1: 3.05,1.02 1.61,1.61 1.02,3.05 1.02,167 1.61,168.44 3.05,169.04 256.03,169.04 257.47,168.44 258.06,167 258.06,3.05 257.47,1.61 256.03,1.02 ; 1 cut-out
GND on 04_PWR1: 2.92,2.6 1.02,4.51 1.02,165.67 2.79,167.45 204.11,167.45 204.22,167.34 204.22,154.98 203.86,154.62 93.62,154.62 92.84,153.84 92.84,86.02 92.47,85.66 81.43,85.66 80.9,85.13 80.9,82.76 85.6,78.06 85.6,38.42 85.22,38.04 52.01,38.04 50.93,39.12 50.93,109.09 48.83,111.19 41,111.19 40.64,111.55 40.64,130.37 41.27,131 45.57,131 46.99,132.42 46.99,153.08 46.33,153.73 18.56,153.73 17.91,153.08 17.91,133.69 20.85,130.75 21.59,130.75 22.1,130.24 22.1,24.85 22.75,24.19 45.19,24.19 46.1,25.1 46.1,29.68 46.97,30.54 58.41,30.54 59.05,29.9 59.05,2.71 58.95,2.6
GND on 05_PWR2: 2.79,2.6 1.02,4.38 1.02,165.67 2.79,167.45 255.63,167.45 258.06,165.02 258.06,4.91 255.76,2.6 ; 2 cut-outs
GND on 06_SIG2: 3.05,1.02 1.61,1.61 1.02,3.05 1.02,167 1.61,168.44 3.05,169.04 256.03,169.04 257.47,168.44 258.06,167 258.06,3.05 257.47,1.61 256.03,1.02 ; 5 cut-outs
GND on 06_SIG2: 62.23,66.23 47.62,80.84 47.62,104.65 48.2,105.22 53.47,105.22 90.55,68.14 90.55,66.61 90.17,66.23
VCC_D0V9 on TOP: 163.07,31.05 163.07,36.13 162.94,36.26 134.24,36.26 134.11,36.13 134.11,30.8 134.24,30.67 148.97,30.67 149.22,30.92 162.94,30.92
VCC_D0V9 on BOTTOM: 156.97,36 156.97,31.05 156.84,30.92 151.51,30.92 151.26,30.67 134.24,30.67 134.11,30.8 134.11,36.13 134.24,36.26 156.72,36.26
VCC_D0V9 on 04_PWR1: 129.58,31.24 129.16,31.66 129.16,43.48 125.09,47.54 125.09,99.12 125.35,99.38 141.58,99.38 142.6,100.39 144.5,100.39 146.92,102.81 153.27,102.81 159.11,108.65 170.33,108.65 171.58,107.4 171.58,99.27 174.27,96.58 179.13,96.58 181.1,94.62 181.1,32.94 179.45,31.29
VCC_D0V9 on 06_SIG2: 134.49,36.26 134.37,36.13 134.37,31.18 134.49,31.05 156.72,31.05 156.84,31.18 156.84,36.13 156.72,36.26
VCC_D1V8 on TOP: 186.31,42.42 186.44,42.55 194.94,42.55 195.07,42.42 195.07,38.54 194.94,38.42 186.44,38.42 186.31,38.54
VCC_D1V8 on 05_PWR2: 129.92,60.71 122.56,68.07 122.56,83.31 124.59,85.34 124.59,90.55 123.44,91.69 123.44,93.47 124.59,94.62 124.59,98.43 124.97,98.81 128.14,98.81 128.65,98.3 128.65,88.99 130.68,86.95 130.68,70.8 159.7,41.78 194.06,41.78 194.69,41.15 194.69,33.72 192.02,31.05 135.45,31.05 129.92,36.58
VCC_D1V8 on 06_SIG2: 123.44,93.66 123.32,93.54 123.32,89.6 123.44,89.47 136.4,89.47 136.53,89.6 136.53,93.54 136.4,93.66
VCC_DDR3 on TOP (solid shape): 124.21,142.81 124.21,141.16 124.08,141.03 120.78,141.03 120.65,141.16 120.65,142.81 120.78,142.94 124.08,142.94
VCC_DDR3 on TOP (solid shape): 183.9,119.57 183.9,116.14 183.77,116.01 182.12,116.01 181.99,116.14 181.99,119.57 182.12,119.7 183.77,119.7
VCC_DDR3 on TOP (solid shape): 184.66,77.66 184.66,74.36 184.53,74.23 182.88,74.23 182.75,74.36 182.75,77.66 182.88,77.79 184.53,77.79
VCC_DDR3 on BOTTOM (solid shape): 196.72,147.13 196.72,124.78 196.6,124.65 193.29,124.65 193.17,124.78 193.17,144.78 195.99,144.78 195.99,146.81 193.96,146.81 193.96,144.78 193.17,144.78 193.17,147.13 193.29,147.26 196.6,147.26
VCC_DDR3 on TOP: 196.34,141.29 196.6,141.54 196.6,147.13 196.47,147.26 193.04,147.26 192.91,147.13 192.91,124.4 193.04,124.27 196.22,124.27 196.34,124.4
VCC_DDR3 on BOTTOM: 126.11,82.74 126.11,81.98 126.24,81.85 129.03,81.85 129.16,81.98 129.16,82.36 128.65,82.87 128.65,84.77 128.02,85.41 127.25,85.41 127.13,85.28 127.13,83.25 126.75,82.87 126.24,82.87
VCC_DDR3 on 05_PWR2: 163.05,52.39 138.05,77.38 138.05,83.23 136.14,85.13 136.14,86.32 136.63,86.8 138.03,86.8 139.19,87.97 139.19,100.24 138.03,101.41 137.01,101.41 136.65,101.77 136.65,105.58 135.87,106.36 129.31,106.36 128.65,105.71 128.65,99.7 128.27,99.31 124.84,99.31 123.89,100.27 100.56,100.27 98.68,102.15 98.68,146.52 99.55,147.38 195.6,147.38 196.47,146.52 196.47,72.3 176.55,52.39
VCC_DDR3 on 06_SIG2: 133.41,84.52 133.35,84.58 133.35,86.42 133.22,86.55 129.67,86.55 129.54,86.42 129.54,85.03 128.02,83.5 126.49,83.5 126.36,83.63 126.36,88.58 126.49,88.71 139.32,88.71 139.45,88.58 139.45,84.65 139.32,84.52
VCC_IO3V0 on 05_PWR2: 39.73,21.02 39.12,21.63 39.12,25.19 38.33,25.97 25.89,25.97 25.4,26.46 25.4,44.41 26.01,45.02 38.46,45.02 39.12,45.68 39.12,53.13 38.33,53.91 26.01,53.91 25.4,54.52 25.4,72.35 26.01,72.96 38.46,72.96 39.12,73.62 39.12,81.07 38.33,81.85 26.01,81.85 25.4,82.46 25.4,100.29 26.01,100.9 38.46,100.9 39.12,101.56 39.12,109.01 38.33,109.79 26.01,109.79 25.4,110.4 25.4,157.44 25.89,157.92 47.9,157.92 48.51,157.31 48.51,21.5 48.03,21.02
VCCIO_D1V8 on BOTTOM (solid shape): 194.82,35.24 194.82,30.67 194.69,30.54 185.1,30.54 184.91,30.73 184.91,31.28 194.31,31.28 194.31,33.31 192.28,33.31 192.28,31.28 184.91,31.28 184.91,35.24 185.04,35.37 194.69,35.37
VCCIO_D1V8 on TOP: 188.85,30.92 189.1,30.67 194.69,30.67 194.82,30.8 194.82,37.4 194.69,37.53 178.05,37.53 177.93,37.4 177.93,31.05 178.05,30.92
VCCIO_D1V8 on 04_PWR1: 174.48,97.09 172.09,99.48 172.09,107.61 170.54,109.16 158.9,109.16 153.06,103.31 146.71,103.31 144.29,100.9 142.39,100.9 141.37,99.89 126.49,99.89 126.11,100.27 126.11,102.43 125.6,102.93 93.7,102.93 93.34,103.29 93.34,153.63 93.83,154.11 203.86,154.11 204.22,153.76 204.22,33.66 201.68,31.11 183.13,31.11 181.86,32.38 181.86,95.31 180.09,97.09
VCCIO_D1V8 on 05_PWR2: 131.04,87.31 129.16,89.2 129.16,105.5 129.52,105.85 135.66,105.85 136.14,105.37 136.14,101.56 136.8,100.9 137.82,100.9 138.68,100.03 138.68,88.18 137.82,87.31
VCCIO_D3V0 on TOP: 199.26,31.31 199.14,31.43 199.14,33.85 199.26,33.97 209.68,33.97 209.8,33.85 209.8,31.43 209.68,31.31
VCCIO_D3V0 on 05_PWR2: 196.28,31.05 195.2,32.13 195.2,41.53 194.06,42.67 159.58,42.67 131.19,71.06 131.19,86.45 131.55,86.8 135.15,86.8 135.64,86.32 135.64,84.92 137.54,83.02 137.54,77.15 165.35,49.34 203.48,49.34 209.3,43.52 209.3,31.79 208.56,31.05
VCCR_D1V0 on BOTTOM (solid shape): 127.89,33.97 127.89,30.8 127.76,30.67 106.17,30.67 106.05,30.8 106.05,31.28 127.38,31.28 127.38,33.31 125.35,33.31 125.35,31.28 106.05,31.28 106.05,33.97 106.17,34.1 127.76,34.1
VCCR_D1V0 on TOP: 122.05,30.92 122.3,30.67 127.76,30.67 127.89,30.8 127.89,36.13 127.76,36.26 106.05,36.26 105.92,36.13 105.92,31.05 106.05,30.92
VCCR_D1V0 on 04_PWR1: 93.8,31.21 93.34,31.66 93.34,102.07 93.7,102.43 125.35,102.43 125.6,102.17 125.6,100.39 124.59,99.38 124.59,47.33 128.65,43.27 128.65,31.66 128.23,31.24
VCCT_D1V0 on TOP: 119.38,37.27 119.25,37.15 107.31,37.15 107.19,37.27 107.19,40.45 119.25,40.45 119.38,40.32
VCCT_D1V0 on 05_PWR2: 98.11,36.64 96.01,38.73 96.01,89.58 90.93,94.66 90.93,101.56 91.16,101.79 98.32,101.79 100.35,99.76 123.59,99.76 124.08,99.27 124.08,94.49 123.06,93.47 123.06,91.57 124.08,90.55 124.08,85.6 122.17,83.69 122.17,67.82 129.29,60.71 129.29,37.72 128.21,36.64
VDD_PLL1 on TOP: 130.3,60.26 130.43,60.13 131.44,60.13 131.83,60.52 131.83,62.04 131.7,62.17 130.43,62.17 130.3,62.04
VDD_PLL1 on 03_SIG1: 142.37,62.8 142.37,57.59 142.24,57.47 131.19,57.47 131.06,57.59 131.06,62.8 131.19,62.93 142.24,62.93
VDD_PLL2 on TOP: 84.07,86.42 82.42,86.42 82.3,86.55 82.3,87.82 82.42,87.95 84.07,87.95 84.2,87.82 84.2,86.55
VDD_PLL2 on 03_SIG1: 87.25,97.85 87.5,97.6 87.5,88.71 85.73,86.93 81.66,86.93 81.28,87.31 81.28,94.42 84.71,97.85
(no net) on TOP: 92.46,22.8 92.46,21.53 90.93,20 88.01,20 87.88,20.13 87.88,22.54 88.01,22.67 91.31,22.67 91.57,22.92 92.33,22.92
(no net) on TOP: 185.29,121.35 185.42,121.48 186.06,121.48 186.18,121.35 186.18,113.98 184.66,112.46 184.66,100.65 184.53,100.52 182.12,100.52 181.99,100.65 181.99,115.38 182.12,115.51 184.02,115.51 184.4,115.89 184.4,120.08 184.66,120.33 185.17,120.33 185.29,120.46
(no net) on TOP: 22.86,41.08 23.75,41.08 24.13,41.47 24.13,42.23 24.26,42.35 24.77,42.35 24.89,42.23 24.89,39.69 24.77,39.56 22.86,39.56 22.73,39.69 22.73,40.96
(no net) on TOP: 186.18,123.76 185.29,123.76 185.29,124.78 185.93,125.41 185.93,127.83 185.55,128.21 184.78,128.21 184.66,128.33 184.66,129.98 184.91,130.24 184.91,131.89 185.04,132.02 186.82,132.02 186.94,131.89 186.94,124.52
(no net) on TOP: 116.59,145.22 116.59,144.34 115.57,144.34 114.94,144.97 112.52,144.97 112.14,144.59 112.14,143.83 112.01,143.7 110.36,143.7 110.11,143.95 108.46,143.95 108.33,144.08 108.33,145.86 108.46,145.99 115.82,145.99
(no net) on TOP: 22.86,96.96 23.75,96.96 24.13,97.35 24.13,98.11 24.26,98.23 24.77,98.23 24.89,98.11 24.89,95.57 24.77,95.44 22.86,95.44 22.73,95.57 22.73,96.84
(no net) on TOP: 183.77,22.8 183.77,21.53 185.29,20 188.21,20 188.34,20.13 188.34,22.54 188.21,22.67 184.91,22.67 184.66,22.92 183.9,22.92
(no net) on TOP: 181.36,72.58 181.23,72.45 180.59,72.45 180.47,72.58 180.47,79.95 181.99,81.47 181.99,95.06 182.12,95.19 184.4,95.19 184.66,94.93 184.66,78.42 184.53,78.3 182.63,78.3 182.25,77.91 182.25,73.85 181.99,73.6 181.48,73.6 181.36,73.47
(no net) on TOP: 21.46,131 17.78,131 17.65,130.87 17.65,128.59 17.78,128.46 21.46,128.46 21.59,128.59 21.59,130.87
(no net) on TOP: 180.85,110.43 179.45,110.43 179.32,110.55 179.32,129.98 181.36,132.02 183.77,132.02 183.9,131.89 183.9,130.24 184.15,129.98 184.15,128.33 184.02,128.21 181.74,128.21 180.97,127.44 180.97,110.55
(no net) on TOP: 24.13,101.03 24,101.16 24,101.79 23.88,101.92 22.61,101.92 22.1,102.43 22.1,102.93 22.23,103.06 24.77,103.06 24.89,102.93 24.89,101.16 24.77,101.03
(no net) on TOP: 178.18,22.8 178.18,21.53 176.66,20 173.74,20 173.61,20.13 173.61,22.54 173.74,22.67 177.04,22.67 177.29,22.92 178.05,22.92
(no net) on TOP: 98.04,22.8 98.04,21.53 99.57,20 102.49,20 102.62,20.13 102.62,22.54 102.49,22.67 99.19,22.67 98.93,22.92 98.17,22.92
(no net) on TOP: 21.59,95.57 21.46,95.44 15.37,95.44 15.24,95.57 15.24,98.74 15.37,98.87 21.46,98.87 21.59,98.74
(no net) on TOP: 204.47,136.33 205.74,136.33 207.26,137.86 207.26,140.78 207.14,140.91 204.72,140.91 204.6,140.78 204.6,137.48 204.34,137.22 204.34,136.46
(no net) on TOP: 21.59,39.69 21.46,39.56 15.37,39.56 15.24,39.69 15.24,42.86 15.37,42.99 21.46,42.99 21.59,42.86
(no net) on TOP: 21.46,75.12 17.78,75.12 17.65,74.99 17.65,72.71 17.78,72.58 21.46,72.58 21.59,72.71 21.59,74.99
